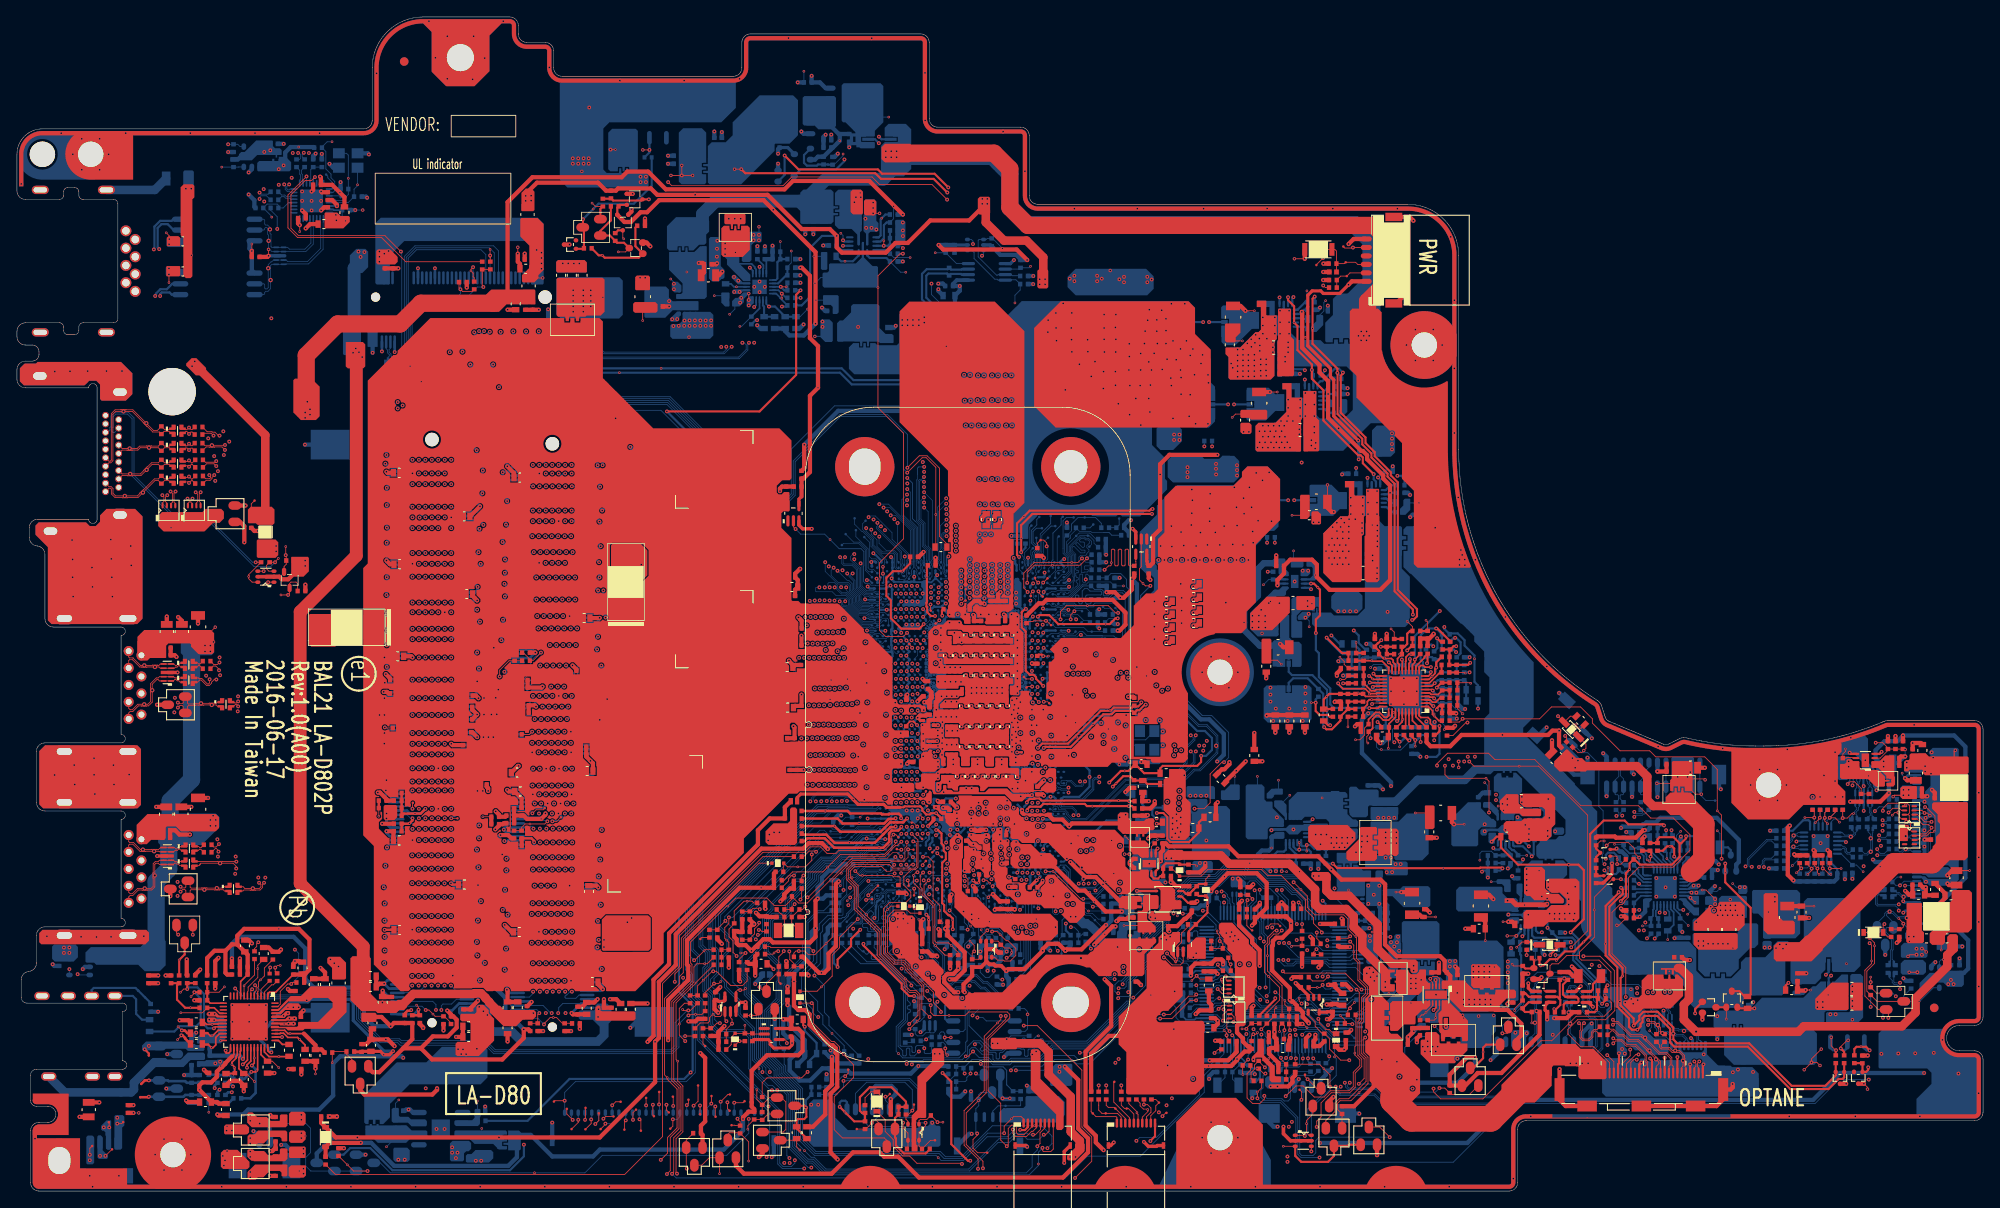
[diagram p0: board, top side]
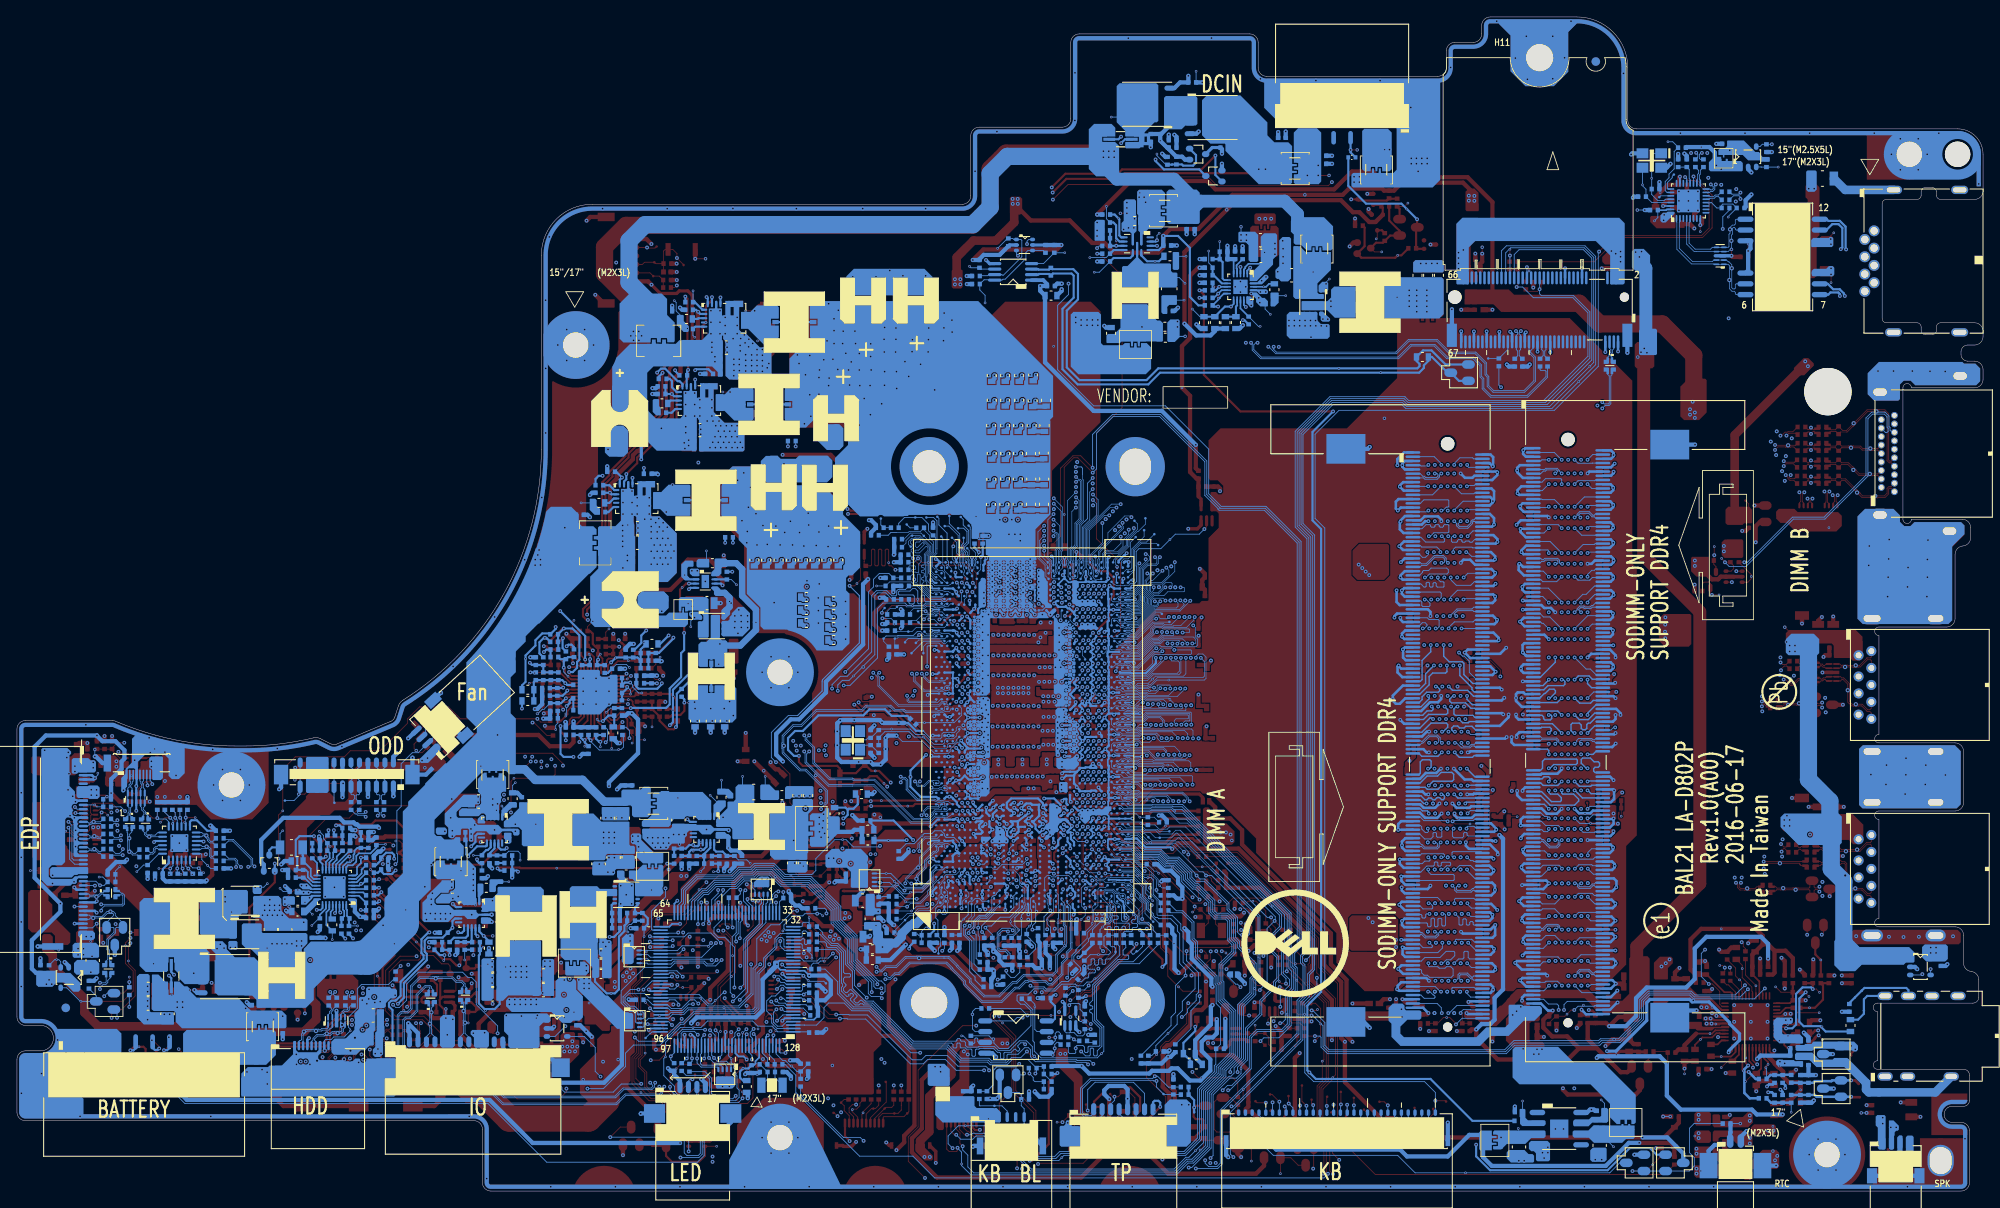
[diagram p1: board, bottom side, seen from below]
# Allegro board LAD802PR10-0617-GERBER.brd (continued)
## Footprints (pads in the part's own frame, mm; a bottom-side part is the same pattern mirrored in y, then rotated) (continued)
SN65LVPE502CPRGER_VQFN24_4X4-S
  oval 0.254x1.041 smd: 1(0,0) 2(0.5,0) 3(1,0) 4(1.5,0) 5(2,0) 6(2.5,0) 13(2.5,3.95) 14(2,3.95) 15(1.5,3.95) 16(1,3.95) 17(0.5,3.95) 18(0,3.95)
  oval 1.041x0.254 smd: 7(3.225,0.725) 8(3.225,1.225) 9(3.225,1.725) 10(3.225,2.225) 11(3.225,2.725) 12(3.225,3.225) 19(-0.725,3.225) 20(-0.725,2.725) 21(-0.725,2.225) 22(-0.725,1.725) 23(-0.725,1.225) 24(-0.725,0.725)
  rect 2.108x2.108 smd: 25(1.25,1.975)
SN74AHC1G08DCKR_SC70-5
  oval 0.381x1.295 smd: 1(0,0.15) 2(0.65,0.15) 3(1.3,0.15) 4(1.3,1.89) 5(0,1.89)
SN74LVC1G06DCKR_SC70-5
  oval 0.381x0.864 smd: 1(0,0) 2(0.65,0) 3(1.3,0) 4(1.3,1.74) 5(0,1.74)
SSM3K7002FU_SC70-3
  oval 0.508x0.991 smd: 1(0,0) 2(0.65,1.9) 3(-0.65,1.9)
STARC_132C30-100020-A2-R_30P
  oval 0.406x0.787 smd: 1(0,0) 2(0.8,0) 3(1.6,0) 4(2.4,0) 5(3.2,0) 6(4,0) 7(4.8,0) 8(5.6,0) 9(6.4,0) 10(7.2,0) 11(8,0) 12(8.8,0) 13(9.6,0) 14(10.4,0) 15(11.2,0) 16(12,0) 17(12.8,0) 18(13.6,0) 19(14.4,0) 20(15.2,0) 21(16,0) 22(16.8,0) 23(17.6,0) 24(18.4,0) 25(19.2,0) 26(20,0) 27(20.8,0) 28(21.6,0) 29(22.4,0) 30(23.2,0)
  rect 0.559x1.295 smd: 31(-1.475,-3.3) 32(24.675,-3.3)
SW_TST71-N-220-T170-S017_2P
  rect 0.61x1.499 smd: 1(0,0) 2(3.2,0)
SY6288C20AAC_SOT23-5
  oval 0.559x0.787 smd: 1(0,0) 2(0.95,0) 3(1.9,0) 4(1.9,2.4) 5(0,2.4)
SY6288D20AAC_SOT23-5
  oval 0.559x0.787 smd: 1(0,0) 2(0.95,0) 3(1.9,0) 4(1.9,2.4) 5(0,2.4)
SY8033BDBC_DFN10_3X3-S
  oval 0.305x0.559 smd: 1(0,0) 2(0.5,0) 3(1,0) 4(1.5,0) 5(2,0) 6(2,2.7) 7(1.5,2.7) 8(1,2.7) 9(0.5,2.7) 10(0,2.7)
  rect 2.591x1.753 smd: 11(1,1.35)
SY8286BRAC_QFN20_3X3-S
  oval 0.889x0.254 smd: 1(0,0) 2(0,-0.45) 3(0,-0.9) 4(0,-1.35) 5(0,-1.8) 11(3.1,-1.8) 12(3.1,-1.35) 13(3.1,-0.9) 14(3.1,-0.45) 15(3.1,0)
  oval 0.254x0.889 smd: 6(0.65,-2.45) 7(1.1,-2.45) 8(1.55,-2.45) 9(2,-2.45) 10(2.45,-2.45) 16(2.45,0.65) 17(2,0.65) 18(1.55,0.65) 19(1.1,0.65) 20(0.65,0.65)
  rect 0.991x0.991 smd: 21(1.55,-0.9)
SY8286CRAC_QFN20_3X3-S
  oval 0.889x0.254 smd: 1(0,0) 2(0,-0.45) 3(0,-0.9) 4(0,-1.35) 5(0,-1.8) 11(3.1,-1.8) 12(3.1,-1.35) 13(3.1,-0.9) 14(3.1,-0.45) 15(3.1,0)
  oval 0.254x0.889 smd: 6(0.65,-2.45) 7(1.1,-2.45) 8(1.55,-2.45) 9(2,-2.45) 10(2.45,-2.45) 16(2.45,0.65) 17(2,0.65) 18(1.55,0.65) 19(1.1,0.65) 20(0.65,0.65)
  rect 0.991x0.991 smd: 21(1.55,-0.9)
SY8286RAC_QFN20_3X3-S
  oval 0.889x0.254 smd: 1(0,0) 2(0,-0.45) 3(0,-0.9) 4(0,-1.35) 5(0,-1.8) 11(3.1,-1.8) 12(3.1,-1.35) 13(3.1,-0.9) 14(3.1,-0.45) 15(3.1,0)
  oval 0.254x0.889 smd: 6(0.65,-2.45) 7(1.1,-2.45) 8(1.55,-2.45) 9(2,-2.45) 10(2.45,-2.45) 16(2.45,0.65) 17(2,0.65) 18(1.55,0.65) 19(1.1,0.65) 20(0.65,0.65)
  rect 0.991x0.991 smd: 21(1.55,-0.9)
TAIYO_MCF12102G900-T_4P
  rect 0.508x0.305 smd: 1(0,0) 2(0,-0.55) 3(1.25,-0.55) 4(1.25,0)
TPC12
  round 0.305 smd: 1(0,0)
TPS22961DNYR_WSON8
  oval 0.305x0.508 smd: 1(0,0) 2(0.65,0) 3(1.3,0) 4(1.95,0) 5(1.95,2.7)
  oval 1.6x0.508 smd: 6(0.65,2.7)
  rect 2.388x1.6 smd: 7(0.975,1.35)
TPS22967DSGR_SON8_2X2-S
  oval 0.254x0.787 smd: 1(0,0) 2(0.5,0) 3(1,0) 4(1.5,0) 5(1.5,2.2) 6(1,2.2) 7(0.5,2.2) 8(0,2.2)
  rect 1.6x0.889 smd: 9(0.75,1.1)
TVNST52302AB0_SOT523-3
  oval 0.508x0.559 smd: 1(0,0) 2(-0.5,-1.4) 3(0.5,-1.4)
TVWDF1004AD0_DFN9
  oval 0.203x0.686 smd: 1(0,0) 2(0.5,0) 4(1.5,0) 5(2,0) 6(2,0.875) 7(1.5,0.875) 8(0.5,0.875) 9(0,0.875)
  oval 0.406x1.549 smd: 3(1,0.437)
W25Q128FVSIQ_SO8
  oval 0.635x1.676 smd: 1(0,0) 2(1.27,0) 3(2.54,0) 4(3.81,0) 5(3.81,7.25) 6(2.54,7.25) 7(1.27,7.25) 8(0,7.25)
Y_7V25000014_4P
  rect 1.397x1.194 smd: 1(0,0) 2(2.2,0) 3(2.2,1.7) 4(0,1.7)
Y_X1A000141000200_2P
  rect 0.991x1.803 smd: 1(0,0) 2(2.5,0)
Y_X3G024000DC1H_4P
  rect 1.397x1.194 smd: 1(0,0) 2(2.2,0) 3(2.2,1.7) 4(0,1.7)
YUQIU_PJ753-F07J1BE-B_7P-T
  oval 0.991x1.803 hole 0.61x1.397: 1(0,0) 2(9.5,-5.5) 3(9.5,-8.6) 4(0,-7.8) 5(9.5,0) 6(9.5,-2.75) 7(0,-2.65)

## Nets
0.6V_DDR_VTT_ON: CC90.1 PR202.1 RC9.2 UC2.4
1.2V_VTT_PWRGD: PR209.2 PU200.10 RC106.1
2.5V_VIN: PC802.1 PJP801.2 PU800.3
3V_FB: PC113.1 PR109.2 PR110.1 PU100.13
3V_SN: PC112.1 PR106.2
3V_VIN: PC100.1 PC103.1 PC104.1 PC105.1 PC130.1 PC131.1 PJP105.2 PL102.2 PU100.2 PU100.3 PU100.4 PU100.5
5V_FB: PC127.1 PR115.2 PR118.1 PU102.13
5V_SN: PC125.1 PR112.2
5V_VIN: PC115.1 PC116.1 PC117.1 PC118.1 PC132.1 PC133.1 PJP106.2 PL103.2 PU102.2 PU102.3 PU102.4 PU102.5
+0.6V_DDR_VTT: CD5.1 CD6.1 CD7.1 CD8.1 CD31.1 CD32.1 CD33.1 CD34.1 JDIMM1.258 JDIMM2.258 PJP203.1
+0.6VSP: PC205.1 PC211.1 PJP203.2 PU200.2 PU200.20
+1.0V_AMPHYPLL: CC74.1 CC75.1 RC169.1 UC1.K15 UC1.L15
+1.0V_APLL: CC82.1 CC83.1 L1.2 UC1.V15
+1.0V_APLLEBB: CC63.1 RC162.1 UC1.N18
+1.0V_CLK2: CC76.1 RC170.1 UC1.K19
+1.0V_CLK4: CC84.1 RC173.1 UC1.N20
+1.0V_CLK5: CC77.1 RC76.2 RC171.1 UC1.L19
+1.0V_MPHYGT: CC59.1 CC60.1 CC73.1 RC169.2 RC174.1 UC1.N15 UC1.N16 UC1.N17 UC1.P15 UC1.P16
+1.0V_PRIM: CC55.1 CC57.1 CC58.1 CC72.1 CC87.1 CE17.1 CZ4.1 CZ21.1 L1.1 PJP302.2 RC149.1 RC161.2 RC162.2 RC170.2 RC171.2 RC173.2 RC174.2 UC1.A10 UC1.A14 UC1.AB17 UC1.AB19 UC1.AB20 UC1.AF18 UC1.AF19 UC1.AK20 UC1.K17 UC1.L1 UC1.L21 UC1.P18 UC1.T1 UC1.V20 UC1.V21 UC1.Y18 UE1.95 UZ1.1 UZ1.2 UZ2.1 UZ2.2 UZ2.7
+1.0V_SRAM: CC62.1 RC161.1 UC1.AF20 UC1.AF21 UC1.T19 UC1.T20
+1.0V_VCCST: CC41.1 CC44.1 JP2.1 PC602.1 PR601.1 PR604.1 PR605.1 RC104.2 RC111.1 RC112.1 RC138.2 RC152.1 RC154.1 RZ4.2 UC1.A18 UC1.K20 UC1.K21
+1.0V_VCCST_C: CZ2.1 JP2.2 UZ1.7 UZ1.8
+1.0V_VCCSTG: CC42.1 JP3.1 RC113.1 RC140.2 RC141.2 RC142.2 RZ4.1 UC1.A22 UC1.G20
+1.0V_VCCSTG_C: CZ6.1 JP1.1 JP3.2 UZ2.6
+1.0V_XDP: RC143.1 RC149.2
+1.0VS_VCCIO: CC45.1 CC46.1 CC47.1 CC48.1 CC49.1 CC50.1 CC51.1 CC52.1 CC53.1 CC54.1 CZ8.1 JP1.2 RC4.1 UC1.AK28 UC1.AK30 UC1.AL30 UC1.AL42 UC1.AM28 UC1.AM30 UC1.AM42
+1.0VS_VCCOPC: CC17.1 CC18.1 CC19.1 CC20.1 CC21.1 CC22.1 CC23.1 CC24.1 CC25.1 PJP1202.2 UC1.AB62 UC1.AE62 UC1.AG62 UC1.P62 UC1.V62
+1.0VS_VCCOPCP: PC1206.1 PC1207.1 PC1208.1 PJP1202.1 PL1201.2 PU1200.12
+1.2V_DDR: CC1.1 CC26.1 CC27.1 CC28.1 CC29.1 CC30.1 CC31.1 CC32.1 CC33.1 CC34.1 CC35.1 CC36.1 CC37.1 CC38.1 CC39.1 CC40.1 CC43.1 CD11.1 CD12.1 CD13.1 CD14.1 CD15.1 CD16.1 CD17.1 CD18.1 CD19.1 CD20.1 CD21.1 CD22.1 CD23.1 CD24.1 CD25.1 CD26.1 CD27.1 CD41.1 CD42.1 CD43.1 CD44.1 CD45.1 CD46.1 CD47.1 CD48.1 CD49.1 CD50.1 CD51.1 CD52.1 CD53.1 CD54.1 CD55.1 CD56.1 CD57.1 JDIMM1.12 JDIMM1.33 JDIMM1.54 JDIMM1.75 JDIMM1.96 JDIMM1.111 JDIMM1.112 JDIMM1.117 JDIMM1.118 JDIMM1.123 JDIMM1.124 JDIMM1.129 JDIMM1.130 JDIMM1.135 JDIMM1.136 JDIMM1.141 JDIMM1.142 JDIMM1.147 JDIMM1.148 JDIMM1.153 JDIMM1.154 JDIMM1.159 JDIMM1.160 JDIMM1.163 JDIMM1.178 JDIMM1.199 JDIMM1.220 JDIMM1.241 JDIMM2.12 JDIMM2.33 JDIMM2.54 JDIMM2.75 JDIMM2.96 JDIMM2.111 JDIMM2.112 JDIMM2.117 JDIMM2.118 JDIMM2.123 JDIMM2.124 JDIMM2.129 JDIMM2.130 JDIMM2.135 JDIMM2.136 JDIMM2.141 JDIMM2.142 JDIMM2.147 JDIMM2.148 JDIMM2.153 JDIMM2.154 JDIMM2.159 JDIMM2.160 JDIMM2.163 JDIMM2.178 JDIMM2.199 JDIMM2.220 JDIMM2.241 PJP200.2 RD7.1 RD10.1 RD20.1 RD23.1 RD24.1 UC1.AL23 UC1.AM40 UC1.AU23 UC1.AU28 UC1.AU35 UC1.AU42 UC1.BB23 UC1.BB32 UC1.BB41 UC1.BB47 UC1.BB51 UC2.5
+1.2VP: PC213.1 PC214.2 PC215.1 PC216.1 PC217.1 PC218.1 PC219.1 PC220.1 PJP200.1 PL200.1 PR207.2 PU200.5 PU200.19
+1.8V_AVDD: CA12.1 RA5.1 UA1.40
+1.8V_CPVDD: CA13.1 CA14.1 RA6.2 UA1.36
+1.8V_PRIM: CC68.1 CC86.1 PJP502.2 QA1.1 RC137.1 UC1.AA1 UC1.AF16 UC1.G61 UC1.H63
+1.8VALWP: PC503.1 PC505.1 PC506.1 PC507.1 PJP502.1 PL501.2 PR503.2
+1VALWP: PC309.1 PC310.1 PC311.1 PC312.1 PC313.1 PJP302.1 PL301.2 PR308.2
+2.5V_MEM: CD1.1 CD2.1 CD3.1 CD4.1 CD35.1 CD36.1 CD37.1 CD38.1 JDIMM1.257 JDIMM1.259 JDIMM2.257 JDIMM2.259 PJP802.2
+2.5VP: PC803.1 PC804.1 PJP802.1 PR801.1 PU800.6
+3.3V_ALW_DSW: CC80.1 CC81.1 RC85.1 RC89.2 RC90.2 RC93.1 RC163.1 UC1.AD17 UC1.AD18 UC1.AJ17
+3.3V_HDA: CC61.1 L2.2 UC1.AJ19
+3.3V_OUT: CZ12.1 JP5.1 UZ3.8 UZ3.9
+3.3V_SPI: CC3.1 RC17.1 RC18.1 RC19.1 RC20.1 RC139.1 UC1.AJ16 UC3.8
+3.3V_WLAN: CW6.1 CW7.1 CW8.1 CW9.1 JWLAN1.2 JWLAN1.4 JWLAN1.64 JWLAN1.66 RW3.1 RW5.2
+3V_DVDD: CA5.1 CA6.1 CA15.1 CA16.1 CA17.1 RA2.1 RA3.2 RA8.1 UA1.1 UA1.9
+3VALW: CC11.1 CC12.1 CC13.1 CC85.1 CL9.1 CZ25.1 D2.2 JP9.1 JP11.2 JPWR1.1 PC1205.1 PJP102.2 PJP501.1 PJP801.1 PR3.2 PR16.2 PR28.1 PR209.1 PR303.1 PR304.1 PR756.2 PR791.1 PU1200.10 Q2.2 Q2.5 Q16.2 R35.1 R43.1 R53.1 RA11.2 RC88.2 RC92.2 RC163.2 RE2.2 RE15.2 RE17.2 RE18.2 RE21.2 RE25.1 RE40.2 RE46.1 RE49.1 RE55.1 RE56.1 RE57.1 RE58.1 RE59.1 RL7.1 RPE1.5 RPE1.6 RPE1.7 RPE1.8 RPE2.5 RPE2.6 RPE2.7 RPE2.8 RPE3.1 RPE3.2 RPE3.3 RPE3.4 RPE4.1 RPE4.2 RPE4.3 RPE4.4 RPE5.1 RPE5.2 RPE5.3 RPE5.4 RPE6.1 RPE6.2 RPE6.3 RPE6.4 RW5.1 TPS9.1(TP-1) UC5.5 UC6.5 UC7.5 UC9.5 UL3.5 UZ3.6 UZ3.7
+3VALW_EC: CE5.1 CE6.1 CE7.2 CE8.2 CE9.1 CE10.1 CE11.1 CE12.1 CE13.1 CE15.1 CE20.1 CE21.1 RE1.1 RE2.1 RE3.1 RE8.2 RE9.2 RE10.2 RE11.2 RE12.1 RE14.2 UE1.5 UE1.19 UE1.22 UE1.43 UE1.54 UE1.65 UE1.82 UE1.103 UE1.115
+3VALW_PCH: CC64.1 CC65.1 CC66.1 CC67.1 CC78.1 CC79.1 JP9.2 L2.1 RC5.1 RC17.2 RC29.2 RC30.2 RC31.2 RC32.2 RC33.2 RC34.2 RC35.2 RC37.2 RC38.2 RC39.2 RC44.1 RC45.2 RC46.2 RC47.2 RC84.1 RC128.1 RC129.1 RPC1.5 RPC1.6 RPC1.7 RPC1.8 RX2.1 RX13.1 TPS10.1(TP-1) UC1.AD15 UC1.AG15 UC1.AJ21 UC1.AK15 UC1.AK17 UC1.T16 UC1.V19 UC1.Y15 UC1.Y16
+3VALWP: PC106.1 PC107.1 PC108.1 PC109.1 PC110.1 PJP102.1 PL100.2 PR107.1 PR108.2 PR109.1 PR113.1 PU100.14
+3VLP: D1.2 PC111.1 PU100.16 PU100.17 R42.1 RE29.2
+3VS: C17.1 C20.1 C21.1 CD9.1 CD10.1 CD39.1 CD40.1 CE22.1 CW3.1 CW4.1 CW5.1 CX4.2 CX5.2 EC2225.1 EC2226.1 JDB1.9 JDB1.10 JDIMM1.255 JDIMM2.255 JIOB1.12 JP5.2 JSSD1.24 JSSD1.25 JSSD1.26 JSSD1.27 JSSD1.28 JSSD1.29 JSSD1.30 PR612.1 PR1206.1 Q6.2 Q10.2 Q10.5 Q11.2 Q11.5 QA1.2 QC1.2 QC1.5 QI2.2 QI2.5 QI3.2 R5.1 R11.1 R16.1 R23.1 R24.1 R28.1 R29.1 R33.1 R34.1 R36.1 R48.1 R49.1 R50.2 R57.1 RA2.2 RC1.2 RC2.2 RC3.2 RC9.1 RC13.1 RC14.1 RC27.1 RC28.1 RC36.2 RC42.1 RC43.2 RC51.1 RC53.1 RC55.1 RC57.1 RC59.1 RC61.1 RC63.1 RC64.1 RC69.2 RC70.2 RC72.1 RC73.1 RC86.1 RC105.1 RC114.1 RC115.1 RC181.1 RC187.1 RC188.1 RD1.1 RD2.1 RD3.1 RD13.1 RD14.1 RD15.1 RE13.2 RI15.1 RL3.1 RL16.1 RW3.2 RX1.1 RX10.1 RX11.1 RX14.1 RX16.1 RX18.1 RX20.1 RX22.1 RX24.1 RX26.1 RX28.1 RX30.1 U1.5 U2.1 UC4.5 UE2.5 UX2.1 UX2.13
+3VS_CAM: C14.1 C15.1 JEDP1.30 R16.2
+5V_AVDD: CA10.1 CA11.1 RA4.2 UA1.26
+5V_CAM: CX2.2 CX13.1 J3D1.9 J3D1.10 JP10.2 UX1.7 UX1.8
+5V_HDD: CS5.1 CS6.1 CS7.1 JHDD1.10 JHDD1.11 JHDD1.12 JP12.2
+5V_HDMI: CI9.1 FI1.1 JHDMI1.18 ZT62.1(TP-1)
+5V_KB_BL: C34.1 EC3002.1 F3.1 JKBBL1.1 ZT61.1(TP-1)
+5V_OUT: CZ9.1 JP4.2 UZ3.13 UZ3.14
+5V_PVDD: CA1.1 CA2.1 CA3.1 CA4.1 RA1.1 UA1.41 UA1.46
+5VALW: CU5.1 CU17.1 CX1.1 CX12.1 CZ5.1 CZ22.1 CZ23.1 CZ24.1 EC2229.1 EC2230.1 JP10.1 PC661.1 PC669.1 PC677.1 PC685.1 PC801.1 PD5.3 PD6.3 PJP103.2 PR8.1 PR206.1 PR210.2 PR602.2 PR615.1 PR634.1 PU603.2 PU604.2 PU605.2 PU606.6 PU800.4 Q3.3 Q4.3 Q15.3 UU1.5 UU3.5 UX1.1 UX1.2 UX1.4 UZ1.4 UZ2.3 UZ3.1 UZ3.2 UZ3.4
+5VALWP: PC120.1 PC121.1 PC122.1 PC123.1 PC124.1 PJP103.1 PL101.2 PR115.1 PR117.2 PU102.14
+5VS: C30.1 EC2215.1 EC2216.1 F3.2 FI1.2 JFAN1.1 JP4.1 JP12.1 JP13.1 Q7.3 QI1.2 R12.1 R30.2 RA1.2 RA4.1 RI13.2 RI14.2
+5VS_ODD: CS13.1 CS14.1 CS15.1 JODD1.17 JODD1.18 JODD1.19 JODD1.20 JODD1.21 JODD1.22 JP13.2
+17.4V_BATT+: PC7.1 PC761.1 PC766.1 PC775.1 PC776.1 PC777.1 PC778.1 PJP3.2 PL3.1 PQ710.3 PR745.2 PR765.4 PR780.2
+17.4V_BATT++: PBATT1.8 PBATT1.9 PBATT1.10 PC8.1 PJP3.1 PL3.2
+19V_ADPIN: PC1.1 PC2.1 PJP1.2 PJPDC1.5 PJPDC1.6 PL1.1
+19V_VIN: PC3.1 PC4.1 PC742.2 PD704.2 PJP1.1 PL1.2 PQ740.5 PR5.1 PR7.2 PR31.2 PR729.1
+19VB: EC2201.1 EC2202.1 EC2203.1 EC2204.1 EC2205.1 EC2206.1 EC2207.1 EC2208.1 EC2209.1 EC2210.1 EC2211.1 EC2212.1 EC2213.1 EC2214.1 F1.1 PJP105.1 PJP106.1 PJP206.2 PJP301.1 PJP601.2 PJP602.2 PJP701.1 PJP1201.1 PL102.1 PL103.1 PL201.1 PL302.1 PL602.2 PL606.2 PL704.1 PL1202.1 PQ717.5 PR102.2 PR703.4
+19VB_1.2V: PC201.1 PC206.1 PC208.1 PC212.1 PC230.1 PC231.1 PJP206.1 PL201.2 PQ201.2 PQ201.3 PQ201.4 PQ201.10 PR208.1
+19VB_+1VALW: PC301.1 PC302.1 PC303.1 PC320.1 PC321.1 PJP301.2 PL302.2 PU300.2 PU300.3 PU300.4 PU300.5
+VCC_CORE: PC1001.1 PC1002.1 PC1003.1 PC1004.1 PC1005.1 PC1006.1 PC1007.1 PC1008.1 PC1009.1 PC1010.1 PC1011.1 PC1012.1 PC1013.1 PC1030.1 PC1031.1 PC1032.1 PC1033.1 PC1034.1 PC1035.1 PC1036.1 PC1037.1 PC1038.1 PC1039.1 PC1050.1 PC1051.1 PC1052.1 PC1053.1 PC1054.1 PC1061.1 PC1062.1 PC1064.1 PC1065.1 PC1066.1 PC1067.1 PC1068.1 PC1069.1 PC1070.1 PC1071.1 PC1072.1 PC1073.1 PC1074.1 PC1075.1 PC1076.1 PC1077.1 PC1078.1 PC1079.1 PC1080.1 PC1081.1 PC1082.1 PC1083.1 PC1084.1 PC1085.1 PC1086.1 PC1087.1 PC1088.1 PC1089.1 PC1090.1 PC1091.1 PC1092.1 PC1093.1 PC1094.1 PC1095.1 PC1096.1 PC1097.1 PC1098.1 PC1099.1 PC1125.1 PC1126.1 PC1127.1 PC1164.1 PC1170.1 PC1171.1 PC1172.1 PC1173.1 PC1174.1 PL603.1 RC150.1 UC1.A30 UC1.A34 UC1.A39 UC1.A44 UC1.AK33 UC1.AK35 UC1.AK37 UC1.AK38 UC1.AK40 UC1.AL33 UC1.AL37 UC1.AL40 UC1.AM32 UC1.AM33 UC1.AM35 UC1.AM37 UC1.AM38 UC1.G30 UC1.G32 UC1.G33 UC1.G35 UC1.G37 UC1.G38 UC1.G40 UC1.G42 UC1.J30 UC1.J33 UC1.J37 UC1.J40 UC1.K33 UC1.K35 UC1.K37 UC1.K38 UC1.K40 UC1.K42 UC1.K43
+VCC_CORE_G0: TP32.1(TP-1) UC1.K32
+VCC_CORE_G1: TP33.1(TP-1) UC1.AK32
+VCC_GT: PC1014.1 PC1015.1 PC1016.1 PC1017.1 PC1018.1 PC1019.1 PC1020.1 PC1021.1 PC1022.1 PC1023.1 PC1024.1 PC1025.1 PC1026.1 PC1027.1 PC1028.1 PC1029.1 PC1040.1 PC1041.1 PC1042.1 PC1043.1 PC1044.1 PC1045.1 PC1046.1 PC1047.1 PC1048.1 PC1049.1 PC1055.1 PC1056.1 PC1063.1 PC1101.1 PC1128.1 PC1129.1 PC1130.1 PC1131.1 PC1132.1 PC1133.1 PC1134.1 PC1135.1 PC1136.1 PC1137.1 PC1138.1 PC1154.1 PC1155.1 PC1156.1 PC1158.1 PC1159.1 PC1161.1 PC1162.1 PC1163.1 PC1175.1 PC1176.1 PC1177.1 PC1178.1 PC1179.1 PC1180.1 PC1181.1 PC1182.1 PC1183.1 PC1184.1 PC1221.1 PC1222.1 PC1223.1 PC1224.1 PL604.1 PL605.1 RC155.1 RC157.1 UC1.A48 UC1.A53 UC1.A58 UC1.A62 UC1.A66 UC1.AA63 UC1.AA64 UC1.AA66 UC1.AA67 UC1.AA69 UC1.AA70 UC1.AA71 UC1.AC64 UC1.AC65 UC1.AC66 UC1.AC67 UC1.AC68 UC1.AC69 UC1.AC70 UC1.AC71 UC1.AK42 UC1.AK43 UC1.AK45 UC1.AK46 UC1.AK48 UC1.AK50 UC1.AK52 UC1.AK53 UC1.AK55 UC1.AK56 UC1.AK58 UC1.AK60 UC1.AK70 UC1.AL43 UC1.AL46 UC1.AL50 UC1.AL53 UC1.AL56 UC1.AL60 UC1.AM48 UC1.AM50 UC1.AM52 UC1.AM53 UC1.AM56 UC1.AM58 UC1.AU58 UC1.AU63 UC1.BB57 UC1.BB66 UC1.J43 UC1.J45 UC1.J46 UC1.J48 UC1.J50 UC1.J52 UC1.J53 UC1.J55 UC1.J56 UC1.J58 UC1.J60 UC1.K48 UC1.K50 UC1.K52 UC1.K53 UC1.K55 UC1.K56 UC1.K58 UC1.K60 UC1.L62 UC1.L63 UC1.L64 UC1.L65 UC1.L66 UC1.L67 UC1.L68 UC1.L69 UC1.L70 UC1.L71 UC1.M62 UC1.N63 UC1.N64 UC1.N66 UC1.N67 UC1.N69 UC1.N70 UC1.N71 UC1.R63 UC1.R64 UC1.R65 UC1.R66 UC1.R67 UC1.R68 UC1.R69 UC1.R70 UC1.R71 UC1.T62 UC1.U65 UC1.U68 UC1.U71 UC1.W63 UC1.W64 UC1.W65 UC1.W66 UC1.W67 UC1.W68 UC1.W69 UC1.W70 UC1.W71 UC1.Y62
+VCC_SA: EC2217.1 EC2218.1 PC1057.1 PC1058.1 PC1059.1 PC1060.1 PC1139.1 PC1140.1 PC1141.1 PC1142.1 PC1143.1 PC1144.1 PC1145.1 PC1146.1 PC1147.1 PC1148.1 PC1149.1 PC1150.1 PC1151.1 PC1152.1 PC1153.1 PL601.1 RC159.1 UC1.AK23 UC1.AK25 UC1.G23 UC1.G25 UC1.G27 UC1.G28 UC1.J22 UC1.J23 UC1.J27 UC1.K23 UC1.K25 UC1.K27 UC1.K28 UC1.K30
GND: C1.2 C2.2 C3.2 C4.2 C5.2 C13.2 C14.2 C15.2 C16.2 C17.2 C19.2 C20.2 C21.2 C24.2 C25.2 C26.2 C27.2 C30.2 C34.2 CA1.2 CA2.2 CA3.2 CA4.2 CA5.2 CA6.2 CA13.2 CA14.2 CA15.2 CA16.2 CA17.2 CA22.1 CA25.1 CA27.2 CA28.2 CA29.2 CA30.2 CC1.2 CC2.1 CC3.2 CC4.2 CC5.2 CC6.2 CC7.2 CC8.2 CC9.2 CC10.2 CC11.2 CC12.2 CC13.2 CC14.2 CC15.2 CC16.2 CC17.2 CC18.2 CC19.2 CC20.2 CC21.2 CC22.2 CC23.2 CC24.2 CC25.2 CC26.2 CC27.2 CC28.2 CC29.2 CC30.2 CC31.2 CC32.2 CC33.2 CC34.2 CC35.2 CC36.2 CC37.2 CC38.2 CC39.2 CC40.2 CC41.2 CC42.2 CC43.2 CC44.2 CC45.2 CC46.2 CC47.2 CC48.2 CC49.2 CC50.2 CC51.2 CC52.2 CC53.2 CC54.2 CC55.2 CC56.2 CC57.2 CC58.2 CC59.2 CC60.2 CC61.2 CC62.2 CC63.2 CC64.2 CC65.2 CC66.2 CC67.2 CC68.2 CC69.2 CC70.2 CC71.2 CC72.2 CC73.2 CC74.2 CC75.2 CC76.2 CC77.2 CC78.2 CC79.2 CC80.2 CC81.2 CC82.2 CC83.2 CC84.2 CC85.2 CC86.2 CC87.2 CC88.2 CC89.2 CC90.2 CD1.2 CD2.2 CD3.2 CD4.2 CD5.2 CD6.2 CD7.2 CD8.2 CD9.2 CD10.2 CD11.2 CD12.2 CD13.2 CD14.2 CD15.2 CD16.2 CD17.2 CD18.2 CD19.2 CD20.2 CD21.2 CD22.2 CD23.2 CD24.2 CD25.2 CD26.2 CD27.2 CD28.2 CD29.2 CD31.2 CD32.2 CD33.2 CD34.2 CD35.2 CD36.2 CD37.2 CD38.2 CD39.2 CD40.2 CD41.2 CD42.2 CD43.2 CD44.2 CD45.2 CD46.2 CD47.2 CD48.2 CD49.2 CD50.2 CD51.2 CD52.2 CD53.2 CD54.2 CD55.2 CD56.2 CD57.2 CD58.2 CE3.2 CE4.2 CE5.2 CE6.2 CE7.1 CE8.1 CE9.2 CE10.2 CE11.2 CE12.2 CE13.2 CE14.2 CE15.2 CE16.2 CE17.2 CE18.2 CE19.2 CE20.2 CE22.2 CE23.2 CE24.2 CE26.2 CE27.2 CE28.2 CE29.2 CE31.2 CE32.1 CE33.2 CI9.2 CL5.2 CL6.2 CL7.2 CL8.2 CL9.2 CL10.2 CL11.2 CL12.2 CL13.2 CL14.2 CS5.2 CS6.2 CS7.2 CS13.2 CS14.2 CS15.2 CU5.2 CU6.2 CU7.2 CU8.2 CU9.2 CU10.2 CU17.2 CU18.2 CU19.2 CU20.2 CU21.2 CU22.2 CW3.2 CW4.2 CW5.2 CW6.2 CW7.2 CW8.2 CW9.2 CX1.2 CX2.1 CX3.2 CX4.1 CX5.1 CX12.2 CX13.2 CZ1.2 CZ2.2 CZ3.2 CZ4.2 CZ5.2 CZ6.2 CZ7.2 CZ8.2 CZ9.2 CZ10.2 CZ11.2 CZ12.2 CZ21.2 CZ22.2 CZ23.2 CZ24.2 CZ25.2 DA1.1 DA2.1 DA4.1 DA5.1 DA6.1 DE1.2 DX1.3 DX1.8 EC2201.2 EC2202.2 EC2203.2 EC2204.2 EC2205.2 EC2206.2 EC2207.2 EC2208.2 EC2209.2 EC2210.2 EC2211.2 EC2212.2 EC2213.2 EC2214.2 EC2215.2 EC2216.2 EC2217.2 EC2218.2 EC2225.2 EC2226.2 EC2229.2 EC2230.2 EC2301.2 EC2302.2 EC2901.2 EC2902.2 EC3001.2 EC3002.2 EC3201.2 EC3202.2 ED2901.2 EU2601.3 EU2602.1 EU2603.3 EU2604.1 EU3101.3 EU3501.3 H1.1(TP-1) H2.1(TP-1) H3.1(TP-1) H4.1(TP-1) H5.1(TP-1) H11.1(TP-1) H12.1(TP-1) H21.1(TP-1) HCPU1.1(TP-1) HCPU2.1(TP-1) HCPU3.1(TP-1) HCPU4.1(TP-1) J3D1.1 J3D1.4 J3D1.11 J3D1.12 JCMOS1.2 JDB1.2 JDB1.11 JDB1.12 JDEG1.10 JDEG1.11 JDEG1.12 JDIMM1.1 JDIMM1.2 JDIMM1.5 JDIMM1.6 JDIMM1.9 JDIMM1.10 JDIMM1.14 JDIMM1.15 JDIMM1.18 JDIMM1.19 JDIMM1.22 JDIMM1.23 JDIMM1.26 JDIMM1.27 JDIMM1.30 JDIMM1.31 JDIMM1.35 JDIMM1.36 JDIMM1.39 JDIMM1.40 JDIMM1.43 JDIMM1.44 JDIMM1.47 JDIMM1.48 JDIMM1.51 JDIMM1.52 JDIMM1.56 JDIMM1.57 JDIMM1.60 JDIMM1.61 JDIMM1.64 JDIMM1.65 JDIMM1.68 JDIMM1.69 JDIMM1.72 JDIMM1.73 JDIMM1.77 JDIMM1.78 JDIMM1.81 JDIMM1.82 JDIMM1.85 JDIMM1.86 JDIMM1.89 JDIMM1.90 JDIMM1.93 JDIMM1.94 JDIMM1.98 JDIMM1.99 JDIMM1.102 JDIMM1.103 JDIMM1.106 JDIMM1.107 JDIMM1.167 JDIMM1.168 JDIMM1.171 JDIMM1.172 JDIMM1.175 JDIMM1.176 JDIMM1.180 JDIMM1.181 JDIMM1.184 JDIMM1.185 JDIMM1.188 JDIMM1.189 JDIMM1.192 JDIMM1.193 JDIMM1.196 JDIMM1.197 JDIMM1.201 JDIMM1.202 JDIMM1.205 JDIMM1.206 JDIMM1.209 JDIMM1.210 JDIMM1.213 JDIMM1.214 JDIMM1.217 JDIMM1.218 JDIMM1.222 JDIMM1.223 JDIMM1.226 JDIMM1.227 JDIMM1.230 JDIMM1.231 JDIMM1.234 JDIMM1.235 JDIMM1.238 JDIMM1.239 JDIMM1.243 JDIMM1.244 JDIMM1.247 JDIMM1.248 JDIMM1.251 JDIMM1.252 JDIMM1.261 JDIMM1.262 JDIMM2.1 JDIMM2.2 JDIMM2.5 JDIMM2.6 JDIMM2.9 JDIMM2.10 JDIMM2.14 JDIMM2.15 JDIMM2.18 JDIMM2.19 JDIMM2.22 JDIMM2.23 JDIMM2.26 JDIMM2.27 JDIMM2.30 JDIMM2.31 JDIMM2.35 JDIMM2.36 JDIMM2.39 JDIMM2.40 JDIMM2.43 JDIMM2.44 JDIMM2.47 JDIMM2.48 JDIMM2.51 JDIMM2.52 JDIMM2.56 JDIMM2.57 JDIMM2.60 JDIMM2.61 JDIMM2.64 JDIMM2.65 JDIMM2.68 JDIMM2.69 JDIMM2.72 JDIMM2.73 JDIMM2.77 JDIMM2.78 JDIMM2.81 JDIMM2.82 JDIMM2.85 JDIMM2.86 JDIMM2.89 JDIMM2.90 JDIMM2.93 JDIMM2.94 JDIMM2.98 JDIMM2.99 JDIMM2.102 JDIMM2.103 JDIMM2.106 JDIMM2.107 JDIMM2.167 JDIMM2.168 JDIMM2.171 JDIMM2.172 JDIMM2.175 JDIMM2.176 JDIMM2.180 JDIMM2.181 JDIMM2.184 JDIMM2.185 JDIMM2.188 JDIMM2.189 JDIMM2.192 JDIMM2.193 JDIMM2.196 JDIMM2.197 JDIMM2.201 JDIMM2.202 JDIMM2.205 JDIMM2.206 JDIMM2.209 JDIMM2.210 JDIMM2.213 JDIMM2.214 JDIMM2.217 JDIMM2.218 JDIMM2.222 JDIMM2.223 JDIMM2.226 JDIMM2.227 JDIMM2.230 JDIMM2.231 JDIMM2.234 JDIMM2.235 JDIMM2.238 JDIMM2.239 JDIMM2.243 JDIMM2.244 JDIMM2.247 JDIMM2.248 JDIMM2.251 JDIMM2.252 JDIMM2.261 JDIMM2.262 JEDP1.9 JEDP1.13 JEDP1.16 JEDP1.19 JEDP1.22 JEDP1.27 JEDP1.33 JEDP1.35 JEDP1.38 JEDP1.41 JEDP1.42 JFAN1.4 JFAN1.5 JFAN1.6 JHDD1.1 JHDD1.4 JHDD1.7 JHDD1.13 JHDD1.14 JHDMI1.2 JHDMI1.5 JHDMI1.8 JHDMI1.11 JHDMI1.17 JHDMI1.20 JHDMI1.21 JHDMI1.22 JHDMI1.23 JIOB1.1 JIOB1.2 JIOB1.5 JIOB1.6 JIOB1.9 JIOB1.10 JIOB1.17 JIOB1.18 JKB1.1 JKB1.31 JKB1.32 JKBBL1.5 JKBBL1.6 JLAN1.9 JLAN1.10 JLAN1.11 JLAN1.12 JLED1.1 JLED1.4 JLED1.5 JLED1.6 JODD1.1 JODD1.2 JODD1.7 JODD1.8 JODD1.13 JODD1.14 JODD1.25 JODD1.26 JPWR1.6 JPWR1.7 JPWR1.8 JRTC1.2 JRTC1.3 JRTC1.4 JSPK1.5 JSPK1.6 JSSD1.1 JSSD1.4 JSSD1.7 JSSD1.10 JSSD1.13 JSSD1.16 JSSD1.21 JSSD1.31 JSSD1.32 JSSD1.33 JSSD1.34 JSSD1.35 JTP1.5 JTP1.9 JTP1.10 JUSB1.4 JUSB1.7 JUSB1.10 JUSB1.11 JUSB1.12 JUSB1.13 JUSB2.4 JUSB2.7 JUSB2.10 JUSB2.11 JUSB2.12 JUSB2.13 JWLAN1.1 JWLAN1.7 JWLAN1.10 JWLAN1.18 JWLAN1.25 JWLAN1.31 JWLAN1.37 JWLAN1.43 JWLAN1.49 JWLAN1.55 JWLAN1.61 JWLAN1.67 JWLAN1.68 JWLAN1.69 PBATT1.1 PBATT1.2 PBATT1.3 PBATT1.4 PBATT1.11 PBATT1.12 PC1.2 PC2.2 PC3.2 PC4.2 PC7.2 PC8.2 PC100.2 PC103.2 PC104.2 PC105.2 PC106.2 PC107.2 PC108.2 PC109.2 PC110.2 PC111.2 PC112.2 PC115.2 PC116.2 PC117.2 PC118.2 PC119.2 PC120.2 PC121.2 PC122.2 PC123.2 PC124.2 PC125.2 PC126.2 PC128.2 PC130.2 PC131.2 PC132.2 PC133.2 PC201.2 PC202.2 PC203.2 PC204.1 PC205.2 PC206.2 PC208.2 PC209.2 PC210.2 PC211.2 PC212.2 PC213.2 PC215.2 PC216.2 PC217.2 PC218.2 PC219.2 PC220.2 PC230.2 PC231.2 PC301.2 PC302.2 PC303.2 PC304.2 PC305.2 PC306.2 PC308.2 PC310.2 PC311.2 PC312.2 PC313.2 PC320.2 PC321.2 PC501.2 PC502.2 PC504.2 PC505.2 PC506.2 PC507.2 PC601.2 PC602.2 PC603.2 PC604.2 PC605.1 PC606.2 PC608.2 PC612.2 PC613.1 PC614.1 PC616.1 PC618.1 PC619.1 PC621.1 PC622.2 PC625.1 PC628.2 PC629.1 PC631.2 PC636.1 PC641.2 PC643.2 PC644.2 PC645.2 PC647.1 PC649.2 PC651.1 PC652.2 PC654.1 PC656.2 PC657.2 PC658.2 PC659.2 PC660.2 PC661.2 PC662.2 PC664.2 PC665.2 PC666.2 PC667.2 PC668.2 PC669.2 PC670.2 PC672.2 PC673.2 PC674.2 PC677.2 PC678.2 PC679.2 PC680.2 PC681.2 PC685.2 PC686.2 PC687.2 PC688.2 PC690.2 PC691.2 PC692.2 PC693.2 PC694.2 PC695.1 PC705.2 PC711.1 PC748.2 PC749.1 PC751.1 PC752.1 PC753.1 PC757.1 PC760.2 PC761.2 PC762.2 PC763.2 PC764.2 PC765.2 PC766.2 PC767.2 PC768.1 PC769.1 PC775.2 PC776.2 PC777.2 PC778.2 PC780.2 PC781.2 PC790.2 PC801.2 PC802.2 PC804.2 PC805.2 PC1001.2 PC1002.2 PC1003.2 PC1004.2 PC1005.2 PC1006.2 PC1007.2 PC1008.2 PC1009.2 PC1010.2 PC1011.2 PC1012.2 PC1013.2 PC1014.2 PC1015.2 PC1016.2 PC1017.2 PC1018.2 PC1019.2 PC1020.2 PC1021.2 PC1022.2 PC1023.2 PC1024.2 PC1025.2 PC1026.2 PC1027.2 PC1028.2 PC1029.2 PC1030.2 PC1031.2 PC1032.2 PC1033.2 PC1034.2 PC1035.2 PC1036.2 PC1037.2 PC1038.2 PC1039.2 PC1040.2 PC1041.2 PC1042.2 PC1043.2 PC1044.2 PC1045.2 PC1046.2 PC1047.2 PC1048.2 PC1049.2 PC1050.2 PC1051.2 PC1052.2 PC1053.2 PC1054.2 PC1055.2 PC1056.2 PC1057.2 PC1058.2 PC1059.2 PC1060.2 PC1061.2 PC1062.2 PC1063.2 PC1064.2 PC1065.2 PC1066.2 PC1067.2 PC1068.2 PC1069.2 PC1070.2 PC1071.2 PC1072.2 PC1073.2 PC1074.2 PC1075.2 PC1076.2 PC1077.2 PC1078.2 PC1079.2 PC1080.2 PC1081.2 PC1082.2 PC1083.2 PC1084.2 PC1085.2 PC1086.2 PC1087.2 PC1088.2 PC1089.2 PC1090.2 PC1091.2 PC1092.2 PC1093.2 PC1094.2 PC1095.2 PC1096.2 PC1097.2 PC1098.2 PC1099.2 PC1101.2 PC1125.2 PC1126.2 PC1127.2 PC1128.2 PC1129.2 PC1130.2 PC1131.2 PC1132.2 PC1133.2 PC1134.2 PC1135.2 PC1136.2 PC1137.2 PC1138.2 PC1139.2 PC1140.2 PC1141.2 PC1142.2 PC1143.2 PC1144.2 PC1145.2 PC1146.2 PC1147.2 PC1148.2 PC1149.2 PC1150.2 PC1151.2 PC1152.2 PC1153.2 PC1154.2 PC1155.2 PC1156.2 PC1158.2 PC1159.2 PC1161.2 PC1162.2 PC1163.2 PC1164.2 PC1170.2 PC1171.2 PC1172.2 PC1173.2 PC1174.2 PC1175.2 PC1176.2 PC1177.2 PC1178.2 PC1179.2 PC1180.2 PC1181.2 PC1182.2 PC1183.2 PC1184.2 PC1202.2 PC1203.2 PC1204.2 PC1205.2 PC1206.2 PC1207.2 PC1208.2 PC1209.2 PC1210.2 PC1211.2 PC1212.2 PC1221.2 PC1222.2 PC1223.2 PC1224.2 PD2.1 PD3.1 PD4.1 PD5.2 PD6.2 PH601.1 PH603.1 PJP2.1 PJPDC1.7 PJPDC1.8 PL4.2 PQ1.1 PQ1.4 PQ2.1 PQ2.4 PQ3.3 PQ5.3 PQ201.5 PQ201.6 PQ201.7 PQ601.5 PQ601.6 PQ601.7 PQ708.1 PQ708.2 PQ708.3 PQ711.3 PQ712.3 PQ720.3 PQ721.3 PR2.2 PR9.1 PR10.1 PR29.2 PR32.2 PR33.1 PR103.2 PR110.2 PR118.2 PR122.2 PR203.2 PR204.2 PR302.2 PR305.2 PR310.2 PR502.1 PR505.2 PR608.2 PR611.2 PR613.1 PR629.1 PR631.1 PR637.2 PR647.1 PR651.2 PR653.2 PR654.2 PR662.2 PR680.2 PR681.2 PR727.2 PR731.2 PR732.2 PR738.2 PR751.1 PR752.1 PR753.1 PR755.1 PR779.1 PR802.2 PR1202.1 PR1205.2 PR1207.2 PU100.7 PU100.8 PU100.18 PU100.21 PU102.7 PU102.8 PU102.18 PU102.21 PU200.1 PU200.3 PU200.14 PU200.21 PU300.7 PU300.8 PU300.18 PU300.21 PU500.11 PU602.41 PU603.7 PU603.10 PU604.7 PU604.10 PU605.7 PU605.10 PU606.4 PU606.9 PU703.33 PU800.8 PU800.9 PU1200.2 PU1200.11 Q1.3 Q8.3 Q13.3 QC2.3 QI1.3 R2.2 R10.2 R27.2 R40.2 R45.2 R54.2 RA9.2 RA17.1 RA18.1 RA22.1 RA24.2 RC6.1 RC7.2 RC8.2 RC10.2 RC11.2 RC12.2 RC52.2 RC54.2 RC56.2 RC58.2 RC60.2 RC62.2 RC66.2 RC67.2 RC68.2 RC87.2 RC94.1 RC102.2 RC109.2 RC110.2 RC119.2 RC120.2 RC121.2 RC122.2 RC130.2 RC131.1 RC132.1 RC133.1 RC134.2 RC136.1 RC144.2 RC145.2 RC146.2 RC147.2 RC151.2 RC156.2 RC158.2 RC160.2 RC164.2 RC182.2 RC192.2 RD4.2 RD5.2 RD6.2 RD11.2 RD12.2 RD16.2 RD17.2 RD18.2 RD21.2 RD22.2 RE16.2 RE19.2 RE20.2 RE32.2 RE48.2 RE50.2 RE53.1 RI16.2 RL2.1 RL4.2 RL6.1 RP1.1 RP1.2 RP1.3 RW8.2 RX3.2 RX5.2 RX6.2 RX12.1 RX15.1 RX17.1 RX19.1 RX21.1 RX23.1 RX25.1 RX27.1 RX29.1 RX31.1 RZ9.2 SW1.2 U1.2 U2.5 UA1.49 UC1.A5 UC1.A67 UC1.A70 UC1.AA2 UC1.AA4 UC1.AA65 UC1.AA68 UC1.AB8 UC1.AB15 UC1.AB16 UC1.AB18 UC1.AB21 UC1.AD8 UC1.AD13 UC1.AD16 UC1.AD19 UC1.AD20 UC1.AD21 UC1.AD62 UC1.AE64 UC1.AE65 UC1.AE66 UC1.AE67 UC1.AE68 UC1.AE69 UC1.AF1 UC1.AF2 UC1.AF4 UC1.AF10 UC1.AF15 UC1.AF17 UC1.AF63 UC1.AG16 UC1.AG17 UC1.AG18 UC1.AG19 UC1.AG20 UC1.AG21 UC1.AG71 UC1.AH6 UC1.AH13 UC1.AH63 UC1.AH64 UC1.AH67 UC1.AJ4 UC1.AJ15 UC1.AJ18 UC1.AJ20 UC1.AK8 UC1.AK11 UC1.AK16 UC1.AK18 UC1.AK21 UC1.AK22 UC1.AK27 UC1.AK63 UC1.AK68 UC1.AK69 UC1.AL2 UC1.AL4 UC1.AL28 UC1.AL32 UC1.AL35 UC1.AL38 UC1.AL45 UC1.AL48 UC1.AL52 UC1.AL55 UC1.AL58 UC1.AL64 UC1.AL65 UC1.AL66 UC1.AM8 UC1.AM13 UC1.AM21 UC1.AM25 UC1.AM27 UC1.AM43 UC1.AM45 UC1.AM46 UC1.AM55 UC1.AM60 UC1.AM61 UC1.AM68 UC1.AM71 UC1.AN20 UC1.AN23 UC1.AN28 UC1.AN30 UC1.AN32 UC1.AN33 UC1.AN35 UC1.AN37 UC1.AN38 UC1.AN40 UC1.AN42 UC1.AN58 UC1.AN63 UC1.AP10 UC1.AP18 UC1.AP20 UC1.AP23 UC1.AP28 UC1.AP32 UC1.AP35 UC1.AP38 UC1.AP42 UC1.AP58 UC1.AP63 UC1.AP68 UC1.AP70 UC1.AR5 UC1.AR8 UC1.AR11 UC1.AR15 UC1.AR16 UC1.AR20 UC1.AR23 UC1.AR28 UC1.AR35 UC1.AR42 UC1.AR43 UC1.AR45 UC1.AR46 UC1.AR48 UC1.AR50 UC1.AR52 UC1.AR53 UC1.AR55 UC1.AR58 UC1.AR63 UC1.AT2 UC1.AT4 UC1.AT20 UC1.AT23 UC1.AT28 UC1.AT35 UC1.AT42 UC1.AT56 UC1.AT58 UC1.AT63 UC1.AT68 UC1.AT71 UC1.AU10 UC1.AU15 UC1.AU20 UC1.AU32 UC1.AU38 UC1.AV1 UC1.AV68 UC1.AV69 UC1.AV70 UC1.AV71 UC1.AW6 UC1.AW8 UC1.AW10 UC1.AW12 UC1.AW14 UC1.AW16 UC1.AW18 UC1.AW21 UC1.AW23 UC1.AW26 UC1.AW28 UC1.AW30 UC1.AW32 UC1.AW34 UC1.AW36 UC1.AW38 UC1.AW41 UC1.AW43 UC1.AW45 UC1.AW47 UC1.AW49 UC1.AW51 UC1.AW53 UC1.AW55 UC1.AW57 UC1.AW60 UC1.AW62 UC1.AW64 UC1.AW66 UC1.AY3 UC1.AY66 UC1.AY71 UC1.B10 UC1.B14 UC1.B18 UC1.B22 UC1.B30 UC1.B34 UC1.B39 UC1.B44 UC1.B48 UC1.B53 UC1.B58 UC1.B62 UC1.B66 UC1.B71 UC1.BA1 UC1.BA2 UC1.BA6 UC1.BA10 UC1.BA14 UC1.BA18 UC1.BA23 UC1.BA28 UC1.BA32 UC1.BA36 UC1.BA41 UC1.BA45 UC1.BA49 UC1.BA53 UC1.BA57 UC1.BA62 UC1.BA66 UC1.BA71 UC1.BB6 UC1.BB18 UC1.BB26 UC1.BB30 UC1.BB34 UC1.BB38 UC1.BB43 UC1.BB55 UC1.BB60 UC1.BB64 UC1.BB67 UC1.BB70 UC1.C1 UC1.C5 UC1.C25 UC1.D6 UC1.D10 UC1.D11 UC1.D14 UC1.D18 UC1.D22 UC1.D25 UC1.D26 UC1.D30 UC1.D34 UC1.D39 UC1.D44 UC1.D45 UC1.D47 UC1.D48 UC1.D53 UC1.D58 UC1.D62 UC1.D66 UC1.D69 UC1.E6 UC1.E11 UC1.E15 UC1.E18 UC1.E21 UC1.E46 UC1.E50 UC1.E53 UC1.E56 UC1.E65 UC1.E71 UC1.F1 UC1.F2 UC1.F4 UC1.F8 UC1.F13 UC1.F22 UC1.F23 UC1.F27 UC1.F28 UC1.F32 UC1.F33 UC1.F35 UC1.F37 UC1.F38 UC1.F40 UC1.F42 UC1.F68 UC1.G5 UC1.G6 UC1.G10 UC1.G22 UC1.G43 UC1.G45 UC1.G48 UC1.G52 UC1.G55 UC1.G58 UC1.G60 UC1.G63 UC1.G66 UC1.H15 UC1.H18 UC1.H71 UC1.J8 UC1.J11 UC1.J13 UC1.J25 UC1.J28 UC1.J32 UC1.J35 UC1.J38 UC1.J42 UC1.K16 UC1.K18 UC1.K22 UC1.K61 UC1.K63 UC1.K64 UC1.K65 UC1.K66 UC1.K67 UC1.K68 UC1.K70 UC1.K71 UC1.L2 UC1.L4 UC1.L8 UC1.L11 UC1.L16 UC1.L17 UC1.L18 UC1.L20 UC1.N6 UC1.N10 UC1.N13 UC1.N19 UC1.N21 UC1.N65 UC1.N68 UC1.P17 UC1.P19 UC1.P20 UC1.P21 UC1.R6 UC1.R13 UC1.T2 UC1.T4 UC1.T15 UC1.T17 UC1.T18 UC1.T21 UC1.U10 UC1.U63 UC1.U64 UC1.U66 UC1.U67 UC1.U69 UC1.U70 UC1.V16 UC1.V17 UC1.V18 UC1.W6 UC1.W9 UC1.W13 UC1.Y17 UC1.Y19 UC1.Y20 UC1.Y21 UC2.3 UC3.4 UC4.3 UC5.3 UC6.3 UC7.3 UC9.3 UE1.17 UE1.51 UE1.64 UE1.84 UE1.100 UE1.124 UE2.3 UL1.33 UL3.2 UU1.2 UU3.2 UX1.5 UX1.9 UX2.10 UX2.21 UX2.25 UZ1.5 UZ1.9 UZ2.5 UZ3.11 UZ3.15 YL1.2 YL1.4
V3D3_STB: RA11.1 RA12.1 UA1.20
VCC_EDRAM_SENSE: TP34.1(TP-1) UC1.AC63
VCC_GT_SENSE: PC617.1 PC618.2 PC620.1 PR622.1 RC155.2 UC1.J70
VCCEOPIO_SENSE: TP36.1(TP-1) UC1.AL63
VCCIO_SENSE: TP38.1(TP-1) UC1.AM23
VCCSA_B+: PC608.1 PC612.1 PJP603.1 PQ601.2 PQ601.3 PQ601.4 PQ601.10
VCCSENSE: PC639.1 PC651.2 PC653.1 PR648.1 RC150.2 UC1.E32
VCCSENSE_VCCGTUS: RC157.2 UC1.AK62
VCCST_PWRGD: RC96.2 UC1.B65
VCCSTG_EN: DZ2.1 RZ2.2 RZ3.1 UC9.4
VCCSTG_EN_R: CZ7.1 DZ2.2 RZ3.2 UZ2.4
VDD_1.2V: PC209.1 PR205.1 PR206.2 PU200.11
VDD_CHG: PC768.2 PR741.1 PR749.2 PR750.2 PR760.1 PR781.1 PU703.19
VDDP_CHG: PC769.2 PR760.2 PU703.20
VIN_+VCCEOPIO: PC1202.1 PC1203.1 PC1210.1 PC1211.1 PC1212.1 PJP1201.2 PL1202.2 PU1200.1
VSS_EDRAM_SENSE: TP35.1(TP-1) UC1.AE63
VSS_GT_SENSE: PC619.2 PC620.2 PU602.6 RC156.1 UC1.J69
VSSEOPIO_SENSE: TP37.1(TP-1) UC1.AJ62
VSSIO_SENSE: TP39.1(TP-1) UC1.AM22
VSSSENSE: PC653.2 PC654.2 PU602.18 RC151.1 UC1.E33
VSSSENSE_VCCGTUS: RC158.1 UC1.AL61
3D_CAM_EN: DX2.2 RX1.2 RX2.2 RX3.1 UE1.71 UX1.3
3D_CAM_EN_PCH: DX2.1 UC1.AN7
+DCBAT_CAM: JEDP1.3 JEDP1.4 R51.1
+DCBAT_LCD: C4.1 C5.1 F1.2 JEDP1.1 JEDP1.2 R51.2
+LAN_VDD10: CL5.1 CL6.1 UL1.8 UL1.30
+LAN_VDD33: CL7.1 CL8.1 JP11.1 RL1.1 RL5.1 UL1.32 UL3.1
+LAN_VDDREG: CL14.1 RL5.2 UL1.23
+LCDVDD: R3.2 U1.1
+LCDVDD_LCD: C2.1 C3.1 JEDP1.6 JEDP1.7 JEDP1.8 R3.1
+LINE1_VREFO_L: RA29.1 UA1.31
+LINE1_VREFO_R: RA33.1 UA1.30
+MIC2-VREFO: RA25.1 RA26.1 UA1.29
+RTC_CELL: C1.1 CC70.1 CC71.1 D1.1 D2.1 RA12.2 RC77.2 RC78.2 RC91.2 RE7.2 RE30.2 RE41.1 UC1.AK19 UC1.BB14
+RTC_CELL_VBAT: CE14.1 RE7.1 UE1.122
+RTC_VCC: JRTC1.1 R1.2
+TP_VDD: C19.1 JTP1.8 Q9.2 Q12.1 R31.1 R32.1 R36.2 R37.2 R39.1 R40.1 R41.1 R46.1 R47.1 ZT59.1(TP-1)
+TPAN_VDD: F2.2 JEDP1.40 R13.2
+TPAN_VDD_F: F2.1 R11.2 R12.2 R13.1
+V_DDR_REFA: CD28.1 JDIMM1.164 RD9.2 RD10.2 RD12.1
+V_DDR_REFA_R: CD30.1 RD9.1 UC1.AY67
+V_DDR_REFB: CD58.1 JDIMM2.164 RD19.2 RD20.2 RD21.1
+V_DDR_REFB_R: CD59.1 RD19.1 UC1.BA67
AC_DIS: PQ712.2 UE1.69
AC_PRESENT: DZ1.2 RC90.1 UC1.AY15
ACAV_IN: CE32.2 DZ1.1 PR12.1 PR731.1 PR741.2 PU703.2 UE1.128
ACIN_CHG: PC711.2 PQ712.1 PR729.2 PR732.1 PU703.1
ACLIM: PR749.1 PR751.2 PU703.16
ADJ_2.5V: PC803.2 PR801.2 PR802.1 PU800.7
ALERT#: R28.2 U2.6
ALL_SYS_PWRGD: RC105.2 RC106.2 RC107.1 RE42.2 UC6.4 UC7.2
ALWON: PR114.1 UE1.121
AMBER_LED_BAT: JLED1.2 Q3.1 ZT17.1(TP-1)
ASGATE: PR762.2 PU703.30
AUD_AGND: CA7.2 CA10.2 CA11.2 CA12.2 CA20.1 CA21.1 CA23.2 CA26.2 CA34.2 CA35.2 CA36.2 CA37.2 EC2301.1 EC2302.1 JHP1.7 RA17.2 RA18.2 RA22.2 RA30.2 RA34.2 RA40.2 RA41.1 UA1.25 UA1.38
AUD_HP1_JACK_L: RA27.1 UA1.32
AUD_HP1_JACK_L1: RA27.2 RA28.2 RA29.2 RA36.1
AUD_HP1_JACK_R: RA31.1 UA1.33
AUD_HP1_JACK_R1: RA31.2 RA32.2 RA33.2 RA37.1
AUD_PC_BEEP: CA31.2 UA1.16
AUD_PC_BEEP_C: DA3.1 RA23.1
AUD_SENSE: RA10.1 RA39.1
AUD_SENSE_A: CA7.1 RA3.1 RA10.2 UA1.13
AUD_SPK_L+: RA15.1 UA1.42
AUD_SPK_L+_C: CA28.1 DA1.3 JSPK1.3 RA15.2 ZT6.1(TP-1)
AUD_SPK_L-: RA16.1 UA1.43
AUD_SPK_L-_C: CA27.1 DA1.2 JSPK1.4 RA16.2 ZT7.1(TP-1)
AUD_SPK_R+: RA13.1 UA1.45
AUD_SPK_R+_C: CA30.1 DA2.3 JSPK1.1 RA13.2 ZT4.1(TP-1)
AUD_SPK_R-: RA14.1 UA1.44
AUD_SPK_R-_C: CA29.1 DA2.2 JSPK1.2 RA14.2 ZT5.1(TP-1)
AUD_VREF: CA23.1 UA1.28
BA: PD704.3 PQ710.1 PR780.1
BAT1_LED#: Q2.1 RE18.1 UE1.1
BAT2_LED#: Q2.4 RE21.1 UE1.106
BATT_WHITE_LED_R#: Q2.3 Q4.2 Q5.1
BEEP: DA3.2 UE1.45
BKLT_CTRL: D3.1 R9.1 RP1.8 RP2.7
BLON_OUT_C: JEDP1.24 RP1.7 RP2.1
BLUETOOTH_EN: JWLAN1.46 RC42.2 UC1.AB2
BOARD_ID: CE2.1 RE1.2 RE6.2 UE1.111
BOARD_ID2: RC55.2 RC56.1 UC1.AB3
BOARD_ID3: RC57.2 RC58.1 UC1.BA7
BREATH_LED#: Q16.3 R53.2 UE1.70
BST_1.2V: PR200.2 PU200.18
BST_1.2V_R: PC200.1 PR200.1
BST_3V: PR100.1 PU100.1
BST_5V: PR111.1 PU102.1
BST_+1VALW: PR306.1 PU300.1
BST_+1VALW_R: PC307.1 PR306.2
BST_+VCCEOPIO: PR1203.1 PU1200.9
BST_R_+VCCEOPIO: PC1201.1 PR1203.2
C0_1.0VS_VCCOPCP: PR1207.1 PU1200.4
C1_1.0VS_VCCOPCP: PR1206.2 PU1200.3
CAM_DETECT#: J3D1.7 RC63.2 UC1.P2
CAP_LED: JKB1.4 R25.2 ZT50.1(TP-1)
CAP_LED#: Q6.3 R24.2 UE1.93
CAP_LED_Q: Q7.1 R25.1
CAP_LED_R#: Q6.1 Q7.2
CBN: CA24.1 UA1.35
CBP: CA24.2 UA1.37
CCLIM: PR750.1 PR752.2 PU703.11
CFG0: RC131.2 TPC10.1(TP-1) UC1.E68
CFG1: RC132.2 TPC11.1(TP-1) UC1.B67
CFG2: TPC12.1(TP-1) UC1.D65
CFG3: RC133.2 RC175.1 TPC13.1(TP-1) UC1.D67
CFG4: RC136.2 TPC14.1(TP-1) UC1.E70
CFG5: TPC15.1(TP-1) UC1.C68
CFG6: TPC16.1(TP-1) UC1.D68
CFG7: TPC17.1(TP-1) UC1.C67
CFG8: TPC20.1(TP-1) UC1.F71
CFG9: TPC21.1(TP-1) UC1.G69
CFG10: TPC22.1(TP-1) UC1.F70
CFG11: TPC23.1(TP-1) UC1.G68
CFG12: TPC24.1(TP-1) UC1.H70
CFG13: TPC25.1(TP-1) UC1.G71
CFG14: TPC26.1(TP-1) UC1.H69
CFG15: TPC27.1(TP-1) UC1.G70
CFG16: TPC19.1(TP-1) UC1.E63
CFG17: TPC18.1(TP-1) UC1.F63
CFG18: TPC29.1(TP-1) UC1.E66
CFG19: TPC28.1(TP-1) UC1.F66
CFG_RCOMP: RC134.1 UC1.E60
CHG_AMBER_LED_R#: Q2.6 Q3.2
CLK_ITPXDP_N: TP8.1(TP-1) UC1.F43
CLK_ITPXDP_P: TP9.1(TP-1) UC1.E43
CLK_PCI_LPC_MEC: CC88.1 RC15.2 RE27.2 UE1.57
CLK_PCI_LPDEBUG: JDB1.1 RC16.2
CLK_PCIE_LAN_N2: UC1.D41 UL1.16
CLK_PCIE_LAN_P2: UC1.C41 UL1.15
CLK_PCIE_LAN_REQ#: RC73.2 RL13.1 UC1.AT8
CLK_PCIE_LAN_REQ#_R: RL13.2 RL16.2 UL1.12
CLK_PCIE_SSD_N3: JSSD1.3 UC1.D40
CLK_PCIE_SSD_P3: JSSD1.2 UC1.C40
CLK_PCIE_SSD_REQ#: JSSD1.20 RC188.2 UC1.AT10
CLK_PCIE_WLAN_N1: EC3201.1 JWLAN1.41 UC1.B42
CLK_PCIE_WLAN_P1: EC3202.1 JWLAN1.39 UC1.A42
CLK_PCIE_WLAN_REQ#: RC72.2 RW9.1 UC1.AT7
CLK_PCIE_WLAN_REQ#_R: JWLAN1.45 RW9.2 ZT63.1(TP-1)
CLK_SMB: PBATT1.7 PR18.1
CLK_TP_SIO: C27.1 JTP1.1 R32.2 UE1.78 ZT13.1(TP-1)
CLKRUN#: RC36.1 UC1.AW11 UE1.63
CMP_STRAP0: RE40.1 UE1.118
CMP_VIN0: RE37.2 RE52.1 UE1.20
CMP_VOUT0: PR116.1 RE49.2 RE52.2 UE1.85
CMSRC: PR763.2 PU703.29
COMP: PC751.2 PR754.2 PU703.10
COMP_IA: PC636.2 PR639.2 PU602.16
COMP_VSA: PC628.1 PR630.1 PU602.24
CORE_SNUB: PC662.1 PR663.2
CORE_SW: PL603.4 PR663.1 PU603.8
CPU_B+: PC606.1 PC656.1 PC657.1 PC658.1 PC659.1 PC660.1 PC680.1 PC686.1 PC691.1 PC694.1 PJP601.1 PJP603.2 PL602.1 PR603.2 PU603.6 PU603.11
CPU_DP3_AUXN: TP1.1(TP-1) UC1.G46
CPU_DP3_AUXP: TP2.1(TP-1) UC1.F46
CPU_POPIRCOMP: RC119.1 UC1.AT16
CPU_XDP_TCK0: RC146.1 TPC2.1(TP-1) UC1.A59 UC1.B61
CPVEE: CA25.2 UA1.34
CS_1.2V: PR205.2 PU200.13
CSI2_COMP: RC7.1 UC1.E13
DAT_SMB: PBATT1.6 PR20.1
DAT_TP_SIO: C26.1 JTP1.2 R31.2 UE1.79 ZT12.1(TP-1)
DBC_EN: R6.2 UC1.AM5
DBC_EN_R: JEDP1.10 R5.2 R6.1
DDC_CLK_HDMI: JHDMI1.15 QI2.6 RI13.1
DDC_DATA_HDMI: JHDMI1.16 QI2.3 RI14.1
DDR4_DRAMRST#: CD29.1 JDIMM1.108 JDIMM2.108 RD8.1
DDR_A_ACT#: JDIMM1.114 UC1.BA55
DDR_A_ALERT#: JDIMM1.116 UC1.AW50
DDR_A_BG0: JDIMM1.115 UC1.AY55
DDR_A_BG1: JDIMM1.113 UC1.AY54
DDR_A_BS0: JDIMM1.150 UC1.AU52
DDR_A_BS1: JDIMM1.145 UC1.AT48
DDR_A_CAS#: JDIMM1.156 UC1.AU48
DDR_A_CKE0: JDIMM1.109 UC1.BA56
DDR_A_CKE1: JDIMM1.110 UC1.BB56
DDR_A_CKE2: TP3.1(TP-1) UC1.AW56
DDR_A_CKE3: TP4.1(TP-1) UC1.AY56
DDR_A_CLK0: JDIMM1.137 UC1.AT53
DDR_A_CLK1: JDIMM1.138 UC1.AT55
DDR_A_CLK#0: JDIMM1.139 UC1.AU53
DDR_A_CLK#1: JDIMM1.140 UC1.AU55
DDR_A_CS#0: JDIMM1.149 UC1.AU45
DDR_A_CS#1: JDIMM1.157 UC1.AU43
DDR_A_D0: JDIMM1.4 UC1.AL71
DDR_A_D1: JDIMM1.3 UC1.AL68
DDR_A_D2: JDIMM1.20 UC1.AN68
DDR_A_D3: JDIMM1.21 UC1.AN69
DDR_A_D4: JDIMM1.8 UC1.AL70
DDR_A_D5: JDIMM1.7 UC1.AL69
DDR_A_D6: JDIMM1.16 UC1.AN70
DDR_A_D7: JDIMM1.17 UC1.AN71
DDR_A_D8: JDIMM1.29 UC1.AR70
DDR_A_D9: JDIMM1.25 UC1.AR68
DDR_A_D10: JDIMM1.37 UC1.AU71
DDR_A_D11: JDIMM1.41 UC1.AU68
DDR_A_D12: JDIMM1.24 UC1.AR71
DDR_A_D13: JDIMM1.28 UC1.AR69
DDR_A_D14: JDIMM1.42 UC1.AU70
DDR_A_D15: JDIMM1.38 UC1.AU69
DDR_A_D16: JDIMM1.45 UC1.BB65
DDR_A_D17: JDIMM1.49 UC1.AW65
DDR_A_D18: JDIMM1.63 UC1.AW63
DDR_A_D19: JDIMM1.58 UC1.AY63
DDR_A_D20: JDIMM1.50 UC1.BA65
DDR_A_D21: JDIMM1.46 UC1.AY65
DDR_A_D22: JDIMM1.59 UC1.BA63
DDR_A_D23: JDIMM1.62 UC1.BB63
DDR_A_D24: JDIMM1.67 UC1.BA61
DDR_A_D25: JDIMM1.70 UC1.AW61
DDR_A_D26: JDIMM1.79 UC1.BB59
DDR_A_D27: JDIMM1.84 UC1.AW59
DDR_A_D28: JDIMM1.66 UC1.BB61
DDR_A_D29: JDIMM1.71 UC1.AY61
DDR_A_D30: JDIMM1.83 UC1.BA59
DDR_A_D31: JDIMM1.80 UC1.AY59
DDR_A_D32: JDIMM1.174 UC1.AY39
DDR_A_D33: JDIMM1.170 UC1.AW39
DDR_A_D34: JDIMM1.187 UC1.AY37
DDR_A_D35: JDIMM1.186 UC1.AW37
DDR_A_D36: JDIMM1.169 UC1.BB39
DDR_A_D37: JDIMM1.173 UC1.BA39
DDR_A_D38: JDIMM1.182 UC1.BA37
DDR_A_D39: JDIMM1.183 UC1.BB37
DDR_A_D40: JDIMM1.195 UC1.AY35
DDR_A_D41: JDIMM1.191 UC1.AW35
DDR_A_D42: JDIMM1.207 UC1.AY33
DDR_A_D43: JDIMM1.203 UC1.AW33
DDR_A_D44: JDIMM1.194 UC1.BB35
DDR_A_D45: JDIMM1.190 UC1.BA35
DDR_A_D46: JDIMM1.208 UC1.BA33
DDR_A_D47: JDIMM1.204 UC1.BB33
DDR_A_D48: JDIMM1.211 UC1.AY31
DDR_A_D49: JDIMM1.216 UC1.AW31
DDR_A_D50: JDIMM1.229 UC1.AY29
DDR_A_D51: JDIMM1.228 UC1.AW29
DDR_A_D52: JDIMM1.215 UC1.BB31
DDR_A_D53: JDIMM1.212 UC1.BA31
DDR_A_D54: JDIMM1.224 UC1.BA29
DDR_A_D55: JDIMM1.225 UC1.BB29
DDR_A_D56: JDIMM1.237 UC1.AY27
DDR_A_D57: JDIMM1.233 UC1.AW27
DDR_A_D58: JDIMM1.236 UC1.AY25
DDR_A_D59: JDIMM1.232 UC1.AW25
DDR_A_D60: JDIMM1.245 UC1.BB27
DDR_A_D61: JDIMM1.249 UC1.BA27
DDR_A_D62: JDIMM1.246 UC1.BA25
DDR_A_D63: JDIMM1.250 UC1.BB25
DDR_A_DQS0: JDIMM1.13 UC1.AM69
DDR_A_DQS1: JDIMM1.34 UC1.AT70
DDR_A_DQS2: JDIMM1.55 UC1.AY64
DDR_A_DQS3: JDIMM1.76 UC1.BA60
DDR_A_DQS4: JDIMM1.179 UC1.AY38
DDR_A_DQS5: JDIMM1.200 UC1.BA34
DDR_A_DQS6: JDIMM1.221 UC1.AY30
DDR_A_DQS7: JDIMM1.242 UC1.BA26
DDR_A_DQS#0: JDIMM1.11 UC1.AM70
DDR_A_DQS#1: JDIMM1.32 UC1.AT69
DDR_A_DQS#2: JDIMM1.53 UC1.BA64
DDR_A_DQS#3: JDIMM1.74 UC1.AY60
DDR_A_DQS#4: JDIMM1.177 UC1.BA38
DDR_A_DQS#5: JDIMM1.198 UC1.AY34
DDR_A_DQS#6: JDIMM1.219 UC1.BA30
DDR_A_DQS#7: JDIMM1.240 UC1.AY26
DDR_A_MA0: JDIMM1.144 UC1.AY50
DDR_A_MA1: JDIMM1.133 UC1.BB50
DDR_A_MA2: JDIMM1.132 UC1.AY51
DDR_A_MA3: JDIMM1.131 UC1.BA50
DDR_A_MA4: JDIMM1.128 UC1.BB52
DDR_A_MA5: JDIMM1.126 UC1.BA51
DDR_A_MA6: JDIMM1.127 UC1.BA52
DDR_A_MA7: JDIMM1.122 UC1.AW52
DDR_A_MA8: JDIMM1.125 UC1.AY52
DDR_A_MA9: JDIMM1.121 UC1.BB54
DDR_A_MA10: JDIMM1.146 UC1.AT50
DDR_A_MA11: JDIMM1.120 UC1.BA54
DDR_A_MA12: JDIMM1.119 UC1.AW54
DDR_A_MA13: JDIMM1.158 UC1.AU46
DDR_A_ODT0: JDIMM1.155 UC1.AT45
DDR_A_ODT1: JDIMM1.161 UC1.AT43
DDR_A_PAR: JDIMM1.143 UC1.AT52
DDR_A_RAS#: JDIMM1.152 UC1.AU50
DDR_A_WE#: JDIMM1.151 UC1.AT46
DDR_B_ACT#: JDIMM2.114 UC1.AN53
DDR_B_ALERT#: JDIMM2.116 UC1.AN43
DDR_B_BG0: JDIMM2.115 UC1.AP52
DDR_B_BG1: JDIMM2.113 UC1.AN52
DDR_B_BS0: JDIMM2.150 UC1.BB44
DDR_B_BS1: JDIMM2.145 UC1.BA44
DDR_B_CAS#: JDIMM2.156 UC1.AY43
DDR_B_CKE0: JDIMM2.109 UC1.AN56
DDR_B_CKE1: JDIMM2.110 UC1.AP55
DDR_B_CKE2: TP5.1(TP-1) UC1.AN55
DDR_B_CKE3: TP6.1(TP-1) UC1.AP53
DDR_B_CLK0: JDIMM2.137 UC1.AP45
DDR_B_CLK1: JDIMM2.138 UC1.AP46
DDR_B_CLK#0: JDIMM2.139 UC1.AN45
DDR_B_CLK#1: JDIMM2.140 UC1.AN46
DDR_B_CS#0: JDIMM2.149 UC1.BB42
DDR_B_CS#1: JDIMM2.157 UC1.AY42
DDR_B_D0: JDIMM2.28 UC1.AF65
DDR_B_D1: JDIMM2.25 UC1.AF64
DDR_B_D2: JDIMM2.42 UC1.AK65
DDR_B_D3: JDIMM2.38 UC1.AK64
DDR_B_D4: JDIMM2.24 UC1.AF66
DDR_B_D5: JDIMM2.29 UC1.AF67
DDR_B_D6: JDIMM2.41 UC1.AK67
DDR_B_D7: JDIMM2.37 UC1.AK66
DDR_B_D8: JDIMM2.8 UC1.AF70
DDR_B_D9: JDIMM2.4 UC1.AF68
DDR_B_D10: JDIMM2.21 UC1.AH71
DDR_B_D11: JDIMM2.20 UC1.AH68
DDR_B_D12: JDIMM2.7 UC1.AF71
DDR_B_D13: JDIMM2.3 UC1.AF69
DDR_B_D14: JDIMM2.16 UC1.AH70
DDR_B_D15: JDIMM2.17 UC1.AH69
DDR_B_D16: JDIMM2.45 UC1.AT66
DDR_B_D17: JDIMM2.49 UC1.AU66
DDR_B_D18: JDIMM2.62 UC1.AP65
DDR_B_D19: JDIMM2.59 UC1.AN65
DDR_B_D20: JDIMM2.50 UC1.AN66
DDR_B_D21: JDIMM2.46 UC1.AP66
DDR_B_D22: JDIMM2.63 UC1.AT65
DDR_B_D23: JDIMM2.58 UC1.AU65
DDR_B_D24: JDIMM2.71 UC1.AT61
DDR_B_D25: JDIMM2.66 UC1.AU61
DDR_B_D26: JDIMM2.79 UC1.AP60
DDR_B_D27: JDIMM2.84 UC1.AN60
DDR_B_D28: JDIMM2.70 UC1.AN61
DDR_B_D29: JDIMM2.67 UC1.AP61
DDR_B_D30: JDIMM2.83 UC1.AT60
DDR_B_D31: JDIMM2.80 UC1.AU60
DDR_B_D32: JDIMM2.169 UC1.AU40
DDR_B_D33: JDIMM2.173 UC1.AT40
DDR_B_D34: JDIMM2.183 UC1.AT37
DDR_B_D35: JDIMM2.187 UC1.AU37
DDR_B_D36: JDIMM2.170 UC1.AR40
DDR_B_D37: JDIMM2.174 UC1.AP40
DDR_B_D38: JDIMM2.186 UC1.AP37
DDR_B_D39: JDIMM2.182 UC1.AR37
DDR_B_D40: JDIMM2.190 UC1.AT33
DDR_B_D41: JDIMM2.194 UC1.AU33
DDR_B_D42: JDIMM2.207 UC1.AU30
DDR_B_D43: JDIMM2.203 UC1.AT30
DDR_B_D44: JDIMM2.191 UC1.AR33
DDR_B_D45: JDIMM2.195 UC1.AP33
DDR_B_D46: JDIMM2.204 UC1.AR30
DDR_B_D47: JDIMM2.208 UC1.AP30
DDR_B_D48: JDIMM2.216 UC1.AU27
DDR_B_D49: JDIMM2.212 UC1.AT27
DDR_B_D50: JDIMM2.225 UC1.AT25
DDR_B_D51: JDIMM2.229 UC1.AU25
DDR_B_D52: JDIMM2.211 UC1.AP27
DDR_B_D53: JDIMM2.215 UC1.AN27
DDR_B_D54: JDIMM2.228 UC1.AN25
DDR_B_D55: JDIMM2.224 UC1.AP25
DDR_B_D56: JDIMM2.232 UC1.AT22
DDR_B_D57: JDIMM2.236 UC1.AU22
DDR_B_D58: JDIMM2.249 UC1.AU21
DDR_B_D59: JDIMM2.245 UC1.AT21
DDR_B_D60: JDIMM2.237 UC1.AN22
DDR_B_D61: JDIMM2.233 UC1.AP22
DDR_B_D62: JDIMM2.250 UC1.AP21
DDR_B_D63: JDIMM2.246 UC1.AN21
DDR_B_DQS0: JDIMM2.34 UC1.AH65
DDR_B_DQS1: JDIMM2.13 UC1.AG70
DDR_B_DQS2: JDIMM2.55 UC1.AR65
DDR_B_DQS3: JDIMM2.76 UC1.AR60
DDR_B_DQS4: JDIMM2.179 UC1.AR38
DDR_B_DQS5: JDIMM2.200 UC1.AR32
DDR_B_DQS6: JDIMM2.221 UC1.AR27
DDR_B_DQS7: JDIMM2.242 UC1.AR21
DDR_B_DQS#0: JDIMM2.32 UC1.AH66
DDR_B_DQS#1: JDIMM2.11 UC1.AG69
DDR_B_DQS#2: JDIMM2.53 UC1.AR66
DDR_B_DQS#3: JDIMM2.74 UC1.AR61
DDR_B_DQS#4: JDIMM2.177 UC1.AT38
DDR_B_DQS#5: JDIMM2.198 UC1.AT32
DDR_B_DQS#6: JDIMM2.219 UC1.AR25
DDR_B_DQS#7: JDIMM2.240 UC1.AR22
DDR_B_MA0: JDIMM2.144 UC1.BA46
DDR_B_MA1: JDIMM2.133 UC1.AY46
DDR_B_MA2: JDIMM2.132 UC1.AY47
DDR_B_MA3: JDIMM2.131 UC1.BB46
DDR_B_MA4: JDIMM2.128 UC1.BA47
DDR_B_MA5: JDIMM2.126 UC1.AY48
DDR_B_MA6: JDIMM2.127 UC1.BA48
DDR_B_MA7: JDIMM2.122 UC1.AP48
DDR_B_MA8: JDIMM2.125 UC1.BB48
DDR_B_MA9: JDIMM2.121 UC1.AP50
DDR_B_MA10: JDIMM2.146 UC1.AW46
DDR_B_MA11: JDIMM2.120 UC1.AN48
DDR_B_MA12: JDIMM2.119 UC1.AN50
DDR_B_MA13: JDIMM2.158 UC1.BA43
DDR_B_ODT0: JDIMM2.155 UC1.BA42
DDR_B_ODT1: JDIMM2.161 UC1.AW42
DDR_B_PAR: JDIMM2.143 UC1.AP43
DDR_B_RAS#: JDIMM2.152 UC1.AW44
DDR_B_WE#: JDIMM2.151 UC1.AY44
DDR_VTT_CNTL: UC1.AW67 UC2.2
DIMM_CHA_SA0: JDIMM1.256 RD1.2 RD4.1
DIMM_CHA_SA1: JDIMM1.260 RD2.2 RD5.1
DIMM_CHA_SA2: JDIMM1.166 RD3.2 RD6.1
DIMM_CHB_SA0: JDIMM2.256 RD13.2 RD16.1
DIMM_CHB_SA1: JDIMM2.260 RD14.2 RD17.1
DIMM_CHB_SA2: JDIMM2.166 RD15.2 RD18.1
DMIC_CLK: L5.2 UA1.3
DMIC_CLK_EDP: JEDP1.28 L5.1 R56.1
DMIC_DATA: RA42.2 UA1.2
DMIC_DATA_EDP: JEDP1.29 RA42.1
DRMOS_EN: PR655.2 PU603.12 PU604.12 PU605.12
E51_TX1: JWLAN1.36 RW6.2
EC_AGND: CE1.2 CE2.2 CE21.2 CE25.2 CE30.2 RE4.1 RE6.1 RE50.1 UE1.112
EC_MUTE#: RA8.2 RE24.1 RE28.1 UA1.47
EC_MUTE#_R: RE28.2 UE1.119
EC_SPI_CLK: RE33.2 UE1.32
EC_SPI_CS0#: RE38.1 UE1.27
EC_SPI_MISO: RE35.2 UE1.29
EC_SPI_MOSI: RE34.2 UE1.28
EC_WAKE#: RC100.1 UE1.35
EDP_AUX: C11.2 JEDP1.14
EDP_AUX#: C10.2 JEDP1.15
EDP_AUX_DN: C10.1 UC1.E45
EDP_AUX_DP: C11.1 UC1.F45
EDP_BKLT_CTRL: D3.2 R8.2 R9.2
EDP_COMP: RC4.2 UC1.E52
EDP_HPD: JEDP1.11 RP1.6 UC1.L10
EDP_TX0: C7.2 JEDP1.18
EDP_TX0#: C6.2 JEDP1.17
EDP_TX0_DN: C6.1 UC1.C47
EDP_TX0_DP: C7.1 UC1.C46
EDP_TX1: C9.2 JEDP1.21
EDP_TX1#: C8.2 JEDP1.20
EDP_TX1_DN: C8.1 UC1.D46
EDP_TX1_DP: C9.1 UC1.C45
EDP_VDD_EN: D4.2 UC1.U13
EDRAM_OPIO_RCOMP: RC121.1 UC1.H66
EMMC_RCOMP: RC8.1 UC1.AT1
EN_0.6VSP: PC203.1 PR202.2 PU200.7
EN_1.0V_VCCST_ON: CZ1.1 DZ5.2 RZ1.2 RZ9.1 UZ1.3
EN_1.2V: PC202.1 PR201.2 PU200.8
EN_1.8VALW: PC502.1 PR501.2 PR502.2 PU500.5
EN_2.5V: PC805.1 PR803.2 PU800.2
EN_3V: PR121.1 PU100.12
EN_5V: PR120.1 PU102.12
EN_+1VALW: PC304.1 PR301.2 PR302.1 PU300.11
EN_+VCCEOPIO: PC1204.1 PR1204.1 PR1205.1 PU1200.5
ENLDO_3V5V: PR102.1 PR103.1 PU100.11 PU102.11
EOPIO_RCOMP: RC122.1 UC1.H65
FAN1_PWM: JFAN1.2 R50.1 UE1.47 ZT14.1(TP-1)
FAN1_TACH: CE28.1 D8.2 R55.2 RE13.1 UE1.40 ZT15.1(TP-1)
FB_1.2V: PC214.1 PR204.1 PR207.1 PU200.6
FB_1.8VALW: PC503.2 PR504.1 PR505.1 PU500.6
FB_+1VALW: PC309.2 PR309.1 PR310.1 PU300.14
FB_IA: PR645.2 PR648.2 PR650.1 PU602.17
FB_VSA: PR646.1 PR649.1 PR652.1 PU602.25
FCCM_GT: PR664.2 PR671.2 PU602.11
FCCM_IA: PR659.2 PU602.21
FCCM_VSA: PR679.2 PU602.29
FW_UPDATE: DX3.2 J3D1.8 RX10.2 RX13.2 UE1.34
FW_UPDATE_PCH: DX3.1 UC1.AP5
GPP_B23: RC39.1 UC1.AM7
GPP_C5: RC38.1 UC1.W1
GPU_B+: PC664.1 PC665.1 PC666.1 PC667.1 PC668.1 PC672.1 PC673.1 PC674.1 PC679.1 PC681.1 PC687.1 PC688.1 PC690.1 PC692.1 PC693.1 PJP602.1 PL606.1 PU604.6 PU604.11 PU605.6 PU605.11
GT1N: PL605.2 PR670.1 PR673.1
GT1P: PL605.3 PR674.2 PR675.1
GT2N: PL604.2 PR666.1 PR677.2
GT2P: PL604.3 PR667.2 PR668.1
GT_SNUB1: PC678.1 PR676.2
GT_SNUB2: PC670.1 PR669.2
GT_SW1: PL605.4 PR676.1 PU605.8
GT_SW2: PL604.4 PR669.1 PU604.8
H_CATERR#: RC111.2 UC1.D63
H_CPU_SVIDALRT#: RC153.1 UC1.B63
H_CPUPWRGD: CC15.1 RC95.2 UC1.A68
H_CPUPWRGD_R: RC95.1 TP7.1(TP-1)
H_DRAMRST#: RD7.2 RD8.2 UC1.AT13
H_PROCHOT#: CE26.1 PC605.2 PQ2.6 PQ3.1 PQ721.1 PR678.1 PR777.1 RC113.2 RC117.1 UE2.4
H_PROCHOT#_R: RC117.2 UC1.C65
H_PROCHOT_EC: RE53.2 UE1.83 UE2.2
H_THERMTRIP#: RC112.2 TP14.1(TP-1) UC1.C63
H_VCCST_PWRGD: RC96.1 RC104.1 UC7.4
HDA_BIT_CLK: RC124.2 UC1.AY22
HDA_CODEC_BITCLK: CC16.1 RC124.1 UA1.6
HDA_CODEC_RST#: RC127.1 TP74.1(TP-1)
HDA_CODEC_SDIN0: RA7.2 UA1.8
HDA_CODEC_SDOUT: RC125.1 UA1.5
HDA_CODEC_SYNC: RC123.1 UA1.10
HDA_RST#: CC89.1 RC127.2 UC1.AW22
HDA_SDIN0: RA7.1 UC1.BA21
HDA_SDOUT: RC125.2 RC126.2 RC129.2 UC1.BB22
HDA_SYNC: RC123.2 UC1.BA22
HDD_DEVSLP: RS1.2 UC1.J1
HDD_DEVSLP_R: JHDD1.8 RS1.1
HDMI_CLK: CI1.1 UC1.G56
HDMI_CLK#: CI2.1 UC1.F56
HDMI_CLK#_R: CI2.2 LI1.2 RI1.1 RPI2.6
HDMI_CLK#_R_C: JHDMI1.12 LI1.1 RI1.2 RI3.2
HDMI_CLK_R: CI1.2 LI1.3 RI2.1 RPI2.5
HDMI_CLK_R_C: JHDMI1.10 LI1.4 RI2.2 RI3.1
HDMI_DATA0: CI3.1 UC1.G53
HDMI_DATA0#: CI4.1 UC1.F53
HDMI_DATA0#_R: CI4.2 LI2.2 RI5.1 RPI2.8
HDMI_DATA0#_R_C: JHDMI1.9 LI2.1 RI5.2 RI6.2
HDMI_DATA0_R: CI3.2 LI2.3 RI4.1 RPI2.7
HDMI_DATA0_R_C: JHDMI1.7 LI2.4 RI4.2 RI6.1
HDMI_DATA1: CI7.1 UC1.F58
HDMI_DATA1#: CI8.1 UC1.E58
HDMI_DATA1#_R: CI8.2 LI3.2 RI7.1 RPI1.8
HDMI_DATA1#_R_C: JHDMI1.6 LI3.1 RI7.2 RI9.2
HDMI_DATA1_R: CI7.2 LI3.3 RI8.1 RPI1.7
HDMI_DATA1_R_C: JHDMI1.4 LI3.4 RI8.2 RI9.1
HDMI_DATA2: CI5.1 UC1.F55
HDMI_DATA2#: CI6.1 UC1.E55
HDMI_DATA2#_R: CI6.2 LI4.2 RI10.1 RPI1.6
HDMI_DATA2#_R_C: JHDMI1.3 LI4.1 RI10.2 RI12.2
HDMI_DATA2_R: CI5.2 LI4.3 RI11.1 RPI1.5
HDMI_DATA2_R_C: JHDMI1.1 LI4.4 RI11.2 RI12.1
HDMI_HPD: QI3.3 RI15.2 UC1.L9
HDMI_HPD_B: JHDMI1.19 QI3.1 RI16.1
HDMI_PLL_GND: QI1.1 RPI1.1 RPI1.2 RPI1.3 RPI1.4 RPI2.1 RPI2.2 RPI2.3 RPI2.4
HOST_DEBUG_TX: JDEG1.8 JWLAN1.30 RE59.2 RW6.1 RW8.1 UE1.81 ZT57.1(TP-1)
HPOUT_L: CA35.1 DA4.2 JHP1.1 RA30.1 RA36.2 ZT19.1(TP-1)
HPOUT_R: CA34.1 DA4.3 JHP1.2 RA34.1 RA37.2 ZT22.1(TP-1)
I2C_SCL_TP: Q10.1 R34.2 UC1.U6
I2C_SCL_TP_Q: JTP1.6 Q10.6 R46.2 ZT9.1(TP-1)
I2C_SDA_TP: Q10.4 R33.2 UC1.U7
I2C_SDA_TP_Q: JTP1.7 Q10.3 R47.2 ZT8.1(TP-1)
I_ADP: PC748.1 PR774.1 RE51.2
I_ADP_R: CE25.1 RE51.1 UE1.110
I_BATT: PC749.2 PR775.1 RE54.2
I_BATT_R: CE30.1 RE54.1 UE1.114
I_SYS: PR620.1 PR727.1 PU703.8 RE44.1
ICSP_CLK: RE24.2 RE60.1 UE1.101
ICSP_CLK_R: JDEG1.2 RE60.2 ZT53.1(TP-1)
ICSP_CLR: RE61.1 UE1.87
ICSP_CLR_R: JDEG1.3 RE61.2 ZT54.1(TP-1)
ICSP_DAT: RE26.2 RE63.1 UE1.102
ICSP_DAT_R: JDEG1.5 RE63.2 ZT56.1(TP-1)
ILMT_+1VALW: PR304.2 PR305.1 PU300.13
IMON_IA: PC625.2 PR629.2 PU602.14
IMON_VSA: PC643.1 PR651.1 PU602.23
IMVP_VR_ON: PR616.1 PR655.1 RC107.2
INT_TP#: JTP1.4 Q9.3 R39.2 ZT10.1(TP-1)
INTRUDER#: RC91.1 UC1.AP16
IR_CAM_DETECT#: JEDP1.34 RC64.2 UC1.P4
IR_GND: JEDP1.25 JEDP1.26 R54.1
ISEN1_GT: PC635.2 PR615.2 PR675.2 PR677.1 PU602.9
ISEN2_GT: PC638.2 PR634.2 PR668.2 PR670.2 PU602.10
ISOLATE#: RL3.2 RL4.1 UL1.20
ISUMN_GT: PC624.2 PC626.2 PC635.1 PC638.1 PC641.1 PH602.2 PR632.1 PR633.2 PR638.1 PR666.2 PR673.2
ISUMN_IA: PC642.2 PC645.1 PC646.2 PH605.2 PL603.2 PR640.2 PR644.2 PR656.2
ISUMN_VSA: PC633.2 PC637.2 PC644.1 PH604.2 PL601.2 PR636.2 PR641.2 PR643.1
ISUMP_GT: PC624.1 PC626.1 PR628.1 PR633.1 PR637.1 PR667.1 PR674.1 PU602.7
ISUMP_IA: PC642.1 PC646.1 PR653.1 PR656.1 PR657.1 PR661.2 PU602.19
ISUMP_VSA: PC633.1 PC637.1 PR624.2 PR642.1 PR643.2 PR654.1 PU602.27
JACK_PLUG: JHP1.5 RA39.2 ZT20.1(TP-1)
JACK_PLUG_DET: JHP1.6 RA40.1 ZT21.1(TP-1)
KB_BL_CTRL#: EC3001.1 JKBBL1.4 Q8.1 ZT52.1(TP-1)
KB_DET#: JKB1.30 RC45.1 UC1.BB7 ZT24.1(TP-1)
KB_LED_BL_DET: R26.1 R27.1 UC1.W8
KB_LED_DET_C: JKBBL1.2 R26.2 ZT51.1(TP-1)
KB_LED_PWM: Q8.2 UE1.44
KSI0: JKB1.22 RPE1.4 UE1.98 ZT32.1(TP-1)
KSI1: JKB1.24 RPE1.3 UE1.99 ZT30.1(TP-1)
KSI2: JKB1.26 RPE1.2 UE1.6 ZT28.1(TP-1)
KSI3: JKB1.23 RPE1.1 UE1.7 ZT31.1(TP-1)
KSI4: JKB1.27 RPE2.4 UE1.104 ZT27.1(TP-1)
KSI5: JKB1.25 RPE2.3 UE1.105 ZT29.1(TP-1)
KSI6: JKB1.28 RPE2.2 UE1.107 ZT26.1(TP-1)
KSI7: JKB1.29 RPE2.1 UE1.108 ZT25.1(TP-1)
KSO0: JKB1.13 RPE3.8 UE1.2 ZT41.1(TP-1)
KSO1: JKB1.15 RPE3.7 UE1.14 ZT39.1(TP-1)
KSO2: JKB1.14 RPE3.6 UE1.15 ZT40.1(TP-1)
KSO3: JKB1.16 RPE3.5 UE1.16 ZT38.1(TP-1)
KSO4: JKB1.20 RPE4.8 UE1.37 ZT34.1(TP-1)
KSO5: JKB1.21 RPE4.7 UE1.38 ZT33.1(TP-1)
KSO6: JKB1.18 RPE4.6 UE1.39 ZT36.1(TP-1)
KSO7: JKB1.19 RPE4.5 UE1.50 ZT35.1(TP-1)
KSO8: JKB1.17 RPE6.8 UE1.46 ZT37.1(TP-1)
KSO9: JKB1.7 RE15.1 UE1.68 ZT47.1(TP-1)
KSO10: JKB1.5 RPE5.8 UE1.72 ZT49.1(TP-1)
KSO11: JKB1.6 RPE5.7 UE1.74 ZT48.1(TP-1)
KSO12: JKB1.12 RPE5.6 UE1.75 ZT42.1(TP-1)
KSO13: JKB1.9 RPE5.5 UE1.76 ZT45.1(TP-1)
KSO14: JKB1.8 RPE6.6 UE1.77 ZT46.1(TP-1)
KSO15: JKB1.10 RPE6.7 UE1.86 ZT44.1(TP-1)
KSO16: JKB1.11 RPE6.5 UE1.92 ZT43.1(TP-1)
L_BKLT_CTRL: R8.1 UC1.R11
L_BKLT_EN_EC: RC6.2 UC1.R12 UE1.91
LAN_EN: RL6.2 UE1.3 UL3.4
LAN_MDI0N: EU3501.2 EU3501.8 TL1.5 UL1.2
LAN_MDI0P: EU3501.1 EU3501.9 TL1.6 UL1.1
LAN_MDI1N: EU3501.5 EU3501.6 TL1.1 UL1.5
LAN_MDI1P: EU3501.4 EU3501.7 TL1.2 UL1.4
LAN_TXN_C_PCH_RXN6: CL2.2 UL1.18
LAN_TXP_C_PCH_RXP6: CL1.2 UL1.17
LAN_WAKE#: RC85.2 RC100.2 UC1.AM15
LANXIN: CL10.1 UL1.28 YL1.1
LANXOUT: CL11.1 UL1.29 YL1.3
LCD_BRIGHTNESS: JEDP1.23 RP2.2
LCD_TST: D3.3 RP2.6 UE1.26
LCD_TST_C: JEDP1.12 RP2.3
LCD_VCC_TEST_EN: RE44.2 RE64.2 UE1.113
LCD_VCC_TEST_EN_R: D4.3 RE64.1
LCDVDD_EN: D4.1 R10.1 U1.4
LDO1_CAP: CA20.2 RA41.2 UA1.27
LDO2_CAP: CA21.2 UA1.39
LDO3_CAP: CA22.2 UA1.7
LDO_+1VALW: PC306.1 PU300.16 PU300.17
LED1: RL1.2 UL1.26
LG_1.2V: PQ201.8 PU200.15
LGATE_CHG: PQ708.4 PU703.21
LID_CLOSE#: CE19.1 D5.1 R22.1 RE25.2 UE1.41
LID_CLOSE#_C: EC2902.1 JPWR1.2 R22.2 ZT3.1(TP-1)
LINE1-L_C: CA32.2 RA28.1
LINE1-L_R: CA33.2 RA32.1
LINE1_L: CA32.1 UA1.22
LINE1_R: CA33.1 UA1.21
LOM_TCT: CL12.1 TL1.3 TL1.4
LP#_+VCCEOPIO: PR1201.1 PU1200.6
LPC_LAD0: JDB1.8 UC1.AY13 UE1.59
LPC_LAD1: JDB1.7 UC1.BA13 UE1.60
LPC_LAD2: JDB1.6 UC1.BB13 UE1.61
LPC_LAD3: JDB1.5 UC1.AY12 UE1.62
LPC_LFRAME#: JDB1.4 UC1.BA12 UE1.58
LPSS_UART2_CTS#: RC43.1 UC1.AD4
LX_1.2V: PC200.2 PC207.1 PL200.2 PQ201.9 PU200.16
LX_1.8VALW: PL501.1 PR506.1 PU500.2 PU500.3
LX_3V: PC102.2 PL100.1 PR106.1 PU100.6 PU100.19 PU100.20
LX_5V: PC114.2 PL101.1 PR112.1 PU102.6 PU102.19 PU102.20
LX_+1VALW: PC307.2 PL301.1 PR307.1 PU300.6 PU300.19 PU300.20
M2_SLOT2_PEDET: JSSD1.18 UC1.G4
MCT: CL13.1 RL14.1 RL15.1
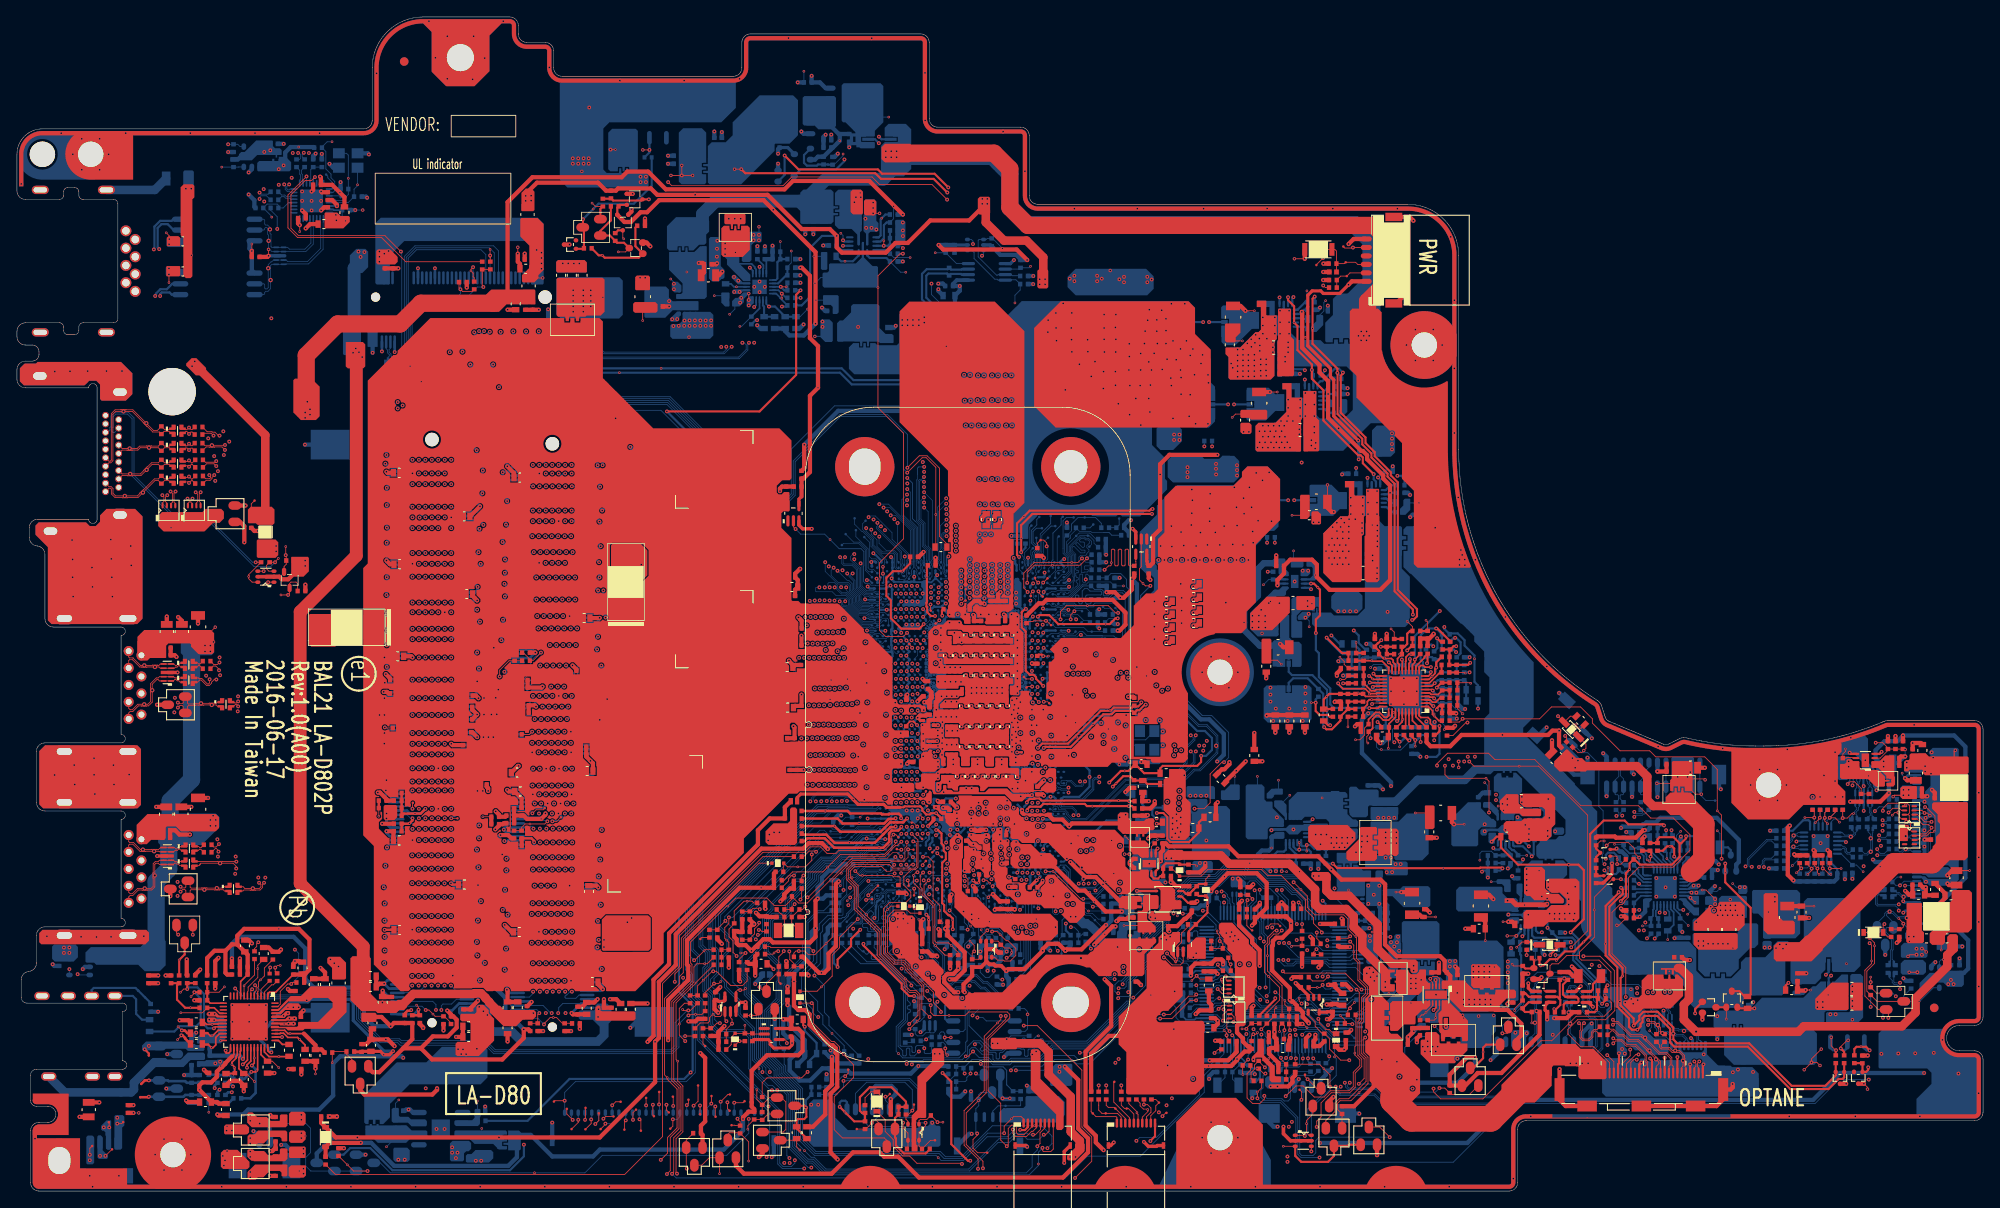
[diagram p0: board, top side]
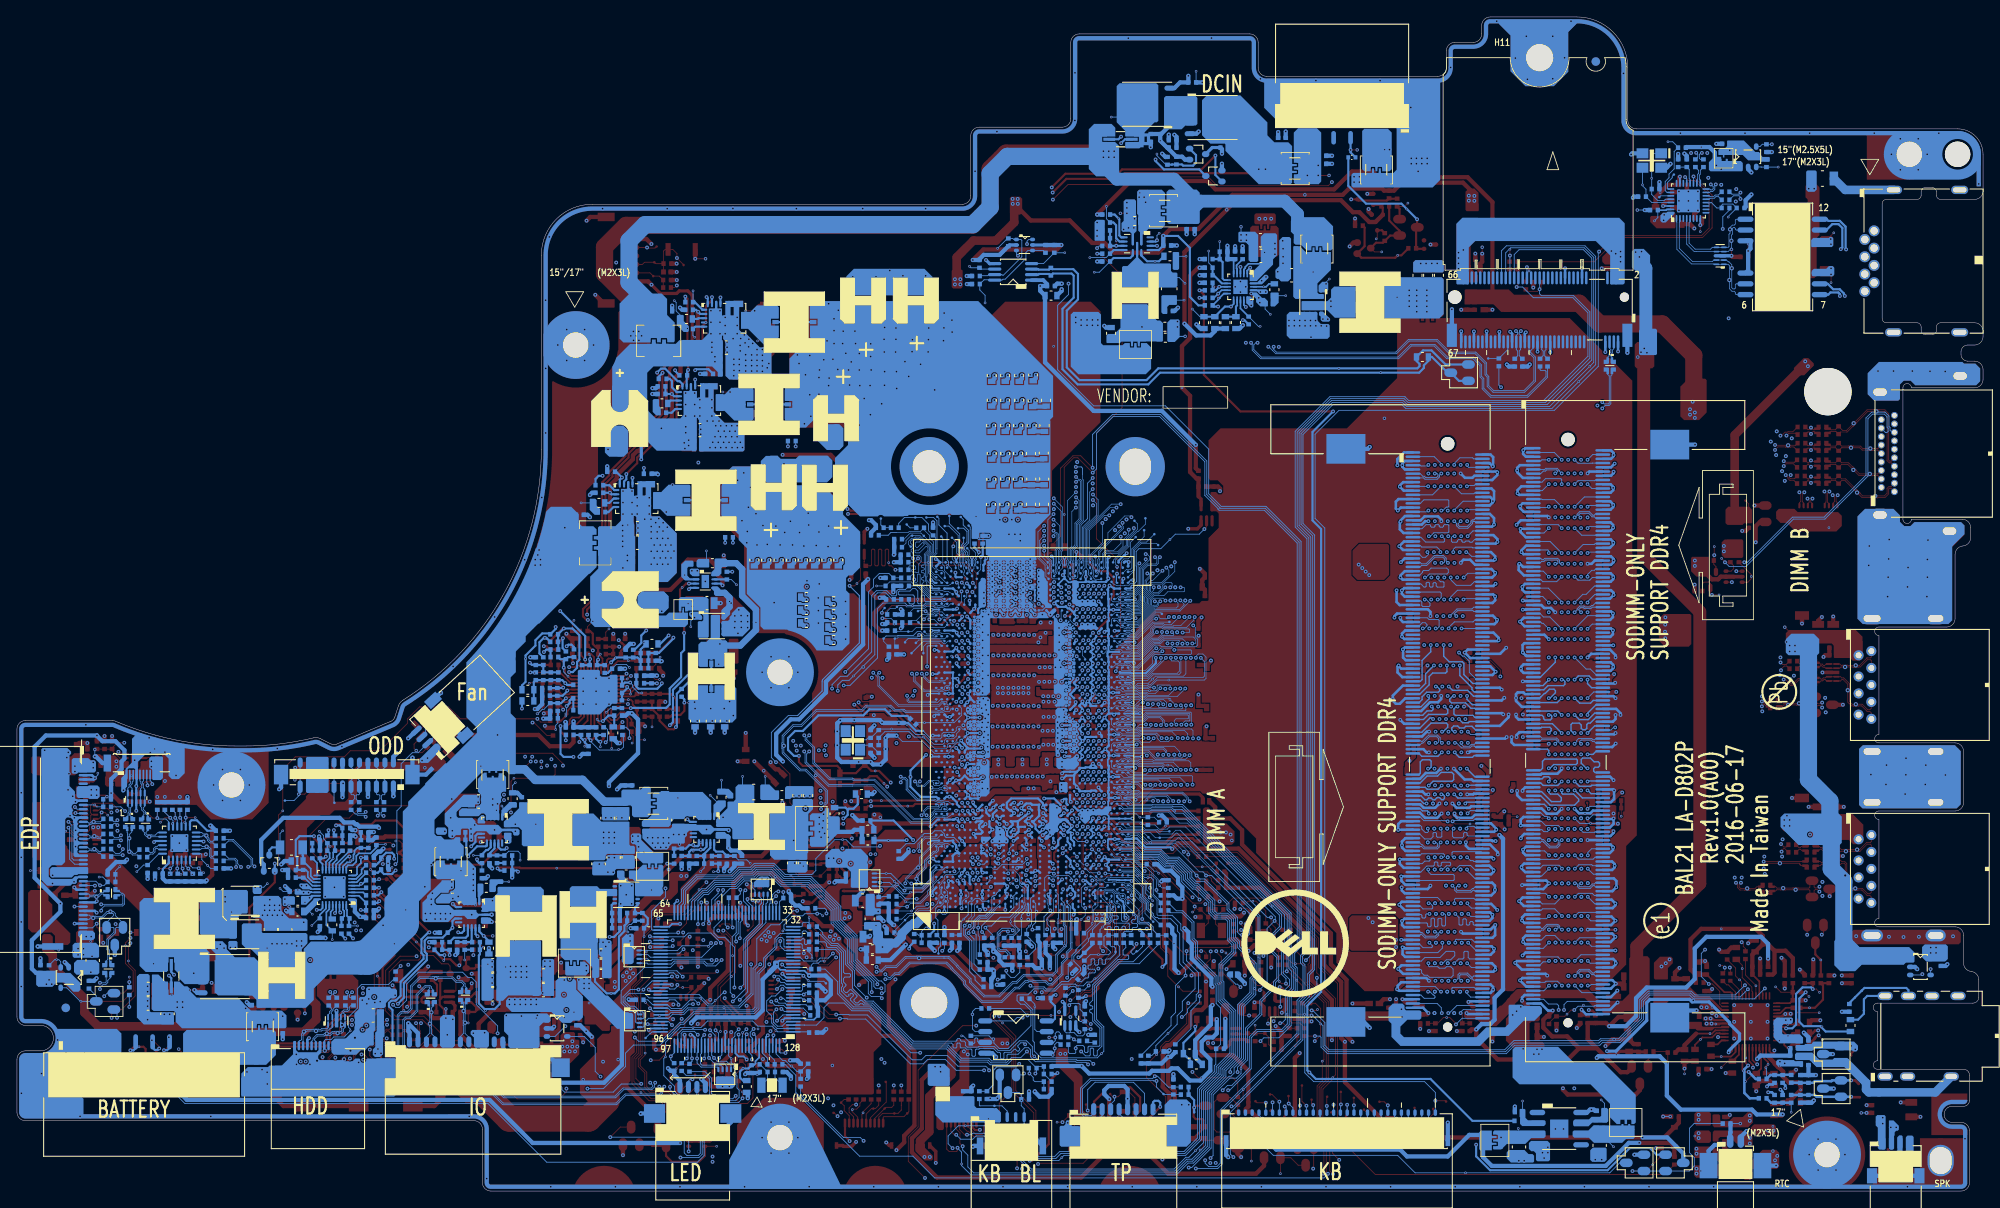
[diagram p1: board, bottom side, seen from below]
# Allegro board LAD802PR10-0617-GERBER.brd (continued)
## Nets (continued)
MCT0: RL15.2 TL1.9
MCT1: RL14.2 TL1.10
MDO0+: JLAN1.1 TL1.7
MDO0-: JLAN1.2 TL1.8
MDO1+: JLAN1.3 TL1.11
MDO1-: JLAN1.6 TL1.12
ME_FWP_EC: RC126.1 RE19.1 UE1.80
ME_SUS_PWR_ACK: RC84.2 UC1.AR13 UE1.42
MEC_XTAL1: CE3.1 RE47.2 YE1.1
MEC_XTAL1_R: RE47.1 UE1.123
MEC_XTAL2: CE4.1 RE45.1 UE1.125 YE1.2
MIC_CAP: CA26.1 UA1.19
MODEL_ID: CE1.1 RE3.2 RE4.2 UE1.109
MPHYP_PWR_EN: TP13.1(TP-1) UC1.AM10
NCT7718_DXN: C22.2 C23.2 Q14.3 U2.3
NCT7718_DXP: C22.1 C23.1 Q14.1 Q14.2 U2.2
NRB_BIT: RC44.2 UC1.AR7
NTC_IA: PR635.2 PU602.15
ONE_DIMM#: RC181.2 RC182.1 UC1.M2
PANEL_BKEN_EC: RP2.8 UE1.117
PBAT_CHG_SMBCLK: PD2.3 PR18.2 PR770.1 RE9.1 UE1.9
PBAT_CHG_SMBDAT: PD2.2 PR20.2 PR769.1 RE8.1 UE1.8
PBAT_PRES#: CE16.1 PC14.1 PC753.2 PD3.2 PR15.2 PR16.1 PR756.1 PR764.1 UE1.97
PCH_BATLOW#: RC89.1 UC1.AU13
PCH_DPWROK: RC87.1 RC97.2 UC1.BB20
PCH_HDMI_CLK: QI2.1 RC1.1 UC1.L13
PCH_HDMI_DATA: QI2.4 RC2.1 UC1.L12
PCH_JTAG_TCK1: RC147.1 TPC3.1(TP-1) UC1.B56
PCH_PCIE_WAKE#: RC99.2 UC1.BB15
PCH_PLTRST#: RC108.1 UC1.AN10 UC4.1 UC4.2
PCH_PLTRST#_EC: CE27.1 JDB1.3 JSSD1.23 RC108.2 RC109.1 RL12.1 RW4.2 UC4.4 UE1.56
PCH_POPIRCOMP: RC120.1 UC1.AU16
PCH_RSMRST#: RE20.1 UC5.1 UE1.88
PCH_RSMRST#_Q: RC94.2 RC97.1 RC148.1 UC1.AY17 UC5.4
PCH_RTCRST#: CC5.1 JCMOS1.1 QC2.1 RC78.1 TPS7.1(TP-1) UC1.AM16
PCH_RTCX1: CC8.1 RC82.2 UC1.AM18 YC2.1
PCH_RTCX2: RC82.1 RC83.2 UC1.AM20
PCH_RTCX2_R: CC9.1 RC83.1 YC2.2
PCH_SMB_ALERT#: RC37.1 UC1.R10
PCH_SMBCLK: JDIMM1.253 JDIMM2.253 QC1.1 RC28.2
PCH_SMBDATA: JDIMM1.254 JDIMM2.254 QC1.4 RC27.2
PCH_SPI_CLK_0_R: RC178.1 UC3.6
PCH_SPI_CLK_R: RC21.2 RC24.2 RC178.2 RE33.1
PCH_SPI_CLK_R1: RC24.1 UC1.AV2
PCH_SPI_CS#0_R1: RC18.2 RE38.2 UC1.AU3 UC3.1
PCH_SPI_D0_0_R: RC179.1 UC3.5
PCH_SPI_D0_R: RC23.2 RC179.2 RE34.1
PCH_SPI_D0_R1: RC23.1 RC40.2 UC1.AV3
PCH_SPI_D1_0_R: RC180.1 UC3.2
PCH_SPI_D1_R: RC22.2 RC180.2 RE35.1
PCH_SPI_D1_R1: RC22.1 UC1.AW3
PCH_SPI_D2_0_R: RC176.2 UC3.3
PCH_SPI_D2_R: RC26.2 RC176.1
PCH_SPI_D2_R1: RC19.2 RC26.1 RC41.2 UC1.AW2
PCH_SPI_D3_0_R: RC177.2 UC3.7
PCH_SPI_D3_R: RC25.2 RC177.1
PCH_SPI_D3_R1: RC20.2 RC25.1 UC1.AU4
PCI_CLK_LPC1: RC15.1 RC16.1 UC1.AY9
PCIE_CRX_LANTX_N6: CL2.1 UC1.G18
PCIE_CRX_LANTX_P6: CL1.1 UC1.F18
PCIE_CRX_SSDTX_N11: JSSD1.8 UC1.E28
PCIE_CRX_SSDTX_N12: JSSD1.14 UC1.E30
PCIE_CRX_SSDTX_P11: JSSD1.9 UC1.E27
PCIE_CRX_SSDTX_P12: JSSD1.15 UC1.F30
PCIE_CRX_WLANTX_N5: JWLAN1.35 UC1.F16
PCIE_CRX_WLANTX_P5: JWLAN1.33 UC1.E16
PCIE_CTX_C_SSDRX_N11: CS18.2 JSSD1.6
PCIE_CTX_C_SSDRX_N12: CS16.2 JSSD1.12
PCIE_CTX_C_SSDRX_P11: CS19.2 JSSD1.5
PCIE_CTX_C_SSDRX_P12: CS17.2 JSSD1.11
PCIE_CTX_LANRX_N6: CL4.1 UC1.D20
PCIE_CTX_LANRX_P6: CL3.1 UC1.C20
PCIE_CTX_SSDRX_N11: CS18.1 UC1.D24
PCIE_CTX_SSDRX_N12: CS16.1 UC1.A25
PCIE_CTX_SSDRX_P11: CS19.1 UC1.C24
PCIE_CTX_SSDRX_P12: CS17.1 UC1.B25
PCIE_CTX_WLANRX_N5: CW1.2 JWLAN1.29
PCIE_CTX_WLANRX_N5_C: CW1.1 UC1.C19
PCIE_CTX_WLANRX_P5: CW2.2 JWLAN1.27
PCIE_CTX_WLANRX_P5_C: CW2.1 UC1.D19
PCIE_PTX_LANRX_N6_C: CL4.2 UL1.14
PCIE_PTX_LANRX_P6_C: CL3.2 UL1.13
PCIE_RCOMPN: RC65.1 UC1.F5
PCIE_RCOMPP: RC65.2 UC1.E5
PCIE_WAKE#: JSSD1.19 RC99.1 RE12.2 UE1.4 UL1.21
PECI_EC: DE1.1 RE23.2 UC1.A54
PECI_MEC1404: RE23.1 UE1.94
PHASE_CHG: PC721.2 PL700.1 PQ704.1 PQ704.2 PQ704.3 PQ708.5 PR766.1 PU703.22
PIRQA#: RC187.2 UC1.BB11
PLT_RST#_LAN: RL12.2 UL1.19
PLT_RST_NGFF#: JWLAN1.44 RW4.1
PM_ZVM#: PR1201.2 UC1.AR56
PME#: TP12.1(TP-1) UC1.AU11
POK: CC10.1 PR13.1 PR107.2 PR113.2 PR301.1 PR501.1 PU100.9 PU102.9 RC102.1 UC5.2
POWER_SW#_MB: EC2901.1 ED2901.1 JPWR1.3 RE43.2 SW1.1 TPS8.1(TP-1) ZT2.1(TP-1)
POWER_SW_IN#: CE33.1 RE41.2 RE43.1 UE1.127
PROG: PR753.2 PU703.9
PROH: PQ720.2 PR777.2 PR781.2 PU703.5
PROJECT_ID1: RC51.2 RC52.1 UC1.AY8
PROJECT_ID2: RC53.2 RC54.1 UC1.BA8
PS_ID: PD5.1 PR3.1 PR4.2 UE1.36
PSID: PJPDC1.3 PL2.2
PSID-1: PQ5.2 PR6.1 PR9.2
PSID-2: PQ5.1 PQ6.2 PR8.2 PR11.1
PSID-3: PQ6.3 PR4.1
PTP_DIS#: D6.1 RE22.1 RE26.1
PTP_DIS#_R: RE22.2 UE1.90
PWM1_GT: PR680.1 PU602.12 PU605.13
PWM2_GT: PR681.1 PU602.13 PU604.13
PWM_IA: PR662.1 PU602.22 PU603.13
PWM_VSA: PU602.30 PU606.3
PWR_LED_R#: Q15.2 Q16.1
RESET_OUT#: CE31.1 RE16.1 UC1.BA20 UE1.73
RING2: RA25.2 RA35.1 UA1.17
RING2_R: CA36.1 DA5.2 JHP1.4 RA35.2 ZT23.1(TP-1)
RTC_DET#: Q1.1 RC46.1 UC1.P1
RTC_PWR: D1.3 Q1.2 R1.1 R2.1
RTCRST_ON: QC2.2 RC164.1 UE1.31
RUNPWROK: RE42.1 UE1.48
SA_SNUB: PC622.1 PR627.2
SA_SW: PL601.4 PQ601.9 PR619.2 PR627.1 PU606.8
SATA3_CRX_HDDTX_N0: CS3.1 UC1.F20
SATA3_CRX_HDDTX_P0: CS4.1 UC1.E20
SATA3_CTX_HDDRX_N0: CS2.1 UC1.B21
SATA3_CTX_HDDRX_P0: CS1.1 UC1.A21
SATA_CRX_ODDTX_N1: CS10.2 UC1.G21
SATA_CRX_ODDTX_P1: CS9.2 UC1.F21
SATA_CTX_ODDRX_N1: CS11.2 UC1.D21
SATA_CTX_ODDRX_P1: CS12.2 UC1.C21
SATA_LED#: Q5.3 RC69.1 UC1.H1
SATA_LED_EN: Q5.2 R23.2 UE1.30
SATA_ODD_DA#: JODD1.23 JODD1.24 TP46.1(TP-1)
SATA_ODD_PRSNT#: JODD1.15 JODD1.16 TP47.1(TP-1)
SATA_RXN0_R: CS3.2 EU3101.4 EU3101.7 JHDD1.5
SATA_RXN2_R: CS10.1 JODD1.9 JODD1.10
SATA_RXP0_R: CS4.2 EU3101.5 EU3101.6 JHDD1.6
SATA_RXP2_R: CS9.1 JODD1.11 JODD1.12
SATA_TXN0_R: CS2.2 EU3101.2 EU3101.8 JHDD1.3
SATA_TXN2_R: CS11.1 JODD1.5 JODD1.6
SATA_TXP0_R: CS1.2 EU3101.1 EU3101.9 JHDD1.2
SATA_TXP2_R: CS12.1 JODD1.3 JODD1.4
SD_RCOMP: RC130.1 UC1.AB7
SERIRQ: RC14.2 UC1.AY11 UE1.55
SIO_EXT_SCI#: RC70.1 UC1.J2 UE1.66
SIO_EXT_SMI#: RC5.2 UC1.L6 UE1.10
SIO_EXT_WAKE#: RC47.1 UC1.AD3 UE1.116
SIO_PWRBTN#: RC93.2 UC1.BA15 UE1.52
SIO_RCIN#: RC13.2 UC1.AW13 UE1.53
SIO_SLP_A#: TPS6.1(TP-1) UC1.AN16
SIO_SLP_LAN#: RC88.1 TP10.1(TP-1) UC1.AW15
SIO_SLP_S0#: TPS2.1(TP-1) UC1.AT11 UC9.2
SIO_SLP_S3#: CE29.1 DZ4.1 PR1204.2 RC103.1 RZ2.1 TPS3.1(TP-1) UC1.AP15 UC9.1 UE1.23 UZ3.3 UZ3.5
SIO_SLP_S4#: DZ5.1 PR201.1 PR803.1 RZ1.1 TPS4.1(TP-1) UC1.BA16 UE1.67
SIO_SLP_S5#: PQ711.2 TPS5.1(TP-1) UC1.AY16
SIO_SLP_SUS#: TP75.1(TP-1) UC1.AN15
SIO_SLP_WLAN#: TP11.1(TP-1) UC1.BB17
SLEEVE: RA26.2 RA38.1 UA1.18
SLEEVE_R: CA37.1 DA5.3 JHP1.3 RA38.2 ZT18.1(TP-1)
SM_RCOMP0: RC10.1 UC1.AR18
SM_RCOMP1: RC11.1 UC1.AT18
SM_RCOMP2: RC12.1 UC1.AU18
SMBCLK: QC1.6 RC29.1 UC1.R7
SMBDATA: QC1.3 RC30.1 UC1.R8
SML0_SMBCLK: RC33.1 UC1.R9
SML0_SMBDATA: RC34.1 UC1.W2
SML1CLK: Q11.3 RC31.1 RE11.1 UC1.W3 UE1.12
SML1DATA: Q11.6 RC32.1 RE10.1 UC1.V3 UE1.11
SNUB_+1VALW: PC308.1 PR307.2
SOC_XDP_TDI: RC141.1 TPC5.1(TP-1) UC1.D59 UC1.D60
SOC_XDP_TDO: RC142.1 TPC1.1(TP-1) UC1.A56 UC1.A61
SOC_XDP_TMS: RC140.1 TPC4.1(TP-1) UC1.C59 UC1.C60
SOC_XDP_TRST#: TPC6.1(TP-1) UC1.B59 UC1.C61
SPKR: DA3.3 RC128.2 UC1.AW5
SRTCRST#: CC4.1 RC77.1 UC1.AN18
SUS_STAT#/LPCPD#: RC35.1 UC1.BA11
SUSCLK: RC74.2 RC75.2 RC110.1 RC189.2 UC1.BA17
SUSCLK_EC: RC75.1 RE45.2
SUSCLK_SSD: JSSD1.22 RC189.1
SUSCLK_WLAN: JWLAN1.42 RC74.1
SW_VCCEOPIO: PC1201.2 PL1201.1 PR1208.1 PU1200.8
SYS_PWROK: UC1.B6 UE1.89
SYS_RESET#: RC86.2 TPS1.1(TP-1) UC1.B5
SYSPWR_PRES: RE29.1 RE32.1 UE1.120
T_CRIT#: R29.2 U2.4
THM_SML1_CLK: C24.1 Q11.4 R49.2 U2.8
THM_SML1_DATA: C25.1 Q11.1 R48.2 U2.7
TON_1.2V: PR208.2 PU200.9
TOUCH_SCREEN_PD#: D5.2 R19.2 RC115.2 RC118.1
TOUCH_SCREEN_PD#_R: RC118.2 UC1.A7
TOUCHPAD_INTR#: DZ3.1 Q9.1 RE14.1 UE1.33
TOUCHPAD_INTR#_D: DZ3.2 RC114.2 UC1.BA5
TP_EN: C16.1 JEDP1.39 R19.1
TP_LOCK#: D6.2 JTP1.3 R41.2 ZT11.1(TP-1)
TP_ON#_GATE: C18.2 Q12.2 Q13.2 R38.2
TP_PW_EN#: R38.1 UE1.49
UG_1.2V: PQ201.1 PU200.17
UGATE_CHG: PR761.1 PU703.23
USB2_ID: RC67.1 UC1.AG3
USB2_VBUSSENSE: RC68.1 UC1.AG4
USB3_CM_P0: RX16.2 RX17.2 UX2.14
USB3_CRX_C_RD_DTX_N3: CX6.2 UX2.11
USB3_CRX_C_RD_DTX_P3: CX7.2 UX2.12
USB3_CRX_DTX_N1: LU3.3 RU5.2 UC1.H8
USB3_CRX_DTX_N1_C: EU2601.1 EU2601.9 JUSB1.5 LU3.4 RU5.1
USB3_CRX_DTX_N2: LU6.3 RU11.2 UC1.J6
USB3_CRX_DTX_N2_C: EU2603.1 EU2603.9 JUSB2.5 LU6.4 RU11.1
USB3_CRX_DTX_N3: CX6.1 UC1.J10
USB3_CRX_DTX_P1: LU3.2 RU6.2 UC1.G8
USB3_CRX_DTX_P1_C: EU2601.2 EU2601.8 JUSB1.6 LU3.1 RU6.1
USB3_CRX_DTX_P2: LU6.2 RU12.2 UC1.H6
USB3_CRX_DTX_P2_C: EU2603.2 EU2603.8 JUSB2.6 LU6.1 RU12.1
USB3_CRX_DTX_P3: CX7.1 UC1.H10
USB3_CRX_L_DTX_N3: DX1.4 DX1.7 J3D1.5 LX2.2 RX9.2
USB3_CRX_L_DTX_P3: DX1.5 DX1.6 J3D1.6 LX2.1 RX8.2
USB3_CRX_RD_DTX_N3: LX2.3 RX9.1 UX2.20
USB3_CRX_RD_DTX_P3: LX2.4 RX8.1 UX2.19
USB3_CTX_C_DRX_N3: CX11.2 LX1.3 RX4.1
USB3_CTX_C_DRX_P3: CX9.2 LX1.4 RX7.1
USB3_CTX_C_RD_DRX_N3: CX8.2 UX2.8
USB3_CTX_C_RD_DRX_P3: CX10.2 UX2.9
USB3_CTX_DRX_N1: CU2.1 UC1.C13
USB3_CTX_DRX_N1_C: EU2601.4 EU2601.7 JUSB1.8 LU2.4 RU3.1
USB3_CTX_DRX_N1_R: CU2.2 LU2.3 RU3.2
USB3_CTX_DRX_N2: CU4.1 UC1.B13
USB3_CTX_DRX_N2_C: EU2603.4 EU2603.7 JUSB2.8 LU5.4 RU9.1
USB3_CTX_DRX_N2_R: CU4.2 LU5.3 RU9.2
USB3_CTX_DRX_N3: CX8.1 UC1.B15
USB3_CTX_DRX_P1: CU1.1 UC1.D13
USB3_CTX_DRX_P1_C: EU2601.5 EU2601.6 JUSB1.9 LU2.1 RU4.1
USB3_CTX_DRX_P1_R: CU1.2 LU2.2 RU4.2
USB3_CTX_DRX_P2: CU3.1 UC1.A13
USB3_CTX_DRX_P2_C: EU2603.5 EU2603.6 JUSB2.9 LU5.1 RU10.1
USB3_CTX_DRX_P2_R: CU3.2 LU5.2 RU10.2
USB3_CTX_DRX_P3: CX10.1 UC1.A15
USB3_CTX_L_DRX_N3: DX1.1 DX1.10 J3D1.2 LX1.2 RX4.2
USB3_CTX_L_DRX_P3: DX1.2 DX1.9 J3D1.3 LX1.1 RX7.2
USB3_CTX_RD_DRX_N3: CX11.1 UX2.23
USB3_CTX_RD_DRX_P3: CX9.1 UX2.22
USB3_DE1_P0: RX28.2 RX29.2 UX2.3
USB3_DE2_P0: RX22.2 RX23.2 UX2.16
USB3_EQ1_P0: RX30.2 RX31.2 UX2.2
USB3_EQ2_P0: RX24.2 RX25.2 UX2.17
USB3_ERD_P0: RX18.2 RX19.2 UX2.5
USB3_OS1_P0: RX26.2 RX27.2 UX2.4
USB3_OS2_P0: RX20.2 RX21.2 UX2.15
USB3_P0_PIN6: RX11.2 RX12.2 UX2.6
USB3_P0_PIN18: RX14.2 RX15.2 UX2.18
USB20_VCCA: JIOB1.13 JIOB1.14 JIOB1.15 JIOB1.16 UU3.1
USB30_VCCA: CU6.1 CU7.1 CU8.1 CU9.1 CU10.1 CU18.1 CU19.1 CU20.1 CU21.1 CU22.1 JUSB1.1 JUSB2.1 UU1.1
USB_CAMERA_EDP: JEDP1.32 L3.4 R18.1
USB_CAMERA_EDP#: JEDP1.31 L3.1 R17.1
USB_EN#: RE17.1 UE1.13 UU1.4 UU3.4
USB_OC#0_1: RPC1.3 UC1.A9 UU1.3
USB_OC#2_3: RPC1.2 UC1.C9 UU3.3
USB_OC#4_5: RPC1.1 UC1.D9
USB_OC#6_7: RPC1.4 UC1.B9
USB_PN1: LU1.2 RU1.2 UC1.AB9
USB_PN1_C: EU2602.3 JUSB1.2 LU1.1 RU1.1
USB_PN2: LU4.2 RU8.1 UC1.AD6
USB_PN2_C: EU2604.3 JUSB2.2 LU4.1 RU8.2
USB_PN3: LU7.3 RU14.1 UC1.AH3
USB_PN3_C: JIOB1.8 LU7.4 RU14.2
USB_PN5: L3.2 R17.2 UC1.AJ1
USB_PN6: LU8.2 RU15.1 UC1.AF6
USB_PN6_C: JIOB1.3 LU8.1 RU15.2
USB_PN7: L4.2 R20.2 UC1.AH1
USB_PN7_TPNL: DA6.2 JEDP1.36 L4.1 R20.1
USB_PN8: LW1.3 RW1.2 UC1.AF8
USB_PN8_R: JWLAN1.5 LW1.4 RW1.1
USB_PP1: LU1.3 RU2.2 UC1.AB10
USB_PP1_C: EU2602.2 JUSB1.3 LU1.4 RU2.1
USB_PP2: LU4.3 RU7.1 UC1.AD7
USB_PP2_C: EU2604.2 JUSB2.3 LU4.4 RU7.2
USB_PP3: LU7.2 RU13.1 UC1.AJ3
USB_PP3_C: JIOB1.7 LU7.1 RU13.2
USB_PP5: L3.3 R18.2 UC1.AJ2
USB_PP6: LU8.3 RU16.1 UC1.AF7
USB_PP6_C: JIOB1.4 LU8.4 RU16.2
USB_PP7: L4.3 R21.2 UC1.AH2
USB_PP7_TPNL: DA6.3 JEDP1.37 L4.4 R21.1
USB_PP8: LW1.2 RW2.2 UC1.AF9
USB_PP8_R: JWLAN1.3 LW1.1 RW2.1
USBCOMP: RC66.1 UC1.AB6
VCI_IN1: RE30.1 UE1.126
VCIN0_PH: C32.1 C33.1 R42.2 R43.2 R44.1 RE37.1
VCREF0: CE23.1 RE46.2 RE48.1 UE1.25
VD_IN1_C: C32.2 C33.2 R44.2 R45.1
VIDALERT_N: PR607.1 RC152.2 RC153.2
VIDSCLK: PR606.1 UC1.A63
VIDSOUT: PR609.1 RC154.2 UC1.D64
VL: PC126.1 PU102.15
VR_ALERT#: PR625.2 PU602.36
VR_CAP: CE24.1 TP44.1(TP-1) UE1.18
VR_SCLK: PR618.2 PU602.37
VR_SDA: PR626.2 PU602.35
VRALERT#: RC92.1 UC1.AM11
VRAM_ID1: RC59.2 RC60.1 UC1.AP8
VRAM_ID2: RC61.2 RC62.1 UC1.AW7
VSA_SEN+: PC640.2 PC650.1 PC652.1 PR649.2 RC159.2 UC1.H20
VSA_SEN-: PC649.1 PC650.2 PU602.26 RC160.1 UC1.H21
VTTREF_1.2V: PC210.1 PU200.4
WHITE_LED_BAT: JLED1.3 Q4.1 ZT16.1(TP-1)
WHITE_LED_PWR: JPWR1.5 Q15.1 ZT1.1(TP-1)
WLAN_RADIO_DIS#: JWLAN1.48 RC3.1 UC1.B7
XCLK_BIASREF: RC76.1 UC1.E42
XDP_HOOK0: RC148.2 TPC32.1(TP-1)
XDP_ITP_PMODE: RC143.2 TPC7.1(TP-1) UC1.E8
XDP_OBS0_R: TP15.1(TP-1) UC1.C55
XDP_OBS1_R: TP16.1(TP-1) UC1.D55
XDP_OBS2_R: TP17.1(TP-1) UC1.B54
XDP_OBS3_R: TP18.1(TP-1) UC1.C56
XDP_PRDY#: TPC31.1(TP-1) UC1.D56
XDP_PREQ#: TPC30.1(TP-1) UC1.D61
XDP_PRSENT_CPU: RC144.1 RC175.2 TPC33.1(TP-1)
XDP_SPI_IO2: RC41.1 RC145.1 TPC9.1(TP-1)
XDP_SPI_SI: RC40.1 RC139.2 TPC8.1(TP-1)
XTAL24_IN: CC6.1 RC80.2 UC1.E37 YC1.3
XTAL24_OUT: RC80.1 RC81.2 UC1.E35
XTAL24_OUT_R: CC7.1 RC81.1 YC1.1
N16875033: CC14.1 DZ4.2 RC103.2 RC192.1 UC6.2
N17003698: TP71.1(TP-1) UE1.96
N17003752: JDIMM1.134 RD23.2
N17004366: JDIMM2.134 RD24.2
N17230024: TP48.1(TP-1) UL1.27
N17230026: TP49.1(TP-1) UL1.25
N17231159: RL2.2 UL1.31
N17237617: PC705.1 PC760.1 PC762.1 PC763.1 PC764.1 PC765.1 PC780.1 PC781.1 PJP701.2 PL704.2 PQ704.5
N17268429: PQ720.1 PR790.1 PR791.2
N17273333: QA1.3 RA5.2 RA6.1
N17274212: RL7.2 UL3.3
N17415515: PJP2.2 PJPDC1.1 PJPDC1.2 PL4.1
N17421985: PC695.2 PR601.2 PR606.2 PR618.1
N17563414: RA9.1 UA1.4
N17751623: C13.1 R56.2
N17772976: PQ740.4 PR778.1
N17902584: JDEG1.1 RE58.2 ZT60.1(TP-1)
N17902623: JDEG1.9 RE56.2 ZT58.1(TP-1)
N17902681: JDEG1.4 ZT55.1(TP-1)
N17902688: JDEG1.7 RE57.2
N17902690: JDEG1.6 RE55.2
N18234461: D8.1 JFAN1.3 R30.1 R55.1
N18336277: Q13.1 R37.1
N18336387: C18.1 Q12.3 R35.2
N18359999: R57.2 U1.3
N18390627: PQ710.2 PQ711.1
N18517471: CZ10.1 UZ3.12
N18517492: CZ11.1 UZ3.10
N18941428: PC640.1 PR646.2
N18941436: PC601.1 PR652.2
N18941447: PC632.1 PR636.1 PU602.28
N18941448: PC632.2 PR641.1
N18941457: PH604.1 PR642.2
N18941471: PR604.2 PR607.2 PR625.1
N18941481: PR605.2 PR609.2 PR626.1
N18941485: PR616.2 PU602.40
N18941487: PR612.2 PU602.39
N18941496: PR678.2 PU602.38
N18941497: PC603.1 PR602.1 PU602.34
N18941498: PC604.1 PR603.1 PU602.33
N18941511: PR608.1 PU602.32
N18941513: PR611.1 PU602.31
N18941562: PC630.1 PR640.1 PU602.20
N18941580: PH605.1 PR657.2
N18941616: PC639.2 PR645.1
N18941625: PC647.2 PR650.2
N18941629: PC629.2 PR639.1
N18941656: PC627.1 PR632.2
N18941661: PH602.1 PR628.2
N18941667: PC627.2 PR638.2 PU602.8
N18941711: PC621.2 PR623.1
N18941712: PR621.2 PR622.2 PR623.2 PU602.5
N18941722: PC616.2 PR617.2 PU602.4
N18941723: PC614.2 PR617.1
N18941731: PR610.2 PU602.3
N18941735: PC613.2 PR613.2 PU602.2
N18941759: PC617.2 PR621.1
N18941760: PC631.1 PR630.2
N18941767: PC630.2 PR644.1
N18941770: PC611.2 PU606.2
N18941771: PC611.1 PR619.1
N18941791: PH601.2 PR610.1 PR631.2
N18941811: PH603.2 PR635.1 PR647.2
N18941826: PQ601.8 PU606.5
N18941830: PQ601.1 PU606.1
N18941848: PR679.1 PU606.7
N18941869: PL601.3 PR624.1
N18944084: PL603.3 PR661.1
N18944130: PC671.2 PU605.5
N18944131: PR672.2 PU605.3
N18944132: PC671.1 PR672.1
N18944141: PC655.2 PU603.5
N18944142: PR660.2 PU603.3
N18944143: PC655.1 PR660.1
N18944153: PR659.1 PU603.1
N18944154: PC663.2 PU604.5
N18944155: PR665.2 PU604.3
N18944156: PC663.1 PR665.1
N18944237: PR664.1 PU604.1
N18944256: PR671.1 PU605.1
N18987516: PC128.1 PD102.2 PR114.2 PR120.2 PR121.2 PR122.1
N19006308: CD30.2 RD11.1
N19034361: CZ3.1 UZ1.6
N19055432: RX6.1 UX2.24
N19055471: RX5.1 UX2.7
N19675639: CX3.1 UX1.6
N19910104: CE18.1 RE27.1
N23700319: PD4.2 PL2.1 PQ6.1 PR6.2
N27266810: PC742.1 PC744.1 PQ709.1 PQ718.4 PR762.1 PR778.2
N27286345: PD704.1 PR743.2
N28424999: TP30.1(TP-1) UC1.AW71
N28425002: TP31.1(TP-1) UC1.AW70
N28483977: PQ1.2 PR2.1 PR12.2 PR13.2
N28483985: PQ1.3 PR5.2
N28484391: PC16.1 PQ2.3 PR28.2
N28484395: PC16.2 PQ2.2 PR29.1
N28484412: PQ2.5 PR31.1 PR33.2
N28484439: PC14.2 PQ3.2 PR32.1
N28484451: PQ1.5 PQ1.6 PR7.1 PR10.2
N28714500: PR769.2 PU703.3
N28714504: PR770.2 PU703.4
N28714507: PC744.2 PQ709.3 PQ718.1 PQ718.2 PQ718.3 PQ740.1 PQ740.2 PQ740.3 PR737.1 PR763.1
N28714524: PC750.1 PU703.27
N28714534: PC752.2 PR754.1
N28714559: PR774.2 PU703.6
N28714562: PR775.2 PU703.7
N28714564: PC721.1 PR771.2
N28714572: PC757.2 PR743.1 PU703.18
N28714582: PR755.2 PU703.12
N28714583: PC708.1 PR776.1 PU703.14
N28714585: PC708.2 PR742.1 PU703.15
N28714598: PC747.1 PR740.2 PU703.31
N28714599: PC747.2 PR772.2 PU703.32
N28714601: PC750.2 PU703.28
N28714604: PR773.1 PU703.25
N28714606: PQ704.4 PR761.2
N28714608: PR745.1 PU703.26
N28714612: PR771.1 PU703.24
N28714614: PR757.2 PU703.17
N28714617: PQ718.5 PR703.1
N28714625: PR757.1 PR779.2
N28714693: PC779.1 PL700.2 PQ717.1 PQ717.2 PQ717.3 PR765.1
N28714721: PR742.2 PR765.2
N28714724: PR765.3 PR776.2
N28714743: PQ709.2 PR737.2 PR738.1
N28714752: PR703.2 PR772.1
N28714753: PR703.3 PR740.1
N28714782: PC767.1 PR766.2
N28714793: PC779.2 PQ717.4 PR773.2
N28842863: CC56.1 UC1.AL1
N28843886: CC69.1 UC1.BB10
N28856399: TP19.1(TP-1) UC1.BA70
N28856402: TP20.1(TP-1) UC1.BA68
N28857231: TP21.1(TP-1) UC1.BB68
N28857234: TP22.1(TP-1) UC1.BB69
N28857237: TP23.1(TP-1) UC1.AK13
N28857240: TP24.1(TP-1) UC1.AK12
N28861827: RC138.1 UC1.C64
N28938912: CC2.2 RC21.1
N29189918: PR764.2 PU703.13
N29708559: TP28.1(TP-1) UC1.AY4
N29708561: TP29.1(TP-1) UC1.BB3
N29708599: TP25.1(TP-1) UC1.AU5
N29708601: TP26.1(TP-1) UC1.AT5
N29708639: TP27.1(TP-1) UC1.BB5
N32842463: RC137.2 UC1.U11 UC1.U12
N33124395: PC204.2 PR210.1 PU200.12
N33124472: PC207.2 PR203.1
N33188643: CA31.1 RA23.2 RA24.1
N36085760: PD6.1 PR11.2
N39282118: PC501.1 PJP501.2 PU500.8 PU500.9 PU500.10
N39282176: PC504.1 PR506.2
N39282188: PR503.1 PR504.2
N39880170: PR1202.2 PU1200.7
N39880453: PC1209.1 PR1208.2
N40598435: PC102.1 PR100.2
N40598492: PC119.1 PU102.16 PU102.17
N40598500: PC114.1 PR111.2
N40598503: PC113.2 PR108.1
N40598539: PC127.2 PR117.1
N40598619: PD102.1 PR116.2
N40605947: PC305.1 PR303.2 PU300.15
N40606056: PR308.1 PR309.2
N40664383: JDIMM1.165 TP41.1(TP-1)
N40665360: JDIMM2.165 TP42.1(TP-1)
N40665398: JDIMM2.162 TP43.1(TP-1)
N41315323: PBATT1.5 PR15.1
N41321201: PC790.1 PQ721.2 PR790.2
N41527020: JDIMM1.162 TP40.1(TP-1)
N124753277: CD59.2 RD22.1
N200649300: PR620.2 PU602.1

Pads without a net: FD1 1; FD2 1; FD3 1; FD4 1; JDIMM1 87 88 91 92 95 97 100 101 104 105; JDIMM2 87 88 91 92 95 97 100 101 104 105; JEDP1 5; JHDD1 9; JHDMI1 13 14; JIOB1 11; JKB1 2 3; JKBBL1 3; JLAN1 4 5 7 8; JPWR1 4; JSSD1 17; JWLAN1 6 8 9 11 12 13 14 15 16 17 19 20 21 22 23 24 26 28 32 34 38 40 47 50 51 52 53 54 56 57 58 59 60 62 63 65; PD3 3; PD4 3; PJPDC1 4; PU100 10 15; PU102 10; PU300 9 10 12; PU500 1 4 7; PU603 4 9; PU604 4 9; PU605 4 9; PU800 1 5; PU1200 13; RP1 4 5; RP2 4 5; UA1 11 12 14 15 23 24 48; UC1 A3 A4 A6 A11 A17 A19 A23 A26 A27 A29 A31 A33 A36 A38 A40 A45 A47 A50 A52 A65 A69 AB1 AB4 AB11 AB12 AB13 AC1 AC2 AC3 AD1 AD2 AD9 AD10 AD11 AD12 AF11 AF12 AF13 AG1 AG2 AH7 AH8 AH9 AH10 AH11 AH12 AK6 AK7 AK9 AK10 AL25 AL27 AM1 AM2 AM3 AM4 AN1 AN2 AN3 AN5 AN8 AN11 AN13 AP1 AP2 AP3 AP4 AP7 AP11 AP13 AP56 AR10 AT15 AU1 AU2 AU7 AU8 AU56 AW1 AW9 AW17 AW20 AW48 AW68 AW69 AY1 AY2 AY5 AY7 AY20 AY21 AY68 B2 B3 B11 B17 B19 B23 B26 B27 B29 B31 B33 B36 B38 B40 B45 B47 B50 B52 B69 B70 BA3 BA4 BA9 BB2 BB4 BB9 C2 C4 C7 C8 C11 C12 C15 C16 C17 C23 C27 C28 C29 C31 C32 C33 C36 C37 C38 C42 C50 C51 C52 C54 C70 C71 D1 D3 D4 D5 D7 D8 D12 D15 D16 D17 D23 D27 D28 D29 D31 D32 D33 D36 D37 D38 D42 D50 D51 D52 D54 D71 E1 E2 E3 E10 E22 E23 E25 E38 E40 E48 E61 F6 F10 F11 F15 F25 F48 F50 F52 F60 F61 F65 G1 G2 G3 G11 G13 G15 G16 G50 G65 H2 H3 H5 H11 H13 H16 J3 J4 J5 J68 J71 K45 K46 L7 M1 M3 M4 N1 N2 N3 N7 N8 N9 N11 N12 P3 U1 U2 U3 U4 U8 U9 V1 V2 W4 W7 W10 W11 W12; UC2 1; UC6 1; UC7 1; UE1 21 24; UE2 1; UL1 3 6 7 9 10 11 22 24; YC1 2 4

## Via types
v1: diameter 0.305, hole 0.152, TOP to BOTTOM, 451 vias
v2: diameter 0.457, hole 0.203, TOP to BOTTOM, 4259 vias
v3: diameter 0.508, hole 0.254, TOP to BOTTOM, 57 vias
v4: diameter 0.406, hole 0.203, TOP to BOTTOM, 113 vias

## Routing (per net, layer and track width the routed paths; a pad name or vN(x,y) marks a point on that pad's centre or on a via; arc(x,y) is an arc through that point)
0.6V_DDR_VTT_ON: length 30.7
  TOP w0.381: UC2.4 92.24,81.63 92.54,81.93
  TOP w0.508: 92.54,81.93 CC90.1 RC9.2 92.76,84.04 93.53,84.82 93.53,93.81 v1(94.48,94.76) 94.48,99.67 93.53,100.63 93.53,107.97 92.58,108.92 v2(92.4,108.92)
  BOTTOM w0.508: PR202.1 v2(92.4,108.92)
1.2V_VTT_PWRGD: length 288.3
  IN1 w0.254: v2(30,102.95) 44.79,102.95 48.24,99.5 81.48,99.5 83.14,101.16 87.75,101.16 90.23,103.64 v2(90.23,104.34)
  IN2 w0.254: v2(126.67,28.59) 126.74,28.52 126.74,25.84 128.61,23.97 128.61,20.59 124.48,16.47 124.48,14.39 118.95,8.86 116.27,8.86 113.66,6.26 111.87,6.26 110.02,4.41 99.97,4.41 99.07,5.32 61.21,5.32 60.36,6.17 47.18,6.17 43.71,9.63 43.71,11.32 43.71,11.58 39.71,15.58 39.71,17.07 38.41,18.37 38.41,26.75 34.18,30.99 26.21,30.99 19.83,37.36 19.83,74.56 19.83,74.65 15.77,78.71 15.77,86.85 20.91,91.99 22.4,91.99 30,99.6 v2(30,102.95)
  BOTTOM w0.203: PU200.10 89.55,105.87 90,105.42 90,105.35 PR209.2
  BOTTOM w0.254: v2(126.67,28.59) 126.58,28.68 126.58,28.9 RC106.1 ; v2(90.23,104.34) 90.74,104.34 PR209.2
2.5V_VIN: length 0.5
  BOTTOM w0.102: 54.82,6.89 v1(54.82,7.38)
3V_FB: length 6.4
  BOTTOM w0.102: PR109.2 173.9,40.09 172.8,40.09 172.55,39.83 v1(172.55,39.03)
  BOTTOM w0.254: PR109.2 174.41,39.6 PC113.1 PR110.1 176.17,39.81 175.57,40.41 PU100.13
3V_SN: length 1.6
  TOP w0.102: PR106.2 v1(164.94,44.6)
3V_VIN:
  vias: v1(175.34,44.91) v2(175.22,45.67) v2(175.79,46.25) v2(175.79,45.55)
5V_FB: length 3.5
  BOTTOM w0.254: PU102.13 178.26,29.41 178.22,29.37 ; 178.22,29.37 PC127.1 PR118.1 ; 178.22,29.37 PR115.2
5V_SN: length 2.9
  TOP w0.102: PC125.1 v1(173.18,29.55)
  TOP w0.508: PC125.1 173.18,31.77 PR112.2
5V_VIN:
  vias: v1(179.53,37.8) v2(178.07,37.99) v2(178.07,37.36) v2(178.07,36.72) v2(178.07,36.09) v2(178.07,35.45) v2(179.85,34.75) v2(180.49,35.13) v2(180.49,34.5)
+0.6V_DDR_VTT: length 143.4
  TOP w1.016: 56.41,21.54 55.71,22.24 55.71,22.31 55.27,22.75 55.27,22.81 54.74,23.33 54.01,23.33 53.93,23.26 46.76,23.26 45.48,21.98
  TOP w1.524: 40.85,27.13 40.85,28.84 33.41,36.28 33.41,68.33 40.03,74.95 40.03,97.43
  IN2 w1.524: 40.98,112.07 42.22,113.31 74.57,113.31 76.13,114.88 82.76,114.88
  BOTTOM w0.305: v2(43.1,22.24) 43.15,22.24 44.02,21.38 JDIMM2.258 ; v2(60.91,20.99) 60.79,20.87 JDIMM1.258
  BOTTOM w1.524: 40.03,109.12 39.77,108.86 39.77,101.24
  vias: v2(39.64,98.89) v2(39.96,99.4) v2(40.28,110.83) v2(40.34,98.95) v2(40.53,110.19) v2(40.98,110.76) v2(83.97,114.7) v2(84.67,114.7) v2(85.36,114.7) v4(40.72,98.38)
+0.6VSP: length 2.9
  BOTTOM w0.203: PU200.2 87.19,108.71 87.03,108.87 87.03,109 86.65,109.38 85.12,109.38 85.11,109.37
  vias: v1(84.74,110.72) v2(83.52,111.78) v2(83.52,111.14) v2(83.52,110.51)
+1.0V_AMPHYPLL: length 10.3
  TOP w0.508: v2(130.32,32.97) 128.42,32.97 125.94,35.45 125.19,35.45 122.33,38.31 122.19,38.31
  vias: v1(120.8,39.58) v2(117.85,41.17)
+1.0V_APLL: length 29
  TOP w0.254: v2(129.26,47.71) v1(129.64,48.09) 130.49,48.94 131.29,48.94 CC82.1 131.81,48.42 CC83.1 132.92,48.42 133.32,48.02 L1.2
  IN1 w0.254: v2(114.36,41.3) 114.25,41.3 113.69,41.86 113.69,42.94 115.27,44.53 117.62,44.53 118.12,45.03 118.12,45.81 119.51,47.19 120.95,47.19 121.13,47.38 122.4,47.38 124.39,49.36 127.95,49.36 128.25,49.05 128.25,48.09 128.63,47.71 v2(129.26,47.71)
  BOTTOM w0.254: v2(114.36,41.3) 114.3,41.3 UC1.V15
+1.0V_APLLEBB: length 20
  IN1 w0.254: v2(115.99,43.28) 116.91,43.28 117.5,42.69 117.69,42.69 120.52,39.85 121.43,39.85 121.92,40.34 124.48,40.34 125.54,41.4 v2(126.19,41.4)
  BOTTOM w0.254: v2(115.99,43.28) 116.36,43.57 UC1.N18 ; v2(126.19,41.4) 128.5,43.71 CC63.1 131.24,43.44 130.83,43.03 RC162.1
+1.0V_CLK2: length 29.2
  TOP w0.254: CC76.1 139.4,43.48 RC170.1 139.4,42.31 138.26,41.17 136.06,41.17 135.68,41.54 135.68,44.13 135.21,44.6 v2(134.45,44.6)
  IN1 w0.254: v2(134.45,44.6) 134.3,44.6 133.48,43.77 129.43,43.77 127.93,42.27 125.07,42.27 124.67,41.86 120.73,41.86 119.07,43.53 v2(119.07,43.97)
  BOTTOM w0.254: v2(119.07,43.97) 118.33,43.97 UC1.K19
+1.0V_CLK4: length 27.7
  IN1 w0.254: v2(134.44,43.96) 134.21,43.96 133.64,43.39 129.59,43.39 128.09,41.88 125.23,41.88 124.83,41.48 122.74,41.48 122.1,40.83 120.11,40.83 119.73,41.21 119.73,42.2 118.05,43.88 v2(116.8,43.88)
  BOTTOM w0.254: v2(116.8,43.88) 116.8,44.47 UC1.N20 ; 133.91,44.98 133.79,45.1 133.23,45.1 132.72,45.61 132.72,46.55 CC84.1 ; 133.91,44.98 133.91,44.37 134.32,43.96 v2(134.44,43.96) ; 133.91,44.98 134.17,45.23 RC173.1
+1.0V_CLK5: length 48.9
  TOP w0.254: v2(128.84,48.19) 130.2,49.56 v1(130.66,49.56) 131.1,49.56 CC77.1 132.95,49.29 RC171.1 134.83,49.84 135.15,50.16 139.21,50.16 139.67,50.61 v2(139.67,51.33)
  IN1 w0.254: v2(117.57,45.23) 117.57,45.79 119.35,47.57 120.79,47.57 120.97,47.76 122.25,47.76 124.34,49.85 128.06,49.85 128.84,49.08 v2(128.84,48.19)
  BOTTOM w0.254: v2(139.67,51.33) 140.25,51.33 140.95,52.04 140.95,53.43 140.11,54.27 139.21,54.27 137.37,56.11 132.06,56.11 131.35,56.83 129.51,56.83 128.73,56.05 126.87,56.05 RC76.2 ; v2(117.57,45.23) 117.57,45.22 117.57,44.63 UC1.L19
+1.0V_MPHYGT: length 3.9
  BOTTOM w1.016: 129.39,29.23 128.27,29.23 127.55,29.95 127.55,30.35 126.58,31.32
  vias: v2(115.22,41.28) v2(115.92,42.03) v2(115.99,42.65) v2(116.02,41.28) v2(116.82,41.29) v2(124.29,32.36) v2(124.87,32.36) v4(122.26,34.75)
+1.0V_PRIM: length 89.5
  TOP w0.508: v2(157.37,19) 157.07,18.7 CE17.1 ; v2(117.68,33.22) 117.65,33.26 CC72.1 116.85,33.27 CC87.1 115.43,33.27 v2(115.33,33.17) ; v2(128.29,24.97) 129.06,24.2 129.06,19.47 126.04,16.45 126.04,7.73 127.25,6.52 127.25,5.74 v2(128.16,4.83)
  IN1 w0.508: v2(157.37,19) 157.37,18.9 159.41,16.87 159.41,12.3 158.36,11.26 157.35,11.26 154.89,8.79 152.8,8.79 150.72,6.71 147.96,6.71 143.83,10.85 140.02,10.85 134,4.83 v2(128.16,4.83)
  BOTTOM w0.203: v2(115.33,33.17) 115.32,33.19 UC1.T1 ; UE1.95 157.2,19.18 v2(157.37,19) ; v2(124.34,41) 124,41.34 UC1.A14 ; UC1.A10 123.49,38.86 v2(123.85,39.22)
  BOTTOM w0.254: UC1.AK20 108.05,44.91 v2(108.4,45.26) ; UC1.AF18 110.54,43.61 v2(110.88,43.95) ; UC1.AB19 112.46,43.97 112.55,43.97 v2(112.55,43.97) 112.65,43.97 UC1.Y18 v2(112.55,43.26) UC1.AB17 ; v2(114.28,45.22) UC1.V20 ; v2(117.68,33.22) 117.71,33.22 117.98,33.49 UC1.L1 ; v2(113.43,45.81) 113.55,45.81 113.8,45.56 UC1.V21 ; UC1.AF19 110.81,44.58 v2(110.86,44.58) ; UC1.AB20 112.49,45.23 v2(112.54,45.23) ; UC1.K17 117.99,42.96 v2(117.66,43.29) ; UC1.P18 115.45,43.61 v2(115.15,43.31) ; UC1.L21 117.2,45.64 v2(116.79,46.05)
  BOTTOM w0.508: v2(132.38,28.52) RC174.2 131.72,28.49 RC149.1 ; RC161.2 132.23,41.38 RC162.2 133.13,42.62 133.37,42.37 135.21,42.37
  vias: v2(133.7,32.32) v2(134.2,32.81) v2(134.27,32.18) v2(136.23,41.74) v2(136.32,44.01) v2(136.3,43.35) v2(136.3,42.69) v2(136.63,42.19) v2(136.76,44.46) v2(136.8,43.67) v2(136.89,42.84) v2(137.05,41.74) v2(137.24,42.37) v2(137.27,44.07) v2(137.27,43.3) v4(137.69,49.04)
+1.0V_SRAM: length 34.9
  TOP w0.508: CC62.1 110.8,45.27 v2(110.88,45.27)
  IN1 w0.254: v2(114.28,44.59) 114.28,44.08 113.3,43.1 113.3,41.65 114.15,40.8 114.96,40.8 115.49,40.26 115.49,39.25 115.65,39.08 115.65,38.36 115.86,38.15 116.51,38.15 118.45,40.09 119.72,40.09 120.61,39.2 121.43,39.2 122.19,39.96 124.64,39.96 125.6,40.92 126.47,40.92 v2(126.96,41.4)
  BOTTOM w0.254: UC1.AF20 110.82,45.24 110.85,45.24 v2(110.88,45.27) ; v2(110.88,45.27) 110.59,45.56 UC1.AF21 ; v2(110.88,45.27) 110.88,45.73 111.46,46.31 114.64,46.31 115.15,45.8 115.15,45.23 114.83,44.91 UC1.T20 114.65,44.91 114.32,44.59 v2(114.28,44.59) 114.6,44.26 UC1.T19 ; v2(126.96,41.4) 127,41.36 v1(129.12,41.36) RC161.1
+1.0V_VCCST: length 94.5
  TOP w0.508: RC104.2 131.78,72.45 v2(131.52,72.18) 131.52,70.96 130.55,70 v2(130.13,70) 129.48,70.64 v2(128.53,70.64) ; 121.66,44.39 122.23,43.82 123.32,43.82 v2(124.11,43.02) 124.45,43.37 130.35,43.37
  IN1 w0.508: v2(166.25,55.4) 163.83,55.4 163.14,54.72 158.58,54.72 155.63,51.77 144.61,51.77 144.6,51.78 142.67,51.78 v2(141.56,50.68) 139.54,48.66 136.95,48.66 134.9,46.6 133.24,46.6 131.05,44.4 v2(130.77,44.4) ; v2(128.53,70.64) 128.53,69.52 v2(127.64,68.64)
  BOTTOM w0.203: UC1.A18 123.32,43.82 v2(124.11,43.02)
  BOTTOM w0.254: UC1.K21 118.56,45.04 118.56,44.92 v2(118.56,44.91) UC1.K20
  BOTTOM w0.508: RC112.1 RC111.1 127.48,68.47 v2(127.64,68.64) ; v2(128.53,70.64) RC138.2 RC154.1 ; v2(131.52,72.18) 132.1,71.6 132.1,64.47 136.48,60.09 136.48,58.8 139.64,55.64 140.63,55.64 142.35,53.93 142.35,51.47 v2(141.56,50.68) ; v2(130.13,70) 129.58,70 RC152.1 ; v2(166.25,55.4) PC602.1 166.24,54.71 PR601.1 PR604.1 PR605.1
  vias: v4(130.07,44.09)
+1.0V_VCCST_C: length 1
  TOP w0.102: 131.4,41.17 v1(130.7,41.86)
+1.0V_VCCSTG: length 94.2
  TOP w0.254: RZ4.1 134.92,43.33 v2(134.44,43.33)
  TOP w0.508: v2(129.84,66.11) 130.06,66.11 130.75,66.81 130.75,68.23 129.24,69.74 121.43,69.74 121.02,69.33 120.53,69.33 119.1,67.9 RC141.2 ; v2(124.25,38.79) 126,37.04 127.24,37.04 v4(128.1,36.18) 130.25,34.03 ; CC42.1 120.97,46.79 v2(121.11,46.65)
  IN1 w0.254: v2(119.74,44.86) 119.74,45.07 120,45.32 120.62,45.32 120.91,45.61 120.91,46.45 v2(121.11,46.65) 121.45,46.99 122.56,46.99 124.42,48.85 v2(126.51,48.85) ; v2(134.44,43.33) 134.11,43.33 133.8,43.01 130.13,43.01 125.92,38.79 v2(124.25,38.79)
  IN1 w0.508: v2(124.67,51.45) 124.67,56.18 123.82,57.03 123.82,59.2 124.45,59.84 126.72,59.84 127.26,60.38 v2(127.26,63.3) 127.26,63.65 129.72,66.11 v2(129.84,66.11) 130.2,66.11 131.2,67.11 131.2,71.19 v2(130.06,72.33)
  IN2 w0.254: v2(126.51,48.85) 126.83,48.53 126.83,48.18 130.09,44.93 131.94,44.93 133,43.86 133.85,43.86 134.39,43.33 v2(134.44,43.33)
  BOTTOM w0.254: v2(119.74,44.86) 119.74,44.72 UC1.G20 ; UC1.A22 123.24,46.29 123.27,46.3 123.46,46.5 125.31,46.5 126.51,47.71 v2(126.51,48.85) 126.51,49.61 v2(124.67,51.45)
  BOTTOM w0.508: RC140.2 v2(129.84,66.11) ; RC113.1 v2(130.06,72.33) ; RC142.2 v2(127.26,63.3)
+1.0V_VCCSTG_C: length 1.8
  TOP w0.102: 132.42,31.32 v1(130.58,31.32)
+1.0V_XDP: length 8.2
  TOP w0.508: v2(129.57,31.22) 129.22,31.22 v1(128.3,30.3) v2(127.07,29.07)
  BOTTOM w0.508: RC149.2 128.89,27.25 v2(127.07,29.07) ; v2(129.57,31.22) 129.32,30.97 RC143.1
+1.0VS_VCCIO: length 25.7
  TOP w0.508: v2(119.72,62.26) 119.77,62.21 RC4.1 ; CC49.1 107.85,58.85 CC50.1
  IN1 w0.508: 109.24,49.74 109.37,49.61 117.35,49.61 117.61,49.88 118.28,49.88 118.57,50.17 118.57,51.89 118.96,52.28 118.96,61.5 v2(119.72,62.26)
  BOTTOM w0.254: UC1.AL42 107.67,56.77 UC1.AM42 107.03,57.41 v2(107.03,57.68) ; v2(106.88,51.28) 107.21,50.95 UC1.AM30
  vias: v2(103.91,32.71) v2(103.91,32.12) v2(104.54,32.7) v2(104.54,32.12) v2(105.52,32.19) v2(108.63,50.65) v2(108.64,50.04) v4(129.81,28.78)
+1.0VS_VCCOPC: length 8.4
  TOP w0.254: CC17.1 115.72,68.2 v2(115.53,68.01)
  TOP w0.457: v2(111.84,68.01) 111.96,67.9 CC24.1
  TOP w0.508: v2(111.84,68.01) 111.45,68.4 CC18.1 111.42,68.65 CC19.1 110.21,68.21 v2(110,68.01)
  BOTTOM w0.254: v2(114.64,68.03) 114.6,68.03 UC1.V62 114.13,68.45 v2(113.69,68.01) ; UC1.AE62 110.47,68.48 v2(110,68.01) ; v2(115.53,68.01) 115.96,68.44 UC1.P62 ; UC1.AB62 112.3,68.47 v2(111.84,68.01)
  BOTTOM w0.508: v2(110,68.01) 110,68.05 UC1.AG62
  vias: v1(109.62,99.65) v2(104.41,102.76) v2(104.41,102.13) v2(105.05,102.76) v2(105.05,102.13) v2(105.68,102.76) v2(105.68,102.13) v2(106.38,102.76) v2(106.38,102.13) v2(107.02,103.08) v2(107.02,102.44)
+1.0VS_VCCOPCP: length 15.7
  IN1 w0.254: v2(99.21,101.94) 96.79,101.94 95.91,102.82 95.91,111.08 96.98,112.16 v2(97.43,112.16)
  BOTTOM w0.102: v1(97.18,112.98) 97.43,112.73 v2(97.43,112.16)
  BOTTOM w0.254: PU1200.12 97.59,112 v2(97.43,112.16)
+1.2V_DDR: length 160.8
  TOP w0.254: v2(106.96,56.74) 106.96,56.78 106.51,57.23 105.13,57.23 CC33.1
  TOP w0.508: CD56.1 46.6,30.82 v2(46.62,30.84) ; CD49.1 54.31,36.16 v2(54.38,36.09) ; CD54.1 46.61,41.36 v2(46.65,41.4)
  IN1 w0.254: v2(104.24,54.02) 103.77,54.02 103.12,54.67 103.12,57.21 103.53,57.61 v2(103.6,57.61)
  BOTTOM w0.152: v2(99.95,46.16) 100.16,46.38 101.01,46.38 101.03,46.38 UC1.BB23 ; UC1.BB41 100.35,56.32
  BOTTOM w0.178: UC1.BB47 100.65,59.97 100.3,59.97 v2(100.23,59.93) ; v2(99.23,51.24) 100.15,51.24 100.27,51.35 101.04,51.35 101.06,51.36 UC1.BB32
  BOTTOM w0.203: UC1.BB51 100.3,62.43 v2(100.14,62.28)
  BOTTOM w0.254: v2(99.43,56.39) 99.5,56.32 100.35,56.32 ; UC1.AM40 107.21,56.49 v2(106.96,56.74) ; v2(103.6,57.61) 103.96,57.25 UC1.AU42 ; v2(107.59,45.91) 107.69,46 UC1.AL23 ; UC1.AU35 103.96,53.74 104.24,54.02 v2(104.24,54.02) ; UC1.AU23 104.03,47.17 v2(104.33,47.62) ; v2(104.28,50.39) 103.96,50.08 UC1.AU28
  BOTTOM w0.305: JDIMM2.112 43.48,59.87 v2(43.39,59.96) ; v2(43.33,52.79) 43.74,52.38 JDIMM2.142 ; v2(51.22,79.47) 51.38,79.62 JDIMM2.33 ; v2(51.4,25.42) 51.61,25.63 JDIMM2.241 ; JDIMM1.178 58.15,40.87 57.23,39.96 v2(57.23,39.71) ; v2(43.58,48.47) 43.99,48.87 JDIMM2.148 ; JDIMM1.118 56.78,57.88 v2(56.47,58.18) ; v2(49.7,49.87) 49.7,49.73 50.21,49.22 ; v2(46.65,73.99) 46.18,73.99 45.8,74.38 JDIMM2.54 ; v2(60.77,51.75) 60.6,51.75 60.47,51.87 JDIMM1.142 ; JDIMM2.153 54.01,47.62 54.31,47.32 v2(54.31,47.2) ; v2(49.7,45.09) 50.27,44.52 51.45,44.52 52.06,45.12 JDIMM2.163 ; JDIMM1.199 65.51,35.63 65.19,35.95 v2(65.19,36.03) ; v2(63.94,49.83) 64.02,49.75 64.06,49.75 64.49,49.32 65.72,49.32 66.42,48.62 JDIMM1.147 ; JDIMM2.124 43.27,56.87 42.76,56.37 v2(42.76,56.16) ; JDIMM2.135 54.69,54.12 55.02,53.79 v2(55.02,53.55) ; JDIMM1.75 65.48,68.62 65.18,68.32 v2(65.18,67.82) ; JDIMM2.117 54.02,58.62 54.21,58.82 54.88,58.82 55.09,58.62 v2(55.09,58.16) 55.09,57.81 54.4,57.13 JDIMM2.123 ; v2(65.35,24.81) 65.67,25.13 JDIMM1.241 ; JDIMM2.75 52.1,69.13 51.76,68.78 50.97,68.78 v2(50.46,68.28) ; v2(55.96,56.22) 55.96,55.9 56.99,54.87 JDIMM1.130 ; JDIMM2.178 44.88,41.4 v2(46.65,41.4) ; JDIMM2.118 43.58,58.38 v2(43.35,58.14) ; JDIMM1.136 56.37,53.38 v2(56.19,53.55) ; v2(61.57,30.58) 61.37,30.38 JDIMM1.220 ; JDIMM2.111 v2(54.28,60.13) ; JDIMM2.220 46.58,30.87 v2(46.62,30.84) ; JDIMM1.163 66.42,44.63 65.82,44.03 64.38,44.03 v2(63.86,44.54) ; v2(65.42,46.8) 65.78,46.8 66.11,47.13 JDIMM1.153 ; JDIMM1.112 57,59.38 v2(56.77,59.15) ; v2(55.08,56.21) 55.08,55.93 54.78,55.62 JDIMM2.129 ; JDIMM2.12 46.43,84.88 v2(46.65,84.66) ; v2(60.85,46.8) 60.13,46.8 60.05,46.87 JDIMM1.154 ; v2(56.25,64.09) 56.96,63.38 JDIMM1.96 ; JDIMM2.199 54.34,36.12 v2(54.38,36.09) ; JDIMM1.54 59.91,73.88 60.5,74.47 61.29,74.47 61.59,74.17 v2(61.59,74.1) ; JDIMM1.159 66.39,45.63 65.98,45.21 64.62,45.21 v2(64.12,45.72) ; JDIMM2.147 52.17,49.12 52.06,49.23 50.21,49.23 ; JDIMM2.136 43.5,53.87 v2(43.35,54.03) ; JDIMM1.117 68.15,58.13 68.79,57.49 69.26,57.49 69.62,57.84 v2(69.62,58.03) 69.62,58.44 68.43,59.62 JDIMM1.111 ; JDIMM2.160 43.89,45.87 43.52,46.24 v2(43.52,47.26) 43.63,47.38 JDIMM2.154 ; JDIMM1.148 60.14,48.38 60.32,48.55 61.14,48.55 v2(62.41,49.83) ; v2(56.6,56.24) 56.74,56.38 JDIMM1.124 ; v2(65.34,54.19) 65.61,54.19 66.17,53.62 JDIMM1.135 ; v2(43.35,62.94) 43.35,63.22 44,63.87 JDIMM2.96 ; JDIMM1.129 68.28,55.13 v2(68.74,55.58) ; v2(63.9,79.02) 63.9,79.2 64.28,79.58 65.87,79.58 66.33,79.13 JDIMM1.33 ; JDIMM1.141 66.01,52.13 65.63,51.75 v2(65.36,51.75) ; JDIMM1.12 60,84.37 60.24,84.13 61.1,84.13 v2(61.61,84.64) ; JDIMM1.160 60.38,45.38 60.55,45.21 62.08,45.21 v2(62.59,45.72) ; JDIMM1.123 66.27,56.62 65.24,57.66 64.29,57.66 63.91,58.04 v2(63.91,58.41) ; JDIMM2.159 54.38,46.12 54.95,46.69 v2(54.95,47.2) ; v2(43.35,56.16) 43.35,55.68 43.65,55.38 JDIMM2.130 ; JDIMM2.141 55.3,52.62 55.61,52.93 v2(55.61,53.55)
  vias: v4(70.61,91.15)
+1.2VP: length 49.8
  IN1 w0.762: 83.79,107.68 78.95,107.68 77.96,108.67 69.11,108.67 67.43,106.99
  IN2 w0.254: v2(89.12,111.51) 89.12,112.34 88.18,113.28 82.35,113.28 81.77,113.86 76.69,113.86 74.87,112.04 71.38,112.04 v2(65.6,106.27)
  BOTTOM w0.203: PU200.5 88.39,109.76 PC213.1
  BOTTOM w0.508: v2(89.12,111.51) PR207.2 89.12,109.93 PC214.2 88.23,109.93 PC213.1
  vias: v1(69.11,105.43) v2(65.6,105.63) v2(65.6,105) v2(65.6,104.36) v2(65.6,103.73) v2(66.8,106.27) v2(66.8,105.63) v2(66.8,105) v2(66.8,104.36) v2(66.8,103.73) v2(67.69,106.25) v2(67.69,105.63) v2(67.69,105) v2(67.69,104.36) v2(84.58,107.83) v2(85.08,107.38)
+1.8V_AVDD: length 7.2
  TOP w0.203: UA1.40 31.57,18.96 31.96,18.57 v1(32.21,18.57) 33.84,18.57
  TOP w0.508: 33.84,18.57 35.21,17.2 CA12.1 35.92,16.7 RA5.1
+1.8V_CPVDD: length 29.7
  TOP w0.203: UA1.36 29.59,16.56 29.79,16.36 v2(30.01,16.36)
  TOP w0.381: v2(44.35,16.5) 43.93,16.08 v1(43.26,16.08) 42.86,16.48 CA13.1 40.71,16.48 CA14.1 39.82,16.42 RA6.2
  BOTTOM w0.381: v2(44.35,16.5) 43.29,16.5 39.67,20.12 39.67,22.23 39.29,22.61 34.61,22.61 34.31,22.31 32.32,22.31 29.9,19.88 29.9,19.74 28.72,18.56 28.72,17.8 30.01,16.51 v2(30.01,16.36)
+1.8V_PRIM: length 186.5
  TOP w0.254: v2(119.01,68.67) 118.9,68.67 118.51,68.28 118.51,66.49 118.98,66.02 118.98,61.38 119.46,60.9 119.91,60.9 120.2,60.61 120.2,60.43 v2(121.05,59.58)
  TOP w0.508: QA1.1 40.48,11.89 40.99,11.38 48.99,11.38 49.55,11.94 v2(49.55,12.12)
  TOP w1.016: 154.45,37.1 154.45,35.44 155.05,34.84 157.09,34.84 160.48,31.45 160.48,28.56 162.23,26.82 163.79,26.82
  IN1 w0.254: v2(110.91,41.98) 110.94,41.98 111.4,42.44 111.4,46.05 111.87,46.53 116.23,46.53 116.37,46.67 117.91,46.67 119.11,47.87 119.11,51.39 119.52,51.8 120.71,51.8 120.72,51.78 121.44,51.78 122.89,53.23 122.89,59.07 122.38,59.58 v2(121.05,59.58)
  IN1 w0.508: v2(49.55,12.12) 49.55,14.71 50.06,15.22 100.06,15.22 v2(100.41,15.58)
  IN1 w1.016: v2(122.5,31.13) 123.36,30.27 124.89,30.27 125.57,30.94 125.7,30.94 129.01,34.25 129.01,36.52 129.75,37.26 129.77,37.26 129.78,37.26 134.01,37.26 134.55,37.8 136.29,37.8 138.48,39.98 140.55,39.98 141.27,39.26 150.12,39.26 151.98,37.41
  IN2 w0.508: v2(100.41,15.58) 100.41,15.76 104.88,20.23 104.88,24.58 103.18,26.28 103.18,28.55 103.6,28.97 107.33,28.97 108.35,29.99 110.38,29.99 112.42,32.02 v2(112.62,32.02)
  BOTTOM w0.203: v2(112.61,32.64) 112.61,33.79 UC1.AA1
  BOTTOM w0.254: UC1.G61 119.45,68.23 v2(119.01,68.67) 118.87,68.82 UC1.H63 ; v2(110.91,41.98) UC1.AF16
  BOTTOM w0.508: RC137.1 122.5,30.21 v2(122.5,31.13)
  vias: v2(152.93,37.17) v2(153.56,37.17) v2(164.74,26.58) v2(164.74,26) v4(111.65,32.97)
+1.8VALWP: length 13.9
  BOTTOM w0.254: PC503.1 PR503.2 159.92,31.63 160.25,31.31 160.25,30.66 160.9,30 160.9,23.79 161.37,23.32 v1(161.82,23.32) 162.35,23.32 163.72,24.7 PC507.1
+1VALWP: length 13.2
  IN2 w0.254: v2(149.18,37.74) 148.67,37.23 147.4,37.23 145.75,38.88 142.77,38.88 v2(140.29,41.36)
  BOTTOM w0.102: v1(149.75,37.67) 149.24,37.67 v2(149.18,37.74)
  BOTTOM w0.254: v2(149.18,37.74) 149.18,38.49 PR308.2 149.92,38.62 PC309.1
+2.5V_MEM:
  vias: v2(52.03,16.73) v2(52.39,16.16) v2(52.61,16.72) v2(52.98,16.15) v2(54.52,21.73) v2(55.02,21.21) v2(55.48,20.77) v2(68.54,20.54) v2(68.6,21.45) v4(54.25,16.78)
+2.5VP: length 2.1
  BOTTOM w0.102: PC804.1 44.6,6.24 v1(43.58,5.23)
+3.3V_ALW_DSW: length 106.2
  TOP w0.254: v2(92.92,19.39) 92.74,19.56 RC163.1 ; v2(108.42,42.59) 108.64,42.59 109.05,42.18 109.05,41.02 109.3,40.76 109.3,40.15 109.56,39.9 109.56,39.13 109.13,38.71 109.13,33.97 109.37,33.74 109.37,33.04 109.88,32.53 110,32.53 110.38,32.15 v2(110.38,30.88) ; v2(99.84,29.16) 99.84,28.98 104.35,24.47 104.35,23.89 105.24,23.01 v2(105.81,23.01)
  TOP w0.508: v2(76.8,17.8) 76.8,22.52 79.1,24.82 79.18,24.9 79.18,26.56 79.03,26.72 79.03,29.56 85.25,35.78 v1(87.78,35.78) RC93.1 RC89.2 89.29,37.48 RC90.2
  IN1 w0.254: v2(110.38,30.88) 109.56,30.05 100.33,30.05 99.84,29.56 v2(99.84,29.16) ; v2(76.8,17.8) 78.01,19 81.39,19 82.9,20.52 84.42,20.52 85.74,19.2 91.34,19.2 91.52,19.39 v2(92.92,19.39) 93.85,18.46 93.85,18.41 94.14,18.12 100.83,18.12 105.72,23.01 v2(105.81,23.01)
  IN2 w0.254: v2(110.89,43.28) 109.11,43.28 v2(108.42,42.59)
  BOTTOM w0.254: UC1.AD18 111.3,43.62 v2(110.89,43.28) 111.32,42.96 UC1.AD17 ; UC1.AJ17 108.82,42.9 108.51,42.59 v2(108.42,42.59) ; CC80.1 93.49,15.39 CC81.1 94.32,17.48 92.92,18.88 v2(92.92,19.39) ; v2(105.81,23.01) 105.91,22.91 106.02,22.91 106.13,22.8 RC85.1
+3.3V_HDA: length 19.7
  TOP w0.254: CC61.1 109.02,43.97 v2(108.41,44.57) 107.83,44.57 107.68,44.42 107.26,44.42 106.79,44.88 106.79,45.12 106.54,45.38 104.7,45.38 104.58,45.26 104.16,45.26
  TOP w0.381: L2.2 92.02,46.41 92.44,46.83 97.99,46.83 v1(98.64,46.18) 99.21,45.61 102.24,45.61 102.59,45.26 104.16,45.26
  BOTTOM w0.254: UC1.AJ19 108.72,44.26 108.41,44.57 v2(108.41,44.57)
+3.3V_OUT:
  vias: v1(164.42,22.18)
+3.3V_SPI: length 57.8
  TOP w0.254: RC17.1 88.61,26.8 v2(89.24,26.18) ; v2(96.79,26.43) 96.79,27.31 98.38,28.89 98.38,29.74 v2(99.46,30.82)
  IN1 w0.254: v2(89.24,26.18) 91.52,26.18 91.9,26.55 96.68,26.55 v2(96.79,26.43) 97,26.64 103.25,26.64 103.65,26.24 v2(104.35,26.24)
  IN2 w0.254: v2(99.46,30.82) 99.46,30.93 100.5,31.96 100.5,32.44 104.24,36.18 105.26,36.18 105.41,36.34 105.43,36.34 105.68,36.59 105.68,37.72 106.03,38.07 106.12,38.07 106.37,38.32 106.37,39.58 106.68,39.88 106.69,39.88 107.21,40.4 107.21,40.6 107.47,40.87 107.85,40.87 107.94,40.79 108.1,40.79 108.4,41.09 v2(108.4,41.97) ; v2(109.38,23.13) 108.95,23.55 108.95,25.01 106.7,27.26 v2(106.7,27.58) 106.45,27.58 106.07,27.2 105.82,27.2 104.87,26.24 v2(104.35,26.24)
  BOTTOM w0.254: v2(99.46,30.82) 99.14,30.5 RC139.1 ; RC20.1 96.35,26.88 v2(96.79,26.43) ; v2(109.38,23.13) 109.61,23.13 CC3.1 109.98,22.34 109.47,21.84 109.47,21.33 109.47,21.33 109.47,20.33 109.72,20.07 UC3.8 ; RC18.1 105.05,29.05 RC19.1 106.52,27.58 v2(106.7,27.58) ; v2(108.4,41.97) 108.48,41.97 UC1.AJ16
+3.3V_WLAN: length 0.8
  TOP w0.102: 61.23,107.71 v4(62.01,107.71)
  vias: v2(42.76,110.83) v2(42.76,110.21) v2(42.75,109.62) v2(43.33,110.57) v2(61.87,110.7) v2(61.87,110.06) v2(61.87,109.43) v2(61.87,108.79) v4(43.84,110.89) v4(61.3,111.02)
+3V_DVDD: length 38
  TOP w0.203: CA17.1 26.39,24.73 UA1.9 ; CA16.1 30.51,23.46 29.79,23.46 29.59,23.25 UA1.1
  TOP w0.508: CA15.1 33.88,25.41 RA8.1 ; CA15.1 33.99,25.61 34.5,26.12 34.5,29.67 33.25,30.93 v1(30.88,30.93) 26.8,30.93 25.99,30.12 25.99,29.1 ; CA15.1 33.6,25.54 CA16.1 ; 24.59,28.34 24.59,25.75 24.8,25.54 RA2.1 ; 24.59,28.34 23.29,28.34 22.43,27.49 RA3.2 ; 24.59,28.34 25.35,29.1 25.99,29.1 ; 25.99,29.1 CA5.1 27.21,27.88 CA6.1 CA17.1
+3VALW: length 706.1
  TOP w0.381: UC6.5 91.27,19.17 CC12.1 ; v2(157.06,106.91) 156.03,105.89 154.08,105.89 153.78,106.19 152.78,106.19 152.25,105.67 TPS9.1 152.25,99.7 154.93,97.03 154.93,96.08 155.32,95.7 155.32,91.42 v2(158.2,88.54) ; UC7.5 133.26,74.31 133.31,74.26 133.31,73.94 CC13.1 ; CC11.1 82.59,22.54 82.76,22.37 83.3,22.37 83.51,22.58 UC5.5
  TOP w0.432: Q2.5 152.3,5.93 152.3,5.93 151.46,5.93 151.46,5.93 Q2.2 150.22,5.93 149.38,6.76 v2(149.38,7.6)
  TOP w0.508: v2(141.59,86.85) 135.93,86.85 134.83,85.74 v4(134.83,84.54) 134.83,78.06 134.01,77.23 134.01,74.12 133.64,73.75 CC13.1 ; 144.18,19.74 143.91,19.47 143.91,18.7 144.61,18 144.61,17.63 145.19,17.05 145.34,17.05 RE40.2 145.31,16.46 144.81,16.46 v2(143.92,15.57) 143.92,15.45 143.21,14.75 139.83,14.75 ; v2(147.87,12.34) v2(148.67,12.34) 149.94,12.34 150.45,12.85 150.45,13.34 150.77,13.66 RE21.2 ; v2(85.64,8.5) 85.64,8.7 86.3,9.37 R35.1 86.95,9.67 86.66,9.97 86.66,10.47 86.66,10.47 86.66,14.2 88.48,16.02 92.16,16.02 92.67,16.53 92.67,18.64 92.16,19.15 CC12.1 91.34,19.2 RC163.2 90.4,20.25 v2(90.38,20.27) ; v2(144.04,36.85) 144.29,36.6 RE25.1 ; v2(157.22,28.78) 155.97,28.78 RE15.2 ; CC11.1 82.28,22.44 82.28,21.46 v2(82.71,21.03) ; v2(110.01,24.97) 110.7,24.97 111.78,26.04 111.78,28.16 CC85.1 109.76,30.68 v2(109.49,30.94) 109.76,31.21 RC92.2 ; v2(191.99,42.56) 191.81,42.56 190.94,41.69 188.6,41.69 188.46,41.83 186.4,41.83 PR791.1 ; RC88.2 D2.2 36.87,5.69 v2(40.56,5.69) ; JPWR1.1 157.45,107.31 v2(157.06,106.91) ; RE58.1 126.7,16.21 128.8,18.31 130.39,18.31 ; RA11.2 20.02,25.5 v2(20.02,27.32) ; PR16.2 v2(218.3,15.99) ; PR28.1 179.59,18.42 175.09,13.92 172.29,13.92 172.29,13.9 170.83,12.44 Q16.2 169.03,12.44 R53.1 168.99,13.73 171.04,15.78 v2(171.96,15.78) ; 60.43,118.05 61.34,118.95 68.54,118.95 69.48,118.01 PR3.2 70.64,118.01 70.9,118.27 74.77,118.27 75.52,117.52 v4(79.99,117.52) 88.54,117.52 92.58,113.48 95.88,113.48 v2(96.69,112.67) 96.69,111.31 97.3,110.7 102.47,110.7 103.61,111.84 105.07,111.84 107.73,114.5 112.31,114.5 113.44,115.63
  TOP w1.016: 114.27,115.58 114.27,114.27 116.42,112.12 119.08,112.12 121.06,110.15 121.06,108.48 121.06,108.48
  IN1 w0.508: v2(143.92,15.57) 143.92,15.39 144.42,14.88 145.22,14.88 145.68,14.42 146.27,14.42 146.65,14.05 146.65,12.94 147.25,12.34 v2(147.87,12.34) ; v2(191.99,42.56) 192.31,42.88 192.31,47.01 190.96,48.35 189.31,48.35 185.92,51.75 183.56,51.75 181.16,54.15 181.16,55.33 179.5,56.99 177.26,56.99 176.14,58.11 176.14,64.59 174.95,65.78 174.95,66.4 168.47,72.89 168.47,88.93 162.76,94.64 162.76,104.44 161.22,105.98 v2(161.22,109.53) ; v2(148.67,12.34) 149.56,12.34 150.3,11.6 150.3,10.83 149.38,9.91 v2(149.38,7.6) ; v2(109.49,30.94) 110.07,31.51 112.27,31.51 112.39,31.39 115.42,31.39 116.92,29.88 118.28,29.88 120.43,27.73 126.66,27.73 128.91,29.97 129.19,29.97 130.74,31.52 131.21,31.52 131.57,31.88 131.57,32.57 133.45,34.45 136.42,34.45 138.73,36.75 143.31,36.75 v2(143.4,36.85) ; v2(40.56,5.69) 43.38,8.51 43.38,19.76 43.38,20.37 38.34,25.42 38.25,25.42 37.99,25.67 31.83,25.67 31.71,25.55 28.91,25.55 27.64,26.82 20.52,26.82 v2(20.02,27.32) ; v2(90.38,20.27) 89.81,19.71 85.95,19.71 84.62,21.04 82.71,21.04 v2(82.71,21.03) ; v2(171.96,15.78) 173.16,16.98 185.28,16.98 187.11,18.82 188.65,18.82 189.19,18.28 193.65,18.28 194.2,17.72 194.2,17.71 194.94,16.97 205.15,16.97 206.17,17.99 215.59,17.99 217.59,15.99 v2(218.3,15.99)
  IN1 w1.016: 113.9,118.1 113.1,118.1 103.69,127.51 103.69,131.2 102.43,132.45 91.08,132.45 84.56,125.94 74.44,125.94 66.25,117.75 61.49,117.75 ; 29.29,121.62 29.29,120.8 29.97,120.12 29.97,118.22 32.02,116.16 32.02,113.62 33.04,112.6 40.72,112.6 45.87,117.75 59.15,117.75
  IN2 w0.508: v2(106.32,14.75) 107.14,15.58 109.5,15.58 110.15,16.23 110.15,24.82 v2(110.01,24.97) ; v2(158.26,86.31) 157.88,85.93 v2(151.53,85.93) ; v2(161.22,109.53) 158.6,106.91 v2(157.06,106.91)
  BOTTOM w0.254: PC1205.1 97.23,111 PU1200.10 ; v2(96.69,112.67) 94.95,112.67 93.56,111.27 93.56,105.48 92.55,104.48 PR209.1
  BOTTOM w0.381: v2(158.26,86.31) 158.26,88.48 v2(158.2,88.54)
  BOTTOM w0.508: v2(148.5,37.74) 148.5,38.04 148.16,38.37 PR303.1 ; v2(136.46,19.11) 136.87,18.69 RE18.2 ; PR756.2 192.37,42.59 192.02,42.59 v2(191.99,42.56) ; PC1205.1 96.69,111.55 v2(96.69,112.67) ; 58.97,5.25 58.97,4 57.94,2.96 44.5,2.96 41.78,5.69 v2(40.56,5.69) ; 160.55,19.51 160.55,14.88 162.64,12.78 169.95,12.78 171.96,14.8 v2(171.96,15.78) ; v2(136.55,23.55) 136.55,23.58 136.88,23.91 136.89,23.91 137.26,24.28 RE17.2 ; v2(90.38,20.27) 90.38,18.6 90.87,18.12 91.65,18.12 92.16,17.61 92.16,16.53 91.14,15.51 91.14,14.2 92.31,13.04 93.56,13.04 94.99,14.47 95.71,14.47 96.01,14.18 98.02,14.18 98.34,13.86 105.43,13.86 v2(106.32,14.75) 109.8,14.75 R43.1 ; v2(85.64,8.5) 85.64,7.16 83.37,4.89 68.76,4.89 67.95,4.08 63.14,4.08 60.6,6.62 59.2,6.62 ; PR304.1 v2(153.5,38)
  vias: v2(29.17,122.57) v2(29.88,122.77) v2(60,117.39) v2(60,116.81) v2(60.65,117.42) v2(60.65,116.83) v2(113.86,117.04) v2(113.85,116.45) v2(114.45,116.45) v2(114.46,117.04) v2(120.63,107.56) v2(120.63,106.95) v2(121.27,107.56) v2(121.27,106.95) v2(134.95,29.76) v2(135.38,30.19) v2(135.57,29.64) v2(136.02,30.01) v2(142.64,30.43) v2(143.09,29.99) v2(143.26,30.55) v2(143.47,29.49) v2(143.66,30.12) v2(144.07,29.67) v2(157.94,39.97) v2(158.64,41.87) v2(158.64,41.24) v2(158.58,40.6) v2(158.58,39.97) v2(159.28,41.87) v2(159.28,41.24) v2(159.58,30.08) v2(159.58,29.5) v2(164.42,25.07) v2(164.42,24.48) v2(164.42,23.9) v2(165,25.07) v2(165,24.48) v2(165,23.9) v2(165.63,24.91) v4(135.72,14.81)
+3VALW_EC: length 118.3
  TOP w0.508: CE5.1 156.23,23.32 155.52,24.04 155.52,24.28 CE10.1 155.35,24.32 154.75,24.32 154.75,24.32 154.65,24.32 v2(154.65,24.32) ; 146.67,32.69 146.29,32.31 CE7.2 146.02,31.67 v2(145.67,31.32) ; 146.67,32.69 147.4,33.42 147.4,36.34 146.26,37.48 142.82,37.48 v1(142.43,37.09) 140.86,35.53 v2(140.86,35.38) ; 146.67,32.69 146.97,32.4 CE15.1 CE8.2 150.28,31.81 v2(150.28,31.58) 150.28,30.9 149.27,29.89 148.54,29.89 148.14,29.49 148.14,28.99 148.05,28.91 148.05,26.01 150.14,23.92 v2(150.14,22.56) 150.32,22.37 150.46,22.37 150.97,21.87 RE3.1 151.27,21.49 151.66,21.1 151.66,20.56 152.36,19.86 v2(152.36,19.8) ; v2(142.26,26.75) 142.26,27.14 142.07,27.33 141.38,27.33 140.87,26.83 CE6.1 140.86,26.83 CE20.1 138.98,26.83 138.48,26.33 138.48,25.45 v2(138.45,25.42) ; v2(152.46,18.43) 152.03,18 CE11.1 ; RE2.1 141.63,19.71 v2(141.63,20.08) 141.31,20.39 CE12.1 ; CE9.1 v2(153.69,31.51)
  IN1 w0.508: v2(152.36,19.8) 152.46,19.7 v2(152.46,18.43) 152.46,17.79 153.56,16.68 153.56,15.21 152.66,14.31 148.61,14.31 147.39,15.52 v2(145.83,15.52) ; v2(150.28,31.58) 150.28,31.67 150.71,32.1 151.84,32.1 152.42,31.51 v2(153.69,31.51) ; v2(154.65,24.32) 154.65,24.1 154.26,23.71 151.29,23.71 v2(150.14,22.56)
  BOTTOM w0.203: v2(152.46,18.43) 152.27,18.43 151.96,18.12 UE1.103 ; v2(145.83,15.52) 146.18,15.88 146.79,15.88 147.16,16.25 UE1.115 ; UE1.54 150.36,31.94 150.28,31.86 v2(150.28,31.58) ; v2(138.45,25.42) 138.45,25.43 139,25.98 UE1.19 141.19,25.98 141.31,26.1 141.86,26.1 142.26,26.5 v2(142.26,26.75) 142.26,26.88 141.96,27.18 UE1.22 ; v2(145.67,31.32) 145.96,31.61 UE1.43 ; v2(154.65,24.32) 154.72,24.38 UE1.82 ; UE1.65 154.95,31.18 154.62,31.51 v2(153.69,31.51) ; RE8.2 137.42,20.7 137.9,20.22 138.9,20.22 139.06,20.38 UE1.5 141.33,20.38 v2(141.63,20.08)
  BOTTOM w0.508: v2(138.45,25.42) 138.42,25.42 138.42,25.43 138.42,25.42 136.54,25.42 135.91,24.8 135.91,23.19 136.6,22.5 RE10.2 ; v2(140.86,35.38) 140.86,35.26 140.59,34.99 RE14.2 140.59,34.19 140.09,33.68 139.63,33.68 139.3,33.36 RE12.1 ; v2(152.36,19.8) 152.36,19.81 152.36,19.86 151.73,20.49 144.77,20.49 143.95,21.32 143.95,24.95 142.88,26.01 ; RE10.2 137.55,21.74 RE9.2 RE8.2 ; RE10.2 RE11.2
+3VALW_PCH: length 386.3
  TOP w0.508: RC5.1 117.03,35.88 v2(117.02,35.88) ; v2(112.54,42.62) 112.99,42.62 113.11,42.5 CC78.1 113.62,42.62 v2(114.32,42.62) ; RC17.2 87.08,27.71 RC45.2 ; RC17.2 v2(87.08,25.42) ; RC17.2 86.32,26.8 RC129.1 ; RC39.2 v2(110.07,26.24) ; CC66.1 113.43,40.51 113.04,40.89 v2(112.81,40.89) 112.59,40.89 112.15,41.33 CC64.1 ; RX2.1 v2(221.57,53.67) ; RX13.1 v2(216.24,45.93) ; v2(96.92,36.53) 96.6,36.21 96.6,28.89 95.73,28.02 95.73,26.24 95.22,25.74 v2(94.89,25.74) 94.61,25.74 92.71,27.63 RC84.1 ; L2.1 90.57,45.28 CC65.1 88.79,43.96 87.4,42.56 87.4,40.88 76.92,30.4 76.92,26.76 75.08,24.92 75.08,18.32 74.63,17.87 74.63,17.86 v2(74.38,17.61)
  TOP w1.016: 117.5,17.42 120.67,17.42 121.69,16.4 121.69,13.73 124.29,11.13 124.29,7 125.37,5.92 125.37,4.91 ; 161.05,26.18 158.69,28.54 158.69,30.15 157.67,31.18 157.67,32.41 156.81,33.27 153.65,33.27 153.12,33.8 153.12,35.57 150.09,38.6 142.98,38.6 142.01,39.58 137.18,39.58 137.12,39.52
  IN1 w0.508: v2(221.57,53.67) 221.57,48.63 219.51,46.58 216.88,46.58 v2(216.24,45.93) ; v2(113.62,28.26) 113.56,28.2 113.56,27.9 113.3,27.65 113.3,27.45 112.8,26.94 110.76,26.94 v2(110.07,26.24) 108.04,26.24 v2(107.43,25.64) 106.23,25.64 106.09,25.77 104.91,25.77 104.74,25.61 103.43,25.61 102.9,26.14 97.84,26.14 97.44,25.74 v2(94.89,25.74) 94.58,26.04 92.11,26.04 91.48,25.42 v2(87.08,25.42) 85,25.42 84.06,24.47 84.06,23.97 83.07,22.98 82.37,22.98 81.95,22.56 79.13,22.56 79.12,22.55 78.67,22.55 77.94,21.82 77.94,20.74 75.45,18.24 75,18.24 74.38,17.62 v2(74.38,17.61)
  IN1 w1.016: 126,3.96 126.4,3.56 134.52,3.56 140.54,9.58 143.3,9.58 147.44,5.44 152.17,5.44 152.39,5.67 ; 154.44,6.18 154.64,6.18 157.47,9 157.47,9.48 157.97,9.99 158.88,9.99 160.74,11.84 160.74,17.86 161.96,19.08 161.96,22.97
  IN2 w0.254: v2(112.54,42.62) 112.67,42.62 113.05,43.01 113.05,44.15 v2(113.43,44.53)
  IN2 w0.508: v2(224.95,13.92) 224.95,18.76 230.38,24.19 230.38,50.27 229.95,50.69 225.32,50.69 224.05,51.96 222.71,51.96 221.57,53.11 v2(221.57,53.67) ; v2(116.73,28.26) 116.94,28.47 116.94,31.75 117.41,32.21 118.57,32.21 119.29,32.92 119.29,33.64 118.87,34.05 117.85,34.05 117.34,34.56 117.34,34.89 117.02,35.21 v2(117.02,35.88)
  BOTTOM w0.254: v2(107.66,40.41) 107.66,40.89 107.98,41.21 UC1.AK15 ; v2(113.43,44.53) 113.7,44.26 UC1.V19 ; v2(112.54,42.62) 112.97,42.31 UC1.Y16 ; v2(108.42,43.24) 108.14,42.96 UC1.AK17 ; v2(111.02,41.29) 111.02,41.35 UC1.AD15 ; v2(109.59,41.12) 109.66,41.18 UC1.AG15 ; UC1.AJ21 109.56,46.31 110.63,46.31 110.63,46.3 v2(110.75,46.3) ; v2(112.81,40.89) 112.83,40.92 112.83,41.49 UC1.Y15 ; UC1.T16 114.68,42.37 114.43,42.62 v2(114.32,42.62)
  BOTTOM w0.508: RC128.1 107.43,25.69 v2(107.43,25.64) ; v2(153.69,5.67) 171.07,5.67 176.15,10.75 211.86,10.75 215.03,13.92 v2(224.95,13.92) ; RC47.2 110.57,28.09 110.07,27.58 v2(110.07,26.24) ; RC35.2 96.78,36.67 v2(96.92,36.53) ; RC37.2 113.62,27.58 v2(113.62,28.26) 113.71,28.35 RC33.2 RC34.2 115.46,28.95 RC38.2 ; RC44.1 95.97,31.39 95.64,31.06 95.64,30.41 95.36,30.13 95.36,26.21 v2(94.89,25.74) ; RC46.2 117.42,28.14 117.81,28.53 RC32.2 116.87,28.95 RC31.2 116.73,28.83 v2(116.73,28.26) 116.53,28.26 116.02,27.75 116.02,27.18 115.5,26.66 RC30.2 RC29.2 114.51,26.01 v2(114.49,25.99)
  vias: v2(115.08,17.42) v2(115.67,17.42) v2(124.23,4.02) v2(124.86,4.02) v2(135.57,39.26) v2(136.15,39.26) v2(161.39,24.68) v2(161.39,24.05) v4(116.73,17.93)
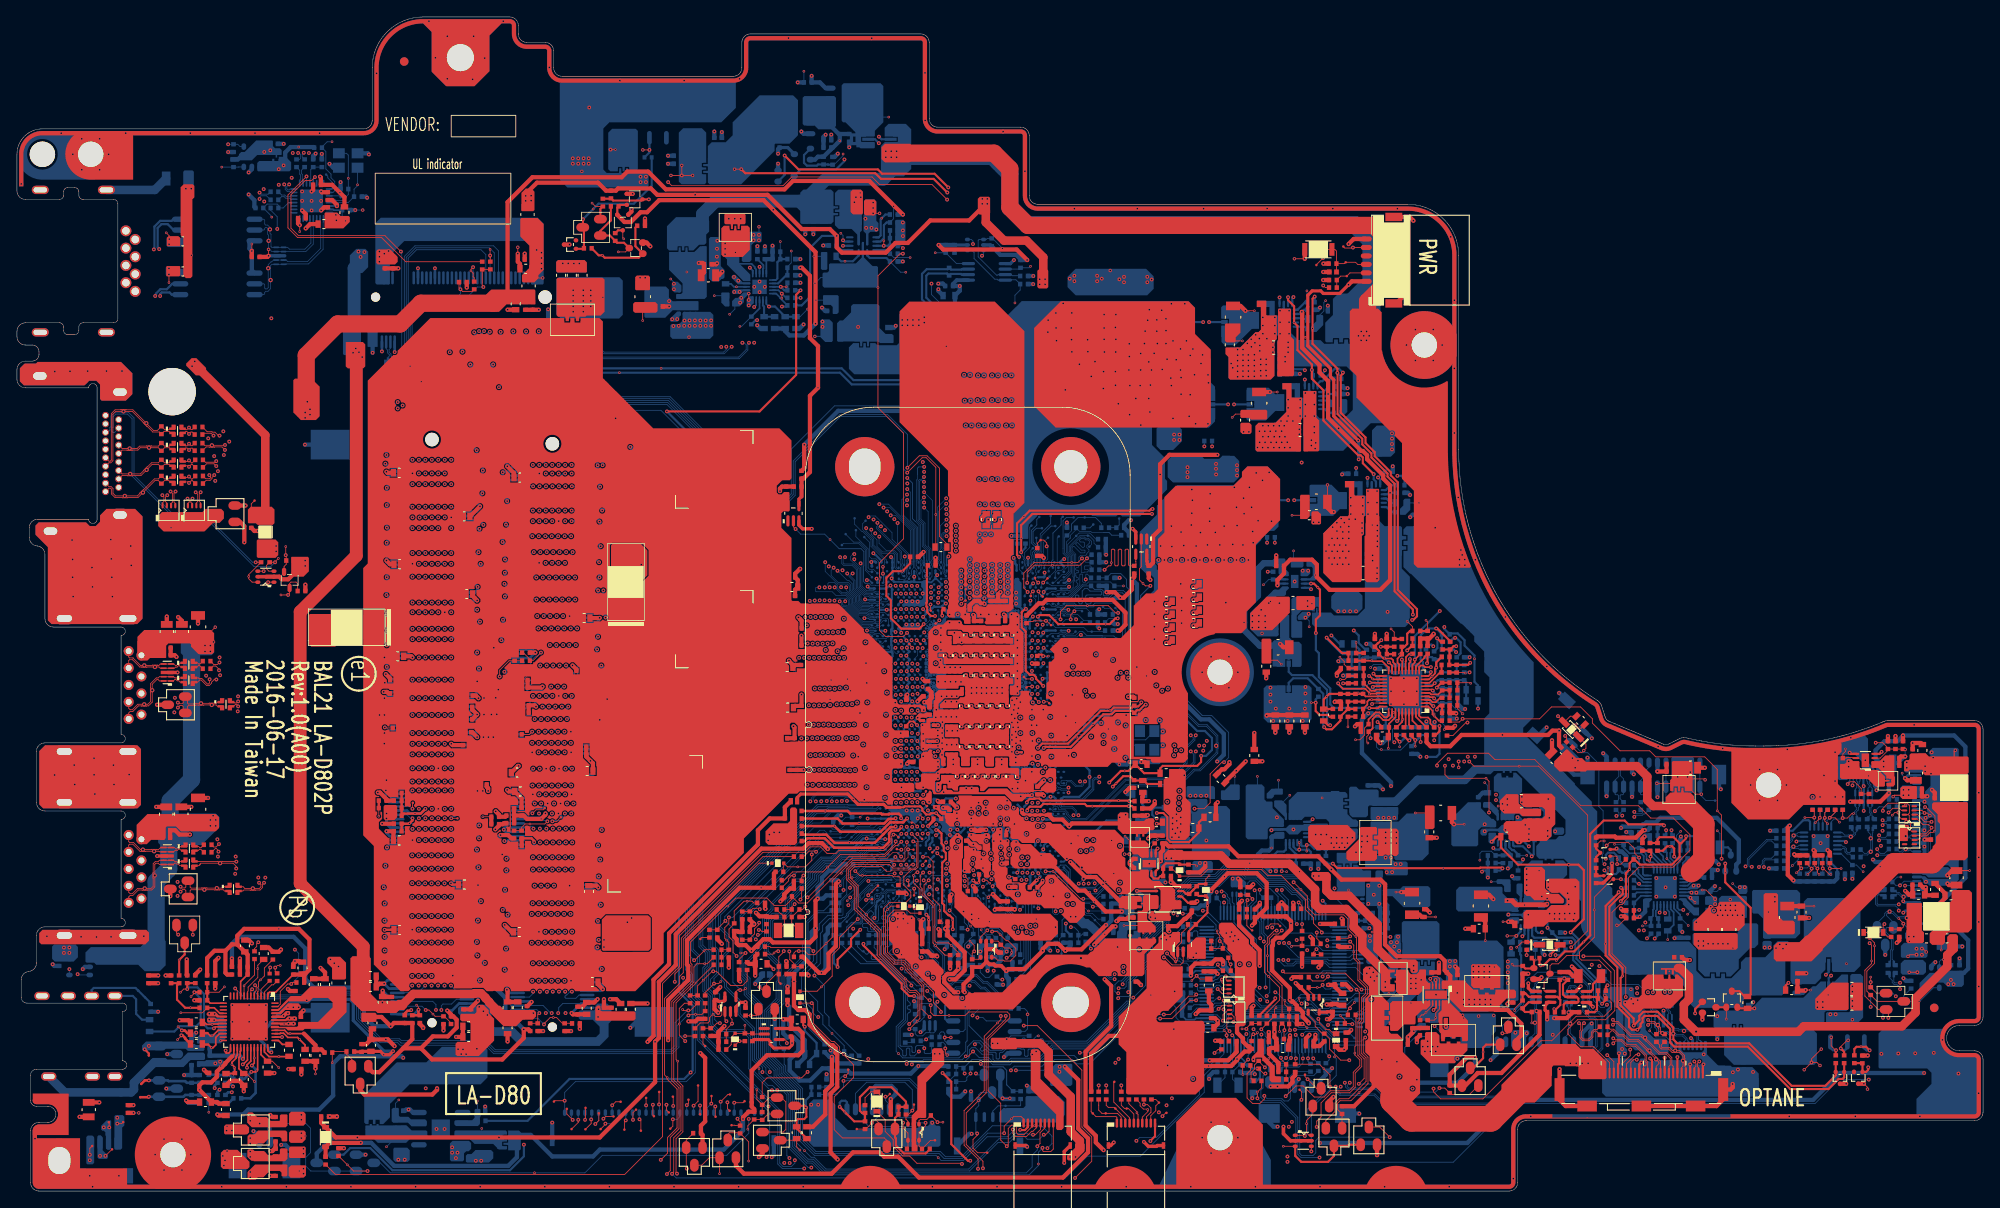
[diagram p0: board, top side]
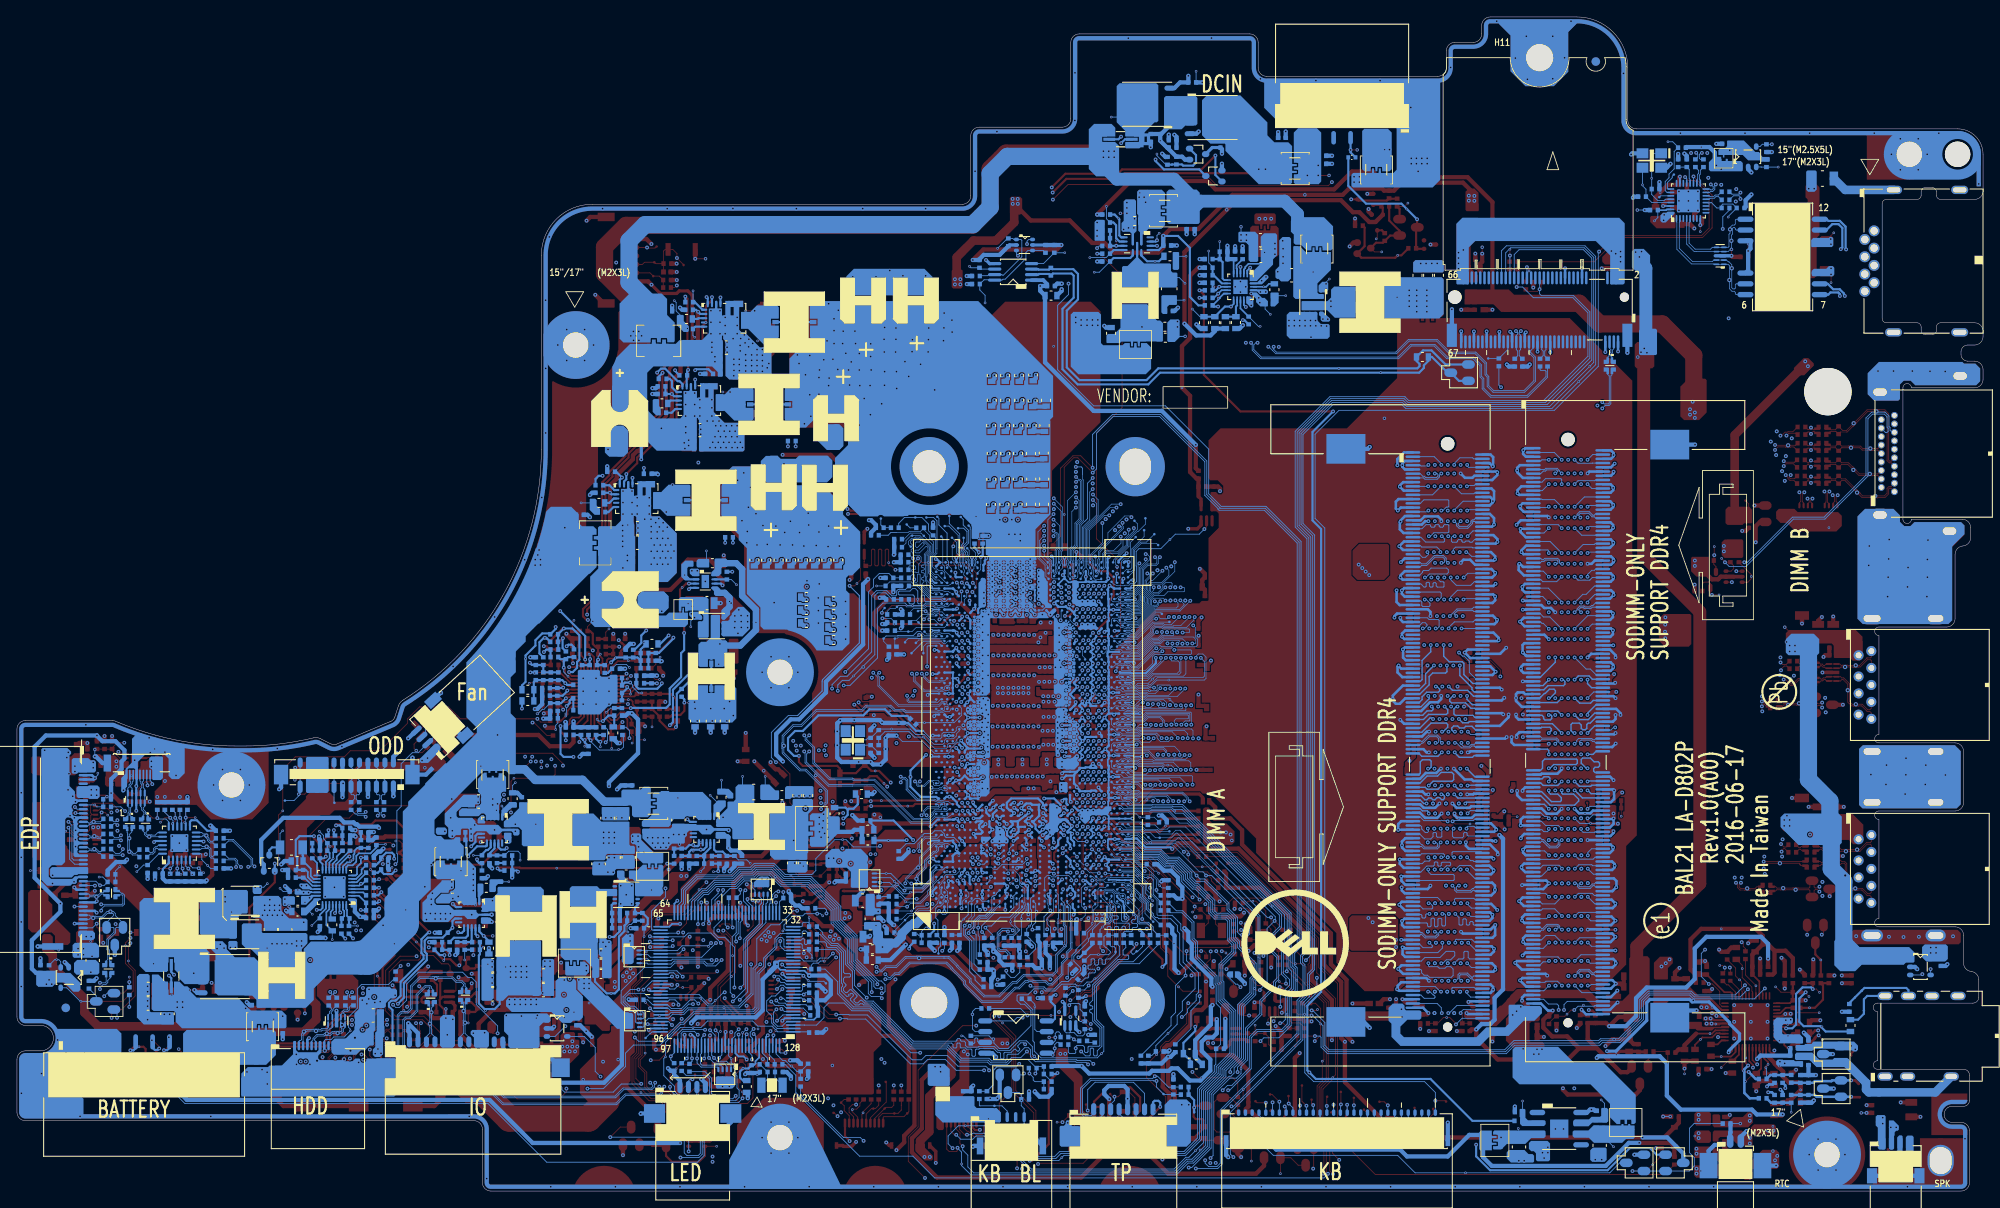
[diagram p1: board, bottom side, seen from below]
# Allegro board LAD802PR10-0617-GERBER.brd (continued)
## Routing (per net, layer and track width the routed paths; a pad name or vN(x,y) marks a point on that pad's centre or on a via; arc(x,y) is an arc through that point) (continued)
+3VALWP: length 46.3
  IN1 w0.254: v2(174.14,40.47) 173.95,40.28 173.89,40.28 172.17,38.56 164.46,38.56 164.19,38.83 164.19,38.92 162.71,40.41 v2(162.71,41.04) ; v2(172.8,37.67) 172.42,38.05 164.29,38.05 163.7,38.65 163.7,38.77 162.07,40.39 v2(162.07,41.04)
  IN1 w0.508: v2(182.62,30.49) 182.54,30.41 181.23,30.41 180.74,29.91 179.61,29.91 179.25,30.27 179.25,30.27 179.09,30.43 179.09,33.53 175.64,36.99 v2(173.49,36.99)
  BOTTOM w0.254: v2(172.8,37.67) 172.94,37.81 PR107.1 PR108.2 PR109.1 ; PU100.14 175.12,40.57 174.83,40.28 174.32,40.28 v2(174.14,40.47) ; PC107.1 163.66,39.45
  BOTTOM w0.508: PR113.1 v2(182.62,30.49) ; v2(173.49,36.99) PR107.1
  vias: v2(161.44,42.31) v2(161.44,41.68) v2(161.44,41.04) v2(162.07,42.31) v2(162.07,41.68) v2(162.71,42.31) v2(162.71,41.68)
+3VLP: length 240.8
  TOP w0.254: v2(173.95,41.22) 174.54,41.81 PC111.1 175.02,40.53 177.06,38.5 v4(183.03,38.5) 184.17,38.5 184.81,37.86 184.81,32.06 v2(183.25,30.51) ; v2(109.18,13.92) 110.2,12.9 110.2,5.53 112.16,3.57 v2(112.44,3.57) ; v2(148.42,22.75) 148.42,22.61 146.53,20.72 RE29.2
  IN1 w0.254: v2(159.02,18.81) 159.91,17.93 159.91,12.09 158.57,10.75 157.66,10.75 155.17,8.26 152.99,8.26 150.93,6.2 147.75,6.2 143.62,10.34 140.23,10.34 134.21,4.32 126.72,4.32 126.32,4.72 124.23,4.72 122.43,2.92 115.15,2.92 114.4,3.68 112.51,3.68 112.41,3.57 ; v2(59.79,5.47) 62.45,2.81 78.13,2.81 78.79,2.16 91.68,2.16 93.34,3.83 94.53,3.83 95.95,2.41 112.03,2.41 112.35,2.73 112.35,3.52 112.41,3.57 ; 112.41,3.57 v2(112.44,3.57)
  IN2 w0.254: v2(148.42,22.75) 149.26,22.75 150.44,21.57 153.05,21.57 153.22,21.4 155.61,21.4 156.66,20.35 157.87,20.35 158.26,19.96 158.26,19.42 158.87,18.81 v2(159.02,18.81) 159.99,18.81 162.18,16.62 163.89,16.62 164.92,15.59 169.01,15.59 170.87,17.45 180.36,17.45 180.6,17.21 187.58,17.21 v2(187.61,17.23)
  BOTTOM w0.254: v2(59.79,5.47) 59.79,4.1 58.15,2.46 44.28,2.46 41.67,5.07 39.3,5.07 38.52,4.29 D1.2 ; R42.1 109.3,13.8 v2(109.18,13.92) ; v2(183.25,30.51) 183.37,30.51 184.19,29.7 184.19,28.07 183.94,27.83 183.94,27.39 186.65,24.69 186.65,23.04 187.15,22.54 187.2,22.54 187.28,22.46 187.74,22.46 188.02,22.18 188.02,21.78 187.61,21.36 v2(187.61,17.23)
+3VS: length 682.3
  TOP w0.381: UE2.5 154.5,21.1 154.55,21.15 CE22.1
  TOP w0.432: QI2.5 29.42,72.47
  TOP w0.457: RC27.1 113.74,26.42 114.32,27 ; 114.32,27 QC1.5 QC1.2 ; 114.32,27 114.45,27 114.7,26.75 115.22,26.75 115.4,26.57 116.08,26.57 v2(116.69,25.96)
  TOP w0.508: RC53.1 RC57.1 85.11,30.56 85.01,30.67 RC59.1 84.6,29.99 84.89,29.7 84.89,29.24 85.12,29.01 85.94,29.01 v2(86.63,28.33) 87.13,28.84 RC73.1 87.32,28.99 88.04,29.71 RC61.1 88.78,29.71 89.17,29.33 93.53,29.33 94.19,29.99 v2(94.19,31.01) 94.19,34.24 v2(94.44,34.5) ; CD10.1 66.13,20.85 CD9.1 65.58,20.84 v2(65.42,20.99) ; v2(96.12,15.83) 96.12,12.55 95.33,11.77 95.33,9.04 93.88,7.58 R36.1 ; EC2225.1 v2(90.89,24.11) ; 29.42,72.47 QI2.2 30.94,72.47 31.24,72.17 31.99,72.17 32.81,72.98 QI3.2 ; 57.87,105.88 57.87,116.66 60.8,119.59 71.32,119.59 71.99,120.26 74.44,120.26 76.54,118.17 90.53,118.17 91.52,119.16 100.53,119.16 v2(104.49,115.19) ; R16.1 227.41,35.12 R11.1 227.41,34.55 v2(226.78,33.91) ; RC28.1 115.73,28.14 115.34,28.53 114.32,28.53 ; v2(116.69,25.96) 116.91,26.18 118.83,26.18 v2(120.99,28.34) 120.99,28.53 121.62,29.16 122.84,29.16 v2(123.65,28.35) 123.81,28.51 125.57,28.51 v2(128.45,31.39) ; v2(119.15,109.83) 117.91,111.07 109.25,111.07 v2(108.72,111.6) ; v2(146.58,26.58) 146.58,28.4 145.69,29.29 145.69,29.8 144.15,31.34 RE13.2 ; v2(209.1,43.1) 208.87,42.87 208.87,37.31 v2(209.53,36.65) ; v2(154.52,20.27) 154.81,20.27 155.18,20.64 CE22.1 ; RC9.1 92.86,85.27 v2(92.86,88.03) ; v2(50.76,21.29) 51.2,20.85 RD13.1 51.46,20.61 51.86,20.21 51.86,19.28 50.82,18.24 49.05,18.24 47.65,16.84 ; v2(220.8,46.94) 219.79,45.93 RX10.1 ; 45.55,16.84 42.73,14.02 41.95,14.02 41.45,14.53 QA1.2 ; 45.55,16.84 47.65,16.84 ; 45.55,16.84 46.63,17.92 RD14.1 CD39.1 45.73,19.83 44.47,19.83 v2(44.09,19.45) 43,20.53 CD40.1 ; v2(111.78,23.45) 111.65,23.58 111.65,24.37 112.67,25.39 RC27.1 ; RC43.2 111.02,26.29 v2(111.01,26.28) 111.01,26.18 110.45,25.61 109.82,25.61 109.81,25.6 109.75,25.6 109.37,25.23 109.37,24.63 110.55,23.45 v2(111.02,23.45) ; RD15.1 v2(43.07,43.33) ; RD2.1 v2(66.39,19.13) ; Q6.2 80.87,6.63 R24.1 80.68,7.71 81.17,8.21 81.17,15.7 v2(80.6,16.27) ; 47.65,16.84 48.97,15.52 57.25,15.52 59.77,18.05 v2(59.77,19.07) 60.34,19.07 RD1.1 ; v2(57.04,41.99) 57.93,41.99 58.32,41.6 RD3.1 ; RA2.2 v2(25.36,27.43) ; v2(90.05,34.17) 90.49,34.61 RC188.1 90.49,34.99 91.2,35.69 RC14.1 RC13.1 ; 160.04,12.91 160.04,12.34 157.71,10.01 R23.1 ; RX1.1 v2(222.46,53.74) ; R50.2 181.89,52.58 v2(181.89,54.31) 181.11,54.31 180.6,53.8 v4(175.22,53.8) 170.39,53.8 169.06,52.47 166.74,52.47 166.26,52.94 PR612.1
  TOP w2.032: 56.34,104.73 47.65,104.73 45.2,102.29 37.83,102.29 34.12,98.57 34.12,95.65
  TOP w3.048: 177.25,11.96 173.82,8.53 164.49,8.53 162.33,10.69 162.33,11.13
  IN1 w0.508: v2(154.52,20.27) 156.93,20.27 158.52,21.86 158.52,22.43 160.1,24.02 v2(160.1,24.79) ; v2(211.79,46.49) 211.79,45.79 v2(209.1,43.1) 207.95,43.1 206.58,44.47 199.16,44.47 194.11,49.52 194.11,49.76 193.37,50.5 189.5,50.5 187.55,52.46 185,52.46 183.14,54.31 v2(181.89,54.31) ; v2(57.04,41.99) 55.65,41.99 55.27,42.37 52.41,42.37 52.05,42.01 46.29,42.01 44.97,43.33 v2(43.07,43.33) ; v2(94.44,34.5) 93.68,35.26 91.14,35.26 v2(90.05,34.17) ; v2(111.21,106.76) 111.21,109.11 v2(108.72,111.6) 108.08,111.6 v2(104.49,115.19) ; v2(34.25,93.11) 34.25,97.87 31.52,100.6 29.87,100.6 29.1,101.36 29.1,104.16 30.56,105.62 30.56,111.21 29.87,111.91 29.87,114.95 28.53,116.29 28.15,116.29 27.33,117.11 v2(27.33,117.56) 27.33,118.89 26.56,119.65 26.56,122.76 27.45,123.65 30.25,123.65 31.03,122.87 31.75,122.87 32.53,123.65 34.72,123.65 35.23,123.14 v2(35.23,122.38)
  IN1 w2.413: 190.16,10.79 218.32,10.79
  IN2 w0.508: v2(173.82,15.45) 172.6,14.23 164.35,14.23 163.33,15.26 v2(162.77,15.26) ; v2(220.8,46.94) 220.53,46.68 216.02,46.68 215.6,47.1 212.43,47.1 211.82,46.49 v2(211.79,46.49)
  BOTTOM w0.076: RC105.1 124.28,29.15
  BOTTOM w0.254: UX2.13 211.49,43.56 211.31,43.74 210.69,43.74 209.45,42.5 208.44,42.5 CX4.2 ; 214.7,37.55 214.7,37.98 213.99,38.69 UX2.1
  BOTTOM w0.305: v2(65.42,20.99) 66.06,21.63 JDIMM1.255 ; v2(50.76,21.29) 51.32,21.29 52.16,22.12 JDIMM2.255
  BOTTOM w0.356: v2(108.57,22.33) 108.31,22.08 UC4.5
  BOTTOM w0.381: Q11.5 R49.1
  BOTTOM w0.406: R48.1 114.83,111.6 Q11.2
  BOTTOM w0.457: C21.1 110.4,107 110.85,107.46 U2.1
  BOTTOM w0.508: v2(123.65,28.35) 124.28,28.97 124.28,29.15 ; RC86.1 123.41,29.29 RC105.1 ; RC115.1 130.12,33.92 129.13,33.92 RC3.2 RC1.2 RC2.2 129.06,31.9 128.56,31.39 v2(128.45,31.39) ; RX14.1 RX24.1 RX22.1 RX20.1 RX16.1 v2(211.79,46.49) ; RC181.1 120.73,28.59 v2(120.99,28.34) ; v2(57.04,41.99) 56.62,41.57 56.62,23.78 57.61,22.79 57.61,20.21 58.12,19.7 59.14,19.7 v2(59.77,19.07) ; R49.1 R29.1 v2(108.72,111.6) ; RC55.1 112.14,26.66 111.76,26.28 v2(111.01,26.28) 111.01,27.32 111.27,27.58 111.27,29.29 111.46,29.48 RC42.1 ; v2(209.53,36.65) 209.65,36.52 RX11.1 RX18.1 RX26.1 RX28.1 RX30.1 214.34,36.52 214.7,36.88 CX5.2 214.7,37.55 ; C21.1 v2(111.21,106.76) 111.21,106.2 C20.1 110.64,97.76 104.91,92.03 96.86,92.03 v2(92.86,88.03) ; RC114.1 95.83,15.83 v2(96.12,15.83) 96.89,15.05 RC51.1 RC72.1 ; v2(25.36,27.43) 25.36,29.16 26.18,29.99 32.63,29.99 34.01,28.62 34.01,25.01 35.01,24.01 39.67,24.01 40.93,22.75 40.93,20.64 42.12,19.45 v2(44.09,19.45) ; v2(27.33,117.56) 28,116.88 28,116.1 RL16.1 ; RC63.1 RC64.1 116.82,26.12 116.67,25.96 v2(116.69,25.96) 116.69,25.34 116.83,25.2 116.83,25.11 RC70.2 RC69.2 ; v2(94.19,31.01) 93.73,30.55 93.73,29.53 93.33,29.13 93.33,27.42 91.02,25.1 91.02,24.24 v2(90.89,24.11) ; C17.1 229.64,25.72 230.14,26.23 230.14,29.58 226.78,32.95 v2(226.78,33.91) 229.81,36.95 229.81,52.42 228.49,53.74 v2(222.46,53.74) 222.46,53.7 221.82,53.06 220.29,53.06 219.22,52 219.22,51.01 219.56,50.67 219.56,49.8 220.8,48.57 v2(220.8,46.94) 220.81,46.93 R5.1 ; RC187.1 97.38,38.56 96.62,37.8 95.77,37.8 94.95,36.97 94.95,36.32 94.44,35.82 v2(94.44,34.5) 95.08,34.5 95.46,34.88 RC36.2 ; v2(35.23,122.38) 34.94,122.1 RL3.1 ; R48.1 115.99,110.43 117.86,110.43 118.37,109.93 R28.1 v2(119.15,109.83) ; CX4.2 209.03,43.1 v2(209.1,43.1) ; v2(173.82,15.45) 174.54,16.17 174.54,17.54 JIOB1.12 ; PR1206.1 v2(104.49,115.19)
  vias: v2(33.99,91.84) v2(33.99,91.2) v2(33.99,74.38) v2(33.99,73.74) v2(34.56,92.22) v2(34.56,91.59) v2(108.25,16.19) v2(108.84,16.19) v2(119.75,16.11) v2(120.21,16.47) v2(159.22,25.67) v2(159.53,26.24) v2(159.66,25.23) v2(159.98,25.8) v2(160.42,25.36) v2(183.23,15.05) v2(183.92,15.07) v2(184.61,15.07) v2(185.31,15.07) v2(227.79,24.4) v2(228.11,24.91) v2(228.43,24.4) v4(160.99,15.51) v4(165.12,13.14)
+3VS_CAM: length 4.2
  TOP w0.508: C14.1 224.81,35.82 v2(225.14,35.82) 225.14,35.08 C15.1 225.05,34.89 R16.2
  BOTTOM w0.305: v2(225.14,35.82) 224.87,35.55 JEDP1.30
+5V_AVDD: length 11.1
  TOP w0.203: UA1.26 25.59,16.1 25.37,15.88
  TOP w0.508: 25.37,15.88 24.57,15.08 24.57,15 24.17,14.61 24.1,14.61 23.59,14.1 CA10.1 23.59,13.49 22.92,12.82 21.87,12.82 21.51,12.46 v1(21.51,11.94) 21.51,11.93 CA11.1 23.6,10.5 23.79,10.31 RA4.2
+5V_CAM:
  vias: v1(218.4,48.98) v2(216.05,50.69) v2(216.05,50.06)
+5V_HDD:
  vias: v2(189.69,22.24) v2(190.41,22.66) v2(190.63,22.09) v2(191.17,22.52) v4(187.29,23.09) v4(189.06,22.34) v4(190.37,23.79)
+5V_HDMI: length 33.7
  TOP w0.102: CI9.1 27.64,81.07 ZT62.1
  TOP w1.016: 21.67,96.79 29.29,89.17 29.29,80.41
  IN2 w1.016: 20.02,98.06 16.02,98.06 14.63,96.67 14.63,93.49 12.85,91.71
  vias: v2(20.66,97.3) v2(20.98,97.87)
+5V_OUT:
  vias: v1(170.64,20.4)
+5V_PVDD:
  vias: v4(34.18,22.5)
+5VALW: length 314.9
  TOP w0.203: v2(167.34,24.89) 167.38,24.89 UZ3.4
  TOP w0.254: CZ5.1 138.12,34 137.37,34.75 UZ2.3 ; UX1.4 219.7,51.57 v2(219.93,51.81) ; 134.91,38.9 134.64,38.63 134.64,38.05 134.31,37.72 UZ1.4 ; PD5.3 71.14,116.34 PR8.1 70.81,116 PD6.3
  TOP w0.508: 169.06,24.38 169.06,25.38 CZ23.1 168.4,26.04 168.4,27.17 167.86,27.7 162.73,27.7 161.37,29.07 161.37,36.19 160.83,36.74 156.23,36.74 v2(155.03,37.94) 153.48,39.49 144.06,39.49 142.9,40.66 135.85,40.66 135.49,41.01 CZ22.1 135.17,40.96 135.17,40.18 134.91,39.92 v2(134.91,38.92) 134.91,38.9 ; Q15.3 176.88,17.81 177.44,18.37 177.44,19.74 175.81,21.37 174.38,21.37 174.37,21.39 ; v2(94.19,102.32) 94.19,110.76 v4(89.21,115.75) 88.07,116.88 75.74,116.88 74.32,115.46 73.55,115.46 72.41,114.32 71.65,114.32 70.81,115.16 PD6.3 ; v2(148.67,71.46) 148.67,72.09 149.45,72.87 PC685.1 150.18,74.48 152.75,74.48 153.32,73.91 153.32,72.43 154.83,70.92 160.81,70.92 161.96,72.06 161.96,82.37 v2(161.96,82.37) 161.96,83.24 161.15,84.05 161.15,84.43 159.25,86.33 159.25,86.79 158.74,87.3 158.56,87.3 v4(155.89,89.97) 154.66,91.21 v2(154.66,94.02) 154.66,95.55 153.64,96.56 153.64,97.43 151.59,99.47 151.59,103.64 151.56,103.68 v2(151.56,103.71) ; v2(155.28,11.11) 155.28,11.1 154.78,10.61 Q3.3 ; v2(139.21,34.18) 139.15,34.18 138.97,34 CZ5.1 ; Q4.3 v2(160.42,4.23)
  IN1 w0.508: v2(169.75,63.58) 168.49,62.32 168.49,58.73 168.1,58.34 168.1,56.55 167.59,56.04 162.89,56.04 162.73,56.2 160,56.2 159.84,56.36 v2(159.37,56.36) ; v2(94.19,102.32) 94.19,101.3 95,100.49 108.88,100.49 117.34,108.95 121.65,108.95 123.1,110.39 147.19,110.39 151.56,106.02 v2(151.56,103.71) ; v2(155.28,11.11) 153.32,11.11 v2(150.38,8.16)
  IN2 w0.508: v2(159.37,56.36) 159.07,56.36 157.69,57.74 156.29,57.74 153.51,60.52 153.51,64.04 151.94,65.61 150.13,65.61 148.29,67.46 148.29,71.07 v2(148.67,71.46) ; v2(134.91,38.92) 134.91,38.9 136.22,37.59 136.22,37.11 136.3,37.03 136.35,37.03 136.71,36.67 136.71,36.62 137.41,35.92 137.48,35.92 v2(139.21,34.18) ; v2(155.03,37.94) 158.91,37.94 159.94,38.97 159.94,45.04 162.07,47.17 v2(162.07,47.77)
  BOTTOM w0.254: PC661.1 v2(161.96,82.37) 161.78,82.19 PU603.2 ; PU606.6 148.88,71.66 v2(148.67,71.46) ; PC669.1 151.8,103.95 v2(151.56,103.71) 151.31,103.46 PU604.2 ; PC677.1 155.42,94.92 EC2230.1 v2(154.66,94.02) 154.39,93.75 PU605.2 ; PR615.1 PR634.1 169.45,63.87 v2(169.75,63.58)
  BOTTOM w0.508: v2(94.19,102.32) 92.81,100.93 91.12,100.93 90.61,101.44 PR206.1 PR210.2 ; v2(162.07,47.77) 162.07,48.22 158.64,51.65 158.64,55.63 v2(159.37,56.36) 159.84,56.36 160.1,56.09 PR602.2
  vias: v2(5.54,28.73) v2(5.54,28.09) v2(6.18,28.73) v2(6.18,28.09) v2(51.33,5.16) v2(51.33,4.53) v2(51.77,3.89) v2(51.96,4.53) v2(170.64,22.59) v2(170.64,22.01) v2(171.28,22.59) v2(171.28,22.01) v2(171.91,22.59) v2(171.91,22.01) v2(172.55,22.59) v2(172.55,22.01) v2(173.18,22.59) v2(173.18,22.01) v2(173.82,22.59) v2(173.82,22.01) v2(220.17,50.69) v2(220.17,50.06) v4(169.9,23.37)
+5VALWP: length 22.6
  IN2 w0.254: v2(173.69,25.23) 175.15,23.77 176.49,23.77 176.87,24.15 176.87,25.25 177.57,25.95 v2(177.57,30.05)
  BOTTOM w0.254: PC120.1 174.96,23.18 174.96,22.06 175.55,21.47 176.76,21.47 177.42,22.12 177.42,27.8 177.3,27.92 PR117.2 PR115.1 ; PU102.14 177.81,30.3 v2(177.57,30.05)
  vias: v1(174.26,26.43) v2(171.78,26.5) v2(171.78,25.86) v2(171.78,25.23) v2(172.42,26.5) v2(172.42,25.86) v2(172.42,25.23) v2(173.05,26.5) v2(173.05,25.86) v2(173.05,25.23) v2(173.69,26.5) v2(173.69,25.86)
+5VS: length 181.9
  TOP w0.508: RA4.1 23.76,8.91 v2(23.64,9.04) ; v2(26.82,76.54) 26.82,78.43 26.31,78.94 QI1.2 ; Q7.3 84.8,2.99 85.75,2.05 96.09,2.05 98.61,4.56 101.76,4.56 102.27,4.06 103.93,4.06 106.4,1.59 123.36,1.59 126.33,4.56 126.33,6.22 125.18,7.37 125.18,13.1 v2(123.6,14.67)
  TOP w1.016: 184.93,50.12 191.08,50.12 192.3,48.9 192.3,46.12 193,45.42 194.71,45.42 ; 228.37,28.53 227.68,27.84 227.68,26.47 223.94,22.74 223.94,21.06 222.32,19.44 210.76,19.44 210.12,18.79 198.04,18.79 196.6,20.22 196.6,22 197.2,22.6 197.2,25.27 196.17,26.31 195.92,26.31
  TOP w2.54: 197.02,45.26 198.97,43.31 198.97,39.14 197.51,37.68
  IN1 w1.016: 190.2,23.77 189.63,23.77 188.26,25.14 186.68,25.14 184.61,23.07 180.78,23.07 178.09,20.38 170.85,20.38 168.35,17.87
  BOTTOM w0.508: v2(45.56,15.71) 45.37,15.89 38.13,15.89 37.29,15.06 37.29,11.26 35.64,9.61 27.26,9.61 26.69,9.04 v2(23.64,9.04)
  vias: v2(30.57,76.09) v2(30.57,75.46) v2(36.98,27.32) v2(37.42,26.88) v2(37.93,26.49) v2(122.98,14.66) v2(122.96,14.06) v2(165.82,17.04) v2(166.07,16.46) v2(166.39,17.67) v2(166.4,17.04) v2(166.71,16.46) v2(166.99,17.04) v2(167.34,16.46) v2(167.57,17.04) v2(183.47,51.07) v2(184.12,50.78) v2(191.09,23.96) v2(191.09,23.32) v4(183.79,49.93)
+5VS_ODD: length 4.8
  TOP w0.102: 197.48,48.62 199,48.62 v4(199.12,48.51) ; 197.43,47.35 197.96,46.82 v4(198.67,46.82) ; 195.12,48.09 v4(193.43,48.09)
  vias: v2(195.88,48.85) v2(197.05,48.85) v2(197.38,49.42)
+17.4V_BATT+: length 14.5
  TOP w0.254: PQ710.3 203.05,21.55 PR780.2 v2(204.93,21.55)
  IN1 w0.508: v2(200.55,20.63) 197.66,23.53 197.66,25.6 196.7,26.55 196.7,30.28 v2(196.43,30.56)
  BOTTOM w0.508: v2(196.43,30.56) 196.17,30.82 PR745.2
  vias: v1(213.63,23.13) v2(212.36,22.31) v2(212.36,21.67) v2(213,22.31) v2(213,21.67)
+17.4V_BATT++: length 4.4
  TOP w0.102: v2(211.67,15.17) 212.31,15.17 v4(212.67,14.81) ; v2(211.67,15.17) v4(210.81,14.31) ; v2(211.67,15.17) 211.67,15.59 v4(212.82,16.74)
+19V_ADPIN: length 3.7
  TOP w0.102: v2(78.42,119.8) v4(79.7,119.8) ; v2(78.42,119.8) v4(78.42,120.99) ; v2(78.42,119.8) v4(77.14,119.8)
+19V_VIN: length 242.8
  TOP w0.102: v4(170.05,49.97) v2(170.05,50.67) ; v4(84.64,120.54) v2(85.43,120.54) ; PR729.1 188.95,31.35 v4(188.72,31.35)
  TOP w0.254: v2(109.74,117.79) 108.13,119.4 101.91,119.4 101.24,120.07 85.9,120.07 v2(85.43,120.54)
  TOP w0.508: v2(189.2,32.4) 189.62,32.4 PR729.1 ; v2(183.4,26.49) 184.17,25.72 PR5.1 183.56,25.35 183.08,25.83 PR7.2 PR31.2
  IN1 w0.508: v2(170.05,50.67) 170.05,49.19 175.82,43.43 177.2,43.43 177.9,44.13 179.73,44.13 180.43,43.43 181.33,43.43 183.54,41.22 183.54,39.54 183.85,39.22 183.85,33.47 185.49,31.83 185.49,27.46 184.4,26.37 183.52,26.37 v2(183.4,26.49)
  IN2 w0.508: v2(189.2,32.4) 191.93,35.13 191.93,36.9 190.01,38.82 190.01,40.82 189.2,41.64 v2(189.2,42.84) 188.38,42.84 186.39,40.85 186.39,38.29 186.38,38.27 186.38,37.44 186.39,37.43 186.39,30.59 183.4,27.6 v2(183.4,26.49) ; v2(109.74,117.79) 111.16,116.37 111.16,115.31 113.61,112.86 160.11,112.86 162.45,110.51 162.45,96.76 168.03,91.19 168.03,73.57 168.68,72.92 168.68,72.92 173.88,67.71 173.88,55.67 169.88,51.66 169.88,50.84 v2(170.05,50.67)
  BOTTOM w0.508: PD704.2 202.79,38.51 203.09,38.82 203.09,41.42 200.49,44.02 193.85,44.02 193.31,43.48 192.19,43.48 191.97,43.26 191.79,43.26 191.52,42.99 189.35,42.99 v2(189.2,42.84)
+19VB: length 211.8
  TOP w2.032: 159.3,102.96 159.3,102.97 159.3,104.93 162.6,108.23 162.6,111.37 160.05,113.91 119.24,113.91 117.11,116.04 117.11,120.57 115.25,122.43 105.18,122.43
  TOP w2.413: 227.03,39.81 225.9,38.68 221.41,38.68 211.48,28.75 211.46,28.75
  BOTTOM w1.016: 173.57,49.74 172,49.74 170.77,48.5 165.2,48.5 162.63,45.93 160.04,45.93
  BOTTOM w1.524: 103.33,120.53 102.17,119.36 95.42,119.36 93.75,117.68 ; 80.86,114 80.86,115.25 82.38,116.77 92.31,116.77 92.79,116.29
  BOTTOM w2.032: 157.56,105.05 159.71,107.19 159.71,112.1 157.8,114 119.15,114 117.11,116.04 117.11,120.02 115.08,122.05 105.21,122.05
  BOTTOM w4.064: 191.16,27.54 190.53,27.54 186.52,31.55 186.52,33.67
  vias: v2(102.48,122.66) v2(102.48,121.95) v2(103.12,122.66) v2(103.12,121.95) v2(103.75,122.66) v2(103.75,121.95) v2(158.22,100.88) v2(158.54,100.35) v2(158.55,101.4) v2(158.86,100.88) v2(159.19,101.4) v2(159.18,100.35) v2(159.49,100.88) v2(170.15,74.49) v2(170.15,73.86) v2(170.31,75.62) v2(170.47,75.04) v2(170.77,74.49) v2(170.78,73.83) v2(207.47,28.66) v2(207.92,29.1) v2(208.3,28.59) v2(208.68,29.1) v4(167.28,78.25)
+19VB_1.2V: length 20.2
  TOP w0.508: PC206.1 81.03,108.36 PC230.1 80.88,109.48 v2(80.42,109.48)
  IN1 w0.254: v2(92.43,105.36) 93.11,106.05 93.11,109.07 92.77,109.42 91.51,109.42 91.31,109.62 83.5,109.62 82.75,108.87 81.58,108.87 80.97,109.48 v2(80.42,109.48)
  BOTTOM w0.254: PR208.1 v2(92.43,105.36)
  vias: v1(79.01,108.41)
+19VB_+1VALW:
  vias: v1(153.94,46.37)
+VCC_CORE: length 43.1
  TOP w0.508: v2(130.83,56.14) 131.48,55.49 RC150.1
  BOTTOM w0.102: UC1.K43 118.26,57.87 ; UC1.K43 118.22,58.14 ; UC1.K43 118.52,57.84 ; UC1.J37 119.29,54.94 ; UC1.J37 118.99,54.64 ; UC1.J37 118.68,54.94 ; UC1.J37 118.99,55.25 ; UC1.G30 119.45,51.13 ; UC1.G30 119.72,51.09 ; UC1.G30 119.15,50.83 ; 107.52,55.4 UC1.AM38 ; UC1.AM38 107.21,55.09 ; UC1.AM38 106.95,55.13 ; UC1.AM38 106.91,55.4 ; UC1.AL37 107.99,54.03 ; UC1.AL37 107.38,54.03 ; UC1.AL37 107.69,53.72 ; UC1.AL37 107.69,54.33 ; 119.76,54.48 UC1.G37 ; UC1.G37 119.45,54.79 ; UC1.G37 119.15,54.48 ; UC1.G37 119.72,54.75 ; UC1.J33 118.99,53.42 ; UC1.J33 118.99,52.81 ; UC1.J33 119.29,53.11 ; UC1.J33 118.68,53.11 ; 106.91,54.48 UC1.AM37 ; UC1.AM37 107.21,54.79 ; UC1.AM37 107.21,54.18 ; UC1.AM37 107.52,54.48 ; UC1.G38 119.72,55.13 ; UC1.G38 119.45,55.09 ; UC1.G38 119.76,55.4 ; UC1.G38 119.15,55.4 ; UC1.G42 119.72,56.96 ; UC1.G42 119.45,56.92 ; UC1.G42 119.15,57.23 ; UC1.K42 118.52,57.53 ; UC1.K42 118.52,56.92 ; UC1.K42 118.83,57.23 ; UC1.K42 118.22,57.23 ; 107.21,52.35 UC1.AM33 ; UC1.AM33 107.52,52.65 ; UC1.AM33 107.21,52.96 ; UC1.AM33 106.91,52.65 ; 119.76,53.57 UC1.G35 ; UC1.G35 119.15,53.57 ; UC1.G35 119.72,53.3 ; UC1.G35 119.45,53.26 ; 107.69,55.55 UC1.AL40 107.99,55.86 ; UC1.AK40 108.42,56.58 ; UC1.AK40 108.15,56.62 ; UC1.AK40 108.46,56.31 ; UC1.AK40 108.15,56.01 ; UC1.J40 118.99,57.07 ; UC1.J40 119.29,56.77 ; UC1.J40 118.99,56.46 ; UC1.J40 118.68,56.77 ; 118.52,53.26 UC1.K35 ; UC1.K35 118.22,53.57 ; UC1.K35 118.83,53.57 ; UC1.K35 118.26,53.3 ; UC1.G32 119.72,51.47 ; UC1.G32 119.15,51.74 ; UC1.G32 119.45,51.43 ; 118.83,55.4 UC1.K38 ; UC1.K38 118.26,55.13 ; UC1.K38 118.22,55.4 ; UC1.K38 118.52,55.09 ; 118.22,54.48 UC1.K37 ; UC1.K37 118.83,54.48 ; UC1.K37 118.26,54.75 ; UC1.K37 118.52,54.79 ; 118.83,52.65 UC1.K33 ; UC1.K33 118.52,52.96 ; UC1.K33 118.26,52.92 ; UC1.J30 118.99,51.59 ; UC1.J30 119.29,51.28 ; UC1.J30 118.99,50.98 ; UC1.J30 118.68,51.28 ; UC1.AK38 108.15,55.7 ; UC1.AK38 108.46,55.4 ; UC1.AK38 108.42,55.66 ; UC1.AK38 107.85,55.4 ; UC1.K40 118.26,56.58 ; UC1.K40 118.22,56.31 ; UC1.K40 118.83,56.31 ; UC1.K40 118.52,56.62 ; UC1.AK33 108.42,52.39 ; UC1.AK33 108.46,52.65 ; UC1.AK33 108.15,52.35 ; UC1.AK33 107.85,52.65 ; 107.38,52.2 UC1.AL33 ; UC1.AL33 107.69,52.5 ; UC1.AL33 107.99,52.2 ; UC1.AL33 107.69,51.89 ; 119.76,52.65 UC1.G33 ; UC1.G33 119.15,52.65 ; UC1.G33 119.72,52.92 ; UC1.G33 119.45,52.96 ; 107.21,53.26 UC1.AM35 ; UC1.AM35 107.52,53.57 ; UC1.AM35 106.91,53.57 ; UC1.AM35 107.21,53.87 ; 108.15,54.18 UC1.AK37 ; UC1.AK37 107.85,54.48 ; UC1.AK37 108.42,54.22 ; UC1.AK37 108.46,54.48 ; 119.76,56.31 UC1.G40 ; UC1.G40 119.15,56.31 ; UC1.G40 119.45,56.62 ; UC1.G40 119.72,56.58 ; UC1.AM32 106.95,52.01 ; UC1.AM32 107.52,51.74 ; UC1.AM32 107.21,52.05 ; UC1.AK35 108.42,53.84 ; UC1.AK35 108.46,53.57 ; UC1.AK35 107.85,53.57 ; UC1.AK35 108.15,53.87
  BOTTOM w0.152: v2(124.48,58.52) 124.32,58.68 UC1.A44
  BOTTOM w0.203: v2(124.05,51.34) 123.96,51.25 UC1.A30 ; v2(123.72,56.03) 123.54,56.21 UC1.A39 ; UC1.A34 v2(123.87,53.73)
  vias: v2(106.82,54.97) v2(106.89,53.93) v2(106.91,53.09) v2(106.88,52.19) v2(108.44,56.77) v2(108.38,55.88) v2(108.62,54.33) v2(108.62,53.72) v2(108.63,52.5) v2(109.05,58.36) v2(108.99,55.93) v2(109.13,54.03) v2(109.11,52.84) v2(109.11,51.45) v2(109.16,55.31) v2(109.15,54.63) v2(109.16,53.45) v2(109.15,52.16) v2(109.6,55.93) v2(109.66,58.36) v2(109.67,52.65) v2(110.21,55.93) v2(110.27,58.36) v2(110.26,52.65) v2(110.81,55.93) v2(110.84,52.66) v2(110.85,58.37) v2(111.39,57.19) v2(111.41,54.81) v2(111.36,52.38) v2(112.59,57.22) v2(112.61,54.8) v2(112.61,52.41) v2(113.79,57.24) v2(113.81,54.8) v2(113.81,52.41) v2(114.99,57.24) v2(115.02,54.8) v2(115.02,52.41) v2(116.2,57.24) v2(116.23,54.8) v2(116.23,52.41) v2(117.33,56.22) v2(117.37,57.89) v2(117.36,55.28) v2(117.36,53.8) v2(117.36,53.22) v2(117.41,52.42) v2(117.36,51.81) v2(117.5,54.7) v2(117.57,56.75) v2(117.66,57.36) v2(117.69,55.76) v2(117.79,54.2) v2(117.83,52.82) v2(117.81,51.16) v2(117.81,50.55) v2(117.92,58.08) v2(117.87,53.52) v2(118.03,56.35) v2(118.04,55.28) v2(118.12,56.96) v2(118.09,54.7) v2(118.35,57.68) v2(118.35,53.1) v2(119.72,56.79) v2(119.68,54.96) v2(119.72,51.32) v2(119.77,53.09) v2(120.28,54.95) v2(121.05,56.79) v2(134.17,69.55) v2(134.16,68.05) v2(134.16,66.58) v2(134.16,65.11) v2(134.89,76.09) v2(135.34,74.44) v2(135.55,69.93) v2(135.56,68.41) v2(135.56,66.88) v2(135.56,65.36) v2(136.16,78.44) v2(136.23,76.03) v2(136.74,74.44) v2(137.31,77.74) v2(137.27,71.62) v2(137.38,69.97) v2(137.37,68.47) v2(137.37,67) v2(137.62,76.15) v2(138.13,74.44) v2(138.51,78.57) v2(138.58,82.76) v2(138.64,81.49) v2(138.58,79.96) v2(138.72,71.99) v2(138.77,70.45) v2(138.77,68.93) v2(138.77,67.4) v2(139.09,76.09) v2(139.53,74.44) v2(139.59,77.68) v2(140.42,76.22) v2(140.74,82.25) v2(140.67,80.54) v2(140.67,79.01) v2(140.93,74.44) v2(141.35,77.69) v2(141.88,76.22) v2(142.39,78.44) v2(142.39,74.44) v2(143.4,76.28) v2(143.59,83.01) v2(143.85,80.66) v2(143.85,74.44) v2(143.91,78.5) v2(144.61,76.22) v2(144.67,81.74) v2(144.74,79.9) v2(145.24,74.44) v2(145.37,83.01) v2(145.63,80.66) v2(145.75,77.81) v2(145.82,76.47) v2(146.17,84.71) v2(146.39,79.08) v2(146.91,83.84) v2(147.7,84.78) v2(147.98,79.01) v4(132.09,61.82) v4(142.59,69.41)
+VCC_CORE_G0: length 1.1
  TOP w0.254: TP32.1 118.03,51.76 118.01,51.74 v2(117.96,51.74)
  BOTTOM w0.254: UC1.K32 v2(117.96,51.74)
+VCC_CORE_G1: length 1.1
  TOP w0.076: TP33.1 108.5,51.76 v2(108.63,51.89)
  BOTTOM w0.076: v2(108.63,51.89) 108.48,51.74 UC1.AK32
+VCC_GT: length 128.9
  TOP w0.254: v2(108.92,62.63) 108.69,62.63 108.31,63 PC1042.1 ; v2(118,61.34) 117.81,61.53 PC1176.1
  TOP w0.508: PC1182.1 115.97,78.89 v2(115.97,79.19) ; RC157.1 108.35,74.7 v2(108.35,74.71) ; PC1180.1 114.56,78.75 v2(114.56,79.2)
  IN1 w0.508: 104.29,67.01 104.29,67.01 104.29,66.58 104.3,66.57 v2(104.3,65.85)
  BOTTOM w0.076: UC1.AK45 108.79,59.06 108.84,59.11
  BOTTOM w0.102: UC1.AK48 108.42,61.15 ; UC1.AK48 107.85,60.88 ; UC1.AK48 108.46,60.88 ; UC1.AK48 108.15,61.19 ; UC1.AA63 112.76,69.27 ; UC1.AA63 113.06,68.96 ; UC1.AA63 112.45,68.96 ; UC1.AA63 112.76,68.66 ; UC1.AA64 112.49,69.35 ; UC1.AA64 113.06,69.61 ; UC1.AA64 112.76,69.92 ; UC1.AA64 112.76,69.31 ; 108.46,64.54 UC1.AK55 ; UC1.AK55 108.42,64.81 ; UC1.AK55 107.85,64.54 ; UC1.AK55 108.15,64.85 ; UC1.L65 117.33,70.57 ; UC1.L65 117.33,69.96 ; UC1.L65 117.06,70 ; UC1.L65 117.02,70.26 ; 117.33,73.21 UC1.L70 ; UC1.L70 117.02,73.51 ; UC1.L70 117.06,73.25 ; UC1.L70 117.33,73.82 ; 118.99,62.86 UC1.J52 ; UC1.J52 118.99,63.48 ; UC1.J52 118.68,63.17 ; UC1.R67 115.23,71.3 ; UC1.R67 115.5,71.87 ; UC1.R67 115.19,71.56 ; UC1.R67 115.5,71.26 ; 107.69,57.99 UC1.AL43 ; UC1.AL43 107.69,57.38 ; UC1.AL43 107.99,57.68 ; 107.85,57.23 UC1.AK42 ; UC1.AK42 108.46,57.23 ; UC1.AK42 108.42,57.49 ; UC1.AK42 108.15,57.53 ; 116.11,68.96 UC1.N63 ; UC1.N63 116.72,68.96 ; UC1.N63 116.41,68.66 ; UC1.N63 116.41,69.27 ; 111.84,73.86 UC1.AC71 ; UC1.AC71 112.15,74.16 ; UC1.AC71 111.84,74.47 ; UC1.AC71 112.11,74.43 ; 113.67,72.56 UC1.W69 ; UC1.W69 113.4,72.6 ; UC1.W69 113.67,73.17 ; UC1.W69 113.37,72.86 ; 115.19,70.26 UC1.R65 ; UC1.R65 115.5,70.57 ; UC1.R65 115.81,70.26 ; UC1.R65 115.5,69.96 ; UC1.R64 115.5,69.92 ; UC1.R64 115.5,69.31 ; UC1.R64 115.19,69.61 ; UC1.R64 115.81,69.61 ; 115.5,73.21 UC1.R70 ; UC1.R70 115.19,73.51 ; UC1.R70 115.5,73.82 ; UC1.R70 115.81,73.51 ; 118.99,62.56 UC1.J50 ; UC1.J50 118.99,61.95 ; UC1.J50 118.68,62.26 ; 118.22,62.71 UC1.K52 ; UC1.K52 118.83,62.71 ; UC1.K52 118.52,62.41 ; UC1.K52 118.52,63.02 ; 114.89,72.21 UC1.U68 ; UC1.U68 114.59,71.91 ; UC1.U68 114.59,72.52 ; UC1.U68 114.32,71.95 ; 118.83,61.8 UC1.K50 ; UC1.K50 118.52,61.49 ; UC1.K50 118.26,61.53 ; UC1.K50 118.52,62.1 ; 118.22,65.46 UC1.K56 ; UC1.K56 118.52,65.76 ; UC1.K56 118.52,65.15 ; UC1.K56 118.83,65.46 ; UC1.J53 118.68,64.08 ; UC1.J53 118.99,63.78 ; UC1.J53 118.99,64.39 ; 108.15,58.75 UC1.AK45 ; UC1.AK45 108.42,59.32 ; UC1.AK45 108.15,59.36 ; UC1.AK45 107.85,59.06 ; 114.59,73.86 UC1.U71 ; UC1.U71 114.59,74.47 ; UC1.U71 114.28,74.16 ; UC1.U71 114.89,74.16 ; UC1.L62 117.52,68.23 ; UC1.L62 117.48,68.49 ; UC1.L62 117.79,68.19 ; UC1.L62 118.09,68.49 ; UC1.K60 118.52,67.59 ; UC1.K60 118.22,67.29 ; UC1.K60 118.52,66.98 ; UC1.K60 118.83,67.29 ; UC1.AC70 112.11,73.78 ; UC1.AC70 111.84,73.82 ; UC1.AC70 111.84,73.21 ; UC1.AC70 112.15,73.51 ; UC1.AA66 112.76,71.22 ; UC1.AA66 113.02,71.18 ; UC1.AA66 113.06,70.91 ; UC1.AA66 112.49,71.18 ; 116.41,71.26 UC1.N67 ; UC1.N67 116.15,71.3 ; UC1.N67 116.41,71.87 ; UC1.N67 116.72,71.56 ; UC1.AA71 113.06,74.16 ; UC1.AA71 112.76,74.47 ; UC1.AA71 112.76,73.86 ; UC1.AA71 112.45,74.16 ; 107.85,63.63 UC1.AK53 ; UC1.AK53 108.42,63.36 ; UC1.AK53 108.15,63.32 ; UC1.AK53 108.46,63.63 ; UC1.W71 113.67,74.47 ; UC1.W71 113.67,73.86 ; UC1.W71 113.37,74.16 ; UC1.W71 113.98,74.16 ; 108.15,65.15 UC1.AK56 ; UC1.AK56 107.85,65.46 ; UC1.AK56 108.42,65.19 ; UC1.AK56 108.46,65.46 ; 108.46,66.37 UC1.AK58 ; UC1.AK58 108.42,66.64 ; UC1.AK58 108.15,66.68 ; UC1.AK58 107.85,66.37 ; UC1.W63 113.67,69.27 ; UC1.W63 113.67,68.66 ; UC1.W63 113.37,68.96 ; UC1.W63 113.4,69.23 ; UC1.L69 117.33,73.17 ; UC1.L69 117.02,72.86 ; UC1.L69 117.06,72.6 ; UC1.L69 117.33,72.56 ; 118.99,67.44 UC1.J60 118.68,67.74 ; 113.67,73.21 UC1.W70 ; UC1.W70 113.37,73.51 ; UC1.W70 113.67,73.82 ; UC1.W70 113.4,73.25 ; UC1.N64 116.72,69.61 ; UC1.N64 116.41,69.31 ; UC1.N64 116.11,69.61 ; UC1.N64 116.41,69.92 ; 113.06,71.56 UC1.AA67 ; UC1.AA67 112.76,71.26 ; UC1.AA67 112.76,71.87 ; UC1.AA67 112.49,71.3 ; UC1.N66 116.41,71.22 ; UC1.N66 116.15,71.18 ; UC1.N66 116.68,71.18 ; UC1.N66 116.72,70.91 ; UC1.W64 113.4,69.35 ; UC1.W64 113.37,69.61 ; UC1.W64 113.67,69.92 ; UC1.W64 113.67,69.31 ; 118.22,64.54 UC1.K55 ; UC1.K55 118.52,64.24 ; UC1.K55 118.83,64.54 ; UC1.K55 118.52,64.85 ; UC1.K53 118.83,63.63 ; UC1.K53 118.52,63.32 ; UC1.K53 118.52,63.93 ; UC1.K53 118.22,63.63 ; UC1.N70 116.41,73.82 ; UC1.N70 116.41,73.21 ; UC1.N70 116.72,73.51 ; UC1.N70 116.11,73.51 ; UC1.K58 118.52,66.68 ; UC1.K58 118.26,66.1 ; UC1.K58 118.83,66.37 ; UC1.K58 118.52,66.07 ; UC1.AM58 107.52,66.37 ; 118.99,66.52 UC1.J58 ; UC1.J58 118.68,66.83 ; UC1.J58 118.99,67.13 ; 107.69,62.86 UC1.AL53 ; UC1.AL53 107.99,63.17 ; UC1.AL53 107.38,63.17 ; UC1.AL53 107.69,63.48 ; 114.74,68.49 UC1.T62 ; UC1.T62 115.04,68.8 ; UC1.T62 115.35,68.49 ; UC1.T62 115.04,68.19 ; UC1.L63 117.06,69.23 ; UC1.L63 117.02,68.96 ; UC1.L63 117.33,68.66 ; UC1.L63 117.33,69.27 ; 117.33,73.86 UC1.L71 ; UC1.L71 117.02,74.16 ; UC1.L71 117.06,74.43 ; UC1.L71 117.06,73.9 ; 118.99,64.69 UC1.J55 ; UC1.J55 118.68,65 ; UC1.J55 118.99,65.3 ; UC1.AK43 108.15,58.45 ; UC1.AK43 107.85,58.14 ; UC1.AK43 108.15,57.84 ; UC1.AK43 108.46,58.14 ; 115.19,74.16 UC1.R71 ; UC1.R71 115.5,73.86 ; UC1.R71 115.5,74.47 ; UC1.R71 115.81,74.16 ; 118.99,65.61 UC1.J56 ; UC1.J56 118.99,66.22 ; UC1.J56 118.68,65.91 ; 108.15,66.98 UC1.AK60 108.42,67.02 ; 107.21,63.32 UC1.AM53 107.52,63.63 ; 115.19,72.86 UC1.R69 ; UC1.R69 115.81,72.86 ; UC1.R69 115.5,73.17 ; UC1.R69 115.5,72.56 ; 107.85,59.97 UC1.AK46 ; UC1.AK46 108.15,59.66 ; UC1.AK46 108.42,59.7 ; 115.5,71.91 UC1.R68 ; UC1.R68 115.23,71.95 ; UC1.R68 115.5,72.52 ; UC1.R68 115.19,72.21 ; 107.38,61.34 UC1.AL50 ; UC1.AL50 107.69,61.04 ; UC1.AL50 107.69,61.65 ; UC1.AL50 107.99,61.34 ; 118.99,59.82 UC1.J45 118.99,59.21 ; UC1.W65 113.4,70 ; UC1.W65 113.67,69.96 ; UC1.W65 113.67,70.57 ; UC1.W65 113.37,70.26 ; 107.85,61.8 UC1.AK50 ; UC1.AK50 108.15,61.49 ; UC1.AK50 108.46,61.8 ; UC1.AK50 108.42,61.53 ; 117.33,71.91 UC1.L68 ; UC1.L68 117.02,72.21 ; UC1.L68 117.06,71.95 ; UC1.L68 117.33,72.52 ; 107.21,62.41 UC1.AM52 107.52,62.71 ; 107.21,61.19 UC1.AM48 ; UC1.AM48 107.21,60.58 ; UC1.AM48 107.52,60.88 ; 114.89,70.26 UC1.U65 ; UC1.U65 114.32,70 ; UC1.U65 114.59,69.96 ; UC1.U65 114.59,70.57 ; 112.15,71.56 UC1.AC67 ; UC1.AC67 112.11,71.3 ; UC1.AC67 111.84,71.26 ; UC1.N69 116.41,73.17 ; UC1.N69 116.41,72.56 ; UC1.N69 116.72,72.86 ; UC1.N69 116.11,72.86 ; UC1.K48 118.52,61.19 ; UC1.K48 118.52,60.58 ; UC1.K48 118.22,60.88 ; UC1.K48 118.83,60.88 ; 117.33,70.61 UC1.L66 ; UC1.L66 117.33,71.22 ; UC1.L66 117.02,70.91 ; UC1.L66 117.06,70.65 ; UC1.AC69 112.11,73.13 ; UC1.AC69 111.84,72.56 ; UC1.AC69 112.15,72.86 ; UC1.AC69 111.84,73.17 ; 107.69,66.52 UC1.AL60 107.99,66.83 ; 118.68,58.6 UC1.J43 118.99,58.9 ; UC1.Y62 113.21,68.8 ; UC1.Y62 113.21,68.19 ; UC1.Y62 113.52,68.49 ; UC1.Y62 112.91,68.49 ; UC1.W66 113.67,71.22 ; UC1.W66 113.37,70.91 ; UC1.W66 113.67,70.61 ; UC1.W66 113.4,70.65 ; UC1.R63 115.5,69.27 ; UC1.R63 115.81,68.96 ; UC1.R63 115.5,68.66 ; UC1.R63 115.19,68.96 ; UC1.L64 117.33,69.92 ; UC1.L64 117.02,69.61 ; UC1.L64 117.06,69.35 ; UC1.L64 117.33,69.31 ; 107.85,62.71 UC1.AK52 ; UC1.AK52 108.42,62.98 ; UC1.AK52 108.46,62.71 ; UC1.AK52 108.15,63.02 ; 112.76,73.21 UC1.AA70 ; UC1.AA70 112.76,73.82 ; UC1.AA70 112.45,73.51 ; UC1.AA70 113.06,73.51 ; 118.99,60.12 UC1.J46 ; UC1.J46 118.99,60.73 ; UC1.J46 118.68,60.43 ; UC1.N71 116.72,74.16 ; UC1.N71 116.11,74.16 ; UC1.N71 116.41,73.86 ; UC1.N71 116.41,74.47 ; 111.84,72.52 UC1.AC68 112.11,72.48 ; 113.37,72.21 UC1.W68 ; UC1.W68 113.4,71.95 ; UC1.W68 113.67,71.91 ; UC1.W68 113.67,72.52 ; 107.69,59.21 UC1.AL46 ; UC1.AL46 107.69,59.82 ; UC1.AL46 107.99,59.51 ; 116.57,68.49 UC1.M62 ; UC1.M62 116.87,68.19 ; UC1.M62 117.18,68.49 ; UC1.M62 116.87,68.8 ; 107.69,64.69 UC1.AL56 ; UC1.AL56 107.99,65 ; UC1.AL56 107.69,65.3 ; 118.99,61.04 UC1.J48 ; UC1.J48 118.68,61.34 ; UC1.J48 118.99,61.65 ; UC1.R66 115.5,71.22 ; UC1.R66 115.19,70.91 ; UC1.R66 115.23,70.65 ; UC1.R66 115.5,70.61 ; UC1.W67 113.67,71.87 ; UC1.W67 113.4,71.3 ; UC1.W67 113.67,71.26 ; UC1.W67 113.37,71.56 ; 117.02,71.56 UC1.L67 ; UC1.L67 117.33,71.87 ; UC1.L67 117.06,71.3 ; UC1.L67 117.33,71.26 ; UC1.AC66 111.84,71.22 ; UC1.AC66 112.11,71.18 ; UC1.AC66 112.15,70.91 ; UC1.AA69 112.76,73.17 ; UC1.AA69 112.76,72.56 ; UC1.AA69 112.45,72.86 ; UC1.AA69 113.06,72.86 ; UC1.AM50 107.52,61.8 ; UC1.AM50 107.21,61.49 ; UC1.AM50 107.21,62.1 ; UC1.AM56 107.52,65.46
  BOTTOM w0.127: UC1.BB57 100.29,66.09 v2(100.26,66.12) ; UC1.AK70 108.33,74.69 v2(108.35,74.71)
  BOTTOM w0.203: UC1.A62 123.98,68.6 v2(124.02,68.56) ; UC1.A53 123.34,63.83 v2(123.67,63.83) ; UC1.AC64 UC1.AC65 UC1.AC66 ; v2(124.1,71.28) 123.9,71.08 UC1.A66 ; UC1.A48 123.33,60.99 v2(123.9,60.99) ; v2(124.05,66.09) 124.05,66.1 124.03,66.12 UC1.A58
  BOTTOM w0.254: UC1.AU63 103.96,69.22 104.3,69.56 v2(104.31,69.56) ; v2(118,65.91) 118.46,66.37 UC1.K58 ; v2(118,59.5) 118.01,59.51 UC1.J45 ; UC1.AU58 103.96,66.33 104.3,66 v2(104.3,65.85) ; UC1.K50 118.46,61.8 v2(118,61.34) ; UC1.BB66 101.09,71.07 101.08,71.08 100.57,71.08 v2(100.34,71.31)
  vias: v2(108.78,61.79) v2(108.99,66.42) v2(108.97,65.56) v2(108.96,64.75) v2(108.99,63.83) v2(109.42,61.78) v2(110,67.06) v2(110.12,63.18) v2(110.07,61.79) v2(110.65,61.78) v2(110.95,68.01) v2(111.15,67.06) v2(111.32,63.18) v2(111.27,61.78) v2(112.42,96.28) v2(112.39,74.54) v2(112.39,73.83) v2(112.4,73.19) v2(112.38,72.52) v2(112.39,71.23) v2(112.48,93.24) v2(112.53,65.6) v2(112.53,63.18) v2(112.53,60.83) v2(112.61,90.32) v2(113.23,73.84) v2(113.21,73.19) v2(113.23,72.51) v2(113.23,71.87) v2(113.23,71.24) v2(113.23,70.6) v2(113.56,77.47) v2(113.56,76.71) v2(113.74,65.6) v2(113.74,63.18) v2(113.74,60.83) v2(114,93.3) v2(114.07,96.22) v2(114.13,90.32) v2(114.13,87.01) v2(114.07,73.84) v2(114.07,71.92) v2(114.1,69.93) v2(114.19,83.98) v2(114.19,81.01) v2(114.19,77.47) v2(114.89,77.47) v2(114.94,65.6) v2(114.94,63.18) v2(114.94,60.83) v2(115.02,73.87) v2(115.02,73.23) v2(115.02,72.6) v2(115.02,71.9) v2(115.02,71.27) v2(115.02,70.63) v2(115.72,96.22) v2(115.72,93.3) v2(115.72,90.32) v2(115.65,86.98) v2(115.65,83.99) v2(115.72,81.01) v2(115.97,73.84) v2(115.98,73.15) v2(115.98,72.51) v2(116,71.27) v2(116.15,65.6) v2(116.15,63.18) v2(116.15,60.83) v2(116.86,73.87) v2(116.86,73.23) v2(116.86,72.54) v2(116.86,71.9) v2(116.86,71.27) v2(116.86,70.57) v2(117.3,96.22) v2(117.3,93.3) v2(117.3,87.01) v2(117.3,83.97) v2(117.3,68.01) v2(117.37,90.32) v2(117.37,80.99) v2(117.36,65.6) v2(117.36,63.18) v2(117.36,60.83) v2(118,67.76) v2(118,66.8) v2(118,64.96) v2(118,64.07) v2(118,63.18) v2(118,62.23) v2(118,60.45) v2(118,58.74) v2(121.62,102.74) v2(121.6,101.33) v2(122.54,103.57) v2(122.56,101.82) v2(122.61,100.31) v2(123.4,104.72) v2(124.42,103.59) v2(124.35,101.81) v2(124.39,100.44) v2(124.43,98.99) v2(125.32,97.53) v2(126.28,100.42) v2(126.32,99.01) v2(126.72,96.09) v2(127.16,97.85) v2(128.14,94.67) v2(128.23,103.4) v2(128.23,101.81) v2(128.23,100.48) v2(128.16,96.67) v2(128.26,98.98) v2(129.62,103.4) v2(129.56,101.87) v2(129.62,100.48) v2(129.6,98.98) v2(129.56,96.67) v2(129.57,95.05) v2(129.9,92.87) v2(131.15,96.86) v2(131.2,99.94) v2(131.21,98.44) v2(131.24,91.59) v2(131.27,95.02) v2(131.97,93.49) v2(132.54,98.8) v2(132.54,96.86) v2(132.48,95.01) v2(132.56,90.35) v2(132.99,99.97) v2(133.07,101.44) v2(133.37,102.72) v2(133.5,97.81) v2(133.5,93.49) v2(133.56,103.97) v2(133.62,91.9) v2(133.69,95.08) v2(133.81,96.86) v2(134.13,98.82) v2(134.45,102.77) v2(134.45,101.43) v2(134.51,99.97) v2(135.02,103.9) v2(135.08,96.92) v2(135.53,102.89) v2(135.53,101.5) v2(135.53,99.97) v2(135.66,98.13) v2(136.1,95.9) v2(136.16,104.67) v2(136.16,95.01) v2(136.35,100.29) v2(136.35,91.15) v2(136.74,98.06) v2(137.24,99.34) v2(137.24,96.86) v2(137.31,95.97) v2(137.31,94) v2(137.75,104.67) v2(137.94,100.29) v2(138.26,91.39) v2(138.39,98.57) v2(138.39,93.93) v2(138.7,99.33) v2(138.89,96.29) v2(139.02,90.51) v2(139.66,97.62) v2(139.85,98.63) v2(140.48,96.28) v2(140.54,95.34) v2(140.48,90.51) v4(123.65,94.51)
+VCC_SA: length 24.1
  TOP w0.508: v2(147.4,56.09) 147.47,56.15 PC1060.1 PC1059.1 PC1058.1 ; EC2218.1 142.11,49.75 142.41,49.75 143.01,50.35 v2(143.01,50.59) ; v2(134.2,45.98) 134.2,45.64 133.69,45.13 RC159.1 ; EC2217.1 v2(145.94,54.04)
  BOTTOM w0.102: 118.22,50.83 UC1.K30 ; UC1.K30 118.52,50.52 ; UC1.K30 118.26,50.56 ; UC1.K23 118.52,47.47 ; UC1.K23 118.83,47.17 ; UC1.K23 118.22,47.17 ; UC1.K23 118.52,46.86 ; 118.68,46.71 UC1.J22 ; UC1.J22 119.29,46.71 ; UC1.J22 118.99,47.02 ; 118.52,49.61 UC1.K28 ; UC1.K28 118.83,49.91 ; UC1.K28 118.22,49.91 ; UC1.K28 118.52,50.22 ; 119.45,49.3 UC1.G27 119.15,49 ; 118.68,49.45 UC1.J27 ; UC1.J27 118.99,49.76 ; UC1.J27 119.29,49.45 ; UC1.J27 118.99,49.15 ; 119.15,48.08 UC1.G25 ; UC1.G25 119.72,47.82 ; UC1.G25 119.45,47.78 ; UC1.J23 118.99,47.93 ; UC1.J23 118.99,47.32 ; UC1.J23 118.68,47.63 ; UC1.J23 119.29,47.63 ; UC1.K25 118.26,47.82 ; UC1.K25 118.83,48.08 ; UC1.K25 118.52,47.78 ; UC1.K25 118.22,48.08 ; UC1.G23 119.72,47.44 ; UC1.G23 119.15,47.17 ; UC1.G23 119.45,47.47 ; 119.15,49.91 UC1.G28 119.45,49.61 ; 118.83,49 UC1.K27 ; UC1.K27 118.26,49.26 ; UC1.K27 118.52,49.3
  BOTTOM w0.203: UC1.G28 v2(119.71,49.45) UC1.G27
  vias: v2(108.69,47.93) v2(108.69,47.35) v2(110,48.33) v2(111.51,48.9) v2(112.72,48.9) v2(113.93,48.9) v2(115.13,48.9) v2(116.34,48.9) v2(116.92,48.85) v2(117.41,47.47) v2(118.03,47.49) v2(118.06,48.22) v2(147.85,59.39) v2(147.85,58.57) v2(147.85,57.74) v2(148.17,55.45) v2(148.48,56.91) v2(149.88,55.45) v2(150.07,56.91) v2(151.66,55.45) v2(151.91,56.91) v2(151.98,59.45) v2(151.98,58.69) v2(151.98,57.68) v4(118.96,48.41)
GND: length 2276.2
  TOP w0.102: v2(115.12,35.03) 114.95,35.03 v4(114.57,34.65) ; v4(218.27,12.02) 218.27,12.24 v2(217.85,12.66) ; v2(59.07,110.58) v4(59.07,111.33) ; v2(100.99,115.33) v4(101.75,115.33) ; v2(116.25,10.94) v4(117.11,10.94) ; v2(29.67,110.32) v4(29.67,111.08) ; v2(151.9,109.97) v4(150.68,109.97)
  TOP w0.203: v2(167.09,21.36) 167.09,21.36 167.09,21.35 167.38,21.64 UZ3.11 ; v2(106.17,54.97) 105.75,55.39 105.74,55.39 105.73,55.4 105.35,55.4 104.9,54.95 CC32.2
  TOP w0.254: JSSD1.1 198.85,14.86 v2(198.93,14.94) ; JDB1.2 119.24,7.54 118.89,7.19 118.32,7.19 v2(118.32,7.22) ; v2(133.69,5.9) 133.69,5.92 134.24,6.47 JDEG1.10 ; v2(216.17,51.71) 216.31,51.57 UX1.5 ; v2(188.68,40.4) 188.58,40.3 PQ720.3 ; JSSD1.13 192.85,15.42 v2(192.63,15.64) ; CC19.2 109.1,68.45 109.1,67.91 v2(109.14,67.87) ; JSSD1.4 v2(197.35,14.94) ; JSSD1.10 v2(194.35,15.74) ; v2(134.54,40.41) 134.31,40.18 UZ1.5 ; JSSD1.16 191.35,14.92 v2(191.6,15.17) ; JSSD1.21 188.85,14.96 188.96,15.07 v2(188.96,16.25) ; JSSD1.7 v2(195.85,15.8)
  TOP w0.305: v2(46.5,21.35) 46.41,21.27 46.06,21.27 45.74,20.95 CD39.2 ; v2(61,41.15) 61,41.3 60.7,41.6 RD6.2 ; v2(43.37,30.82) CD56.2 ; CD49.2 51.33,36.16 v2(51.19,36.3) ; v2(132.1,35.4) UZ2.5
  TOP w0.356: UC6.3 88.62,17.87 88.83,17.66 88.83,17.3 89.26,16.87 91.06,16.87 91.42,17.23 v2(91.42,17.46) ; PC1164.2 106.57,55.51 v2(106.24,55.83) ; CC61.2 108.11,43.7 v2(107.46,43.06) ; PC1085.2 107.47,53.05 PC1030.2 108.1,53.05
  TOP w0.381: RE53.1 151.44,23.95 152.3,23.08 UE2.3 ; v2(188.13,38.65) 188.13,37.42 187.75,37.04 187.75,36.99 PQ721.3 187.09,36.33 PC790.2 ; v2(185.88,21.74) 185.38,22.24 PQ1.1 ; v2(85.93,22.26) 85.33,22.26 84.81,21.74 UC5.3 ; v2(184.46,24.17) 183.83,23.54 PQ1.4 ; 108.1,53.05 108.5,53.05 v2(108.53,53.08) ; v2(116.83,42.65) 116.69,42.51 CC55.2 ; PQ2.1 178.65,23.57 178.26,23.95 v2(178.26,24.5) ; PQ2.4 180.62,22.27 180.24,21.89 180.24,21.35 PR33.1 ; CC14.2 86.94,17.87 UC6.3
  TOP w0.406: EU2601.3 v2(18.94,61.17) ; v2(131.59,78.12) 131.96,77.75 UC7.3 ; JDB1.11 119,5.37 v2(119.15,5.23) ; v2(129.37,5.73) 129.01,5.37 JDEG1.11 ; EU2603.3 v2(16.53,39.52) ; JDB1.12 123.53,4.66 v2(123.53,3.32) ; UC2.3 92.24,78.55 92.67,78.12 v2(93.75,78.12) ; v2(132.93,5.8) 133.45,5.28 134.41,5.28 134.51,5.37 JDEG1.12
  TOP w0.457: CC21.2 113.72,69.33 114.06,69.33 v2(114.12,69.27)
  TOP w0.508: CE31.2 RE16.2 153.82,26.69 153.53,26.4 v2(153.53,26.39) ; CC75.2 116.67,38.63 v2(116.14,38.63) ; v2(225.32,46.57) C3.2 C2.2 ; CC46.2 107.32,56.19 107.22,56.09 106.5,56.09 v2(106.24,55.83) ; CU21.2 v2(16.43,45.32) ; 86.95,31.5 86.88,31.43 86.73,31.43 86.44,31.14 RC58.2 ; 86.95,31.5 86.91,31.54 86.44,32 RC54.2 ; 86.95,31.5 v2(86.95,31.5) ; v2(214.45,48.37) CX2.1 CX13.2 ; CD50.2 53.43,79.59 v2(54.61,80.77) ; v2(157.82,54.82) 158.08,55.08 PR611.2 PR608.2 ; v2(90.72,27.12) 90.77,27.07 CC5.2 ; EC2902.2 v2(154.07,107.47) ; CC76.2 141.41,45.65 v2(141.63,45.87) ; v2(47.91,19.23) 47.91,19.31 47.52,19.7 RD17.2 ; v2(227.71,36.28) 227.88,36.1 R54.2 ; v2(136.1,36.42) 136.11,36.42 ; 136.11,36.42 CZ1.2 ; 136.11,36.42 136.26,36.42 136.72,35.96 CZ7.2 ; CC12.2 91.42,18.1 v2(91.42,17.46) ; v2(104.99,50.41) 105.2,50.62 CC45.2 ; v2(29.86,1.79) 29.87,1.79 CA29.2 ; v2(74.71,111.44) 74.26,111.88 PQ5.3 ; CD8.2 CD7.2 57.87,23.66 v2(57.79,23.74) ; CD51.2 46.51,63.08 v2(46.65,62.94) ; CC31.2 91.7,53.41 CC26.2 91.71,54.7 v2(91.59,54.82) ; v2(175.79,22.08) 175.95,22.24 EC2229.2 ; PR752.1 191.73,41.58 v2(191.97,41.82) ; v2(160.8,52.84) 160.36,53.29 PC604.2 ; v2(28.4,77.87) 28.01,77.87 CI9.2 ; CA27.2 CA30.2 30.39,4.99 30.12,4.72 v2(29.86,4.72) ; v2(92.77,49.69) 92.75,49.68 CC29.2 CC30.2 ; JPWR1.7 162.67,104.71 v2(163.68,105.72) ; v2(152.55,30) 152.85,29.7 CE29.2 ; CE5.2 155.85,21.93 155.71,22.07 CE22.2 155.12,22.01 v2(154.48,22.01) ; PR681.2 165.51,65.17 PR647.1 166.38,65.17 PC647.1 ; PC711.1 189.41,33.1 v2(189.2,33.32) ; PR29.2 177.59,25.62 PR32.2 v2(178.25,25.64) ; RW8.2 v2(53.05,106.58) ; v2(112.8,67.96) 112.87,67.89 CC24.2 CC22.2 ; 26.88,29.61 27.33,29.61 v2(27.71,29.23) ; v2(92.54,58.56) CC27.2 91.79,57.23 CC36.2 ; v2(43.31,24.46) 42.75,24.46 CD32.2 CD33.2 ; v2(147.66,18.75) 147.66,18.75 CE13.2 ; v2(225.88,47.33) 226.21,47 EC2212.2 ; CC17.2 115.72,70.37 v2(116,70.65) ; CC17.2 CC20.2 ; CC17.2 CC25.2 ; v2(133.37,44.34) 133.24,44.34 133.17,44.28 CC44.2 CC41.2 ; EC2216.2 196.72,27.25 v2(197.31,27.25) ; PC1072.2 139.15,66.71 v2(138.77,66.71) ; v2(166.64,32.85) 166.25,33.25 PC504.2 ; EC2226.2 164.05,18.14 v2(164.1,18.19) 164.61,18.69 CZ12.2 165.49,19.23 CZ11.2 CZ10.2 ; JSSD1.32 182.67,10.03 181.95,10.75 JSSD1.31 v2(181.95,14.37) ; CC10.2 82.75,18.77 v2(83.44,19.46) ; CC10.2 82.53,18.29 CC89.2 ; CC10.2 RC102.2 82.75,17.62 RC192.2 ; CC28.2 92.55,67.28 92.38,67.45 92.38,67.47 v2(92.18,67.67) ; v2(60.7,22.31) 60.21,21.82 CD5.2 ; PC1069.2 139.1,71.29 v2(138.74,71.29) ; PC125.2 v2(170.83,30.95) ; v2(92.38,73.39) 92.35,73.39 91.79,72.83 CC39.2 92.09,72.09 CC38.2 91.78,70.94 CC35.2 ; v2(88.29,33.29) 88.23,33.34 RC60.2 ; PC601.2 156.15,61.53 155.68,61.06 v2(155.68,60.79) ; CL8.2 36.23,116.05 v2(35.87,115.68) ; v2(33.64,115.68) 34.07,115.25 CL5.2 ; CD53.2 43.7,84.73 v2(43.58,84.85) ; EU2602.1 v2(16.53,57.36) ; PC1180.2 113.85,79.43 v2(113.85,79.2) ; v2(55.58,47.2) 55.58,47.52 55.4,47.69 CD43.2 ; v2(43.52,60.98) 44.01,60.48 CD42.2 ; CS14.2 CS13.2 193.52,49.49 v2(193.5,49.51) ; CZ8.2 132.18,24.71 v2(132.58,24.31) ; 156.53,16.67 156.74,16.87 CE17.2 ; 156.53,16.67 v2(156.53,16.68) ; 156.53,16.67 155.98,16.67 DE1.2 ; RD5.2 v2(65.35,18.87) ; v2(106.89,32.07) 106.62,31.8 CC56.2 106.77,30.79 CC51.2 CC52.2 ; CC83.2 132.8,46.56 132.73,46.5 RC160.2 v2(133.5,45.99) ; PD2.1 v2(215.75,12.65) ; v2(83.97,26.37) 83.97,26.37 RC110.2 ; v2(34.06,113.56) 34.56,114.06 CL7.2 ; v2(43.59,42.44) RD18.2 44.41,42.39 CD54.2 ; CA22.1 29.68,28.73 RA9.2 30.89,28.22 31.14,28.47 v2(31.14,28.48) ; v2(108.6,46.03) 108.72,45.92 CC62.2 ; v2(61.14,63.52) 61.14,63.52 CD29.2 ; v2(65.53,62) 65.98,61.54 CD13.2 ; CZ5.2 138.58,32.85 137.84,32.11 137.71,32.11 136.85,31.25 CZ4.2 135.79,30.76 v2(135.91,30.64) ; PC1060.2 v2(148.43,54.08) ; v2(155.43,57.7) 155.46,57.73 PR654.2 156.17,57.66 156.17,56.94 PC644.2 ; CE27.2 150.56,33.96 v2(150.52,34.01) ; RD12.2 57.6,44.16 RD11.2 56.86,44.39 v2(56.47,44.79) ; v2(150.16,18.36) 150.16,17.88 150.08,17.81 150.08,17.49 149.98,17.39 RE50.2 ; v2(135.56,67.71) 135.91,67.71 PC1004.2 ; v2(213.57,40.22) 213.82,39.97 RX31.1 ; CW4.2 CW3.2 v2(61.55,103.96) ; v2(43.58,74.38) 44.02,73.94 CD52.2 ; CC53.2 107.41,28.26 CC54.2 108.45,27.77 v2(108.54,27.68) ; v2(106.82,60.43) 107.09,60.15 CC50.2 ; v2(138.77,69.75) 139.16,69.75 PC1078.2 ; C4.2 224.56,52.85 v2(223.6,52.85) C5.2 ; CD35.2 CD36.2 53.55,21.62 v2(54.38,22.44) ; v2(112.74,36) 113.06,35.68 RC130.2 ; CD6.2 v2(57.87,17.64) ; CZ24.2 169.91,26.22 v2(169.64,26.49) ; v2(181.31,20.4) 182.8,20.4 183.34,20.94 PR10.1 PR2.2 ; v2(157.07,111.71) 157.66,112.31 JPWR1.6 ; v2(212.68,46.49) RX21.1 RX17.1 ; RA22.1 v2(7.39,8.76) ; v2(135.56,64.66) 135.91,64.66 PC1012.2 ; CD40.2 41.75,18.96 CA13.2 ; RD16.2 v2(50.31,18.94) ; RZ9.2 139.52,37.6 140.16,38.25 v2(140.16,38.69) ; RE19.2 150.52,25.23 v2(150.32,25.04) ; v2(33.8,21.3) 33.48,20.98 CA4.2 ; CA14.2 41.2,17.33 CA13.2 ; PR33.1 v2(180.49,20.25) ; CU8.2 v2(17.67,67.77) ; v2(222.71,51.26) 222.21,51.26 CX12.2 CX1.2 ; v2(214.46,46.49) RX25.1 RX23.1 ; CZ9.2 168.54,19.4 v2(168.55,19.39) ; CL12.2 29.55,110.2 v2(29.67,110.32) ; v2(165.12,17.55) 165.12,18.01 EC2215.2 ; v2(202.37,12.63) 202.37,12.22 202.12,11.98 JSSD1.35 201.25,10.81 200.46,10.03 JSSD1.34 JSSD1.33 ; v2(93.36,25.44) 93.21,25.59 CC4.2 ; v2(108.69,30.9) 108.85,30.75 CC85.2 ; EU2604.1 v2(18.09,34.78) ; PC647.1 PR680.2 ; PC647.1 166.57,65.16 167.09,65.68 v2(167.09,65.74) ; CC16.2 80.32,20.31 80.03,20.02 v2(79.2,20.02) ; CC11.2 82.38,23.49 v2(82.95,24.06) ; v2(221.72,29.28) 222.01,29.57 C16.2 ; CE18.2 v2(151.58,26.46) ; CD37.2 CD38.2 v2(51.8,18.18) ; CW6.2 59.33,109.37 59.07,109.62 v2(59.07,110.58) ; v2(169.76,56.34) 169.7,56.4 PR631.1 168.98,56.42 PC621.1 ; v2(106.94,75.39) 106.37,74.82 RC158.2 ; v2(179.81,25.21) 179.6,25 PQ3.3 ; RD4.2 v2(62.06,18.87) ; v2(129.69,31.84) 129.78,31.84 130.03,32.1 130.92,32.1 131.09,32.27 CZ6.2 ; RA18.1 v2(32.02,14.39) ; CL14.2 34.93,118.1 v2(34.75,117.92) ; v2(156.24,32.15) 156.37,32.02 CE9.2 ; CD2.2 70.7,22.63 v2(69.96,22.63) ; v2(141.61,25.62) 141.33,25.91 CE6.2 140.86,25.92 CE20.2 ; CE7.1 146.59,33.8 v2(146.59,34.01) ; RC136.1 120.88,74.92 v2(121.11,74.7) ; v2(135.56,66.19) 135.91,66.19 PC1071.2 ; v2(57.83,85.49) 58.63,84.69 CD23.2 ; CC43.2 92.53,64.37 v2(92.53,65.51) ; v2(133.69,72.09) 133.5,72.28 CC13.2 ; EC2217.2 v2(146.9,50.69) ; PC1059.2 v2(150.08,54.08) ; CC90.2 CC1.2 90.23,83.1 90,82.87 v2(90,82.57) ; v2(35.87,117.92) 35.97,117.82 CL6.2 ; EC2901.2 v2(154.1,109.4) ; PC651.1 v2(161.56,65.73) ; v2(87.17,32.83) 87.6,32.41 RC62.2 88.49,32.33 CC9.2 ; CD41.2 43.83,58.7 43.64,58.88 v2(43.26,58.88) ; CA25.1 v2(30.36,13.92) ; CC77.2 133.03,50.61 v2(132.62,50.61) ; v2(82.57,109.44) 82.46,109.33 PC230.2 ; v2(54.28,69.67) 54.02,69.93 54,69.93 53.74,70.19 CD55.2 ; PD5.2 v2(72.63,117.64) ; CE10.2 156.76,24.38 v2(157.37,23.77) ; v2(209.63,39.72) 209.75,39.6 RX12.1 RX19.1 ; v2(51.22,52.76) 51.38,52.6 CD44.2 ; RX15.1 v2(215.35,46.49) ; v2(110.23,34.98) 110.05,34.8 CC86.2 ; v2(211.92,40.22) 212.05,40.09 RX27.1 RX29.1 ; v2(91.07,62.57) 91.07,62.51 91.52,62.06 CC37.2 91.79,62.06 CC34.2 ; CZ2.2 131.66,39.18 v2(131.26,38.79) 131.26,38.59 CZ21.2 ; CD11.2 59.53,41.59 RD6.2 ; v2(72.47,115.84) 72.47,115.55 PD6.2 ; CD17.2 CD18.2 61.87,59.39 v2(61.98,59.51) ; CD15.2 CD16.2 61.08,57.3 v2(61.22,57.15) ; CE32.1 141.96,17.73 v2(141.33,17.73) ; v2(87.51,4.01) 87.94,4.44 Q13.3 ; CC82.2 131.23,47.56 v2(130.75,47.08) ; v2(83.19,108.45) 82.77,108.03 PC206.2 ; v2(115.32,79.2) 115.32,79.63 PC1182.2 ; CD21.2 58.36,30.56 v2(57.54,31.39) ; v2(138.77,68.23) 139.16,68.23 PC1081.2 ; RC151.2 131.65,58.31 v2(131.07,58.31) ; PR9.1 v2(74.07,114.72) ; v2(68.48,22.63) 68.1,22.25 CD10.2 66.71,21.75 CD9.2 ; EC2218.2 142.5,48.26 v4(143.82,49.58) v2(144.93,50.69) ; v2(29.86,8.97) 30.1,8.74 CA28.2 ; R40.2 C19.2 v2(103.07,10.85) ; CC42.2 120.4,47.71 v2(121.13,48.44) ; PD3.1 v2(217.85,12.66) ; CZ22.2 134.2,41.93 CZ3.2 133.76,41.93 v2(133.43,41.59) ; CE24.2 140.58,22.27 140.86,21.99 CE12.2 139.47,21.31 139.05,20.89 v2(139.04,20.89) ; v2(26.29,27.43) CA6.2 CA17.2 ; CC49.2 106.82,58.36 v2(106.22,57.77) ; CZ25.2 CZ23.2 v2(167.72,26.94) ; PC1174.2 135.91,69.23 v2(135.56,69.23) ; EC2225.2 v2(90.89,21.94) ; CC18.2 112.36,69.06 112.92,69.61 CC21.2 ; v2(54.28,53.55) 53.7,54.13 CD45.2 ; CS15.2 v2(199.09,49.93) ; CD48.2 54.14,58.44 v2(54.44,58.14) ; CA15.2 33.35,27.01 33.23,27.13 v2(32.79,27.13) 32.79,27.01 32.59,26.81 CA16.2 ; C30.2 181.06,51.77 v2(181.06,53.17) ; CA2.2 32.2,23.6 v2(31.96,23.83) ; CA13.2 v4(43.52,17.88) 43.75,17.88 v2(44.53,17.1) ; PD4.1 v2(65.17,111.65) ; CE28.2 144.15,33.91 v2(144.49,34.24) ; RA17.1 23.39,27.13 v2(23.77,27.51) ; EC2211.2 v2(225,41.46) ; CU18.2 CU19.2 18.66,42.56 19.17,42.06 v2(20.4,42.06) ; RI16.2 v2(34.02,71.53) ; v2(68.73,67.62) 68.7,67.59 CD22.2 ; CE26.2 153.64,17.1 CE11.2 152.94,17.68 153.15,17.89 v2(153.15,18.43) ; CE19.2 145.49,35.85 v2(145.82,36.18) ; v2(150.83,24.53) 151.35,24.01 RE53.1 ; PC622.2 v2(147.35,60.48) ; SW1.2 v2(151.9,109.97) ; CD47.2 53.69,56.8 v2(54.27,56.22) 53.71,55.65 CD46.2 ; CC72.2 116.85,34.18 CC87.2 115.94,34.18 115.12,35 v2(115.12,35.03) ; CU7.2 18.13,64.09 CU6.2 18.62,63.21 v2(18.82,63.01) ; CE15.2 148.8,33.68 v2(149.16,34.04) 149.69,33.51 CE8.1 ; QI1.3 v2(26.96,80.87) ; PC605.1 169.39,54.65 v2(169.63,54.88) ; v2(214.45,51.77) CX3.2 ; v2(116.42,68.01) 116.56,67.87 CC23.2 ; v2(164.71,114.47) 164.27,114.91 JPWR1.8 ; v2(74.38,22.12) CD1.2 ; CC33.2 104.92,58.46 v2(105.01,58.55) ; CU20.2 v2(20.57,45.32) ; v2(145.84,21.86) 145.64,21.66 RE32.2 ; PC685.2 v2(148.53,74.99) ; EC2302.2 v2(16.66,25.43) ; CD26.2 59.09,50.14 v2(59.17,50.14) ; v2(109.24,45.21) 109.77,45.21 CC57.2 ; CD24.2 68.54,24.38 v2(69.11,23.81) ; PC767.2 v2(211.38,32.22) ; PC112.2 v2(167.47,41.68) ; QC2.3 v2(89.38,20.31) ; RC164.2 v2(85.93,22.26) ; v2(69.23,22.63) CD4.2 CD3.2 ; CD28.2 59.52,46.32 CD19.2 57.99,47.14 v2(57.82,47.31) ; CC69.2 104.77,35.18 v2(104.93,35.02) ; CU10.2 v2(21.36,66.95) ; CW7.2 v2(59.89,110.58) ; EC2301.2 v2(13.73,9.22) ; CU9.2 19.45,67.26 v2(19.01,67.71) ; v2(43.14,23.64) CD34.2 43.19,22.9 CD31.2 ; ED2901.2 v2(154.08,108.42) ; v2(222.71,35.41) 223.18,34.94 C15.2 223.58,34.97 C14.2 ; R2.2 v2(38.56,5.05) ; v2(22.54,46.37) CU22.2 ; PQ711.3 v2(198.8,20.22) ; PC1058.2 v2(151.92,54.08) ; v2(68.57,35.82) 68.36,36.03 CD25.2 ; CA1.2 CA3.2 36.34,25.79 v2(35.81,26.32) ; RX3.2 v2(220.68,53.67) ; v2(44.98,108.84) CW9.2 43.39,108.84 CW8.2 ; v2(83.14,29.16) 82.61,29.7 RC94.1 ; CD14.2 67.15,51.52 CD12.2 67.15,51.24 v2(67.65,50.75) 67.94,50.46 CD20.2 ; CW5.2 v2(57.87,103.97) ; RA24.2 v2(17.53,25.43) ; CC8.2 v2(92.91,32.33) ; v2(37.73,8.79) 37.74,8.79 37.74,8.79 C1.2 ; PC654.1 v2(160.17,65.73)
  VCC w0.203: JLAN1.11 11.73,101.3 ; JLAN1.11 11.73,101.97 ; JLAN1.11 10.55,100.63 ; JLAN1.11 9.37,101.97 ; JLAN1.11 11.73,100.63 ; JLAN1.11 9.37,101.3 ; JLAN1.11 9.37,100.63 ; JLAN1.11 10.55,101.97 ; JUSB1.4 15.28,55.6 ; JUSB1.4 13.9,56.2 ; JUSB1.4 15.28,56.8 ; JUSB1.4 15.46,56.2 ; JUSB1.4 14.08,56.8 ; JUSB1.4 14.08,55.6 ; JUSB1.4 14.68,56.98 ; JUSB1.4 14.68,55.43 ; JHDMI1.5 10.91,84.96 ; JHDMI1.5 9.99,84.96 ; JHDMI1.5 9.99,84.04 ; JHDMI1.5 11.03,84.5 ; JHDMI1.5 10.91,84.04 ; JHDMI1.5 9.87,84.5 ; JUSB2.13 14.56,45.85 ; JUSB2.13 11.62,45.85 ; JUSB2.13 11.62,46.73 ; JUSB2.13 14.56,44.97 ; JUSB2.13 13.09,46.73 ; JUSB2.13 14.56,46.73 ; JUSB2.13 13.09,44.97 ; 11.54,83.46 JHDMI1.2 ; JHDMI1.2 12,82.42 ; JHDMI1.2 12.46,82.54 ; JHDMI1.2 11.42,83 ; JHDMI1.2 12.46,83.46 ; JHDMI1.2 12.58,83 ; JHDMI1.2 11.54,82.54 ; JHDMI1.11 10.91,87.96 ; JHDMI1.11 10.91,87.04 ; JHDMI1.11 9.87,87.5 ; JHDMI1.11 9.99,87.04 ; JHDMI1.11 9.99,87.96 ; JHDMI1.11 11.03,87.5 ; 50.27,133.7 H11.1 ; H11.1 52.3,135.73 ; H11.1 53.79,135.19 ; H11.1 50.81,132.21 ; H11.1 53.79,132.21 ; H11.1 52.3,131.67 ; H11.1 54.33,133.7 ; H11.1 50.81,135.19 ; JUSB1.7 13.18,60.48 ; JUSB1.7 13.78,59.1 ; JUSB1.7 13.96,59.7 ; JUSB1.7 13.78,60.3 ; JUSB1.7 13.18,58.92 ; H4.1 208.02,49.32 ; H4.1 205.18,49.32 ; H4.1 206.6,45.97 ; H4.1 208.53,47.9 ; H4.1 208.02,46.48 ; H4.1 205.18,46.48 ; H4.1 206.6,49.83 ; H4.1 204.67,47.9 ; 1.42,95.22 JHDMI1.23 ; JHDMI1.23 3.98,97.08 ; JHDMI1.23 3.98,96.15 ; JHDMI1.23 2.7,97.08 ; JHDMI1.23 1.42,97.08 ; JHDMI1.23 3.98,95.22 ; JHDMI1.23 1.42,96.15 ; JHDMI1.23 2.7,95.22 ; 11.54,86.46 JHDMI1.8 ; JHDMI1.8 12.58,86 ; JHDMI1.8 12.46,86.46 ; JHDMI1.8 12.46,85.54 ; JHDMI1.8 11.42,86 ; JHDMI1.8 11.54,85.54 ; 164.58,101.22 H21.1 ; H21.1 167.42,98.38 ; H21.1 166,101.73 ; H21.1 164.07,99.8 ; H21.1 166,97.87 ; H21.1 167.93,99.8 ; H21.1 164.58,98.38 ; H21.1 167.42,101.22 ; JLAN1.10 11.73,117.43 ; JLAN1.10 9.37,118.1 ; JLAN1.10 10.55,118.77 ; JLAN1.10 9.37,118.77 ; JLAN1.10 10.55,117.43 ; JLAN1.10 9.37,117.43 ; JLAN1.10 11.73,118.1 ; JLAN1.10 11.73,118.77 ; JHDMI1.21 5.23,76.92 ; JHDMI1.21 2.67,78.78 ; JHDMI1.21 2.67,76.92 ; JHDMI1.21 3.95,78.78 ; JHDMI1.21 2.67,77.85 ; JHDMI1.21 3.95,76.92 ; JHDMI1.21 5.23,78.78 ; JHDMI1.21 5.23,77.85 ; JUSB1.10 14.56,52.73 ; JUSB1.10 14.56,50.97 ; JUSB1.10 11.62,50.97 ; JUSB1.10 13.09,52.73 ; JUSB1.10 11.62,51.85 ; JUSB1.10 14.56,51.85 ; JUSB1.10 13.09,50.97 ; 12.15,93.32 JHDMI1.22 ; JHDMI1.22 13.43,95.18 ; JHDMI1.22 13.43,94.25 ; JHDMI1.22 10.87,95.18 ; JHDMI1.22 10.87,93.32 ; JHDMI1.22 13.43,93.32 ; JHDMI1.22 10.87,94.25 ; JHDMI1.22 12.15,95.18 ; 6.77,122.3 H2.1 ; H2.1 7.28,123.72 ; H2.1 10.63,122.3 ; H2.1 8.7,124.23 ; H2.1 8.7,120.37 ; H2.1 7.28,120.88 ; H2.1 10.12,123.72 ; H2.1 10.12,120.88 ; 9.87,90.5 JHDMI1.17 ; JHDMI1.17 10.91,90.04 ; JHDMI1.17 9.99,90.96 ; JHDMI1.17 11.03,90.5 ; JHDMI1.17 9.99,90.04 ; JHDMI1.17 10.91,90.96 ; JUSB1.13 14.56,66.67 ; JUSB1.13 14.56,68.43 ; JUSB1.13 11.62,67.55 ; JUSB1.13 13.09,66.67 ; JUSB1.13 11.62,68.43 ; JUSB1.13 13.09,68.43 ; JUSB1.13 14.56,67.55 ; 4.22,51.85 JUSB1.11 ; JUSB1.11 4.22,50.97 ; JUSB1.11 6.96,50.97 ; JUSB1.11 5.59,50.97 ; JUSB1.11 6.96,51.85 ; 4.22,46.73 JUSB2.12 ; JUSB2.12 6.96,45.85 ; JUSB2.12 5.59,46.73 ; JUSB2.12 4.22,45.85 ; JUSB2.12 6.96,46.73 ; 10.87,80.68 JHDMI1.20 ; JHDMI1.20 13.43,78.82 ; JHDMI1.20 13.43,79.75 ; JHDMI1.20 12.15,78.82 ; JHDMI1.20 10.87,78.82 ; JHDMI1.20 12.15,80.68 ; JHDMI1.20 13.43,80.68 ; JHDMI1.20 10.87,79.75 ; JUSB2.4 14.68,35.28 ; JUSB2.4 13.9,34.5 ; JUSB2.4 14.08,33.9 ; JUSB2.4 15.28,33.9 ; JUSB2.4 14.68,33.73 ; JUSB2.4 15.46,34.5 ; JUSB2.4 15.28,35.1 ; JUSB2.4 14.08,35.1 ; JLAN1.12 3.93,101.97 ; JLAN1.12 1.57,101.3 ; JLAN1.12 3.93,100.63 ; JLAN1.12 1.57,101.97 ; JLAN1.12 1.57,100.63 ; JLAN1.12 2.75,100.63 ; JLAN1.12 3.93,101.3 ; JLAN1.12 2.75,101.97 ; 97.71,82.87 HCPU1.1 ; HCPU1.1 97.71,88.03 ; HCPU1.1 97.71,85.45 ; HCPU1.1 100,82.87 ; HCPU1.1 102.29,88.03 ; HCPU1.1 102.29,85.45 ; HCPU1.1 100,88.03 ; HCPU1.1 102.29,82.87 ; JLAN1.9 3.93,118.77 ; JLAN1.9 3.93,118.1 ; JLAN1.9 1.57,118.1 ; JLAN1.9 2.75,117.43 ; JLAN1.9 3.93,117.43 ; JLAN1.9 1.57,117.43 ; JLAN1.9 1.57,118.77 ; JLAN1.9 2.75,118.77 ; JUSB2.7 13.18,38.78 ; JUSB2.7 13.78,37.4 ; JUSB2.7 13.96,38 ; JUSB2.7 13.18,37.22 ; JUSB2.7 13.78,38.6 ; 4.22,67.55 JUSB1.12 ; JUSB1.12 5.59,68.43 ; JUSB1.12 6.96,67.55 ; JUSB1.12 4.22,68.43 ; JUSB1.12 6.96,68.43
  VCC w0.254: 5,1.57 H12.1 ; H12.1 5,5.63 ; H12.1 3.27,5.63 ; H12.1 6.73,1.57 ; H12.1 3.27,1.57 ; H12.1 6.73,5.63 ; H12.1 6.73,3.6 ; H12.1 3.27,3.6 ; 16.98,5.72 H1.1 ; H1.1 18.4,2.37 ; H1.1 20.33,4.3 ; H1.1 18.4,6.23 ; H1.1 19.82,2.88 ; H1.1 16.47,4.3 ; H1.1 16.98,2.88 ; H1.1 19.82,5.72
  IN1 w0.508: v2(17.72,16.15) 17.62,16.05 v2(17.62,12.09) 17.62,11.96 14.87,9.22 v2(13.73,9.22)
  IN1 w1.016: JLAN1.10 9.8,118.1 8.88,119.02 8.38,119.02 7.74,119.15 7.15,119.4 4.05,119.4 JLAN1.9
  IN2 w0.127: v2(91.14,3.31) 91.51,2.94 92.05,2.94 92.56,3.45 95.56,3.45 96.15,2.86 110.49,2.86 111.65,4.02 121.69,4.02 124.16,6.5 124.16,10.27 129.03,15.13 v2(129.56,15.13) ; v2(129.94,15.58) 129.98,15.54 129.98,14.88 129.53,14.43 128.69,14.43 124.42,10.16 124.42,8.76 124.42,6.39 121.79,3.76 113.39,3.76 112.23,2.6 96.04,2.6 95.45,3.19 92.67,3.19 92.16,2.69 91.14,2.69 v2(90.51,3.32)
  GND w0.203: JLAN1.10 11.73,118.1 ; JLAN1.10 9.37,118.1 ; JLAN1.10 9.37,118.77 ; JLAN1.10 9.37,117.43 ; JLAN1.10 10.55,117.43 ; JLAN1.10 11.73,117.43 ; JLAN1.10 11.73,118.77 ; JLAN1.10 10.55,118.77 ; HCPU2.1 126.04,87.19 ; HCPU2.1 122.56,87.19 ; HCPU2.1 124.3,83.06 ; HCPU2.1 126.04,83.71 ; HCPU2.1 122.56,83.71 ; HCPU2.1 126.69,85.45 ; HCPU2.1 124.3,87.84 ; HCPU2.1 121.91,85.45 ; 10.87,78.82 JHDMI1.20 ; JHDMI1.20 13.43,78.82 ; JHDMI1.20 10.87,79.75 ; JHDMI1.20 13.43,80.68 ; JHDMI1.20 12.15,80.68 ; JHDMI1.20 10.87,80.68 ; JHDMI1.20 13.43,79.75 ; JHDMI1.20 12.15,78.82 ; 141.9,59.27 H5.1 ; H5.1 139.97,61.2 ; H5.1 141.9,63.13 ; H5.1 143.83,61.2 ; H5.1 143.32,62.62 ; H5.1 140.48,62.62 ; H5.1 140.48,59.78 ; H5.1 143.32,59.78 ; H11.1 53.79,132.21 ; H11.1 52.3,131.67 ; H11.1 52.3,135.73 ; H11.1 50.81,132.21 ; H11.1 54.33,133.7 ; H11.1 53.79,135.19 ; H11.1 50.27,133.7 ; H11.1 50.81,135.19 ; 3.95,76.92 JHDMI1.21 ; JHDMI1.21 3.95,78.78 ; JHDMI1.21 2.67,78.78 ; JHDMI1.21 5.23,77.85 ; JHDMI1.21 2.67,76.92 ; JHDMI1.21 2.67,77.85 ; JHDMI1.21 5.23,76.92 ; JHDMI1.21 5.23,78.78 ; 13.9,56.2 JUSB1.4 ; JUSB1.4 14.68,56.98 ; JUSB1.4 15.28,55.6 ; JUSB1.4 15.28,56.8 ; JUSB1.4 15.46,56.2 ; JUSB1.4 14.08,56.8 ; JUSB1.4 14.08,55.6 ; JUSB1.4 14.68,55.43 ; 1.57,101.97 JLAN1.12 ; JLAN1.12 3.93,100.63 ; JLAN1.12 2.75,101.97 ; JLAN1.12 1.57,100.63 ; JLAN1.12 3.93,101.97 ; JLAN1.12 1.57,101.3 ; JLAN1.12 3.93,101.3 ; JLAN1.12 2.75,100.63 ; JUSB1.11 6.96,50.97 ; JUSB1.11 5.59,50.97 ; JUSB1.11 6.96,51.85 ; JUSB1.11 4.22,51.85 ; JUSB1.11 4.22,50.97 ; 13.18,58.92 JUSB1.7 ; JUSB1.7 13.78,60.3 ; JUSB1.7 13.78,59.1 ; JUSB1.7 13.18,60.48 ; JUSB1.7 13.96,59.7 ; 11.62,51.85 JUSB1.10 ; JUSB1.10 13.09,50.97 ; JUSB1.10 14.56,51.85 ; JUSB1.10 13.09,52.73 ; JUSB1.10 14.56,50.97 ; JUSB1.10 14.56,52.73 ; JUSB1.10 11.62,50.97 ; H12.1 6.73,1.57 ; H12.1 6.73,3.6 ; H12.1 3.27,3.6 ; H12.1 3.27,5.63 ; H12.1 5,5.63 ; H12.1 3.27,1.57 ; H12.1 5,1.57 ; H12.1 6.73,5.63 ; 10.87,93.32 JHDMI1.22 ; JHDMI1.22 13.43,94.25 ; JHDMI1.22 12.15,95.18 ; JHDMI1.22 10.87,94.25 ; JHDMI1.22 13.43,95.18 ; JHDMI1.22 12.15,93.32 ; JHDMI1.22 10.87,95.18 ; JHDMI1.22 13.43,93.32 ; HCPU4.1 124.3,24.54 ; HCPU4.1 121.72,22.25 ; HCPU4.1 126.88,24.54 ; HCPU4.1 126.88,19.96 ; HCPU4.1 126.88,22.25 ; HCPU4.1 121.72,24.54 ; HCPU4.1 124.3,19.96 ; HCPU4.1 121.72,19.96 ; H3.1 143.32,4.88 ; H3.1 139.97,6.3 ; H3.1 140.48,4.88 ; H3.1 141.9,4.37 ; H3.1 143.83,6.3 ; H3.1 140.48,7.72 ; H3.1 143.32,7.72 ; H3.1 141.9,8.23 ; 7.28,120.88 H2.1 ; H2.1 10.63,122.3 ; H2.1 10.12,123.72 ; H2.1 10.12,120.88 ; H2.1 6.77,122.3 ; H2.1 7.28,123.72 ; H2.1 8.7,120.37 ; H2.1 8.7,124.23 ; H1.1 20.33,4.3 ; H1.1 16.47,4.3 ; H1.1 16.98,2.88 ; H1.1 18.4,2.37 ; H1.1 19.82,5.72 ; H1.1 16.98,5.72 ; H1.1 18.4,6.23 ; H1.1 19.82,2.88 ; JHDMI1.23 3.98,97.08 ; JHDMI1.23 3.98,95.22 ; JHDMI1.23 2.7,97.08 ; JHDMI1.23 2.7,95.22 ; JHDMI1.23 1.42,96.15 ; JHDMI1.23 3.98,96.15 ; JHDMI1.23 1.42,97.08 ; JHDMI1.23 1.42,95.22 ; 9.87,87.5 JHDMI1.11 ; JHDMI1.11 9.99,87.04 ; JHDMI1.11 10.91,87.96 ; JHDMI1.11 10.91,87.04 ; JHDMI1.11 11.03,87.5 ; JHDMI1.11 9.99,87.96 ; 97.71,85.45 HCPU1.1 ; HCPU1.1 102.29,82.87 ; HCPU1.1 100,82.87 ; HCPU1.1 97.71,82.87 ; HCPU1.1 102.29,85.45 ; HCPU1.1 97.71,88.03 ; HCPU1.1 100,88.03 ; HCPU1.1 102.29,88.03 ; JHDMI1.5 10.91,84.96 ; JHDMI1.5 9.87,84.5 ; JHDMI1.5 9.99,84.04 ; JHDMI1.5 9.99,84.96 ; JHDMI1.5 10.91,84.04 ; JHDMI1.5 11.03,84.5 ; JHDMI1.2 12.46,82.54 ; JHDMI1.2 11.42,83 ; JHDMI1.2 12.58,83 ; JHDMI1.2 12.46,83.46 ; JHDMI1.2 12,82.42 ; JHDMI1.2 11.54,82.54 ; JHDMI1.2 11.54,83.46 ; 205.18,46.48 H4.1 ; H4.1 205.18,49.32 ; H4.1 204.67,47.9 ; H4.1 206.6,49.83 ; H4.1 206.6,45.97 ; H4.1 208.02,46.48 ; H4.1 208.53,47.9 ; H4.1 208.02,49.32 ; 5.59,29.27 JUSB2.11 ; JUSB2.11 6.96,29.27 ; JUSB2.11 4.22,29.27 ; JUSB2.11 4.22,30.15 ; JUSB2.11 6.96,30.15 ; 9.99,90.04 JHDMI1.17 ; JHDMI1.17 10.91,90.96 ; JHDMI1.17 11.03,90.5 ; JHDMI1.17 9.99,90.96 ; JHDMI1.17 9.87,90.5 ; JHDMI1.17 10.91,90.04 ; JUSB2.10 14.56,30.15 ; JUSB2.10 11.62,29.27 ; JUSB2.10 14.56,29.27 ; JUSB2.10 11.62,30.15 ; JUSB2.10 13.09,29.27 ; JUSB2.10 13.09,31.03 ; JUSB2.10 14.56,31.03 ; 164.58,98.38 H21.1 ; H21.1 167.42,101.22 ; H21.1 166,97.87 ; H21.1 166,101.73 ; H21.1 167.93,99.8 ; H21.1 164.58,101.22 ; H21.1 164.07,99.8 ; H21.1 167.42,98.38 ; 11.54,85.54 JHDMI1.8 ; JHDMI1.8 12.58,86 ; JHDMI1.8 11.42,86 ; JHDMI1.8 12.46,86.46 ; JHDMI1.8 11.54,86.46 ; JHDMI1.8 12.46,85.54 ; JUSB1.13 13.09,68.43 ; JUSB1.13 11.62,68.43 ; JUSB1.13 14.56,68.43 ; JUSB1.13 11.62,67.55 ; JUSB1.13 13.09,66.67 ; JUSB1.13 14.56,66.67 ; JUSB1.13 14.56,67.55 ; 14.68,33.73 JUSB2.4 ; JUSB2.4 14.08,35.1 ; JUSB2.4 13.9,34.5 ; JUSB2.4 14.08,33.9 ; JUSB2.4 15.46,34.5 ; JUSB2.4 14.68,35.28 ; JUSB2.4 15.28,35.1 ; JUSB2.4 15.28,33.9 ; 11.62,45.85 JUSB2.13 ; JUSB2.13 14.56,44.97 ; JUSB2.13 13.09,44.97 ; JUSB2.13 14.56,45.85 ; JUSB2.13 14.56,46.73 ; JUSB2.13 13.09,46.73 ; JUSB2.13 11.62,46.73 ; JUSB1.12 6.96,68.43 ; JUSB1.12 4.22,67.55 ; JUSB1.12 5.59,68.43 ; JUSB1.12 6.96,67.55 ; JUSB1.12 4.22,68.43 ; JLAN1.9 2.75,118.77 ; JLAN1.9 2.75,117.43 ; JLAN1.9 1.57,118.77 ; JLAN1.9 3.93,117.43 ; JLAN1.9 3.93,118.77 ; JLAN1.9 1.57,117.43 ; JLAN1.9 3.93,118.1 ; JLAN1.9 1.57,118.1 ; 9.37,100.63 JLAN1.11 ; JLAN1.11 10.55,100.63 ; JLAN1.11 9.37,101.97 ; JLAN1.11 11.73,101.3 ; JLAN1.11 10.55,101.97 ; JLAN1.11 11.73,101.97 ; JLAN1.11 9.37,101.3 ; JLAN1.11 11.73,100.63 ; JUSB2.7 13.18,38.78 ; JUSB2.7 13.78,37.4 ; JUSB2.7 13.96,38 ; JUSB2.7 13.18,37.22 ; JUSB2.7 13.78,38.6 ; 100,19.96 HCPU3.1 ; HCPU3.1 97.71,22.25 ; HCPU3.1 101.67,23.92 ; HCPU3.1 102.29,22.25 ; HCPU3.1 100,24.54 ; HCPU3.1 98.33,23.92 ; HCPU3.1 101.67,20.58 ; HCPU3.1 98.33,20.58 ; JUSB2.12 6.96,45.85 ; JUSB2.12 5.59,46.73 ; JUSB2.12 6.96,46.73 ; JUSB2.12 4.22,45.85 ; JUSB2.12 4.22,46.73
  BOTTOM w0.076: 120.96,54.77 120.63,54.77 120.35,54.48 UC1.F37 ; v2(104.71,74.86) 104.65,74.79 UC1.AT71
  BOTTOM w0.089: v2(128.16,53.73) 127.45,53.02 125.05,53.02 123.67,51.63 122.04,51.63 121.83,51.85 121.83,52.11 120.98,52.95 120.72,52.95 v2(120.52,53.14) 120.52,53.14 120.52,53.15 UC1.F35 ; v2(119.77,54.03) 119.77,54.15 UC1.F37 ; 120.96,54.77 121.11,54.62 121.11,54.3 121.31,54.11 122.61,54.11 122.8,53.92 122.8,53.54 123.01,53.33 124.06,53.33 125.02,54.29
  BOTTOM w0.102: v2(181.31,20.4) v4(181.31,21.48) ; v2(222.71,51.26) v4(222.71,52.09) ; v2(13.73,9.22) v4(14.36,9.22) ; v2(87.52,112.79) v4(87.52,113.75) ; v2(37.73,8.79) v4(36.9,8.79) ; v2(39.9,115.72) v4(40.78,115.72)
  BOTTOM w0.127: v2(99.96,67.58) 100.42,67.58 100.56,67.43 101.13,67.43 UC1.BB60 ; 110.38,68.9 110.56,68.9 110.92,68.53 111.34,68.53 UC1.AD62 ; 95.09,100.82 v4(94.11,100.82)
  BOTTOM w0.152: v2(100.25,72.07) 100.52,72.07 UC1.BB67 ; v2(109.86,74.86) 109.66,74.66 UC1.AG71
  BOTTOM w0.178: UC1.AM71 106.99,73.85 106.99,74.12 106.99,74.72 106.95,74.76 106.95,74.93 106.95,74.94 106.95,75.38 v2(106.94,75.39) ; v2(99.82,52.68) 99.86,52.64 101.14,52.64 UC1.BB34 ; v2(100.3,57.64) 100.33,57.62 UC1.BB43 ; v2(100.21,47.63) 100.37,47.63 100.41,47.67 101.16,47.67 UC1.BB26
  BOTTOM w0.203: v2(141.61,25.62) 141.17,25.18 UE1.17 ; UC1.AW43 103.12,57.14 103.15,57.11 103.15,56.81 103.12,56.78 UC1.AW41 103.17,56.32 v2(103.63,55.86) 103.12,55.35 UC1.AW38 103.12,54.63 103.14,54.62 103.14,54.3 103.12,54.28 UC1.AW36 103.12,53.41 103.15,53.38 103.15,53.08 103.12,53.05 UC1.AW34 ; UC1.A67 123.66,71.75 123.99,72.08 v2(124.1,72.08) ; UC1.AW16 103.12,43 103.14,43.01 103.14,43.55 103.12,43.57 UC1.AW18 103.12,44.22 103.42,44.52 ; UC1.BB38 100.19,55.02 v2(100.15,54.98) ; v2(122.51,33) UC1.C1 ; v2(119.14,38.56) 119.14,38.62 UC1.G10 ; v2(157.37,23.77) 157.19,23.58 UE1.84 ; v2(100.03,69.8) 100.09,69.74 UC1.BB64 ; v2(100.42,36.58) 100.52,36.68 UC1.BB6 UC1.BA6 102.13,36.68 102.17,36.72 UC1.AW6 ; v2(108.66,60.08) 108.31,60.43 UC1.AL48 ; v2(101.13,32.21) 101.27,32.35 101.27,33.26 101.31,33.3 UC1.BA1 101.31,33.66 101.39,33.74 101.39,34.07 UC1.BA2 101.6,34.29 101.75,34.29 102.13,34.68 UC1.AY3 ; UC1.AW62 103.12,68.27 103.18,68.21 103.18,67.65 103.12,67.59 UC1.AW60 ; UC1.AW14 103.22,41.42 103.22,40.51 103.12,40.41 UC1.AW12 ; UC1.AW26 103.14,47.6 103.14,48.44 103.12,48.46 UC1.AW28 ; UC1.BB30 100.14,50.04 v2(100,49.91) ; PU200.14 87.19,104.52 v2(86.95,104.29) ; UC1.AT68 104.61,71.85 103.48,71.85 UC1.AV68 ; UC1.D48 UC1.D47 121.52,60.48 121.52,60.14 121.49,60.12 121.49,59.78 121.52,59.75 121.52,59.37 UC1.D45 UC1.D44 ; v2(153.15,18.43) 153.15,17.16 UE1.100 ; UC1.AW49 103.12,61.53 103.22,61.62 103.22,61.9 103.12,62 UC1.AW51 ; v2(86.44,108.92) 86.79,108.58 PU200.1 ; v2(149.16,34.04) UE1.51 ; UE1.64 154.36,33.9 v2(154.01,34.24) ; UC1.F38 v2(119.71,55.86) UC1.F40 ; v2(100.33,43.95) 100.33,43.95 100.33,43.95 100.36,43.95 100.36,43.94 UC1.BB18 UC1.BA18 ; UC1.AW21 103.19,45.19 103.19,45.94 103.12,46.01 UC1.AW23 ; UC1.AV1 103.33,32.1 v2(103.32,32.08) ; UC1.B14 122.43,41.27 122.09,41.27 121.62,41.34 UC1.D14 ; v2(119.26,74.71) UC1.H71 ; UC1.AP68 105.89,71.83 107.05,71.83 UC1.AM68 107.49,71.89 107.58,71.8 107.85,71.8 108.26,72.21 UC1.AK68 108.45,72.21 UC1.AH67 ; v2(106.26,66.84) UC1.AN58 ; UC1.AW32 103.12,51 103.23,50.89 103.23,50.24 UC1.AW30 ; UC1.AL58 v2(108.38,65.91) ; UE1.124 143.56,18.15 v2(143.34,18.37) ; UC1.F35 119.77,53.9 v2(119.77,54.03) ; UC1.AL55 v2(108.38,64.08) ; v2(105.6,66.82) UC1.AP58 ; UC1.AL52 v2(108.38,62.26) ; v2(100.08,64.73) 100.14,64.79 101.17,64.79 UC1.BB55 ; PU200.3 v2(87.59,109.02)
  BOTTOM w0.254: UC1.AF10 109.98,38.87 v2(109.72,38.61) ; UC1.V17 113.76,42.88 113.76,42.4 UC1.V16 113.88,42.31 114.16,42.03 114.29,42.03 v2(114.33,41.99) 114.35,41.99 114.67,41.66 UC1.T15 115.11,41.98 115.11,42.39 115.15,42.43 v2(115.15,42.63) ; UC1.V17 UC1.Y17 ; UC1.V17 UC1.V18 ; UC1.AT2 104.72,34.8 v2(104.93,35.02) 104.93,35.27 UC1.AT4 ; UC1.G55 119.45,64.65 v2(119.76,64.96) ; UC1.AT35 UC1.AR35 UC1.AP35 105.91,53.37 v2(106.2,53.08) ; UC1.BA71 101.2,74.27 100.84,74.27 v2(100.77,74.2) 100.82,74.15 100.82,73.73 UC1.BB70 ; v2(106.2,53.08) 106.56,52.72 UC1.AN33 ; v2(106.2,53.08) 106.56,53.44 UC1.AN35 ; UC1.AU10 103.96,39.05 v2(103.61,39.41) 103.29,39.1 UC1.AW10 ; UC1.AK68 108.33,72.45 v2(108.54,72.66) 108.33,72.87 UC1.AK69 ; UC1.AB16 v2(112.55,42.01) 112.18,41.73 UC1.AB15 ; UC1.AW10 UC1.BA10 ; UC1.AW10 103.12,38.83 v2(103.47,38.48) 103.12,38.13 UC1.AW8 ; UC1.N13 116.32,40.82 v2(116.03,40.53) 115.75,40.82 UC1.R13 ; UC1.AW53 103.17,63.65 103.17,64.38 103.12,64.42 UC1.AW55 103.12,65.2 103.2,65.28 103.2,65.62 103.12,65.7 UC1.AW57 ; UC1.AW53 UC1.BA53 ; UC1.AW53 103.27,63.46 103.27,63.09 103.17,62.99 103.17,62.44 UC1.AW51 ; v2(119.83,67.77) 119.45,67.39 UC1.G60 UC1.G58 ; UC1.F23 120.06,47.17 119.71,46.76 v2(119.71,46.71) ; 114.13,73.19 v2(114.12,73.19) ; 114.13,73.19 UC1.U69 v2(114.12,72.51) ; 114.13,73.19 114.31,73.37 114.31,73.37 114.46,73.51 UC1.U70 ; UC1.K22 118.58,46.31 119.4,46.31 UC1.G22 v2(119.71,46.71) ; UC1.E46 v2(120.98,60.43) 121.04,60.49 UC1.D47 ; UC1.G43 119.45,58.2 119.7,58.65 119.71,58.65 ; UC1.G43 118.99,57.68 UC1.J42 ; UC1.G43 119.45,58.01 v2(119.82,57.65) 120.1,57.36 UC1.F42 ; UC1.H15 v2(119.07,42.14) 118.21,42.14 UC1.K16 118.04,42.44 118.41,42.81 118.41,43.19 118.04,43.56 UC1.K18 118.2,43.61 118.2,43.61 118.7,43.61 UC1.H18 ; 119.71,58.65 v2(119.73,58.65) ; 119.71,58.65 119.45,58.92 UC1.G45 ; UC1.AN40 106.24,56.63 v2(106.24,56.67) 106.24,56.91 UC1.AN42 106.56,57.31 106.22,57.66 ; v2(116,70.65) UC1.N65 ; UC1.AP38 105.91,55.5 v2(106.24,55.83) 106.56,55.51 UC1.AN38 ; v2(108.63,54.94) UC1.AL38 ; v2(108.71,71.22) 109.09,71.51 UC1.AH67 ; UC1.B18 UC1.D18 121.32,43.82 121.22,43.92 v2(121.01,43.92) 120.88,43.78 120.88,43.63 UC1.E18 ; UC1.J13 118.15,40.48 117.99,40.32 v2(117.99,40.31) 118.15,40.15 UC1.J11 118.15,39.85 117.8,39.85 117.79,39.86 117.5,39.57 UC1.L11 ; UC1.AR28 105.26,50.14 v2(104.99,50.41) 104.61,50.03 UC1.AT28 UC1.AR28 ; UC1.AR28 105.34,49.99 105.84,49.99 UC1.AP28 UC1.AN28 106.56,49.77 106.88,49.45 ; v2(115.15,42.63) 115.48,42.96 UC1.P17 ; v2(115.15,42.63) 115.08,42.63 114.74,42.96 UC1.T17 114.46,43.19 114.46,43.38 UC1.T18 UC1.V18 ; v2(148.92,105.42) PU604.10 ; v2(103.53,52.14) 103.92,51.74 UC1.AU32 ; v2(103.53,52.14) 103.12,51.74 UC1.AW32 102.57,51.36 ; v2(103.53,52.14) 103.12,52.54 UC1.AW34 ; UC1.J28 119.73,50.37 v2(119.78,50.42) 119.97,50.23 119.97,50.04 UC1.F28 ; UC1.AL2 107.08,34.8 107.08,35.2 UC1.AL4 107.37,35.61 v2(107.65,35.9) 108.03,35.52 UC1.AJ4 ; UC1.F1 UC1.F2 120.55,34.59 v2(120.55,35) 120.55,35.41 UC1.F4 ; UC1.D44 v2(121.99,58.68) UC1.B44 ; UC1.A5 123.91,35.37 v2(123.91,34.88) ; v2(215.73,41.17) 215.6,41.29 UX2.21 ; UC1.AW30 103.12,49.72 103.17,49.68 103.17,49.27 103.12,49.23 UC1.AW28 v2(102.63,48.86) UC1.BA28 ; UC1.AP70 v2(105.83,72.46) UC1.AP68 105.45,71.89 105.39,71.82 105.1,71.82 105.04,71.89 UC1.AT68 ; v2(116.14,38.63) 116.33,38.63 UC1.N10 ; 102.57,51.36 v2(102.55,51.39) 102.53,51.36 ; 102.57,51.36 102.53,51.36 ; v2(159.3,84.13) PU603.10 ; UC1.W6 113.13,36.26 112.87,36 v2(112.74,36) 112.67,35.93 UC1.AA4 UC1.AA2 ; UC1.AH64 109.26,69.61 v2(109.57,69.31) 109.44,69.31 UC1.AH63 109.05,68.92 108.23,68.92 UC1.AK63 107.95,68.73 107.74,68.73 UC1.AM61 ; UC1.AW41 102.63,56.32 v2(102.5,56.19) 102.36,56.32 UC1.BA41 ; UC1.AD13 111.12,40.82 v2(110.76,40.53) ; UC1.T2 115.12,34.71 v2(115.12,35.03) 115.32,35.23 UC1.T4 115.08,35.73 v2(115.08,35.96) 115.39,36.26 UC1.R6 UC1.N6 ; v2(102.43,66.09) UC1.BA57 ; UC1.F22 120.08,46.25 119.71,46.68 v2(119.71,46.71) ; v2(108.63,48.68) 108.47,48.68 UC1.AK27 UC1.AM27 ; v2(118.35,54.02) 118.35,54.03 UC1.J35 119.77,54.03 v2(119.77,54.03) ; 106.22,57.66 v2(106.22,57.77) ; 106.22,57.66 106.22,57.53 UC1.AP42 105.91,57.23 105.78,57.36 105.78,57.6 v2(105.6,57.78) ; UC1.AT23 104.69,47.24 105.19,47.24 UC1.AR23 UC1.AP23 UC1.AN23 106.56,47.31 v2(106.88,47.63) 106.88,47.75 UC1.AM25 UC1.AM27 ; UC1.AR8 105.26,38.14 v2(104.9,38.5) ; PU102.18 175.93,32.6 v2(175.91,32.61) ; UC1.E56 120.8,65.46 121.05,65.71 121.05,65.86 ; UC1.AR15 104.9,42.05 v2(104.9,42.14) 104.9,42.23 UC1.AR16 104.95,42.91 v2(104.95,42.97) ; UC1.V18 113.84,43.61 113.01,44.26 UC1.Y19 112.94,44.26 v2(112.57,44.64) ; UC1.AW14 v2(102.41,41.52) UC1.BA14 ; UC1.AM55 107.21,64.61 107.08,64.75 107.08,64.85 v2(106.95,64.98) ; v2(121.11,74.7) 121.11,74.21 UC1.E71 ; v2(118.14,52.33) 118.27,52.2 UC1.J32 119.69,52.2 119.77,52.28 ; v2(112.37,71.92) UC1.AA68 ; 127.24,55.22 126.79,55.22 125.86,54.29 125.02,54.29 ; UC1.D34 v2(121.99,53.73) UC1.B34 ; UC1.AW45 v2(102.61,58.8) UC1.BA45 ; UC1.AW45 103.12,59.22 103.17,59.26 103.17,59.56 103.12,59.61 UC1.AW47 103.12,60.38 103.17,60.42 103.17,60.73 103.12,60.77 UC1.AW49 ; UC1.AW45 103.12,58.36 103.17,58.31 103.17,57.94 103.12,57.9 UC1.AW43 ; UC1.AK11 107.63,38.99 v2(107.63,38.36) 107.55,38.36 UC1.AM8 ; UC1.D30 122.01,51.25 v2(122.02,51.25) 122.02,51.25 UC1.B30 ; v2(119.72,61.36) 119.72,61.15 UC1.G48 ; UC1.N21 116.4,45.56 v2(116.72,45.24) 117.05,44.91 UC1.L20 ; 102.39,46.38 UC1.BA23 ; 102.39,46.38 v2(102.39,46.39) ; 102.39,46.38 UC1.AW23 103.12,46.84 103.2,46.92 103.2,47.19 103.12,47.27 UC1.AW26 ; UC1.AM27 107.21,49.12 106.88,49.45 ; v2(108.6,46.03) 108.38,46.25 UC1.AK22 108.12,46.22 108.12,45.7 UC1.AK21 ; UC1.T21 114.44,45.81 v2(114.27,45.81) ; UC1.AM13 107.21,41.16 107.59,41.54 107.59,42 v2(107.44,42.15) 107.61,42.31 UC1.AK16 107.98,42.44 107.61,42.81 107.61,42.82 107.46,42.97 v2(107.46,43.06) 107.98,43.58 UC1.AK18 ; 121.1,64.08 120.91,63.68 UC1.E53 ; 121.1,64.08 121.1,64.08 121.1,64.08 121.48,63.7 UC1.D53 UC1.B53 ; 121.1,64.08 v2(121.09,64.08) ; v2(106.25,43.97) 105.91,43.63 UC1.AP18 ; UC1.AF15 110.37,41.66 v2(110.04,42) 109.97,42 UC1.AG16 ; v2(103.1,74.79) 103.26,74.63 UC1.AV71 UC1.AV70 UC1.AV69 103.26,72.36 v2(103.17,72.27) 103.17,72.16 UC1.AV68 ; UC1.AY71 101.96,74.35 101.28,75.03 101.22,75.03 v2(101.01,75.24) ; v2(108.62,36.76) 109.09,36.29 UC1.AH6 ; UC1.U10 114.04,38.87 v2(113.75,39.16) ; UC1.D14 121.48,41.14 121.12,40.78 121.12,40.61 121.11,40.61 121.11,40.39 121.05,40.32 v2(121.05,40.31) 121.05,40.15 UC1.E11 121.21,39.85 UC1.D11 121.52,38.9 UC1.D10 UC1.B10 ; UC1.AB8 112.01,37.56 v2(111.78,37.79) 111.45,37.79 UC1.AD8 ; v2(112.39,70.57) UC1.AA65 ; UC1.W13 113.36,40.79 v2(112.84,40.27) ; v2(119.86,71.68) 119.52,71.34 UC1.G66 ; UC1.U63 v2(114.12,69.27) UC1.U64 ; UC1.AT42 UC1.AR42 105.26,57.44 v2(105.6,57.78) ; UC1.BA36 v2(102.48,53.84) UC1.AW36 ; v2(121.21,72.95) 121.21,72.49 UC1.D69 UC1.F68 ; v2(119.8,37.49) 119.82,37.49 119.82,37.47 119.81,37.47 119.81,37.47 UC1.G6 119.54,37.03 119.54,36.28 UC1.G5 ; UC1.AK8 v2(107.64,37.56) ; UC1.D25 v2(121.13,48.44) 121.1,48.47 120.63,48.47 UC1.F27 119.64,48.54 UC1.J25 118.93,48.6 118.38,48.6 118.15,48.83 v2(117.97,48.83) ; UC1.AM43 107.23,58.14 UC1.AL45 107.67,58.6 UC1.AM45 107.21,59.09 v2(106.81,59.49) 107.21,59.89 UC1.AM46 v2(106.82,60.43) ; v2(103.63,55.86) UC1.AU38 ; 102.53,51.36 UC1.BA32 ; UC1.D6 121.65,36.57 v2(122.01,36.57) 122.01,35.96 UC1.C5 ; UC1.L8 v2(117.99,37.56) 118.15,37.73 UC1.J8 ; v2(113.94,38.1) 113.83,38.21 UC1.W9 ; UC1.E6 120.48,37.38 120.48,37.49 v2(120.46,37.49) 120.1,37.85 UC1.F8 ; UC1.E15 120.42,41.35 v2(120.42,41.29) 120.1,40.98 UC1.F13 ; UC1.B39 122.22,55.93 v2(121.88,55.93) 121.76,55.93 UC1.D39 ; UC1.A70 UC1.B71 123.01,74.16 123.41,74.56 v2(123.53,74.56) ; v2(117.85,69.3) 118.16,68.98 UC1.K63 118.52,68.67 UC1.K61 ; UC1.AT58 v2(104.9,66.83) UC1.AR58 ; 121.05,65.86 121.31,66.12 UC1.D58 UC1.B58 ; 121.05,65.86 v2(121.05,65.87) ; v2(118.35,55.86) UC1.J38 v2(119.71,55.86) ; v2(106.17,54.97) 106.56,54.51 UC1.AN37 v2(106.25,53.94) ; v2(97.57,62.9) 97.57,62.26 98.75,61.08 100.49,61.08 100.56,61.15 101.76,61.15 UC1.BA49 ; v2(120.52,53.14) 120.52,53.07 UC1.F33 120.1,52.61 119.77,52.28 ; 119.77,52.28 120.1,51.95 UC1.F32 ; UC1.P20 115.59,44.91 v2(115.95,45.26) 115.65,45.56 UC1.P21 ; PU300.18 148.12,42.65 148.04,42.57 v2(147.97,42.57) ; UC1.BA66 UC1.AY66 v2(103.03,71.43) UC1.AW66 103.19,70.88 103.19,69.91 UC1.AW64 103.17,69.8 103.17,69.03 103.12,68.98 UC1.AW62 v2(102.59,68.57) UC1.BA62 ; UC1.E21 121.03,45.61 121.03,45.84 UC1.D22 121.7,46.51 v2(121.92,46.51) 122.28,46.51 UC1.B22 ; UC1.N19 116.31,44.26 v2(115.99,43.95) 115.68,44.26 UC1.P19 ; v2(121.02,68.72) 121.14,68.6 UC1.D62 UC1.B62 ; UC1.AM60 107.21,67.4 v2(106.88,67.74) 107.21,68.07 UC1.AM61 ; UC1.AF1 110.08,33.92 110.08,34.45 UC1.AF2 110.23,34.72 v2(110.23,34.98) 110.02,35.19 UC1.AF4 ; v2(217.83,44.85) DX1.3 DX1.8 v2(217.83,47.77) 217.79,47.81 J3D1.4 ; UC1.AM21 106.76,44.88 v2(106.25,44.88) ; UC1.BA18 UC1.AW18 ; UC1.K70 UC1.K71 117.75,74 117.75,74.37 117.56,74.55 v2(117.56,74.68) ; UC1.AL35 108.5,53.11 v2(108.53,53.08) ; v2(106.88,68.65) 107.21,68.31 UC1.AM61 ; UC1.AW57 103.12,66.25 103.26,66.38 103.26,67.15 UC1.AW60 ; UC1.AW57 103.49,66.09 v2(103.63,65.95) ; PU606.4 152.48,71.16 v2(152.64,71) ; v2(119.72,63.13) 119.72,62.98 UC1.G52 ; UC1.D48 UC1.B48 ; PU100.18 173.28,42.6 v2(173.12,42.44) ; UC1.C25 v2(121.88,48.48) UC1.D26 ; v2(105.6,57.78) 105.52,57.78 105.26,58.03 UC1.AR43 105.26,58.18 105.01,58.43 v2(105.01,58.55) 105.01,58.71 105.27,58.99 UC1.AR45 104.98,59.37 v2(104.98,59.45) 104.98,59.69 UC1.AR46 104.93,60.3 v2(104.93,60.42) 104.93,60.55 105.26,60.88 UC1.AR48 105.26,60.88 104.95,61.19 v2(104.95,61.32) 104.95,61.49 UC1.AR50 105,62.06 v2(105,62.22) 105,62.36 105.26,62.62 UC1.AR52 104.9,63.08 v2(104.9,63.16) 104.9,63.27 UC1.AR53 104.96,63.93 v2(104.96,64.1) 104.96,64.24 UC1.AR55 105.27,64.57 104.91,64.92 v2(104.91,64.95) 104.9,64.95 104.6,65.4 UC1.AT56 ; v2(111.39,73.19) 111.06,72.86 UC1.AE69 UC1.AE68 UC1.AE67 UC1.AE66 UC1.AE65 ; UC1.AP32 v2(105.54,52.2) ; UC1.AR11 105.26,39.81 v2(105.68,39.4) 105.91,39.16 UC1.AP10 ; v2(108.63,49.28) 108.45,49.45 UC1.AL28 106.88,49.45 ; PU605.10 v2(151.91,95.73) ; UC1.L4 118.05,35.41 v2(118.05,35) 118.05,34.59 UC1.L2 ; UC1.AU15 103.96,41.79 v2(104.31,42.14) ; v2(109.78,40.46) 109.45,40.46 UC1.AH13 109.09,41.38 UC1.AJ15 ; UC1.AR5 105.38,36.2 105.81,36.62 v2(106.14,36.62) ; UC1.G63 119.52,69.62 v2(119.54,69.65) ; v2(114.12,70.6) UC1.U66 ; v2(209.89,41.23) 209.95,41.29 UX2.10 ; v2(116,71.89) UC1.N68 ; UC1.Y20 113.18,44.91 v2(113.43,45.17) 113.4,45.17 UC1.Y21 112.85,45.72 112.32,45.72 UC1.AB21 UC1.AD21 111.37,45.52 111.37,44.95 UC1.AD20 UC1.AD19 111.98,43.61 UC1.AB18 111.76,43.2 111.76,42.74 UC1.AD16 111.24,42.31 v2(110.91,42.64) 110.81,42.64 UC1.AF17 110.17,43.29 109.98,43.29 UC1.AG18 ; UC1.L16 117.17,42.31 v2(116.83,42.65) 117.14,42.96 UC1.L17 UC1.L18 ; v2(114.12,71.24) UC1.U67 ; PU1200.11 v2(97.43,111.5) ; UC1.B66 UC1.D66 121.1,70.7 v2(121.1,70.67) 121.1,70.47 UC1.E65 ; UC1.AN30 106.56,50.85 106.24,51.17 v2(106.24,51.27) 106.24,51.42 UC1.AN32 106.23,52.07 v2(106.23,52.29) ; v2(121.07,62.27) 121.07,62.12 UC1.E50 ; UC1.AL32 v2(108.33,51.28) ; UC1.AE64 110.97,69.6 v2(111.39,69.87)
  BOTTOM w0.305: v2(68.48,22.63) 68.12,22.63 68.12,22.63 JDIMM1.251 ; JDIMM2.61 54.15,72.62 54.77,73.25 54.77,73.91 v2(54.7,73.99) 54.62,73.99 54.26,73.62 JDIMM2.57 ; JDIMM1.9 68.19,85.13 68.49,85.43 v2(68.49,85.62) 68.49,85.82 68.19,86.13 JDIMM1.5 ; JDIMM1.93 68.2,64.13 v2(68.43,63.9) 68.43,63.86 68.41,63.84 68.41,62.93 68.1,62.62 JDIMM1.99 ; JDIMM2.44 43.91,76.87 43.61,76.57 v2(43.61,76.47) 43.61,76.28 44.02,75.87 JDIMM2.48 ; 68.79,83.08 68.33,82.62 JDIMM1.19 ; 68.79,83.08 v2(68.78,83.08) ; 68.79,83.08 68.79,83.23 68.39,83.62 JDIMM1.15 ; JDIMM1.189 68.32,38.13 68.8,38.6 v2(68.8,39.11) 68.78,39.13 JDIMM1.185 ; 68.98,42.63 68.98,43.29 68.64,43.63 JDIMM1.167 ; 68.98,42.63 67.25,42.63 JDIMM1.171 ; 68.98,42.63 v2(68.98,42.6) ; JDIMM1.10 57.38,84.88 v2(57.3,84.79) 57.3,84.47 57.89,83.88 JDIMM1.14 ; JDIMM2.47 53.9,76.13 54.44,75.58 v2(54.44,75.37) 54.2,75.13 JDIMM2.51 ; JDIMM2.5 53.92,86.62 54.24,86.94 54.24,87.38 v2(54.23,87.39) 54,87.62 JDIMM2.1 ; JDIMM2.180 43.92,40.87 43.64,40.59 v2(43.64,40.53) 43.64,40.25 44.02,39.87 JDIMM2.184 ; JDIMM1.26 58.18,80.88 57.82,81.24 v2(57.82,81.39) ; JDIMM1.239 68.41,25.63 v2(68.98,26.2) 68.98,26.24 68.6,26.63 JDIMM1.235 ; JDIMM2.30 43.94,80.37 43.62,80.69 v2(43.62,80.92) 43.62,81.02 43.98,81.37 JDIMM2.26 ; JDIMM1.90 57.24,64.88 v2(57.13,64.98) 57.14,64.98 57.14,65.26 57.75,65.88 JDIMM1.86 ; JDIMM1.52 57.7,74.38 v2(57.57,74.51) 57.55,74.53 57.55,74.88 58.04,75.38 JDIMM1.48 ; JDIMM1.18 57.98,82.88 57.68,82.57 57.68,81.53 v2(57.82,81.39) ; JDIMM1.243 68.63,24.63 69.04,24.21 69.04,23.87 v2(69.11,23.81) 69,23.7 68.92,23.7 68.84,23.63 JDIMM1.247 ; JDIMM2.2 43.89,87.37 43.58,87.07 v2(43.58,86.82) 43.58,86.68 43.89,86.37 JDIMM2.6 ; JDIMM1.209 68.21,33.13 v2(68.86,33.77) 68.86,33.77 68.86,33.82 68.55,34.13 JDIMM1.205 ; JDIMM2.27 54.31,81.13 54.61,80.82 v2(54.61,80.77) 54.61,80.55 54.18,80.13 JDIMM2.31 ; JDIMM2.94 v2(43.62,64.38) ; JDIMM2.19 54.46,83.13 54.9,82.68 v2(54.9,82.31) 54.72,82.13 JDIMM2.23 ; JDIMM1.107 68.5,60.62 69.06,61.18 69.06,61.87 v2(68.93,62) 68.93,61.93 68.63,61.62 JDIMM1.103 ; v2(54.51,41.61) 54.51,41.73 54.12,42.12 JDIMM2.175 ; JWLAN1.31 v2(52.55,99.01) ; JWLAN1.25 v2(51.05,98.95) ; JDIMM2.40 43.94,77.87 43.63,78.18 v2(43.63,78.26) 43.63,78.57 43.94,78.87 JDIMM2.36 ; JDIMM2.223 53.95,30.12 54.25,29.82 v2(54.25,29.39) 53.99,29.12 JDIMM2.227 ; JDIMM1.238 57.77,25.87 v2(57.53,26.11) 57.53,26.47 57.93,26.87 JDIMM1.234 ; JEDP1.38 v2(225.1,31.55) ; JDIMM2.244 43.71,24.87 43.31,24.48 v2(43.31,24.46) 43.89,23.87 JDIMM2.248 ; 57.55,31.37 58.05,30.87 JDIMM1.218 ; 57.55,31.37 v2(57.54,31.39) ; 57.55,31.37 57.55,30.18 57.86,29.87 JDIMM1.222 ; JWLAN1.1 v2(43.05,99.04) ; v2(55.01,78.58) 55.01,78.63 54.52,79.13 JDIMM2.35 ; JDIMM1.65 68.28,71.13 v2(68.55,70.86) 68.55,70.45 68.22,70.13 JDIMM1.69 ; JDIMM1.81 68.42,67.13 68.73,67.43 v2(68.73,67.62) ; JDIMM1.43 68.3,76.62 v2(68.86,76.07) 68.42,75.62 JDIMM1.47 ; JDIMM2.218 43.87,31.38 v2(43.35,31.9) 43.83,32.38 JDIMM2.214 ; JWLAN1.55 v2(58.55,101.41) ; v2(65.42,79.02) 65.8,79.02 66.19,78.62 JDIMM1.35 ; JDIMM1.227 68.18,28.63 68.3,28.75 v2(68.47,28.75) 68.47,27.93 68.16,27.63 JDIMM1.231 ; JDIMM2.247 53.88,24.12 v2(54.61,24.85) 54.34,25.12 JDIMM2.243 ; JDIMM2.197 51.52,36.63 v2(51.19,36.3) 51.86,35.63 JDIMM2.201 ; v2(60.7,22.31) 60.63,22.38 JDIMM1.252 ; JDIMM2.73 54.23,69.62 v2(54.28,69.67) ; v2(222.49,34.19) 222.63,34.05 JEDP1.33 ; JDIMM2.89 51.75,65.62 v2(51.22,65.1) ; JDIMM2.213 54.03,32.63 54.37,32.28 v2(54.37,31.91) 54.09,31.63 JDIMM2.217 ; JDIMM2.206 43.81,34.38 v2(43.37,33.93) 43.37,33.71 43.7,33.38 JDIMM2.210 ; JDIMM2.103 54.2,62.13 54.5,61.82 v2(54.5,61.63) 54.5,61.43 54.2,61.13 JDIMM2.107 ; JHDD1.4 197.65,17.84 v2(197.45,18.04) ; v2(54.38,22.44) 54.38,22.82 54.07,23.12 JDIMM2.251 ; v2(43.14,23.64) 43.15,23.62 43.16,23.62 43.9,22.87 JDIMM2.252 ; JDIMM1.72 57.86,69.38 57.55,69.68 v2(57.55,70.15) 57.78,70.38 JDIMM1.68 ; JDIMM2.22 43.93,82.37 43.62,82.68 v2(43.62,82.95) 43.62,83.07 43.93,83.37 JDIMM2.18 ; JDIMM1.56 57.98,73.38 v2(57.54,72.93) 57.54,72.73 57.9,72.38 JDIMM1.60 ; JDIMM2.65 54.03,71.62 54.33,71.32 v2(54.33,71.27) 54.33,70.93 54.03,70.62 JDIMM2.69 ; JDIMM2.86 43.89,66.38 v2(43.66,66.15) 43.66,65.68 43.96,65.38 JDIMM2.90 ; JWLAN1.37 54.05,101.18 v2(53.93,101.3) ; v2(43.59,42.44) 43.59,42.23 43.95,41.87 JDIMM2.176 ; JDIMM1.202 58,34.87 57.57,35.3 v2(57.57,35.53) 57.57,36.04 57.9,36.38 JDIMM1.196 ; JDIMM2.81 54.16,67.62 v2(54.62,67.17) 54.08,66.62 JDIMM2.85 ; JDIMM1.197 68.13,36.13 68.6,36.59 68.6,37.09 v2(68.62,37.11) 68.61,37.13 JDIMM1.193 ; JDIMM1.44 57.48,76.38 v2(57.28,76.57) 57.28,76.9 57.76,77.38 JDIMM1.40 ; JDIMM1.106 57.87,60.88 v2(57.49,61.25) 58.11,61.88 JDIMM1.102 ; JDIMM2.226 43.93,29.38 43.37,29.94 v2(43.37,29.99) 43.75,30.38 JDIMM2.222 ; JDIMM2.188 43.76,38.87 43.45,38.57 v2(43.45,38.37) 43.45,38.18 43.76,37.87 JDIMM2.192 ; JDIMM1.64 57.76,71.38 v2(57.5,71.63) ; JDIMM1.39 68.36,77.62 68.79,78.06 68.79,78.88 v2(68.7,78.97) 68.7,79.1 68.18,79.62 JDIMM1.31 ; v2(43.45,85.81) 43.89,85.37 JDIMM2.10 ; JDIMM1.192 58.03,37.38 57.72,37.68 v2(57.72,37.83) 57.72,37.88 58.22,38.38 JDIMM1.188 ; JWLAN1.49 v2(57.05,101.36) ; JDIMM2.106 43.92,61.38 43.62,61.68 v2(43.62,61.83) 43.62,62.07 43.92,62.38 JDIMM2.102 ; JDIMM1.230 58.08,27.87 57.69,28.27 v2(57.69,28.6) 57.97,28.87 JDIMM1.226 ; JWLAN1.61 v2(60.05,101.4) ; JDIMM2.230 v2(43.37,28.38) ; JDIMM1.30 58.17,79.88 57.68,79.38 v2(57.68,78.61) 57.92,78.38 JDIMM1.36 ; v2(57.49,41.29) 57.86,41.29 57.94,41.38 JDIMM1.176 ; JDIMM2.93 54.1,64.62 54.31,64.41 54.31,63.56 v2(54.28,63.53) 54.21,63.45 54.21,63.45 53.95,63.19 53.95,63.19 53.88,63.13 JDIMM2.99 ; JDIMM2.14 43.89,84.37 43.58,84.68 v2(43.58,84.85) ; JDIMM1.78 57.81,67.88 v2(57.33,67.39) 57.33,67.18 57.63,66.88 JDIMM1.82 ; v2(222.5,32.83) 222.71,33.05 JEDP1.35 ; JDIMM1.210 58.15,32.87 v2(57.87,32.59) 57.87,32.21 58.21,31.87 JDIMM1.214 ; JDIMM1.168 58.05,43.38 57.42,42.75 v2(57.42,42.62) 57.67,42.38 JDIMM1.172 ; JDIMM1.206 58.02,33.87 v2(57.3,33.16) ; JDIMM2.168 43.66,43.87 v2(43.58,43.95) 43.58,43.31 44.02,42.87 JDIMM2.172 ; JDIMM2.181 53.91,40.63 v2(54.26,40.28) 54.26,39.93 53.95,39.63 JDIMM2.185 ; JDIMM2.205 54.3,34.63 v2(54.73,34.2) 54.73,34.19 54.16,33.63 JDIMM2.209 ; JWLAN1.67 v2(61.55,101.43) ; v2(54.31,27.79) 53.98,28.12 JDIMM2.231 ; JDIMM2.39 54.55,78.13 v2(54.55,78.12) 54.55,77.74 53.93,77.13 JDIMM2.43 ; v2(54.28,68.58) 53.95,68.58 53.9,68.62 JDIMM2.77 ; JDIMM2.56 43.89,73.87 43.58,74.18 v2(43.58,74.38) 43.58,74.57 43.89,74.87 JDIMM2.52 ; JDIMM1.184 57.92,39.38 v2(57.74,39.2) ; v2(61,41.15) 61,41.15 61,40.73 60.65,40.38 JDIMM1.180 ; JDIMM1.213 68.24,32.13 68.51,31.86 v2(68.53,31.86) 68.53,31.38 68.27,31.13 JDIMM1.217 ; v2(68.57,35.82) 68.56,35.8 68.56,35.47 68.21,35.13 JDIMM1.201 ; v2(46.65,62.94) 46.22,63.38 JDIMM2.98 ; JDIMM1.61 68.46,72.13 v2(68.71,72.38) 68.71,72.61 68.2,73.13 JDIMM1.57 ; v2(55.77,101.36) 55.55,101.14 JWLAN1.43 ; v2(47.3,108.86) JWLAN1.10 ; JDIMM2.196 43.54,36.87 43.24,36.57 43.24,35.86 v2(43.26,35.83) 43.72,35.38 JDIMM2.202 ; JDIMM1.98 60.49,62.88 61.13,63.52 v2(61.14,63.52) 60.78,63.88 JDIMM1.94 ; JDIMM1.23 68.95,81.62 69.26,81.32 69.26,80.5 v2(69.03,80.27) 68.68,80.62 JDIMM1.27 ; JDIMM1.77 69.12,68.13 69.43,67.82 v2(69.43,67.65) ; JDIMM1.6 58.22,85.88 v2(57.83,85.49) 57.78,85.44 57.78,86.57 58.09,86.88 JDIMM1.2 ; JHDD1.1 199.15,16.32 v2(198.95,16.12) ; JDIMM2.82 43.99,67.38 43.66,67.71 v2(43.66,68.15) 43.88,68.38 JDIMM2.78 ; v2(49.3,108.86) JWLAN1.18 ; JDIMM2.9 54.63,85.62 54.95,85.3 v2(54.95,85) 54.95,84.79 54.28,84.13 JDIMM2.15 ; JDIMM1.223 68.6,29.63 68.6,29.63 v2(68.63,29.63) ; JDIMM2.234 43.63,27.38 43.32,27.07 v2(43.32,26.89) 43.32,26.74 43.69,26.38 JDIMM2.238 ; JDIMM2.235 54.98,27.12 v2(55.19,26.91) 54.4,26.12 JDIMM2.239 ; JDIMM1.175 68.14,41.63 68.54,41.23 v2(68.54,40.79) 68.54,40.53 68.13,40.13 JDIMM1.181 ; JDIMM2.171 54.53,43.12 v2(54.53,43.13) 54.53,43.8 54.21,44.12 JDIMM2.167 ; JDIMM1.248 58.1,23.38 57.79,23.68 v2(57.79,23.74) 57.79,24.07 58.1,24.38 JDIMM1.244 ; v2(69.17,70.86) 69.17,69.49 68.81,69.13 JDIMM1.73 ; JDIMM2.72 44.02,69.87 43.58,70.31 v2(43.58,70.31) 43.58,70.57 43.88,70.87 JDIMM2.68 ; JDIMM2.64 43.92,71.87 43.62,72.18 v2(43.62,72.41) 43.62,72.57 43.92,72.87 JDIMM2.60 ; JDIMM2.193 54.01,37.63 54.44,38.05 v2(54.44,38.18) 54.44,38.32 54.13,38.63 JDIMM2.189 ; JDIMM1.89 68.27,65.13 v2(68.54,65.39) 68.54,65.75 68.17,66.13 JDIMM1.85 ; JDIMM1.22 58.13,81.88 57.82,81.57 v2(57.82,81.39) ; JDIMM1.51 68.22,74.62 v2(68.66,74.19) ; v2(69.08,85.62) 69.08,86.34 68.3,87.13 JDIMM1.1 ; JWLAN1.7 v2(44.55,98.97)
  BOTTOM w0.381: U2.5 117.18,109.41 v2(117.6,109.83) ; v2(106.57,18.74) 106.63,18.74 107.01,19.13 UC4.3
  BOTTOM w0.406: EU3501.3 v2(29.67,110.32) ; v2(194.21,21.28) 194.21,21.13 194.2,21.12 EU3101.3
  BOTTOM w0.457: RC146.2 127.48,66.55 v2(127.66,66.38) ; JIOB1.6 180.6,17.88 v2(181.14,18.43) 181.6,17.97 JIOB1.5
  BOTTOM w0.508: v2(113.3,93.3) 113.3,92.98 PC1024.2 ; v2(161.12,47.39) 160.66,47.85 EC2206.2 159.35,47.85 EC2214.2 ; JKB1.31 89.28,4.26 89.28,4.25 v2(89.03,4) ; v2(160.69,33.88) 160.69,33.52 160.79,33.42 PC502.2 PR502.1 ; PC1027.2 115.02,92.92 v2(115.02,93.3) ; PC669.2 153.44,103.95 v2(153.69,104.21) ; RC7.2 127.54,39.19 126.74,39.98 v2(126.74,40.3) ; JRTC1.4 32.38,4.73 31.67,5.44 v2(31.16,5.44) ; PC1132.2 110.75,83.31 PC1130.2 112.26,83.3 PC1022.2 113.49,83.66 v2(113.49,83.98) ; v2(200.97,47.4) 200.75,47.62 JODD1.25 ; PC209.2 92.3,101.75 v2(92.78,102.23) ; CL11.2 41.17,117.3 v2(41.3,117.18) ; v2(130.77,54.92) 131.21,54.48 CC6.2 ; PC1023.2 116.61,92.92 v2(116.61,93.3) ; PH603.1 156.38,84.62 v2(156.3,84.54) ; EC2202.2 204.44,21.93 v2(204.79,22.28) ; JFAN1.4 v2(185.76,53.41) ; v2(112.61,6.75) 112.32,6.75 JKBBL1.6 ; JODD1.13 v2(193.5,46.46) ; PC1060.2 v2(148.43,54.08) ; v2(159.75,22.62) 159.69,22.56 RE20.2 ; v2(152.61,38) PR305.2 PR310.2 ; PC4.2 v2(82.25,124.99) ; v2(87.31,102.13) 87.69,101.75 PC204.1 ; JTP1.10 93.68,7.92 v2(93.68,10.18) ; PC201.2 v2(82.56,110.22) ; R27.2 116.33,10.86 v2(116.25,10.94) 115.98,11.21 Q8.3 ; PC629.1 v2(160.17,61.62) ; v2(92.41,107.14) PC202.2 ; v2(113.43,87.01) 113.43,86.72 PC1223.2 PC1016.2 110.85,86.32 PC1018.2 ; v2(155.11,14.5) 154.79,14.17 CE16.2 154.39,13.72 153.7,13.03 JLED1.1 ; v2(138.77,66.71) 139.15,66.71 PC1013.2 ; PJPDC1.8 83.7,127.86 ; RC8.2 106.97,31.99 v2(106.89,32.07) ; UU1.2 8.03,26.44 v2(7.77,26.18) ; JKBBL1.5 119.05,5.33 v2(119.15,5.23) ; JODD1.8 190.5,49.38 v2(190.71,49.17) ; CC80.2 92.92,15.77 CC81.2 92.92,17.8 91.08,19.64 91.08,21.75 v2(90.89,21.94) ; v2(136.04,74.44) 136.04,74.12 PC1070.2 ; CC59.2 131.39,30 v2(131.27,30.12) ; PC1058.2 v2(151.92,54.08) ; v2(180.18,27.85) 180.18,27.85 179.98,28.06 PR118.2 ; PC126.2 v2(176.23,28.66) ; v2(53.47,97.5) 53.72,97.26 EC3202.2 ; JDIMM2.262 36.1,21.3 v2(33.8,21.3) ; v2(146.01,13.79) 145.88,13.92 CE14.2 144.4,13.92 CE3.2 ; PR738.2 96.44,121.99 v2(96.82,122.37) ; v2(119.11,12.43) 119.33,12.22 EC3002.2 C34.2 ; PC203.2 v2(92.4,108.03) ; PC1134.2 PC1224.2 111.91,89.93 v2(111.91,90.32) ; v2(130.75,51.11) 131.21,51.57 CC7.2 ; v2(171.34,62.97) PC641.2 ; PC1135.2 110.57,92.54 PC1222.2 111.78,92.86 v2(111.78,93.24) ; v2(222.71,51.26) 222.59,51.26 221.81,50.49 J3D1.12 ; JIOB1.18 168.86,15.64 169.88,15.64 169.88,15.63 v2(169.89,15.63) ; JRTC1.2 28.58,6.39 v2(27.89,7.07) ; PR751.1 196.16,40.18 PR779.1 196.16,41.42 196.26,41.52 v2(196.26,41.82) ; PC748.2 188.13,38.03 188.13,38.64 v2(188.13,38.65) 188.13,39.23 PC749.1 ; RC6.1 115.64,24.33 v2(116.31,24.33) ; v2(156.94,94.71) 156.54,94.71 PC677.2 ; v2(160.8,52.84) 161.06,52.84 PC603.2 ; JIOB1.2 184.6,18.63 185.73,19.76 ; PR802.2 45.77,9.47 45.9,9.61 v2(46.19,9.61) 46.36,9.61 46.71,9.27 PU800.8 ; v2(138.77,69.75) 139.16,69.75 PC1080.2 ; v2(155.86,62.5) 156.03,62.5 156.08,62.56 PC645.2 ; PBATT1.11 v2(229,13.86) ; v2(56.17,97.5) 55.93,97.26 EC3201.2 ; PR755.1 192.6,41.07 PC753.1 192.08,41.93 v2(191.97,41.82) ; PR204.2 v2(92.4,109.94) ; CL10.2 v2(38.17,119.02) ; v2(94.51,10.18) 94.81,10.48 C27.2 ; v2(176.35,37.14) 176.59,36.9 PR122.2 ; PC1002.2 135.9,69.23 v2(135.56,69.23) ; v2(115.02,83.99) 115.02,83.67 PC1021.2 ; v2(175.85,38.06) 176.17,38.38 PR110.2 ; J3D1.11 v2(213.14,49.03) ; v2(165.53,51.23) 165.2,51.57 PC695.1 ; C13.2 221.2,37.37 221.2,37.82 220.2,38.82 219.2,38.82 v2(218.92,39.1) ; v2(107.96,8.04) 107.96,6.76 JTP1.9 ; EC2213.2 v2(93.94,112.87) ; CC73.2 130.08,32.24 v2(129.69,31.84) ; v2(140.23,74.44) 140.23,74.12 PC1074.2 ; v2(103.07,10.85) 103.65,11.44 103.65,11.89 103.14,12.4 101.3,12.4 100.9,12 v2(100.9,10.9) JTP1.5 ; v2(158.33,9.12) 158.3,9.15 JLED1.5 ; PC7.2 v2(200.55,17.91) ; PC649.2 157.07,60.79 PC652.2 v2(156.42,60.81) ; v2(113.37,96.22) 113.37,95.84 PC1179.2 ; v2(130.75,47.08) 131,46.83 CC84.2 ; v2(190.5,46.5) 190.5,46.51 JODD1.7 ; v2(109.43,28.53) 109.68,28.78 RC67.2 RC68.2 ; U1.2 225.79,26.53 v2(226.27,27.01) ; v2(229.45,28.85) 229.45,28.85 JEDP1.41 ; PC1014.2 115.02,89.93 v2(115.02,90.32) ; v2(128.47,74.18) RC122.2 RC121.2 ; CX5.1 v2(215.61,36.79) ; v2(187.09,51.64) 187.5,51.23 JODD1.2 ; v2(138.73,13.23) 138.58,13.38 CE33.2 ; DA4.1 v2(17.62,12.09) ; CC63.2 132.73,43.71 v2(133.37,44.34) ; Q1.3 v2(41.12,4.29) ; v2(137.43,74.44) 137.43,74.12 PC1079.2 ; PC661.2 164.06,82.37 v2(164.32,82.11) ; CC79.2 134.13,36.56 CC67.2 135.32,36.55 v2(135.47,36.4) ; v2(135.56,67.71) 135.9,67.71 PC1068.2 ; v2(222.51,25.1) 222.81,24.8 R10.2 ; v2(4.21,26.75) 4.41,26.55 CU5.2 ; RX6.2 v2(216.49,36.83) ; v2(108.68,106.38) 108.68,106.19 C20.2 ; v2(159.16,64.55) 159.59,64.55 160.1,64.04 PR653.2 ; JIOB1.10 176.6,18.55 176.74,18.69 v2(176.74,18.68) ; PC1076.2 135.9,66.19 v2(135.56,66.19) ; CC15.2 131.16,77.68 RC144.2 130.59,78.58 131.15,79.14 v2(131.4,79.14) ; JLED1.6 147.7,8.11 148.21,7.6 v2(148.69,7.6) ; v2(119.86,106.99) C24.2 ; v2(94.95,104.21) 95.34,103.82 PC1209.2 ; PR732.2 PR731.2 189.41,33.11 v2(189.2,33.32) ; v2(185.25,51.12) 185.25,51.12 JODD1.26 183.65,49.12 EC2203.2 ; v2(111.84,11.76) 111.84,11.7 111.27,11.13 110.26,11.13 109.86,11.52 R45.2 ; v2(112.2,28.85) 112.76,29.41 RC56.2 ; v2(134.64,74.44) 134.64,74.12 PC1082.2 ; PC1073.2 139.15,68.23 v2(138.77,68.23) ; v2(181.88,58.76) 181.94,58.76 JFAN1.6 ; C21.2 109.2,107.04 v2(108.67,107.04) ; v2(116.61,96.22) 116.61,95.84 PC1025.2 ; C17.2 v2(229.13,27.45) ; PC2.2 v2(76.79,122.13) ; v2(36.86,121.18) 37.33,120.71 YL1.4 ; DA5.1 v2(17.72,16.15) ; CC3.2 v2(111.5,22.77) ; v2(164.32,79.49) 164.6,79.77 EC2205.2 ; PC757.1 200.34,38.93 v2(200.73,38.54) ; v2(97.22,44.3) 96.83,44.3 96.27,43.75 RC87.2 ; PC1017.2 116.61,83.64 v2(116.61,83.97) ; PC1015.2 113.43,90 v2(113.43,90.32) ; RX5.2 v2(206.64,38.06) ; PC805.2 v2(55.22,9.97) ; v2(89.38,20.31) 89.38,16.95 CC88.2 ; YL1.2 41.38,122.41 v2(41.51,122.29) ; PC1075.2 138.83,74.12 v2(138.83,74.44) ; PC1019.2 114.96,86.68 v2(114.96,86.98) ; v2(116.67,90.32) 116.67,89.93 PC1184.2 ; PR727.2 189.81,39.54 189.3,40.05 189.04,40.05 v2(188.68,40.4) ; v2(27.33,120.16) 27.7,120.54 UL3.2 ; RC147.2 129.05,62.88 v2(129.28,62.65) ; PC1006.2 144.55,74.12 v2(144.55,74.44) ; RC182.2 121.62,28.62 v2(121.88,28.36) ; v2(169.82,55.73) 169.05,55.73 PC614.1 169.02,56.63 PC616.1 ; PC210.2 v2(87.33,111.46) ; RC133.1 v2(123.84,78.86) ; PC1221.2 115.08,80.68 v2(115.08,81.01) ; v2(147.84,37.73) 147.28,38.29 PC305.2 PC306.2 ; v2(168.55,19.39) 168.75,19.19 UU3.2 ; 185.73,19.76 185.73,18.86 185.6,18.73 JIOB1.1 ; 185.73,19.76 v2(185.73,19.77) ; RC52.2 96.1,16.46 v2(95.97,16.59) ; v2(129.84,66.89) 129.43,66.89 RC134.2 ; PC213.2 v2(88.22,111.45) ; JWLAN1.68 v2(41.95,98.89) ; JFAN1.5 179.48,53.75 v2(180.42,54.69) ; v2(151.18,13.21) 150.7,12.73 JLED1.4 ; v2(132.1,35.4) 133.01,34.49 CC74.2 ; PR753.1 189.64,41.72 189.97,41.39 PC751.1 190.44,42.3 PC752.1 190.39,42.35 v2(189.81,42.35) ; v2(200.62,37.87) PC768.1 PC769.1 ; EC2201.2 v2(154.62,104.44) ; JRTC1.3 24.4,3 24.4,3.01 v2(24.41,3.01) ; JWLAN1.69 v2(62.65,104.01) ; RL6.1 v2(24.91,122.57) ; PC1.2 v2(76.79,121.18) ; v2(128.47,75.06) 128.43,75.1 RC131.1 RC132.1 ; v2(115.02,96.22) 115.02,95.84 PC1156.2 ; v2(105.81,22.4) 105.95,22.26 RC109.2 ; PQ712.3 v2(89.77,121.19) ; UC3.4 116.87,16.26 v2(116.42,15.81) ; v2(113.56,81.01) 113.56,80.65 PC1154.2 PC1155.2 PC1136.2 ; CE4.2 141.12,14.04 140.61,13.54 v2(140.61,13.23) ; PC608.2 v2(148.9,69.35) ; JIOB1.9 177.6,18.15 v2(178.07,18.62) ; PJPDC1.7 v2(67.5,127.82) ; JSPK1.5 v2(12.03,1.8) ; C25.2 v2(119.87,107.94) ; v2(111.72,96.28) 111.72,95.9 PC1026.2 ; v2(164.1,18.19) v4(164.77,18.85) 165.47,19.56 CU17.2 ; v2(106,26.5) 106,25.74 RC145.2 ; C26.2 v2(95.5,13.79) ; PC1020.2 116.61,86.66 v2(116.61,87.01) ; EC3001.2 v2(112.53,11.76) ; v2(135.56,64.66) 135.9,64.66 PC1077.2 ; 127.24,55.22 v2(127.89,55.22) 129.8,55.22 v2(129.86,55.29) 130.13,55.55 v2(133.14,55.55) 134.77,55.55 v2(134.79,55.53) 135.15,55.17 v2(135.15,54.22) v2(135.15,52.58) 135.15,51.12 134.64,50.61 v2(132.62,50.61) v2(131.21,50.61) 130.92,50.32 v4(130.03,50.32) 129.43,50.92 v2(129.43,52.14) v2(129.43,53.45) 129.15,53.73 v2(128.16,53.73) ; PR1202.1 v2(104.49,109.66) ; EC2204.2 EC2210.2 195.55,29.88 v2(195.51,29.84) ; v2(72.35,19.26) 73.04,19.95 JDIMM1.262 ; v2(87.08,24.42) 87.08,24.53 87.87,25.32 JCMOS1.2 ; PC1003.2 143.15,74.12 v2(143.15,74.44) ; RL2.1 v2(39.9,115.72) ; v2(72.35,87.78) 72.57,87.55 JDIMM1.261 ; JSPK1.6 v2(8.59,1.8) ; JKB1.32 63.13,5.98 63.13,5.99 v2(63.13,8.07) ; JDIMM2.261 v2(33.97,88.05) ; PC1059.2 v2(150.08,54.08) ; v2(141.69,74.44) 141.69,74.12 PC1173.2 ; v2(151.33,96.4) PH601.1 ; v2(105.53,18.43) CC2.1 ; PC1205.2 v2(95.1,111.54) ; DA6.1 v2(220.36,27.86) ; v2(170.81,56.86) 170.53,56.86 169.96,57.44 PC619.1 PC618.1 ; RC156.2 v2(117.31,77.29) ; PC3.2 v2(83.14,124.92) ; v2(187.5,46.58) 187.5,46.58 JODD1.1 ; v2(116.73,81.01) 116.73,80.6 PC1178.2 ; EC2230.2 v2(156.95,94.02) ; v2(193.5,49.51) 193.5,49.51 JODD1.14 ; v2(167.21,55.33) 167.16,55.28 PC602.2 ; PR662.2 v2(162.28,85.49) ; PR505.2 v2(159.51,31.01) ; PC128.2 v2(183.27,29.36) ; RL4.2 v2(35.96,122.34) ; v2(103.65,102.06) 103.45,101.86 PC1206.2 ; CL9.2 v2(31.46,123.53) ; EC2207.2 v2(92.98,112.87) ; CX4.1 v2(206.78,42.51)
  BOTTOM w1.016: JLAN1.10 16.26,118.1 CL13.2
  vias: v1(24.79,7.64) v2(0.51,118.8) v2(2.13,6.18) v2(3.54,30.05) v2(4.44,49.08) v2(4.47,96.68) v2(5.22,124.79) v2(6.26,96.7) v2(6.5,76.79) v2(6.59,122.3) v2(6.56,74.5) v2(6.56,72.41) v2(6.62,70.12) v2(6.75,50.25) v2(6.81,47.96) v2(7.65,124.13) v2(7.65,120.47) v2(7.56,29.99) v2(8.34,96.73) v2(8.85,73.55) v2(8.91,71.27) v2(8.92,0.51) v2(9.09,51.06) v2(9.1,49.1) v2(9.19,46.83) v2(9.38,29.96) v2(9.75,124.13) v2(9.75,120.47) v2(10.56,96.73) v2(10.81,122.3) v2(11.07,76.85) v2(11.13,74.57) v2(11.09,29.99) v2(11.2,72.41) v2(11.26,70.12) v2(11.39,50.25) v2(11.45,47.96) v2(12.39,96.73) v2(12.83,124.79) v2(13.23,49.13) v2(13.42,76.09) v2(13.48,73.81) v2(14.97,30.07) v2(16.29,4.3) v2(17.35,6.13) v2(17.35,2.47) v2(18.63,58.18) v2(18.56,56.47) v2(18.94,36.47) v2(18.94,34.82) v2(19.45,6.13) v2(19.45,2.47) v2(20.45,124.79) v2(20.51,4.3) v2(22.31,60.79) v2(22.56,88.79) v2(23.26,86.7) v2(23.39,83.77) v2(23.64,41.49) v2(23.71,84.92) v2(23.7,39.46) v2(23.9,62.95) v2(23.96,60.85) v2(24.16,0.51) v2(24.34,89.62) v2(24.28,4.15) v2(24.4,86.82) v2(24.54,3.62) v2(24.72,7.13) v2(25.04,88.41) v2(25.42,21.93) v2(25.42,19.96) v2(25.42,17.99) v2(25.36,7.13) v2(25.74,37.42) v2(25.8,39.46) v2(26.04,56.59) v2(26.08,58.35) v2(27.39,21.93) v2(27.39,19.96) v2(27.39,17.99) v2(28.08,124.79) v2(28.47,36.98) v2(29.1,118.19) v2(29.17,116.73) v2(29.29,36.98) v2(29.36,21.93) v2(29.36,19.96) v2(29.36,17.99) v2(30.88,118.7) v2(31.78,0.51) v2(32.41,119.53) v2(32.53,122.45) v2(33.64,117.92) v2(33.64,116.8) v2(34.44,122.45) v2(34.75,116.8) v2(34.75,115.68) v2(35.7,124.79) v2(35.87,116.8) v2(37.47,67.67) v2(37.49,66.82) v2(37.51,65.98) v2(37.49,65.21) v2(39.4,0.51) v2(42.41,131.84) v2(43.59,44.54) v2(44.98,3.7) v2(45.49,92.66) v2(45.74,3.7) v2(46.65,79.47) v2(46.65,68.28) v2(46.65,65.1) v2(46.65,52.76) v2(46.65,42.72) v2(46.62,36.32) v2(46.62,25.38) v2(47.02,0.51) v2(47.41,86.26) v2(47.41,84.66) v2(47.41,83.39) v2(47.41,80.72) v2(47.41,78.2) v2(47.41,75.26) v2(47.41,73.99) v2(47.41,72.47) v2(47.41,69.42) v2(47.41,66.32) v2(47.41,65.1) v2(47.41,62.94) v2(47.41,60.33) v2(47.41,58.14) v2(47.41,56.16) v2(47.41,54.03) v2(47.41,51.51) v2(47.41,49.87) v2(47.41,48.31) v2(47.41,47.26) v2(47.41,45.09) v2(47.41,43.97) v2(47.41,41.4) v2(47.38,39.6) v2(47.38,38.03) v2(47.38,34.71) v2(47.38,32.44) v2(47.38,30.84) v2(47.38,29.31) v2(47.38,27.15) v2(47.38,24.23) v2(48.14,30.84) v2(48.17,84.66) v2(48.17,73.99) v2(48.17,65.1) v2(48.17,51.51) v2(48.17,49.87) v2(48.17,42.72) v2(48.17,41.4) v2(48.6,138) v2(48.94,86.26) v2(48.94,84.66) v2(48.94,83.39) v2(48.94,80.72) v2(48.94,79.47) v2(48.94,78.2) v2(48.94,75.26) v2(48.94,73.99) v2(48.94,72.47) v2(48.94,69.42) v2(48.94,68.28) v2(48.94,66.32) v2(48.94,65.1) v2(48.94,62.94) v2(48.94,60.33) v2(48.94,58.14) v2(48.94,56.16) v2(48.94,54.03) v2(48.94,52.76) v2(48.94,51.51) v2(48.94,49.87) v2(48.94,48.31) v2(48.94,47.26) v2(48.94,45.09) v2(48.94,43.97) v2(48.94,42.72) v2(48.94,41.4) v2(48.9,39.6) v2(48.9,38.03) v2(48.9,36.3) v2(48.9,34.71) v2(48.9,32.44) v2(48.9,30.84) v2(48.9,29.31) v2(48.9,27.15) v2(48.9,25.38) v2(48.9,24.23) v2(49.36,133.69) v2(49.49,7.32) v2(49.7,79.47) v2(49.7,68.28) v2(49.7,65.1) v2(49.7,62.94) v2(49.7,51.51) v2(49.7,43.97) v2(49.67,36.3) v2(50.43,39.6) v2(50.43,38.03) v2(50.43,36.3) v2(50.43,34.71) v2(50.43,32.44) v2(50.43,29.31) v2(50.43,27.15) v2(50.43,24.23) v2(50.44,7.32) v2(50.46,86.26) v2(50.46,83.39) v2(50.46,80.72) v2(50.46,79.47) v2(50.46,75.26) v2(50.46,72.47) v2(50.46,69.42) v2(50.46,66.32) v2(50.46,65.1) v2(50.46,60.33) v2(50.46,58.14) v2(50.46,56.16) v2(50.46,54.03) v2(50.46,51.51) v2(50.46,49.87) v2(50.46,48.31) v2(50.46,47.26) v2(50.46,45.09) v2(50.46,43.97) v2(50.46,42.72) v2(50.76,136.23) v2(50.76,131.21) v2(51.22,73.99) v2(51.22,68.28) v2(51.22,62.94) v2(51.22,41.4) v2(51.19,30.84) v2(53.74,131.15) v2(53.87,136.23) v2(54.12,3.57) v2(54.64,0.51) v2(54.76,3.57) v2(55.16,133.65) v2(57.36,138) v2(60.85,79.02) v2(60.76,52.87) v2(60.78,24.81) v2(61.06,55.68) v2(61.06,36.03) v2(61.37,67.82) v2(61.53,54.19) v2(61.53,51.75) v2(61.49,32.7) v2(61.49,29.29) v2(61.61,85.66) v2(61.64,83.13) v2(61.61,80.27) v2(61.55,77.25) v2(61.63,58.41) v2(61.57,47.84) v2(61.61,46.8) v2(61.58,44.54) v2(61.62,39.37) v2(61.63,37.93) v2(61.58,33.95) v2(61.61,26.87) v2(61.72,75.37) v2(61.65,49.83) v2(61.68,42.75) v2(61.69,41.13) v2(61.68,23.51) v2(61.83,45.72) v2(62.02,72.38) v2(62.04,69.78) v2(62.27,66.37) v2(62.33,30.58) v2(62.26,0.51) v2(62.37,84.64) v2(62.35,74.1) v2(62.45,41.13) v2(62.38,20.99) v2(62.48,62) v2(62.58,55.68) v2(62.74,57.15) v2(62.8,132.54) v2(62.86,64.41) v2(63.01,32.7) v2(63.01,29.29) v2(63.14,85.66) v2(63.14,84.64) v2(63.14,80.27) v2(63.14,79.02) v2(63.08,77.25) v2(63.05,54.19) v2(63.05,52.87) v2(63.07,51.75) v2(63.09,47.84) v2(63.14,46.8) v2(63.1,44.54) v2(63.14,39.37) v2(63.11,33.95) v2(63.1,30.58) v2(63.14,26.87) v2(63.06,24.81) v2(63.16,83.13) v2(63.25,75.37) v2(63.15,58.41) v2(63.18,49.83) v2(63.2,42.75) v2(63.21,41.13) v2(63.15,37.93) v2(63.2,23.52) v2(63.35,55.68) v2(63.34,36.03) v2(63.35,45.72) v2(63.55,72.38) v2(63.57,69.78) v2(63.65,67.82) v2(63.79,66.37) v2(63.78,59.51) v2(63.83,24.81) v2(64,62) v2(64.11,55.68) v2(64.27,57.15) v2(64.38,109.43) v2(64.41,67.82) v2(64.42,64.41) v2(64.53,32.7) v2(64.54,29.29) v2(64.6,77.25) v2(64.64,74.1) v2(64.58,54.19) v2(64.6,51.75) v2(64.64,47.86) v2(64.62,44.54) v2(64.63,33.95) v2(64.59,24.81) v2(64.66,85.66) v2(64.69,83.13) v2(64.66,80.27) v2(64.66,79.02) v2(64.67,58.41) v2(64.7,49.83) v2(64.66,46.8) v2(64.73,42.75) v2(64.67,39.37) v2(64.68,37.93) v2(64.66,26.87) v2(64.66,23.52) v2(64.7,20.99) v2(64.77,75.37) v2(64.88,45.72) v2(65.02,109.43) v2(65.07,72.38) v2(65.09,69.78) v2(65.32,66.37) v2(65.34,52.87) v2(65.42,84.64) v2(65.5,41.13) v2(65.49,30.61) v2(65.56,121.82) v2(65.56,121.19) v2(65.69,109.42) v2(65.92,64.41) v2(66.2,121.82) v2(66.2,121.19) v2(66.33,109.42) v2(66.83,121.82) v2(66.83,121.19) v2(67.44,121.82) v2(67.44,121.19) v2(69.25,29.63) v2(69.24,28.78) v2(69.88,0.51) v2(71.12,130.99) v2(72,31.71) v2(72.4,72.66) v2(72.5,32.21) v2(72.82,73.07) v2(73.23,73.49) v2(73.5,107.74) v2(73.55,119.65) v2(73.55,119.02) v2(73.64,73.9) v2(74.1,107.74) v2(74.19,119.65) v2(74.19,119.02) v2(77.43,102.04) v2(77.5,0.51) v2(78.06,102.06) v2(78.69,130.99) v2(78.73,102.68) v2(78.7,102.06) v2(79.33,102.7) v2(79.33,102.06) v2(79.97,102.7) v2(79.97,102.06) v2(80.6,102.7) v2(80.6,102.06) v2(81.24,102.7) v2(81.24,102.06) v2(81.87,102.7) v2(81.87,102.06) v2(82.61,112.1) v2(82.56,111.16) v2(83.07,99.57) v2(85.12,0.51) v2(85.24,131.2) v2(86.89,112.79) v2(86.89,112.16) v2(86.97,106.67) v2(86.95,100.07) v2(87.52,112.16) v2(87.59,107.29) v2(87.59,106.04) v2(88.21,106.67) v2(88.75,42.06) v2(89.3,42.31) v2(89.94,42.31) v2(91,136.01) v2(92.53,53.4) v2(92.74,0.51) v2(93.44,62.9) v2(93.4,57.3) v2(93.97,55.01) v2(94.04,49.68) v2(94.09,69.66) v2(94.19,67.71) v2(94.43,64.57) v2(94.39,53.42) v2(94.6,47.92) v2(94.69,59.29) v2(94.86,45.98) v2(95.02,102.57) v2(95.02,101.94) v2(95.05,65.91) v2(95.22,62.9) v2(95.28,71.21) v2(95.42,67.72) v2(95.4,51.47) v2(95.73,55.02) v2(95.75,73.69) v2(95.85,69.66) v2(95.83,49.68) v2(95.91,57.33) v2(96.25,65.91) v2(96.2,64.61) v2(96.3,53.41) v2(96.45,59.25) v2(96.45,47.92) v2(96.71,45.98) v2(97.21,71.24) v2(97.34,51.48) v2(97.38,73.23) v2(97.57,54.97) v2(97.66,49.65) v2(98.21,47.92) v2(98.44,53.43) v2(98.5,57.44) v2(100.08,114.7) v2(100.16,113.62) v2(100.36,0.51) v2(100.82,136) v2(100.79,113.62) v2(100.99,116.6) v2(100.99,115.97) v2(101.03,79.22) v2(101.24,77.59) v2(101.37,113.43) v2(102.38,77.96) v2(102.64,80.18) v2(103.49,79.26) v2(104.49,114.25) v2(104.5,113.32) v2(104.5,112.65) v2(104.92,69.56) v2(104.94,44.9) v2(105.02,83.47) v2(104.98,80.89) v2(105.61,69.56) v2(105.6,44.9) v2(106.24,69.51) v2(106.84,85.99) v2(106.84,70.49) v2(107,84.84) v2(106.98,83.05) v2(106.99,81.23) v2(107.11,131.91) v2(107.12,126.29) v2(107.98,0.51) v2(109.3,47.06) v2(109.51,63.18) v2(109.48,60.09) v2(109.52,57.72) v2(109.61,80.44) v2(109.63,78.54) v2(109.71,54.29) v2(110.12,60.08) v2(110.1,42.61) v2(110.21,57.72) v2(110.32,54.29) v2(110.43,50.92) v2(110.43,50.33) v2(110.57,65.85) v2(110.74,77.89) v2(110.74,76.13) v2(110.71,63.18) v2(110.73,60.08) v2(110.83,57.73) v2(110.93,54.29) v2(110.9,48.9) v2(111.18,65.31) v2(111.35,60.06) v2(111.39,72.53) v2(111.39,71.88) v2(111.39,71.23) v2(111.39,70.55) v2(111.42,64.73) v2(111.92,65.6) v2(111.92,63.18) v2(111.92,60.83) v2(111.97,57.24) v2(112,54.8) v2(112,52.41) v2(111.97,47.5) v2(112.11,48.9) v2(112.59,59.36) v2(112.59,58.73) v2(112.61,47.5) v2(113.13,65.6) v2(113.13,63.18) v2(113.13,60.83) v2(113.19,59.39) v2(113.19,58.75) v2(113.18,57.24) v2(113.2,54.8) v2(113.2,52.41) v2(113.3,50.92) v2(113.3,50.33) v2(113.32,48.9) v2(113.77,59.36) v2(113.77,58.73) v2(114.33,65.6) v2(114.33,63.18) v2(114.33,60.83) v2(114.36,59.36) v2(114.36,58.73) v2(114.38,57.24) v2(114.41,54.8) v2(114.41,52.41) v2(114.52,48.9) v2(114.97,59.36) v2(114.97,58.73) v2(115.54,65.6) v2(115.54,63.18) v2(115.54,60.83) v2(115.6,59.36) v2(115.6,58.73) v2(115.59,57.24) v2(115.62,54.8) v2(115.62,52.41) v2(115.6,0.51) v2(115.73,48.9) v2(116.15,50.9) v2(116.15,50.32) v2(116.2,59.37) v2(116.2,58.74) v2(116.31,124.97) v2(116.75,65.6) v2(116.75,63.18) v2(116.75,60.83) v2(116.8,57.24) v2(116.82,54.8) v2(116.82,52.41) v2(117.85,70.6) v2(117.85,69.95) v2(118.89,120.3) v2(123.22,0.51) v2(124.18,107.63) v2(124.73,115.89) v2(124.72,107.97) v2(124.72,107.33) v2(126,59.01) v2(126.7,53.61) v2(127.4,107.97) v2(127.4,107.33) v2(127.96,107.63) v2(128.16,52.85) v2(129.81,60.55) v2(130.03,107.55) v2(130.58,107.84) v2(130.58,107.21) v2(130.84,0.51) v2(131.07,60.56) v2(132.15,115.89) v2(133.32,107.84) v2(133.32,107.21) v2(133.56,38.62) v2(133.84,107.52) v2(136.48,89.24) v2(136.48,88.6) v2(136.52,52.57) v2(136.48,51.4) v2(137.12,89.24) v2(137.12,88.6) v2(138.06,85.39) v2(138.06,84.8) v2(138.06,84.22) v2(138.39,46.63) v2(138.46,0.51) v2(138.76,27.57) v2(139.02,46.63) v2(139.09,28.05) v2(139.53,38.69) v2(139.66,46.63) v2(139.79,61.2) v2(139.79,6.3) v2(139.92,51.95) v2(139.97,115.89) v2(140.34,53.1) v2(140.29,46.63) v2(140.85,63.03) v2(140.85,59.37) v2(140.85,8.13) v2(140.85,4.47) v2(141.43,85.78) v2(141.43,85.2) v2(141.43,84.54) v2(142.95,63.03) v2(142.95,59.37) v2(142.95,8.13) v2(142.95,4.47) v2(143.91,85.63) v2(143.91,85.04) v2(143.91,84.41) v2(143.97,99.27) v2(143.97,98.6) v2(143.97,97.96) v2(143.97,97.33) v2(143.97,96.69) v2(143.97,96.06) v2(144.01,61.2) v2(144.01,6.3) v2(144.61,99.27) v2(144.61,98.63) v2(144.61,98) v2(144.61,97.36) v2(144.61,96.73) v2(144.61,96.09) v2(144.67,89.55) v2(145.12,99.99) v2(145.24,98.63) v2(145.24,98) v2(145.24,97.36) v2(145.24,96.73) v2(145.24,96.09) v2(145.31,89.55) v2(145.57,100.49) v2(145.6,99.59) v2(145.73,67.86) v2(145.71,67.16) v2(145.71,66.46) v2(145.94,98) v2(145.94,97.36) v2(145.94,96.73) v2(145.94,96.09) v2(146.02,100.06) v2(145.96,98.66) v2(146.11,101) v2(146.08,0.51) v2(146.54,100.56) v2(146.49,67.89) v2(146.48,67.18) v2(146.46,66.49) v2(146.6,99.75) v2(146.59,99.1) v2(146.55,89.63) v2(146.58,88.32) v2(146.71,98.13) v2(146.71,97.49) v2(146.69,96.78) v2(146.72,96.16) v2(146.76,68.56) v2(146.92,87.7) v2(146.95,103.06) v2(146.95,102.1) v2(146.95,101.14) v2(146.96,90.28) v2(146.96,88.98) v2(147.19,89.63) v2(147.21,88.32) v2(147.23,67.85) v2(147.21,67.18) v2(147.34,98.13) v2(147.34,97.49) v2(147.33,96.8) v2(147.25,66.46) v2(147.43,100.55) v2(147.35,96.17) v2(147.45,115.91) v2(147.59,90.28) v2(147.59,88.98) v2(147.56,87.7) v2(147.82,89.63) v2(147.91,88.32) v2(148.14,100.16) v2(148.14,99.54) v2(148.14,98.95) v2(148.23,90.28) v2(148.29,88.98) v2(148.25,87.7) v2(148.37,103.06) v2(148.37,102.1) v2(148.37,101.14) v2(148.48,89.64) v2(148.55,88.32) v2(148.89,90.26) v2(148.93,88.98) v2(148.89,87.7) v2(149.09,90.84) v2(149.17,89.64) v2(149.18,88.32) v2(149.47,90.28) v2(149.52,87.7) v2(149.56,88.98) v2(149.8,90.82) v2(149.83,88.33) v2(149.94,93.35) v2(149.94,92.39) v2(149.94,91.43) v2(150.16,87.7) v2(150.49,90.84) v2(150.57,42.65) v2(150.71,71.91) v2(151.25,90.47) v2(151.25,89.86) v2(151.25,89.27) v2(151.35,93.35) v2(151.35,92.39) v2(151.35,91.43) v2(152.93,78.89) v2(153.18,42.06) v2(153.56,78.89) v2(153.7,0.51) v2(153.82,42.06) v2(154.45,42.06) v2(154.76,76.21) v2(154.76,74.68) v2(155.02,41.68) v2(155.02,41.04) v2(155.11,76.99) v2(155.11,75.47) v2(155.11,73.94) v2(155.21,115.89) v2(155.19,78.31) v2(155.34,40.54) v2(155.39,76.21) v2(155.39,74.68) v2(155.68,78.83) v2(155.7,77.86) v2(155.75,76.99) v2(155.75,75.47) v2(155.75,73.94) v2(155.66,41.68) v2(155.66,41.04) v2(155.85,68.39) v2(156.03,76.21) v2(156.03,74.68) v2(155.97,40.54) v2(156.13,78.34) v2(156.19,79.33) v2(156.29,41.68) v2(156.29,41.04) v2(156.38,77.75) v2(156.38,76.99) v2(156.38,75.47) v2(156.38,73.94) v2(156.55,68.39) v2(156.56,78.85) v2(156.61,40.54) v2(156.74,76.21) v2(156.74,74.68) v2(156.93,41.68) v2(156.93,41.04) v2(157.12,79.25) v2(157.09,78.39) v2(157.09,77.75) v2(157.09,76.99) v2(157.09,75.47) v2(157.09,73.94) v2(157.25,68.39) v2(157.33,81.79) v2(157.33,80.83) v2(157.33,79.86) v2(157.51,41.68) v2(157.86,79.25) v2(157.94,68.39) v2(158.74,81.79) v2(158.74,80.83) v2(158.74,79.86) v2(158.66,78.81) v2(158.66,78.21) v2(158.66,77.63) v2(159.39,36.02) v2(159.39,33.88) v2(160.04,34.95) v2(160.55,44.03) v2(160.69,36.02) v2(161.18,44.03) v2(161.32,0.51) v2(161.44,39.33) v2(161.56,37.61) v2(161.82,44.03) v2(162.07,60.48) v2(162.07,58.96) v2(162.07,57.43) v2(162.07,39.33) v2(162.07,29.36) v2(162.19,89.39) v2(162.19,88.75) v2(162.19,88.12) v2(162.19,87.48) v2(162.2,37.62) v2(162.45,44.03) v2(162.45,28.85) v2(162.6,38.57) v2(162.83,115.89) v2(162.77,29.36) v2(162.9,29.99) v2(163.02,28.34) v2(163.21,38.57) v2(163.59,60.48) v2(163.59,58.96) v2(163.59,57.43) v2(163.89,99.8) v2(164.95,101.63) v2(164.95,97.97) v2(165.12,60.48) v2(165.12,58.96) v2(165.12,57.43) v2(167.05,101.63) v2(167.05,97.97) v2(167.38,23.16) v2(168.11,99.8) v2(168.94,0.51) v2(169.02,27.12) v2(169.02,26.49) v2(169.11,112.55) v2(169.54,105.08) v2(169.54,97.04) v2(169.54,89.42) v2(169.64,27.13) v2(170,81.82) v2(172.02,74.47) v2(175.56,67.72) v2(175.57,42.6) v2(175.85,27.07) v2(175.85,26.44) v2(175.85,25.8) v2(175.85,25.17) v2(175.85,24.53) v2(176.49,1.47) v2(177.19,41.17) v2(177.5,46.5) v2(177.5,45.87) v2(177.91,43.19) v2(178.33,42.12) v2(178.33,41.48) v2(178.26,32.6) v2(178.35,42.72) v2(178.56,8.81) v2(180.46,61.89) v2(180.55,42.5) v2(180.55,41.86) v2(180.61,36.47) v2(180.61,35.83) v2(180.78,32.73) v2(181.35,32.09) v2(181.43,42.44) v2(181.36,32.73) v2(181.95,32.73) v2(181.93,32.09) v2(182.56,32.74) v2(182.58,32.09) v2(182.9,35.13) v2(183.03,34.44) v2(183.03,33.8) v2(183.14,32.74) v2(183.72,32.74) v2(189.33,16.76) v2(189.64,16.21) v2(193.36,36.92) v2(193.36,34.73) v2(193.58,52.43) v2(194.46,35.83) v2(195.55,36.92) v2(195.55,34.73) v2(198.08,31.71) v2(200.6,32.54) v2(200.93,33.7) v2(200.93,33.12) v2(201.19,52.2) v2(201.19,32.54) v2(201.52,33.7) v2(201.52,33.12) v2(201.77,32.54) v2(202.1,33.7) v2(202.1,33.12) v2(202.35,32.54) v2(202.39,14.01) v2(202.69,33.7) v2(202.69,33.12) v2(202.94,32.54) v2(202.99,14.33) v2(203.52,32.54) v2(204.49,47.9) v2(204.77,14.05) v2(205.55,49.73) v2(205.55,46.07) v2(207.65,49.73) v2(207.65,46.07) v2(208.71,47.9) v2(208.81,52.1) v2(209.04,8.81) v2(211.92,41.87) v2(212.74,41.04) v2(213.57,41.87) v2(213.89,20.85) v2(214.52,20.85) v2(216.31,53.47) v2(216.49,24.15) v2(216.49,23.52) v2(216.49,22.44) v2(216.49,21.8) v2(216.83,8.81) v2(218.01,50.82) v2(219.34,47.29) v2(219.86,40.72) v2(219.91,16.19) v2(220.05,42.5) v2(221.9,16.22) v2(222.32,42.91) v2(222.91,42.91) v2(223.77,54.99) v2(223.9,16.25) v2(224.45,8.81) v2(225,45.93) v2(224.98,42.55) v2(224.99,40.63) v2(225.13,44.02) v2(225.17,36.48) v2(225.84,51.75) v2(226.09,16.3) v2(227.11,17.83) v2(231.39,46.98) v2(231.39,39.36) v2(231.39,31.74) v2(231.39,24.12) v2(231.38,11.54) v4(24.79,4.72) v4(66.63,120.29) v4(79.27,100.73) v4(88.6,41.36) v4(118.4,46.56) v4(128.95,108.59) v4(143.21,97.62) v4(143.4,97.11) v4(146.32,87.71) v4(146.86,65.79) v4(147.66,69.36) v4(153.75,40.91) v4(154.4,75.49) v4(180.61,46.25) v4(180.74,44.02) v4(183.6,32.02) v4(183.79,35.9) v4(199.79,33.55) v4(202.08,34.37) v4(216.49,20.21)
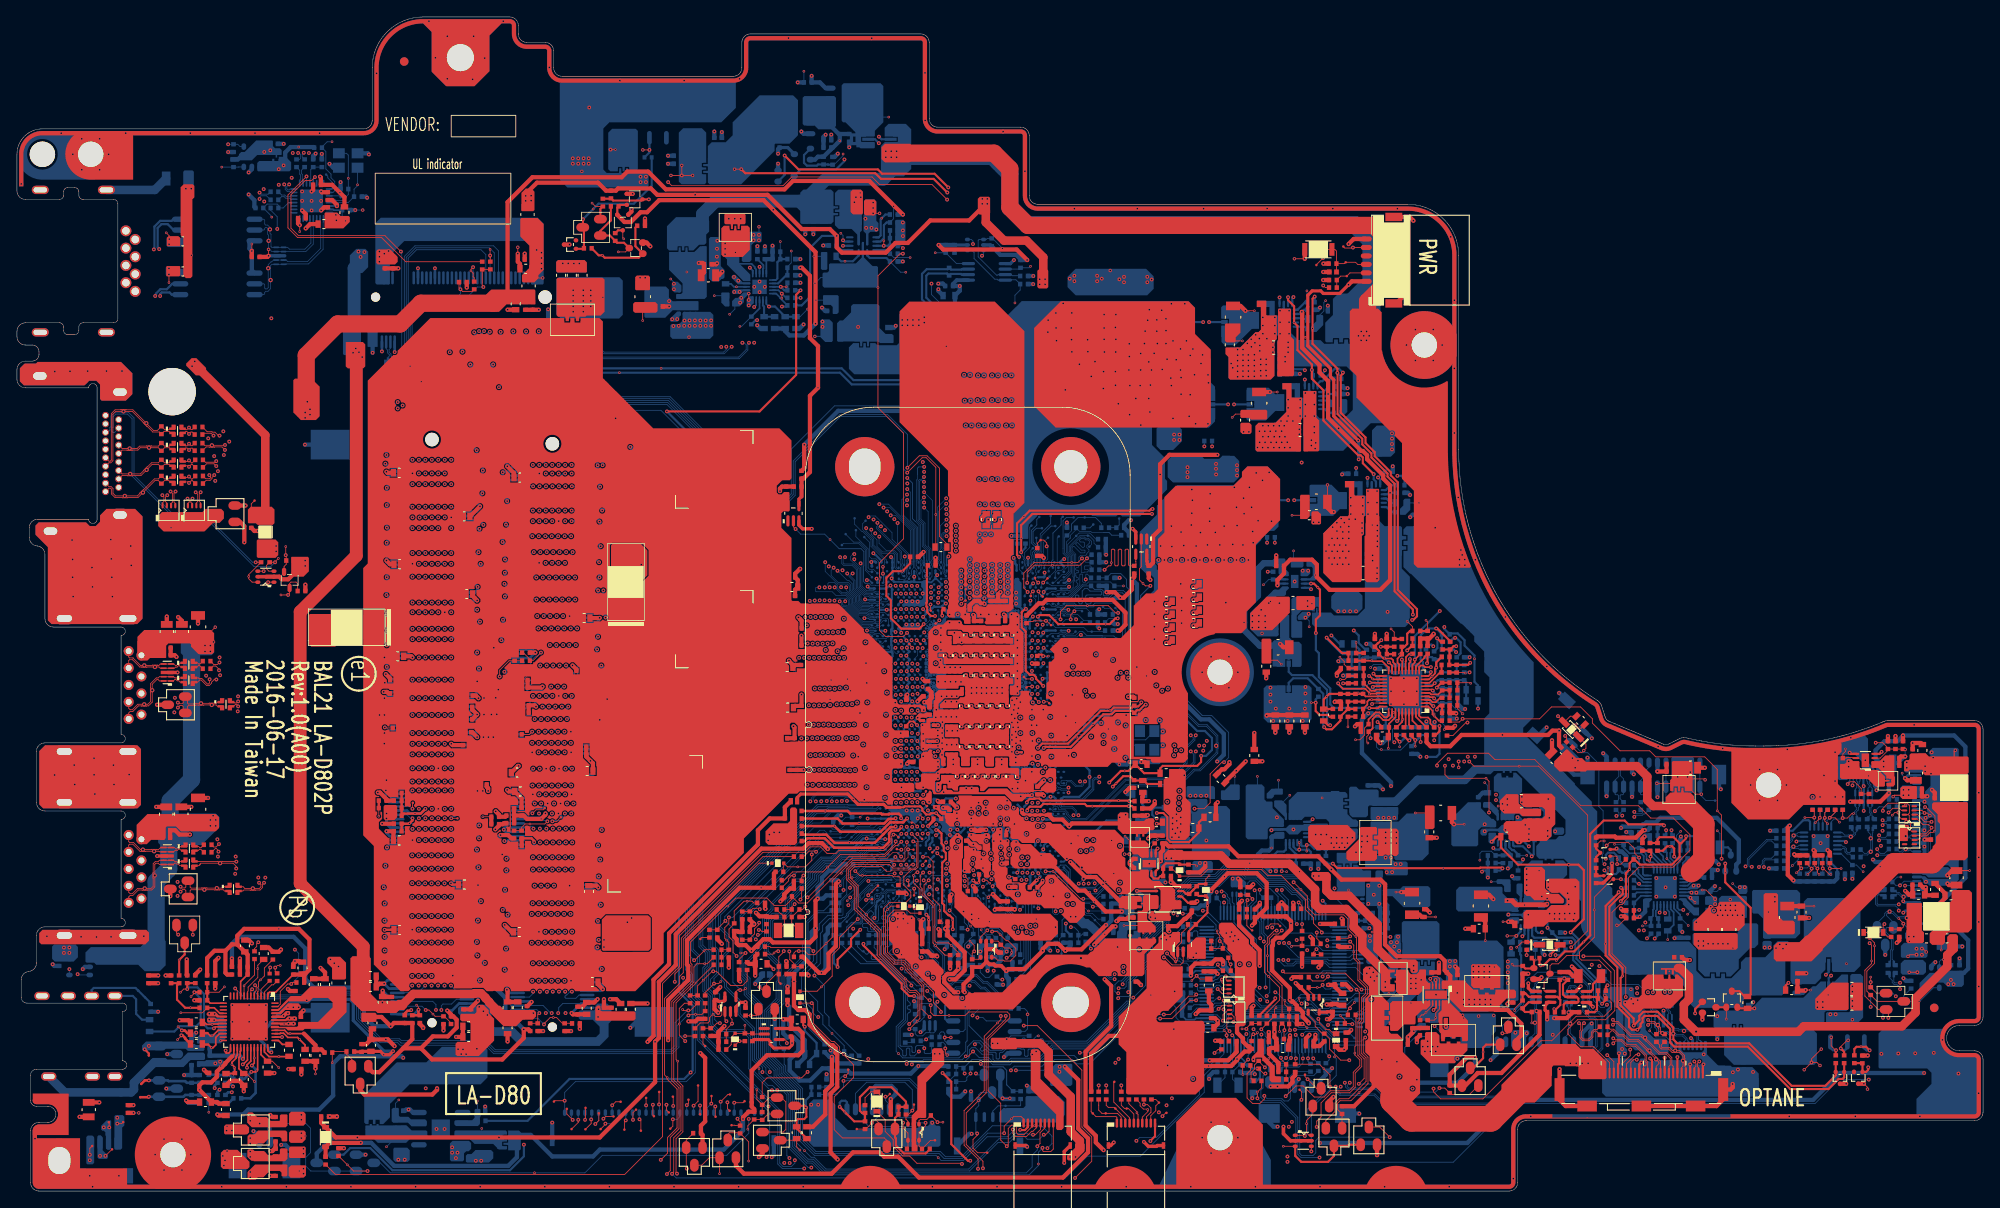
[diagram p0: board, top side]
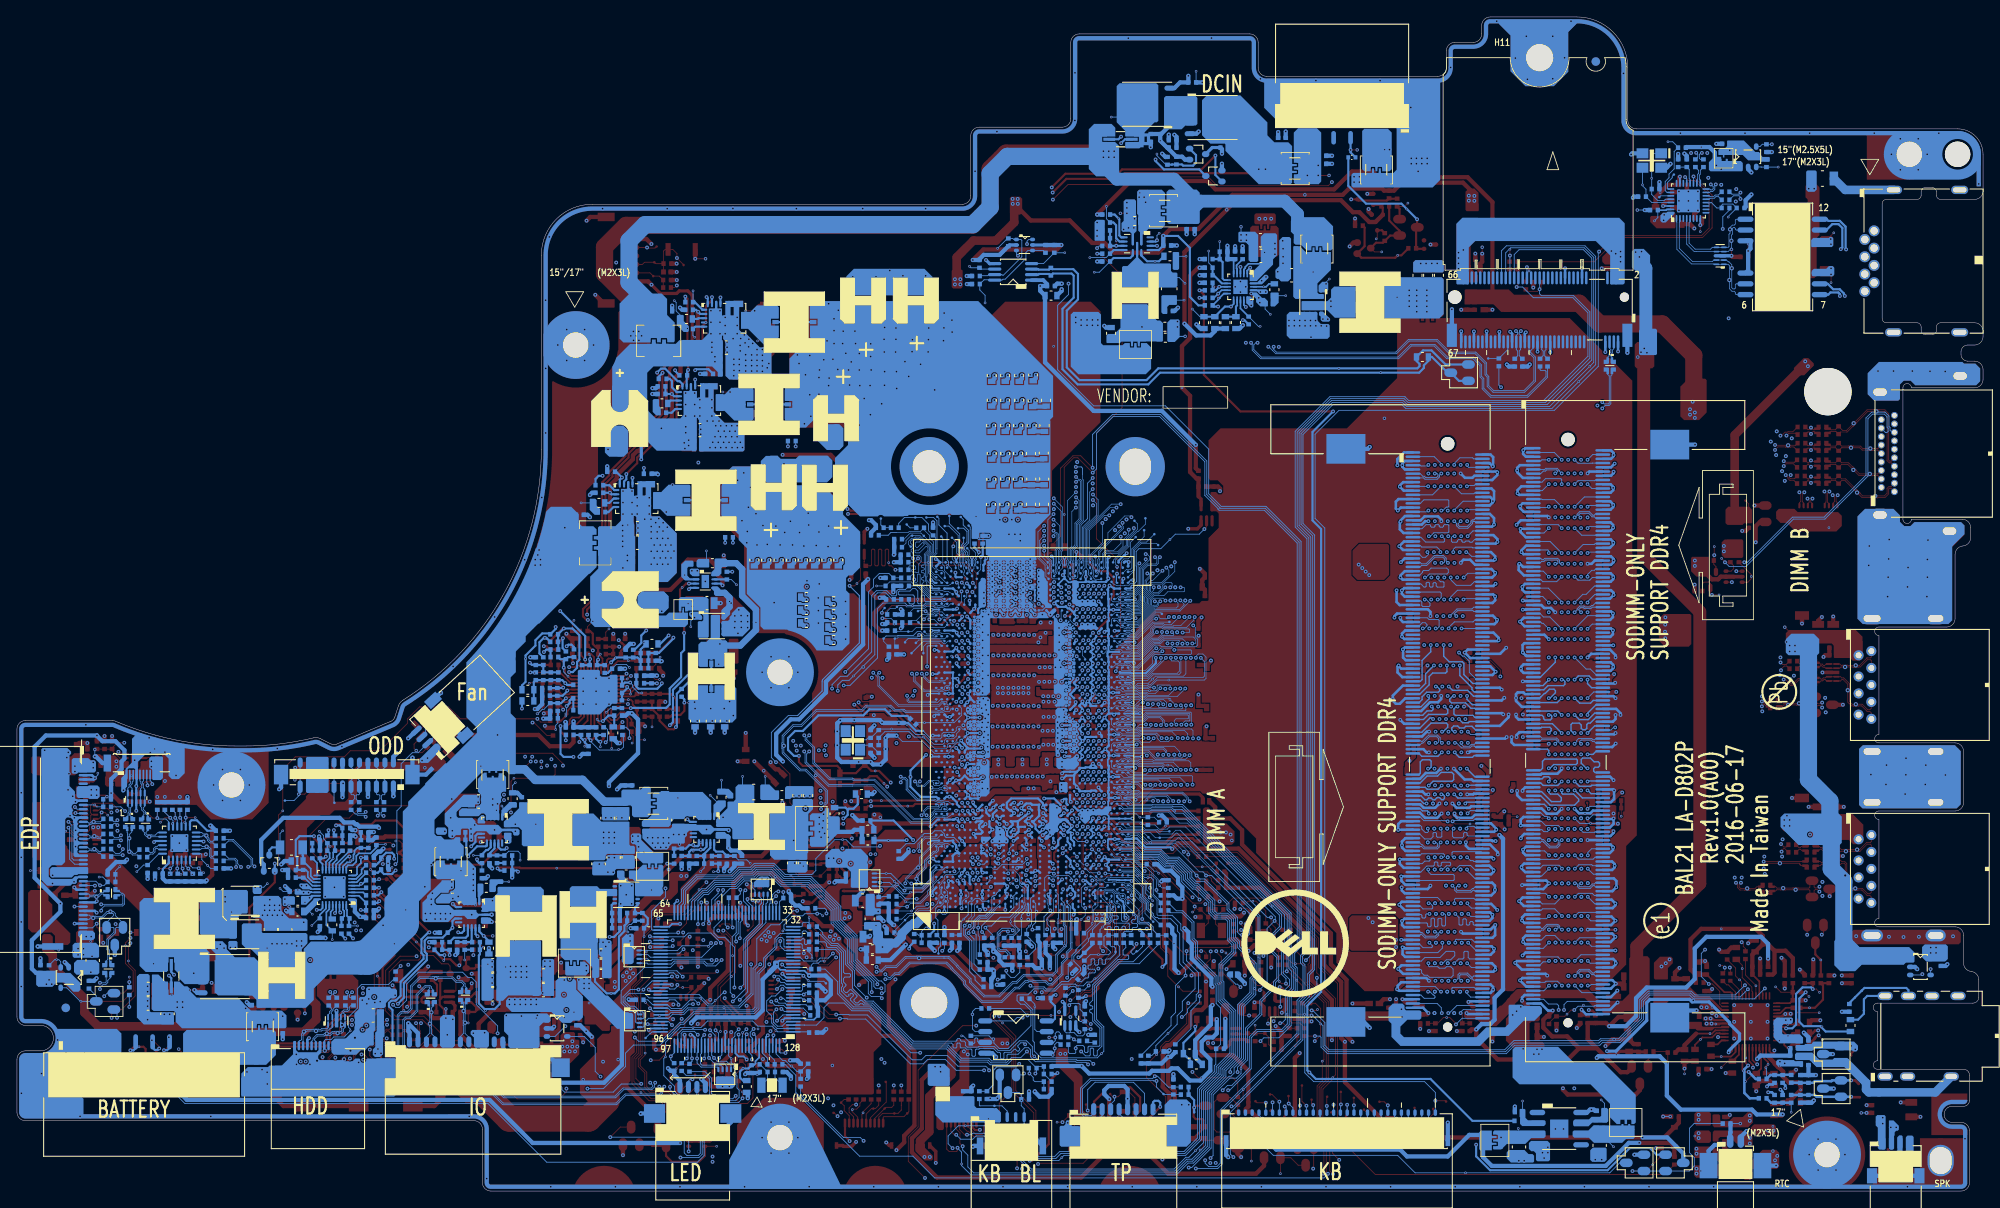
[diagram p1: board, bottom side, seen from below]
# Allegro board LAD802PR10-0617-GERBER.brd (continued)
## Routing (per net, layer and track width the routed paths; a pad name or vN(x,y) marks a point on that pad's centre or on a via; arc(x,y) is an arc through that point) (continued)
V3D3_STB: length 11.1
  TOP w0.102: v1(19.29,23.45) 19.67,23.83 v2(20.08,23.83)
  TOP w0.203: UA1.20 23.4,19.36 v2(23.23,19.2)
  TOP w0.254: RA12.1 RA11.1 v2(20.08,23.83)
  BOTTOM w0.254: v2(23.23,19.2) 22.5,19.2 22.05,19.64 22.05,23.26 21.29,24.02 20.28,24.02 v2(20.08,23.83)
VCC_EDRAM_SENSE: length 2.5
  TOP w0.102: TP34.1 111.91,70.44 112.36,69.98 v2(112.36,69.95)
  BOTTOM w0.076: UC1.AC63 111.84,69.21 112.36,69.73 v2(112.36,69.95)
VCC_GT_SENSE: length 95.6
  TOP w0.254: v2(118.45,75.37) v1(118.45,76.98) 118.45,78.55 119.77,79.88 v2(133.88,79.88) ; PC617.1 168.1,59.97 PR622.1 168.02,59.96 167.47,59.41 v2(167.47,59.38)
  IN1 w0.254: v2(133.88,79.88) 133.88,77.37 132.61,76.1 132.61,64.18 135.36,61.44 137.05,61.44 140.28,58.21 143.73,58.21 147,54.95 152,54.95 153.79,56.74 153.79,62.89 155.83,64.93 157.99,64.93 159.88,66.82 164.1,66.82 165.74,65.18 165.74,61.69 166.1,61.33 166.1,60.65 166.35,60.39 167.42,60.39 167.72,60.09 167.72,59.64 167.47,59.39 v2(167.47,59.38)
  BOTTOM w0.076: v2(118.45,75.37) 118.45,75.14 118.57,75.01 118.57,74.94 118.69,74.82 118.69,74.52 118.72,74.49 118.72,74.49 118.86,74.35 118.86,74.06 118.81,73.92 118.81,73.75 UC1.J70
  BOTTOM w0.254: v2(118.45,75.37) 118.96,75.88 RC155.2 ; PC618.2 168.18,59.33 PC620.1 167.51,59.35 167.48,59.38 v2(167.47,59.38)
VCCEOPIO_SENSE: length 1.3
  TOP w0.102: v2(107.75,69.2) 107.75,68.5 TP36.1
  BOTTOM w0.076: v2(107.75,69.2) 107.52,68.96 UC1.AL63
VCCIO_SENSE: length 1.1
  TOP w0.102: v2(106.89,46.75) 107.21,47.08 TP38.1
  BOTTOM w0.076: v2(106.89,46.75) 107.21,47.08 TP38.1
VCCSA_B+:
  vias: v1(152.74,69.3) v2(152.23,69.61) v2(152.23,68.98)
VCCSENSE: length 56
  TOP w0.254: v2(133.14,57.38) 133.04,57.38 132.38,56.72 132.09,56.72 RC150.2 131.54,56.65 129.53,56.65 129.12,56.24 128.13,56.24 v1(126.92,55.04) 124.28,52.4 121.24,52.4 v2(121.12,52.28) ; PR648.1 PC653.1 161.56,63.35 PC651.2 ; PC639.1 PC651.2 ; PC651.2 v2(160.87,64.21)
  IN1 w0.254: v2(133.14,57.38) 136.12,57.38 138.72,54.78 143.9,54.78 145.55,53.13 152.22,53.13 153.19,54.1 153.19,54.53 154.93,56.27 154.93,60.76 155.53,61.36 159,61.36 159,61.36 159.21,61.36 160.55,62.69 160.55,63.89 v2(160.87,64.21)
  BOTTOM w0.254: UC1.E32 120.75,51.91 v2(121.12,52.28)
VCCSENSE_VCCGTUS: length 7.3
  TOP w0.254: RC157.2 107.33,73.69 v1(107.33,72.41) 107.33,69.45 107.27,69.4 107.27,68.94 107.36,68.85 107.36,68.28 107.8,67.84 v2(108.29,67.84)
  BOTTOM w0.076: v2(108.29,67.84) 108.29,67.96 108.02,68.23 UC1.AK62
VCCST_PWRGD: length 24.4
  BOTTOM w0.076: UC1.B65 122.85,70.4 123.11,70.66 123.64,70.66 123.83,70.47 123.94,70.47 124.02,70.54 124.02,70.58 124.09,70.66 124.26,70.66 124.92,71.32 124.96,71.32 125.13,71.49 125.13,71.66 124.92,71.86 124.92,72 125,72.08 125.12,72.08 125.19,72.15 125.19,72.31 125.12,72.38 125,72.38 124.92,72.46 124.92,72.57 124.88,72.61 124.88,72.85 124.96,72.93 125.13,72.93 125.2,73.01 125.2,73.16 125.13,73.24 124.96,73.24 124.88,73.31 124.88,73.46 124.96,73.54 125.13,73.54 125.2,73.62 125.2,73.77 125.13,73.85 124.96,73.85 124.88,73.92 124.88,75.12 124.44,75.56 124.44,75.91 124.57,76.04 124.68,76.04 125.44,75.28 125.89,75.28 125.98,75.36 125.98,75.55 125.92,75.6 125.55,75.6 124.9,76.26 124.9,76.36 125.01,76.47 125.13,76.47 125.68,75.92 125.79,75.92 125.92,76.04 125.92,76.46 125.82,76.56 125.46,76.56 125.33,76.69 125.33,76.8 125.51,76.98 125.86,76.98 126.03,76.81 126.34,76.81 126.48,76.67 126.48,76.43 126.19,76.14 126.19,75.89 126.44,75.65 126.44,75.46 126.19,75.22 126.19,75.13 126.06,75 125.47,75 125.25,74.78 125.25,74.25 125.53,73.97 125.53,73.02 125.61,72.94 125.82,72.94 125.9,73.02 126.25,73.02 126.36,73.13 126.36,73.26 126.28,73.34 125.95,73.34 125.9,73.39 125.9,73.67 125.98,73.75 126.61,73.75 126.75,73.6 RC96.2
VCCSTG_EN: length 7
  TOP w0.254: UC9.4 138.21,30.63 RZ2.2 140.42,32.83 v1(140.42,33.67) 140.42,34.62 DZ2.1 139.38,34.81 RZ3.1
VCCSTG_EN_R: length 4.9
  TOP w0.102: v1(140.61,37.19) 140.23,36.81 DZ2.2
  TOP w0.254: DZ2.2 139.4,36.21 RZ3.2 139.15,35.94 138.77,35.55 138.76,35.55 138.61,35.41 138.61,35.4 CZ7.1 137.9,35.05 137.55,35.4 UZ2.4
VDD_1.2V: length 9.4
  IN1 w0.254: v2(88.7,104.34) 88.7,104.15 v2(87.3,102.74)
  BOTTOM w0.102: v1(93.26,104.04) 92.36,103.14 PC209.1
  BOTTOM w0.203: PU200.11 88.39,104.65 v2(88.7,104.34)
  BOTTOM w0.254: v2(88.7,104.34) 89.42,104.34 PR206.2 PC209.1 ; v2(87.3,102.74) 87.12,102.74 PR205.1
VDD_CHG: length 29
  TOP w0.254: 196.11,41.03 196.11,39.41 195.21,38.51 191.41,38.51 190.8,39.12 PR781.1 190.2,38.65 v1(190.2,37.93) 189.78,37.51 189.78,34.81 v2(189.17,34.2) ; 196.11,41.03 195.39,41.74 193.76,41.74 193.5,41.49 PR749.2 PR750.2 ; 196.11,41.03 196.29,41.03 196.87,41.61 v2(196.87,41.86)
  BOTTOM w0.203: PU703.19 196.99,36.43 197.59,37.03 197.59,37.64 197.83,37.88 PR760.1
  BOTTOM w0.254: v2(196.87,41.86) 198.57,41.86 199.01,41.42 199.01,39.52 198.84,39.34 198.84,38.05 PC768.2 198.88,37.88 PR760.1 ; PR741.1 189.37,34 v2(189.17,34.2)
VDDP_CHG: length 2.9
  BOTTOM w0.203: PU703.20 197.06,36.03 198,36.97 PR760.2
  BOTTOM w0.254: PC769.2 198.88,36.97 PR760.2
VIN_+VCCEOPIO:
  vias: v1(99.46,117.75) v2(98.78,116.64) v2(98.95,117.24) v2(99.54,117.24)
VSS_EDRAM_SENSE: length 1.3
  TOP w0.102: TP35.1 111.78,69.66 v2(111.39,69.27)
  BOTTOM w0.076: UC1.AE63 111.08,68.96 v2(111.39,69.27)
VSS_GT_SENSE: length 97.9
  TOP w0.203: PU602.6 166.88,59.16 v2(166.99,59.04)
  TOP w0.254: v2(133.94,80.46) 133.78,80.46 133.58,80.26 119.46,80.26 v1(118.77,79.58) 117.95,78.75 117.95,75.05 v2(118.2,74.8)
  IN1 w0.254: v2(133.94,80.46) 133.78,80.46 133.4,80.08 133.4,77.43 132.23,76.26 132.23,64.03 135.2,61.05 136.9,61.05 140.12,57.83 143.57,57.83 146.84,54.56 152.15,54.56 154.17,56.58 154.17,62.73 155.99,64.55 158.15,64.55 160.04,66.44 163.95,66.44 165.36,65.02 165.36,61.53 165.69,61.2 165.69,60.34 v2(166.99,59.04)
  BOTTOM w0.076: v2(118.2,74.8) 118.2,73.96 118.26,73.91 118.26,73.29 118.59,72.95 UC1.J69
  BOTTOM w0.254: PC619.2 169.03,58.43 PC620.2 167.53,58.43 166.99,58.97 v2(166.99,59.04) ; RC156.1 117.99,76.37 117.99,75.01 v2(118.2,74.8)
VSSEOPIO_SENSE: length 1.8
  TOP w0.102: v2(108.8,67.33) 108.41,66.95 TP37.1
  BOTTOM w0.076: UC1.AJ62 108.74,68.39 108.74,67.38 v2(108.8,67.33)
VSSIO_SENSE: length 1.2
  TOP w0.102: TP39.1 107.28,45.42 v2(106.89,45.81)
  BOTTOM w0.076: v2(106.89,45.81) 106.89,45.93 UC1.AM22
VSSSENSE: length 59.2
  TOP w0.203: PU602.18 162.59,62.11 162.33,62.38 162.33,62.62 162.12,62.82 161.17,62.82 PC653.2
  TOP w0.254: v2(120.43,52.29) 120.92,52.78 123.97,52.78 127.83,56.65 v1(128.93,56.65) 128.99,56.65 129.37,57.03 131.54,57.03 RC151.1 131.89,57.17 132.25,57.17 132.62,57.54 v2(132.62,57.65) ; v2(160.92,64.99) 160.56,64.62 160.51,64.62 160.17,64.28 PC654.2 160.66,63.71 PC653.2
  IN1 w0.254: v2(132.62,57.65) 132.92,57.94 136.61,57.94 139.26,55.29 143.93,55.29 145.7,53.51 152.06,53.51 152.81,54.26 152.81,54.69 154.55,56.43 154.55,60.92 155.37,61.74 159.01,61.74 160.1,62.83 160.1,64.17 v2(160.92,64.99)
  BOTTOM w0.254: v2(120.43,52.29) 120.43,52.33 UC1.E33
VSSSENSE_VCCGTUS: length 15.2
  TOP w0.254: RC158.1 105.35,74.05 v1(104.43,73.12) 103.33,73.12 102.54,72.33 102.54,70.21 103.07,69.69 103.07,67.58 104.32,66.33 106.44,66.33 106.95,66.85 v2(106.95,66.88)
  BOTTOM w0.076: v2(106.95,66.88) 107.23,66.88 107.69,67.34 UC1.AL61
3D_CAM_EN: length 211.2
  TOP w0.102: RX3.1 220.68,52.27 220.07,52.89 219.25,52.89 v2(219.24,52.88) ; RX3.1 220.68,51.98 219.77,51.07 UX1.3 ; RX3.1 RX2.2 RX1.2 ; DX2.2 105.37,32.78 105,33.15 103.45,33.15 102.68,32.38 102.68,28.19 103.63,27.23 104.63,27.23 105.22,26.64 105.22,26.32 108.1,23.45 108.1,22.22 108.99,21.33 v2(108.99,21.13) ; v2(183.32,28.75) 185.26,30.69 185.26,44.33 179.48,50.12 v1(177.19,50.12) 171.85,50.12 v2(171.3,50.67)
  IN1 w0.127: v2(183.32,28.75) 177.98,28.75 176.3,27.07 176.3,24.02 176.17,23.89 170.07,23.89 166.07,27.89 159.08,27.89 158.07,26.89 155.29,26.89 154.55,27.64 v2(154.55,28.9) 155,29.35 155,31.88 154.41,32.47 154.2,32.47 152.81,32.47 152.23,33.05 150.22,33.05 149.99,32.82 144.49,32.82 144.31,33 141.49,33 139.26,30.78 137.74,30.78 135.92,28.96 134.86,28.96 131.02,25.13 130.2,25.13 129.22,24.15 129.22,20.99 126.49,18.26 118.14,18.26 117.32,19.07 111.04,19.07 v2(108.99,21.13)
  IN2 w0.127: v2(219.24,52.88) 218.36,52.88 216.59,51.11 213.24,51.11 210.67,48.55 210.67,46.58 209.03,44.94 202.74,44.94 199.25,48.43 195.71,48.43 192.95,51.19 189.92,51.19 188.06,53.04 186.5,53.04 186.05,52.6 172.61,52.6 171.55,51.53 171.55,50.92 v2(171.3,50.67)
  BOTTOM w0.102: UE1.71 154.67,28.78 v2(154.55,28.9)
3D_CAM_EN_PCH: length 4.7
  TOP w0.102: v2(106.22,37.61) 106.07,37.61 105.73,37.28 v1(105.73,37.23) 105.73,36.38 106.51,35.6 DX2.1
  BOTTOM w0.076: UC1.AN7 106.56,37.27 v2(106.22,37.61)
+DCBAT_CAM: length 5.1
  TOP w0.508: v2(222.7,48.7) 222.95,48.45 R51.1
  BOTTOM w0.102: v1(222.36,49.29) 222.36,49.08 222.7,48.74 v2(222.7,48.7)
  BOTTOM w0.305: JEDP1.3 223.05,49.05 v2(222.7,48.7) 222.85,48.55 JEDP1.4
+DCBAT_LCD: length 1.9
  TOP w0.127: v4(228.63,52) 228.49,51.86 F1.2
  vias: v2(222.91,50.56) v2(222.91,49.93) v2(225.06,50.12) v2(225.06,49.48) v4(225.76,49.23) v4(226.02,51.14)
+LAN_VDD10: length 12.9
  TOP w0.102: v2(33.35,113.95) v1(33.35,113.18)
  TOP w0.508: CL6.1 37.17,116.91 37.74,116.34 v2(37.74,116.19) ; v2(33.35,113.95) 33.15,114.14 CL5.1
  IN1 w0.508: v2(33.35,113.95) 33.6,114.19 35.9,114.19 36.34,113.75 37.9,113.75 38.56,114.41 38.56,115.66 38.03,116.19 v2(37.74,116.19)
  BOTTOM w0.203: UL1.8 v2(33.35,113.95) ; v2(37.74,116.19) 37.74,116.2 UL1.30
+LAN_VDD33: length 13.1
  IN1 w1.016: 36.79,116.1 36.79,118.22 36.6,118.41 36.6,119.28 36.62,119.3 36.62,120.02 36.11,120.52 36.11,120.52 36.02,120.6 32.28,120.6
  BOTTOM w0.508: RL1.1 34.99,123.15 v1(33.23,123.15) 32.28,123.15 31.64,122.52 31.64,121.75
  vias: v2(30.88,120.55) v2(31.45,120.99) v2(37.61,115.15) v2(37.68,114.51)
+LAN_VDDREG: length 6.3
  TOP w0.508: v2(35.75,119.66) 35.85,119.56 CL14.1 37.17,118.7 v1(38.09,117.78) 38.63,117.24 RL5.2
  BOTTOM w0.203: UL1.23 v2(35.75,119.66)
+LCDVDD: length 1
  TOP w0.102: v2(224.15,25.81) v4(223.18,25.81)
+LCDVDD_LCD: length 3
  TOP w0.102: v2(224.69,28.6) 224.8,28.6 v4(225.2,28.2) ; v2(224.05,27.88) 223.24,27.88 v4(223.04,27.68)
  TOP w0.127: v4(221.29,46.53) 221.46,46.69 v2(222.5,46.69)
  vias: v2(222.51,47.33) v2(223.13,47.34) v2(223.13,46.7) v2(224.05,28.59) v2(224.69,27.86)
+LINE1_VREFO_L: length 7.6
  TOP w0.203: UA1.31 27.59,15.33 27.13,14.88 v2(27.13,14.56)
  IN2 w0.305: v2(23.9,11.96) 25.24,13.3 25.61,13.3 26.74,14.44 27.01,14.44 v2(27.13,14.56)
  BOTTOM w0.305: v2(23.9,11.96) 23.64,11.7 RA29.1
+LINE1_VREFO_R: length 7.5
  TOP w0.203: v2(26.64,14.95) 26.69,14.95 27.19,15.44 UA1.30
  IN2 w0.305: v2(23.32,12.15) 23.39,12.15 23.39,12.17 23.69,12.46 23.79,12.46 25.06,13.73 25.43,13.73 v2(26.64,14.95)
  BOTTOM w0.305: v2(23.32,12.15) 23.32,12.46 23.63,12.77 RA33.1
+MIC2-VREFO: length 6.3
  TOP w0.203: v2(26.65,15.58) 26.79,15.72 UA1.29
  BOTTOM w0.508: RA26.1 RA25.1 26.25,15.98 v2(26.65,15.58)
+RTC_CELL: length 261.3
  TOP w0.508: v2(85.3,24.72) 85.17,24.85 RC91.2 ; C1.1 35.88,8.04 D2.1 37.6,6.32 v2(40.15,6.32) v4(56.85,6.32) 68.74,6.32 75.27,12.85 v2(75.27,17.61) 75.71,18.05 75.71,24.66 77.71,26.65 77.71,30.29 87.81,40.39 CC71.1 CC70.1 92.74,40.39 93.39,41.04 94.95,41.04 v2(95.64,40.35) ; v2(21.61,26.12) 21.04,25.55 RA12.2 ; RE30.2 143.86,16.41 142.87,15.43 v2(140.69,15.43) ; RC78.2 91.64,25.6 RC77.2 91.65,24.72 v2(91.65,24.72) 91.65,24.72 91.65,21.86 92.16,21.35 92.98,21.35 93.49,20.85 93.49,19.61 95.91,17.2 96.22,17.2 96.58,16.84 96.58,16.34 96.54,16.3 96.75,16.09 96.75,12.29 95.97,11.5 95.97,4.55 v2(96.79,3.73)
  IN1 w0.432: v2(140.69,15.43) 140.97,15.43 142.13,14.27 144.98,14.27 145.44,13.81 145.44,11.22 v2(145.7,10.95)
  IN1 w0.508: v2(75.27,17.61) 75.71,17.61 78.58,20.47 78.58,21.56 78.94,21.92 79.39,21.92 79.39,21.93 82.22,21.93 82.63,22.34 83.33,22.34 84.69,23.7 84.69,24.21 85.2,24.72 v2(85.3,24.72) 85.68,24.72 87.08,23.32 88.09,23.32 89.49,24.72 v2(91.65,24.72) ; v2(21.61,26.12) 27.19,26.12 28.4,24.91 31.97,24.91 32.1,25.04 37.73,25.04 42.75,20.02 42.75,8.93 40.15,6.34 v2(40.15,6.32) ; v2(140.69,15.43) 139.34,14.07 139.34,12.15 134.4,7.21 127.15,7.21 126.17,6.22 123.94,6.22 121.9,4.19 115.68,4.19 114.92,4.95 109.2,4.95 107.98,3.73 v2(96.79,3.73)
  IN2 w0.254: v2(100.22,41.59) 100.63,42.01 100.91,42.01 103.35,44.44 104.88,44.44 104.89,44.44 105.85,44.44 105.86,44.43 106.5,44.43 106.99,44.91 v2(107.45,44.91)
  BOTTOM w0.254: UC1.BB14 101.15,41.54 101.06,41.54 101.03,41.55 100.27,41.55 100.22,41.6 v2(100.22,41.59) 99.81,41.59 98.76,40.54 95.83,40.54 v2(95.64,40.35) ; UC1.AK19 107.98,44.32 107.45,44.84 v2(107.45,44.91)
  BOTTOM w0.508: v2(140.69,15.43) 139.86,15.43 139.74,15.31 RE41.1 ; v2(40.15,6.32) 37.25,6.32 35.36,4.44 D1.1 ; v2(145.7,10.95) 145.7,11.52 RE7.2
+RTC_CELL_VBAT: length 6.2
  BOTTOM w0.203: UE1.122 144.36,15.75 144.79,15.32 144.79,15.04 144.99,14.84 CE14.1
  BOTTOM w0.254: RE7.1 146.26,13.04 146.62,13.39 146.62,14.1 v1(146.26,14.46) 145.64,14.46 CE14.1
+RTC_VCC: length 3.2
  BOTTOM w0.102: R1.2 v4(28.63,7.96)
  BOTTOM w0.508: R1.2 29.79,6.93 29.83,6.89 JRTC1.1
+TP_VDD: length 40.8
  TOP w0.254: Q12.1 92.85,10.06 v2(93.05,9.86) 93.11,9.8 93.11,8.74 92.86,8.49 92.1,8.49 91.97,8.36 R37.2 91.97,7.39 R36.2 ; R46.1 107.67,4.91 107.19,4.44 104.62,4.44 103.66,5.39 103.66,6.23 103.56,6.33 Q9.2 103.56,8.62 R40.1 C19.1 104.85,9.93 R47.1 104.86,10.54 103.16,12.24 100.59,12.24 99.42,11.08 99.42,9.47 99.68,9.21 R41.1 R39.1 98.75,8.22 v1(97.65,9.32) v2(97.05,9.93)
  IN1 w0.254: v2(97.05,9.93) 96.82,9.7 93.21,9.7 v2(93.05,9.86)
  BOTTOM w0.254: v2(97.05,9.93) 97.05,10.43 97.26,10.65 97.72,10.65 97.9,10.47 JTP1.8 ; R31.1 R32.1 93.05,10.72 v2(93.05,9.86) ZT59.1
+TPAN_VDD:
  vias: v1(223.21,29.46) v2(223.15,30.02) v2(223.73,30.02)
+TPAN_VDD_F: length 1.4
  TOP w0.102: R12.2 v1(226.97,28.43)
+V_DDR_REFA: length 9.7
  TOP w0.508: RD10.2 58.63,44.3 RD12.1 ; RD9.2 RD12.1 ; RD12.1 58.65,44.3 CD28.1 59.76,44.3 60.15,43.9 v1(61.83,43.9) 62.34,44.4 v2(62.34,44.54)
  BOTTOM w0.305: JDIMM1.164 59.94,44.38 60.28,44.03 62.03,44.03 62.34,44.34 v2(62.34,44.54)
+V_DDR_REFA_R: length 154.7
  TOP w0.102: v4(102.15,73.64) v2(102.15,72.82)
  TOP w0.508: RD9.1 57.43,43.39 57.3,43.27 CD30.1 56.86,43.11 v2(56.43,42.67)
  IN1 w0.381: v2(102.15,72.82) 103.09,73.77 108.34,73.77 109.14,74.57 109.14,75.31 110.18,76.35 110.18,77.22 110.19,77.22 110.19,79.51 110.54,79.87
  IN1 w0.508: 110.54,79.87 110.54,86.51 103.5,93.56 91.6,93.56 90.9,92.86 48.41,92.86 40.98,85.43 40.98,52.22 42.44,50.75 52.34,50.75 53.61,49.48 53.61,45.48 v2(56.43,42.67)
  BOTTOM w0.152: v2(102.15,72.82) 102.22,72.75 102.22,71.83 UC1.AY67
+V_DDR_REFB: length 9.5
  TOP w0.305: RD20.2 RD19.2 RD21.1 CD58.1 45.62,44.53 v1(46.95,44.53) 47.62,44.53 v2(48.17,45.09)
  BOTTOM w0.305: JDIMM2.164 46.01,44.87 46.32,44.57 47.65,44.57 v2(48.17,45.09)
+V_DDR_REFB_R: length 143.7
  TOP w0.508: RD19.1 CD59.1 43.59,46.23 42.82,47.01 v2(42.57,47.01)
  IN1 w0.381: v2(101.39,72.24) 102.36,72.24 103.38,73.26 109.23,73.26 111.4,75.42 111.4,81.36
  IN1 w0.508: 111.4,81.36 111.4,86.56 103.76,94.2 91.34,94.2 90.63,93.49 47.83,93.49 40.12,85.78 40.12,48.43 41.49,47.07 42.5,47.07 v2(42.57,47.01)
  BOTTOM w0.254: UC1.BA67 101.5,72.13 v2(101.39,72.24)
AC_DIS: length 219.8
  TOP w0.254: v2(109.85,118.39) 108.23,120.01 102.05,120.01 101.54,120.52 92.18,120.52 v2(90.55,122.15)
  IN1 w0.127: v2(170.7,50.67) 170.7,49.28 174.28,45.7 174.63,45.7 176.01,47.09 177.65,47.09 180.64,44.09 181.3,44.09 183.98,41.41 183.98,39.72 184.36,39.34 184.36,33.59 185.95,32.01 185.95,26.89 v2(185.75,26.69)
  IN2 w0.127: v2(154.55,29.58) 155.21,28.91 155.21,28.55 156.7,27.07 165.76,27.07 169.5,23.32 174.01,23.32 174.84,22.5 179.69,22.5 182.17,24.97 184.03,24.97 v2(185.75,26.69)
  IN2 w0.254: v2(109.85,118.39) 111.67,116.58 111.67,115.54 113.75,113.45 160.23,113.45 162.96,110.72 162.96,96.97 168.54,91.4 168.54,73.78 169.18,73.13 169.18,73.13 174.29,68.02 174.39,67.87 174.39,55.45 174.29,55.36 174.29,55.35 170.58,51.63 170.58,50.79 v2(170.7,50.67)
  BOTTOM w0.102: UE1.69 v2(154.55,29.58)
  BOTTOM w0.254: v2(90.55,122.15) 90.55,119.86 PQ712.2
AC_PRESENT: length 15.3
  TOP w0.102: v2(93.75,39.71) 93.75,39.01 92.98,38.25 v1(92.1,38.25) 90.88,38.25 DZ1.2 90.39,38.63 RC90.1
  BOTTOM w0.076: v2(93.75,39.71) 93.75,40.04 94.89,41.18 98.39,41.18 99.55,42.34 101.65,42.34 101.84,42.14 UC1.AY15
ACAV_IN: length 201.8
  TOP w0.102: v2(141.25,16.29) 141.68,16.71 CE32.2 ; v2(75.94,3.68) 76.73,4.46 76.73,6.31 77.86,7.44 77.86,12.03 76.7,13.19 v1(76.7,13.38) 76.37,13.71 76.37,22.7 78.17,24.5 78.17,25.32 78.59,25.75 78.59,29.74 87.53,38.68 DZ1.1
  TOP w0.254: v2(187.6,24.28) 187.41,24.08 PR12.1
  IN1 w0.127: v2(149.85,4.07) 152.73,4.07 153.28,4.63 154.51,4.63 161.58,11.7 161.58,13.48 163.42,15.32 166.98,15.32 171.35,19.69 178.38,19.69 181.07,22.37 184.93,22.37 186.84,24.28 v2(187.6,24.28) ; 134.7,9.29 133.07,7.65 126.97,7.65 125.98,6.67 123.75,6.67 121.72,4.64 115.86,4.64 115.11,5.39 107.28,5.39 106.55,4.65 91.05,4.65 89.38,2.98 87.12,2.98 86.43,3.68 v2(75.94,3.68) ; 134.7,9.29 135.17,9.76 135.17,10.29 135.42,10.53 135.85,10.53 135.86,10.52 136.62,10.52 138.06,11.96 138.06,13.78 140.43,16.15 141.11,16.15 v2(141.25,16.29) ; 134.7,9.29 v2(134.69,9.29)
  IN2 w0.127: v2(134.69,9.29) 134.7,9.29 134.26,8.84 134.26,4.44 135.82,2.88 148.65,2.88 149.85,4.07 v2(149.85,4.07)
  IN2 w0.254: v2(187.6,24.28) 188.17,24.85 188.17,29.95 191.35,33.12 v2(191.35,33.17)
  BOTTOM w0.102: UE1.128 141.96,16.39 141.86,16.29 v2(141.25,16.29)
  BOTTOM w0.203: PU703.2 191.55,34.83 PR741.2 PR731.1 191.29,33.11 v2(191.35,33.17)
ACIN_CHG: length 170.7
  TOP w0.254: v2(191.41,32.35) 191.27,32.21 PR729.2 PC711.2
  IN1 w0.508: v2(191.41,32.35) 191.23,32.35 190.33,33.25 190.33,34.5 190.06,34.77 190.06,38.84 189.29,39.61 189.29,40.67 187.94,42.02 187.94,43 182.93,48.01 182.27,48.01 173.29,57 173.29,63.68 172.29,64.68 172.29,65.3 165.73,71.86 165.73,87.84 159.63,93.93 159.63,96.5 156.79,99.34 156.79,104.79 158.34,106.35 158.34,111.76 157.77,112.34 110.36,112.34 103.53,119.17 100.12,119.17 v2(97.6,121.69)
  BOTTOM w0.254: PQ712.1 92.45,120.52 96.62,120.52 97.6,121.5 v2(97.6,121.69)
  BOTTOM w0.508: PR732.1 190.85,32.35 v2(191.41,32.35) 191.44,32.35 192.04,32.95 192.04,33.81
ACLIM: length 5.5
  TOP w0.254: v2(195.47,39.46) 195.47,40.41 195.22,40.66 v1(194.97,40.66) 194.65,40.66 194.13,40.14 PR749.1
  BOTTOM w0.203: v2(195.47,39.46) 195.67,39.25 PR751.2 196.17,38.88 195.86,38.57 PU703.16
ADJ_2.5V: length 1.4
  BOTTOM w0.102: v1(45.04,10.75) 44.64,10.35 PR802.1
ALERT#: length 3.1
  BOTTOM w0.102: v1(119.55,109.09) 119.38,108.91 R28.2 118.21,108.76 U2.6
ALL_SYS_PWRGD: length 131.6
  TOP w0.102: v2(133.69,71.39) 133.1,71.39 v1(132.82,71.67) 132.4,72.09 132.4,73.43 132.61,73.64 UC7.2 ; v2(142.37,50.59) 142.13,50.59 140.74,49.19 140.74,45.8 140.04,45.1 v2(138.89,45.1) ; UC6.4 90.58,17.87 90.81,17.65 v2(90.81,17.46)
  IN1 w0.127: v2(138.89,45.1) 138.89,41.39 136,38.5 134.26,38.5 133.72,37.96 129.49,37.96 129.48,37.96 129.46,37.96 128.3,36.8 128.3,34.67 127.59,33.97 126.67,33.97 125.69,32.98 125.69,32.05 125.67,32.04 125.67,32.03 125.21,31.56 125.2,31.56 124.77,31.13 v2(124.31,31.13) 123.49,31.13 122.79,31.83 122.2,31.83 122,32.03 122,33.1 121.31,33.8 119.53,33.8 118.44,32.72 116.87,32.72 115.99,33.59 112.21,33.59 110.64,32.02 108.16,32.02 107.19,31.05 100.22,31.05 100.01,31.26 98.89,31.26 98.64,31.01 v2(98.64,30.94)
  IN2 w0.127: v2(98.64,30.94) 98.64,30.81 95.46,27.63 95.46,25.04 93.25,22.83 93.25,21.68 90.81,19.24 v2(90.81,17.46) ; v2(146.58,35.54) 146.58,36.51 145.29,37.8 142.03,37.8 138.89,40.93 v2(138.89,45.1)
  BOTTOM w0.102: RC107.1 125.19,30.64 124.7,31.13 v2(124.31,31.13) ; RC107.1 RC105.2 ; RC107.1 125.55,30.18 125.69,30.32 RC106.2 ; v2(146.58,35.54) 146.58,35.05 RE42.2 ; 139.82,56.09 140.93,56.09 142.92,54.1 142.92,51.13 v2(142.37,50.59)
  BOTTOM w0.127: 139.82,56.09 136.93,58.99 136.93,60.15 136.89,60.31 132.54,64.65 132.54,70.25 v2(133.69,71.39)
ALWON: length 49.6
  IN1 w0.127: v2(145.01,18.53) 145.44,18.96 145.44,19.27 147.3,21.13 152.43,21.13 152.98,21.68 152.98,22.02 153.71,22.76 154.66,22.76 159.29,27.39 165.86,27.39 169.86,23.39 176.38,23.39 176.8,23.81 176.8,25.93 179.35,28.47 181.14,28.47 181.48,28.13 v2(181.48,27.84)
  BOTTOM w0.102: v1(181.57,27.2) 181.48,27.28 v2(181.48,27.84) ; v2(145.01,18.53) 144.76,18.28 UE1.121
  BOTTOM w0.254: PR114.1 182.02,27.84 v2(181.48,27.84)
AMBER_LED_BAT: length 4
  TOP w0.102: ZT17.1 151.92,13.49 v2(152.23,13.19) 153.3,12.11 Q3.1
  BOTTOM w0.102: JLED1.2 152.7,12.98 152.49,13.19 v2(152.23,13.19)
ASGATE: length 164
  IN1 w0.508: v2(193.76,32.85) 193.41,32.85 190.7,35.57 190.7,39.1 189.92,39.87 189.92,40.93 188.58,42.28 188.58,43.35 183.2,48.72 182.66,48.72 173.92,57.46 173.92,63.94 172.92,64.94 172.92,65.56 166.42,72.06 166.42,88.06 160.73,93.76 160.73,103.6 158.98,105.35 158.98,112.02 158.03,112.97 110.66,112.97 103.83,119.8 100.58,119.8 96.04,124.34 v2(96.04,124.62)
  BOTTOM w0.203: PU703.30 193.86,32.95 v2(193.76,32.85)
  BOTTOM w0.508: PR762.2 v2(96.04,124.62)
AUD_AGND: length 34.3
  TOP w0.102: v2(35.21,14.45) v1(35.21,13.82)
  TOP w0.203: UA1.38 v2(31.26,18.16) ; UA1.25 25.19,16.48 24.98,16.28 24.7,16.28 24.61,16.36 v2(24.61,16.58)
  TOP w0.508: CA21.1 35.2,15.31 CA12.2 v2(35.21,14.45) ; RA17.2 v2(23.39,23.89) ; CA20.1 25.18,12.99 RA41.1 26.23,12.99 CA23.2 v2(26.75,11.77) ; CA10.2 22.43,13.93 v2(22.05,14.31) ; v2(19.2,20.15) 20.21,20.15 CA26.2 ; RA22.2 v2(9.71,10.46) ; RA18.2 v2(33.55,13.75) ; EC2302.1 v2(16.64,24.52) ; v2(19.96,10.69) 20.14,10.5 CA11.2 ; EC2301.1 v2(13.73,10.13) ; CA7.2 v2(20.92,22.5)
  VCC w0.254: 7.82,12.84 JHP1.7 ; JHP1.7 7.82,13.52 ; JHP1.7 9.98,13.52 ; JHP1.7 8.9,12.84 ; JHP1.7 9.98,12.84
  GND w0.254: 8.9,12.84 JHP1.7 ; JHP1.7 7.82,13.52 ; JHP1.7 9.98,12.84 ; JHP1.7 7.82,12.84 ; JHP1.7 9.98,13.52
  BOTTOM w0.508: v2(21.14,18.69) 20.59,18.14 CA37.2 ; RA34.2 CA34.2 ; CA34.2 20.59,13.68 20.59,14.86 CA36.2 ; CA34.2 v2(19.72,13.68) ; RA40.2 v2(16.64,21.15) ; RA30.2 CA35.2 20.23,10.42 v2(19.96,10.69)
AUD_HP1_JACK_L: length 7.6
  TOP w0.203: UA1.32 v1(27.99,15.7) 27.99,15.08 v2(27.71,14.81)
  BOTTOM w0.305: RA27.1 27.52,10.94 28.15,11.58 28.15,14.37 v2(27.71,14.81)
AUD_HP1_JACK_L1: length 4.3
  BOTTOM w0.102: RA36.1 v1(22.63,9.29)
  BOTTOM w0.305: RA27.2 25.01,10.42 RA28.2 RA29.2 RA36.1
AUD_HP1_JACK_R: length 5
  TOP w0.203: v2(27.64,14.05) 28.15,14.05 v1(28.28,14.18) 28.39,14.29 UA1.33
  BOTTOM w0.305: RA31.1 26.82,13.23 v2(27.64,14.05)
AUD_HP1_JACK_R1: length 4.5
  BOTTOM w0.102: RA31.2 25.53,14.48 v1(25.61,14.56)
  BOTTOM w0.305: RA37.1 22.66,13.73 23.6,13.73 RA33.2 RA32.2 25.08,13.68 RA31.2
AUD_PC_BEEP: length 5.5
  TOP w0.102: CA31.2 21.87,21.03 v1(19.33,21.03)
  TOP w0.203: CA31.2 23.28,21.61 23.93,20.96 UA1.16
AUD_PC_BEEP_C: length 4.1
  TOP w0.254: DA3.1 19.78,27.91 v1(19.13,27.26) RA23.1
AUD_SENSE: length 11.6
  TOP w0.102: v2(20.92,23.46) 20.92,23.33 v1(20.53,22.94)
  TOP w0.254: RA10.1 v2(20.92,23.46)
  BOTTOM w0.254: v2(20.92,23.46) 21.67,22.71 21.67,19.96 21.16,19.45 19.19,19.45 18.56,18.82 RA39.1
AUD_SENSE_A: length 6.3
  TOP w0.102: v1(24.47,24.08) 23.84,23.46 RA10.2
  TOP w0.203: UA1.13 22.79,22.16 CA7.1
  TOP w0.254: RA3.1 22.43,23.94 22.45,23.93 RA10.2 CA7.1
AUD_SPK_L+: length 11.9
  IN1 w1.016: 34.73,9.31 35.02,9.31 37.41,11.7 37.41,17.81 36.16,19.07 35.83,19.07
  vias: v1(31.52,19.7) v2(32.02,19.75) v2(32.61,19.75) v2(33.55,8.99) v2(33.55,8.41)
AUD_SPK_L+_C: length 17.2
  TOP w0.102: ZT6.1 11.21,4.92 v2(10.43,4.15)
  IN1 w1.016: 11.92,4.55 16.35,8.98 21.49,8.98 22.32,8.15 25.8,8.15
  vias: v2(9.8,4.15) v2(27.51,8.91) v2(27.51,8.28)
AUD_SPK_L-: length 17.1
  IN1 w1.016: 34.85,20.82 36.38,20.82 38.81,18.39 38.81,11.12 35.58,7.89 35.33,7.89
  vias: v1(33.99,6.5) v2(32.14,20.36) v2(32.72,20.36) v2(33.55,6.83) v2(33.55,6.25)
AUD_SPK_L-_C: length 20.7
  TOP w0.102: v2(8.59,4.27) 8.59,5.05 ZT7.1
  IN1 w1.016: 9.42,3.03 11.34,3.03 12.5,3.03 17.05,7.58 20.91,7.58 22.24,6.25 26.5,6.25
  vias: v2(8.59,3.64) v2(27.51,6.25) v2(27.51,5.61)
AUD_SPK_R+: length 23.2
  IN1 w1.016: 35.03,5.61 35.58,5.61 36.79,6.81 36.98,6.81 40.21,10.04 40.21,18.97 36.89,22.29 34.3,22.29
  vias: v1(31.96,21.67) v2(32.59,21.68) v2(33.23,21.68) v2(33.8,4.99) v2(33.8,4.41)
AUD_SPK_R+_C: length 16.8
  TOP w0.102: ZT4.1 12.35,7.96 v2(11.83,7.96)
  IN2 w1.016: 26.63,4.4 25.29,4.4 20.72,8.97 16.27,8.97 15.65,8.36 12.72,8.36
  vias: v2(11.83,8.65) v2(27.51,4.66) v2(27.51,4.02)
AUD_SPK_R-: length 30.9
  IN1 w1.016: 34.82,2.62 41.6,9.41 41.6,19.55 37.38,23.77 33.34,23.77 32.55,22.99
  vias: v1(33.29,2.37) v2(31.45,20.66) v2(31.96,20.98) v2(33.8,2.64) v2(33.8,2.06)
AUD_SPK_R-_C: length 19.4
  TOP w0.102: ZT5.1 10.88,8.08 v2(10.88,7.51)
  IN2 w1.016: 26.63,1.92 23.71,1.92 21.99,3.64 21.99,5.54 19.96,7.58 16.85,7.58 15.9,6.62 11.7,6.62
  vias: v2(10.24,7.51) v2(27.51,2.25) v2(27.51,1.61)
AUD_VREF: length 5
  TOP w0.102: v1(28.02,12.91) 27.07,13.87 CA23.1
  TOP w0.203: CA23.1 26.18,14.43 26.18,15.76 26.33,15.91 26.33,16.47 26.39,16.53 UA1.28
BA: length 20.2
  TOP w0.254: v2(201.49,38.63) v1(201.49,37.55) 201.49,36.42 204.49,33.42 204.49,23.2 204.24,22.95 PR780.1 203.79,22.95 203.15,23.58 PQ710.1
  BOTTOM w0.254: PD704.3 v2(201.49,38.63)
BAT1_LED#: length 32.4
  TOP w0.102: v2(151.91,6.5) 151.83,6.58 Q2.1
  BOTTOM w0.102: v2(151.91,6.5) 152.25,6.84 152.25,9.68 154.35,11.78 154.35,12.36 155.61,13.62 155.61,15.63 v1(155.4,15.83) 155.4,17.55 153.65,19.3 151.21,19.3 150.45,20.06 145.12,20.06 144.51,19.45 142.83,19.45 142.17,18.78 UE1.1 138.55,18.78 RE18.1
BAT2_LED#: length 17.4
  TOP w0.102: v2(154.87,12.29) 154.87,13.7 v1(154.15,14.42) 153.62,14.96 RE21.1 150.77,15.56 v2(150.85,15.64) ; Q2.4 v2(152.67,4.68)
  BOTTOM w0.102: v2(150.85,15.64) 150.76,15.74 UE1.106 ; v2(152.67,4.68) 152.67,9.76 154.87,11.97 v2(154.87,12.29)
BATT_WHITE_LED_R#: length 12.1
  TOP w0.102: v1(149.37,5.28) Q2.3
  TOP w0.254: Q4.2 157.1,5.47 156.97,5.33 Q5.1 155.34,4.14 154.64,3.45 151.47,3.45 150.77,4.14 Q2.3
BEEP: length 156.6
  TOP w0.102: v2(20.75,30.23) DA3.2
  IN1 w0.127: v2(147.07,29.44) 146.44,28.8 140.97,28.8 139.32,27.15 138.39,27.15 137.76,27.15 134.77,24.16 134.77,22.35 133.37,20.95 133.37,20.02 128.82,15.46 126.55,15.46 125.96,14.88 124.67,14.88 124.09,15.46 122.23,15.46 121.44,14.68 121.19,14.42 119.05,14.42 118.56,14.92 116.96,14.92 116.86,14.81 114.81,14.81 113.44,13.45 109.82,13.45 109.76,13.51 98.94,13.51 98,12.57 95.26,12.57 94.47,13.36 52.04,13.36 50.18,11.5 49.48,11.5 48.66,12.32 48.66,15.64 47.2,17.1 47.2,19.87 44.28,22.79 44.28,24.51 38.73,30.05 27.3,30.05 26.64,29.39 20.06,29.39 19.83,29.62 19.83,30.02 20.05,30.23 v2(20.75,30.23)
  BOTTOM w0.102: UE1.45 146.76,31.85 146.83,31.78 146.83,30.37 147.12,30.08 147.12,29.49 v2(147.07,29.44)
BKLT_CTRL: length 35.6
  TOP w0.102: RP2.7 223.01,44.4 ; 223.01,44.4 223.09,44.4 223.2,44.29 223.2,43.5 223.35,43.35 223.35,42.58 223.51,42.41 RP1.8 ; 223.01,44.4 223.22,44.61 223.22,45.48 222.96,45.75 220.7,45.75 220.09,45.14 v2(220.09,44.85) ; D3.1 219.4,22.38 R9.1 218.19,23.58 218.19,25.94 219.1,26.85 v1(219.1,28.94) 219.1,29.28 v2(218.51,29.86)
  IN1 w0.127: v2(218.51,29.86) 218.99,30.35 218.99,37.51 220.5,39.02 220.5,44 220.09,44.42 v2(220.09,44.85)
BLON_OUT_C: length 10.6
  TOP w0.102: RP1.7 224.37,41.91 224.59,42.13 225.16,42.13 225.83,42.8 v2(225.83,42.87) 225.47,43.22 224.81,43.22 224.14,43.9 RP2.1
  BOTTOM w0.102: v2(225.83,42.87) 225.69,42.73 225.69,39.15 225.09,38.55 JEDP1.24
BLUETOOTH_EN: length 200.2
  IN2 w0.127: v2(112.13,30.84) 111.88,30.84 110.83,29.78 110.83,28 112.03,26.79 112.03,25.3 113.35,23.98 113.35,20.99 113.7,20.65 113.7,15.65 113.27,15.22 113.27,14.83 113.81,14.28 113.81,13.6 113.09,12.88 110.92,12.88 110,11.96 99.97,11.96 96.98,8.97 90.21,8.97 89.19,9.99 v2(88.65,9.99)
  BOTTOM w0.102: JWLAN1.46 56.3,110.68 55.7,111.28 47.04,111.28 45.92,110.15 45.92,97.75 v1(46.37,97.3) 51.12,92.55 68.01,92.55 68.48,93.02 76.76,93.02 80.44,89.34 80.44,78.66 79.07,77.29 79.07,26.2 79.66,25.61 79.66,23.1 80.46,22.31 80.46,17.92 88.4,9.99 v2(88.65,9.99) ; RC42.2 111.64,30.84 v2(112.13,30.84) 112.13,31.29 111.74,31.68 111.74,33.92 UC1.AB2
BOARD_ID: length 4.4
  TOP w0.102: RE1.2 RE6.2 CE2.1 149.09,15.57 149.09,15.73 149.09,15.73 v2(149.09,15.72)
  BOTTOM w0.102: UE1.111 148.76,16.05 149.09,15.73 149.09,15.73 v2(149.09,15.72)
BOARD_ID2: length 8.5
  BOTTOM w0.102: UC1.AB3 112.35,34.49 112.35,33.28 112.22,33.15 112.22,31.51 v1(112.48,31.26) 112.8,30.94 RC56.1 112.8,30.14 112.38,29.72 112.38,29.7 111.77,29.09 111.77,28.54 RC55.2
BOARD_ID3: length 21.1
  TOP w0.102: v2(87.54,31.65) 87.46,31.57 87.46,31.39 87,30.93 87,30.34 86.44,29.78 RC58.1 RC57.2
  IN2 w0.142: v2(98.29,34.63) 98.25,34.63 98.1,34.48 97.19,34.48 95.49,32.78 90.53,32.78 90.3,32.55 88.4,32.55 87.54,31.7 v2(87.54,31.65)
  BOTTOM w0.076: UC1.BA7 101.5,37.43 101.39,37.53 100.24,37.53 98.81,36.11 98.81,35.16 v2(98.29,34.63) 98.29,34.59 v1(97.94,34.24)
BREATH_LED#: length 35.1
  TOP w0.102: v2(157.25,29.43) 157.68,29.01 v1(157.68,28.21) 157.68,27.44 158.16,26.96 158.16,24.88 159.05,23.99 159.05,23.29 158.6,22.85 158.6,20.1 158.39,19.89 158.39,16.11 158.9,15.61 158.9,13.27 v2(158.27,12.65) ; v2(167.79,12.15) 168.41,12.15 R53.2 169.18,11.38 171.31,11.38 Q16.3
  BOTTOM w0.102: UE1.70 157.01,29.18 v2(157.25,29.43) ; v2(158.27,12.65) 158.29,12.63 160.61,12.63 161.56,11.67 167.31,11.67 v2(167.79,12.15)
BST_1.2V: length 2.6
  BOTTOM w0.203: PR200.2 84.22,107.02 84.57,106.67 v1(84.86,106.67) PU200.18
BST_1.2V_R: length 1.3
  BOTTOM w0.102: PR200.1 v1(82.25,105.62)
BST_3V: length 0.4
  BOTTOM w0.102: v1(174.71,45.42) 174.58,45.29 174.58,45.04
BST_+1VALW: length 1.7
  BOTTOM w0.102: v1(150.13,46.69) 149.19,45.74 PR306.1
BST_+1VALW_R: length 1.3
  BOTTOM w0.102: PR306.2 v1(148.8,48.47)
BST_+VCCEOPIO: length 3.5
  BOTTOM w0.254: PR1203.1 97.2,109.68 v1(97.67,109.68) 98.6,109.68 99.28,110.37 PU1200.9
BST_R_+VCCEOPIO: length 1.2
  BOTTOM w0.102: PR1203.2 v1(94,110.27)
C0_1.0VS_VCCOPCP: length 5.5
  BOTTOM w0.102: v1(103.4,116.16) 103.4,114.7 102.97,114.27 PR1207.1
  BOTTOM w0.254: PU1200.4 101.85,112 102.26,112.41 102.26,113.94 102.57,114.25 PR1207.1
C1_1.0VS_VCCOPCP: length 3.9
  BOTTOM w0.254: PU1200.3 101.65,112.5 101.87,112.73 101.87,114.64 v1(102,114.76) 102.43,115.19 PR1206.2
CAM_DETECT#: length 135.7
  IN1 w0.127: v2(119.08,30.56) 119.08,30.31 120.61,28.78 125.47,28.78 126.17,29.48 126.89,29.48 126.9,29.48 127.14,29.48 128.87,31.21 128.87,31.84 129.59,32.56 130.54,32.56 131.95,33.97 132.34,33.97 133.27,34.89 136.24,34.89 138.54,37.19 142.99,37.19 143.09,37.29 146.24,37.29 147.29,36.24 149.28,36.24 150.02,35.5 154.66,35.5 155.21,34.94 156.91,34.94 157.63,35.66 157.63,37.44 159.95,39.76 159.95,42.15 159.05,43.05 159.05,47.14 159.05,47.35 161.25,49.55 166.27,49.55 167.33,50.6 167.92,50.6 168.96,51.65 171.55,51.65 v2(171.97,51.24)
  IN2 w0.127: v2(216.5,47.86) 216.5,48.03 214.84,49.7 212.19,49.7 210.93,48.44 210.93,46.47 209.14,44.68 202.64,44.68 199.14,48.18 195.6,48.18 192.84,50.93 189.81,50.93 187.96,52.79 186.6,52.79 186.16,52.34 172.99,52.34 171.97,51.32 v2(171.97,51.24)
  BOTTOM w0.076: 116.73,33.22 115.99,33.96 UC1.P2
  BOTTOM w0.102: 116.73,33.22 116.73,33.2 117.59,32.34 118.31,32.34 118.9,31.74 118.9,31.1 119.08,30.93 v2(119.08,30.56) 118.77,30.24 118.77,27.44 RC63.2 ; v2(216.5,47.86) 216.5,47.92 216.5,47.93 216.5,48.1 216.59,48.2 J3D1.7
CAP_LED: length 2.9
  TOP w0.102: v2(84.98,8.53) 84.98,8.48 85.3,8.16 R25.2 84.71,7.72 84.67,7.77 ZT50.1
  BOTTOM w0.102: JKB1.4 85.4,8.94 v2(84.98,8.53)
CAP_LED#: length 105.7
  TOP w0.102: R24.2 78.94,5.99 Q6.3 78.95,5.12 78.95,2.71 v2(79.01,2.64)
  IN1 w0.127: v2(79.01,2.64) 79.6,2.64 79.77,2.48 91.54,2.48 93.21,4.15 94.67,4.15 96.08,2.73 111.78,2.73 111.97,2.92 111.97,3.87 112.1,3.99 114.53,3.99 115.28,3.24 122.3,3.24 124.33,5.27 133.81,5.27 139.83,11.29 144.01,11.29 148.15,7.16 150.54,7.16 152.62,9.24 154.71,9.24 157.17,11.7 158.17,11.7 158.96,12.49 158.96,16.69 156.58,19.07 155.15,19.07 v2(154.64,19.58)
  BOTTOM w0.102: v2(154.64,19.58) 155.03,19.98 UE1.93
CAP_LED_Q: length 5.9
  TOP w0.102: v1(86.3,3.54) 86.3,5.8 R25.1 85.23,6.88 84.03,6.88 83.84,6.68 Q7.1
CAP_LED_R#: length 5.2
  TOP w0.102: v1(82.87,2.05) Q7.2 81.66,3.94 80.77,3.05 Q6.1
CBN: length 3.6
  TOP w0.203: UA1.35 29.19,16.41 29.73,15.86 v1(30.88,15.86) 32.05,15.86 CA24.1
CBP: length 1.8
  TOP w0.203: UA1.37 30.84,17.76 31.31,17.3 CA24.2
CCLIM: length 4.4
  TOP w0.102: v1(192.54,38.94) 192.68,39.08 v2(192.68,39.46)
  TOP w0.254: PR752.2 PR750.1 192.75,40 192.75,39.53 v2(192.68,39.46)
  BOTTOM w0.203: PU703.11 193.86,38.47 192.86,39.46 v2(192.68,39.46)
CFG0: length 12.3
  BOTTOM w0.076: RC131.2 127.03,76.43 127.03,76.74 126.46,77.31 TPC10.1 125.38,77.31 124.11,76.05 124.11,75.43 124.55,74.98 124.55,72.47 124.59,72.43 124.59,72.05 124.25,71.71 123.95,71.71 123.64,71.4 122.08,71.4 121.8,71.57 UC1.E68
CFG1: length 10
  BOTTOM w0.076: RC132.2 127.26,76.9 126.55,77.62 125.27,77.62 TPC11.1 123.95,76.29 123.95,75.36 124.39,74.92 124.39,72.91 123.55,72.08 123.15,72.08 UC1.B67
CFG2: length 12.2
  BOTTOM w0.076: TPC12.1 126.73,76.26 126.73,76.66 126.39,77.01 126.07,77.01 125.93,77.15 125.44,77.15 124.28,75.98 124.28,75.5 124.72,75.05 124.72,72.54 124.76,72.5 124.76,71.98 124.58,71.81 124.58,71.21 124.19,70.82 122.72,70.82 122.41,70.72 122.04,70.72 UC1.D65
CFG3: length 13.2
  BOTTOM w0.076: UC1.D67 122.31,71.75 123.27,72.71 123.65,72.71 124.06,73.12 124.06,74.78 123.56,75.27 123.56,77.12 123.78,77.34 RC133.2 124.38,77.87 124.38,78.01
  BOTTOM w0.102: RC175.1 127.9,78.77 127.21,79.46 TPC13.1 125.16,79.46 124.38,78.67 124.38,78.01
CFG4: length 5.1
  TOP w0.102: RC136.2 120.35,76.41 TPC14.1 121.11,76.79 121.46,76.45 v2(121.46,76.05)
  BOTTOM w0.076: v2(121.46,76.05) 121.58,75.93 121.58,74.56 121.37,74.35 121.37,73.99 121.17,73.79 UC1.E70
CFG5: length 5.2
  BOTTOM w0.076: TPC15.1 122.7,77.04 122.7,73.91 122.51,73.72 122.51,73.2 UC1.C68
CFG6: length 7.1
  BOTTOM w0.076: UC1.D68 121.7,73.45 122.02,73.77 122.02,74.04
  BOTTOM w0.102: TPC16.1 123.16,79.35 123.16,78.58 122.19,77.62 122.19,74.45 122.02,74.27 122.02,74.04
CFG7: length 9.4
  BOTTOM w0.076: UC1.C67 122.46,72.91 122.77,73.22 123.21,73.22 123.37,73.38 123.65,73.38 123.89,73.63 123.89,74.71 123.39,75.22 123.39,75.77
  BOTTOM w0.102: TPC17.1 123.78,79.46 123.39,79.06 123.39,75.77
CFG8: length 5.9
  BOTTOM w0.076: 121.58,78.04 120.89,77.35 120.89,75.4 120.56,75.08 120.56,74.1 120.61,74.05 120.61,73.78 UC1.F71
  BOTTOM w0.102: 121.58,78.04 121.98,78.44 TPC20.1
CFG9: length 7.6
  BOTTOM w0.076: 119.78,75.34 119.78,75.09 ; 119.85,74.86 119.85,74.52 119.65,74.32 119.65,74.06 119.71,73.94 119.71,73.8 119.64,73.57 119.64,73.44 119.72,73.22 119.72,72.96 UC1.G69
  BOTTOM w0.089: 119.78,75.09 119.85,75.01 119.85,74.86
  BOTTOM w0.102: 119.78,75.34 120.12,75.68 120.12,75.98 119.64,76.46 119.64,77.92 120.29,78.57 120.29,79.23 TPC21.1
CFG10: length 4.5
  BOTTOM w0.076: UC1.F70 120.81,73.39 120.81,73.87 120.8,73.88 120.8,74.1 120.73,74.16 120.73,74.93 121.06,75.26 121.06,76.52 TPC22.1
CFG11: length 8.4
  BOTTOM w0.076: 120.7,77.5 120.7,75.46 120.4,75.17 120.4,73.99 120.28,73.87 120.28,73.4 120.11,73.23 120.11,73.04 120.22,72.93 120.22,72.69 119.82,72.29 UC1.G68
  BOTTOM w0.102: 120.7,77.5 121.93,78.73 TPC23.1
CFG12: length 5.8
  BOTTOM w0.076: UC1.H70 119.03,73.42 119.03,73.65 118.97,73.78 118.97,73.89 119.03,74.03 119.03,74.42 118.89,74.56 118.89,74.56 118.86,74.59 118.86,75.32 119.46,75.92 119.46,78.04
  BOTTOM w0.102: TPC24.1 119.46,78.31 119.46,78.04
CFG13: length 5.3
  BOTTOM w0.076: 120.01,75.3 120.01,75.16 120.07,75.1 120.07,74.38 119.92,74.23 UC1.G71
  BOTTOM w0.102: 120.01,75.3 120.31,75.61 120.31,76.08 119.84,76.55 119.84,77.79 120.24,78.19 TPC25.1
CFG14: length 3.6
  BOTTOM w0.076: TPC26.1 119.59,75.6 119.59,75.04 119.65,74.97 119.65,74.55 119.49,74.39 119.49,74.02 119.5,73.99 119.53,73.91 119.53,73.79 119.47,73.57 119.47,73.43 119.53,73.27 119.53,73.01 119.26,72.74 UC1.H69
CFG15: length 3.9
  BOTTOM w0.076: UC1.G70 120.11,73.71 120.11,73.94 120.23,74.05 120.23,75.25
  BOTTOM w0.102: TPC27.1 120.24,76.46 120.52,76.18 120.52,75.54 120.23,75.25
CFG16: length 2.5
  TOP w0.102: TPC19.1 120.49,70.62 v2(120.49,70.74)
  BOTTOM w0.076: UC1.E63 120.49,69.49 v2(120.49,70.74)
CFG17: length 2.4
  TOP w0.102: TPC18.1 119.59,70.5 v2(119.83,70.74)
  BOTTOM w0.076: UC1.F63 120.17,69.76 119.87,70.06 119.87,70.7 v2(119.83,70.74)
CFG18: length 1.4
  TOP w0.102: v2(121.04,71.78) 121.05,71.78 TPC29.1
  BOTTOM w0.076: UC1.E66 120.82,71.55 v2(121.04,71.78)
CFG19: length 1.4
  TOP w0.102: TPC28.1 120.1,72.13 v2(120.45,71.78)
  BOTTOM w0.076: UC1.F66 120.17,71.49 v2(120.45,71.78)
CFG_RCOMP: length 12.5
  TOP w0.254: v2(129.83,67.56) 129.56,67.56 128.89,66.89 v1(128.42,66.89) 122.81,66.89 121.76,67.94 120.59,67.94 v2(120.41,67.76)
  BOTTOM w0.076: v2(129.83,67.56) 128.81,67.56 128.34,67.09 RC134.1
  BOTTOM w0.254: UC1.E60 120.41,67.62 v2(120.41,67.76)
CHG_AMBER_LED_R#: length 4.2
  TOP w0.102: Q3.2 152.85,9.07 152.1,8.32 v1(152.1,7.96) 152.1,6.88 152.4,6.58 Q2.6
CLK_ITPXDP_N: length 1.3
  TOP w0.097: v2(120.53,57.69) 120.56,57.69 120.56,57.69 120.52,57.69 TP8.1
  BOTTOM w0.097: v2(120.53,57.69) 120.1,58.11 UC1.F43
CLK_ITPXDP_P: length 1.3
  TOP w0.097: TP9.1 121.58,57.72 v2(121.11,57.72)
  BOTTOM w0.097: UC1.E43 120.75,58.08 v2(121.11,57.72)
CLK_PCI_LPC_MEC: length 121.8
  TOP w0.102: RE27.2 v2(151.58,31.49)
  IN2 w0.127: v2(121.54,5.06) 121.54,5.05 122.07,5.58 122.07,8.53 128.51,14.97 128.51,16.36 131.97,19.83 131.97,22.51 v2(131.67,22.81)
  BOTTOM w0.102: v2(131.67,22.81) 133.12,24.26 133.12,26.02 133.96,26.86 133.96,29.66 135.87,31.58 135.87,33.12 138.71,35.96 141.84,35.96 143.17,37.28 144.37,37.28 144.83,36.82 146.2,36.82 147.09,35.92 149.43,35.92 150.37,34.97 150.86,34.97 151.58,34.26 151.58,33.73 151.56,33.71 UE1.57 151.56,31.51 v2(151.58,31.49) ; RC15.2 95.81,32.83 94.49,32.83 93.3,31.64 93.3,29.71 92.9,29.31 92.9,27.6 90.58,25.28 90.58,24.42 90.46,24.29 90.46,22.13 89.94,21.61 89.94,17.3 CC88.1 90.49,16.74 90.49,14.95 90.67,14.78 90.67,14.06 92.64,12.09 92.64,6.27 94.24,4.67 108.91,4.67 109.52,4.06 111.41,4.06 115.05,7.7 v1(120.04,7.7) 120.86,7.7 122.07,6.5 122.07,5.58 121.54,5.05 v2(121.54,5.06)
CLK_PCI_LPDEBUG: length 63.2
  TOP w0.102: JDB1.1 118.74,8.49 118.45,8.78 117.56,8.78 v1(117.31,8.52) 116.44,7.66 v2(116.44,6.83)
  BOTTOM w0.102: v2(116.44,6.83) 114.5,6.83 111.5,3.83 109.37,3.83 108.76,4.44 94.15,4.44 92.41,6.17 92.41,12 90.44,13.97 90.44,14.68 88.83,16.29 88.83,21.01 90.23,22.41 90.23,24.38 90.36,24.51 90.36,25.37 92.67,27.69 92.67,29.4 93.07,29.81 93.07,31.74 94.4,33.06 95.15,33.06 RC16.2
CLK_PCIE_LAN_N2: length 178.3
  IN2 w0.122: v2(130.19,61.14) 130.31,61.14 130.65,61.48 130.65,63.85 132.09,65.3 132.09,87.19 113.6,105.69 113.6,107.31 110.58,110.33 110.58,112.62 106.79,116.4 106.79,123.94 105.15,125.58 105.15,131.64 103.02,133.78 90.39,133.78 85.73,129.12 53.54,129.12 42.44,118.02 36.87,118.02 36.2,118.69 34.02,118.69 32.75,119.96 32.19,119.96 31.85,119.62 31.85,119 v2(32.11,118.75)
  BOTTOM w0.076: v2(130.19,61.14) 130.34,61.14 130.42,61.06 130.42,60.91 130.19,60.67 130.19,59.66 127.89,57.36 123.19,57.36 122.79,57.76 122.3,57.76 122.22,57.68 122.22,57.45 122.12,57.34 121.95,57.34 UC1.D41
  BOTTOM w0.097: UL1.16 32.21,118.2 32.11,118.1 31.97,118.1 31.83,118.23 31.83,118.48 32.09,118.75 v2(32.11,118.75)
CLK_PCIE_LAN_P2: length 178.4
  IN2 w0.122: v2(31.52,118.75) 31.6,118.83 31.6,119.73 32.09,120.21 32.85,120.21 34.12,118.94 36.3,118.94 36.98,118.27 42.34,118.27 53.43,129.36 85.63,129.36 90.29,134.03 103.12,134.03 105.4,131.74 105.4,125.68 107.04,124.04 107.04,116.5 110.83,112.72 110.83,110.43 113.85,107.41 113.85,105.79 132.34,87.3 132.34,65.19 130.9,63.75 v2(130.9,61.14)
  BOTTOM w0.076: UC1.C41 122.5,57.51 122.58,57.59 122.72,57.59 123.12,57.19 127.96,57.19 130.35,59.59 130.35,60.6 130.89,61.14 v2(130.9,61.14)
  BOTTOM w0.097: v2(31.52,118.75) 31.64,118.63 31.64,118.15 31.89,117.91 32.14,117.91 32.25,117.8 UL1.15
CLK_PCIE_LAN_REQ#: length 205.5
  TOP w0.102: RC73.2 88.81,28.84 88.92,28.72 93.53,28.72 v2(93.94,28.31)
  IN2 w0.089: v2(104.27,38.48) 104.27,38.19 104.06,37.98 103.26,37.98 102.69,37.41 102.69,36.75 101.97,36.04
  IN2 w0.127: v2(30.7,113.49) 30.7,97.01 25.17,91.48 21.1,91.48 19.24,89.62 19.24,87.22 19.73,86.72 20.4,86.72 22.26,84.86 22.26,84.29 24.24,82.31 30.63,82.31 32.66,80.28 32.66,68.93 40.79,60.8 40.79,40.44 44.72,36.51 44.72,20.73 47.68,17.77 48.78,17.77 52.15,14.4 76.39,14.4 76.54,14.56 76.91,14.93 80.91,14.93 82.21,16.22 93.5,16.22 94.57,17.3 94.57,20.47 v2(94.51,20.53) ; 101.97,36.04 100.92,34.99 100.92,34.46 98.68,32.21 97.85,32.21 v2(93.94,28.31)
  BOTTOM w0.097: UC1.AT8 104.61,38.13 v2(104.27,38.48)
  BOTTOM w0.102: RL13.1 29.92,115.72 30.7,114.93 v2(30.7,113.49) ; v2(94.51,20.53) 94.38,20.53 93.83,21.07 93.83,21.46 92.8,22.49 92.8,23.16 92.57,23.4 92.54,23.4 92.54,25.76 93.94,27.16 v2(93.94,28.31)
CLK_PCIE_LAN_REQ#_R: length 5.9
  BOTTOM w0.102: v1(30.06,114.89) 30.06,114.97 RL16.2 29.51,116.43 30.69,116.43 30.83,116.29 RL13.2 31.4,115.97 32.03,116.6 UL1.12
CLK_PCIE_SSD_N3: length 123.3
  TOP w0.097: v2(197.84,15.28) 198.03,15.1 198.03,14.71 197.85,14.54 JSSD1.3
  IN2 w0.122: v2(137.05,45.05) 137.05,45.24 137.17,45.36 137.39,45.36 137.95,44.8 137.95,40.92 138.86,40.01 138.86,38.41 140.28,37 142.31,37 143.51,35.8 143.51,34.07 146.09,31.5 146.09,30.71 145.97,30.59 145.97,29.55 147.15,28.38 151.19,28.38 151.99,27.58 154.87,27.58 157.55,24.9 159.04,24.9 161.47,22.47 167.63,22.47 167.98,22.13 169.58,22.13 170.37,21.34 180.26,21.34 181.42,22.5 185.91,22.5 186.3,22.11 186.3,21.91 186.3,21.91 186.3,21.77 186.84,21.23 188.49,21.23 188.82,21.56 188.82,23.06 190.84,25.08 195.01,25.08 195.82,24.26 195.82,18.12 197.95,16 197.95,15.39 v2(197.84,15.28)
  BOTTOM w0.076: UC1.D40 121.76,56.88 121.81,56.83 121.81,56.68 121.91,56.58 122.36,56.58 122.74,56.45 122.93,56.45 123.13,56.51 123.21,56.51 123.33,56.45 124.11,56.45 124.12,56.44 124.14,56.44
  BOTTOM w0.097: 124.14,56.44 127.12,56.44 127.31,56.63 128.41,56.63 128.9,57.12 131.68,57.12 132.2,56.6 137.56,56.6 139.34,54.82 140.29,54.82 141.45,53.66 v3(141.45,52.52) 141.45,51.72 139.49,49.76 138.82,49.76 136.29,47.24 136.29,45.78 136.53,45.55 136.7,45.55 137.05,45.19 v2(137.05,45.05)
CLK_PCIE_SSD_P3: length 123.3
  TOP w0.097: v2(198.43,15.28) 198.22,15.07 198.22,14.67 198.35,14.54 JSSD1.2
  IN2 w0.122: v2(137.05,45.77) 137.21,45.61 137.49,45.61 138.2,44.9 138.2,41.03 139.11,40.11 139.11,38.52 140.39,37.24 142.42,37.24 143.76,35.9 143.76,34.18 146.34,31.6 146.34,30.61 146.22,30.49 146.22,29.66 147.25,28.63 151.29,28.63 152.09,27.83 154.98,27.83 157.65,25.15 159.14,25.15 161.57,22.72 167.74,22.72 168.08,22.38 169.68,22.38 170.47,21.59 180.15,21.59 181.31,22.75 186.01,22.75 186.16,22.61 186.55,22.22 186.55,22.18 186.55,22.18 186.55,21.88 186.95,21.48 188.39,21.48 188.57,21.66 188.57,23.16 190.73,25.32 195.11,25.32 196.07,24.36 196.07,18.23 198.2,16.1 198.2,15.51 v2(198.43,15.28)
  BOTTOM w0.076: UC1.C40 122.14,56.88 122.06,56.96 122.06,57.1 122.14,57.18 122.41,57.18 122.5,57.09 122.5,56.76 122.57,56.69 122.63,56.66 122.77,56.62 122.91,56.62 123.1,56.67 123.25,56.67 123.37,56.62 124.11,56.62 124.12,56.63 124.12,56.63 124.14,56.63
  BOTTOM w0.097: 124.14,56.63 127.04,56.63 127.23,56.82 128.34,56.82 128.82,57.31 131.75,57.31 132.28,56.78 137.64,56.78 139.42,55.01 140.37,55.01 141.64,53.74 141.64,52.89 141.68,52.84 141.68,52.23 141.64,52.19 141.64,51.64 139.57,49.58 138.9,49.58 136.48,47.16 136.48,45.86 136.58,45.77 v2(137.05,45.77)
CLK_PCIE_SSD_REQ#: length 185.9
  TOP w0.076: v2(104.29,39.45) 103.78,39.96 103.33,39.96 102.63,39.26 101.12,39.26
  TOP w0.102: JSSD1.20 189.35,15.03 190.28,15.96 v2(190.28,16.69) ; RC188.2 91.41,34.74 ; 91.41,34.74 91.41,34.45 90.66,33.7 89.31,33.7 88.45,34.56 84.79,34.56 v1(83.84,33.61) 83.69,33.61 79.46,29.38 79.46,26.9 79.61,26.74 79.61,24.72 77.24,22.34 77.24,13.02 78.09,12.17 78.09,7.35 77.06,6.32 77.06,2.4 v2(76.66,2.01) ; 91.41,34.74 92.17,33.98 93.22,33.98 98.5,39.26 101.12,39.26
  IN1 w0.127: v2(76.66,2.01) 77.34,1.33 124,1.33 124.62,1.96 125.11,1.96 125.49,1.59 154.35,1.59 162.94,10.18 164.12,10.18 166.96,13.02 170.19,13.02 173.45,16.28 185.71,16.28 186.49,15.5 189.96,15.5 190.28,15.82 v2(190.28,16.69)
  BOTTOM w0.076: UC1.AT10 104.61,39.19 104.35,39.45 v2(104.29,39.45)
CLK_PCIE_WLAN_N1: length 118.9
  IN2 w0.122: v2(55.09,101.45) 55.01,101.36 55.01,100.2 56.28,98.92 57.05,98.92 57.46,98.5 83.52,98.5 83.92,98.09 117.72,98.09 128.59,87.23 128.59,79.48 127.02,77.91 127.02,71.43 126.34,70.75 126.34,62.91 127.12,62.13 127.12,59.33 126.91,59.12 v2(126.91,58.43)
  BOTTOM w0.076: v2(126.91,58.43) 126.91,57.81 126.71,57.61 123.34,57.61 122.94,58.01 UC1.B42
  BOTTOM w0.097: v2(55.09,101.45) 54.91,101.26 54.91,101.08 55.05,100.94 JWLAN1.41 55.05,99.25 54.89,99.1 54.89,98.52 EC3201.1
CLK_PCIE_WLAN_P1: length 118.8
  IN2 w0.122: v2(126.19,58.44) 126.33,58.44 126.66,58.77 126.66,59.22 126.87,59.43 126.87,62.03 126.09,62.81 126.09,70.86 126.77,71.53 126.77,78.02 128.34,79.58 128.34,87.12 117.62,97.85 83.82,97.85 83.41,98.25 57.36,98.25 56.94,98.67 56.18,98.67 54.76,100.09 54.76,101.2 54.51,101.45 v2(54.51,101.45)
  BOTTOM w0.076: v2(126.19,58.44) 126.38,58.44 126.74,58.07 126.74,57.88 126.64,57.78 123.51,57.78 123.43,57.86 123.43,57.97 UC1.A42
  BOTTOM w0.097: EC3202.1 54.71,98.54 54.71,99.1 54.55,99.25 JWLAN1.39 54.55,100.97 54.72,101.14 54.72,101.29 54.56,101.45 v2(54.51,101.45)
CLK_PCIE_WLAN_REQ#: length 175.7
  IN2 w0.127: v2(94.06,25.42) 92.82,24.17 92.82,21.86 89.26,18.31 80.73,18.31 79.42,17 73.58,17 72.24,15.66 55.48,15.66 50.23,20.91 46.33,20.91 45.98,21.25 45.98,38.83 42.05,42.76 42.05,87.96 47.37,93.27 55.3,93.27 v2(56.85,94.82)
  BOTTOM w0.076: UC1.AT7 104.29,36.78 103.59,36.78 103.33,37.04 102.95,37.04 102.9,36.99 100.31,36.99 99.15,35.83
  BOTTOM w0.102: RW9.1 57.11,95.08 v2(56.85,94.82) ; RC72.2 95.78,19.53 95.78,20.49 95.75,20.56 95.24,21.07 95.24,24.24 v2(94.06,25.42) 94.06,26.12 94.25,26.31 94.25,26.33 94.75,26.83 94.75,30.38 95.03,30.66 95.03,31.33 95.82,32.12 97.22,32.12 97.37,32.28 97.62,32.28 97.87,32.53 97.87,32.72 98.48,33.32 98.48,34.05 99.15,34.73 99.15,35.83
CLK_PCIE_WLAN_REQ#_R: length 3.7
  BOTTOM w0.102: ZT63.1 RW9.2 56.05,99.27 JWLAN1.45
CLK_SMB: length 3.9
  TOP w0.102: v2(214.56,16.61) 214.5,16.61 213.99,17.12 v4(213.99,18.14)
  TOP w0.254: v2(214.56,16.61) 214.52,16.57 PR18.1
  BOTTOM w0.254: v2(214.56,16.61) 214.18,16.61 213.9,16.9 PBATT1.7
CLK_TP_SIO: length 90.7
  IN1 w0.127: v2(153.37,25.29) 152.6,26.06 152.6,28.6 151.15,30.05 147.09,30.05 146.89,30.25 146.47,30.25 146.34,30.12 144.29,30.12 143.44,30.97 142.33,30.97 140.11,28.75 138.64,28.75 134.26,24.37 134.26,22.56 132.86,21.16 132.86,20.23 128.61,15.97 126.34,15.97 125.75,15.39 124.88,15.39 124.3,15.97 122.02,15.97 120.98,14.93 119.26,14.93 118.77,15.42 116.75,15.42 116.65,15.32 114.6,15.32 113.86,14.58 107.51,14.58 106.68,13.76 98.6,13.76 97.83,12.99 v2(97.49,12.99)
  BOTTOM w0.102: UE1.78 154.06,25.98 v2(153.37,25.29) ; JTP1.1 104.9,9.18 105.2,8.88 105.84,8.88 106.22,9.26 106.22,12.05 105.21,13.06 97.9,13.06 97.83,12.99 v2(97.49,12.99) 97.49,12.27 ZT13.1 96.61,11.39 C27.1 94.63,11.39 R32.2
CLKRUN#: length 78.8
  IN1 w0.127: v2(130.1,40.72) 129.37,40.72 126.36,37.71 124.9,37.71 124.72,37.53 124.34,37.53 122.45,35.65 117.74,35.65 116.45,34.36 111.74,34.36 111.63,34.24 109.66,34.24 106.98,31.56 100.43,31.56 98.46,33.53 98.48,33.55 98.48,33.89 98.24,34.14 97.89,34.14 97.87,34.12 97.37,34.62 97.37,35.39 v2(97.49,35.51)
  BOTTOM w0.076: UC1.AW11 102.49,39.39 101.8,39.39 101.61,39.2 101.61,39.13 101.32,38.84 100.51,38.84 98.96,37.29 98.06,37.29 97.49,36.72 v2(97.49,35.51) 97.49,35.28 97.35,35.13 97.25,35.13 97.05,34.93
  BOTTOM w0.102: v2(130.1,40.72) 130.23,40.59 133.24,40.59 134.1,41.45 v1(134.51,41.45) 135.44,41.45 137.68,39.21 137.68,37.8 138.14,37.33 141.28,37.33 142.6,38.65 144.93,38.65 145.4,38.19 146.77,38.19 147.66,37.29 151.8,37.29 153.51,35.58 153.51,34.17 153.96,33.72 UE1.63 ; RC36.1 97.05,34.93
CMP_STRAP0: length 2.9
  TOP w0.102: RE40.1 145.62,18.29 v2(145.83,18.5) 146.13,18.5 v1(146.32,18.69)
  BOTTOM w0.102: v2(145.83,18.5) 145.96,18.37 UE1.118
CMP_VIN0: length 6.9
  TOP w0.102: v2(141.64,26.72) 141.64,26.58 142.23,25.99 RE52.1
  BOTTOM w0.102: v2(141.64,26.72) 141.3,26.38 UE1.20 138.84,26.38 138.64,26.18 RE37.2 138.21,26.64 137.96,26.88 137.38,26.88 137.13,27.13 v1(136.67,27.13)
CMP_VOUT0: length 55.6
  TOP w0.102: PR116.1 178.07,27.84 v2(178.07,27.83) ; RE52.2 v2(143.16,26.75) 142.88,27.03 RE49.2
  IN1 w0.127: v2(178.07,27.83) 176.55,26.31 176.55,23.92 176.27,23.64 169.97,23.64 165.97,27.64 159.18,27.64 154.55,23.01 153.61,23.01 152.72,22.13 152.72,21.79 152.32,21.39 150.48,21.39 v2(148.42,23.45)
  IN2 w0.127: v2(148.42,23.45) 148.31,23.56 146.4,23.56 143.22,26.75 v2(143.16,26.75)
  BOTTOM w0.102: UE1.85 151.43,23.18 150.32,22.07 149.93,22.07 148.55,23.45 v2(148.42,23.45)
CMSRC: length 163.6
  IN1 w0.508: v2(194.39,32.79) 194.39,33.48 193.86,34.02 193.19,34.02 192.69,34.51 192.69,35.65 191.96,36.39 191.96,39.87 190.43,41.39 190.43,43.52 189.96,43.99 189.96,45.23 189.32,45.87 186.95,45.87 183.47,49.36 182.92,49.36 174.56,57.72 174.56,64.21 173.56,65.2 173.56,65.83 167.06,72.33 167.06,88.33 161.36,94.02 161.36,103.86 159.61,105.61 159.61,112.29 158.22,113.68 110.87,113.68 104.1,120.45 100.85,120.45 v2(98.17,123.13)
  BOTTOM w0.203: PU703.29 194.26,32.93 v2(194.39,32.79)
  BOTTOM w0.508: PR763.2 v2(98.17,123.13)
COMP: length 4.8
  BOTTOM w0.203: PU703.10 193.46,38.29 192.96,38.78 192.59,38.78 v1(192.3,39.07) 192.21,39.16 192.21,39.67 192.09,39.78 192.09,40.14 191.76,40.47 PR754.2 PC751.2
COMP_IA: length 3.6
  TOP w0.203: v2(163.35,62.68) 163.39,62.64 PU602.16
  BOTTOM w0.102: v1(163.09,63.33) 163.35,63.06 v2(163.35,62.68)
  BOTTOM w0.254: PR639.2 PC636.2 163.46,62.57 v2(163.35,62.68)
COMP_VSA: length 4.1
  TOP w0.203: v2(159.93,59.47) 160.02,59.56 PU602.24
  BOTTOM w0.102: v2(159.93,59.47) 159.53,59.07 v1(159.53,58.63)
  BOTTOM w0.254: v2(159.93,59.47) 159.93,59.31 160.48,58.76 PC628.1 160.54,57.9 PR630.1
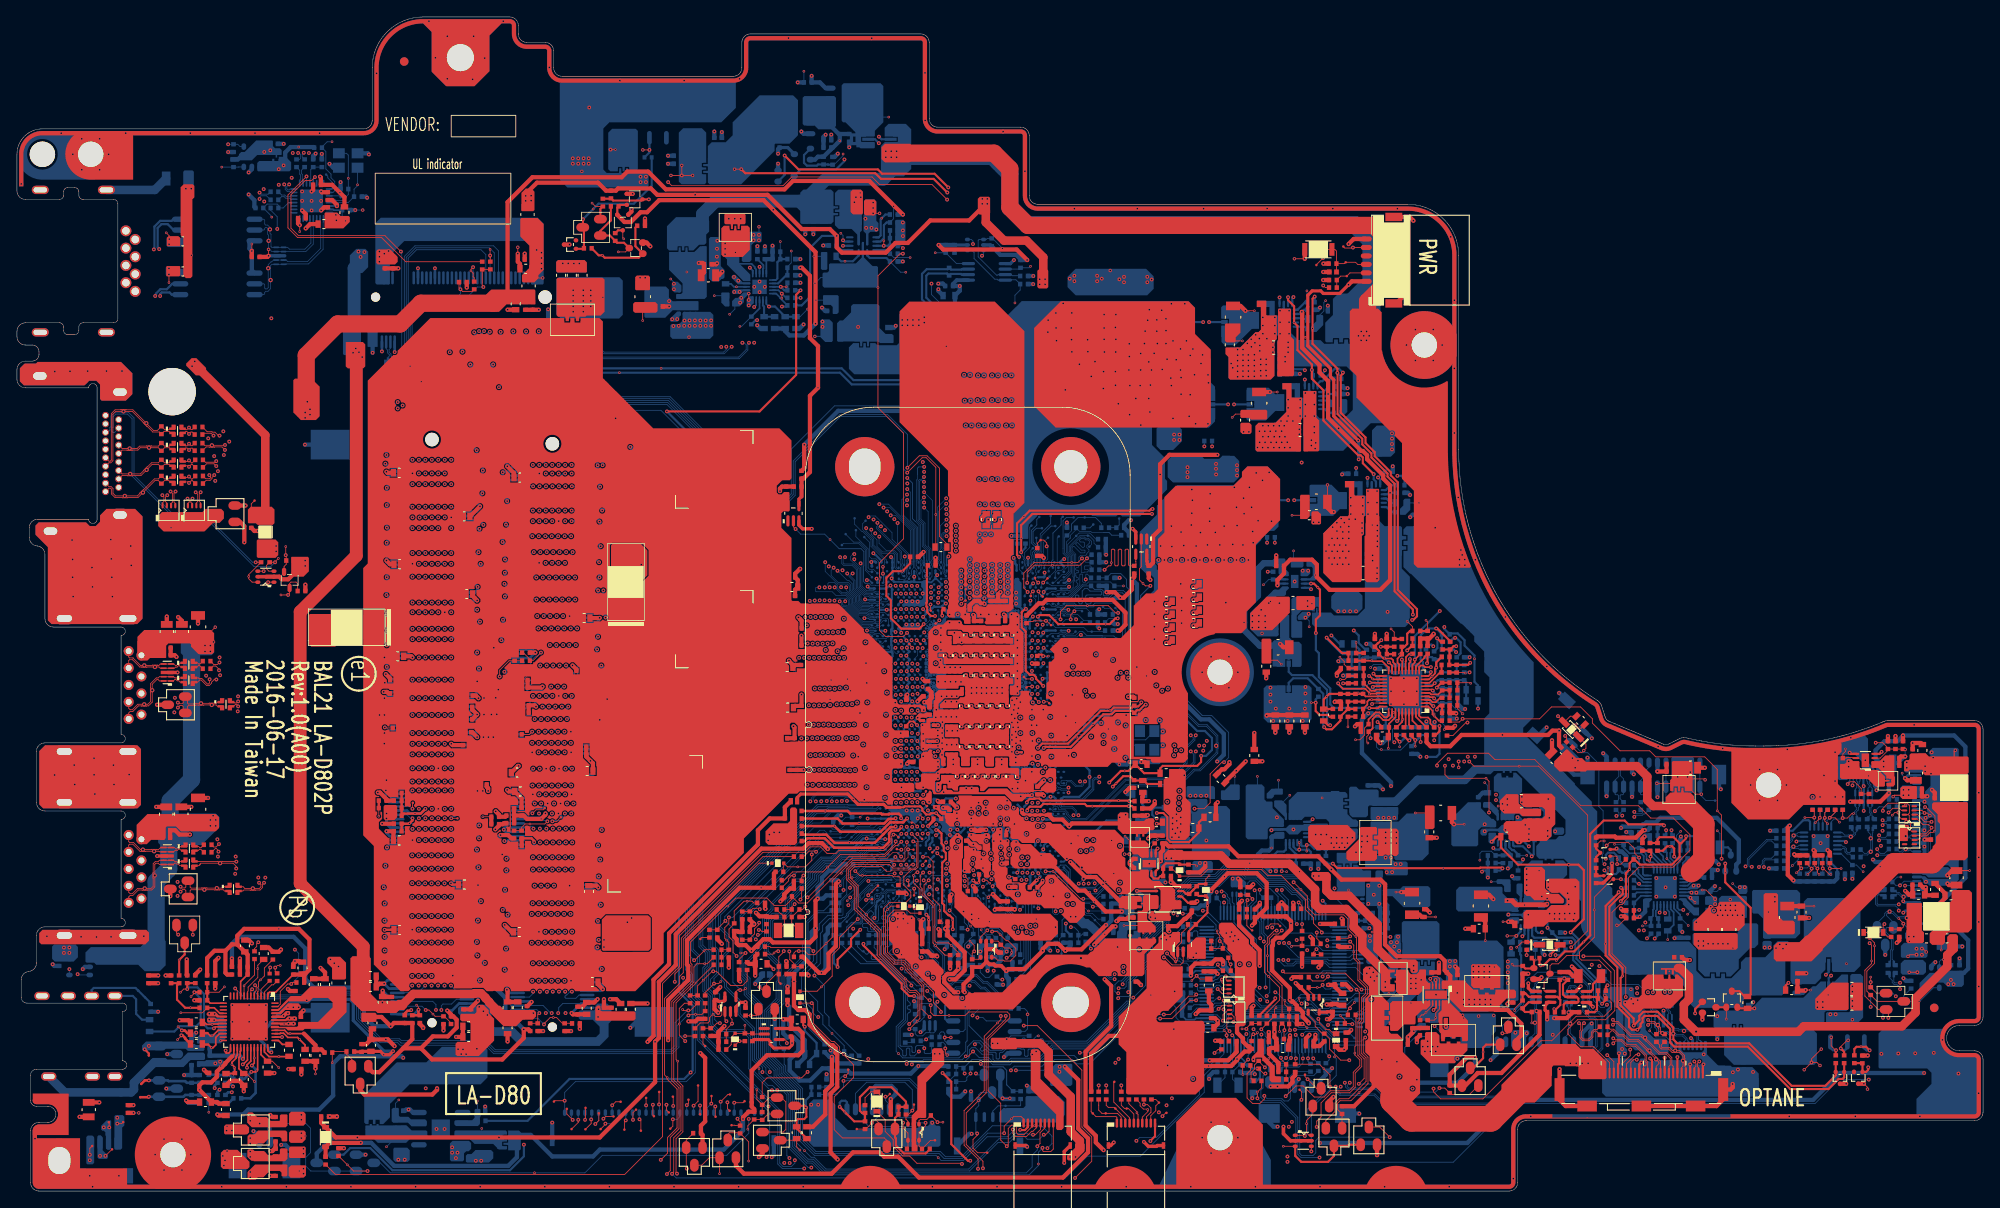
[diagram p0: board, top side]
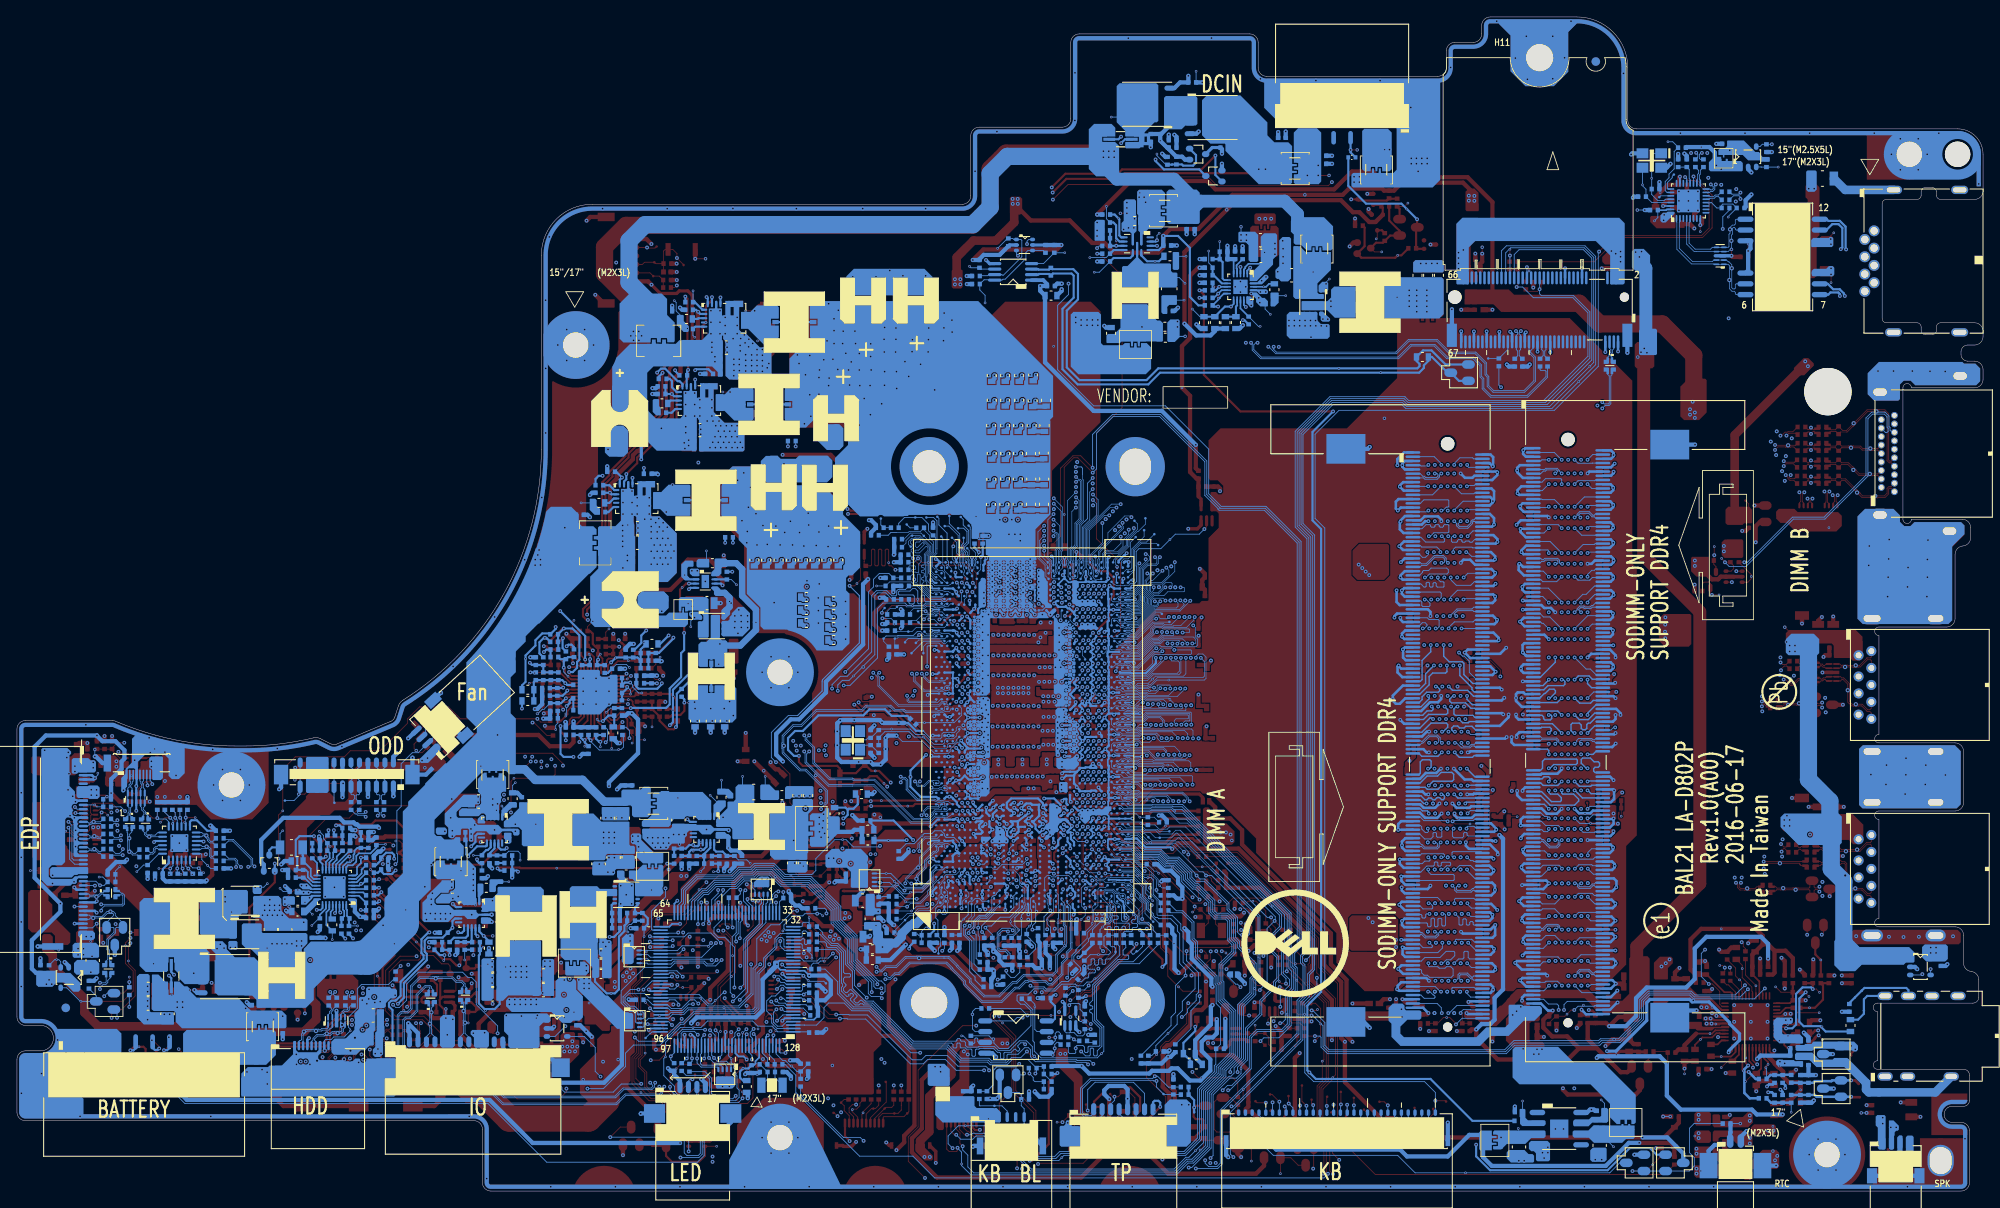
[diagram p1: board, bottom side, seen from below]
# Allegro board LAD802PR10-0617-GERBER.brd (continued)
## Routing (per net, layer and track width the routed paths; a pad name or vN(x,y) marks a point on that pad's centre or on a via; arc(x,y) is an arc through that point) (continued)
CORE_SNUB: length 1.3
  TOP w0.102: PC662.1 v1(150.39,79.72)
CORE_SW: length 3.6
  TOP w0.102: v4(154.58,83.29) PR663.1
  TOP w0.508: v2(155.32,80.1) 155.09,80.1 154.58,80.61 PR663.1
CPU_B+: length 17.1
  TOP w0.203: PR603.2 160.91,54.9 v2(160.48,55.33)
  IN2 w0.254: v2(160.48,55.33) 160.44,55.37 160.44,57.91 159.91,58.44 159.34,58.44 158.83,58.95 158.83,61.99 160.41,63.57 161.43,63.57 162.33,64.47 162.33,67.66 v2(161.67,68.32)
  vias: v1(159.86,78.57) v2(159.35,82.57) v2(159.35,81.21) v2(159.35,79.86) v2(159.9,74.99) v2(159.9,74.36) v2(160.42,82.57) v2(160.42,81.21) v2(160.42,79.86) v2(160.43,73.5) v2(160.42,72.88) v2(160.42,72.24) v2(160.46,78.52) v2(160.46,77.91) v2(160.46,77.27) v2(160.46,76.65) v2(160.46,76.04)
CPU_DP3_AUXN: length 1.3
  TOP w0.102: TP1.1 119.2,59.51 v2(119.74,59.51)
  BOTTOM w0.076: v2(119.74,59.51) 119.74,59.68 UC1.G46
CPU_DP3_AUXP: length 1.7
  TOP w0.102: v2(119.72,60.41) 119.02,60.41 TP2.1
  BOTTOM w0.076: UC1.F46 119.72,60.35 v2(119.72,60.41)
CPU_POPIRCOMP: length 14.5
  TOP w0.305: v2(104.31,42.97) 104.31,42.88 103.95,42.53 103.19,42.53 102.89,42.23 102.89,41.21 102.18,40.5 v1(101.68,40.5) 96.39,40.5 95.29,41.61 93.24,41.61 92.91,41.28 RC119.1
  BOTTOM w0.254: v2(104.31,42.97) 104.31,42.97 104.31,42.9 UC1.AT16
CPU_XDP_TCK0: length 6.8
  BOTTOM w0.076: UC1.B61 122.86,67.92 122.88,67.95 123.37,68.19 123.63,68.19 123.8,68.02 125.11,68.02 125.81,67.32 ; 125.81,67.32 125.57,67.07 TPC2.1 125.28,66.79 UC1.A59 ; 125.81,67.32 126.31,67.32 RC146.1
CPVEE: length 3.6
  TOP w0.102: v1(30.88,14.56) 30.13,15.31 CA25.2
  TOP w0.203: CA25.2 28.79,16.09 UA1.34
CS_1.2V: length 4.2
  BOTTOM w0.102: PR205.2 85.47,102 v1(85.26,102)
  BOTTOM w0.203: PR205.2 87.59,104.12 PU200.13
CSI2_COMP: length 9.2
  BOTTOM w0.102: RC7.1 127.02,40.98 126.08,40.98 v1(125.15,41.9) 124.88,42.18 123.97,42.18 123.65,42.5 122.89,42.5 122.51,42.12 122.51,41.93 122.32,41.74 122.31,41.74 122.3,41.72 121.39,41.72 120.75,41.09 UC1.E13
DAT_SMB: length 4
  TOP w0.102: v2(215.12,16.82) 215.12,17.04 215.87,17.79 v4(215.98,17.79)
  TOP w0.254: PR20.1 215.52,16.42 v2(215.12,16.82)
  BOTTOM w0.254: v2(215.12,16.82) 215.29,16.65 215.65,16.65 215.9,16.91 PBATT1.6
DAT_TP_SIO: length 93.2
  TOP w0.102: ZT12.1 98.04,13.9 v2(97.68,13.54)
  IN1 w0.127: v2(154.01,25.31) 154.01,26.82 152.86,27.97 152.86,28.71 151.26,30.31 147.19,30.31 147,30.5 146.36,30.5 146.23,30.37 144.4,30.37 143.54,31.22 142.22,31.22 140,29 138.53,29 134.01,24.48 134.01,22.66 132.61,21.27 132.61,20.33 128.5,16.23 126.23,16.23 125.65,15.64 124.99,15.64 124.4,16.22 121.91,16.22 120.87,15.19 119.37,15.19 118.33,16.23 114.21,16.23 112.89,14.91 107.48,14.91 106.58,14.01 98.22,14.01 97.75,13.54 v2(97.68,13.54)
  BOTTOM w0.102: v2(154.01,25.31) 154.45,25.75 154.9,25.75 155.07,25.58 UE1.79 ; R31.2 95.48,12.27 C26.1 96.08,12.25 97.37,13.54 v2(97.68,13.54) 97.94,13.29 105.3,13.29 106.45,12.15 106.45,9.16 105.94,8.65 104.16,8.65 103.9,8.91 JTP1.2
DBC_EN: length 151.8
  IN1 w0.127: v2(106.95,36.65) 106.95,35.83 107.34,35.45 107.97,35.45 108.92,34.5 111.53,34.5 111.64,34.61 116.34,34.61 117.63,35.9 122.35,35.9 124.23,37.79 124.61,37.79 124.79,37.97 126.26,37.97 130.47,42.18 134.71,42.18 135.38,42.85 135.38,44.38 136.13,45.13 136.13,46.84 137.18,47.9 155.21,47.9 159.41,52.09 159.49,52.17 161.08,52.17 161.13,52.22 167.37,52.22 168.33,53.18 171.8,53.18 172.99,53.18 181.07,45.1 181.72,45.1 185.03,41.79 185.03,40.11 185.44,39.7 185.44,33.95 186.96,32.43 186.96,31.2 189.3,28.86 193.91,28.86 194.52,29.47 194.52,30.19 197.21,32.89 197.21,33.44 196.24,34.42 196.24,37.36 199.03,40.15 208.19,40.15 210.92,42.88 215.26,42.88 216.62,44.24 218.57,44.24 v2(219.15,44.82)
  BOTTOM w0.076: UC1.AM5 107.21,36.39 v2(106.95,36.65)
  BOTTOM w0.102: R6.2 219.65,45.32 v2(219.15,44.82)
DBC_EN_R: length 3.3
  BOTTOM w0.102: JEDP1.10 v1(222.73,45.55) 222.5,45.32 R6.1 R5.2
DDC_CLK_HDMI: length 35.3
  TOP w0.102: QI2.6 27.74,71.82 27.34,72.23 v1(27.34,72.5) 27.34,72.72 RI13.1 v2(28.16,74.17)
  BOTTOM w0.102: JHDMI1.15 10.72,89.5 10.97,89.74 10.97,90.07 11.09,90.2 11.09,91.43 11.55,91.88 13.13,91.88 13.81,91.2 13.81,84.44 18.75,79.49 22.47,79.49 27.79,74.17 v2(28.16,74.17)
DDC_DATA_HDMI: length 36.9
  TOP w0.102: QI2.3 29.71,73.12 29.42,73.42 29.42,73.79 RI14.1 v2(30.44,74.17) 30.44,74.24 v1(30.84,74.63)
  BOTTOM w0.102: v2(30.44,74.17) 29.95,73.68 27.96,73.68 22.37,79.27 18.65,79.27 13.58,84.34 13.58,91.11 13.04,91.65 11.64,91.65 11.32,91.33 11.32,90.1 11.2,89.97 11.2,89.62 11.32,89.49 11.51,89.49 12,89.98 JHDMI1.16
DDR4_DRAMRST#: length 26.9
  TOP w0.102: CD29.1 59.71,63.52 60.5,62.73 RD8.1 60.85,62.57 v2(61.81,63.52)
  IN1 w0.127: v2(48.17,62.94) 49.79,64.56 60.76,64.56 v2(61.81,63.52)
  BOTTOM w0.102: JDIMM1.108 59.78,60.38 60.59,61.19 60.59,62.51 61.19,63.11 61.4,63.11 v2(61.81,63.52) ; JDIMM2.108 45.62,60.87 46.32,61.58 46.81,61.58 v2(48.17,62.94)
DDR_A_ACT#: length 51
  IN1 w0.076: v2(94.83,67.72) 94.02,68.53 91.79,68.53 91.19,69.13
  IN1 w0.211: 91.19,69.13 90.22,70.11 78.05,70.11 71.39,63.44 68.24,63.44 67.73,63.95 63.78,63.95 61.83,62 v2(61.72,62)
  BOTTOM w0.076: UC1.BA55 101.6,65.01 101.38,65.01 101.37,65.02 101.36,65.02 101.36,65.02 101.27,65.06 101.07,65.06 100.98,65.02 100.98,65.02 100.62,65.02 100.55,65.09 99.73,65.09 97.88,66.95 96.68,66.95 96.53,66.8 95.75,66.8 v2(94.83,67.72)
  BOTTOM w0.163: JDIMM1.114 60.01,58.88 60.28,59.14 60.28,59.38 61.72,60.82 v2(61.72,62)
DDR_A_ALERT#: length 53.2
  IN1 w0.076: v2(93.16,66.72) 90.86,66.72 89.57,68.01 89.54,68.01
  IN1 w0.211: 89.54,68.01 89.4,68.14 78.87,68.14 71.77,61.05 64.01,61.05 63.52,60.55 63.52,60.01 v2(63.02,59.51)
  BOTTOM w0.076: v2(93.16,66.72) 92.9,66.46 92.9,65.36 92.63,65.09 92.63,64.41 92.84,64.2 95.1,64.2 95.11,64.21 95.54,64.21 95.7,64.05 96.97,64.05 97.36,63.66 97.79,63.66 99.71,61.74 100.41,61.74 100.6,61.93 100.7,62.03 100.86,62.03 100.87,62.04 100.95,62.04 101.03,62.01 101.04,62 101.07,61.98 101.21,61.98 101.37,62.03 101.37,62.03 101.61,62.03 101.65,62 101.94,62 102.1,62.05 102.13,62.08 102.32,62.08 102.57,61.83 UC1.AW50
  BOTTOM w0.163: v2(63.02,59.51) 62.58,59.07 60.8,59.07 60.1,58.38 JDIMM1.116
DDR_A_BG0: length 52.3
  IN1 w0.076: 90.84,68.79 91.35,68.28 93.05,68.28 v2(93.6,67.72)
  IN1 w0.211: 90.84,68.79 90.01,69.62 78.26,69.62 71.59,62.95 68.03,62.95 67.53,63.46 64.2,63.46 63.7,62.96 63.7,62.46 v2(63.24,62)
  BOTTOM w0.076: UC1.AY55 102.37,64.89 102.08,64.6 101.92,64.52 101.74,64.52 101.58,64.57 101.44,64.57 101.22,64.51 101.1,64.51 101.02,64.54 100.99,64.56 100.64,64.56 100.44,64.36 99.8,64.36 98.16,66 98.16,66.36 97.73,66.78 96.75,66.78 96.6,66.64 95.52,66.64 95.45,66.71 94.62,66.71 v2(93.6,67.72)
  BOTTOM w0.163: v2(63.24,62) 63.23,61.99 63.23,61.27 63.4,61.11 64.92,61.11 65.33,60.69 65.33,59.72 66.43,58.62 JDIMM1.115
DDR_A_BG1: length 51.6
  IN1 w0.076: v2(92.98,67.71) 92.65,68.04 90.9,68.04 90.49,68.44
  IN1 w0.211: v2(64.77,62) 64.66,62.1 64.55,62.1 64.19,62.46 64.19,62.76 64.41,62.97 65.72,62.97 65.93,62.76 65.93,62.24 66.14,62.03 66.56,62.03 66.77,62.24 66.77,62.76 66.99,62.97 67.31,62.97 67.52,62.76 67.52,62.24 67.73,62.03 68.19,62.03 68.35,62.18 68.35,62.31 68.49,62.46 70.17,62.46 70.57,62.06 71.39,62.06 78.46,69.13 89.81,69.13 90.49,68.44
  BOTTOM w0.076: UC1.AY54 102.05,64.33 101.79,64.33 101.58,64.4 101.44,64.4 101.21,64.34 101.07,64.34 100.95,64.39 100.71,64.39 100.49,64.18 99.75,64.18 97.99,65.94 97.99,66.29 97.66,66.62 96.82,66.62 96.67,66.47 93.97,66.47 93.08,67.36 93.08,67.61 v2(92.98,67.71)
  BOTTOM w0.163: JDIMM1.113 66.52,59.13 65.75,59.89 65.75,61.01 v2(64.77,62)
DDR_A_BS0: length 52.1
  IN1 w0.076: v2(103.61,62.22) 103.11,61.72 103.11,61.15 102.05,60.09 100.91,60.09 98.66,57.84 95.14,57.84
  IN1 w0.211: 95.14,57.84 92.61,57.84 91.85,58.6 82.61,58.6 74.5,50.5 73.48,50.5 72.59,49.6 68.6,49.6 68.3,49.31 62.28,49.31 v2(60.81,47.84)
  BOTTOM w0.076: v2(103.61,62.22) 103.61,62.36 UC1.AU52
  BOTTOM w0.163: JDIMM1.150 60.77,47.87 v2(60.81,47.84)
DDR_A_BS1: length 52.3
  IN1 w0.076: v2(104.29,61.32) 104.29,61.78 104,62.07 104,62.46 103.8,62.66 103.31,62.66 102.94,62.29 102.94,61.21 102.07,60.34 100.12,60.34 98.11,58.33 95.14,58.33
  IN1 w0.211: v2(65.46,49.83) 65.49,49.8 68.09,49.8 68.39,50.09 72.39,50.09 73.28,50.99 74.3,50.99 82.4,59.09 92.93,59.09 93.69,58.33 95.14,58.33
  BOTTOM w0.076: UC1.AT48 104.54,60.81 104.43,60.81 104.12,61.12 104.12,61.23 104.21,61.32 v2(104.29,61.32)
  BOTTOM w0.163: v2(65.46,49.83) 65.28,49.83 65.1,50 65.1,50.71 65.26,50.87 66.13,50.87 66.38,50.63 66.38,49.29 66.54,49.13 JDIMM1.145
DDR_A_CAS#: length 53.5
  IN1 w0.076: 89.61,56.64 90.23,56.64 90.49,56.89 91.7,56.89 92.25,56.34 98.96,56.34 99.28,56.02 100.13,56.02 102.25,58.14 102.25,58.95 102.46,59.17 102.77,59.17 102.88,59.05 103.78,59.05 103.99,59.27 103.99,59.75 103.67,60.07 v2(103.67,60.41)
  IN1 w0.211: v2(62.37,46.8) 62.84,47.26 69.02,47.26 69.41,47.64 74.43,47.64 83.42,56.64 89.61,56.64
  BOTTOM w0.076: v2(103.67,60.41) 103.96,60.71 UC1.AU48
  BOTTOM w0.163: JDIMM1.156 59.85,46.38 59.87,46.36 61.94,46.36 v2(62.37,46.8)
DDR_A_CKE0: length 51.4
  IN1 w0.076: 91.53,69.48 91.53,69.41 92.1,68.85 95.92,68.85 96.79,67.99 96.79,67.72 96.71,67.65 96.09,67.65 v2(96.02,67.72)
  IN1 w0.211: 91.53,69.48 90.42,70.6 77.85,70.6 71.18,63.93 70.81,63.93 70.6,64.14 70.6,64.66 70.39,64.87 69.97,64.87 69.76,64.66 69.76,64.14 69.55,63.93 69.03,63.93 68.82,64.14 68.82,64.23 68.61,64.44 68.14,64.44 67.71,64.87 65.35,64.87 65.14,64.66 v2(65.14,64.41)
  BOTTOM w0.076: UC1.BA56 101.34,65.61 101.14,65.61 100.99,65.71 100.7,65.71 100.64,65.65 100.64,65.65 100.58,65.59 99.98,65.59 97.62,67.95 97.29,67.95 97.2,67.86 97.2,67.68 97.04,67.51 96.23,67.51 v2(96.02,67.72)
  BOTTOM w0.163: JDIMM1.109 66.37,60.13 66.17,60.33 66.17,62.59 65.14,63.61 v2(65.14,64.41)
DDR_A_CKE1: length 50.7
  IN1 w0.076: 91.88,69.83 91.88,69.83 92.54,69.17 95.84,69.17 97.49,67.52 v2(97.53,67.52)
  IN1 w0.211: 91.88,69.83 90.62,71.09 77.65,71.09 71.92,65.36 69.49,65.36 69.06,64.93 68.35,64.93 67.91,65.36 64.57,65.36 63.62,64.41 v2(63.62,64.41)
  BOTTOM w0.076: UC1.BB56 100.82,65.43 99.91,65.43 97.86,67.48 97.57,67.48 v2(97.53,67.52)
  BOTTOM w0.163: v2(63.62,64.41) 63.62,63.09 62.96,62.43 61.42,62.43 61.23,62.25 61.23,60.92 60.19,59.88 JDIMM1.110
DDR_A_CKE2: length 7.8
  BOTTOM w0.076: TP3.1 95.99,67.11 97.95,67.11 99.8,65.26 100.62,65.26 100.69,65.19 100.94,65.19 101.04,65.22 101.3,65.22 101.39,65.19 102.53,65.19 UC1.AW56
DDR_A_CKE3: length 6.6
  BOTTOM w0.076: TP4.1 96.98,68.22 97.59,68.22 100.05,65.76 100.51,65.76 100.63,65.88 101.05,65.88 101.17,65.79 101.7,65.79 UC1.AY56
DDR_A_CLK0: length 52.2
  IN1 w0.076: 93.26,61.13 93.28,61.16 93.92,61.16 94.19,61.42 100.48,61.42 102.48,63.42 103.91,63.42 104.1,63.62 104.1,63.81 v2(104.38,64.08)
  IN1 w0.122: v2(63.83,52.87) 63.91,52.87 64.09,52.69 64.09,52.47 64.39,52.17 65.57,52.17 65.67,52.27 65.86,52.27 66.12,52.54 66.12,52.6 66.25,52.72 66.61,52.72 66.73,52.6 66.73,52.54 67,52.27 67.57,52.27 67.84,52.54 67.84,52.6 67.96,52.72 68.33,52.72 68.45,52.6 68.45,52.54 68.72,52.27 69.35,52.27 69.71,52.63 70.08,52.63 70.44,52.27 71.68,52.27 72.43,53.03 73.45,53.03 81.56,61.13 93.26,61.13
  BOTTOM w0.076: UC1.AT53 104.55,63.63 104.38,63.8 v2(104.38,64.08)
  BOTTOM w0.097: v2(63.83,52.87) 64.03,53.08 64.03,53.47 64.34,53.78 65.39,53.78 66.14,53.04 66.27,53.04 66.35,53.13 JDIMM1.137
DDR_A_CLK1: length 52.1
  IN1 w0.076: 93.24,62.28 93.26,62.26 97.45,62.26 98.28,63.09 100.46,63.09 102.95,65.58 103.81,65.58 104.07,65.32 104.07,65.11 v2(104.26,64.92)
  IN1 w0.122: v2(61.53,52.87) 61.77,53.12 61.77,53.24 62.28,53.75 71.68,53.75 71.99,54.06 73.03,54.06 81.13,62.16 90.15,62.16 90.3,62.31 90.74,62.31 90.89,62.16 91.24,62.16 91.37,62.28 93.24,62.28
  BOTTOM w0.076: v2(104.26,64.92) 104.25,64.92 104.25,64.9 104.52,64.56 UC1.AT55
  BOTTOM w0.097: JDIMM1.138 59.83,52.87 60.01,52.69 60.37,52.69 60.6,52.47 61.3,52.47 61.54,52.72 61.54,52.85 v2(61.53,52.87)
DDR_A_CLK#0: length 52.2
  IN1 w0.076: v2(103.62,64.08) 103.9,63.81 103.9,63.7 103.82,63.62 102.39,63.62 100.39,61.63 94.11,61.63 93.84,61.36 93.26,61.36 93.24,61.38
  IN1 w0.122: v2(64.57,52.87) 64.49,52.87 64.35,52.73 64.35,52.56 64.49,52.42 65.46,52.42 65.57,52.52 65.75,52.52 65.88,52.64 65.88,52.71 66.14,52.97 66.71,52.97 66.98,52.71 66.98,52.64 67.1,52.52 67.47,52.52 67.59,52.64 67.59,52.71 67.86,52.97 68.43,52.97 68.7,52.71 68.7,52.64 68.82,52.52 69.25,52.52 69.61,52.88 70.18,52.88 70.54,52.52 71.57,52.52 72.33,53.28 73.35,53.28 81.45,61.38 93.24,61.38
  BOTTOM w0.076: v2(103.62,64.08) 103.5,64.08 103.42,64.01 103.42,63.67 103.72,63.38 103.82,63.38 103.96,63.52 103.96,63.63 UC1.AU53
  BOTTOM w0.097: JDIMM1.139 66.41,52.62 66.19,52.85 66.06,52.85 65.31,53.6 64.42,53.6 64.22,53.4 64.22,52.96 64.37,52.81 64.51,52.81 v2(64.57,52.87)
DDR_A_CLK#1: length 52.3
  IN1 w0.076: 93.24,62.03 93.25,62.03 93.27,62.06 97.54,62.06 98.36,62.88 100.54,62.88 103.03,65.37 103.72,65.37 103.87,65.23 103.87,65.13 103.63,64.89 103.58,64.89 v2(103.61,64.89)
  IN1 w0.122: 93.24,62.03 91.47,62.03 91.34,61.91 90.79,61.91 90.64,62.06 90.4,62.06 90.25,61.91 81.23,61.91 73.13,53.81 72.09,53.81 71.79,53.5 62.39,53.5 62.02,53.14 62.02,53.01 62.17,52.87 v2(62.29,52.87)
  BOTTOM w0.076: v2(103.61,64.89) 103.58,64.89 103.73,64.87 103.96,64.55 UC1.AU55
  BOTTOM w0.097: v2(62.29,52.87) 62.1,52.87 61.51,52.28 60.52,52.28 60.29,52.5 60.02,52.5 59.99,52.47 59.96,52.47 59.87,52.38 JDIMM1.140
DDR_A_CS#0: length 55.2
  IN1 w0.076: 89.98,57.13 90.53,57.13 90.69,57.28 91.54,57.28 92.26,56.57 99.09,56.57 99.28,56.76 100.58,56.76 102,58.18 102,59.14 102.72,59.85 103.19,59.85 v2(103.62,59.42)
  IN1 w0.211: v2(65.38,47.84) 68.91,47.84 69.21,48.13 73.79,48.13 74,48.34 74,48.81 74.21,49.03 75.11,49.03 83.22,57.13 89.98,57.13
  BOTTOM w0.076: UC1.AU45 103.79,58.88 103.59,58.88 103.42,59.05 103.42,59.21 v2(103.62,59.42)
  BOTTOM w0.163: JDIMM1.149 66.4,48.13 65.57,48.96 64.34,48.96 63.91,49.39 62.66,49.39 62.44,49.17 62.44,48.53 62.63,48.34 64.87,48.34 v2(65.38,47.84)
DDR_A_CS#1: length 56
  IN1 w0.076: v2(103.65,58.52) 103.22,58.52 100.4,55.69 99.1,55.69 98.83,55.96 92.16,55.96 91.56,56.56 90.96,56.56 90.23,55.84 90.05,55.66 89.61,55.66
  IN1 w0.211: v2(65.64,45.72) 65.87,45.49 67.88,45.49 68.09,45.7 68.09,46.07 68.3,46.28 68.72,46.28 68.94,46.07 68.94,45.7 69.15,45.49 69.57,45.49 69.78,45.7 69.78,46.45 69.99,46.66 70.41,46.66 70.62,46.45 70.62,45.7 70.83,45.49 71.25,45.49 71.46,45.7 71.46,46.45 71.68,46.66 72.1,46.66 72.31,46.45 72.31,45.7 72.52,45.49 72.94,45.49 73.15,45.7 73.15,46.45 73.36,46.66 73.78,46.66 73.99,46.45 73.99,45.7 74.21,45.49 74.8,45.49 75.13,45.82 75.13,46.12 74.86,46.39 74.86,46.69 75.07,46.9 75.37,46.9 75.64,46.63 75.94,46.63 76.18,46.87 76.18,47.17 75.91,47.44 75.91,47.74 83.83,55.66 89.61,55.66
  BOTTOM w0.076: v2(103.65,58.52) 103.62,58.55 103.5,58.55 103.42,58.47 103.42,58.06 103.5,57.98 103.89,57.98 103.96,58.06 UC1.AU43
  BOTTOM w0.163: v2(65.64,45.72) 65.98,45.72 66.38,46.13 JDIMM1.157
DDR_A_D0: length 68.7
  IN1 w0.076: 107.84,82.7 v2(106.98,81.83)
  IN1 w0.127: 107.84,82.7 108.22,83.08 108.22,87.18 103.01,92.39 93.49,92.39 90.87,89.78 67.54,89.78 63.83,86.08 62.79,86.08 v2(62.37,85.66)
  BOTTOM w0.076: v2(106.98,81.83) 106.62,81.48 106.62,79.27 107.11,78.79 107.11,76.21 107.65,75.67 107.65,74.19 UC1.AL71
  BOTTOM w0.102: JDIMM1.4 60.09,86.37 60.21,86.5 61.7,86.5 62.37,85.83 v2(62.37,85.66)
DDR_A_D1: length 69.9
  IN1 w0.076: v2(106.99,82.44) 107.84,83.29
  IN1 w0.127: v2(63.9,85.66) 67.68,89.44 87.4,89.44 87.53,89.31 87.53,89.11 87.65,88.98 87.91,88.98 88.04,89.11 88.04,89.31 88.16,89.44 88.43,89.44 88.56,89.31 88.56,89.17 88.69,89.05 88.94,89.05 89.07,89.17 89.07,89.31 89.19,89.44 89.45,89.44 89.57,89.31 89.57,89.17 89.7,89.05 89.96,89.05 90.08,89.17 90.08,89.31 90.21,89.44 91.02,89.44 93.63,92.05 102.87,92.05 107.88,87.04 107.88,83.33 107.84,83.29
  BOTTOM w0.076: v2(106.99,82.44) 107.98,81.45 107.98,74.51 108.09,74.4 108.09,74.01 108.08,73.97 108.05,73.82 108.01,73.69 108.01,73.69 107.92,73.47 107.92,72.49 107.67,72.23 UC1.AL68
  BOTTOM w0.102: JDIMM1.3 64.72,86.62 63.9,85.8 v2(63.9,85.66)
DDR_A_D2: length 70.4
  IN1 w0.127: v2(62.4,83.13) 62.22,83.13 61.98,82.89 61.98,82.53 62.84,81.67 67.48,81.67 67.67,81.86 67.67,82.04 67.5,82.21 67.5,82.39 67.68,82.57 67.86,82.57 68.03,82.4 68.21,82.4 68.39,82.58 68.39,82.76 68.22,82.93 68.22,83.11 68.74,83.64 68.92,83.64 69.09,83.47 69.27,83.47 69.45,83.64 69.45,83.82 69.28,84 69.28,84.17 69.46,84.35 69.64,84.35 69.81,84.18 69.99,84.18 70.17,84.36 70.17,84.54 70,84.71 70,84.89 70.6,85.49 92.72,85.49 96.62,89.39 101.55,89.39 103.53,87.4 103.53,83.49 103.83,83.19 104.4,83.19 104.58,83.01 104.58,82.57 v2(104.99,82.16)
  BOTTOM w0.076: UC1.AN68 106.16,72.73 106.12,72.94 106.15,73.04 106.17,73.15 106.12,73.32 105.91,73.52 105.91,74.31 105.91,74.31 105.91,78.15 104.37,79.69 104.37,81.55 v2(104.99,82.16)
  BOTTOM w0.102: v2(62.4,83.13) 61.52,82.25 60.05,82.25 59.93,82.37 JDIMM1.20
DDR_A_D3: length 69.6
  IN1 w0.127: v2(63.93,83.13) 63.76,83.13 63.34,82.71 62.97,82.71 62.85,82.59 62.85,82.15 62.99,82.01 63.8,82.01 63.93,82.14 63.93,82.31 64.05,82.44 64.31,82.44 64.43,82.31 64.43,82.14 64.56,82.01 64.81,82.01 64.94,82.14 64.94,82.59 65.07,82.71 65.32,82.71 65.45,82.59 65.45,82.14 65.58,82.01 65.83,82.01 65.96,82.14 65.96,82.59 66.08,82.71 66.34,82.71 66.47,82.59 66.47,82.14 66.59,82.01 66.85,82.01 66.97,82.14 66.97,82.59 67.1,82.71 67.34,82.71 70.49,85.87 92.62,85.87 96.48,89.73 101.69,89.73 103.87,87.54 103.87,85.25 v2(105.01,84.12)
  BOTTOM w0.076: 105.98,78.97 105.99,78.97 106.4,78.56 106.4,74.53 106.61,74.32 106.61,74.08 106.55,73.96 106.55,73.8 106.62,73.57 106.62,73.44 106.54,73.22 106.54,72.96 UC1.AN69
  BOTTOM w0.102: v2(63.93,83.13) 64.93,82.13 JDIMM1.21 ; v2(105.01,84.12) 105.64,83.49 105.64,79.31 105.98,78.97
DDR_A_D4: length 69.8
  IN1 w0.076: 107.84,81.48 v2(107,80.63)
  IN1 w0.127: 107.84,81.48 108.57,82.2 108.57,87.32 103.15,92.74 93.34,92.74 90.73,90.12 67.39,90.12 63.69,86.42 61.61,86.42 v2(60.85,85.66)
  BOTTOM w0.076: v2(107,80.63) 107.48,80.15 107.48,76.07 107.81,75.74 107.81,74.43 107.92,74.32 107.92,74.04 107.9,73.96 107.84,73.84 107.67,73.66 UC1.AL70
  BOTTOM w0.102: v2(60.85,85.66) 60.85,85.53 60.69,85.37 JDIMM1.8
DDR_A_D5: length 70.7
  IN1 w0.127: v2(65.42,85.66) 68.05,88.28 78.64,88.28 78.77,88.41 78.77,88.73 78.89,88.85 79.15,88.85 79.28,88.73 79.28,88.41 79.4,88.28 79.66,88.28 79.78,88.41 79.78,88.73 79.91,88.85 80.16,88.85 80.29,88.73 80.29,88.41 80.42,88.28 80.67,88.28 80.8,88.41 80.8,88.73 80.93,88.85 81.18,88.85 81.31,88.73 81.31,88.41 81.43,88.28 81.69,88.28 81.82,88.41 81.82,88.73 81.94,88.85 82.2,88.85 82.32,88.73 82.32,88.41 82.45,88.28 82.7,88.28 82.83,88.41 82.83,88.73 82.96,88.85 83.21,88.85 83.34,88.73 83.34,88.41 83.47,88.28 83.72,88.28 83.85,88.41 83.85,88.73 83.97,88.85 84.23,88.85 84.36,88.73 84.36,88.41 84.48,88.28 90.35,88.28 93.77,91.71 102.73,91.71 107.54,86.9 107.54,85.94 107.02,85.42 v2(107,85.42)
  BOTTOM w0.076: 106.22,84.52 106.22,83.99 106.13,83.89 106.13,79.07 106.57,78.62 106.57,74.59 106.78,74.39 106.78,74.02 106.76,73.99 106.73,73.91 106.73,73.79 106.79,73.57 106.79,73.43 106.74,73.27 106.74,73.09 106.78,73.01 106.78,72.53 106.79,72.41 106.94,72.26 107.31,72.26 107.67,72.62 UC1.AL69
  BOTTOM w0.102: v2(107,85.42) 106.37,85.42 106.22,85.28 106.22,84.52 ; JDIMM1.7 66.39,85.62 66.3,85.53 65.55,85.53 v2(65.42,85.66)
DDR_A_D6: length 68.9
  IN1 w0.127: v2(105,81.52) 104.96,81.52 103.19,83.29 103.19,87.26 101.4,89.05 96.76,89.05 92.86,85.15 71.44,85.15 67.62,81.33 62.29,81.33 62.16,81.45 62.16,81.87 62.03,82 61.78,82 61.65,81.87 61.65,81.45 61.53,81.33 61.27,81.33 61.14,81.45 61.14,81.87 61.02,82 60.76,82 60.64,81.87 60.64,81.45 60.51,81.33 60.23,81.33 60.1,81.45 60.1,82.98 60.26,83.13 v2(60.88,83.13)
  BOTTOM w0.076: UC1.AN70 106.08,73.78 106.08,74.34 106.07,74.34 106.07,78.22 104.54,79.75 104.54,81.06 v2(105,81.52)
  BOTTOM w0.102: v2(60.88,83.13) 60.79,83.22 60.03,83.22 59.88,83.37 JDIMM1.16
DDR_A_D7: length 67.9
  IN1 w0.127: v2(65.45,83.13) 67.27,83.13 67.45,83.31 67.45,83.49 67.15,83.79 67.15,83.97 67.33,84.15 67.51,84.15 67.81,83.85 67.99,83.85 68.17,84.03 68.17,84.21 67.87,84.51 67.87,84.69 68.05,84.87 68.23,84.87 68.53,84.57 68.71,84.57 70.58,86.44 91.75,86.44 91.9,86.6 91.9,86.69 92.08,86.87 92.26,86.87 92.61,86.53 92.79,86.53 92.97,86.71 92.97,86.89 92.62,87.23 92.62,87.41 92.8,87.59 92.98,87.59 93.33,87.24 93.51,87.24 93.69,87.42 93.69,87.6 93.34,87.95 93.34,88.13 93.52,88.31 93.7,88.31 94.05,87.96 94.23,87.96 94.41,88.14 94.41,88.32 93.8,88.92 93.8,89.1 93.98,89.28 94.16,89.28 94.77,88.68 94.95,88.68 95.13,88.86 95.13,89.04 94.59,89.58 94.59,89.76 94.77,89.94 94.95,89.94 95.48,89.4 95.66,89.4 96.34,90.07 102.21,90.07 105.5,86.79 105.5,83.3 105.01,82.81 v2(105.01,82.81)
  BOTTOM w0.076: UC1.AN71 106.34,74.27 106.24,74.37 106.24,78.29 105.37,79.16 105.37,82.45 v2(105.01,82.81)
  BOTTOM w0.102: JDIMM1.17 65.67,83.13 65.66,83.13 v2(65.45,83.13)
DDR_A_D8: length 56.8
  IN1 w0.127: v2(65.42,80.27) 67.95,80.27 70.41,82.73 70.59,82.73 70.8,82.52 70.98,82.52 71.16,82.7 71.16,82.88 70.95,83.09 70.95,83.27 71.13,83.45 71.31,83.45 71.52,83.24 71.7,83.24 71.88,83.42 71.88,83.6 71.67,83.81 71.67,83.99 71.85,84.17 90.88,84.17 91.03,84.01 91.03,83.59 91.16,83.46 91.54,83.46 91.67,83.59 91.67,84.04 91.8,84.17 92.18,84.17 92.3,84.04 92.3,83.59 92.43,83.46 92.81,83.46 92.94,83.59 92.94,84.04 93.07,84.17 93.45,84.17 93.57,84.04 93.57,83.59 93.7,83.46 94.08,83.46 94.21,83.59 94.21,84.09 94.34,84.22 94.72,84.22 94.84,84.09 94.84,83.59 94.97,83.46 95.35,83.46 95.48,83.59 95.48,83.67 95.61,83.8 96.36,83.8 98.54,81.63 101.81,81.63 102.21,81.22 v2(102.21,80.63)
  BOTTOM w0.076: UC1.AR70 105.31,73.66 105.58,73.93 105.58,74.25 105.58,74.25 105.58,78.01 102.97,80.63 v2(102.21,80.63)
  BOTTOM w0.102: JDIMM1.29 65.57,80.13 v2(65.42,80.27)
DDR_A_D9: length 58.7
  IN1 w0.127: v2(63.9,80.27) 63.8,80.18 63.8,79.98 63.93,79.85 68.02,79.85 68.95,80.79 69.74,80.79 72.77,83.83 89.82,83.83 90.53,83.12 96.56,83.12 98.4,81.28 101.46,81.28 v2(101.71,81.03)
  BOTTOM w0.076: v2(101.71,81.03) 102.8,81.03 105.74,78.08 105.74,74.28 105.75,74.28 105.75,73.52 105.51,73.24 105.48,73.09 105.49,73.03 105.54,72.92 105.55,72.86 105.54,72.77 105.54,72.74 105.22,72.41 UC1.AR68
  BOTTOM w0.102: JDIMM1.25 66.36,81.13 65.94,81.54 63.11,81.54 63.01,81.44 63.01,80.78 63.11,80.68 63.3,80.68 63.71,80.27 v2(63.9,80.27)
DDR_A_D10: length 55.2
  IN1 w0.127: v2(101.71,77.2) 101.8,77.11 102,77.11 102.15,77.25 102.15,77.43 100.61,78.97 97.59,78.97 95.65,80.91 84.57,80.91 84.3,81.18 84.04,81.18 83.91,81.06 83.91,80.98 83.79,80.85 83.53,80.85 83.41,80.98 83.41,81.06 83.28,81.18 83.03,81.18 82.9,81.06 82.9,80.98 82.77,80.85 82.52,80.85 82.39,80.98 82.39,81.06 82.26,81.18 82.01,81.18 81.88,81.06 81.88,80.98 81.76,80.85 81.5,80.85 81.37,80.98 81.37,81.06 81.25,81.18 80.99,81.18 80.87,81.06 80.87,80.98 80.74,80.85 80.49,80.85 80.36,80.98 80.36,81.06 80.23,81.18 73.25,81.18 69.31,77.25 v2(65.36,77.25)
  BOTTOM w0.076: v2(101.71,77.2) 101.68,77.17 101.68,76.41 102.53,75.56 103.49,75.56 103.87,75.18 103.87,74.25 103.96,74.16 UC1.AU71
  BOTTOM w0.102: v2(65.36,77.25) 65.18,77.25 64.77,77.65 63.11,77.65 63.01,77.75 63.01,78.51 63.11,78.62 63.53,78.62 63.63,78.51 63.63,78.42 63.73,78.31 64.04,78.31 64.14,78.42 64.14,78.51 64.24,78.62 64.55,78.62 64.65,78.51 64.65,78.42 64.75,78.31 65.06,78.31 65.16,78.42 65.16,78.51 65.26,78.62 65.69,78.62 66.19,78.13 JDIMM1.37
DDR_A_D11: length 57.6
  IN1 w0.127: v2(100.45,79.49) 100.26,79.31 97.74,79.31 95.79,81.25 89.12,81.25 88.98,81.39 88.98,81.56 88.85,81.68 88.59,81.68 88.46,81.56 88.46,81.38 88.34,81.25 84.71,81.25 84.28,81.68 82.28,81.68 82.12,81.53 81.36,81.53 81.2,81.68 80.8,81.68 80.65,81.53 80.16,81.53 80,81.68 79.5,81.68 79.34,81.53 78.97,81.53 78.81,81.68 78.39,81.68 78.23,81.53 77.89,81.53 77.73,81.68 77.38,81.68 77.22,81.53 76.87,81.53 76.71,81.68 76.36,81.68 76.2,81.53 75.85,81.53 75.69,81.68 75.35,81.68 75.19,81.53 74.84,81.53 74.68,81.68 74.33,81.68 74.17,81.53 73.82,81.53 73.66,81.68 73.26,81.68 69.19,77.61 67.16,77.61 67.03,77.75 66.71,77.75 66.58,77.61 65.87,77.61 65.76,77.72 63.72,77.72 63.56,77.56 63.56,77.38 63.69,77.25 63.84,77.25 v2(63.84,77.25)
  BOTTOM w0.076: v2(100.45,79.49) 100.59,79.63 101.24,79.63 103.22,77.66 103.22,76.89 105.08,75.03 105.08,74.59 104.88,74.39 104.88,74.02 104.9,73.99 104.93,73.91 104.93,73.79 104.87,73.57 104.87,73.43 104.94,73.21 104.92,72.75 104.99,72.56 104.99,72.49 104.87,72.29 104.76,72.17 104.33,72.15 104.07,72.16 UC1.AU68
  BOTTOM w0.102: v2(63.84,77.25) 63.51,76.91 63.51,76.66 63.61,76.56 65.74,76.56 66.31,77.13 JDIMM1.41
DDR_A_D12: length 56.1
  IN1 w0.127: v2(62.37,80.27) 62.79,80.69 67.88,80.69 71.7,84.51 93.13,84.51 93.32,84.7 95.95,84.7 98.68,81.97 102.1,81.97 103.06,81.01 v2(103.06,79.71)
  BOTTOM w0.076: UC1.AR71 105.41,74.26 105.41,77.95 103.65,79.71 v2(103.06,79.71)
  BOTTOM w0.102: JDIMM1.24 61.32,81.37 62.37,80.32 v2(62.37,80.27)
DDR_A_D13: length 56.9
  IN1 w0.127: v2(103.87,78.8) 103.35,78.8 101.32,80.83 98.37,80.83 96.42,82.77 90.39,82.77 89.96,83.2 72.63,83.2 68.94,79.51 60.28,79.51 60.15,79.64 60.15,80.15 60.28,80.27 v2(60.85,80.27)
  BOTTOM w0.076: UC1.AR69 105.11,72.96 105.11,73.22 105.04,73.44 105.04,73.57 105.1,73.8 105.1,73.9 105.11,73.91 105.05,74.06 105.05,74.32 105.25,74.52 105.25,75.1 103.87,76.47 v2(103.87,78.8)
  BOTTOM w0.102: JDIMM1.28 60.75,80.37 v2(60.85,80.27)
DDR_A_D14: length 56.1
  IN1 w0.127: v2(62.32,77.25) 62.15,77.25 61.73,76.83 61.68,76.83 61.55,76.7 61.55,76.48 61.68,76.35 62.25,76.35 62.67,76.77 65.47,76.77 65.61,76.9 66.09,76.9 66.32,76.67 66.82,76.67 67.04,76.9 67.36,76.9 67.59,76.67 68.09,76.67 68.31,76.9 69.6,76.9 73.54,80.84 80.02,80.84 80.02,80.84 80.34,80.51 84.31,80.51 84.37,80.57 95.51,80.57 97.45,78.62 100.47,78.62 100.77,78.33 v2(100.77,78.02)
  BOTTOM w0.076: v2(100.77,78.02) 100.77,77.49 101.44,76.81 101.44,76.03 102.08,75.4 103.42,75.4 103.71,75.11 103.71,73.58 103.83,73.46 103.94,73.46 UC1.AU70
  BOTTOM w0.102: JDIMM1.42 59.94,76.88 60.28,76.54 60.51,76.54 60.65,76.68 61,76.68 61.14,76.54 61.37,76.54 61.47,76.64 61.47,76.74 61.57,76.84 61.87,76.84 61.98,76.74 61.98,76.64 62.08,76.54 62.59,76.54 62.69,76.64 62.69,77.11 62.56,77.25 v2(62.32,77.25)
DDR_A_D15: length 56.4
  IN1 w0.127: v2(60.79,77.25) 60.79,77.49 60.67,77.62 59.46,77.62 59.33,77.49 59.33,76.13 59.46,76.01 62.39,76.01 62.81,76.43 65.95,76.43 66.04,76.33 68.33,76.33 68.49,76.48 69.67,76.48 73.35,80.17 84.45,80.17 84.51,80.23 95.36,80.23 97.31,78.28 100.09,78.28 v2(100.16,78.2)
  BOTTOM w0.076: UC1.AU69 103.99,73.07 103.54,73.52 103.54,73.7 103.53,73.71 103.53,75.05 103.35,75.23 102.01,75.23 101.06,76.18 101.06,76.96 100.15,77.87 100.15,78.19 v2(100.16,78.2)
  BOTTOM w0.102: v2(60.79,77.25) 60.16,77.88 JDIMM1.38
DDR_A_D16: length 49.5
  IN1 w0.127: v2(98.76,75.14) 98.76,75.14 97.09,76.81 96.91,76.81 94.82,78.91 91.34,78.91 91.13,78.69 90.79,78.69 90.58,78.91 90.33,78.91 90.15,78.73 80.77,78.73 80.69,78.65 73.7,78.65 70.01,74.95 68.01,74.95 67.89,74.83 67.89,74.79 67.76,74.66 67.51,74.66 67.38,74.79 67.38,74.83 67.25,74.96 67,74.96 66.87,74.83 66.87,74.79 66.74,74.66 66.49,74.66 66.36,74.79 66.36,74.83 66.24,74.96 65.98,74.96 65.86,74.83 65.86,74.79 65.73,74.66 65.47,74.66 65.35,74.79 65.35,74.8 65.22,74.93 64.18,74.93 63.96,75.14 63.96,75.32 v2(64.01,75.37)
  BOTTOM w0.076: v2(98.76,75.14) 98.6,75.14 98.33,74.86 98.33,74.44 99.33,73.44 99.33,71.25 100.09,70.5 100.76,70.5 UC1.BB65
  BOTTOM w0.102: v2(64.01,75.37) 64.01,75.55 64.43,75.97 66.21,75.97 66.37,76.13 JDIMM1.45
DDR_A_D17: length 51.1
  IN1 w0.127: v2(98.57,72.85) 98.27,73.15 98.27,73.44 99.18,74.35 99.18,75.31 97.34,77.15 97.05,77.15 94.96,79.25 90.18,79.25 90.01,79.08 89.59,79.08 89.42,79.25 89.17,79.25 89,79.08 88.58,79.08 88.41,79.25 88.15,79.25 87.98,79.08 87.56,79.08 87.39,79.25 87.14,79.25 86.96,79.08 86.55,79.08 86.37,79.25 86.12,79.25 85.95,79.08 85.53,79.08 85.36,79.25 85.1,79.25 84.93,79.08 73.64,79.08 69.87,75.3 65.6,75.3 v2(65.53,75.37)
  BOTTOM w0.076: v2(98.57,72.85) 98.39,72.85 98.32,72.78 98.32,72.55 98.84,72.03 98.84,71.05 99.55,70.34 99.55,69.76 99.88,69.43 100.45,69.43 100.52,69.5 101.02,69.5 101.1,69.47 101.22,69.47 101.44,69.53 101.58,69.53 101.74,69.48 101.97,69.48 102.01,69.51 102.61,69.51 102.8,69.7 UC1.AW65
  BOTTOM w0.102: v2(65.53,75.37) 65.51,75.37 65.4,75.26 65.4,75.12 65.76,74.76 66.12,74.76 66.49,75.13 JDIMM1.49
DDR_A_D18: length 52.9
  IN1 w0.127: v2(64.31,72.38) 64.2,72.27 64.2,72.09 64.32,71.96 68.05,71.96 68.4,71.62 70.27,71.62 74.75,76.09 93.71,76.09 95.33,74.46 v2(95.33,74.19)
  BOTTOM w0.076: UC1.AW63 102.72,69.25 102.62,69.25 102.23,68.86 102.12,68.86 101.99,68.88 101.86,68.88 101.72,68.87 101.52,68.66 100.63,68.66 100.52,68.77 99.61,68.77 98.89,69.49 98.89,70.06 98.18,70.77 98.18,71.37 97.94,71.6 96.82,71.6 95.33,73.09 v2(95.33,74.19)
  BOTTOM w0.102: v2(64.31,72.38) 64.31,72.18 64,71.87 63.69,71.87 63.58,71.77 63.58,71.32 63.66,71.25 64.37,71.25 64.5,71.38 64.5,71.67 64.6,71.77 64.77,71.77 64.87,71.67 64.87,71.35 64.98,71.25 65.18,71.25 65.28,71.35 65.28,71.71 65.38,71.81 65.59,71.81 65.69,71.71 65.69,71.35 65.79,71.25 65.93,71.25 66.31,71.62 JDIMM1.63
DDR_A_D19: length 51.5
  IN1 w0.127: v2(97.93,72.85) 97.93,73.27 96.25,74.95 96.14,74.95 94.31,76.77 74.46,76.77 70.49,72.8 62.88,72.8 61.99,73.68 61.04,73.68 60.92,73.55 60.92,72.72 v2(61.26,72.38)
  BOTTOM w0.076: UC1.AY63 102.05,69.28 101.79,69.28 101.58,69.36 101.44,69.36 101.21,69.29 101.07,69.29 100.98,69.34 100.59,69.34 100.52,69.26 99.81,69.26 99.38,69.7 99.38,70.27 98.67,70.98 98.67,71.96 98.15,72.48 98.15,72.62 v2(97.93,72.85)
  BOTTOM w0.102: v2(61.26,72.38) 60.77,72.88 JDIMM1.58
DDR_A_D20: length 50.5
  IN1 w0.127: v2(98.76,74.53) 98.32,74.97 98.32,75.03 96.89,76.47 96.77,76.47 94.67,78.56 91.48,78.56 91.23,78.31 90.7,78.31 90.62,78.39 80.91,78.39 80.83,78.31 73.85,78.31 70.14,74.61 68.49,74.61 68.2,74.32 65.02,74.32 64.81,74.52 64.12,74.52 64.01,74.63 60.89,74.63 60.73,74.79 60.73,75.24 60.85,75.37 v2(60.96,75.37)
  BOTTOM w0.076: v2(98.76,74.53) 98.76,74.28 99.5,73.54 99.5,71.32 100.16,70.66 100.98,70.66 101.2,70.56 101.2,70.55 101.21,70.55 101.35,70.41 UC1.BA65
  BOTTOM w0.102: JDIMM1.50 60.33,74.88 60.82,75.37 v2(60.96,75.37)
DDR_A_D21: length 51.5
  IN1 w0.127: v2(62.49,75.37) 62.66,75.37 63.07,75.79 65.71,75.79 65.85,75.65 69.73,75.65 73.62,79.53 84.72,79.53 84.78,79.59 95.1,79.59 97.2,77.5 97.48,77.5 99.52,75.45 99.52,74.06 v2(99.51,74.05)
  BOTTOM w0.076: UC1.AY65 101.94,70.41 101.68,70.67 101.4,70.67 101.26,70.73 101.23,70.73 101.02,70.83 100.23,70.83 99.66,71.39 99.66,73.89 v2(99.51,74.05)
  BOTTOM w0.102: v2(62.49,75.37) 62.49,75.69 62.22,75.96 60.28,75.96 60.2,75.88 JDIMM1.46
DDR_A_D22: length 51.6
  IN1 w0.127: v2(96.33,73.53) 96.33,73.95 93.85,76.43 74.6,76.43 70.13,71.96 69.86,71.96 69.73,72.09 69.73,72.33 69.61,72.46 69.35,72.46 69.23,72.33 69.23,72.09 69.1,71.96 68.54,71.96 68.12,72.38 v2(65.83,72.38)
  BOTTOM w0.076: UC1.BA63 101.29,69.08 101.03,68.83 100.7,68.83 100.59,68.93 99.68,68.93 99.05,69.56 99.05,70.13 98.34,70.84 98.34,71.49 98.07,71.77 96.88,71.77 96.03,72.62 96.03,73.24 v2(96.33,73.53)
  BOTTOM w0.102: JDIMM1.59 66.48,72.62 66.12,72.98 66.12,73.08 65.99,73.21 65.39,73.21 65.11,73.49 63.26,73.49 63.08,73.3 63.08,72.95 63.24,72.79 65.3,72.79 65.71,72.38 v2(65.83,72.38)
DDR_A_D23: length 50
  IN1 w0.127: v2(96.79,73.17) 96.58,72.97 95.88,72.97 94.32,74.53 94.32,74.99 93.57,75.75 74.89,75.75 70.42,71.27 68.25,71.27 67.91,71.62 63.53,71.62 63.32,71.83 63.02,71.83 62.81,71.62 62.49,71.62 62.37,71.74 62.37,72.14 62.61,72.38 v2(62.79,72.38)
  BOTTOM w0.076: v2(96.79,73.17) 97.93,72.03 98.13,72.03 98.51,71.65 98.51,70.91 99.22,70.2 99.22,69.63 99.74,69.1 100.83,69.1 UC1.BB63
  BOTTOM w0.102: JDIMM1.62 60.01,71.88 60.42,71.46 62.13,71.46 62.79,72.12 v2(62.79,72.38)
DDR_A_D24: length 49
  IN1 w0.127: v2(95.86,71.21) 95.43,71.65 95.33,71.65 92.55,74.42 75.73,74.42 72.86,71.55 72.57,71.55 70.76,69.75 67.91,69.75 67.36,70.3 64.16,70.3 63.99,70.13 63.99,69.95 64.16,69.78 v2(64.33,69.78)
  BOTTOM w0.076: v2(95.86,71.21) 95.83,71.21 95.65,71.39 95.65,71.67 95.75,71.77 96.41,71.77 96.82,71.37 96.82,71.08 97.26,70.63 97.85,70.63 98.56,69.93 98.56,69.35 99.47,68.44 100.38,68.44 100.49,68.33 101,68.33 101.28,68.05 UC1.BA61
  BOTTOM w0.102: JDIMM1.67 66.38,70.62 66.35,70.66 64.05,70.66 63.91,70.52 63.91,70 64.13,69.78 v2(64.33,69.78)
DDR_A_D25: length 49.9
  IN1 w0.127: v2(97.81,71.21) 97.4,71.63 96.93,71.63 96.23,72.33 95.62,72.33 92.84,75.11 75.45,75.11 72.58,72.24 72.28,72.24 70.48,70.44 68.19,70.44 67.65,70.98 62.48,70.98 v2(61.28,69.78)
  BOTTOM w0.076: UC1.AW61 102.67,67.95 102.35,68.27 102.12,68.27 101.99,68.25 101.77,68.25 101.77,68.25 101.76,68.25 101.51,68.5 100.56,68.5 100.45,68.6 99.54,68.6 98.72,69.42 98.72,69.99 97.81,70.91 v2(97.81,71.21)
  BOTTOM w0.102: v2(61.28,69.78) 61.18,69.88 JDIMM1.70
DDR_A_D26: length 49.3
  IN1 w0.076: v2(95.26,69.68) 95.36,69.68 95.53,69.85 95.53,70.11 95.39,70.25 93.07,70.25 92.68,70.63
  IN1 w0.127: 92.68,70.63 91.09,72.22 77.18,72.22 73.99,69.03 73.42,69.03 73.24,68.85 73.24,68.67 73.34,68.57 73.34,68.39 73.16,68.21 72.98,68.21 72.88,68.31 72.7,68.31 72.52,68.13 72.52,67.95 72.62,67.85 72.62,67.67 72.44,67.49 72.26,67.49 72.16,67.59 71.98,67.59 71.65,67.27 70.12,67.27 69.71,66.86 68.41,66.86 68,67.27 65.7,67.27 65.33,66.9 64.31,66.9 64.18,66.76 64.18,66.54 64.36,66.36 64.55,66.36 v2(64.56,66.37)
  BOTTOM w0.076: UC1.BB59 100.74,66.83 99.68,66.83 97.73,68.78 95.15,68.78 94.95,68.98 94.95,69.37 v2(95.26,69.68)
  BOTTOM w0.102: JDIMM1.79 65.55,67.62 65.35,67.42 64.26,67.42 64.15,67.32 64.15,66.56 64.34,66.37 v2(64.56,66.37)
DDR_A_D27: length 51
  IN1 w0.076: v2(96.43,69.65) 95.64,70.44 93.36,70.44 92.93,70.87
  IN1 w0.127: v2(61.51,66.37) 61.36,66.37 61.23,66.49 61.23,67.12 61.36,67.24 65.19,67.24 65.55,67.61 68.14,67.61 68.55,67.2 69.57,67.2 69.98,67.61 71.25,67.61 73.34,69.69 74.16,69.69 77.03,72.56 91.24,72.56 92.76,71.04 92.76,71.04 92.93,70.87
  BOTTOM w0.076: v2(96.43,69.65) 96.71,69.94 97.85,69.94 98.06,69.72 98.06,69.15 99.26,67.94 100.18,67.94 100.29,67.84 100.43,67.84 100.64,67.62 100.98,67.62 100.98,67.62 101.08,67.66 101.27,67.66 101.36,67.62 101.36,67.62 101.37,67.62 101.38,67.61 101.6,67.61 101.69,67.64 101.95,67.64 102.05,67.57 102.66,67.57 102.8,67.43 UC1.AW59
  BOTTOM w0.102: v2(61.51,66.37) 59.06,66.37 JDIMM1.84
DDR_A_D28: length 48.3
  IN1 w0.127: v2(62.8,69.78) 63.67,70.64 67.51,70.64 68.05,70.09 70.62,70.09 72.42,71.9 72.72,71.9 75.59,74.77 92.7,74.77 95.48,71.99 96.08,71.99 96.44,71.62 96.44,71.22 v2(96.45,71.21)
  BOTTOM w0.076: UC1.BB61 100.73,68.17 100.42,68.17 100.32,68.27 99.4,68.27 98.39,69.28 98.39,69.86 97.81,70.44 97.22,70.44 v2(96.45,71.21)
  BOTTOM w0.102: JDIMM1.66 61.99,70.88 62.8,70.06 v2(62.8,69.78)
DDR_A_D29: length 49.8
  IN1 w0.127: v2(65.85,69.78) 65.68,69.78 65.34,69.44 65.34,69.25 65.47,69.13 66.71,69.13 66.84,69.25 66.84,69.83 66.97,69.95 67.22,69.95 67.35,69.83 67.35,69.25 67.48,69.13 68,69.13 68.12,69.25 68.12,69.28 68.25,69.41 68.5,69.41 68.63,69.28 68.63,69.25 68.76,69.13 69.01,69.13 69.14,69.25 69.14,69.28 69.27,69.41 69.52,69.41 69.65,69.28 69.65,69.25 69.77,69.13 70.03,69.13 70.16,69.25 70.16,69.28 70.28,69.41 70.9,69.41 72.71,71.21 73.08,71.21 75.95,74.08 92.41,74.08 94.65,71.84 v2(94.65,71.21)
  BOTTOM w0.076: v2(94.65,71.21) 94.27,71.21 94.19,71.14 94.19,70.77 94.27,70.69 96.16,70.69 96.6,70.25 97.77,70.25 98.23,69.79 98.23,69.22 99.33,68.11 100.25,68.11 100.35,68 100.49,68 100.71,67.79 100.95,67.79 101.06,67.82 101.3,67.82 101.39,67.79 101.6,67.79 101.7,67.82 102.02,67.82 UC1.AY61
  BOTTOM w0.102: v2(65.85,69.78) 65.66,69.78 65.23,69.35 65.23,69.06 65.34,68.96 66.09,68.96 66.2,69.06 66.2,69.5 66.33,69.62 JDIMM1.71
DDR_A_D30: length 49.5
  IN1 w0.076: v2(94.68,69.68) 94.68,69.98 94.6,70.06 92.77,70.06 92.44,70.39
  IN1 w0.127: v2(66.08,66.37) 66.07,66.36 65.88,66.36 65.7,66.54 65.7,66.79 65.84,66.92 66.62,66.92 66.75,66.8 66.75,66.28 66.88,66.15 67.13,66.15 67.26,66.28 67.26,66.8 67.39,66.92 67.64,66.92 67.77,66.8 67.77,66.28 67.89,66.15 68.28,66.15 68.4,66.28 68.4,66.39 68.53,66.51 68.78,66.51 68.91,66.39 68.91,66.28 69.04,66.15 69.29,66.15 69.42,66.28 69.42,66.39 69.55,66.51 69.8,66.51 69.93,66.39 69.93,66.28 70.05,66.15 70.31,66.15 70.43,66.28 70.43,66.8 70.56,66.92 70.82,66.92 70.94,66.8 70.94,66.28 71.07,66.15 71.59,66.15 71.77,66.33 71.77,66.51 71.66,66.63 71.66,66.81 71.82,66.97 72.04,66.97 72.13,66.87 72.31,66.87 77.32,71.88 90.95,71.88 92.44,70.39
  BOTTOM w0.076: v2(94.68,69.68) 94.24,69.24 94.24,69.13 94.78,68.59 97.69,68.59 99.61,66.67 100.5,66.67 100.7,66.47 100.98,66.47 101.48,66.68 101.48,66.68 UC1.BA59
  BOTTOM w0.102: v2(66.08,66.37) 65.89,66.37 65.59,66.67 65.59,66.84 65.79,67.04 66.14,67.04 66.56,66.62 JDIMM1.83
DDR_A_D31: length 50.7
  IN1 w0.076: 92.2,70.15 92.72,69.63 v2(93.51,69.63)
  IN1 w0.127: 92.2,70.15 90.81,71.53 77.46,71.53 71.73,65.81 64.38,65.81 63.62,65.04 62.57,65.04 62.44,65.17 62.44,65.95 62.86,66.37 v2(63.03,66.37)
  BOTTOM w0.076: v2(93.51,69.63) 94.72,68.42 97.62,68.42 99.54,66.5 100.44,66.5 100.63,66.31 101.01,66.31 101.05,66.33 101.48,66.46 101.68,66.46 101.94,66.73 UC1.AY59
  BOTTOM w0.102: v2(63.03,66.37) 63.03,66.46 62.36,67.14 60.16,67.14 59.92,67.38 JDIMM1.80
DDR_A_D32: length 53
  IN1 w0.076: 89.61,53.88 89.91,53.88 91.32,55.29 93.14,55.29 93.39,55.04 v2(93.39,55.01)
  IN1 w0.127: 89.61,53.88 85.7,53.88 77.05,45.23 77.05,45.12 75.63,43.71 63.84,43.71 63.32,43.19 62.25,43.19 62.12,43.07 62.12,42.89 62.25,42.75 v2(62.44,42.75)
  BOTTOM w0.076: UC1.AY39 101.94,55.68 101.68,55.95 101.4,55.95 100.99,56.11 100.59,56.11 100.48,56.01 99.22,56.01 98.73,56.5 93.47,56.5 93.39,56.42 v2(93.39,55.01)
  BOTTOM w0.102: JDIMM1.174 60.73,41.87 60.85,42 60.85,42.21 60.95,42.31 61.16,42.31 61.26,42.21 61.26,41.84 61.42,41.67 62.4,41.67 62.57,41.84 62.57,42.63 v2(62.44,42.75)
DDR_A_D33: length 50.5
  IN1 w0.076: 89.61,54.23 89.92,54.23 91.14,55.45 98.32,55.45 v2(98.73,55.04)
  IN1 w0.127: v2(60.92,42.75) 62.22,44.05 75.49,44.05 76.68,45.24 76.68,45.34 85.56,54.23 89.61,54.23
  BOTTOM w0.076: v2(98.73,55.04) 99.45,55.04 99.88,54.61 100.44,54.61 100.6,54.78 100.94,54.78 101.06,54.75 101.27,54.76 101.34,54.78 101.66,54.78 101.72,54.76 102.01,54.74 102.51,54.74 102.8,55.03 UC1.AW39
  BOTTOM w0.102: JDIMM1.170 59.89,42.87 60.05,43.03 60.79,43.03 60.92,42.9 v2(60.92,42.75)
DDR_A_D34: length 52
  IN1 w0.076: 89.34,50.65 89.96,50.65 92.17,52.86 93.7,52.86 93.81,52.98 95.03,52.98 95.35,53.29 95.35,53.79 95.42,53.87 98.83,53.87 99.38,54.41 99.38,54.58 99.29,54.67 98.48,54.67 v2(98.15,55.01)
  IN1 w0.127: 89.34,50.65 87.17,50.65 81.43,44.91 81.43,44.61 77.16,40.33 72.91,40.33 72.11,39.53 71.6,39.53 71.46,39.38 71.46,38.74 71.28,38.56 70.45,38.56 70.33,38.69 70.33,39.17 70.13,39.36 69.14,39.36 68.97,39.53 68.62,39.53 68.42,39.33 67.39,39.33 67.24,39.18 67.24,38.69 67.12,38.56 66.86,38.56 66.73,38.69 66.73,39.2 66.61,39.33 65.47,39.33 v2(65.43,39.37)
  BOTTOM w0.076: v2(98.15,55.01) 98.15,54.8 98.27,54.67 99.58,54.67 99.81,54.45 100.51,54.45 100.67,54.61 100.92,54.61 101.12,54.57 101.24,54.57 101.4,54.61 101.64,54.61 101.79,54.56 102.05,54.56 UC1.AY37
  BOTTOM w0.102: JDIMM1.187 66.15,38.63 65.85,38.92 65.33,38.92 65.23,39.02 65.23,39.17 v2(65.43,39.37)
DDR_A_D35: length 53.3
  IN1 w0.076: v2(94.98,53.44) 95.08,53.55 95.08,53.86 95,53.93 92.22,53.93 89.97,51.68 89.73,51.68
  IN1 w0.127: 89.73,51.68 86.74,51.68 80.41,45.34 80.41,45.03 76.73,41.36 72.41,41.36 71.71,40.66 69.55,40.66 68.91,41.3 68.29,41.3 67.55,40.56 60.55,40.56 60.42,40.43 60.42,39.57 60.62,39.37 v2(60.86,39.37)
  BOTTOM w0.076: v2(94.98,53.44) 94.98,53.51 95.64,54.18 99.38,54.18 99.64,53.91 101.56,53.91 101.78,54.13 102.26,54.13 102.58,54.46 UC1.AW37
  BOTTOM w0.102: JDIMM1.186 60.05,38.87 60.15,38.98 60.46,38.98 v2(60.86,39.37)
DDR_A_D36: length 50.8
  IN1 w0.076: 90.83,53.55 91.5,54.22 91.74,54.22 92,54.48 95.32,54.48 95.4,54.55 95.4,54.77 v2(95.14,55.02)
  IN1 w0.127: 90.83,53.55 90.63,53.55 90.32,53.23 90.32,53.04 90.19,52.91 89.94,52.91 89.65,53.2 85.99,53.2 78.68,45.9 78.68,45.72 78.72,45.68 78.72,45.5 78.54,45.32 78.36,45.32 78.32,45.36 78.14,45.36 77.96,45.18 77.96,45 78,44.96 78,44.77 77.83,44.61 77.5,44.61 77.3,44.4 77.3,44.09 77.1,43.89 76.78,43.89 76.58,43.69 76.58,43.37 76.09,42.88 75.52,42.88 75.38,43.02 74.96,43.02 74.82,42.88 74.44,42.88 74.3,43.02 73.95,43.02 73.81,42.88 73.43,42.88 73.29,43.02 72.8,43.02 72.66,42.88 72.09,42.88 71.95,43.02 71.69,43.02 71.41,42.74 71.04,42.74 70.76,43.02 70.39,43.02 70.12,42.75 69.73,42.75 69.46,43.02 68.37,43.02 68.17,42.82 67.6,42.82 67.39,43.02 67.11,43.02 66.89,42.79 66.58,42.79 66.35,43.02 65.62,43.02 65.49,42.89 v2(65.49,42.75)
  BOTTOM w0.076: v2(95.14,55.02) 95.4,55.28 95.4,55.5 95.19,55.71 93.8,55.71 93.72,55.78 93.72,56.09 93.8,56.17 98.59,56.17 99.08,55.68 100.84,55.68 UC1.BB39
  BOTTOM w0.102: v2(65.49,42.75) 65.43,42.69 65.43,42.41 65.54,42.29 65.78,42.29 66.21,42.71 66.21,42.96 66.37,43.13 JDIMM1.169
DDR_A_D37: length 52.1
  IN1 w0.076: 89.61,53.54 90.25,53.54 91.16,54.45 91.74,54.45 91.93,54.64 94.19,54.64 v2(94.56,55.01)
  IN1 w0.127: 89.61,53.54 85.84,53.54 77.62,45.32 77.62,45.21 75.77,43.36 63.98,43.36 63.85,43.24 63.85,42.87 v2(63.97,42.75)
  BOTTOM w0.076: v2(94.56,55.01) 94.12,55.45 93.63,55.45 93.56,55.53 93.56,56.26 93.63,56.33 98.66,56.33 99.15,55.84 100.55,55.84 100.66,55.95 100.95,55.95 101.2,55.83 101.2,55.83 101.21,55.82 101.35,55.68 UC1.BA39
  BOTTOM w0.102: JDIMM1.173 66.45,42.13 65.86,41.53 65.14,41.53 64.88,41.8 64.88,42.21 64.77,42.31 64.57,42.31 64.47,42.21 64.47,41.84 64.37,41.74 63.94,41.74 63.84,41.84 63.84,42.62 v2(63.97,42.75)
DDR_A_D38: length 52
  IN1 w0.076: v2(93.81,53.42) 93.81,53.68 93.72,53.77 92.37,53.77 89.94,51.34 89.73,51.34
  IN1 w0.127: 89.73,51.34 86.89,51.34 80.75,45.2 80.75,44.89 76.87,41.02 72.55,41.02 71.75,40.22 62.11,40.22 61.98,40.09 61.98,39.59 62.2,39.37 v2(62.38,39.37)
  BOTTOM w0.076: UC1.BA37 101.29,54.36 101.01,54.08 99.71,54.08 99.44,54.34 94.21,54.34 93.81,53.94 v2(93.81,53.42)
  BOTTOM w0.102: v2(62.38,39.37) 62.53,39.37 62.63,39.47 62.63,39.93 62.53,40.03 59.2,40.03 JDIMM1.182
DDR_A_D39: length 51.4
  IN1 w0.076: v2(93.19,53.4) 93.37,53.4 93.46,53.31 93.46,53.11 93.38,53.03 92.02,53.03 89.98,50.99 89.69,50.99
  IN1 w0.127: 89.69,50.99 87.03,50.99 81.09,45.06 81.09,44.75 77.02,40.67 72.69,40.67 71.89,39.87 71.23,39.87 71.04,39.68 71.04,39.45 70.91,39.32 70.73,39.32 70.61,39.45 70.61,39.67 70.4,39.87 69.79,39.87 69.62,39.71 69.28,39.71 69.11,39.87 68.18,39.87 68.01,39.71 67.67,39.71 67.5,39.87 67.25,39.87 67.04,39.67 66.74,39.67 66.54,39.87 66.23,39.87 66.03,39.67 65.72,39.67 65.52,39.87 63.64,39.87 63.52,39.75 63.52,39.57 63.71,39.37 v2(63.91,39.37)
  BOTTOM w0.076: v2(93.19,53.4) 93.19,54.32 93.37,54.51 99.51,54.51 99.74,54.28 100.58,54.28 100.65,54.36 UC1.BB37
  BOTTOM w0.102: v2(63.91,39.37) 63.64,39.37 63.54,39.47 63.54,39.68 63.64,39.79 66.23,39.79 66.39,39.63 JDIMM1.183
DDR_A_D40: length 54.2
  IN1 w0.076: 89.22,49.32 89.52,49.32 92.57,52.37 97.52,52.37 97.83,52.68 v2(97.83,53.41)
  IN1 w0.127: v2(65.44,37.93) 65.62,37.93 65.88,37.67 66.32,37.24 67.66,37.24 68.1,37.67 68.1,37.67 68.31,37.88 69.27,37.88 69.9,37.24 71.94,37.24 73.71,39.01 77.71,39.01 82.76,44.06 82.76,44.37 87.71,49.32 89.22,49.32
  BOTTOM w0.076: UC1.AY35 102.05,53.13 101.78,53.13 101.6,53.06 101.39,53.06 101.3,53.1 101.06,53.1 101.04,53.1 100.95,53.06 100.38,53.06 100.2,53.24 99.63,53.24 99.33,52.94 98.3,52.94 v2(97.83,53.41)
  BOTTOM w0.102: v2(65.44,37.93) 65.44,37.68 65.11,37.35 62.48,37.35 62.38,37.25 62.38,36.73 62.48,36.63 JDIMM1.195
DDR_A_D41: length 55.5
  IN1 w0.076: 89.22,49.67 89.61,49.67 92.48,52.53 96.67,52.53 96.88,52.75 v2(96.88,53.43)
  IN1 w0.127: 89.22,49.67 89.22,49.66 87.56,49.66 82.41,44.51 82.41,44.2 77.56,39.35 73.46,39.35 71.69,37.58 70.05,37.58 69.28,38.35 68.3,38.35 67.96,38.02 67.96,38.02 67.52,37.58 66.46,37.58 65.69,38.35 63.93,38.35 63.8,38.22 63.8,38.04 v2(63.91,37.93)
  BOTTOM w0.076: v2(96.88,53.43) 97.46,54.01 99.31,54.01 99.57,53.75 101.54,53.75 101.74,53.55 102.24,53.55 102.56,53.23 UC1.AW35
  BOTTOM w0.102: JDIMM1.191 66.32,37.63 65.61,38.34 64.83,38.34 64.73,38.44 64.73,38.72 64.62,38.82 64.41,38.82 64.31,38.72 64.31,38.43 64.21,38.33 64,38.33 63.9,38.43 63.9,38.68 63.8,38.79 62.9,38.79 62.79,38.68 62.79,38.47 62.9,38.37 63.29,38.37 63.73,37.93 v2(63.91,37.93)
DDR_A_D42: length 53.8
  IN1 w0.076: 89.22,46.43 89.54,46.43 89.87,46.75 89.87,47.13 91.65,48.91 91.65,49.56 92.65,50.56 98.56,50.56 98.63,50.64 v2(98.63,51.38)
  IN1 w0.127: v2(65.39,33.95) 65.39,34.22 65.52,34.35 65.91,34.35 66.03,34.22 66.03,33.93 66.16,33.81 66.41,33.81 66.54,33.93 66.54,34.22 66.67,34.35 66.92,34.35 67.05,34.22 67.05,33.93 67.18,33.81 67.43,33.81 67.56,33.93 67.56,34.22 67.68,34.35 69.12,34.35 69.24,34.22 69.24,33.94 69.37,33.82 69.62,33.82 69.75,33.95 69.75,34.22 69.88,34.35 70.13,34.35 70.26,34.22 70.26,33.93 70.39,33.8 70.64,33.8 70.77,33.93 70.77,34.22 70.89,34.35 71.15,34.35 71.27,34.22 71.27,34.01 71.4,33.88 71.65,33.88 71.78,34.01 71.78,34.22 71.91,34.35 72.16,34.35 72.29,34.22 72.29,34.12 72.42,33.99 72.67,33.99 72.8,34.12 72.8,34.22 72.93,34.35 73.22,34.35 74.96,36.09 78.87,36.09 85.65,42.86 85.65,43.17 86.6,44.12 88.9,46.43 89.22,46.43
  BOTTOM w0.076: v2(98.63,51.38) 98.86,51.61 100.59,51.61 100.62,51.57 100.99,51.57 101.14,51.64 102.29,51.64 102.41,51.76 102.41,51.93 102.33,52 UC1.AY33
  BOTTOM w0.102: v2(65.39,33.95) 65.21,33.95 64.92,33.66 64.92,33.38 65.02,33.28 66.05,33.28 66.39,33.63 JDIMM1.207
DDR_A_D43: length 53.1
  IN1 w0.076: 89.22,46.77 89.49,46.77 89.68,46.96 89.68,47.18 91.21,48.7 91.21,49.35 92.61,50.75 94.06,50.75 v2(94.76,51.45)
  IN1 w0.127: v2(63.87,33.95) 63.65,34.17 63.65,34.56 63.78,34.69 73.08,34.69 74.84,36.46 78.76,36.46 85.3,43 85.3,43.31 86.48,44.49 88.76,46.77 89.21,46.77 89.21,46.77 89.22,46.77
  BOTTOM w0.076: UC1.AW33 102.8,52.65 102.59,52.86 102.08,52.86 101.98,52.93 101.73,52.93 101.6,52.89 101.38,52.89 101.37,52.89 101.36,52.9 101.36,52.9 101.27,52.93 101.07,52.93 100.98,52.9 100.98,52.9 100.31,52.9 100.13,53.08 99.69,53.08 99.09,52.47 95.38,52.47 94.76,51.85 v2(94.76,51.45)
  BOTTOM w0.102: JDIMM1.203 64.34,34.63 63.87,34.16 v2(63.87,33.95)
DDR_A_D44: length 52.3
  IN1 w0.076: 89.22,48.97 89.49,48.97 92.72,52.2 97.78,52.2 v2(99.02,53.45)
  IN1 w0.127: 89.22,48.97 87.85,48.97 83.1,44.22 83.1,43.92 77.85,38.67 73.85,38.67 72.08,36.9 69.76,36.9 69.13,37.53 68.45,37.53 68.25,37.33 68.24,37.33 67.81,36.9 66.17,36.9 65.64,37.43 62,37.43 61.35,36.78 60.56,36.78 60.43,36.91 60.43,37.8 60.56,37.93 v2(60.87,37.93)
  BOTTOM w0.076: UC1.BB35 100.77,53.41 99.07,53.41 v2(99.02,53.45)
  BOTTOM w0.102: JDIMM1.194 59.93,36.87 60.87,37.81 v2(60.87,37.93)
DDR_A_D45: length 53.3
  IN1 w0.076: 89.22,50.01 89.64,50.01 92.33,52.7 95.9,52.7 95.97,52.78 95.97,53.15 v2(95.71,53.41)
  IN1 w0.127: 89.22,50.01 87.43,50.01 82.07,44.65 82.07,44.34 77.42,39.7 73.31,39.7 71.54,37.93 70.19,37.93 69.42,38.69 68.15,38.69 67.38,37.92 66.6,37.92 66.27,38.26 66.27,38.26 65.83,38.69 62.13,38.69 62,38.57 62,38.12 62.19,37.93 v2(62.39,37.93)
  BOTTOM w0.076: v2(95.71,53.41) 96.11,53.02 96.99,53.02 97.43,53.45 97.43,53.68 97.6,53.85 99.24,53.85 99.5,53.58 101.02,53.58 101.28,53.33 UC1.BA35
  BOTTOM w0.102: v2(62.39,37.93) 62.2,37.93 61.74,38.39 60.43,38.39 59.91,37.87 JDIMM1.190
DDR_A_D46: length 53.3
  IN1 w0.076: v2(93.59,51.41) 92.8,51.41 90.38,48.99 90.38,48.41 89.43,47.46 89.22,47.46
  IN1 w0.127: 89.22,47.46 88.48,47.46 85.39,44.37 84.62,43.6 84.62,43.29 78.48,37.15 74.57,37.15 72.79,35.38 60.2,35.38 60.07,35.25 60.07,34.08 60.2,33.95 v2(60.82,33.95)
  BOTTOM w0.076: v2(93.59,51.41) 94.08,50.92 95.39,50.92 97.64,50.92 98.49,51.77 100.65,51.77 100.69,51.74 100.95,51.74 101.21,51.86 101.35,52 UC1.BA33
  BOTTOM w0.102: v2(60.82,33.95) 60.82,33.85 60.34,33.38 JDIMM1.208
DDR_A_D47: length 52.7
  IN1 w0.076: 89.22,47.11 89.39,47.11 90.76,48.49 90.76,49.14 92.66,51.04 93.78,51.04 v2(94.18,51.44)
  IN1 w0.127: v2(62.35,33.95) 62.35,34.24 62.22,34.37 61.66,34.37 61.53,34.5 61.53,34.91 61.66,35.03 72.93,35.03 74.7,36.8 78.62,36.8 84.96,43.15 84.96,43.45 85.73,44.23 88.62,47.11 89.22,47.11
  BOTTOM w0.076: v2(94.18,51.44) 94.53,51.08 95.32,51.08 97.54,51.08 98.39,51.94 100.78,51.94 UC1.BB33
  BOTTOM w0.102: v2(62.35,33.95) 62.35,34.4 62.22,34.53 60.06,34.53 59.9,34.38 JDIMM1.204
DDR_A_D48: length 56.2
  IN1 w0.076: 89.22,44.88 90.44,46.1 90.44,47 92.67,49.23 93.62,49.23 93.69,49.31 93.69,49.55 93.54,49.7 v2(93.44,49.7)
  IN1 w0.127: 89.22,44.88 87.95,43.6 86.97,42.62 86.97,42.31 79.42,34.77 75.65,34.77 73.55,32.67 72.34,32.67 72.15,32.48 71.66,32.48 71.52,32.34 71.52,31.7 71.39,31.58 71.14,31.58 71.01,31.7 71.01,32.34 70.88,32.47 70.63,32.47 70.5,32.34 70.5,31.7 70.37,31.58 70.12,31.58 69.99,31.7 69.99,32.34 69.85,32.48 69.6,32.48 69.47,32.35 69.47,31.7 69.35,31.58 69.11,31.58 68.97,31.72 68.97,32.35 68.84,32.48 68.14,32.48 68,32.34 68,31.7 67.88,31.58 67.62,31.58 67.49,31.7 67.49,32.35 67.37,32.48 67.08,32.48 66.95,32.35 66.95,31.98 66.82,31.85 66.57,31.85 66.44,31.98 66.44,32.35 66.32,32.48 65.94,32.48 65.93,32.49 65.42,32.49 65.3,32.61 v2(65.3,32.7)
  BOTTOM w0.076: v2(93.44,49.7) 93.44,50.51 93.68,50.75 95.46,50.75 95.46,50.75 97.82,50.75 97.94,50.87 99.48,50.87 99.57,50.96 100.47,50.96 100.64,51.13 100.98,51.13 101.4,50.97 101.68,50.97 101.94,50.7 UC1.AY31
  BOTTOM w0.102: v2(65.3,32.7) 65.64,32.7 65.74,32.59 65.74,32.31 65.84,32.21 66.09,32.21 66.19,32.31 66.19,32.52 66.29,32.63 JDIMM1.211
DDR_A_D49: length 56.7
  IN1 w0.076: v2(98.85,49.67) 98.25,50.26 92.58,50.26 91.9,49.58 91.9,48.93 90.06,47.09 90.06,46.56 89.29,45.79 89.22,45.79
  IN1 w0.127: v2(62.25,32.7) 62.25,33.08 62.7,33.53 65.54,33.53 65.9,33.17 66.54,33.17 66.54,33.17 71.86,33.17 72.05,33.36 73.12,33.36 75.22,35.45 79.14,35.45 86.28,42.6 86.28,42.9 87.21,43.83 87.21,43.83 89.17,45.79 89.22,45.79
  BOTTOM w0.076: UC1.AW31 102.8,50.01 102.58,49.79 102.02,49.79 102,49.77 101.73,49.77 101.58,49.83 101.44,49.83 101.22,49.76 101.1,49.76 101.02,49.79 100.99,49.81 100.61,49.81 100.41,49.6 100.28,49.6 100,49.32 99.19,49.32 v2(98.85,49.67)
  BOTTOM w0.102: v2(62.25,32.7) 61.81,32.26 61.81,31.48 61.71,31.38 61.46,31.38 61.36,31.48 61.36,32.01 61.26,32.11 61.05,32.11 60.95,32.01 60.95,31.48 60.85,31.38 60.65,31.38 60.54,31.48 60.54,31.69 60.44,31.79 60.24,31.79 60.14,31.69 60.14,31.48 60.04,31.38 JDIMM1.216
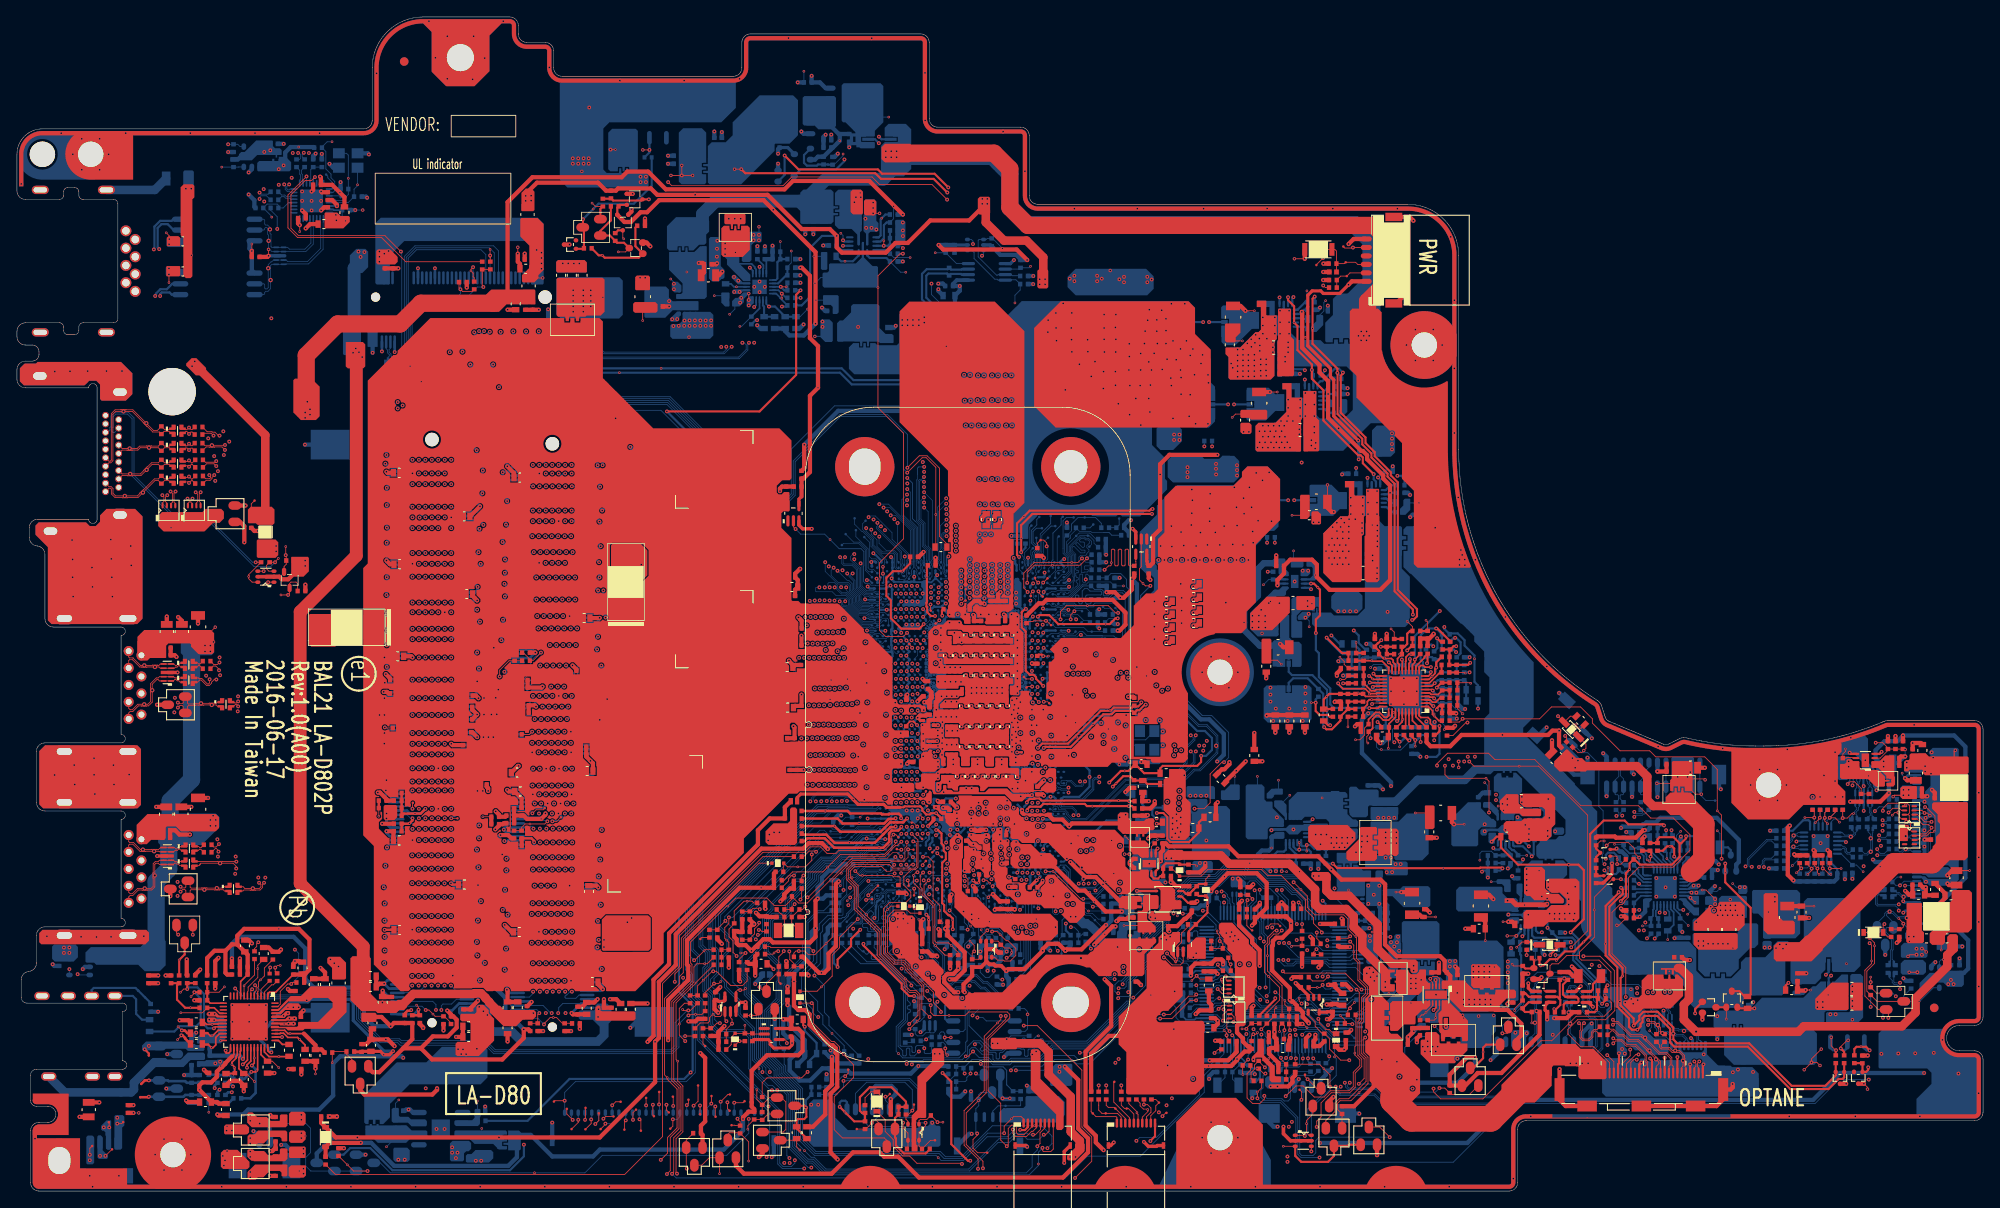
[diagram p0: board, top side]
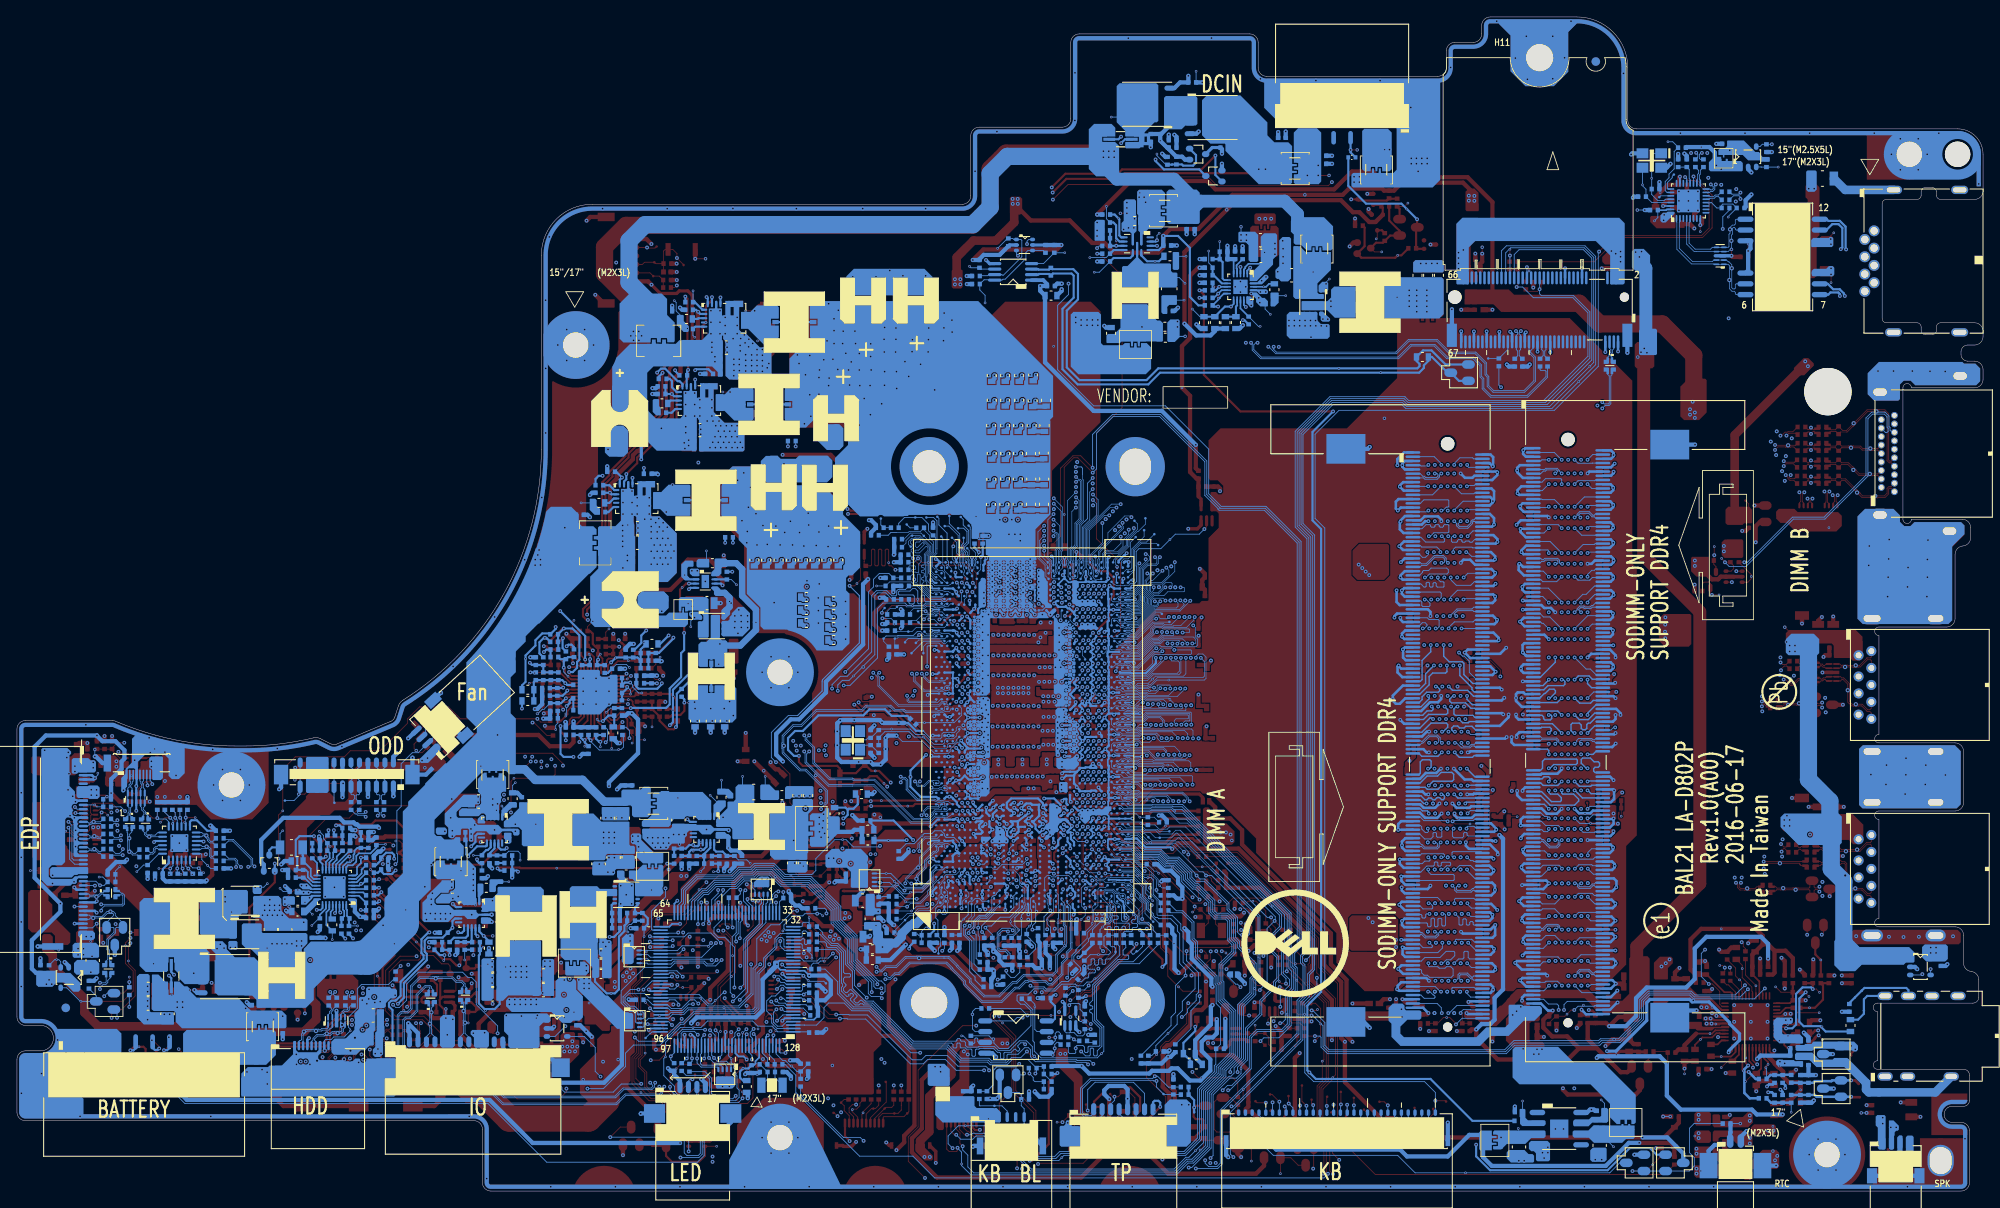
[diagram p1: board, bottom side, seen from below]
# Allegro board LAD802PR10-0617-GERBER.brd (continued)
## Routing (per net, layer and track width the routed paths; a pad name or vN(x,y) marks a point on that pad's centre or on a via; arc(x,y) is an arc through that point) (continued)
DDR_A_D50: length 55.3
  IN1 w0.076: 90.61,43.67 90.61,44.07 91.27,44.72 91.27,46.8 92.78,48.31 96.93,48.31 v2(98.26,49.63)
  IN1 w0.127: v2(63.77,29.29) 63.61,29.46 63.61,29.81 63.73,29.93 65.57,29.93 65.91,29.59 65.91,29.27 66.22,28.97 67.71,28.97 67.95,29.2 69.41,29.2 69.63,29.42 72.93,29.42 76.42,32.91 80.19,32.91 89.18,41.89 90.11,41.89 90.53,42.31 90.53,43.59 90.61,43.67
  BOTTOM w0.076: UC1.AY29 102.05,49.58 101.79,49.58 101.58,49.65 101.44,49.65 101.21,49.59 101.07,49.59 100.95,49.64 100.68,49.64 100.48,49.44 100.35,49.44 100.07,49.16 98.73,49.16 v2(98.26,49.63)
  BOTTOM w0.102: v2(63.77,29.29) 63.77,28.66 64.31,28.13 JDIMM1.229
DDR_A_D51: length 56.5
  IN1 w0.076: v2(95.26,47.92) 94.74,47.4 92.68,47.4 91.84,46.56 91.84,44.09 91.64,43.89 91.64,43.68
  IN1 w0.127: 91.64,43.68 91.64,41.97 90.54,40.86 89.6,40.86 80.62,31.88 77.22,31.88 72.98,27.64 68.01,27.64 67.71,27.94 62.08,27.94 v2(60.73,29.29)
  BOTTOM w0.076: UC1.AW29 102.8,49.47 102.56,49.23 102.42,49.23 102.3,49.12 102.02,49.12 101.99,49.14 101.7,49.14 101.33,48.77 100.38,48.77 100.27,48.66 96,48.66 v2(95.26,47.92)
  BOTTOM w0.102: JDIMM1.228 59.81,28.38 v2(60.73,29.29)
DDR_A_D52: length 55.6
  IN1 w0.076: v2(95.22,49.69) 94.81,50.1 92.65,50.1 92.29,49.73 92.29,49.08 90.25,47.05 90.25,46.39 89.22,45.36
  IN1 w0.127: v2(63.77,32.7) 63.77,33.06 63.9,33.19 65.39,33.19 65.75,32.83 66.39,32.83 66.4,32.82 72,32.82 72.19,33.01 73.27,33.01 75.37,35.11 79.28,35.11 86.62,42.46 86.62,42.76 87.48,43.62 89.22,45.36
  BOTTOM w0.076: v2(95.22,49.69) 95.78,50.25 v1(96.16,50.25) 96.54,50.25 96.72,50.42 99.5,50.42 99.7,50.63 100.78,50.63 UC1.BB31
  BOTTOM w0.102: v2(63.77,32.7) 63.51,32.7 63.4,32.59 63.4,31.38 63.51,31.27 63.72,31.27 63.84,31.39 63.84,32.07 63.94,32.17 64.19,32.17 64.29,32.07 64.29,31.28 64.4,31.18 64.6,31.18 64.7,31.28 64.7,32.09 64.8,32.19 65.01,32.19 65.11,32.09 65.11,31.28 65.21,31.18 65.41,31.18 65.51,31.28 65.51,31.52 65.62,31.63 JDIMM1.215
DDR_A_D53: length 55.2
  IN1 w0.076: 89.22,44.39 90.63,45.8 90.63,46.96 92.72,49.04 93.98,49.04 v2(94.63,49.69)
  IN1 w0.127: 89.22,44.39 88.73,43.9 87.36,42.53 87.36,42.22 79.56,34.42 75.79,34.42 72.6,31.23 66.7,31.23 65.79,32.14 63.43,32.14 63.3,32.02 63.3,31.39 63.17,31.26 62.92,31.26 62.79,31.39 62.79,32.02 62.66,32.14 62.41,32.14 62.28,32.02 62.28,31.39 62.16,31.26 61.9,31.26 61.78,31.39 61.78,32.02 61.65,32.14 61.27,32.14 v2(60.72,32.7)
  BOTTOM w0.076: v2(94.63,49.69) 95.53,50.59 97.89,50.59 97.94,50.64 99.48,50.64 99.64,50.8 100.54,50.8 100.71,50.97 100.95,50.97 101.21,50.84 101.35,50.7 UC1.BA31
  BOTTOM w0.102: JDIMM1.212 60.4,32.38 v2(60.72,32.7)
DDR_A_D54: length 54.8
  IN1 w0.076: v2(93.85,47.92) 93.5,47.57 92.59,47.57 91.65,46.63 91.65,44.28 91.3,43.93 91.3,43.67
  IN1 w0.127: 91.3,43.67 91.3,42.11 90.39,41.2 89.46,41.2 80.48,32.22 77.07,32.22 72.84,27.98 68.15,27.98 67.85,28.28 63.26,28.28 v2(62.25,29.29)
  BOTTOM w0.076: UC1.BA29 101.27,49.38 100.82,48.93 100.31,48.93 100.21,48.83 94.76,48.83 v2(93.85,47.92)
  BOTTOM w0.102: JDIMM1.224 59.98,29.38 60.31,29.7 62.15,29.7 62.25,29.6 v2(62.25,29.29)
DDR_A_D55: length 54.3
  IN1 w0.076: v2(93.24,47.94) 92.64,47.94 91.46,46.75 91.46,44.47 90.96,43.96 90.96,43.67
  IN1 w0.127: v2(65.3,29.29) 65.13,29.29 64.77,28.93 64.77,28.75 64.89,28.62 68,28.62 68.29,28.33 69.53,28.33 69.65,28.45 69.65,28.95 69.78,29.07 70.04,29.07 70.16,28.95 70.16,28.45 70.29,28.33 70.54,28.33 70.67,28.45 70.67,28.95 70.8,29.07 71.05,29.07 71.18,28.95 71.18,28.45 71.31,28.33 72.33,28.33 76.56,32.56 80.33,32.56 89.32,41.55 90.25,41.55 90.96,42.25 90.96,43.67
  BOTTOM w0.076: v2(93.24,47.94) 93.24,48.92 93.32,48.99 100.14,48.99 100.24,49.1 100.57,49.1 UC1.BB29
  BOTTOM w0.102: v2(65.3,29.29) 64.96,28.95 64.96,28.81 65.05,28.71 66.05,28.71 66.46,29.13 JDIMM1.225
DDR_A_D56: length 59.3
  IN1 w0.076: 92.64,46.6 93.05,47.01 96.64,47.01 97.04,47.41 v2(97.04,47.92)
  IN1 w0.127: 92.64,46.6 92.47,46.43 92.47,45.21 92.62,45.06 92.62,41.56 90.94,39.88 90.01,39.88 81.02,30.9 77.62,30.9 73.68,26.96 73.38,26.66 67.6,26.66 67.39,26.88 65.43,26.88 v2(65.42,26.87)
  BOTTOM w0.076: v2(97.04,47.92) 97.04,48.27 97.27,48.5 100.34,48.5 100.45,48.6 101.73,48.6 102.08,48.25 UC1.AY27
  BOTTOM w0.102: JDIMM1.237 66.32,26.13 66.22,26.02 66.22,25.74 65.93,25.46 65.53,25.46 65.29,25.21 62.72,25.21 62.5,25.43 62.5,26.19 62.78,26.46 63.29,26.46 63.47,26.29 64.14,26.29 64.31,26.46 65.32,26.46 65.42,26.57 v2(65.42,26.87)
DDR_A_D57: length 59.7
  IN1 w0.076: v2(95.84,47.92) 95.84,47.48 95.56,47.2 92.97,47.2 92.13,46.35 92.13,46.33
  IN1 w0.127: v2(63.9,26.87) 63.9,27.18 64.03,27.3 67.45,27.3 67.75,27.01 73.24,27.01 77.48,31.24 80.88,31.24 89.87,40.23 90.8,40.23 92.28,41.7 92.28,44.91 92.13,45.06 92.13,46.33
  BOTTOM w0.076: UC1.AW27 102.52,47.97 101.11,47.97 101.07,47.93 101.06,47.93 101.06,47.93 100.43,47.93 100.36,48 99.74,48 99.1,47.36 96.4,47.36 v2(95.84,47.92)
  BOTTOM w0.102: v2(63.9,26.87) 63.71,26.87 63.3,27.28 62.79,27.28 62.31,27.76 62.31,28.17 62.42,28.28 63.33,28.28 64.06,27.54 65.84,27.54 66.26,27.13 JDIMM1.233
DDR_A_D58: length 58.1
  IN1 w0.127: v2(60.85,26.87) 60.24,26.87 60.11,26.74 60.11,26.28 60.29,26.11 67.19,26.11 67.32,25.98 68.13,25.98 68.67,25.44 69.3,25.44 69.38,25.52 69.84,25.98 73.67,25.98 77.91,30.21 81.31,30.21 90.29,39.2 91.23,39.2 93.31,41.28 93.31,45.34 93.16,45.49 93.16,46.14 93.61,46.6 96.8,46.6 97.3,46.1 v2(97.3,46.01)
  BOTTOM w0.076: UC1.AY25 101.9,47.02 101.65,46.77 101.36,46.77 100.97,46.58 99.84,46.58 99.65,46.39 97.67,46.39 v2(97.3,46.01)
  BOTTOM w0.102: v2(60.85,26.87) 60.35,26.38 JDIMM1.236
DDR_A_D59: length 59.2
  IN1 w0.127: v2(97.9,46.02) 97.9,46.1 97.18,46.82 93.35,46.82 92.81,46.28 92.81,45.35 92.96,45.2 92.96,41.42 91.08,39.54 90.15,39.54 81.17,30.56 77.76,30.56 73.83,26.62 73.53,26.32 69.7,26.32 69.24,25.86 69.15,25.78 68.81,25.78 68.27,26.32 67.46,26.32 67.33,26.45 62.39,26.45 62.26,26.58 62.26,26.76 v2(62.37,26.87)
  BOTTOM w0.076: UC1.AW25 102.62,47.02 102.36,46.77 101.88,46.77 101.61,46.49 101.61,46.23 101.5,46.12 101.1,46.12 101.06,46.16 100.61,46.16 100.24,45.79 99.54,45.79 99.31,46.02 v2(97.9,46.02)
  BOTTOM w0.102: v2(62.37,26.87) 61.87,27.38 61.37,27.38 61.23,27.51 61.23,28.18 61.13,28.28 60.8,28.28 60.73,28.21 60.73,27.55 60.55,27.38 JDIMM1.232
DDR_A_D60: length 57.1
  IN1 w0.076: v2(98.8,47.92) 98.8,44.82 98.71,44.73
  IN1 w0.127: 98.71,44.73 98.71,44.73 96.44,42.46 96.44,40.01 93.63,37.2 93.63,36.9 92.82,36.08 90.78,36.08 88.82,34.12 88.82,33.84 89.05,33.61 89.05,32.98 88.54,32.47 87.94,32.47 87.55,32.07 86.77,32.07 86.31,31.61 86.31,31.32 84.25,29.26 84.25,28.71 83.6,28.06 82.85,28.06 82.46,27.67 78.96,27.67 74.73,23.43 71.86,23.43 70.33,21.9 70.31,21.9 70.27,21.87 68.11,21.87 67.38,22.6 67.06,22.6 66.56,23.1 64.35,23.1 v2(63.93,23.52)
  BOTTOM w0.076: UC1.BB27 100.43,48.35 100.41,48.33 99.27,48.33 98.86,47.92 v2(98.8,47.92)
  BOTTOM w0.102: v2(63.93,23.52) 64.01,23.52 64.61,24.13 JDIMM1.245
DDR_A_D61: length 57.8
  IN1 w0.076: v2(97.62,47.92) 97.62,46.94 98.27,46.3 98.27,45.75 98,45.48 97.96,45.48
  IN1 w0.127: v2(65.46,23.52) 66.63,23.52 67.2,22.94 67.52,22.94 68.25,22.21 70.13,22.21 70.16,22.24 70.19,22.24 71.72,23.77 74.58,23.77 78.82,28.01 82.32,28.01 82.71,28.4 83.46,28.4 83.9,28.85 83.9,29.4 85.96,31.46 85.96,31.75 86.63,32.41 87.41,32.41 87.87,32.87 88.11,32.87 88.11,32.87 88.46,32.87 88.71,33.12 88.71,33.47 88.48,33.7 88.48,34.26 90.64,36.43 92.68,36.43 93.29,37.04 93.29,37.34 96.1,40.15 96.1,43.77 97.81,45.48 97.96,45.48
  BOTTOM w0.076: v2(97.62,47.92) 98.02,47.53 98.99,47.53 99.63,48.17 100.43,48.17 100.51,48.09 101,48.09 101.04,48.13 101.18,48.13 101.39,48.35 UC1.BA27
  BOTTOM w0.102: JDIMM1.249 66.31,23.12 65.92,22.73 64.75,22.73 64.64,22.84 64.64,22.99 64.79,23.13 64.85,23.13 65.24,23.52 v2(65.46,23.52)
DDR_A_D62: length 57.6
  IN1 w0.127: v2(96.12,45.98) 95.17,45.03 95.17,41.32 95.17,39.86 94.6,39.29 94.6,39.29 94.1,38.79 94.07,38.79 94.06,38.78 93.45,38.78 92.29,37.62 92.29,37.26 91.8,36.77 90.5,36.77 85.62,31.89 85.62,31.6 83.56,29.54 83.56,28.99 83.32,28.75 82.57,28.75 82.18,28.35 78.68,28.35 74.44,24.11 71.05,24.11 70.23,23.3 69.68,23.3 69.42,23.05 68.79,23.05 68.54,23.3 67.37,23.3 66.8,23.87 66.73,23.94 62.9,23.94 62.5,23.54 v2(62.5,23.49)
  BOTTOM w0.076: UC1.BA25 101.35,47.02 101.2,46.87 100.93,46.74 100.58,46.74 99.77,46.74 99.58,46.55 96.34,46.55 96.12,46.33 v2(96.12,45.98)
  BOTTOM w0.102: v2(62.5,23.49) 62.65,23.64 62.65,23.93 62.55,24.03 60.03,24.03 59.88,23.87 JDIMM1.246
DDR_A_D63: length 56.9
  IN1 w0.127: v2(60.88,23.51) 60.66,23.51 60.53,23.64 60.53,24.04 60.66,24.17 62.57,24.17 62.67,24.28 66.87,24.28 67.14,24.01 67.51,23.64 68.69,23.64 68.69,23.64 68.93,23.39 69.28,23.39 69.53,23.64 70.09,23.64 70.9,24.46 74.3,24.46 78.54,28.69 81.94,28.69 83.13,29.89 83.42,29.89 85.28,31.74 85.28,32.03 90.92,37.68 91.86,37.68 93.3,39.13 93.92,39.13 93.93,39.13 93.96,39.13 94.25,39.43 94.83,40 94.83,40.65 94.83,40.65 94.83,41.17 94.83,41.17 94.83,45.31 v2(95.52,46.01)
  BOTTOM w0.076: v2(95.52,46.01) 96.23,46.72 99.51,46.72 99.71,46.91 100.51,46.91 100.62,47.02 UC1.BB25
  BOTTOM w0.102: JDIMM1.250 60.43,22.87 60.88,23.32 v2(60.88,23.51)
DDR_A_DQS0: length 70.1
  IN1 w0.076: 106.57,83.76 106.6,83.79 106.85,83.79 v2(106.98,83.66)
  IN1 w0.127: 106.57,83.76 106.47,83.76 106.13,84.1 106.13,87.05 102.36,90.82 94.14,90.82 90.42,87.11 70.15,87.11 69.74,86.7 68.95,86.7 68.54,87.11 68.22,87.11 67.51,86.4 67.51,86.22 67.82,85.92 67.82,85.53 67.49,85.21 67.11,85.21 66.83,85.48 66.65,85.48 66.38,85.21 66.38,85.03 66.66,84.76 66.66,84.37 66.05,83.77 64.24,83.77 63.96,84.04 63.96,84.47 63.96,84.47 63.96,84.58 v2(63.9,84.64)
  BOTTOM w0.076: UC1.AM69 107.11,72.73 107.15,72.77 107.28,72.77 107.34,72.84 107.44,73.04 107.44,73.33 107.4,73.41 107.4,73.62 107.46,73.73 107.46,73.95 107.4,74.06 107.4,74.32 107.48,74.4 107.48,75.6 106.94,76.14 106.94,78.72 106.46,79.2 106.46,83.72 106.53,83.79 106.85,83.79 v2(106.98,83.66)
  BOTTOM w0.102: v2(63.9,84.64) 63.93,84.64 64.1,84.46 64.1,84.25 64.38,83.97 65.83,83.97 65.99,84.13 JDIMM1.13
DDR_A_DQS1: length 56.8
  IN1 w0.127: v2(101.91,78.41) 101.91,78.73 101.98,78.8 101.98,79.27 101.06,80.19 98.1,80.19 96.16,82.14 89.84,82.14 89.41,82.57 88.09,82.57 87.81,82.3 87.81,82.27 87.69,82.14 87.31,82.14 87.18,82.27 87.18,82.3 86.91,82.57 86.32,82.57 86.05,82.3 86.05,82.27 85.92,82.14 85.54,82.14 85.41,82.27 85.41,82.3 85.14,82.57 72.9,82.57 68.88,78.55 67.44,78.55 67.23,78.76 66.57,78.76 66.42,78.6 63.35,78.6 63.11,78.36 62.68,78.36 62.37,78.67 v2(62.37,79.02)
  BOTTOM w0.076: v2(101.91,78.41) 101.66,78.41 101.57,78.32 101.57,78.21 104.34,75.44 104.34,74.6 104.42,74.52 104.42,74.06 104.42,74.06 104.42,74.03 104.37,73.89 104.37,73.78 104.42,73.65 104.42,73.38 104.39,73.3 104.39,73.08 104.48,72.89 104.59,72.89 104.65,72.95 104.65,72.98 UC1.AT70
  BOTTOM w0.102: JDIMM1.34 59.83,78.88 59.93,78.97 60.16,78.97 60.2,78.93 60.2,78.75 60.77,78.19 61.81,78.19 62.11,78.49 62.11,78.72 62.12,78.73 62.12,78.77 v2(62.37,79.02)
DDR_A_DQS2: length 51.2
  IN1 w0.127: v2(63.88,74.1) 63.77,73.99 63.77,73.81 63.9,73.68 70.12,73.68 74.11,77.67 94.67,77.67 96.51,75.83 96.62,75.83 97.56,74.9 97.56,74.89 v2(97.67,74.78)
  BOTTOM w0.076: v2(97.67,74.78) 97.53,74.78 97.45,74.7 97.45,74.09 97.57,73.97 98.57,73.97 99.17,73.37 99.17,71.18 100.02,70.33 100.52,70.33 100.71,70.14 100.95,70.14 101.07,70.19 101.28,70.19 101.39,70.14 101.6,70.14 101.68,70.18 101.93,70.18 102.26,69.84 UC1.AY64
  BOTTOM w0.102: JDIMM1.55 66.4,73.62 66.23,73.79 65.63,73.79 64.65,74.77 63.72,74.77 63.52,74.57 63.52,74.2 63.62,74.1 v2(63.88,74.1)
DDR_A_DQS3: length 49.8
  IN1 w0.076: 93.61,71.44 93.63,71.42 93.63,71.38 93.7,71.31 93.7,71.25 94.14,70.82 96.65,70.82 97.45,70.02 97.45,69.81 v2(97.69,69.57)
  IN1 w0.127: 93.61,71.44 91.6,73.45 76.21,73.45 73.34,70.58 72.97,70.58 70.89,68.49 62.78,68.49 62.51,68.22 62.51,68.08 62.38,67.96 62.26,67.96 v2(62.13,67.82)
  BOTTOM w0.076: v2(97.69,69.57) 97.66,69.57 97.66,69.57 97.55,69.57 97.39,69.42 97.39,69.2 97.49,69.11 97.86,69.11 99.8,67.17 100.98,67.17 101.13,67.11 101.24,67.11 101.25,67.11 101.26,67.12 101.29,67.15 101.8,67.15 101.87,67.22 101.87,67.34 UC1.BA60
  BOTTOM w0.102: JDIMM1.76 60.07,68.38 60.17,68.47 61.97,68.47 62.37,68.07 v2(62.13,67.82)
DDR_A_DQS4: length 52
  IN1 w0.076: 89.73,52.56 89.74,52.56 89.77,52.54 89.82,52.54 89.85,52.51 90.14,52.51 91.63,54 91.76,54 92.07,54.31 96.26,54.31 96.47,54.52 96.47,54.81 v2(96.32,54.96)
  IN1 w0.127: v2(63.97,41.13) 64.19,41.35 64.19,41.91 64.46,42.18 66.4,42.18 66.67,41.91 66.67,41.57 66.8,41.44 67.18,41.44 67.31,41.57 67.31,41.91 67.58,42.18 69.45,42.18 69.79,41.85 69.79,41.67 69.91,41.55 70.53,41.55 70.66,41.67 70.66,41.83 70.93,42.1 71.9,42.1 72.05,42.24 76.37,42.24 79.52,45.4 79.52,45.84 86.25,52.56 89.73,52.56
  BOTTOM w0.076: UC1.AY38 102.21,55.32 102.07,55.41 101.96,55.45 101.68,55.45 101.6,55.42 101.39,55.42 101.28,55.47 101.07,55.47 100.95,55.42 100.54,55.42 100.45,55.51 99.01,55.51 98.53,56 97.05,56 96.59,55.54 96.59,55.23 v2(96.32,54.96)
  BOTTOM w0.102: v2(63.97,41.13) 64.15,40.95 64.15,40.59 64.36,40.37 65.94,40.37 66.23,40.65 66.43,40.65 66.46,40.63 JDIMM1.179
DDR_A_DQS5: length 53.9
  IN1 w0.076: v2(96.05,51.45) 96.26,51.45 96.34,51.53 96.34,51.69 96.19,51.83 92.95,51.83 90.06,48.95 90.06,48.62 89.56,48.12 89.27,48.12 89.24,48.09 89.22,48.09
  IN1 w0.127: 89.22,48.09 88.21,48.09 83.98,43.86 83.98,43.55 78.21,37.78 74.3,37.78 72.53,36.01 69.08,36.01 68.86,36.24 68.4,36.24 68.17,36.01 65.81,36.01 65.28,36.54 62.36,36.54 62.23,36.42 62.23,36.14 62.36,36.01 62.57,36.01 v2(62.58,36.03)
  BOTTOM w0.076: v2(96.05,51.45) 96.28,51.68 96.28,51.95 96.64,52.3 100.51,52.3 100.63,52.42 101.02,52.42 101.1,52.38 101.23,52.38 101.36,52.43 101.63,52.43 101.71,52.4 101.93,52.4 101.99,52.43 102.08,52.48 102.09,52.52 102.09,52.6 102.03,52.67 UC1.BA34
  BOTTOM w0.102: v2(62.58,36.03) 62.31,35.76 62.31,35.48 62.1,35.26 60.38,35.26 60.15,35.49 60.03,35.49 59.92,35.38 JDIMM1.200
DDR_A_DQS6: length 55.7
  IN1 w0.076: v2(96.41,49.69) 96.53,49.57 96.53,49.19 96.13,48.79 92.7,48.79 90.82,46.9 90.82,44.91 89.77,43.86 89.73,43.86 89.73,43.85
  IN1 w0.127: v2(63.9,30.59) 64.06,30.75 64.06,31.24 64.33,31.51 65.53,31.51 66.73,30.31 66.73,29.98 66.86,29.85 67.24,29.85 67.37,29.98 67.37,30.31 67.64,30.58 68.18,30.58 68.46,30.3 68.71,30.3 69.01,30.6 69.7,30.6 70,30.3 70.48,30.3 70.78,30.6 71.46,30.6 71.76,30.3 72.57,30.3 76.06,33.79 79.83,33.79 87.99,41.96 87.99,42.26 89.56,43.83 89.71,43.83 89.73,43.85
  BOTTOM w0.076: UC1.AY30 102.27,50.34 101.99,50.47 101.68,50.47 101.6,50.44 101.39,50.44 101.28,50.49 101.07,50.49 100.95,50.44 100.34,50.44 100.31,50.47 99.77,50.47 99.56,50.26 96.8,50.26 96.63,50.08 96.63,49.9 v2(96.41,49.69)
  BOTTOM w0.102: v2(63.9,30.59) 64.05,30.59 64.2,30.44 64.2,30.2 64.53,29.86 65.81,29.86 66.23,30.28 66.33,30.28 66.49,30.13 JDIMM1.221
DDR_A_DQS7: length 58.7
  IN1 w0.127: v2(93.58,45.97) 93.94,45.6 93.94,41.01 91.49,38.56 90.56,38.56 84.39,32.4 84.39,32.11 83.06,30.77 82.77,30.77 81.57,29.58 78.17,29.58 73.93,25.34 70.54,25.34 69.72,24.52 67.88,24.52 67.24,25.16 65.94,25.16 65.63,25.47 62.2,25.47 61.93,25.21 61.93,25.03 61.71,24.81 v2(61.54,24.81)
  BOTTOM w0.076: UC1.BA26 102.03,47.68 102.09,47.62 102.09,47.54 102.08,47.49 101.99,47.44 101.93,47.42 101.71,47.42 101.63,47.45 101.36,47.45 101.23,47.4 101.12,47.4 100.98,47.45 100.59,47.45 100.38,47.24 99.57,47.24 99.38,47.05 94.39,47.05 93.73,46.39 93.73,46.12 v2(93.58,45.97)
  BOTTOM w0.102: JDIMM1.242 60.08,24.87 60.23,25.03 60.4,25.03 60.89,25.51 61.63,25.51 61.73,25.42 61.73,24.99 v2(61.54,24.81)
DDR_A_DQS#0: length 70.1
  IN1 w0.076: 106.76,84.01 106.57,84.01
  IN1 w0.127: v2(64.66,84.64) 64.49,84.64 64.21,84.36 64.21,84.15 64.34,84.02 65.95,84.02 66.41,84.47 66.41,84.65 66.14,84.93 66.14,85.31 66.55,85.73 66.94,85.73 67.21,85.46 67.39,85.46 67.57,85.64 67.57,85.82 67.27,86.12 67.27,86.5 68.12,87.36 68.64,87.36 69.05,86.94 69.64,86.94 70.05,87.36 90.32,87.36 94.03,91.07 102.46,91.07 106.38,87.15 106.38,84.2 106.57,84.01 ; v2(106.98,84.24) 106.76,84.01
  BOTTOM w0.076: v2(106.98,84.24) 106.71,83.96 106.47,83.96 106.29,83.79 106.29,79.13 106.78,78.65 106.78,76.07 107.32,75.53 107.32,74.47 107.23,74.39 107.23,74.06 107.24,74.06 107.24,74.03 107.29,73.89 107.29,73.78 107.24,73.65 107.24,73.38 107.27,73.3 107.27,73.08 107.21,72.94 107.09,72.94 107,73.02 UC1.AM70
  BOTTOM w0.102: JDIMM1.11 66.38,84.62 66.08,84.32 65.91,84.32 65.75,84.16 64.46,84.16 64.3,84.33 64.3,84.54 64.4,84.64 v2(64.66,84.64)
DDR_A_DQS#1: length 56.9
  IN1 w0.127: v2(101.49,78.82) 101.65,78.82 101.73,78.9 101.73,79.17 100.96,79.94 98,79.94 96.05,81.89 89.73,81.89 89.3,82.32 88.19,82.32 88.06,82.19 88.06,82.16 87.79,81.89 87.2,81.89 86.93,82.16 86.93,82.19 86.8,82.32 86.42,82.32 86.29,82.19 86.29,82.16 86.02,81.89 85.43,81.89 85.16,82.16 85.16,82.19 85.03,82.32 73,82.32 68.98,78.3 67.34,78.3 67.13,78.51 66.68,78.51 66.52,78.35 63.45,78.35 63.21,78.11 62.58,78.11 62.13,78.57 62.06,78.57 v2(61.61,79.02)
  BOTTOM w0.076: UC1.AT69 104.47,72.54 104.44,72.57 104.22,73.04 104.22,73.33 104.26,73.41 104.26,73.62 104.2,73.73 104.2,73.95 104.26,74.06 104.26,74.45 104.17,74.53 104.17,75.37 101.4,78.14 101.4,78.39 101.49,78.48 v2(101.49,78.82)
  BOTTOM w0.102: JDIMM1.32 59.86,79.38 60.06,79.17 60.24,79.17 60.4,79.01 60.4,78.83 60.85,78.38 61.73,78.38 61.92,78.57 61.92,78.72 v2(61.61,79.02)
DDR_A_DQS#2: length 51.1
  IN1 w0.127: v2(97.09,74.78) 97.09,75.02 96.52,75.58 96.4,75.58 94.56,77.42 74.21,77.42 70.22,73.43 63.78,73.43 v2(63.11,74.1)
  BOTTOM w0.076: UC1.BA64 101.92,69.74 102,69.82 102,69.88 101.86,70.01 101.71,70.01 101.63,69.98 101.36,69.98 101.23,70.03 101.12,70.03 101.1,70.03 100.99,69.98 100.64,69.98 100.45,70.17 99.95,70.17 99,71.11 99,73.3 98.5,73.81 97.5,73.81 97.29,74.02 97.29,74.58 v2(97.09,74.78)
  BOTTOM w0.102: v2(63.11,74.1) 63.33,74.31 63.33,74.65 63.64,74.96 64.73,74.96 65.71,73.99 66.23,73.99 66.37,74.13 JDIMM1.53
DDR_A_DQS#3: length 49.8
  IN1 w0.076: 93.38,71.32 93.51,71.19 93.51,71.17 94.06,70.62 96.56,70.62 97.25,69.94 97.25,69.78 v2(97.04,69.57)
  IN1 w0.127: 93.38,71.32 91.5,73.2 76.32,73.2 73.45,70.33 73.07,70.33 70.99,68.24 62.89,68.24 62.76,68.12 62.76,67.96 v2(62.89,67.82)
  BOTTOM w0.076: UC1.AY60 102.18,67.29 101.87,66.98 101.36,66.98 101.34,66.97 101.31,66.94 101.26,66.94 101.09,66.94 100.95,67.01 99.73,67.01 97.8,68.95 97.42,68.95 97.23,69.14 97.23,69.38 v2(97.04,69.57)
  BOTTOM w0.102: JDIMM1.74 60.08,68.88 60.29,68.66 62.05,68.66 v2(62.89,67.82)
DDR_A_DQS#4: length 51.9
  IN1 w0.076: v2(96.97,54.96) 96.88,54.96 96.67,54.76 96.67,54.44 96.34,54.11 92.15,54.11 91.84,53.8 91.71,53.8 90.23,52.31 89.73,52.31
  IN1 w0.127: 89.73,52.31 86.35,52.31 79.77,45.73 79.77,45.3 76.47,42 72.15,42 72.01,41.85 71.04,41.85 70.91,41.73 70.91,41.57 70.64,41.3 69.81,41.3 69.54,41.57 69.54,41.74 69.35,41.93 67.68,41.93 67.56,41.81 67.56,41.47 67.28,41.19 66.7,41.19 66.42,41.47 66.42,41.81 66.3,41.93 64.57,41.93 64.44,41.81 64.44,41.42 v2(64.73,41.13)
  BOTTOM w0.076: UC1.BA38 102,54.94 102.11,54.94 102.18,54.98 102.18,55.05 102.18,55.06 102.18,55.13 102.15,55.15 102.08,55.21 101.99,55.26 101.93,55.29 101.71,55.29 101.63,55.25 101.36,55.25 101.23,55.3 101.12,55.3 100.98,55.25 100.47,55.25 100.38,55.35 98.94,55.35 98.46,55.84 97.11,55.84 96.75,55.47 96.75,55.19 v2(96.97,54.96)
  BOTTOM w0.102: v2(64.73,41.13) 64.51,41.13 64.34,40.95 64.34,40.67 64.44,40.56 65.86,40.56 66.15,40.85 66.22,40.85 66.49,41.13 JDIMM1.177
DDR_A_DQS#5: length 53.9
  IN1 w0.076: 89.22,48.34 89.24,48.34 89.27,48.31 89.48,48.31 89.86,48.7 89.86,49.03 92.86,52.03 96.27,52.03 96.54,51.77 96.54,51.62 v2(96.7,51.45)
  IN1 w0.127: 89.22,48.34 88.11,48.34 83.73,43.96 83.73,43.65 78.11,38.03 74.2,38.03 72.43,36.26 69.18,36.26 68.96,36.49 68.29,36.49 68.07,36.26 65.91,36.26 65.38,36.79 62.26,36.79 61.99,36.52 61.99,36.15 61.86,36.03 v2(61.82,36.03)
  BOTTOM w0.076: v2(96.7,51.45) 96.45,51.7 96.45,51.88 96.71,52.14 100.58,52.14 100.7,52.26 100.98,52.26 101.07,52.22 101.28,52.22 101.39,52.27 101.6,52.27 101.68,52.23 101.96,52.23 102.07,52.28 102.21,52.36 102.26,52.49 102.34,52.57 UC1.AY34
  BOTTOM w0.102: JDIMM1.198 59.92,35.87 60.12,35.68 60.23,35.68 60.46,35.46 62.02,35.46 62.12,35.56 62.12,35.87 61.96,36.03 v2(61.82,36.03)
DDR_A_DQS#6: length 55.6
  IN1 w0.076: 89.9,43.67 89.9,43.71 91.02,44.82 91.02,46.82 92.79,48.59 96.21,48.59 96.73,49.1 96.73,49.5 96.92,49.69 v2(97.06,49.69)
  IN1 w0.127: v2(64.66,30.59) 64.64,30.57 64.44,30.57 64.31,30.7 64.31,31.13 64.44,31.26 65.43,31.26 66.48,30.21 66.48,29.87 66.75,29.6 67.34,29.6 67.61,29.87 67.61,30.21 67.74,30.33 68.07,30.33 68.35,30.05 68.81,30.05 69.11,30.35 69.59,30.35 69.89,30.05 70.58,30.05 70.88,30.35 71.36,30.35 71.66,30.05 72.67,30.05 76.16,33.54 79.93,33.54 88.24,41.85 88.24,42.16 89.67,43.58 89.81,43.58 89.9,43.67
  BOTTOM w0.076: UC1.BA30 102,49.99 102.07,50 102.15,50.08 102.15,50.16 102.11,50.21 101.99,50.28 101.93,50.31 101.71,50.31 101.63,50.27 101.36,50.27 101.23,50.32 101.1,50.32 100.99,50.27 100.27,50.27 100.24,50.3 99.84,50.3 99.63,50.09 96.87,50.09 96.79,50.02 96.79,49.83 96.93,49.69 v2(97.06,49.69)
  BOTTOM w0.102: v2(64.66,30.59) 64.53,30.59 64.39,30.45 64.39,30.28 64.61,30.06 65.73,30.06 66.15,30.47 66.27,30.47 66.28,30.47 66.32,30.47 66.47,30.63 JDIMM1.219
DDR_A_DQS#7: length 58.9
  IN1 w0.127: v2(62.3,24.81) 62.18,24.93 62.18,25.11 62.3,25.23 65.52,25.23 65.83,24.92 67.14,24.92 67.78,24.28 69.82,24.28 70.64,25.09 74.04,25.09 78.27,29.33 81.67,29.33 82.87,30.52 83.16,30.52 84.64,32.01 84.64,32.3 90.66,38.31 91.59,38.31 94.19,40.91 94.19,45.93 v2(94.23,45.97)
  BOTTOM w0.076: v2(94.23,45.97) 94.13,45.97 93.9,46.2 93.9,46.32 94.46,46.88 99.44,46.88 99.64,47.07 100.44,47.07 100.66,47.29 100.95,47.29 101.07,47.23 101.28,47.23 101.39,47.29 101.6,47.29 101.68,47.25 101.96,47.25 102.07,47.3 102.21,47.38 102.26,47.51 102.26,47.57 102.28,47.59 UC1.AY26
  BOTTOM w0.102: v2(62.3,24.81) 62.16,24.81 61.92,25.05 61.92,25.55 61.76,25.71 60.81,25.71 60.32,25.22 60.23,25.22 60.07,25.38 JDIMM1.240
DDR_A_MA0: length 48.9
  IN1 w0.076: v2(102.29,61.32) 101.16,61.32 100.68,60.84 95.13,60.84 94.72,60.43
  IN1 w0.211: v2(62.31,51.75) 63.26,50.8 65.76,50.8 66.16,51.21 72.12,51.21 72.87,51.97 73.89,51.97 82,60.07 94.35,60.07 94.72,60.43
  BOTTOM w0.076: v2(102.29,61.32) 102.29,61.37 102.15,61.51 UC1.AY50
  BOTTOM w0.163: JDIMM1.144 60.02,51.38 60.23,51.16 61.77,51.16 62.31,51.71 v2(62.31,51.75)
DDR_A_MA1: length 50.5
  IN1 w0.076: v2(96.8,63.68) 96.99,63.87 97.15,63.87 97.43,63.59 97.43,63.41 97.29,63.27 91.66,63.27 91.57,63.18
  IN1 w0.211: 91.57,63.18 91.42,63.03 90.21,63.03 89.91,62.73 80.89,62.73 72.79,54.63 71.75,54.63 71.45,54.32 70.91,54.32 70.6,54.63 70.06,54.63 69.76,54.32 69.22,54.32 68.92,54.63 68.29,54.63 67.99,54.32 67.39,54.32 67.07,54.64 66.65,54.64 66.33,54.32 65.85,54.32 65.53,54.65 64.02,54.65 63.81,54.44 v2(63.81,54.19)
  BOTTOM w0.076: UC1.BB50 100.85,61.76 100.85,61.66 100.78,61.58 99.64,61.58 97.72,63.49 96.98,63.49 v2(96.8,63.68)
  BOTTOM w0.163: JDIMM1.133 66.18,54.13 65.11,55.2 63.31,55.2 63.14,55.04 63.14,54.71 63.67,54.19 v2(63.81,54.19)
DDR_A_MA2: length 51.7
  IN1 w0.076: v2(97.51,64.03) 97.32,64.22 96.81,64.22 96.06,63.46 94.83,63.46 94.52,63.77 94.13,63.77 93.86,63.51 89.99,63.51
  IN1 w0.211: v2(62.29,54.19) 62.29,54.32 62.07,54.55 62.07,55.01 62.28,55.22 62.68,55.22 63.01,54.88 63.57,54.88 63.9,55.22 67.1,55.22 67.2,55.12 72.59,55.12 80.69,63.22 89.68,63.22 89.75,63.29 89.77,63.29 89.99,63.51
  BOTTOM w0.076: UC1.AY51 102.33,62.25 102.06,62.25 102.01,62.2 101.92,62.17 101.7,62.17 101.66,62.19 101.3,62.19 101.28,62.17 101.26,62.17 101.07,62.17 100.99,62.2 100.64,62.2 100.34,61.91 99.78,61.91 97.66,64.03 v2(97.51,64.03)
  BOTTOM w0.163: JDIMM1.132 59.84,54.38 60.29,54.83 61.02,54.83 61.22,54.63 61.74,54.63 61.97,54.85 62.44,54.85 62.67,54.63 62.67,54.4 62.46,54.19 v2(62.29,54.19)
DDR_A_MA3: length 50.4
  IN1 w0.076: 89.65,63.85 93.64,63.85 93.78,64 95.23,64 v2(95.4,63.83)
  IN1 w0.211: 89.65,63.85 89.5,63.71 80.49,63.71 72.82,56.04 72.17,56.04 71.96,55.83 71.96,55.82 71.75,55.61 71.33,55.61 71.12,55.82 71.12,55.83 70.91,56.04 70.49,56.04 70.28,55.83 70.28,55.82 70.07,55.61 69.64,55.61 69.43,55.82 69.43,55.83 69.22,56.04 68.08,56.04 67.75,55.71 67.24,55.71 66.91,56.04 66.46,56.04 66.13,55.71 64.9,55.71 v2(64.87,55.68)
  BOTTOM w0.076: v2(95.4,63.83) 93.44,63.83 93.37,63.76 93.37,63.39 93.44,63.31 97.67,63.31 97.94,63.05 97.94,62.25 98.78,61.4 101.56,61.4 101.64,61.48 101.64,61.69 101.56,61.77 UC1.BA50
  BOTTOM w0.163: JDIMM1.131 66.41,54.62 65.23,55.81 65,55.81 v2(64.87,55.68)
DDR_A_MA4: length 50.5
  IN1 w0.076: v2(93.85,64.57) 93.47,64.2 89.3,64.2
  IN1 w0.211: v2(61.82,55.68) 61.82,55.46 61.58,55.22 60.81,55.22 60.6,55.43 60.6,56.26 60.81,56.47 62.06,56.47 62.33,56.2 65.93,56.2 66.26,56.53 72.61,56.53 80.28,64.2 89.3,64.2
  BOTTOM w0.076: v2(93.85,64.57) 94.41,65.14 96.68,65.14 97.09,64.73 97.8,64.73 99.48,63.05 100.8,63.05 UC1.BB52
  BOTTOM w0.163: JDIMM1.128 60.59,55.38 60.72,55.24 61.39,55.24 v2(61.82,55.68)
DDR_A_MA5: length 51.5
  IN1 w0.076: v2(95.61,64.58) 95.07,65.12 92.39,65.12 91.84,65.67 90.51,65.67 90,66.18 89.17,66.18
  IN1 w0.211: v2(61.98,57.15) 61.84,57.15 61.63,57.36 61.63,57.75 61.83,57.95 65.63,57.95 66.17,58.49 71.98,58.49 79.68,66.18 84.3,66.18 84.81,65.67 86.04,65.67 86.54,66.17 86.54,66.18 86.55,66.18 89.17,66.18
  BOTTOM w0.076: v2(95.61,64.58) 95.61,64.37 95.77,64.21 96.92,64.21 97.1,64.4 97.66,64.4 99.4,62.66 100.97,62.66 100.98,62.67 101.07,62.7 101.27,62.7 101.36,62.67 101.36,62.67 101.37,62.66 101.38,62.66 101.75,62.66 101.82,62.58 UC1.BA51
  BOTTOM w0.163: v2(61.98,57.15) 62.13,57.15 62.41,56.87 62.41,56.28 62.25,56.12 60.17,56.12 59.93,55.88 JDIMM1.126
DDR_A_MA6: length 50.5
  IN1 w0.076: 89.17,64.69 90.22,64.69 90.76,65.23 91.59,65.23 92.45,64.37 93.19,64.37 93.26,64.44 v2(93.26,64.59)
  IN1 w0.211: 89.17,64.69 80.08,64.69 72.41,57.02 67.69,57.02 67.31,57.4 66.84,57.4 66.47,57.02 66.06,57.02 65.73,56.69 63.72,56.69 63.51,56.9 v2(63.51,57.15)
  BOTTOM w0.076: UC1.BA52 101.5,63.2 101.34,63.35 100.69,63.35 100.55,63.22 99.55,63.22 97.87,64.89 97.16,64.89 96.69,65.36 93.13,65.36 92.86,65.08 92.86,64.67 92.93,64.59 v2(93.26,64.59)
  BOTTOM w0.163: JDIMM1.127 66,55.62 65.4,56.22 63.3,56.22 63.14,56.39 63.14,56.78 v2(63.51,57.15)
DDR_A_MA7: length 52.9
  IN1 w0.076: 89.17,67.16 89.23,67.22 89.7,67.22 90.73,66.19 94.07,66.19 94.16,66.28 95.55,66.28 95.66,66.17 v2(95.66,65.93)
  IN1 w0.211: v2(62.39,58.41) 62.25,58.55 62.25,58.9 62.4,59.05 65.02,59.05 66.04,60.07 70.43,60.07 71.03,59.47 71.58,59.47 79.27,67.16 89.17,67.16
  BOTTOM w0.076: v2(95.66,65.93) 95.47,65.73 95.46,65.73 95.46,65.6 95.54,65.52 96.76,65.52 97.23,65.06 97.94,65.06 99.61,63.38 100.48,63.38 100.62,63.52 101.6,63.52 101.79,63.33 102.72,63.33 102.8,63.26 UC1.AW52
  BOTTOM w0.163: JDIMM1.122 59.88,56.88 59.96,56.95 60.4,56.95 61.04,57.59 62.69,57.59 62.91,57.8 62.91,58.03 62.53,58.41 v2(62.39,58.41)
DDR_A_MA8: length 51.4
  IN1 w0.076: v2(95.03,64.57) 95.03,64.77 94.85,64.96 92.18,64.96 91.71,65.42 90.53,65.42 90.29,65.18 89.56,65.18
  IN1 w0.211: 89.56,65.18 89.32,65.18 89.11,65.39 89.11,65.48 88.9,65.69 88.48,65.69 88.26,65.48 88.26,65.39 88.05,65.18 87.6,65.18 87.39,65.39 87.39,65.48 87.18,65.69 86.76,65.69 86.55,65.48 86.55,65.39 86.34,65.18 84.51,65.18 84.3,65.39 84.3,65.48 84.09,65.69 83.67,65.69 83.46,65.48 83.46,65.39 83.25,65.18 82.83,65.18 82.62,65.39 82.62,65.48 82.41,65.69 81.98,65.69 81.77,65.48 81.77,65.39 81.56,65.18 81.14,65.18 80.93,65.39 80.93,65.48 80.72,65.69 80.3,65.69 80.09,65.48 80.09,65.39 79.3,64.61 78.8,64.61 78.45,64.26 78.45,63.76 78.11,63.41 77.6,63.41 77.26,63.07 77.26,62.56 76.92,62.22 76.41,62.22 76.07,61.88 76.07,61.37 75.72,61.03 75.22,61.03 74.87,60.68 74.87,60.18 74.53,59.84 74.03,59.84 73.68,59.49 73.68,58.99 73.34,58.64 72.83,58.64 72.49,58.3 72.49,57.79 72.21,57.51 71.34,57.51 71.13,57.72 71.13,57.79 70.92,58 70.5,58 70.29,57.79 70.29,57.72 70.08,57.51 68.8,57.51 68.59,57.72 68.59,57.79 68.38,58 66.37,58 65.83,57.46 65.24,57.46 65.03,57.25 v2(65.03,57.15)
  BOTTOM w0.076: UC1.AY52 102.19,62.95 102.19,62.83 102.12,62.76 101.94,62.76 101.87,62.83 101.4,62.83 101.3,62.87 101.06,62.87 101.04,62.87 100.94,62.83 99.47,62.83 97.73,64.56 97.02,64.56 96.61,64.97 94.89,64.97 94.81,64.9 94.81,64.79 v2(95.03,64.57)
  BOTTOM w0.163: v2(65.03,57.15) 64.87,56.99 64.87,56.8 65.03,56.64 65.58,56.64 66.09,56.13 JDIMM1.125
DDR_A_MA9: length 49.8
  IN1 w0.076: v2(94.41,65.88) 94.57,65.88 94.94,65.51 94.94,65.4 94.83,65.3 93.26,65.3 93.05,65.51 93.05,65.85 92.97,65.93 90.76,65.93 89.9,66.79 89.29,66.79 89.17,66.67
  IN1 w0.211: 89.17,66.67 86.26,66.67 86.05,66.46 86.05,66.37 85.84,66.16 85.42,66.16 85.21,66.37 85.21,66.46 85,66.67 79.48,66.67 71.78,58.98 70.68,58.98 70.46,59.19 70.46,59.34 70.25,59.55 69.83,59.55 69.62,59.34 69.62,59.19 69.41,58.98 68.99,58.98 68.78,59.19 68.78,59.34 68.57,59.55 68.15,59.55 67.93,59.34 67.93,59.19 67.72,58.98 67.3,58.98 67.09,59.19 67.09,59.34 66.88,59.55 66.46,59.55 66.25,59.34 66.25,59.19 66.04,58.98 65.65,58.98 65.44,58.77 v2(65.44,58.41)
  BOTTOM w0.076: UC1.BB54 100.85,64.09 100.77,64.01 99.68,64.01 97.83,65.87 97.83,66.22 97.59,66.45 96.88,66.45 96.74,66.31 93.68,66.31 93.58,66.21 93.58,65.96 93.66,65.88 v2(94.41,65.88)
  BOTTOM w0.163: JDIMM1.121 66.28,57.13 65.33,58.08 65.33,58.31 v2(65.44,58.41)
DDR_A_MA10: length 53.2
  IN1 w0.076: 95.14,58.82 97.92,58.82 99.63,60.53 102.03,60.53 102.78,61.28 102.78,62.36 103.24,62.82 103.87,62.82 104.37,62.33 v2(104.37,62.22)
  IN1 w0.211: v2(60.89,49.83) 61.35,50.29 67.89,50.29 68.19,50.58 72.19,50.58 73.08,51.48 74.1,51.48 82.2,59.58 93.15,59.58 93.91,58.82 95.14,58.82
  BOTTOM w0.076: UC1.AT50 104.61,62.02 104.41,62.22 v2(104.37,62.22)
  BOTTOM w0.163: JDIMM1.146 59.94,48.87 v2(60.89,49.83)
DDR_A_MA11: length 50.7
  IN1 w0.076: v2(97.44,65.93) 97.44,66.71 96.88,67.28 90.96,67.28 90.15,68.09
  IN1 w0.211: 90.15,68.09 89.61,68.63 78.66,68.63 71.57,61.54 62.87,61.54 60.86,59.53 v2(60.86,58.41)
  BOTTOM w0.076: v2(97.44,65.93) 97.53,65.93 99.75,63.71 100.35,63.71 100.48,63.85 101.01,63.85 101.29,64.13 UC1.BA54
  BOTTOM w0.163: JDIMM1.120 60.24,57.38 60.86,58 v2(60.86,58.41)
DDR_A_MA12: length 51.4
  IN1 w0.076: v2(96.84,65.96) 97.24,66.35 97.24,66.68 97.16,66.76 94.4,66.76 94,66.36 90.8,66.36 89.5,67.65 89.17,67.65
  IN1 w0.211: 89.17,67.65 79.07,67.65 71.97,60.56 64.22,60.56 64.01,60.34 64.01,60.04 v2(64.54,59.51)
  BOTTOM w0.076: v2(96.84,65.96) 96.84,65.67 97.3,65.22 98.01,65.22 99.68,63.55 100.41,63.55 100.55,63.68 101.49,63.68 101.7,63.89 102.84,63.89 102.91,63.97 102.91,64.15 102.84,64.22 UC1.AW54
  BOTTOM w0.163: JDIMM1.119 66.52,57.62 66.17,57.98 66.17,58.3 65.62,58.84 64.25,58.84 64.09,59.01 64.09,59.2 64.4,59.51 v2(64.54,59.51)
DDR_A_MA13: length 54.2
  IN1 w0.076: 89.61,55.17 90.16,55.17 90.79,55.8 98.73,55.8 99,55.53 100.55,55.53 103.17,58.15 104.38,58.15 104.65,58.42 104.65,59.19 v2(104.36,59.48)
  IN1 w0.211: 89.61,55.17 84.03,55.17 76.67,47.81 76.67,46.67 75.01,45 61.79,45 v2(61.07,45.72)
  BOTTOM w0.076: v2(104.36,59.48) 104.36,59.57 UC1.AU46
  BOTTOM w0.163: v2(61.07,45.72) 60.91,45.87 JDIMM1.158
DDR_A_ODT0: length 55.4
  IN1 w0.076: 89.61,56.15 90.12,56.15 90.7,56.73 91.63,56.73 92.21,56.15 98.89,56.15 99.18,55.86 100.31,55.86 103.34,58.88 103.84,58.88 104.07,59.11 104.34,59.11 104.45,59 104.45,58.76 v2(104.25,58.55)
  IN1 w0.211: 89.61,56.15 83.62,56.15 74.63,47.15 69.61,47.15 69.23,46.77 67.83,46.77 67.62,46.56 67.62,46.19 67.41,45.98 66.97,45.98 66.76,46.19 66.76,46.56 66.55,46.77 66.12,46.77 65.92,46.57 65.92,46.35 65.76,46.19 65.37,46.19 65.23,46.34 64.63,46.34 64.49,46.2 64.04,46.2 63.83,46.41 63.83,46.72 v2(63.9,46.8)
  BOTTOM w0.076: UC1.AT45 104.72,59.06 104.8,58.97 104.8,58.87 104.65,58.71 104.65,58.59 104.52,58.46 104.32,58.46 104.25,58.53 v2(104.25,58.55)
  BOTTOM w0.163: JDIMM1.155 66.29,46.63 65.82,46.15 65.62,46.15 65.41,46.36 65.09,46.36 64.89,46.15 64.65,46.15 64.4,46.41 64.1,46.41 63.86,46.17 63.68,46.17 63.53,46.32 63.53,46.6 63.72,46.8 v2(63.9,46.8)
DDR_A_ODT1: length 56.6
  IN1 w0.076: v2(104.29,57.75) 104.06,57.98 103.26,57.98 100.62,55.35 98.94,55.35 98.65,55.63 90.94,55.63 89.98,54.68 89.61,54.68
  IN1 w0.211: 89.61,54.68 85.37,54.68 85.08,54.38 84.78,54.38 84.48,54.68 84.23,54.68 83.86,54.31 83.86,54.1 84.23,53.73 84.23,53.53 83.83,53.13 83.63,53.13 83.3,53.47 83.03,53.47 82.7,53.14 82.7,52.87 83.04,52.54 83.04,52.34 82.64,51.94 82.44,51.94 82.11,52.28 81.83,52.28 81.51,51.95 81.51,51.68 81.81,51.38 81.81,51.12 81.45,50.75 81.19,50.75 80.85,51.08 80.64,51.08 80.28,50.73 80.28,50.52 80.62,50.18 80.62,49.92 80.31,49.61 80.05,49.61 79.74,49.92 79.47,49.92 79.15,49.59 79.15,49.32 79.48,48.99 79.48,48.79 79.15,48.45 78.89,48.45 78.59,48.76 78.32,48.76 77.99,48.43 77.99,48.16 78.25,47.9 78.25,47.6 77.98,47.33 77.38,47.33 77.16,47.11 77.16,46.47 76.23,45.53 76.23,45.42 75.3,44.5 65.42,44.5 v2(65.38,44.53)
  BOTTOM w0.076: v2(104.29,57.75) 104.27,57.74 104.27,57.58 104.35,57.51 104.98,57.51 105.06,57.59 105.06,57.88 104.76,58.18 104.65,58.18 UC1.AT43
  BOTTOM w0.163: JDIMM1.161 66.4,45.13 66.13,44.85 65.54,44.85 65.38,44.69 v2(65.38,44.53)
DDR_A_PAR: length 49.9
  IN1 w0.076: 94.36,60.77 94.6,61.01 100.61,61.01 102.59,62.99 104.08,62.99 v2(104.27,63.17)
  IN1 w0.211: v2(63.84,51.75) 64.3,51.29 65.55,51.29 65.96,51.7 71.91,51.7 72.67,52.46 73.69,52.46 81.79,60.56 94.15,60.56 94.36,60.77
  BOTTOM w0.076: UC1.AT52 v2(104.27,63.17)
  BOTTOM w0.163: v2(63.84,51.75) 64.3,51.29 66.21,51.29 66.54,51.62 JDIMM1.143
DDR_A_RAS#: length 52.4
  IN1 w0.076: 92.24,57.52 92.84,56.91 98.89,56.91 99.14,57.17 99.27,57.17 99.52,57.42 99.52,58.25 101.11,59.84 102.03,59.84 103.52,61.32 v2(103.59,61.32)
  IN1 w0.211: 92.24,57.52 91.65,58.11 82.81,58.11 74.71,50.01 73.69,50.01 72.8,49.11 68.8,49.11 68.5,48.82 63.31,48.82 v2(62.33,47.84)
  BOTTOM w0.076: v2(103.59,61.32) 103.59,61.43 UC1.AU50
  BOTTOM w0.163: v2(62.33,47.84) 61.87,47.38 JDIMM1.152
DDR_A_WE#: length 51.4
  IN1 w0.076: v2(104.28,60.41) 104.28,60.64 104.13,60.78 103.21,60.78 102.01,59.58 101.24,59.58 99.72,58.06 99.72,57.36 99.33,56.98 99.21,56.98 98.98,56.75 92.32,56.75 91.55,57.52
  IN1 w0.211: v2(63.85,47.84) 64.34,48.33 68.7,48.33 69,48.62 73,48.62 73.89,49.52 74.91,49.52 83.01,57.62 91.45,57.62 91.55,57.52
  BOTTOM w0.076: UC1.AT46 v2(104.28,60.41)
  BOTTOM w0.163: v2(63.85,47.84) 64.29,47.4 65.56,47.4 65.79,47.62 JDIMM1.151
DDR_B_ACT#: length 73.5
  IN2 w0.076: v2(106.83,64.04) 106.51,64.36 106.51,65.12 106.15,65.48 100.83,65.48 100.66,65.65 100.12,65.65 98.39,67.38 98.39,67.57 97.17,68.79 93.17,68.79 92.98,68.98
  IN2 w0.211: v2(46.65,60.33) 48.8,62.48 51.45,62.48 53.46,64.48 55.29,64.48 57.25,66.44 57.72,66.44 58.28,67 58.28,67.47 61.05,70.24 69.67,70.24 71.63,72.2 72.87,72.2 74.34,73.66 88.31,73.66 92.98,68.99 92.98,68.98
  BOTTOM w0.076: v2(106.83,64.04) 106.83,63.89 UC1.AN53
  BOTTOM w0.163: v2(46.65,60.33) 46.65,59.86 46.17,59.38 JDIMM2.114
DDR_B_ALERT#: length 78.7
  IN2 w0.076: 106.77,61.21 106.77,62.41 106.48,62.7 105.9,62.7 105.07,63.54 103.96,63.54 103.38,62.96 101.25,62.96 98.41,65.81 98.41,66.11 97.82,66.69 96.48,66.69 96.29,66.88 94,66.88 93.58,67.3 91.9,67.3 91.46,67.75 91.12,67.75 90.57,68.3
  IN2 w0.089: 106.77,61.21 107.26,60.73 107.26,59.28 106.65,58.67 v2(106.22,58.67)
  IN2 w0.211: v2(46.65,58.14) 46.65,58.97 47.22,59.54 49.19,59.54 49.29,59.64 51.39,59.64 53.84,62.09 56.28,62.09 60.24,66.05 60.24,66.45 61.16,67.36 66.53,67.36 67,66.89 69.87,66.89 73.22,70.24 73.68,70.24 75.15,71.7 79.76,71.7 80.62,70.84 88.03,70.84 90.57,68.3
  BOTTOM w0.102: v2(46.65,58.14) 45.92,58.87 JDIMM2.116 ; v2(106.22,58.67) UC1.AN43
DDR_B_BG0: length 72.9
  IN2 w0.076: v2(106.24,64.05) 106.24,64.36 106.13,64.47 101.38,64.47 100.52,65.32 99.68,65.32 97.93,67.07 96.98,67.07 96.75,67.31 96.75,67.94 96.32,68.37 92.07,68.37 91.62,68.82
  IN2 w0.211: 91.62,68.82 87.76,72.68 74.74,72.68 73.28,71.22 72.49,71.22 70.05,68.78 60.97,68.78 59.26,67.06 59.26,66.45 55.88,63.07 53.43,63.07 51.86,61.49 50.07,61.49 49.7,61.13 v2(49.7,60.33)
  BOTTOM w0.076: UC1.AP52 105.91,62.85 106.24,63.18 v2(106.24,64.05)
  BOTTOM w0.163: v2(49.7,60.33) 49.53,60.33 49.32,60.12 49.32,59.78 49.48,59.62 51.32,59.62 51.81,59.13 JDIMM2.115
DDR_B_BG1: length 73
  IN2 w0.076: v2(106.91,63.09) 105.75,63.09 105.14,63.7 101.91,63.7 100.45,65.16 99.59,65.16 97.87,66.88 96.67,66.88 96.39,67.16 96.39,67.87 96.17,68.09 91.65,68.09 91.62,68.12
  IN2 w0.211: v2(51.22,60.33) 51.38,60.33 53.64,62.58 56.08,62.58 59.75,66.25 59.75,66.86 61.18,68.29 70.25,68.29 72.69,70.73 73.48,70.73 74.95,72.19 80.44,72.19 80.65,71.98 80.65,71.54 80.86,71.33 81.41,71.33 81.62,71.54 81.62,71.98 81.83,72.19 82.13,72.19 82.34,71.98 82.34,71.54 82.55,71.33 83.08,71.33 83.29,71.54 83.29,71.98 83.5,72.19 83.81,72.19 84.03,71.98 84.03,71.54 84.24,71.33 84.66,71.33 84.87,71.54 84.87,71.98 85.08,72.19 85.5,72.19 85.71,71.98 85.71,71.54 85.92,71.33 86.26,71.33 86.47,71.54 86.47,71.98 86.68,72.19 87.1,72.19 87.32,71.98 87.32,71.54 87.53,71.33 88.42,71.33 91.62,68.12
  BOTTOM w0.076: v2(106.91,63.09) 106.56,62.74 UC1.AN52
  BOTTOM w0.163: JDIMM2.113 51.9,59.62 51.22,60.3 v2(51.22,60.33)
DDR_B_BS0: length 72.2
  IN2 w0.076: v2(94.1,59.28) 94.02,59.2 93.65,59.2
  IN2 w0.211: 93.65,59.2 92.56,59.2 91.76,58.4 82.62,58.4 82.4,58.19 82.4,57.8 82.19,57.59 75.36,57.59 73.6,55.83 73,55.83 68.41,51.24 68.41,50.94 68.41,50.94 68.41,50.64 67.74,49.96 66.25,49.96 65.65,49.36 55.99,49.36 55.95,49.41 45.13,49.41 44.91,49.2 44.91,45.12 45.13,44.91 45.66,44.91 45.93,45.19 45.93,48.1 46.14,48.31 v2(46.65,48.31)
  BOTTOM w0.076: UC1.BB44 100.79,58.34 99.6,58.34 99.43,58.51 98.76,58.51 98.56,58.31 95.07,58.31 v2(94.1,59.28)
  BOTTOM w0.163: v2(46.65,48.31) 46.59,48.38 JDIMM2.150
DDR_B_BS1: length 73.6
  IN2 w0.211: v2(51.22,49.87) 51.4,50.05 57.17,50.05 57.36,49.85 58.36,49.85 58.57,50.07 58.57,50.31 58.88,50.62 59.43,50.62 59.6,50.45 66.7,50.45 67.46,51.21 67.69,51.21 72.8,56.32 73.1,56.32 73.1,56.32 73.4,56.32 73.7,56.62 73.7,56.92 73.69,56.92 73.69,57.22 73.96,57.49 74.56,57.49 75.01,57.94 75.01,58.56 75.55,59.09 75.88,59.09 76.1,58.88 76.1,58.29 76.31,58.08 76.73,58.08 76.94,58.29 76.94,58.88 77.15,59.09 77.57,59.09 77.78,58.88 77.78,58.29 77.99,58.08 78.41,58.08 78.63,58.29 78.63,58.88 78.84,59.09 79.26,59.09 79.47,58.88 79.47,58.29 79.68,58.08 80.1,58.08 80.31,58.29 80.31,58.88 80.52,59.09 80.86,59.09 81.07,58.88 81.07,58.29 81.28,58.08 81.7,58.08 81.91,58.29 81.91,58.68 82.13,58.89 91.56,58.89 92.38,59.71 92.43,59.71 93.3,59.71 93.68,60.09 95.33,60.09 95.54,59.88 95.54,59.56 95.27,59.3 v2(95.27,59.27)
  BOTTOM w0.076: UC1.BA44 101.27,58.28 101,58.55 99.63,58.55 99.5,58.68 98.69,58.68 98.49,58.48 96.05,58.48 95.46,59.07 95.46,59.08 v2(95.27,59.27)
  BOTTOM w0.163: JDIMM2.145 52.2,49.62 51.96,49.87 51.96,50.69 51.7,50.95 47.97,50.95 47.86,50.84 47.86,50.47 48.02,50.31 50.64,50.31 51.08,49.87 v2(51.22,49.87)
DDR_B_CAS#: length 72.3
  IN2 w0.076: 87.52,54.38 88.63,54.38 89.95,55.71 96.86,55.71 97.27,56.12 v2(97.27,57.43)
  IN2 w0.211: v2(46.65,47.26) 48.36,45.55 51.45,45.55 51.63,45.37 51.67,45.33 51.74,45.27 58.74,45.27 59.58,44.43 59.58,42.73 60.51,41.8 65.88,41.8 66.44,42.36 66.44,42.84 73.09,49.49 73.09,50.16 76.45,53.52 77.77,53.52 78.36,54.11 84.31,54.11 84.58,54.38 87.52,54.38
  BOTTOM w0.076: UC1.AY43 102.18,57.81 102.08,57.81 101.92,57.89 101.74,57.89 101.58,57.83 101.44,57.83 101.22,57.9 101.1,57.9 100.99,57.85 100.62,57.85 100.45,58.01 99.46,58.01 99.29,58.18 98.9,58.18 98.7,57.98 96.65,57.98 96.32,57.65 96.32,57.12 96.4,57.04 97.19,57.04 97.27,57.13 v2(97.27,57.43)
  BOTTOM w0.163: JDIMM2.156 46.23,46.87 46.61,47.26 v2(46.65,47.26)
DDR_B_CKE0: length 69.6
  IN2 w0.175: 93.07,69.6 93.07,69.48 93.4,69.15 97.19,69.15 99.8,66.54 102.76,66.54 102.94,66.36 106.55,66.36 v2(107.01,65.9)
  IN2 w0.211: v2(50.46,62.94) 52.49,64.97 55.09,64.97 57.05,66.93 57.52,66.93 57.79,67.2 57.79,67.67 60.84,70.73 67.77,70.73 68.36,71.32 69.73,71.32 72.77,74.36 88.31,74.36 93.07,69.6
  BOTTOM w0.076: UC1.AN56 v2(107.01,65.9)
  BOTTOM w0.163: v2(50.46,62.94) 50.46,62.37 52.21,60.62 JDIMM2.109
DDR_B_CKE1: length 70.7
  IN2 w0.076: 92.02,69.11 92.6,68.53 97.04,68.53 98.15,67.43 98.15,67.31 99.97,65.49 100.59,65.49 100.76,65.32 105.17,65.32 v2(105.51,64.98)
  IN2 w0.211: v2(48.17,60.33) 49.83,61.99 51.65,61.99 53.66,63.99 55.49,63.99 57.45,65.95 57.93,65.95 58.77,66.79 58.77,67.27 60.77,69.27 69.59,69.27 72.03,71.71 73.07,71.71 74.54,73.17 87.96,73.17 92.02,69.11
  BOTTOM w0.076: v2(105.51,64.98) 105.51,64.97 105.51,64.94 UC1.AP55
  BOTTOM w0.163: JDIMM2.110 46.08,60.38 46.47,60.76 47.74,60.76 v2(48.17,60.33)
DDR_B_CKE2: length 1.3
  TOP w0.102: TP5.1 v2(106.13,64.98)
  BOTTOM w0.076: v2(106.13,64.98) 106.15,64.98 106.23,64.9 106.23,64.88 UC1.AN55
DDR_B_CKE3: length 1.2
  TOP w0.102: v2(105.58,64.08) 105.28,64.53 TP6.1
  BOTTOM w0.076: UC1.AP53 105.92,63.67 v2(105.58,64.08)
DDR_B_CLK0: length 73.3
  IN2 w0.076: v2(105.64,59.46) 105.71,59.46 105.78,59.53 105.78,59.75 105.67,59.86 101.6,59.86 101.3,60.15
  IN2 w0.122: 101.3,60.15 101.07,60.39 99.25,60.39 97.76,61.89 92.59,61.89 92.55,61.85 85.95,61.85 85.9,61.8 79.07,61.8 78.81,61.55 78.81,61.41 78.55,61.14 76.25,61.14 75.98,61.41 75.98,61.81 75.86,61.93 75.49,61.93 70.93,57.36 70.18,57.36 70.06,57.24 70.06,56.88 69.79,56.61 69.22,56.61 68.95,56.88 68.95,57.24 68.82,57.37 67.44,57.37 67.32,57.24 67.32,57.02 67.72,56.61 67.72,56.23 67.32,55.82 66.94,55.82 66.44,56.32 66.27,56.32 66.01,56.07 66.01,55.89 66.51,55.39 66.51,55.01 66.1,54.61 65.73,54.61 65.32,55.01 65.15,55.01 64.74,54.6 64.32,54.6 64.06,54.87 64.06,54.9 63.93,55.02 63.57,55.02 63.45,54.9 63.45,54.87 63.18,54.6 62.61,54.6 62.34,54.87 62.34,54.89 62.22,55.01 61.85,55.01 61.73,54.89 61.73,54.87 61.46,54.6 60.94,54.6 60.67,54.87 60.67,55.13 60.55,55.25 60.18,55.25 60.06,55.13 60.06,54.57 59.79,54.3 59,54.3 56.79,52.09 50.05,52.09 49.85,52.3 49.85,52.64 49.73,52.76 v2(49.7,52.76)
  BOTTOM w0.076: v2(105.64,59.46) 105.91,59.18 UC1.AP45
  BOTTOM w0.097: v2(49.7,52.76) 49.86,52.76 50.05,52.95 50.05,53.2 50.28,53.43 52.02,53.43 52.22,53.62 JDIMM2.137
DDR_B_CLK1: length 72.2
  IN2 w0.076: v2(105.59,60.44) 105.71,60.44 105.82,60.55 105.82,60.68 105.69,60.81 105.19,60.81 105.17,60.79 102.41,60.79 102.41,60.79 101.49,60.79 101.01,61.27 100.74,61.27 100.29,60.83 99.72,60.83 99.34,61.2 99.34,61.82 98.8,62.36 91.98,62.36 91.33,63.01
  IN2 w0.122: 91.33,63.01 90.76,63.01 90.53,62.78 77.92,62.78 77.8,62.66 77.8,62.18 77.53,61.92 76.96,61.92 76.69,62.18 76.69,62.66 76.57,62.78 75.02,62.78 70.42,58.18 70.15,58.18 69.68,58.66 69.07,58.66 68.55,58.14 68.04,58.14 67.6,58.59 67.43,58.59 64.94,56.1 64.4,56.1 64.01,56.48 63.65,56.48 63.26,56.1 62.68,56.1 62.29,56.48 61.93,56.48 61.54,56.1 59.69,56.1 57.1,53.5 57.1,53.5 56.46,52.87 51.8,52.87 51.39,53.28 50.94,53.28 50.91,53.31 48,53.31 47.88,53.19 47.88,52.88 48,52.76 48.17,52.76 v2(48.17,52.76)
  BOTTOM w0.076: v2(105.59,60.44) 105.91,60.11 UC1.AP46
  BOTTOM w0.097: v2(48.17,52.76) 47.92,53.01 47.92,53.17 47.7,53.39 46.16,53.39 46,53.24 45.8,53.24 45.66,53.38 JDIMM2.138
DDR_B_CLK#0: length 73.1
  IN2 w0.076: 101.64,60.17 101.77,60.04 105.83,60.04 105.98,59.89 105.98,59.59 106.11,59.47 v2(106.23,59.47)
  IN2 w0.122: 101.64,60.17 101.17,60.64 99.36,60.64 97.86,62.13 92.48,62.13 92.45,62.1 85.84,62.1 85.8,62.05 78.96,62.05 78.57,61.66 78.57,61.51 78.44,61.39 76.35,61.39 76.23,61.51 76.23,61.91 75.96,62.18 75.39,62.18 70.82,57.61 70.07,57.61 69.81,57.34 69.81,56.98 69.68,56.86 69.32,56.86 69.2,56.98 69.2,57.34 68.93,57.62 67.33,57.62 67.07,57.35 67.07,56.91 67.48,56.5 67.48,56.33 67.22,56.07 67.04,56.07 66.54,56.57 66.16,56.57 65.76,56.17 65.76,55.79 66.26,55.29 66.26,55.12 66,54.86 65.83,54.86 65.42,55.26 65.04,55.26 64.63,54.85 64.43,54.85 64.3,54.98 64.3,55 64.04,55.27 63.46,55.27 63.2,55 63.2,54.98 63.08,54.85 62.71,54.85 62.59,54.98 62.59,54.99 62.32,55.26 61.75,55.26 61.48,54.99 61.48,54.98 61.36,54.85 61.04,54.85 60.92,54.98 60.92,55.23 60.65,55.5 60.08,55.5 59.81,55.23 59.81,54.67 59.69,54.55 58.89,54.55 56.68,52.34 50.16,52.34 50.1,52.4 50.1,52.64 50.25,52.79 50.43,52.79 v2(50.46,52.76)
  BOTTOM w0.076: v2(106.23,59.47) 106.24,59.47 106.56,59.15 UC1.AN45
  BOTTOM w0.097: JDIMM2.139 52.21,53.12 52.1,53.24 50.36,53.24 50.24,53.12 50.24,52.98 v2(50.46,52.76)
DDR_B_CLK#1: length 72.2
  IN2 w0.076: 91.36,63.26 92.09,62.53 98.87,62.53 99.51,61.89 99.51,61.27 99.79,60.99 100.23,60.99 100.67,61.44 101.08,61.44 101.17,61.35 101.56,60.95 102.34,60.95 102.34,60.95 105.1,60.95 105.12,60.97 105.76,60.97 105.99,60.75 105.99,60.62 106.17,60.44 v2(106.17,60.43)
  IN2 w0.122: 91.36,63.26 90.66,63.26 90.43,63.03 77.81,63.03 77.55,62.76 77.55,62.29 77.42,62.17 77.06,62.17 76.94,62.29 76.94,62.76 76.67,63.03 74.91,63.03 70.37,58.49 70.2,58.49 69.78,58.91 68.97,58.91 68.45,58.39 68.15,58.39 67.7,58.83 67.33,58.83 64.84,56.34 64.5,56.34 64.11,56.73 63.54,56.73 63.15,56.34 62.79,56.34 62.4,56.73 61.82,56.73 61.44,56.34 59.59,56.34 56.99,53.75 56.99,53.75 56.36,53.12 51.9,53.12 51.5,53.53 51.05,53.53 51.01,53.56 47.9,53.56 47.63,53.29 47.63,52.9 47.49,52.76 v2(47.41,52.76)
  BOTTOM w0.076: UC1.AN46 106.56,60.03 v2(106.17,60.43)
  BOTTOM w0.097: v2(47.41,52.76) 47.59,52.94 47.59,53 47.39,53.2 46.23,53.2 46.08,53.05 45.88,53.05 45.7,52.87 JDIMM2.140
DDR_B_CS#0: length 70.3
  IN2 w0.076: v2(97.92,57.45) 97.92,57.85 98.09,58.02 99.22,58.02 99.52,57.72 99.52,57.1 99.65,56.98 101.11,56.98 101.24,57.1 101.24,58.5 101.03,58.71 93.6,58.71 92.27,57.39 91.97,57.39
  IN2 w0.211: v2(51.22,48.31) 51.35,48.31 51.42,48.38 65.48,48.38 66,47.86 66.74,47.86 66.95,48.08 66.95,48.79 67.15,48.98 68.14,48.98 70.5,51.34 70.5,51.87 70.83,52.2 71.36,52.2 71.69,52.53 71.69,53.06 72.03,53.39 72.55,53.39 72.89,53.73 72.89,54.25 73.22,54.59 73.75,54.59 75.74,56.58 83.31,56.58 83.52,56.79 83.52,57.21 83.73,57.42 84.23,57.42 84.44,57.21 84.44,57.04 84.65,56.83 85.07,56.83 85.28,57.04 85.28,57.21 85.49,57.42 85.92,57.42 86.13,57.21 86.13,57.04 86.34,56.83 86.8,56.83 87.02,57.04 87.02,57.15 87.26,57.39 87.63,57.39 87.84,57.18 87.84,57.06 88.05,56.85 88.47,56.85 88.68,57.06 88.68,57.18 88.89,57.39 91.97,57.39
  BOTTOM w0.076: UC1.BB42 100.79,56.9 99.91,56.9 99.7,57.12 98.81,57.12 98.74,57.04 98.18,57.04 97.92,57.3 v2(97.92,57.45)
  BOTTOM w0.163: v2(51.22,48.31) 51.08,48.45 51.08,48.71 51.25,48.87 51.77,48.87 52.02,48.62 JDIMM2.149
DDR_B_CS#1: length 72.7
  IN2 w0.076: 89.07,55.49 89.8,56.22 95.46,56.22 95.59,56.34 95.59,56.7 95.44,56.84 94.46,56.84 v2(94.02,57.28)
  IN2 w0.211: v2(49.7,47.26) 49.48,47.04 49.48,46.74 49.69,46.53 51.86,46.53 52.08,46.31 52.14,46.25 59.71,46.25 60.7,45.26 65.81,45.26 66.22,44.85 66.65,44.85 67.06,45.26 67.47,45.26 72.11,49.9 72.11,50.2 72.07,50.23 72.07,50.53 76.05,54.51 77.37,54.51 77.95,55.09 83.91,55.09 84.18,55.36 88.95,55.36 89.07,55.49
  BOTTOM w0.076: v2(94.02,57.28) 94.02,56.74 94.1,56.66 99.18,56.66 99.28,56.76 99.59,56.76 99.77,56.57 100.45,56.57 100.5,56.53 100.99,56.53 101.02,56.54 101.4,56.69 101.88,56.69 UC1.AY42
  BOTTOM w0.163: v2(49.7,47.26) 49.7,46.95 49.57,46.82 48.29,46.82 47.7,46.23 47.7,46 48.18,45.52 51.07,45.52 52.17,46.63 JDIMM2.157
DDR_B_D0: length 85.1
  IN2 w0.076: 109.3,74.86 109.58,74.58 109.58,72.62 110.1,72.1 110.1,71.16 v2(109.6,70.66)
  IN2 w0.127: 109.3,74.86 107.91,76.25 107.91,77.4 106.81,78.5 106.81,79.33 105.79,80.35 105.79,85.95 101.78,89.96 82.78,89.96 82.46,89.64 64.69,89.64 63.99,90.34 60.63,90.34 55.37,85.08 55.37,84.83 52.1,81.56 48.53,81.56 48.11,81.14 47.07,81.14 v2(46.65,80.72)
  BOTTOM w0.076: UC1.AF65 109.86,70.29 v2(109.6,70.66)
  BOTTOM w0.102: v2(46.65,80.72) 46.5,80.87 JDIMM2.28
DDR_B_D1: length 83.9
  IN2 w0.076: v2(109.59,70.02) 109.09,70.53 109.09,72.64 107.98,73.75 107.98,74.91
  IN2 w0.127: 107.98,74.91 106.34,76.55 106.34,76.83 105.78,77.39 105.78,78.9 103.19,81.5 103.19,87.06 101.32,88.93 98.64,88.93 98.52,88.8 98.52,88.62 98.39,88.49 84.73,88.49 84.6,88.62 84.6,88.8 84.47,88.93 84.22,88.93 84.09,88.8 84.09,88.62 83.97,88.49 83.71,88.49 83.59,88.62 83.59,88.8 83.46,88.93 83.2,88.93 82.89,88.61 64.27,88.61 63.61,89.27 61.02,89.27 56.4,84.65 56.4,84.4 52.3,80.3 50.12,80.3 v2(49.7,80.72)
  BOTTOM w0.076: v2(109.59,70.02) 109.84,69.65 UC1.AF64
  BOTTOM w0.102: v2(49.7,80.72) 50.54,81.56 51.98,81.56 52.05,81.62 JDIMM2.25
DDR_B_D2: length 84.1
  IN2 w0.076: v2(107.81,69.96) 107.44,70.32 107.44,70.87 107.27,71.04 107.27,71.84 104.95,74.16 104.65,74.16 103.94,74.88
  IN2 w0.089: 103.94,74.88 103.94,74.88 103.94,74.92
  IN2 w0.127: v2(48.17,78.2) 48.94,77.44 52.79,77.44 54.95,79.59 55.22,79.59 57.06,81.43 57.06,81.72 59.56,84.22 65.6,84.22 65.91,84.54 72.22,84.54 72.98,85.3 79.14,85.3 79.27,85.17 79.27,84.54 79.4,84.41 79.65,84.41 79.78,84.54 79.78,85.17 79.91,85.3 80.16,85.3 80.29,85.17 80.29,84.54 80.41,84.41 80.67,84.41 80.8,84.54 80.8,85.17 80.92,85.3 81.18,85.3 81.3,85.17 81.3,84.54 81.43,84.41 81.68,84.41 81.81,84.54 81.81,85.17 81.94,85.3 82.19,85.3 82.32,85.17 82.32,84.54 82.45,84.41 82.7,84.41 82.83,84.54 82.83,85.17 82.95,85.3 83.21,85.3 83.34,85.17 83.34,84.54 83.46,84.41 83.72,84.41 83.84,84.54 83.84,85.17 83.97,85.3 84.22,85.3 84.35,85.17 84.35,84.49 84.48,84.36 84.73,84.36 84.86,84.49 84.86,84.57 84.99,84.7 93.49,84.7 97.8,80.4 100.55,80.4 103.27,77.68 103.27,76.79 103.82,76.23 103.82,75.37 103.94,75.25 103.94,74.92
  BOTTOM w0.076: UC1.AK65 108.11,70.26 v2(107.81,69.96)
  BOTTOM w0.102: v2(48.17,78.2) 47.34,77.36 45.76,77.36 45.74,77.38 JDIMM2.42
DDR_B_D3: length 84.6
  IN2 w0.076: 103.68,74.68 103.87,74.68 104.71,73.83 105.01,73.83 107.11,71.73 107.11,70.97 107.28,70.8 107.28,69.84 107.55,69.57 108.49,69.57 v2(108.65,69.4)
  IN2 w0.127: v2(46.65,78.2) 47.75,77.09 52.93,77.09 55.09,79.25 55.36,79.25 57.4,81.29 57.4,81.56 59.72,83.88 65.74,83.88 65.95,84.09 73.09,84.09 73.21,84.22 73.21,84.79 73.34,84.92 73.59,84.92 73.72,84.79 73.72,84.15 73.85,84.02 74.1,84.02 74.23,84.15 74.23,84.79 74.36,84.92 74.61,84.92 74.74,84.79 74.74,84.15 74.86,84.02 75.12,84.02 75.25,84.15 75.25,84.79 75.37,84.92 75.63,84.92 75.75,84.79 75.75,84.15 75.88,84.02 76.13,84.02 76.26,84.15 76.26,84.79 76.39,84.92 76.64,84.92 76.77,84.79 76.77,84.15 76.9,84.02 77.15,84.02 77.28,84.15 77.28,84.79 77.4,84.92 77.66,84.92 77.79,84.79 77.79,84.15 77.91,84.02 78.17,84.02 78.29,84.15 78.29,84.79 78.42,84.92 78.67,84.92 78.8,84.79 78.8,84.15 78.93,84.02 93.69,84.02 98.67,79.04 100.16,79.04 100.18,79.02 100.55,79.02 103.48,76.09 103.48,74.88 103.68,74.68
  BOTTOM w0.076: UC1.AK64 108.44,69.61 v2(108.65,69.4)
  BOTTOM w0.102: v2(46.65,78.2) 46.63,78.2 46.46,78.38 JDIMM2.38
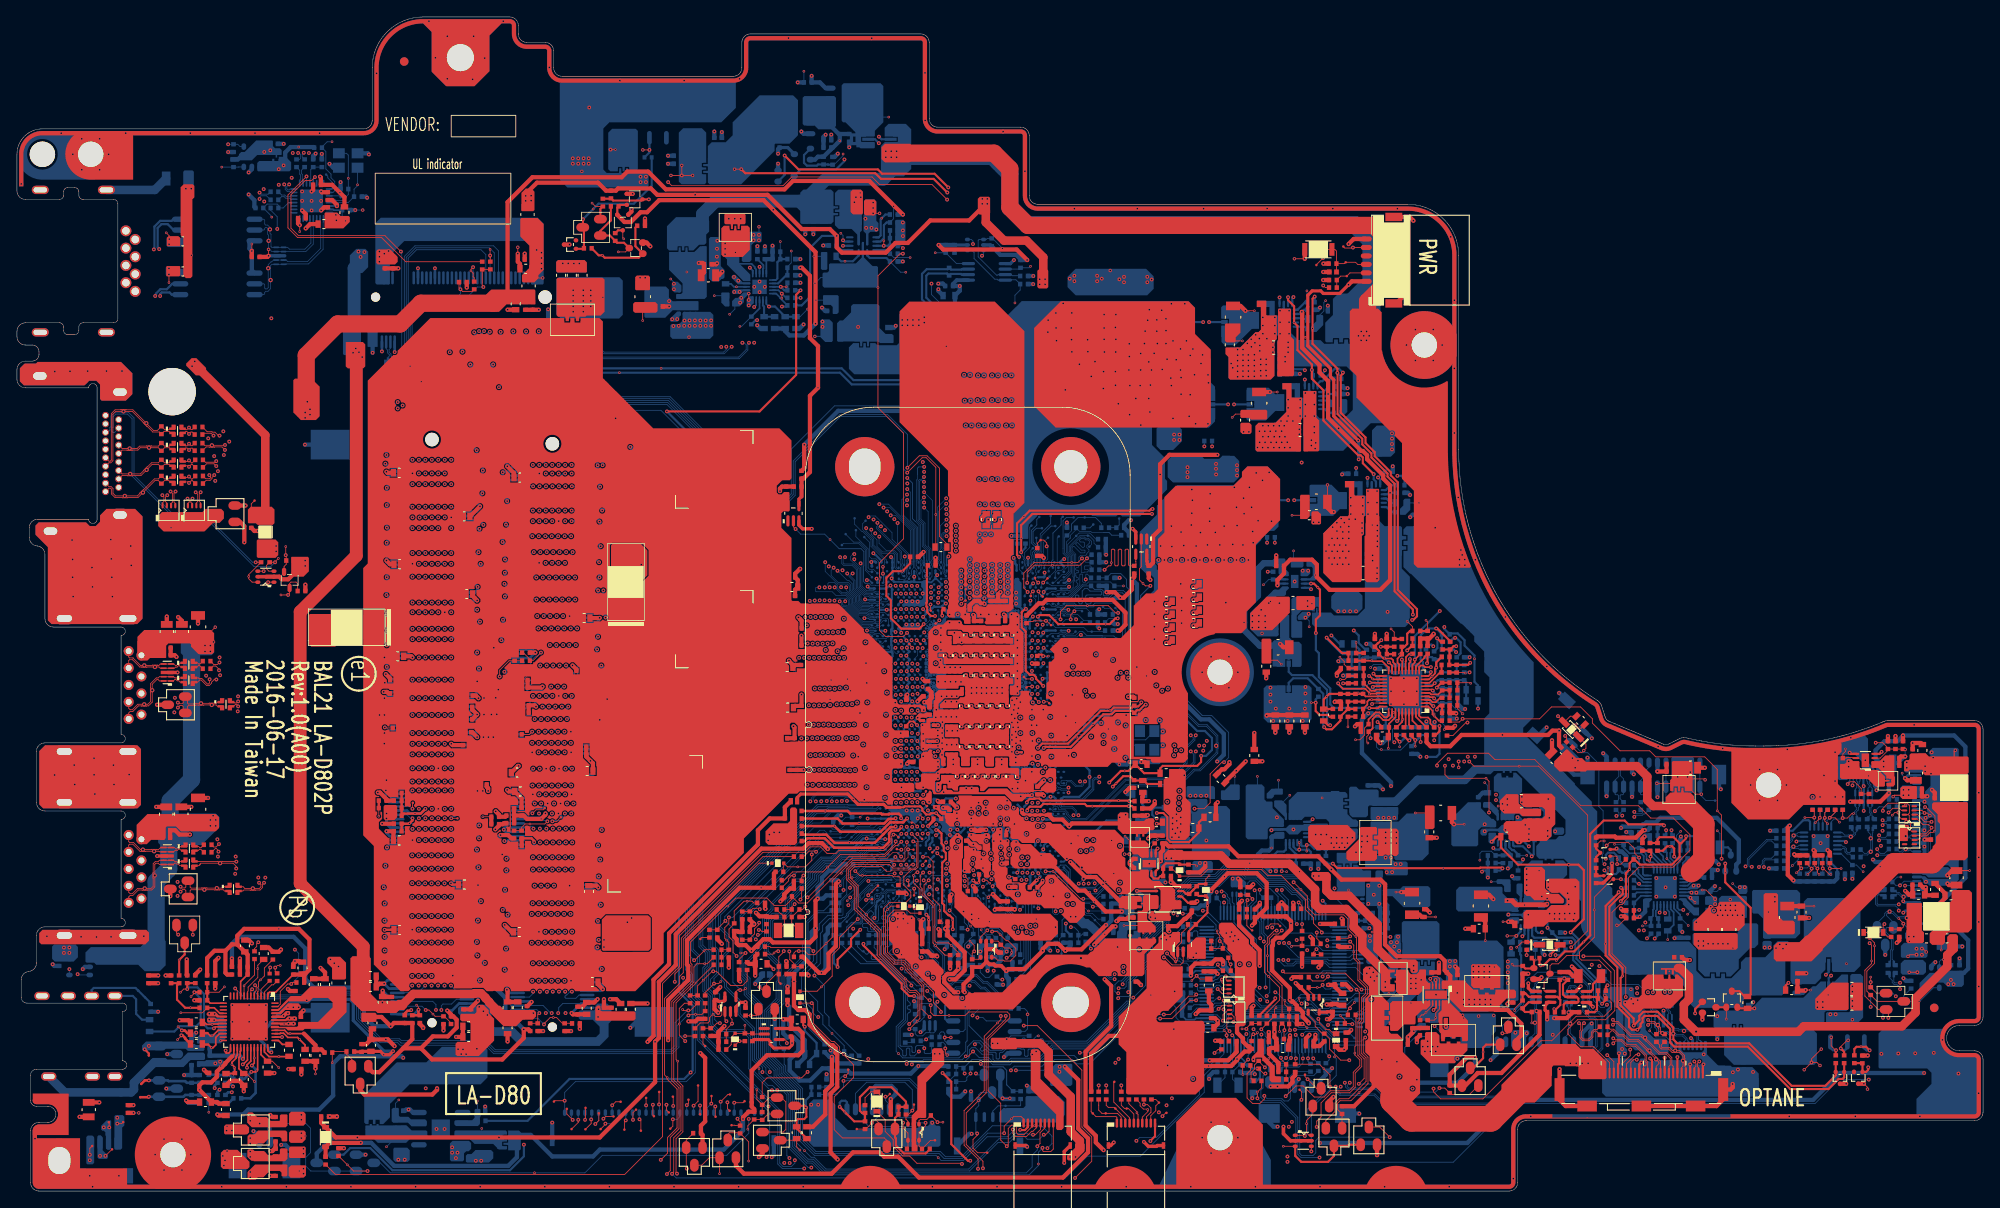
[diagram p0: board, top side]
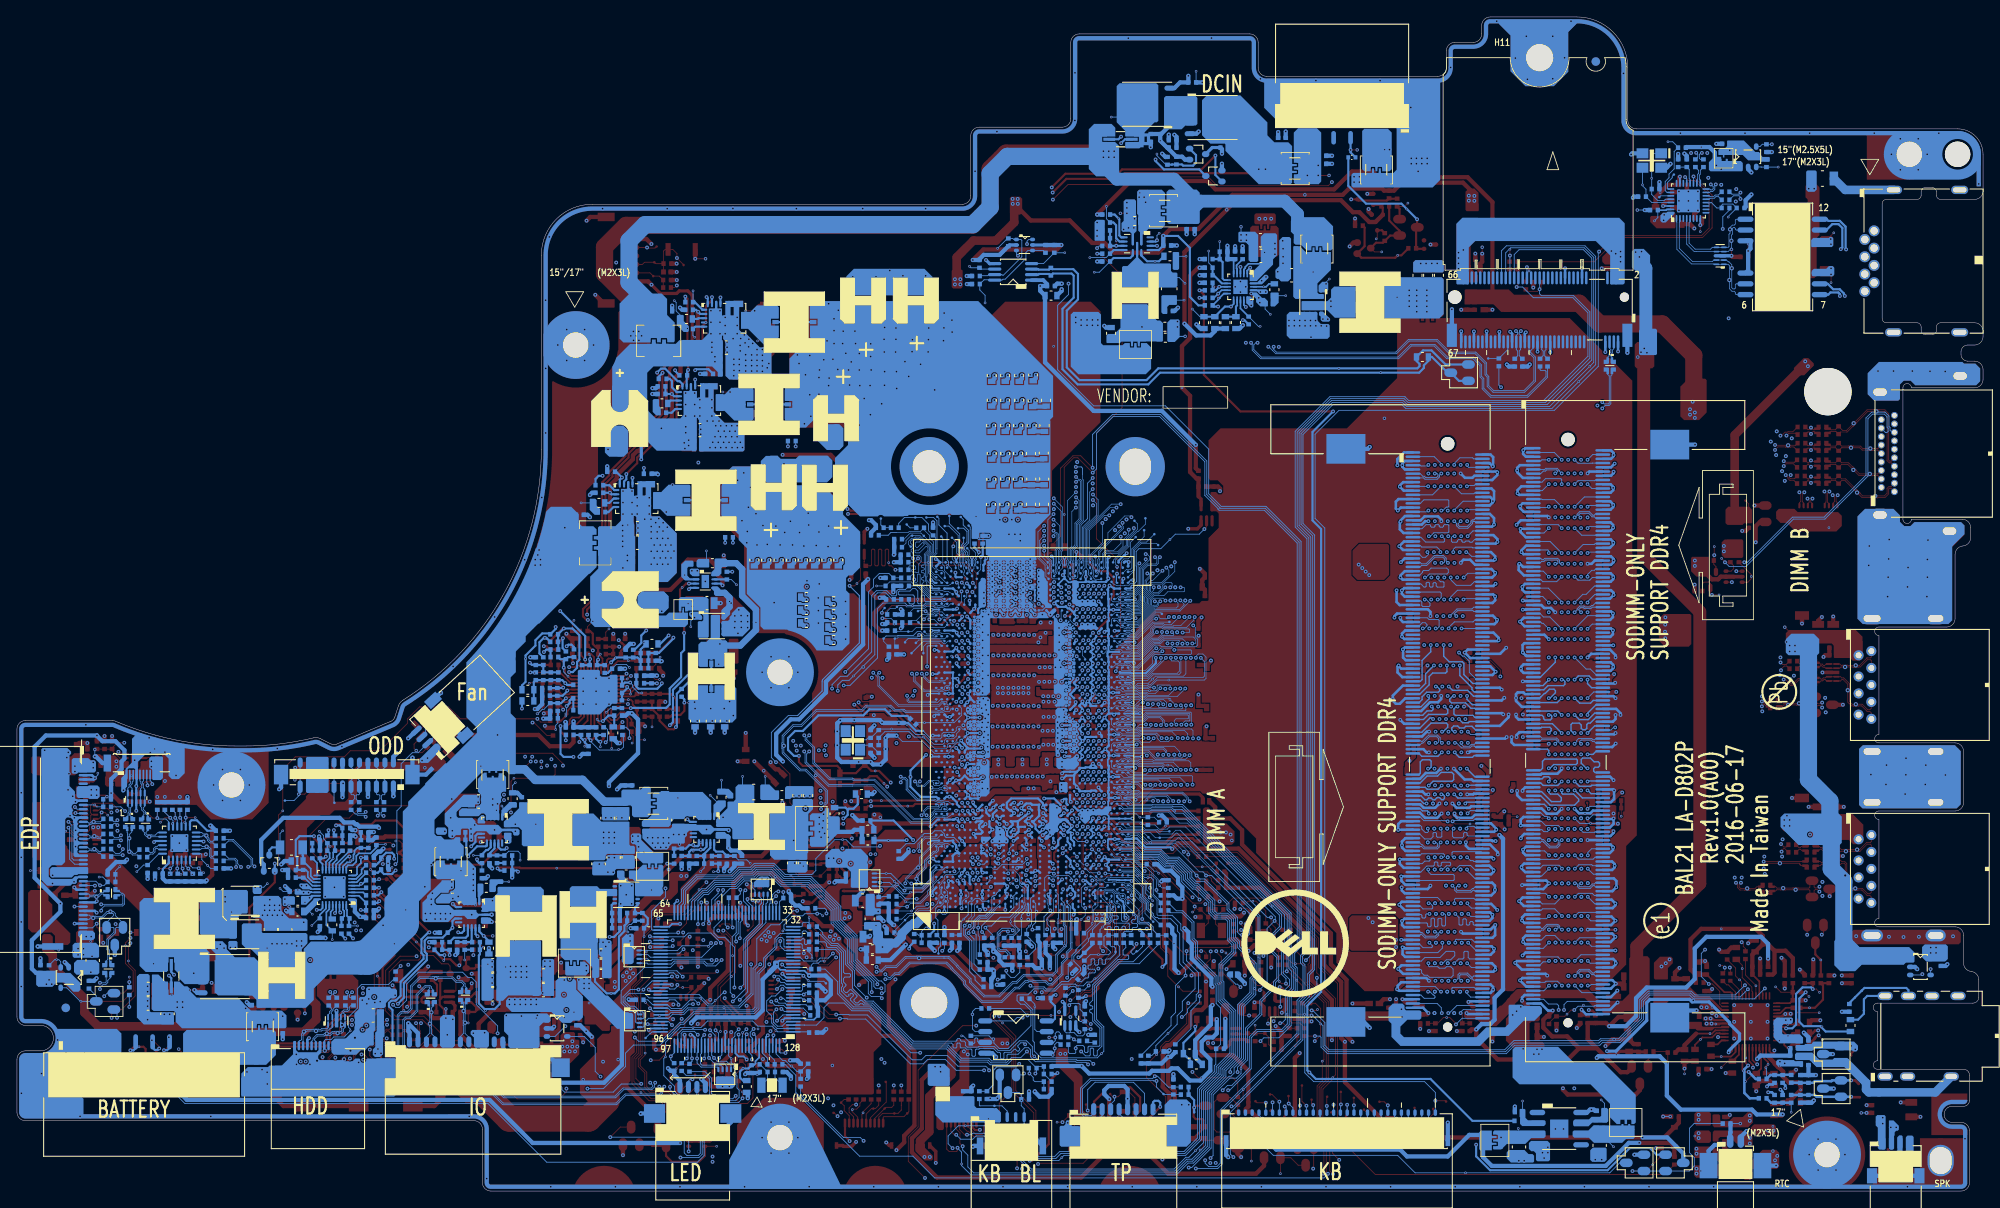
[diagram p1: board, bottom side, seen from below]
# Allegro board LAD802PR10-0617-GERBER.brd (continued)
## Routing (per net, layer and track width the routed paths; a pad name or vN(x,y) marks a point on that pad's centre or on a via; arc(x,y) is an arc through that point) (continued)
DDR_B_D4: length 84.2
  IN2 w0.076: v2(109.59,71.26) 109.93,71.6 109.93,72.04 109.42,72.55 109.42,74.39 108.45,75.36 108.45,75.41
  IN2 w0.127: v2(48.17,80.72) 48.65,81.2 52.23,81.2 55.71,84.68 55.71,84.94 60.76,89.98 63.87,89.98 64.55,89.3 82.6,89.3 82.92,89.62 101.63,89.62 105.44,85.81 105.44,80.21 106.47,79.19 106.47,77.68 107.03,77.11 107.03,76.83 108.45,75.41
  BOTTOM w0.076: UC1.AF66 110.01,70.94 109.69,71.26 v2(109.59,71.26)
  BOTTOM w0.102: v2(48.17,80.72) 47.02,81.87 JDIMM2.24
DDR_B_D5: length 83.5
  IN2 w0.076: 108.28,75.27 108.3,75.27 109.25,74.32 109.25,72.15 v2(109.56,71.84)
  IN2 w0.127: v2(51.22,80.72) 51.34,80.84 52.36,80.84 56.06,84.54 56.06,84.79 60.89,89.63 63.74,89.63 64.41,88.96 82.75,88.96 83.06,89.27 84.95,89.27 85.08,89.15 85.08,88.96 85.21,88.84 85.46,88.84 85.59,88.96 85.59,89.15 85.71,89.27 85.97,89.27 86.09,89.15 86.09,88.96 86.22,88.84 86.48,88.84 86.6,88.96 86.6,89.15 86.73,89.27 86.98,89.27 87.11,89.15 87.11,88.96 87.24,88.84 87.49,88.84 87.62,88.96 87.62,89.15 87.75,89.27 88,89.27 88.13,89.15 88.13,88.96 88.25,88.84 88.51,88.84 88.63,88.96 88.63,89.15 88.76,89.27 89.02,89.27 89.14,89.15 89.14,88.96 89.27,88.84 89.52,88.84 89.65,88.96 89.65,89.15 89.78,89.27 90.03,89.27 90.16,89.15 90.16,88.96 90.29,88.84 90.54,88.84 90.67,88.96 90.67,89.15 90.79,89.27 91.05,89.27 91.17,89.15 91.17,88.96 91.3,88.84 91.56,88.84 91.68,88.96 91.68,89.15 91.81,89.27 92.06,89.27 92.19,89.15 92.19,88.96 92.32,88.84 92.57,88.84 92.7,88.96 92.7,89.15 92.83,89.27 93.08,89.27 93.21,89.15 93.21,88.96 93.33,88.84 93.59,88.84 93.71,88.96 93.71,89.15 93.84,89.27 94.1,89.27 94.22,89.15 94.22,88.96 94.35,88.84 94.6,88.84 94.73,88.96 94.73,89.15 94.86,89.27 101.46,89.27 104.1,86.64 104.1,81.07 106.12,79.05 106.12,77.54 106.69,76.97 106.69,76.87 108.28,75.27
  BOTTOM w0.076: v2(109.56,71.84) 109.73,71.84 UC1.AF67
  BOTTOM w0.102: v2(51.22,80.72) 51.32,80.62 JDIMM2.29
DDR_B_D6: length 82
  IN2 w0.076: v2(107.81,71.26) 107.81,71.77 107.26,72.32 107.26,73.4 105.8,74.86 105.34,74.86 105.28,74.92
  IN2 w0.127: 105.28,74.92 104.55,75.65 104.55,76.47 103.95,77.07 103.95,77.96 100.83,81.09 98.28,81.09 93.38,85.98 86.23,85.98 86.1,86.11 86.1,86.85 85.98,86.97 85.72,86.97 85.6,86.85 85.6,86.11 85.47,85.98 85.21,85.98 85.09,86.11 85.09,86.85 84.96,86.97 84.71,86.97 84.58,86.85 84.58,86.11 84.45,85.98 84.2,85.98 84.07,86.11 84.07,86.85 83.94,86.97 83.69,86.97 83.56,86.85 83.56,86.11 83.44,85.98 83.18,85.98 83.06,86.11 83.06,86.85 82.93,86.97 82.67,86.97 82.55,86.85 82.55,86.11 82.42,85.98 82.17,85.98 82.04,86.11 82.04,86.85 81.91,86.97 81.66,86.97 81.53,86.85 81.53,86.11 81.4,85.98 81.15,85.98 81.02,86.11 81.02,86.85 80.9,86.97 80.64,86.97 80.52,86.85 80.52,86.11 80.39,85.98 80.13,85.98 80.01,86.11 80.01,86.85 79.88,86.97 73.68,86.97 72.79,86.09 72.79,86.08 60.43,86.08 59.53,85.18 59.53,85.17 56.32,81.96 56.32,81.67 54.93,80.28 54.66,80.28 52.51,78.13 51.29,78.13 v2(51.22,78.2)
  BOTTOM w0.076: v2(107.81,71.26) 108.11,71.56 UC1.AK67
  BOTTOM w0.102: JDIMM2.41 51.79,77.62 v2(51.22,78.2)
DDR_B_D7: length 83.1
  IN2 w0.076: v2(107.81,70.6) 107.81,70.74 107.44,71.11 107.44,71.9 104.86,74.49 104.56,74.49 104.3,74.75 104.3,74.9
  IN2 w0.127: 104.3,74.9 104.3,74.96 104.3,75.4 104.21,75.49 104.21,76.33 103.61,76.93 103.61,77.82 100.69,80.74 97.94,80.74 93.04,85.64 79.66,85.64 79.54,85.77 79.54,86.06 79.41,86.19 79.15,86.19 79.03,86.06 79.03,85.77 78.9,85.64 78.65,85.64 78.52,85.77 78.52,86.51 78.39,86.63 78.14,86.63 78.01,86.51 78.01,85.77 77.88,85.64 77.63,85.64 77.5,85.77 77.5,86.51 77.38,86.63 77.12,86.63 77,86.51 77,85.77 76.87,85.64 76.61,85.64 76.49,85.77 76.49,86.51 76.36,86.63 76.11,86.63 75.98,86.51 75.98,85.77 75.85,85.64 75.6,85.64 75.47,85.77 75.47,86.51 75.34,86.63 75.09,86.63 74.96,86.51 74.96,85.77 74.84,85.64 74.58,85.64 74.46,85.77 74.46,86.51 74.33,86.63 74.07,86.63 73.95,86.51 73.95,85.77 73.82,85.64 72.84,85.64 72.28,85.08 59.93,85.08 56.71,81.86 56.71,81.58 55.07,79.94 54.8,79.94 52.65,77.78 50.12,77.78 v2(49.7,78.2)
  BOTTOM w0.076: v2(107.81,70.6) 108.18,70.86 UC1.AK66
  BOTTOM w0.102: JDIMM2.37 52.14,78.62 52.12,78.6 50.1,78.6 v2(49.7,78.2)
DDR_B_D8: length 87.8
  IN2 w0.076: v2(110.74,77.31) 111.95,78.52 111.95,79.93
  IN2 w0.127: v2(48.17,86.26) 48.59,85.84 51.4,85.84 51.64,86.09 51.64,87.17 58.38,93.91 79.46,93.91 79.86,93.52 103.59,93.52 111.75,85.35 111.75,84.03 111.94,83.85 111.94,79.94 111.95,79.93
  BOTTOM w0.076: v2(110.74,77.31) 111.31,76.73 111.31,74.72 110.32,73.73 UC1.AF70
  BOTTOM w0.102: JDIMM2.8 46.07,85.88 46.09,85.85 47.77,85.85 v2(48.17,86.26)
DDR_B_D9: length 88.8
  IN2 w0.076: v2(110.74,78.49) 111.59,79.34 111.59,80.25
  IN2 w0.127: 111.59,80.25 111.59,83.71 111.41,83.89 111.41,85.17 103.4,93.18 79.71,93.18 79.32,93.57 58.53,93.57 51.98,87.03 51.98,85.94 51.54,85.5 47.41,85.5 v2(46.65,86.26)
  BOTTOM w0.076: UC1.AF68 110.54,72.53 110.54,73.27 110.64,73.36 110.64,73.81 111.47,74.65 111.47,77.76 v2(110.74,78.49)
  BOTTOM w0.102: v2(46.65,86.26) 46.03,86.88 JDIMM2.4
DDR_B_D10: length 86.6
  IN2 w0.127: v2(51.22,83.39) 51.25,83.36 51.55,83.36 53.5,85.31 53.5,85.6 53.74,85.84 53.74,86.02 53.52,86.24 53.52,86.42 53.7,86.6 53.88,86.6 54.1,86.38 54.28,86.38 57.55,89.65 57.55,89.83 57.33,90.04 57.33,90.22 57.51,90.4 57.69,90.4 57.91,90.18 58.09,90.18 58.27,90.36 58.27,90.54 58.05,90.76 58.05,90.94 58.23,91.12 58.41,91.12 58.62,90.9 58.8,90.9 58.98,91.08 58.98,91.26 58.77,91.48 58.77,91.66 58.95,91.84 59.12,91.84 59.34,91.62 59.52,91.62 59.95,92.05 64.64,92.05 65.03,91.66 71.97,91.66 72.1,91.78 72.1,91.92 72.22,92.05 72.48,92.05 72.61,91.92 72.61,91.78 72.73,91.66 72.99,91.66 73.11,91.78 73.11,91.92 73.24,92.05 73.49,92.05 73.62,91.92 73.62,91.78 73.75,91.66 76.13,91.66 76.48,91.31 77.14,91.31 77.27,91.43 77.27,91.92 77.4,92.05 77.65,92.05 77.78,91.92 77.78,91.43 77.91,91.31 78.16,91.31 78.29,91.43 78.29,91.92 78.41,92.05 78.67,92.05 78.8,91.92 78.8,91.43 78.92,91.31 79.18,91.31 79.3,91.43 79.3,91.53 79.43,91.66 79.68,91.66 79.81,91.53 79.81,91.43 79.94,91.31 80.19,91.31 80.32,91.43 80.32,91.53 80.45,91.66 80.7,91.66 80.83,91.53 80.83,91.43 80.95,91.31 81.21,91.31 81.34,91.43 81.34,91.53 81.46,91.66 102.77,91.66 109.85,84.58 109.85,83.23 110.07,83.01 110.07,79.64 v2(109.64,79.2)
  BOTTOM w0.076: v2(109.64,79.2) 108.9,78.46 108.9,75.7 109.05,75.55 109.05,74.21 UC1.AH71
  BOTTOM w0.102: v2(51.22,83.39) 51.99,82.62 JDIMM2.21
DDR_B_D11: length 89.4
  IN2 w0.127: v2(109.64,79.85) 107.18,79.85 106.42,80.62 106.42,86.21 102.04,90.59 82.51,90.59 82.2,90.28 64.96,90.28 64.26,90.98 60.33,90.98 54.53,85.17 54.53,84.89 51.84,82.2 48.26,82.2 47.84,81.78 45.84,81.78 45.71,81.9 45.71,83.26 45.84,83.39 v2(46.65,83.39)
  BOTTOM w0.076: UC1.AH68 109.68,72.21 109.88,72.41 109.88,72.66 109.89,72.67 109.89,72.93 109.9,72.95 109.9,73 109.92,73.02 109.92,73.28 109.88,73.41 109.88,73.63 109.89,73.65 109.89,73.65 109.89,73.65 109.92,73.74 109.92,73.94 109.89,74.03 109.89,74.03 109.89,74.37 110.31,74.79 110.31,79.19 v2(109.64,79.85)
  BOTTOM w0.102: v2(46.65,83.39) 46.14,82.87 JDIMM2.20
DDR_B_D12: length 86.3
  IN2 w0.127: v2(110.73,76.72) 111.17,76.28 111.17,76.06 111.34,75.9 111.83,75.9 112.41,76.48 112.41,83.86 112.1,84.17 112.1,85.49 103.73,93.86 82.17,93.86 81.78,94.26 81.52,94.26 81.4,94.13 81.4,93.99 81.27,93.86 81.02,93.86 80.89,93.99 80.89,94.13 80.76,94.26 80.51,94.26 80.38,94.13 80.38,93.99 80.25,93.86 80,93.86 79.87,93.99 79.87,94.13 79.75,94.26 58.24,94.26 50.78,86.79 50.78,86.53 51.05,86.26 v2(51.22,86.26)
  BOTTOM w0.076: UC1.AF71 111.14,74.99 111.14,76.31 v2(110.73,76.72)
  BOTTOM w0.102: JDIMM2.7 52.17,86.13 52.03,86.26 v2(51.22,86.26)
DDR_B_D13: length 88.4
  IN2 w0.127: v2(110.74,75.54) 111.96,75.54 112.75,76.33 112.75,84 112.44,84.32 112.44,85.66 111.54,86.56 111.51,86.56 103.87,94.21 82.31,94.21 81.92,94.6 58.1,94.6 49.76,86.26 v2(49.7,86.26)
  BOTTOM w0.076: v2(110.74,75.54) 110.74,74.99 110.05,74.3 110.05,74.06 110.09,73.97 110.09,73.96 110.09,73.71 110.05,73.62 110.05,73.41 110.08,73.33 110.09,73.33 110.12,73.23 110.12,72.96 UC1.AF69
  BOTTOM w0.102: v2(49.7,86.26) 50.56,87.13 JDIMM2.3
DDR_B_D14: length 87.6
  IN2 w0.127: v2(48.17,83.39) 48,83.39 47.59,82.97 46.82,82.97 46.69,82.84 46.69,82.25 46.82,82.12 47.71,82.12 48.12,82.54 51.7,82.54 54.19,85.03 54.19,85.32 60.21,91.34 64.38,91.34 65.1,90.62 82.06,90.62 82.37,90.94 102.5,90.94 108.89,84.55 108.89,81.05 109.07,80.87 109.4,80.87 v2(109.61,81.08)
  BOTTOM w0.076: v2(109.61,81.08) 108.73,80.2 108.73,75.63 108.88,75.48 108.88,74.45 108.73,74.3 108.73,74.06 108.85,73.81 108.85,73.81 108.85,73.8 109,73.66 UC1.AH70
  BOTTOM w0.102: JDIMM2.16 45.71,83.87 45.79,83.8 47.77,83.8 v2(48.17,83.39)
DDR_B_D15: length 88.6
  IN2 w0.127: v2(109.61,81.71) 109.36,81.71 109.23,81.84 109.23,84.71 102.67,91.28 82.23,91.28 81.91,90.96 75.4,90.96 75.28,91.09 75.28,91.19 75.15,91.32 74.89,91.32 74.77,91.19 74.77,91.09 74.64,90.96 74.39,90.96 74.26,91.09 74.26,91.19 74.13,91.32 73.88,91.32 73.75,91.19 73.75,91.09 73.62,90.96 73.37,90.96 73.24,91.09 73.24,91.19 73.12,91.32 72.86,91.32 72.74,91.19 72.74,91.09 72.61,90.96 72.35,90.96 72.23,91.09 72.23,91.19 72.1,91.32 71.85,91.32 71.72,91.19 71.72,91.09 71.59,90.96 71.34,90.96 71.21,91.09 71.21,91.19 71.08,91.32 70.83,91.32 70.7,91.19 70.7,91.09 70.58,90.96 70.32,90.96 70.2,91.09 70.2,91.19 70.07,91.32 69.81,91.32 69.69,91.19 69.69,91.09 69.56,90.96 69.31,90.96 69.18,91.09 69.18,91.19 69.05,91.32 68.8,91.32 68.67,91.19 68.67,91.09 68.54,90.96 68.29,90.96 68.16,91.09 68.16,91.19 68.04,91.32 67.78,91.32 67.66,91.19 67.66,91.09 67.53,90.96 67.27,90.96 67.15,91.09 67.15,91.19 67.02,91.32 66.77,91.32 66.64,91.19 66.64,91.09 66.51,90.96 66.26,90.96 66.13,91.09 66.13,91.19 66,91.32 65.75,91.32 65.62,91.19 65.62,91.09 65.5,90.96 65.24,90.96 64.51,91.69 60.08,91.69 53.85,85.46 53.85,85.17 51.56,82.88 49.47,82.88 49.34,83.01 49.34,83.26 49.47,83.39 v2(49.7,83.39)
  BOTTOM w0.076: UC1.AH69 109,73.07 108.6,73.46 108.6,73.95 108.56,74.02 108.56,74.37 108.72,74.52 108.72,75.39 108.57,75.54 108.57,80.67 v2(109.61,81.71)
  BOTTOM w0.102: JDIMM2.17 52.02,83.62 51.61,84.03 49.8,84.03 49.7,83.93 v2(49.7,83.39)
DDR_B_D16: length 69.1
  IN2 w0.076: v2(104.27,71.4) 104.27,72.08 101.96,74.39
  IN2 w0.127: 101.96,74.39 101.96,75.34 101.06,76.23 100.25,76.23 98.5,77.98 97.7,77.98 92.69,82.99 76.06,82.99 75.93,82.87 75.93,82.44 75.81,82.31 75.55,82.31 75.43,82.44 75.43,82.87 75.3,82.99 69.95,82.99 68.88,81.92 59.91,81.92 53.67,75.68 50.12,75.68 v2(49.7,75.26)
  BOTTOM w0.076: UC1.AT66 104.61,71.05 v2(104.27,71.4)
  BOTTOM w0.102: v2(49.7,75.26) 51.06,76.62 JDIMM2.45
DDR_B_D17: length 68.4
  IN2 w0.076: v2(103.64,71.4) 103.64,72.43 101.6,74.48
  IN2 w0.127: 101.6,74.48 101.6,75.21 100.93,75.87 100.12,75.87 98.38,77.62 97.55,77.62 93.2,81.97 75.08,81.97 74.96,82.1 74.96,82.44 74.83,82.57 74.58,82.57 74.45,82.44 74.45,82.06 74.32,81.93 74.07,81.93 73.94,82.06 73.94,82.47 73.81,82.6 73.56,82.6 73.43,82.47 73.43,82.06 73.31,81.93 73.05,81.93 72.92,82.06 72.92,82.47 72.8,82.6 72.54,82.6 72.42,82.47 72.42,82.06 72.29,81.93 72.04,81.93 71.91,82.06 71.91,82.47 71.78,82.6 71.53,82.6 71.4,82.47 71.4,82.06 71.27,81.93 71.02,81.93 70.89,82.06 70.89,82.47 70.77,82.6 70.51,82.6 70.38,82.47 70.38,82.06 70.26,81.93 69.38,81.93 69.02,81.58 60.05,81.58 53.78,75.3 51.26,75.3 v2(51.22,75.26)
  BOTTOM w0.076: UC1.AU66 103.96,71.08 v2(103.64,71.4)
  BOTTOM w0.102: JDIMM2.49 51.33,75.62 51.22,75.52 v2(51.22,75.26)
DDR_B_D18: length 71.8
  IN2 w0.076: 96.67,73.85 96.93,73.6 98.35,73.6 99.88,72.07 99.88,71.92 100.1,71.7 100.47,71.7 102.39,69.79 104,69.79 104.14,69.93 106.05,69.93 106.45,70.33 106.45,70.63 106.23,70.85 105.93,70.85 105.57,70.5 105.45,70.5 v2(105.44,70.49)
  IN2 w0.127: 96.67,73.85 93.61,76.92 92.41,76.92 90.45,78.88 82.44,78.88 81.94,79.39 70.79,79.39 69.07,77.67 60.42,77.67 57.88,75.12 57.6,75.12 56.17,73.7 56.17,73.41 54.81,72.05 48.59,72.05 v2(48.17,72.47)
  BOTTOM w0.076: v2(105.44,70.49) 105.45,70.49 105.45,70.41 105.83,70.03 UC1.AP65
  BOTTOM w0.102: v2(48.17,72.47) 47.77,72.06 46.39,72.06 46.07,72.38 JDIMM2.62
DDR_B_D19: length 72.2
  IN2 w0.076: v2(106.08,70.48) 106.08,70.19 105.98,70.09 104.08,70.09 103.94,69.95 102.46,69.95 100.62,71.79 100.62,72.23 100.17,72.68 99.5,72.68 98.42,73.76 97.24,73.76 97.16,73.84 97.16,73.85
  IN2 w0.127: 97.16,73.85 97.19,73.89 97.19,74.08 93.97,77.3 93.23,77.3 91.3,79.22 88.52,79.22 88.39,79.35 88.39,79.58 88.26,79.71 88.01,79.71 87.88,79.58 87.88,79.35 87.75,79.22 87.5,79.22 87.37,79.35 87.37,79.58 87.25,79.71 86.99,79.71 86.86,79.58 86.86,79.35 86.74,79.22 86.48,79.22 86.36,79.35 86.36,79.58 86.23,79.71 85.98,79.71 85.85,79.58 85.85,79.35 85.72,79.22 85.47,79.22 85.34,79.35 85.34,79.58 85.21,79.71 84.96,79.71 84.83,79.58 84.83,79.35 84.71,79.22 82.59,79.22 82.08,79.73 70.65,79.73 68.97,78.05 68.79,78.05 68.66,78.17 68.66,78.46 68.53,78.59 68.28,78.59 68.15,78.46 68.15,78.14 68.03,78.01 67.77,78.01 67.64,78.14 67.64,78.63 67.52,78.76 67.33,78.76 67.2,78.63 67.2,78.2 67.01,78.01 66.76,78.01 66.63,78.14 66.63,78.62 66.5,78.75 66.25,78.75 66.12,78.62 66.12,78.14 65.99,78.01 60.28,78.01 57.74,75.47 57.45,75.47 55.82,73.84 55.82,73.55 54.92,72.64 54.44,72.64 54.19,72.39 53.93,72.39 53.68,72.64 53.42,72.64 53.17,72.39 52.92,72.39 52.67,72.64 52.41,72.64 52.16,72.39 51.9,72.39 51.65,72.64 51.4,72.64 v2(51.22,72.47)
  BOTTOM w0.076: v2(106.08,70.48) 106.53,70.03 UC1.AN65
  BOTTOM w0.102: v2(51.22,72.47) 51.88,73.13 JDIMM2.59
DDR_B_D20: length 71.1
  IN2 w0.076: v2(106.19,71.39) 103.45,74.12 103.21,74.12
  IN2 w0.127: 103.21,74.12 102.67,74.66 102.67,75.59 101.32,76.95 100.5,76.95 98.76,78.7 98.13,78.7 93.14,83.68 68.19,83.68 67.11,82.61 59.63,82.61 53.39,76.37 47.75,76.37 v2(46.65,75.26)
  BOTTOM w0.076: v2(106.19,71.39) 106.56,71.01 UC1.AN66
  BOTTOM w0.102: JDIMM2.50 46.54,75.38 v2(46.65,75.26)
DDR_B_D21: length 70.6
  IN2 w0.076: 102.6,74.28 102.64,74.28 105.54,71.38 v2(105.55,71.38)
  IN2 w0.127: 102.6,74.28 102.31,74.57 102.31,75.47 101.19,76.59 100.38,76.59 98.63,78.34 97.85,78.34 92.85,83.34 69.81,83.34 68.74,82.26 59.77,82.26 53.53,76.02 48.94,76.02 v2(48.17,75.26)
  BOTTOM w0.076: UC1.AP66 v2(105.55,71.38)
  BOTTOM w0.102: JDIMM2.46 45.75,76.38 45.87,76.26 47.17,76.26 v2(48.17,75.26)
DDR_B_D22: length 70.2
  IN2 w0.076: v2(104.27,70.49) 104.18,70.49 103.81,70.12 102.53,70.12 100.86,71.78 100.86,72.22 100.21,72.87 99.9,72.87 98.43,74.34 98.42,74.34
  IN2 w0.127: 98.42,74.34 98.29,74.47 98.29,74.75 97.53,75.51 97.03,75.51 94.83,77.7 93.84,78.69 92.58,78.69 91.57,79.71 88.75,79.71 88.39,80.07 84.49,80.07 84.36,79.94 84.36,79.69 84.24,79.57 83.98,79.57 83.85,79.69 83.85,79.94 83.73,80.07 83.47,80.07 83.35,79.94 83.35,79.69 83.22,79.57 82.97,79.57 82.84,79.69 82.84,79.94 82.71,80.07 70.15,80.07 69.59,79.51 68.03,79.51 67.9,79.38 67.9,79.23 67.77,79.1 67.52,79.1 67.39,79.23 67.39,79.38 67.27,79.51 67.01,79.51 66.86,79.36 66.86,79.22 66.74,79.09 66.5,79.09 66.38,79.22 66.38,79.38 66.25,79.51 66,79.51 65.84,79.36 65.84,78.82 65.62,78.6 60.39,78.6 57.6,75.81 57.31,75.81 55.48,73.98 55.48,73.69 54.77,72.98 49.61,72.98 49.49,72.86 49.49,72.68 v2(49.7,72.47)
  BOTTOM w0.076: v2(104.27,70.49) 104.61,70.14 UC1.AT65
  BOTTOM w0.102: JDIMM2.63 52.16,72.13 51.91,71.88 50.29,71.88 v2(49.7,72.47)
DDR_B_D23: length 69.6
  IN2 w0.076: v2(103.66,70.49) 102.94,70.49 102.32,71.1 102.32,71.84 100.45,73.71
  IN2 w0.089: 100.45,73.71 100.12,74.04 100.12,74.63 99.12,75.63 98.95,75.63 98.89,75.69
  IN2 w0.127: v2(46.65,72.47) 47.51,73.33 54.63,73.33 55.14,73.84 55.14,74.12 57.17,76.15 57.46,76.15 57.7,76.4 57.7,76.47 61.09,79.85 69.45,79.85 70.01,80.41 89.05,80.41 89.18,80.29 89.18,80.18 89.31,80.05 89.56,80.05 89.69,80.18 89.69,80.29 89.82,80.41 90.18,80.41 90.31,80.29 90.31,80.18 90.43,80.05 90.69,80.05 90.81,80.18 90.81,80.29 90.94,80.41 91.19,80.41 91.32,80.29 91.32,80.18 91.45,80.05 91.7,80.05 91.83,80.18 91.83,80.29 91.96,80.41 92.61,80.41 96.93,76.09 98.49,76.09 98.89,75.69
  BOTTOM w0.076: UC1.AU65 103.96,70.18 v2(103.66,70.49)
  BOTTOM w0.102: v2(46.65,72.47) 46.65,72.72 46.14,73.23 45.85,73.23 45.7,73.38 JDIMM2.58
DDR_B_D24: length 68.9
  IN2 w0.076: v2(104.27,68.66) 104.13,68.66 103.68,69.1 101.53,69.1 98.53,72.1 96.11,72.1 95.09,73.12
  IN2 w0.127: 95.09,73.12 93.26,74.95 92.76,74.95 89.97,77.74 75.91,77.74 75.79,77.86 75.79,78.12 75.66,78.24 75.41,78.24 75.28,78.12 75.28,77.86 75.15,77.74 74.9,77.74 74.77,77.86 74.77,78.08 74.64,78.21 74.39,78.21 74.26,78.08 74.26,77.86 74.14,77.74 73.88,77.74 73.76,77.86 73.76,78.08 73.63,78.21 73.37,78.21 73.25,78.08 73.25,77.86 73.12,77.74 72.87,77.74 72.74,77.86 72.74,78.08 72.61,78.21 72.36,78.21 72.23,78.08 72.23,77.86 72.1,77.74 71.85,77.74 71.66,77.93 71.48,77.93 70.03,76.48 68.68,76.48 68.24,76.04 60.68,76.04 57.96,73.32 57.96,72.76 57.72,72.52 57.43,72.52 56.83,71.91 56.83,71.62 56.13,70.93 55.95,70.93 55.72,71.16 55.54,71.16 55.36,70.98 55.36,70.8 55.59,70.57 55.59,70.39 55.41,70.21 55.23,70.21 55,70.44 54.82,70.44 54.64,70.26 54.64,70.08 54.87,69.85 54.87,69.67 54.45,69.25 53.42,69.25 53.3,69.38 53.3,69.46 53.17,69.58 52.91,69.58 52.79,69.46 52.79,69.38 52.66,69.25 52.41,69.25 52.28,69.38 52.28,69.46 52.15,69.58 51.9,69.58 51.77,69.46 51.77,69.38 51.64,69.25 51.39,69.25 v2(51.22,69.42)
  BOTTOM w0.076: v2(104.27,68.66) 104.61,68.31 UC1.AT61
  BOTTOM w0.102: v2(51.22,69.42) 51.93,70.13 JDIMM2.71
DDR_B_D25: length 68.7
  IN2 w0.076: v2(103.63,68.63) 103.33,68.94 101.46,68.94 98.46,71.93 95.92,71.93 94.19,73.66
  IN2 w0.127: 94.19,73.66 93.16,74.7 92.65,74.7 89.87,77.48 71.39,77.48 69.55,75.65 68.57,75.65 68.43,75.79 60.79,75.79 59.66,74.66 59.66,74.48 59.76,74.38 59.76,74.2 59.58,74.02 59.4,74.02 59.3,74.12 59.12,74.12 58.94,73.94 58.94,73.76 59.04,73.66 59.04,73.48 57.82,72.26 57.54,72.26 57.08,71.81 57.08,71.52 54.56,69 48.6,69 v2(48.17,69.42)
  BOTTOM w0.076: UC1.AU61 103.63,68.53 v2(103.63,68.63)
  BOTTOM w0.102: v2(48.17,69.42) 47.2,70.39 46.81,70.39 45.82,71.38 JDIMM2.66
DDR_B_D26: length 71.9
  IN2 w0.076: v2(105.54,67.74) 105.16,67.37 104.58,67.37 104.15,66.94 101.51,66.94 100.29,68.15 99.83,68.15 98.38,69.6 98.38,70.01 98.11,70.29
  IN2 w0.127: v2(49.7,66.32) 49.59,66.21 49.59,66.03 49.71,65.9 51.62,65.9 51.75,66.03 51.75,66.06 51.87,66.19 52.13,66.19 52.25,66.06 52.25,66.03 52.38,65.9 52.63,65.9 52.76,66.03 52.76,66.06 52.89,66.19 53.14,66.19 53.27,66.06 53.27,66.03 53.4,65.9 53.65,65.9 53.78,66.03 53.78,66.06 53.9,66.19 54.16,66.19 54.29,66.06 54.29,66.03 54.41,65.9 54.7,65.9 60.76,71.96 62.54,71.96 62.67,71.83 62.67,71.79 62.79,71.66 63.05,71.66 63.18,71.79 63.18,71.83 63.3,71.96 63.56,71.96 63.68,71.83 63.68,71.79 63.81,71.66 64.06,71.66 64.19,71.79 64.19,71.83 64.32,71.96 64.57,71.96 64.7,71.83 64.7,71.79 64.83,71.66 65.08,71.66 65.21,71.79 65.21,71.83 65.33,71.96 65.59,71.96 65.72,71.83 65.72,71.79 65.84,71.66 66.13,71.66 66.25,71.79 66.25,72.09 66.38,72.22 66.63,72.22 66.76,72.09 66.76,71.81 66.89,71.69 67.07,71.69 68.43,73.05 70.05,73.05 72.45,75.46 88.53,75.46 93.7,70.29 98.11,70.29
  BOTTOM w0.076: v2(105.54,67.74) 105.91,67.36 UC1.AP60
  BOTTOM w0.102: v2(49.7,66.32) 51.09,67.72 51.84,67.72 52.25,68.13 JDIMM2.79
DDR_B_D27: length 71.5
  IN2 w0.076: 98.06,70.07 98.22,69.91 98.22,69.46 99.73,67.94 100.11,67.94 101.29,66.77 104.25,66.77 104.67,67.2 105.62,67.2 v2(106.17,67.74)
  IN2 w0.127: v2(46.65,66.32) 46.65,65.77 46.78,65.65 54.81,65.65 60.56,71.41 60.87,71.41 60.99,71.53 60.99,71.58 61.12,71.71 61.37,71.71 61.5,71.58 61.5,71.53 61.63,71.41 61.88,71.41 62.01,71.53 62.01,71.58 62.14,71.71 62.39,71.71 62.52,71.58 62.52,71.53 62.64,71.41 67.15,71.41 68.54,72.8 70.15,72.8 72.56,75.2 88.43,75.2 93.56,70.07 98.06,70.07
  BOTTOM w0.076: v2(106.17,67.74) 106.56,67.35 UC1.AN60
  BOTTOM w0.102: v2(46.65,66.32) 46.1,66.87 JDIMM2.84
DDR_B_D28: length 71.3
  IN2 w0.076: v2(106.17,68.66) 105.64,69.19 104.06,69.19 103.82,69.43 101.67,69.43 98.67,72.43 96.49,72.43 95.39,73.53
  IN2 w0.127: v2(46.65,69.42) 47.32,70.09 53.75,70.09 60.21,76.55 68.03,76.55 68.47,76.99 69.5,76.99 71.26,78.75 80.66,78.75 80.79,78.62 80.79,78.37 80.91,78.24 81.17,78.24 81.29,78.37 81.29,78.62 81.42,78.75 81.68,78.75 81.8,78.62 81.8,78.37 81.93,78.24 90.18,78.24 92.97,75.46 93.47,75.46 94.91,74.02 94.91,74.01 95.39,73.53 95.39,73.53
  BOTTOM w0.076: v2(106.17,68.66) 106.56,68.26 UC1.AN61
  BOTTOM w0.102: JDIMM2.70 45.79,70.38 46.65,69.52 v2(46.65,69.42)
DDR_B_D29: length 70.7
  IN2 w0.076: 95.76,72.81 96.3,72.26 98.6,72.26 101.6,69.27 103.75,69.27 103.99,69.03 105.17,69.03 v2(105.54,68.66)
  IN2 w0.127: 95.76,72.81 94.66,73.91 94.66,73.91 93.37,75.2 92.87,75.2 90.08,77.99 79.36,77.99 79.23,78.12 79.23,78.37 79.11,78.5 78.85,78.5 78.73,78.37 78.73,78.12 78.6,77.99 78.34,77.99 78.22,78.12 78.22,78.37 78.09,78.5 77.84,78.5 77.71,78.37 77.71,78.12 77.58,77.99 77.33,77.99 77.2,78.12 77.2,78.37 77.07,78.5 76.82,78.5 76.69,78.37 76.69,78.12 76.57,77.99 76.31,77.99 76.19,78.12 76.19,78.37 76.06,78.5 71.51,78.5 69.76,76.74 68.58,76.74 68.14,76.3 60.31,76.3 53.86,69.84 50.12,69.84 v2(49.7,69.42)
  BOTTOM w0.076: UC1.AP61 105.91,68.28 v2(105.54,68.66)
  BOTTOM w0.102: v2(49.7,69.42) 49.7,69.55 51.28,71.13 JDIMM2.67
DDR_B_D30: length 71.2
  IN2 w0.076: 98.36,70.5 98.49,70.38 98.49,70.2 98.55,70.14 98.55,69.67 99.81,68.41 100.35,68.41 101.42,67.34 103.96,67.34 v2(104.28,67.66)
  IN2 w0.127: 98.36,70.5 93.84,70.5 88.64,75.71 72.35,75.71 70.06,73.43 67.81,73.43 67.69,73.3 67.69,72.66 67.56,72.54 67.33,72.54 67.2,72.66 67.2,73.28 67.05,73.43 66.8,73.43 66.63,73.26 66.63,72.64 66.5,72.51 66.29,72.51 66.16,72.64 66.16,73.3 66.04,73.43 65.78,73.43 65.65,73.3 65.65,72.87 65.53,72.75 65.27,72.75 65.15,72.87 65.15,73.3 65.02,73.43 64.77,73.43 64.64,73.3 64.64,72.93 64.51,72.8 64.26,72.8 64.13,72.93 64.13,73.3 64,73.43 63.75,73.43 63.62,73.3 63.62,72.92 63.5,72.8 63.24,72.8 63.11,72.92 63.11,73.3 62.99,73.43 62.73,73.43 62.61,73.3 62.61,72.87 62.48,72.75 62.23,72.75 62.1,72.87 62.1,73.3 61.97,73.43 61.5,73.43 59.99,71.92 59.99,71.59 54.9,66.49 54.34,66.49 54.11,66.72 51.35,66.72 51.22,66.59 v2(51.22,66.32)
  BOTTOM w0.076: v2(104.28,67.66) 104.61,67.32 UC1.AT60
  BOTTOM w0.102: v2(51.22,66.32) 51.87,66.97 52.03,66.97 52.18,67.13 JDIMM2.83
DDR_B_D31: length 70.3
  IN2 w0.076: v2(103.63,67.7) 101.5,67.7 100.54,68.66 99.79,68.66 98.8,69.65 98.8,70.12 98.65,70.27 98.65,70.52 98.35,70.82
  IN2 w0.127: 98.35,70.82 93.89,70.82 89.53,75.18 89.53,75.36 89.6,75.42 89.6,75.6 89.42,75.78 89.24,75.78 89.17,75.72 88.99,75.72 88.74,75.96 72.22,75.96 70.09,73.84 69.8,73.84 69.57,74.07 69.31,74.07 69.19,73.94 69.19,73.81 69.06,73.68 67.85,73.68 67.73,73.81 67.73,73.94 67.6,74.07 67.34,74.07 67.22,73.94 67.22,73.81 67.09,73.68 66.84,73.68 66.71,73.81 66.71,73.94 66.58,74.07 66.33,74.07 66.2,73.94 66.2,73.81 66.07,73.68 65.82,73.68 65.69,73.81 65.69,73.94 65.57,74.07 65.31,74.07 65.19,73.94 65.19,73.81 65.06,73.68 61.39,73.68 59.74,72.03 59.74,71.69 54.79,66.75 54.44,66.75 54.22,66.97 48.83,66.97 v2(48.17,66.32)
  BOTTOM w0.076: v2(103.63,67.7) 103.63,67.68 103.96,67.35 UC1.AU60
  BOTTOM w0.102: JDIMM2.80 45.63,67.87 45.63,67.87 46.62,67.87 v2(48.17,66.32)
DDR_B_D32: length 70
  IN2 w0.076: v2(103.62,56.76) 103.62,56.76 103.54,56.84 102.4,56.84 101.51,55.96 101.51,55.48 100.35,54.31 92.1,54.31 91.85,54.06 91.51,54.06
  IN2 w0.127: 91.51,54.06 90.11,54.06 88.87,52.83 78.89,52.83 75,48.94 74.35,48.94 67.72,42.31 67.72,41.58 66.02,39.88 60.27,39.88 59.53,40.61 59.35,40.61 58.91,40.17 58.73,40.17 58.55,40.35 58.55,40.53 59,40.97 59,41.15 58.8,41.35 58.62,41.35 58,40.74 57.82,40.74 57.69,40.87 57.11,40.87 56.46,41.52 56.46,41.7 56.51,41.75 56.51,41.99 56.38,42.11 56.15,42.11 56.1,42.06 55.92,42.06 55.27,42.71 54.36,42.71 53.92,43.15 50.12,43.15 v2(49.7,42.72)
  BOTTOM w0.076: v2(103.62,56.76) 103.62,56.55 103.85,56.31 UC1.AU40
  BOTTOM w0.102: v2(49.7,42.72) 50.1,43.13 51.61,43.13 52.1,43.63 JDIMM2.169
DDR_B_D33: length 70.9
  IN2 w0.076: v2(104.29,56.67) 104.05,56.67 103.77,56.39 103.46,56.39 103.3,56.55 102.34,56.55 101.68,55.89 101.68,55.41 100.33,54.06 92.22,54.06 91.89,53.72 91.39,53.72
  IN2 w0.127: 91.39,53.72 90.25,53.72 89.02,52.49 79.03,52.49 75,48.45 74.82,48.45 74.67,48.6 74.49,48.6 74.31,48.42 74.31,48.24 74.48,48.07 74.48,47.89 74.3,47.71 74.12,47.71 73.95,47.88 73.77,47.88 73.54,47.64 73.54,47.4 73.65,47.29 73.65,47.05 73.52,46.93 73.29,46.93 73.18,47.04 73,47.04 72.82,46.86 72.82,46.68 72.93,46.57 72.93,46.33 72.78,46.18 72.6,46.18 72.46,46.32 72.28,46.32 69.4,43.44 69.4,42.43 69.12,42.14 68.31,42.14 68.06,41.9 68.06,41.44 65.85,39.23 65.85,39.2 65.49,38.84 60.25,38.84 60.01,39.08 60.01,39.65 59.88,39.78 59.63,39.78 59.5,39.65 59.5,39.08 59.38,38.95 59.12,38.95 58.95,39.13 58.95,39.47 58.03,40.39 57.68,40.39 57.55,40.53 56.97,40.53 55.13,42.37 53.74,42.37 53.61,42.5 53.61,42.68 53.48,42.81 53.23,42.81 53.1,42.68 53.1,42.5 52.97,42.37 52.72,42.37 52.59,42.5 52.59,42.68 52.47,42.81 52.21,42.81 52.09,42.68 52.09,42.5 51.96,42.37 51.35,42.37 51.22,42.5 v2(51.22,42.72)
  BOTTOM w0.076: v2(104.29,56.67) 104.61,56.34 UC1.AT40
  BOTTOM w0.102: JDIMM2.173 52.04,42.63 51.81,42.39 51.37,42.39 51.22,42.55 v2(51.22,42.72)
DDR_B_D34: length 71.5
  IN2 w0.076: 99.63,52.25 99.91,52.25 101.54,53.88 101.54,53.9 102.18,54.54 102.77,54.54 102.86,54.45 103.65,54.45 103.92,54.72 104.03,54.72 v2(104.26,54.95)
  IN2 w0.127: 99.63,52.25 92.3,52.25 91.99,51.94 91.63,51.94 89.97,50.28 80.79,50.28 80.42,50.28 75.7,45.56 75.7,45.24 75.52,45.06 75.3,45.06 75.16,45.2 74.98,45.2 74.8,45.02 74.8,44.84 75.17,44.47 75.17,44.29 74.99,44.11 74.81,44.11 74.44,44.48 74.26,44.48 74.08,44.3 74.08,44.12 74.45,43.75 74.45,43.57 74.27,43.39 74.1,43.39 73.73,43.76 73.55,43.76 73.37,43.58 73.37,43.4 73.74,43.03 73.74,42.85 69.1,38.22 68.16,38.22 65.55,35.61 64.65,35.61 64.53,35.73 64.53,36.16 64.4,36.29 64.15,36.29 64.02,36.16 64.02,35.8 63.83,35.61 60.77,35.61 60.64,35.73 60.64,36.09 60.45,36.28 60.14,36.28 60.02,36.15 60.02,35.73 59.89,35.61 59.64,35.61 59.51,35.73 59.51,36.15 59.38,36.28 58.39,36.28 58.03,36.64 57.74,36.64 54.87,39.52 51.28,39.52 v2(51.19,39.6)
  BOTTOM w0.076: UC1.AT37 v2(104.26,54.95)
  BOTTOM w0.102: v2(51.19,39.6) 51.71,40.12 JDIMM2.183
DDR_B_D35: length 70.8
  IN2 w0.076: v2(103.6,54.92) 103.39,54.71 102.08,54.71 100.63,53.26 99.88,53.26 99.17,52.55 97.87,52.55
  IN2 w0.127: 97.87,52.55 97.86,52.55 92.29,52.55 91.9,52.15 91.36,52.15 89.83,50.63 80.1,50.63 75.02,45.54 74.84,45.54 74.84,45.54 74.81,45.54 72.78,43.5 72.78,43.33 73.16,42.94 73.16,42.76 72.98,42.58 72.8,42.58 72.45,42.93 72.27,42.93 72.09,42.75 72.09,42.57 72.44,42.22 72.44,42.04 70.88,40.48 70.7,40.48 70.58,40.6 70.4,40.6 70.22,40.42 70.22,40.23 70.33,40.12 70.33,39.94 70.15,39.76 69.97,39.76 69.85,39.88 69.67,39.88 69.49,39.7 69.49,39.52 69.61,39.4 69.61,39.22 68.96,38.56 68.02,38.56 66.08,36.63 58.52,36.63 58.17,36.98 57.89,36.98 55.01,39.86 51.53,39.86 51.33,40.05 49.82,40.05 49.67,39.89 v2(49.67,39.6)
  BOTTOM w0.076: v2(103.6,54.92) 103.71,54.92 103.96,54.67 UC1.AU37
  BOTTOM w0.102: v2(49.67,39.6) 50.14,39.12 JDIMM2.187
DDR_B_D36: length 71.4
  IN2 w0.076: 99.22,54.57 99.99,55.35 100.67,55.35 102.45,57.13 105.13,57.13 v2(105.56,56.7)
  IN2 w0.127: v2(48.17,43.97) 47.99,43.97 47.86,43.84 47.86,43.66 47.99,43.54 48.17,43.54 48.18,43.55 57.08,43.55 60.42,40.22 65.87,40.22 67.38,41.72 67.38,42.45 74.21,49.28 74.86,49.28 78.75,53.18 84.74,53.18 84.85,53.29 88.85,53.29 89.96,54.41 91.73,54.41 91.9,54.57 99.22,54.57
  BOTTOM w0.076: v2(105.56,56.7) 105.56,56.66 105.26,56.37 UC1.AR40
  BOTTOM w0.102: JDIMM2.170 46.16,43.38 46.18,43.36 46.9,43.36 46.92,43.38 47.58,43.38 v2(48.17,43.97)
DDR_B_D37: length 72.3
  IN2 w0.076: v2(105.54,55.86) 105.09,56.3 104.13,56.3 104.09,56.34 103.96,56.34 103.84,56.22 103.39,56.22 103.28,56.34 103.02,56.34 102.86,56.19 102.86,56.03 102.65,55.82 102.32,55.82 100.32,53.82 92.36,53.82 91.92,53.38
  IN2 w0.127: 91.92,53.38 90.43,53.38 89.65,52.6 89.61,52.6 89.16,52.15 79.39,52.15 74.28,47.04 74.16,47.04 72.8,45.67 72.12,45.67 69.74,43.3 69.74,42.1 69.45,41.8 68.54,41.8 68.41,41.67 68.41,41.3 66.19,39.08 66.19,39.06 65.64,38.5 59.09,38.5 57.4,40.18 56.83,40.18 54.99,42.03 50.69,42.03 50.48,42.23 47.54,42.23 47.41,42.36 v2(47.41,42.72)
  BOTTOM w0.076: UC1.AP40 v2(105.54,55.86)
  BOTTOM w0.102: v2(47.41,42.72) 47.41,42.55 47.18,42.32 45.81,42.32 45.75,42.38 JDIMM2.174
DDR_B_D38: length 72.9
  IN2 w0.076: v2(105.54,54.94) 105.54,54.67 105.42,54.55 103.99,54.55 103.72,54.29 102.79,54.29 102.7,54.38 102.25,54.38 101.71,53.84 101.71,53.81 99.92,52.02 99.42,52.02
  IN2 w0.127: v2(48.14,39.6) 48.02,39.48 48.02,39.3 48.15,39.17 54.72,39.17 57.6,36.29 57.89,36.29 58.25,35.93 59.04,35.93 59.16,35.81 59.16,35.39 59.29,35.26 65.69,35.26 68.3,37.88 69.24,37.88 75.52,44.15 75.52,44.34 76.37,45.19 76.37,45.37 76.28,45.47 76.28,45.65 80.56,49.94 80.81,49.94 80.81,49.94 90.12,49.94 91.17,50.99 91.17,51.03 91.78,51.64 92,51.64 92.23,51.88 98.11,51.88 98.25,52.02 99.42,52.02
  BOTTOM w0.076: UC1.AP37 v2(105.54,54.94)
  BOTTOM w0.102: v2(48.14,39.6) 47.69,39.15 45.99,39.15 45.77,39.38 JDIMM2.186
DDR_B_D39: length 72.5
  IN2 w0.076: v2(105.57,54.04) 105.21,54.39 104.06,54.39 103.79,54.12 102.73,54.12 102.63,54.21 102.33,54.21 101.87,53.75 101.87,53.74 100.94,52.81 100.94,52.77
  IN2 w0.127: 100.94,52.77 99.94,51.77 98.47,51.77 97.58,50.88 91.54,50.88 90.26,49.6 80.95,49.6 80.71,49.6 76.81,45.7 76.81,45.15 75.86,44.19 75.86,44.01 69.39,37.53 68.44,37.53 65.83,34.92 58.78,34.92 57.75,35.95 57.46,35.95 54.58,38.83 47.39,38.83 v2(46.62,39.6)
  BOTTOM w0.076: UC1.AR37 v2(105.57,54.04)
  BOTTOM w0.102: v2(46.62,39.6) 46.62,39.93 46.18,40.38 JDIMM2.182
DDR_B_D40: length 73.9
  IN2 w0.076: 91.73,49.03 91.96,49.26 99.05,49.26 99.64,49.85 99.64,50.13 99.78,50.28 100.71,50.28 101.66,51.23 101.66,51.79 103.34,53.47 103.78,53.47 104.13,53.11 v2(104.27,53.11)
  IN2 w0.127: v2(48.14,38.03) 47.95,37.83 47.95,37.42 48.09,37.28 48.29,37.28 48.51,37.06 48.9,37.06 49.03,37.19 49.03,37.56 49.15,37.69 49.41,37.69 49.53,37.56 49.53,37.19 49.66,37.06 54.48,37.06 58.69,32.85 59.98,32.85 60.55,32.28 65.71,32.28 67.97,34.54 68.91,34.54 72.63,38.25 72.63,38.75 82.16,48.28 90.98,48.28 91.73,49.03
  BOTTOM w0.076: v2(104.27,53.11) 104.4,52.93 UC1.AT33
  BOTTOM w0.102: v2(48.14,38.03) 47.68,38.49 46.16,38.49 46.04,38.38 JDIMM2.190
DDR_B_D41: length 73.1
  IN2 w0.076: 92.04,48.85 92.22,49.03 99.05,49.03 99.56,49.54 100.2,49.54 101.85,51.18 101.85,51.67 102.02,51.84 102.36,52.18 102.37,52.18 103.29,53.1 v2(103.62,53.1)
  IN2 w0.127: v2(46.62,38.03) 46.62,37.07 46.75,36.94 47.01,36.94 47.14,37.07 47.14,37.48 47.26,37.61 47.48,37.61 47.61,37.48 47.61,37.07 47.73,36.94 48.15,36.94 48.37,36.72 54.34,36.72 58.55,32.5 59.84,32.5 60.41,31.93 65.86,31.93 68.11,34.19 69.06,34.19 72.97,38.11 72.97,38.61 82.3,47.94 91.12,47.94 92.04,48.85
  BOTTOM w0.076: v2(103.62,53.1) 103.96,52.76 UC1.AU33
  BOTTOM w0.102: JDIMM2.194 45.97,37.38 v2(46.62,38.03)
DDR_B_D42: length 72.5
  IN2 w0.076: v2(103.66,51.31) 103.03,50.68 102.47,50.68 100.66,48.88 100.23,48.88 99.35,47.99 99.35,47.72 98.76,47.13 98.19,47.13
  IN2 w0.127: v2(49.67,34.71) 49.54,34.58 49.54,34.4 49.68,34.27 53.58,34.27 58.13,29.71 58.53,29.71 58.66,29.58 58.66,29.34 58.79,29.22 59.04,29.22 59.17,29.34 59.17,29.58 59.3,29.71 59.55,29.71 59.68,29.58 59.68,29.34 59.8,29.22 60.06,29.22 60.18,29.34 60.18,29.58 60.31,29.71 65.75,29.71 65.88,29.58 65.88,29.34 66.01,29.22 66.26,29.22 66.39,29.34 66.39,29.58 66.51,29.71 67.14,29.71 69.56,32.13 69.96,32.13 71.57,33.74 74,36.17 74.84,37.01 74.84,37.81 83.08,46.06 91.89,46.06 92.96,47.13 98.19,47.13
  BOTTOM w0.076: UC1.AU30 103.66,51.24 v2(103.66,51.31)
  BOTTOM w0.102: JDIMM2.207 52.24,34.12 51.99,33.87 50.51,33.87 v2(49.67,34.71)
DDR_B_D43: length 72.8
  IN2 w0.076: v2(104.27,51.31) 104.38,51.31 104.48,51.41 104.48,51.62 104.33,51.77 103.46,51.77 102.54,50.85 102.4,50.85 100.59,49.04 100.17,49.04 99.16,48.04 99.16,47.77 98.89,47.5 98.18,47.5
  IN2 w0.127: v2(51.19,34.71) 51.27,34.63 51.61,34.63 51.74,34.75 51.74,34.87 51.86,35 52.12,35 52.25,34.87 52.25,34.75 52.37,34.63 52.63,34.63 52.75,34.75 52.75,34.87 52.88,35 53.13,35 53.26,34.87 53.26,34.75 53.39,34.63 53.7,34.63 54.63,33.7 54.91,33.7 55.16,33.45 55.16,33.17 55.35,32.99 55.63,32.99 55.88,32.74 55.88,32.45 56.06,32.27 56.35,32.27 56.6,32.02 56.6,31.73 57.45,30.88 57.85,30.88 57.97,30.75 57.97,30.63 58.1,30.5 58.35,30.5 58.48,30.63 58.48,30.75 58.61,30.88 58.96,30.88 59.09,30.75 59.09,30.18 59.22,30.05 59.47,30.05 59.6,30.18 59.6,30.27 59.73,30.4 59.98,30.4 60.11,30.27 60.11,30.18 60.23,30.05 60.49,30.05 60.74,30.31 61,30.31 61.25,30.05 66.12,30.05 66.61,30.54 66.79,30.54 67.05,30.29 67.23,30.29 67.41,30.46 67.41,30.64 67.15,30.9 67.15,31.08 67.33,31.26 67.51,31.26 67.77,31 67.95,31 68.13,31.18 68.13,31.36 67.87,31.62 67.87,31.8 68.51,32.44 68.69,32.44 68.91,32.22 69.16,32.22 69.41,32.47 69.81,32.47 71.23,33.89 73.25,35.9 73.66,36.32 73.66,36.32 74.49,37.15 74.49,37.98 82.93,46.42 91.76,46.42 92.82,47.48 92.9,47.48 92.92,47.5 98.18,47.5
  BOTTOM w0.076: UC1.AT30 104.61,50.85 v2(104.27,51.31)
  BOTTOM w0.102: v2(51.19,34.71) 51.61,35.12 JDIMM2.203
DDR_B_D44: length 74.1
  IN2 w0.076: 100.66,50.65 100.84,50.65 101.49,51.29 101.49,51.86 103.27,53.63 103.84,53.63 103.99,53.49 105.11,53.49 105.19,53.41 105.19,53.24 105.06,53.11 v2(104.9,53.11)
  IN2 w0.127: 100.66,50.65 100.48,50.47 99.7,50.47 99.42,50.18 92.23,50.18 90.67,48.62 82.02,48.62 72.29,38.89 72.29,38.39 72.11,38.21 71.93,38.21 71.78,38.36 71.6,38.36 71.42,38.18 71.42,38 71.57,37.85 71.57,37.67 71.39,37.49 71.21,37.49 71.06,37.64 70.88,37.64 70.7,37.46 70.7,37.28 70.85,37.14 70.85,36.96 70.67,36.78 70.49,36.78 70.34,36.93 70.16,36.93 69.98,36.75 69.98,36.57 70.13,36.42 70.13,36.24 69.95,36.06 69.77,36.06 69.62,36.21 69.44,36.21 69.26,36.03 69.26,35.85 69.41,35.7 69.41,35.52 68.77,34.88 67.83,34.88 66.14,33.19 58.84,33.19 54.62,37.4 50.29,37.4 v2(49.67,38.03)
  BOTTOM w0.076: v2(104.9,53.11) 105.04,52.93 UC1.AR33
  BOTTOM w0.102: v2(49.67,38.03) 49.67,38.09 50.01,38.43 51.9,38.43 52.2,38.12 JDIMM2.191
DDR_B_D45: length 75.4
  IN2 w0.076: 99.64,50.87 100.83,50.87 101.33,51.36 101.33,51.92 101.58,52.18 103.2,53.8 103.91,53.8 104.06,53.65 105.18,53.65 105.22,53.61 105.73,53.61 105.8,53.54 105.8,53.19 105.73,53.11 v2(105.54,53.11)
  IN2 w0.127: 99.64,50.87 99.27,50.5 92.06,50.5 90.52,48.96 81.6,48.96 81.29,48.65 81.11,48.65 80.97,48.78 80.79,48.78 80.61,48.6 80.61,48.42 80.75,48.29 80.75,48.11 80.57,47.93 80.39,47.93 80.25,48.06 80.07,48.06 79.89,47.89 79.89,47.71 80.03,47.57 80.03,47.39 79.85,47.21 79.67,47.21 79.53,47.35 79.35,47.35 79.17,47.17 79.17,46.99 79.31,46.85 79.31,46.67 79.13,46.49 78.95,46.49 78.81,46.63 78.63,46.63 78.45,46.45 78.45,46.27 78.59,46.13 78.59,45.95 78.44,45.8 78.2,45.8 78.09,45.91 77.91,45.91 77.73,45.73 77.73,45.55 77.83,45.45 77.83,45.27 76.49,43.93 76.49,43.74 69.14,36.39 68.2,36.39 67.31,35.51 67.31,35.33 67.46,35.18 67.46,35 67.28,34.82 67.1,34.82 66.95,34.97 66.77,34.97 66.59,34.79 66.59,34.61 66.74,34.46 66.74,34.28 66.56,34.1 66.38,34.1 66.24,34.25 66.06,34.25 65.81,34.01 65.81,33.78 65.57,33.53 60.02,33.53 59.89,33.66 59.89,34.16 59.77,34.29 59.51,34.29 59.39,34.16 59.39,33.8 59.26,33.67 58.95,33.67 58.82,33.8 58.82,33.98 58.13,34.67 57.85,34.67 54.75,37.76 53.87,37.76 53.74,37.89 53.74,38.07 53.61,38.19 53.36,38.19 53.23,38.07 53.23,37.89 53.1,37.76 52.85,37.76 52.72,37.89 52.72,38.07 52.6,38.19 52.34,38.19 52.21,38.07 52.21,37.89 52.09,37.76 51.45,37.76 v2(51.19,38.03)
  BOTTOM w0.076: v2(105.54,53.11) 105.68,52.93 UC1.AP33
  BOTTOM w0.102: v2(51.19,38.03) 52.06,37.16 52.15,37.16 52.19,37.12 JDIMM2.195
DDR_B_D46: length 73.8
  IN2 w0.076: v2(104.9,51.31) 104.53,50.93 104.06,50.93 103.65,50.52 102.53,50.52 100.73,48.71 100.3,48.71 99.51,47.92 99.51,47.65 98.64,46.77 98.19,46.77
  IN2 w0.127: 98.19,46.77 93.11,46.77 92.04,45.7 83.21,45.7 75.18,37.67 75.18,37.15 75.18,36.86 74.95,36.64 73.29,34.97 70.1,31.78 69.7,31.78 66.79,28.87 58.49,28.87 53.45,33.91 48.27,33.91 48.03,34.15 48.03,34.59 v2(48.14,34.71)
  BOTTOM w0.076: UC1.AR30 105.26,50.85 v2(104.9,51.31)
  BOTTOM w0.102: JDIMM2.204 45.86,34.87 46.1,35.12 47.74,35.12 v2(48.14,34.71)
DDR_B_D47: length 74.7
  IN2 w0.076: 97.92,46.42 98.51,46.42 99.68,47.58 99.68,47.86 100.37,48.55 100.8,48.55 102.6,50.35 103.71,50.35 104.13,50.77 104.6,50.77 104.71,50.88 105.1,50.88 v2(105.54,51.31)
  IN2 w0.127: v2(46.62,34.71) 46.62,34.06 47.12,33.57 53.31,33.57 58.34,28.53 66.93,28.53 69.84,31.44 70.24,31.44 72.26,33.46 74.69,35.89 75.53,36.73 75.53,37.53 83.34,45.34 92.19,45.34 93.26,46.42 97.82,46.42 97.82,46.42 97.92,46.42
  BOTTOM w0.076: v2(105.54,51.31) 105.91,50.85 UC1.AP30
  BOTTOM w0.102: v2(46.62,34.71) 45.78,33.87 JDIMM2.208
DDR_B_D48: length 75.6
  IN2 w0.076: 95.41,44.56 95.41,44.58 95.85,45.03 99.02,45.03 99.63,45.63 99.95,45.63 100.32,46 100.32,46.76 101.65,48.08 101.65,48.46 102.48,49.3 103.49,49.3 v2(103.64,49.45)
  IN2 w0.127: 95.41,44.56 95.31,44.47 93.75,44.47 92.91,43.63 84.27,43.63 77.19,36.55 77.19,36.04 74.12,32.97 73.82,32.67 73.82,31.32 69.12,26.62 68.81,26.62 68.3,26.11 68.02,26.11 67.89,26.24 67.89,26.49 67.76,26.62 67.51,26.62 67.38,26.49 67.38,26.24 67.26,26.11 58.12,26.11 52.9,31.33 52.35,31.33 52.22,31.21 52.22,31 52.09,30.87 51.9,30.87 51.77,31 51.77,31.14 51.58,31.33 46.75,31.33 46.62,31.46 v2(46.62,32.44)
  BOTTOM w0.076: v2(103.64,49.45) 103.63,49.45 103.63,49.44 UC1.AU27
  BOTTOM w0.102: JDIMM2.216 46.26,31.87 46.62,32.23 v2(46.62,32.44)
DDR_B_D49: length 76.3
  IN2 w0.076: v2(104.27,49.45) 104.17,49.45 103.81,49.81 102.77,49.81 101.48,48.53 101.48,48.15 99.98,46.64 99.9,46.64 99.52,46.26 99.52,45.76 98.99,45.22 95.56,45.22 95.17,44.83
  IN2 w0.127: 95.17,44.83 95.16,44.83 93.6,44.83 92.77,43.99 83.85,43.99 76.85,36.98 76.85,36.18 73.98,33.31 73.48,32.81 73.48,31.47 68.98,26.96 67.14,26.96 66.98,26.81 66.98,26.58 66.86,26.45 66.6,26.45 66.48,26.58 66.48,26.86 66.35,26.99 66.1,26.99 65.97,26.86 65.97,26.58 65.84,26.45 58.27,26.45 53.04,31.68 47.81,31.68 47.69,31.8 47.69,32.15 47.97,32.44 v2(48.14,32.44)
  BOTTOM w0.076: v2(104.27,49.45) UC1.AT27
  BOTTOM w0.102: v2(48.14,32.44) 47.71,32.87 JDIMM2.212
DDR_B_D50: length 75.5
  IN2 w0.076: v2(104.27,48.54) 104.11,48.54 103.52,47.94 102.45,47.94 100.98,46.48 100.98,45.73 100.23,44.97 99.91,44.97 98.51,43.58 97.11,43.58
  IN2 w0.127: v2(49.67,29.31) 50.09,28.89 52.14,28.89 54.87,26.15 55.16,26.15 56.49,24.82 57.06,24.25 58.08,24.25 58.21,24.12 58.21,23.64 58.34,23.51 58.59,23.51 58.72,23.64 58.72,23.89 58.84,24.02 59.1,24.02 59.23,23.89 59.23,23.55 59.35,23.42 59.61,23.42 59.73,23.55 59.73,23.92 59.86,24.04 65.78,24.04 66.09,23.73 68.44,23.73 68.95,24.25 69.31,24.25 70.33,24.25 74.69,28.61 74.69,28.61 75.78,29.7 75.78,32 79.05,35.27 79.05,35.57 84.35,40.87 85.23,40.87 85.23,40.87 89.77,40.87 90.66,41.76 93.68,41.76 94.5,42.58 96.11,42.58 97.11,43.58
  BOTTOM w0.076: v2(104.27,48.54) 104.27,48.54 UC1.AT25
  BOTTOM w0.102: v2(49.67,29.31) 50.51,30.15 51.55,30.15 52.08,29.63 JDIMM2.225
DDR_B_D51: length 74.7
  IN2 w0.076: 96.93,43.91 98.61,43.91 99.84,45.14 100.16,45.14 100.82,45.8 100.82,46.55 102.38,48.11 103.29,48.11 103.59,48.41 v2(103.59,48.54)
  IN2 w0.127: v2(51.19,29.31) 51.23,29.36 52.2,29.36 52.42,29.13 52.66,29.13 52.88,28.92 52.88,28.63 53.1,28.41 53.38,28.41 53.6,28.2 53.6,27.91 55.01,26.5 55.3,26.5 56.83,24.96 57.21,24.59 60.4,24.59 60.6,24.39 65.52,24.39 65.73,24.59 67.04,24.59 67.17,24.46 67.17,24.2 67.3,24.08 67.55,24.08 67.68,24.2 67.68,24.46 67.8,24.59 69.45,24.59 70.19,24.59 72.48,26.88 72.48,27.06 72.19,27.36 72.19,27.54 72.37,27.72 72.55,27.72 72.84,27.42 73.02,27.42 73.2,27.6 73.2,27.78 72.9,28.08 72.9,28.26 73.08,28.44 73.26,28.44 73.56,28.14 73.74,28.14 73.92,28.32 73.92,28.5 73.62,28.79 73.62,28.97 73.8,29.15 73.98,29.15 74.28,28.86 74.46,28.86 74.64,29.04 74.64,29.22 74.34,29.51 74.34,29.69 74.52,29.87 74.7,29.87 75,29.58 75.18,29.58 75.43,29.84 75.43,30.02 75.2,30.25 75.2,30.55 75.44,30.8 75.44,32.14 78.71,35.41 78.71,35.71 84.32,41.32 89.71,41.32 90.5,42.11 93.54,42.11 94.37,42.94 95.97,42.94 96.93,43.91
  BOTTOM w0.076: UC1.AU25 103.96,48.14 103.59,48.51 v2(103.59,48.54)
  BOTTOM w0.102: JDIMM2.229 51.88,28.63 v2(51.19,29.31)
DDR_B_D52: length 77
  IN2 w0.076: v2(105.54,49.45) 105.15,49.84 104.05,49.84 103.87,50.02 102.74,50.02 101.45,48.74 101.46,48.74 101.32,48.6 101.32,48.22 99.91,46.81 99.84,46.81 99.33,46.3 99.33,45.8 98.95,45.42 95.33,45.42 95.22,45.31 95.22,45.28
  IN2 w0.127: 95.22,45.28 95.12,45.18 93.46,45.18 92.62,44.35 83.73,44.35 76.5,37.13 76.5,36.32 73.83,33.65 73.14,32.96 73.14,31.61 72.96,31.43 72.76,31.43 72.63,31.56 72.45,31.56 72.28,31.39 72.28,31.21 72.42,31.07 72.42,30.89 68.83,27.3 68.48,27.3 68.23,27.55 67.86,27.55 67.63,27.32 67.45,27.32 67.21,27.55 66.84,27.55 66.61,27.32 66.43,27.32 66.2,27.55 65.83,27.55 65.59,27.32 65.41,27.32 65.18,27.55 64.81,27.55 64.56,27.3 60.43,27.3 60.3,27.18 60.3,26.92 60.18,26.8 59.92,26.8 59.8,26.92 59.8,27.18 59.67,27.3 59.41,27.3 59.29,27.18 59.29,26.92 59.16,26.8 58.91,26.8 58.78,26.92 58.78,27.18 58.65,27.3 57.9,27.3 53.19,32.02 49.68,32.02 49.55,32.15 49.55,32.33 v2(49.67,32.44)
  BOTTOM w0.076: v2(105.54,49.45) UC1.AP27
  BOTTOM w0.102: v2(49.67,32.44) 50.52,33.29 51.96,33.29 52.12,33.12 JDIMM2.211
DDR_B_D53: length 77.1
  IN2 w0.076: v2(106.17,49.45) 105.61,50.02 104.12,50.02 103.96,50.19 102.67,50.19 100.87,48.38 100.44,48.38 99.84,47.79 99.84,47.39 99.14,46.69 99.14,45.85 98.88,45.59 95.17,45.59
  IN2 w0.127: 95.17,45.59 95.04,45.59 95,45.54 93.31,45.54 92.47,44.71 83.6,44.71 76.16,37.27 76.16,36.99 76.16,36.46 73.69,33.99 73.69,33.99 72.89,33.2 71.58,31.88 71.58,30.53 71.4,30.35 71.22,30.35 70.7,30.87 70.52,30.87 70.34,30.69 70.34,30.51 70.86,29.99 70.86,29.82 70.68,29.64 70.5,29.64 70,30.14 69.82,30.14 69.64,29.96 69.64,29.78 70.14,29.28 70.14,29.1 68.94,27.9 64.64,27.9 64.39,27.65 64.13,27.65 63.88,27.9 63.63,27.9 63.38,27.65 63.12,27.65 62.87,27.9 62.61,27.9 62.36,27.65 62.1,27.65 61.85,27.9 61.59,27.9 61.34,27.65 61.09,27.65 60.84,27.9 60.58,27.9 60.33,27.65 60.07,27.65 59.82,27.9 59.56,27.9 59.31,27.65 59.05,27.65 58.8,27.9 58.55,27.9 58.3,27.65 58.04,27.65 56.99,28.7 56.99,28.99 56.78,29.2 56.49,29.2 56.27,29.42 56.27,29.7 56.06,29.92 55.77,29.92 55.55,30.14 55.55,30.42 55.34,30.64 55.05,30.64 54.83,30.85 54.83,31.14 54.62,31.36 54.33,31.36 53.25,32.44 52.37,32.44 52.25,32.56 52.25,32.81 52.12,32.93 51.86,32.93 51.74,32.81 51.74,32.56 51.61,32.44 v2(51.19,32.44)
  BOTTOM w0.076: v2(106.17,49.45) UC1.AN27
  BOTTOM w0.102: v2(51.19,32.44) 51.5,32.12 JDIMM2.215
DDR_B_D54: length 77.5
  IN2 w0.076: v2(106.17,48.54) 105.63,48 104.05,48 103.66,47.61 102.58,47.61 101.31,46.34 101.31,45.59 100.37,44.64 100.05,44.64 98.47,43.07 97.59,43.07
  IN2 w0.127: v2(46.62,29.31) 47.75,28.19 51.87,28.19 54.59,25.47 54.88,25.47 55.81,24.54 57.61,22.73 65.75,22.73 66.06,23.05 70.1,23.05 74.98,27.93 76.47,29.42 76.47,31.71 79.74,34.98 79.74,35.28 84.64,40.19 84.94,40.19 90.08,40.19 90.97,41.08 93.97,41.08 94.77,41.88 96.4,41.88 97.59,43.07
  BOTTOM w0.076: v2(106.17,48.54) UC1.AN25
  BOTTOM w0.102: JDIMM2.228 46.18,28.87 v2(46.62,29.31)
DDR_B_D55: length 76.9
  IN2 w0.076: 97.36,43.33 98.49,43.33 99.98,44.81 100.3,44.81 101.15,45.66 101.15,46.41 102.51,47.78 103.59,47.78 103.98,48.17 105.48,48.17 105.56,48.25 v2(105.56,48.57)
  IN2 w0.127: 97.36,43.33 96.26,42.22 94.63,42.22 93.83,41.42 90.83,41.42 89.93,40.53 85.08,40.53 85.08,40.53 84.5,40.53 79.39,35.43 79.39,35.12 76.13,31.86 76.13,29.56 74.84,28.27 69.96,23.39 65.92,23.39 65.61,23.08 57.75,23.08 57.19,23.63 56.15,24.68 55.02,25.81 54.73,25.81 52.01,28.53 48.93,28.53 v2(48.14,29.31)
  BOTTOM w0.076: UC1.AP25 105.91,48.21 v2(105.56,48.57)
  BOTTOM w0.102: JDIMM2.224 47.58,29.87 v2(48.14,29.31)
DDR_B_D56: length 80.3
  IN2 w0.076: 98.43,42.25 99.6,43.42 100.33,43.42 100.7,43.79 100.7,44.19 102.75,46.24 102.75,46.87 103,47.12 103.75,47.12 104.15,46.72 v2(104.27,46.72)
  IN2 w0.127: v2(48.14,27.15) 48.03,27.04 48.03,26.5 48.18,26.35 48.51,26.35 48.64,26.48 48.64,26.61 48.76,26.74 49.02,26.74 49.14,26.61 49.14,26.48 49.27,26.35 51.54,26.35 57.32,20.57 59.61,20.57 59.74,20.45 59.74,19.96 59.87,19.83 60.12,19.83 60.25,19.96 60.25,20.45 60.37,20.57 60.63,20.57 60.75,20.45 60.75,19.96 60.88,19.83 61.14,19.83 61.26,19.96 61.26,20.45 61.39,20.57 67.98,20.57 68.36,20.96 69.88,20.96 75.53,26.61 77.79,28.87 77.79,31.14 85.52,38.86 90.62,38.86 90.79,39.03 92.92,39.03 93.07,38.88 94.48,38.88 95.49,39.89 96.25,39.89 96.86,40.5 97.79,40.5 98.43,41.14 98.43,42.25
  BOTTOM w0.076: UC1.AT22 104.27,46.71 v2(104.27,46.72)
  BOTTOM w0.102: JDIMM2.232 47.42,27.87 v2(48.14,27.15)
DDR_B_D57: length 79.5
  IN2 w0.076: v2(103.63,46.72) 103.42,46.51 103.19,46.51 102.92,46.25 102.92,46.17 100.87,44.12 100.87,43.72 100.39,43.25 99.72,43.25 98.67,42.2
  IN2 w0.127: v2(46.62,27.15) 46.62,26.14 46.75,26.01 51.4,26.01 57.18,20.23 58.92,20.23 59.66,19.49 61.4,19.49 62.15,20.23 63.49,20.23 64.17,19.55 64.43,19.55 64.55,19.68 64.55,20.1 64.68,20.23 64.93,20.23 65.06,20.1 65.06,19.68 65.19,19.55 65.44,19.55 65.57,19.68 65.57,19.99 65.7,20.12 65.95,20.12 66.08,19.99 66.08,19.7 66.2,19.58 66.46,19.58 66.58,19.7 66.58,19.99 66.71,20.12 69.52,20.12 75.67,26.26 78.24,28.84 78.24,31.11 85.66,38.52 90.76,38.52 90.93,38.69 92.78,38.69 92.93,38.54 94.62,38.54 95.63,39.55 96.4,39.55 96.99,40.14 97.74,40.14 98.67,41.06 98.67,42.2
  BOTTOM w0.076: v2(103.63,46.72) 103.63,46.69 103.96,46.35 UC1.AU22
  BOTTOM w0.102: v2(46.62,27.15) 46.34,26.87 JDIMM2.236
DDR_B_D58: length 78.3
  IN2 w0.076: 99.32,40.56 99.32,41.92 100.16,42.76 100.6,42.76 103.58,45.74 103.6,45.74 103.68,45.81 v2(103.68,45.81)
  IN2 w0.127: v2(51.19,24.23) 50.76,23.8 50.76,23.62 55.67,18.71 56.25,18.71 56.38,18.59 56.38,18 56.51,17.88 56.76,17.88 56.89,18 56.89,18.59 57.02,18.71 57.27,18.71 57.4,18.59 57.4,18.2 57.52,18.07 57.78,18.07 57.91,18.2 57.91,18.41 58.06,18.56 58.44,18.56 59.43,17.57 69.12,17.57 69.92,18.36 70.1,18.36 70.65,17.81 70.83,17.81 71.01,17.99 71.01,18.17 70.46,18.72 70.46,18.9 70.64,19.08 70.82,19.08 71.37,18.53 71.55,18.53 71.73,18.71 71.73,18.89 71.18,19.44 71.18,19.62 80.17,28.62 80.17,30.76 85.97,36.56 94.09,36.56 94.54,37.01 95.37,37.01 96.39,38.03 96.79,38.03 99.32,40.56
  BOTTOM w0.076: v2(103.68,45.81) 103.67,45.72 UC1.AU21
  BOTTOM w0.102: v2(51.19,24.23) 51.8,23.63 JDIMM2.249
DDR_B_D59: length 79.2
  IN2 w0.076: v2(104.27,45.81) 104.26,45.81 103.78,45.33 103.41,45.33 100.67,42.59 100.23,42.59 99.52,41.88 99.52,40.41 98.69,39.58
  IN2 w0.127: v2(49.67,24.23) 56.68,17.22 71.24,17.22 73.1,19.09 73.1,19.27 72.76,19.62 72.76,19.8 72.94,19.98 73.12,19.98 73.46,19.63 73.64,19.63 73.82,19.81 73.82,19.99 73.48,20.34 73.48,20.52 73.66,20.7 73.84,20.7 74.18,20.35 74.36,20.35 80.51,26.5 80.51,30.62 86.11,36.21 94.23,36.21 94.64,36.62 95.47,36.62 96.54,37.69 96.79,37.69 98.69,39.58
  BOTTOM w0.076: UC1.AT21 104.27,45.8 v2(104.27,45.81)
  BOTTOM w0.102: v2(49.67,24.23) 50.18,24.75 51.56,24.75 51.68,24.63 JDIMM2.245
DDR_B_D60: length 80.9
  IN2 w0.076: 97.76,42.34 98.24,42.82 98.45,42.82 100.11,44.48 100.43,44.48 101.48,45.52 101.48,46.28 102.65,47.45 103.88,47.45 104.08,47.25 104.48,47.25 105.06,47.83 106.16,47.83 106.59,47.4 106.59,46.97 106.33,46.71 v2(106.17,46.71)
  IN2 w0.127: 97.76,42.34 96.67,41.24 95.03,41.24 94.23,40.44 91.23,40.44 90.51,39.72 90.34,39.55 85.2,39.55 77.1,31.45 77.1,29.15 75.24,27.29 70.16,22.21 68.28,22.21 67.83,21.76 66.85,21.76 66.72,21.88 66.72,22.2 66.59,22.32 66.34,22.32 66.21,22.2 66.21,21.88 66.09,21.76 65.58,21.76 65.45,21.88 65.45,21.97 65.32,22.1 65.07,22.1 64.94,21.97 64.94,21.88 64.82,21.76 64.56,21.76 64.43,21.88 64.43,21.97 64.31,22.1 64.05,22.1 63.93,21.97 63.93,21.88 63.8,21.76 63.55,21.76 63.42,21.88 63.42,21.97 63.29,22.1 63.04,22.1 62.91,21.97 62.91,21.88 62.78,21.76 62.53,21.76 62.4,21.88 62.4,21.97 62.28,22.1 62.02,22.1 61.89,21.97 61.89,21.88 61.77,21.76 61.51,21.76 61.39,21.88 61.39,21.97 61.26,22.1 61.08,22.1 60.95,21.97 60.95,21.88 60.83,21.76 60.16,21.76 60.03,21.88 60.03,21.97 59.91,22.1 59.65,22.1 59.53,21.97 59.53,21.88 59.4,21.76 59.15,21.76 59.02,21.88 59.02,21.97 58.89,22.1 58.64,22.1 58.51,21.97 58.51,21.88 58.38,21.76 58.13,21.76 58,21.88 58,21.97 57.88,22.1 57.62,22.1 57.49,21.97 57.49,21.88 57.37,21.76 57.11,21.76 56.87,22 56.87,22.18 56.98,22.29 56.98,22.47 56.8,22.65 56.62,22.65 56.51,22.54 56.33,22.54 55.76,23.11 55.76,23.29 55.87,23.39 55.87,23.57 55.69,23.75 55.51,23.75 55.4,23.65 55.22,23.65 55.04,23.83 55.04,24.01 55.15,24.11 55.15,24.29 54.97,24.47 54.79,24.47 54.68,24.36 54.5,24.36 53.92,24.95 53.92,25.23 53.7,25.45 53.42,25.45 53.24,25.63 53.24,25.92 53.02,26.13 52.73,26.13 52.52,26.35 52.52,26.64 52.3,26.85 52.02,26.85 51.84,27.03 51.84,27.31 51.6,27.55 51.25,27.55 51.11,27.41 51.11,27.23 v2(51.19,27.15)
  BOTTOM w0.076: UC1.AN22 v2(106.17,46.71)
  BOTTOM w0.102: JDIMM2.237 52.3,26.63 51.88,27.04 51.3,27.04 v2(51.19,27.15)
DDR_B_D61: length 80.8
  IN2 w0.076: v2(105.54,46.71) 105.75,46.92 105.75,47.05 105.64,47.15 104.8,47.15 104.73,47.08 104.01,47.08 103.81,47.28 102.72,47.28 101.64,46.21 101.64,45.46 100.5,44.31 100.18,44.31 98.2,42.33 98.2,42.23
  IN2 w0.127: 98.2,42.23 96.84,40.87 95.34,40.87 94.67,40.19 94.67,39.61 94.28,39.22 93.21,39.22 93.06,39.38 90.65,39.38 90.48,39.21 85.37,39.21 77.45,31.28 77.45,29.01 75.38,26.95 75.38,26.95 70.3,21.87 69.78,21.87 69.65,21.74 69.65,21.43 69.53,21.3 69.27,21.3 69.14,21.43 69.14,21.74 69.02,21.87 68.42,21.87 67.97,21.41 67.62,21.41 67.49,21.28 67.49,21.04 67.37,20.92 67.11,20.92 66.99,21.04 66.99,21.28 66.86,21.41 66.61,21.41 66.48,21.28 66.48,21.04 66.35,20.92 66.1,20.92 65.97,21.04 65.97,21.28 65.84,21.41 65.51,21.41 60.49,21.41 60.37,21.29 60.37,21.04 60.24,20.92 59.99,20.92 59.86,21.04 59.86,21.29 59.73,21.41 59.48,21.41 59.35,21.29 59.35,21.04 59.22,20.92 58.97,20.92 58.84,21.04 58.84,21.29 58.72,21.41 58.46,21.41 58.34,21.29 58.34,21.04 58.21,20.92 57.95,20.92 57.83,21.04 57.83,21.29 57.7,21.41 56.97,21.41 51.66,26.73 49.7,26.73 49.56,26.87 49.56,27.05 v2(49.67,27.15)
  BOTTOM w0.076: UC1.AP22 v2(105.54,46.71)
  BOTTOM w0.102: JDIMM2.233 50.14,27.63 v2(49.67,27.15)
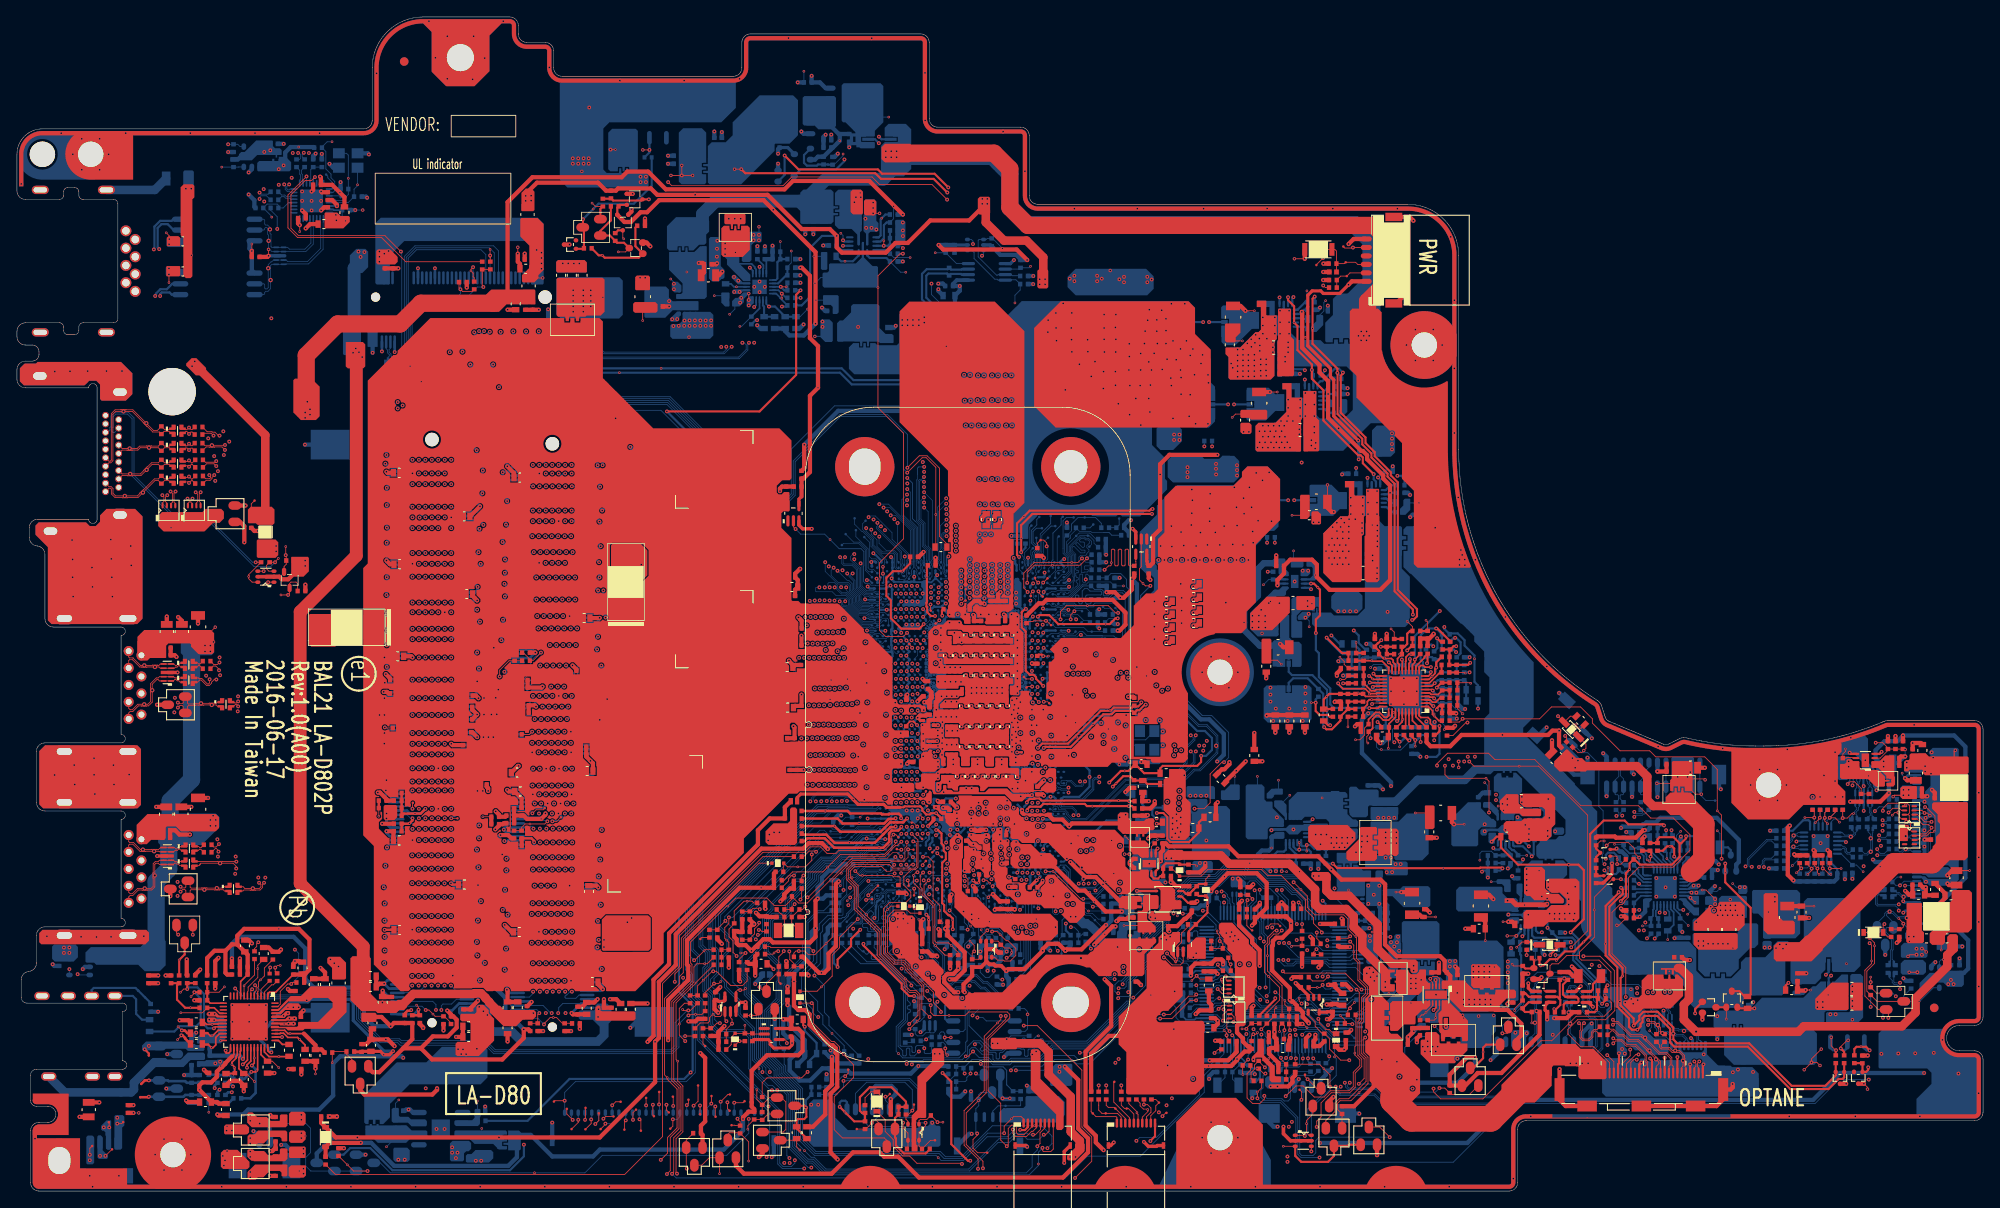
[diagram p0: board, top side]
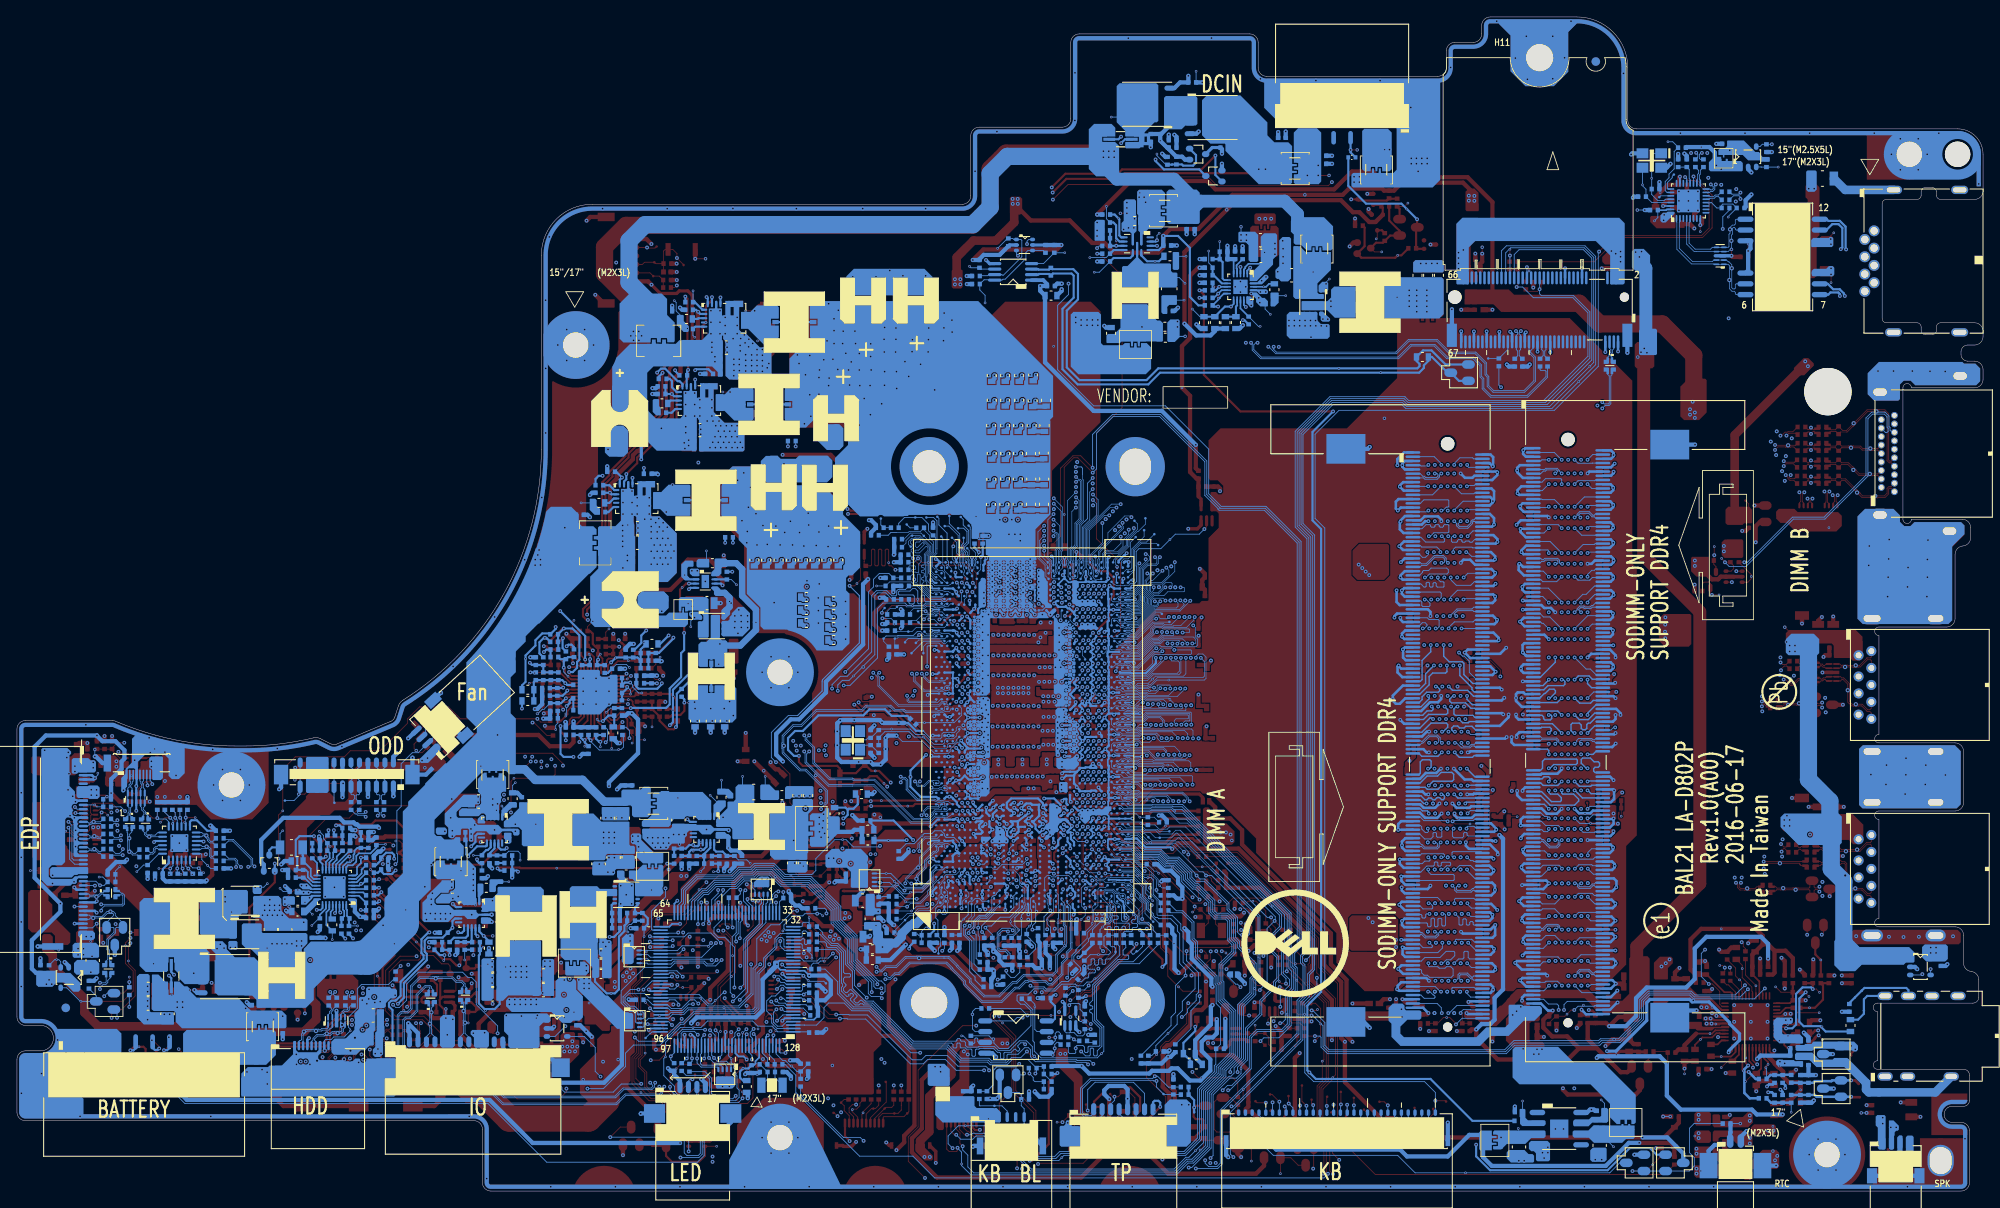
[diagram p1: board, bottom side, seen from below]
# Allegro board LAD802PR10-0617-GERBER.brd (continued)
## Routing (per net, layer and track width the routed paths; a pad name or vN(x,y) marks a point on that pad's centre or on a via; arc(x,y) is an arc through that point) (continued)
DDR_B_D62: length 80.1
  IN2 w0.076: v2(105.59,45.86) 105.18,45.45 104.33,45.45 103.96,45.08 103.39,45.08 100.74,42.43 100.3,42.43 99.69,41.82 99.69,40.24 99.47,40.02
  IN2 w0.127: 99.47,40.02 96.79,37.34 96.68,37.34 95.62,36.28 94.78,36.28 94.37,35.87 86.25,35.87 80.86,30.48 80.86,26.36 71.38,16.88 56.53,16.88 49.6,23.81 48.56,23.81 v2(48.14,24.23)
  BOTTOM w0.076: v2(105.59,45.86) 105.93,45.46 UC1.AP21
  BOTTOM w0.102: JDIMM2.250 45.73,23.38 45.75,23.39 47.3,23.39 v2(48.14,24.23)
DDR_B_D63: length 80.8
  IN2 w0.076: v2(106.21,45.87) 105.62,45.29 104.4,45.29 104.03,44.92 103.46,44.92 100.81,42.26 100.37,42.26 99.85,41.75 99.85,40.03
  IN2 w0.127: 99.85,40.03 95.76,35.94 94.92,35.94 94.52,35.53 86.39,35.53 81.2,30.33 81.2,26.22 71.52,16.54 56.39,16.54 49.46,23.47 47.38,23.47 v2(46.62,24.23)
  BOTTOM w0.076: UC1.AN21 106.2,45.76 v2(106.21,45.87)
  BOTTOM w0.102: v2(46.62,24.23) 46.36,24.23 46.22,24.38 JDIMM2.246
DDR_B_DQS0: length 83.6
  IN2 w0.076: v2(108.65,69.99) 108.18,70.46 108.18,71.82 107.47,72.52 107.47,73.42 106.04,74.86 106.04,75.12 105.87,75.29 105.82,75.29 105.81,75.31
  IN2 w0.127: v2(47.49,79.45) 47.71,79.22 47.71,79.07 47.99,78.8 52.05,78.8 54.52,81.27 54.8,81.27 55.74,82.2 55.74,82.28 60.17,86.71 64.36,86.71 64.63,86.99 64.63,87.59 64.76,87.72 65.14,87.72 65.26,87.59 65.26,86.99 65.54,86.71 66.12,86.71 66.4,86.99 66.4,87.59 66.52,87.72 66.9,87.72 67.03,87.59 67.03,86.99 67.3,86.71 67.89,86.71 68.16,86.99 68.16,87.59 68.3,87.73 71.29,87.73 72.13,86.88 72.69,86.88 73.41,87.61 86.24,87.61 87.23,86.62 93.67,86.62 98.57,81.72 101.71,81.72 104.59,78.84 104.59,77.33 105.46,76.46 105.46,76.18 105.47,76.17 105.47,75.65 105.81,75.31
  BOTTOM w0.076: UC1.AH65 109.07,70.27 v2(108.65,69.99)
  BOTTOM w0.102: v2(47.49,79.45) 47.49,79.48 47.68,79.68 47.68,79.76 47.5,79.95 46.52,79.95 46.11,79.53 45.84,79.53 45.68,79.38 JDIMM2.34
DDR_B_DQS1: length 87.6
  IN2 w0.076: 110.35,78.58 110.35,78.56 110.32,78.53 110.32,77.68 110.14,77.49 109.88,77.49 v2(109.64,77.25)
  IN2 w0.127: 110.35,78.58 110.35,78.96 110.94,79.55 110.94,79.55 110.93,79.57 110.93,80.19 110.96,80.22 110.96,83.44 110.76,83.63 110.76,84.92 103.14,92.54 80.76,92.54 79.45,92.54 79.06,92.94 58.79,92.94 56.16,90.31 56.16,89.92 56.28,89.81 56.28,89.63 56.01,89.36 55.83,89.36 55.71,89.47 55.33,89.47 54.91,89.06 54.91,88.67 55.03,88.56 55.03,88.38 54.76,88.11 54.58,88.11 54.46,88.22 54.08,88.22 52.62,86.77 52.62,85.68 51.21,84.27 50.95,84.27 50.92,84.24 50.41,84.24 50.3,84.35 50.3,84.5 v2(50.46,84.66)
  BOTTOM w0.076: UC1.AG70 109.69,73.15 109.69,72.96 109.62,72.89 109.52,72.89 109.44,72.98 109.39,73.08 109.39,73.3 109.43,73.38 109.43,73.65 109.37,73.78 109.37,73.91 109.45,74.07 109.45,75.66 109.23,75.88 109.23,77.43 109.32,77.53 109.55,77.53 109.64,77.44 v2(109.64,77.25)
  BOTTOM w0.102: JDIMM2.13 52.17,84.62 51.86,84.93 51.61,84.93 51.48,85.07 50.32,85.07 50.2,84.94 50.2,84.84 50.38,84.66 v2(50.46,84.66)
DDR_B_DQS2: length 70.1
  IN2 w0.076: v2(104.85,70.49) 104.97,70.49 105.07,70.59 105.07,70.71 104.92,70.86 102.79,70.86 102.48,71.17 102.48,72.48 102.57,72.57 102.57,73.04 102.41,73.2 101.64,73.2 101.14,73.7 101.14,74.36 100.86,74.64 100.81,74.64 98.71,76.74 97.94,76.74 97.92,76.76 97.91,76.76 97.9,76.75
  IN2 w0.127: 97.9,76.75 97.9,76.74 97.82,76.74 97.81,76.73 97.56,76.73 97.55,76.74 97.18,76.74 92.87,81.05 69.75,81.05 69.39,80.69 60.68,80.69 60.35,80.36 60.35,80.33 57.3,77.28 57.01,77.28 56.55,76.82 56.55,76.53 56.04,76.03 55.76,76.03 55.3,75.57 55.3,75.28 53.98,73.96 53.49,73.96 53.21,74.24 53.21,74.29 53.09,74.42 52.7,74.42 52.58,74.29 52.58,74.24 52.3,73.96 51.84,73.96 51.39,74.42 50.25,74.42 50.12,74.29 50.12,74.09 50.25,73.96 50.43,73.96 v2(50.46,73.99)
  BOTTOM w0.076: UC1.AR65 105.26,70.07 v2(104.85,70.49)
  BOTTOM w0.102: JDIMM2.55 52.21,74.13 52.05,74.28 51.78,74.28 51.62,74.44 50.25,74.44 50.14,74.34 50.14,74.09 50.24,73.99 v2(50.46,73.99)
DDR_B_DQS3: length 70.2
  IN2 w0.076: 93.49,73.11 93.55,73.05 93.61,72.99 93.64,72.99 95.03,71.6 98.32,71.6 98.53,71.4 98.53,70.87 98.82,70.59 98.82,70.39 98.97,70.23 98.97,69.72 99.79,68.9 100.71,68.9 101.74,67.87 103.06,67.87 103.17,67.98 103.18,67.98 103.28,68.08 104.56,68.08 104.58,68.06 104.58,68.06 v2(104.9,67.74)
  IN2 w0.127: v2(47.41,68.28) 47.67,68.02 47.67,67.88 47.94,67.61 54.42,67.61 61.51,74.7 69.98,74.7 71.87,76.6 89.5,76.6 92.29,73.81 92.79,73.81 93.41,73.19 93.42,73.19 93.49,73.12 93.49,73.12 93.49,73.11
  BOTTOM w0.076: v2(104.9,67.74) 105.26,67.38 UC1.AR60
  BOTTOM w0.102: JDIMM2.76 46.1,68.87 46.26,68.71 47.03,68.71 47.15,68.82 47.46,68.82 47.68,68.6 47.68,68.54 v2(47.41,68.28)
DDR_B_DQS4: length 71.7
  IN2 w0.076: 91.21,52.47 91.66,52.47 92.01,52.83 99.21,52.83 99.8,53.42 100.5,53.42 102.15,55.06 103.04,55.06 103.26,55.29 104.06,55.29 104.12,55.35 104.5,55.35 104.73,55.58 104.73,55.78 104.81,55.86 v2(104.95,55.86)
  IN2 w0.127: v2(49.7,41.4) 49.8,41.29 49.8,41.05 50.17,40.69 52.18,40.69 52.5,41.01 52.5,41.01 52.63,41.14 53.01,41.14 53.14,41.01 53.14,40.99 53.43,40.7 55.07,40.7 57.51,38.25 57.95,38.25 58.94,37.26 65.82,37.26 68.52,39.96 68.85,39.96 70.34,41.44 70.94,41.44 71.36,41.86 71.36,42.24 71.08,42.52 71.08,42.7 71.73,43.35 71.73,43.74 71.67,43.8 71.67,43.98 71.94,44.25 72.12,44.25 72.18,44.19 72.56,44.19 74.55,46.18 74.75,46.18 79.84,51.26 89.57,51.26 90.78,52.47 91.21,52.47
  BOTTOM w0.076: UC1.AR38 105.26,55.49 104.95,55.81 v2(104.95,55.86)
  BOTTOM w0.102: v2(49.7,41.4) 49.81,41.4 49.91,41.3 49.91,40.81 50.23,40.49 51.15,40.49 51.47,40.8 51.47,40.8 51.82,41.15 51.82,41.16 51.95,41.28 52.04,41.28 52.2,41.12 JDIMM2.179
DDR_B_DQS5: length 73.5
  IN2 w0.076: 92.73,48.6 92.74,48.61 92.77,48.61 92.88,48.72 99.12,48.72 99.78,49.37 100.46,49.37 102.01,50.93 102.01,51.6 102.07,51.66 102.43,52.01 102.54,52.01 103.16,52.64 103.27,52.64 103.36,52.73 103.77,52.73 103.79,52.74 104.4,52.74 104.67,52.48 104.67,52.43 v2(104.9,52.2)
  IN2 w0.127: v2(48.14,36.3) 48.02,36.19 48.02,36.01 48.16,35.88 53.99,35.88 58,31.87 59.57,31.87 60.17,31.27 66.09,31.27 68.17,33.35 69.12,33.35 73.61,37.85 73.61,38.34 82.56,47.3 91.39,47.3 92.57,48.48 92.6,48.48 92.73,48.6
  BOTTOM w0.076: v2(104.9,52.2) UC1.AR32
  BOTTOM w0.102: v2(48.14,36.3) 48.12,36.32 47.97,36.32 47.85,36.2 47.85,35.92 47.63,35.71 46.33,35.71 46.01,36.03 45.86,36.03 45.71,35.87 JDIMM2.200
DDR_B_DQS6: length 76
  IN2 w0.076: v2(104.9,49.45) 105.08,49.45 105.16,49.38 105.16,49.2 105.04,49.07 103.36,49.07 102.77,48.48 102.28,48.48 100.49,46.69 100.49,45.94 100.02,45.47 99.7,45.47 99.07,44.84 96.83,44.84
  IN2 w0.089: 96.21,44.51 96.22,44.52 96.29,44.52 96.3,44.53 96.33,44.53 96.64,44.84 96.83,44.84
  IN2 w0.127: 96.21,44.51 96.09,44.39 96.09,44.32 95.59,43.82 94.01,43.82 93.17,42.99 86.78,42.99 86.47,42.68 86.13,42.68 85.82,42.99 84.53,42.99 77.82,36.28 77.82,35.77 74.46,32.41 74.46,31.06 71.12,27.72 71.12,27.33 71.31,27.14 71.31,26.96 71.04,26.69 70.86,26.69 70.67,26.88 70.28,26.88 69.87,26.47 69.87,26.08 70.06,25.89 70.06,25.71 69.82,25.47 57.57,25.47 56.38,26.67 56.38,26.95 55.78,27.56 55.49,27.56 55.13,27.92 55.13,28.21 54.52,28.81 54.24,28.81 52.81,30.24 50.33,30.24 50.17,30.4 50.17,30.58 v2(50.43,30.84)
  BOTTOM w0.076: v2(104.9,49.45) 105.26,49.09 UC1.AR27
  BOTTOM w0.102: JDIMM2.221 52.25,30.63 52.09,30.78 51.86,30.78 51.37,31.27 50.22,31.27 50.12,31.16 50.12,31.04 50.32,30.84 v2(50.43,30.84)
DDR_B_DQS7: length 79.6
  IN2 w0.076: 97.11,39 99.03,40.92 99.03,42.05 99.9,42.92 100.53,42.92 101.2,43.59 101.2,43.98 103.25,46.04 103.25,46.11 103.33,46.18 104.83,46.18 104.93,46.09 v2(104.93,45.89)
  IN2 w0.127: 97.11,39 97.08,38.96 97.06,38.96 96.93,38.83 96.93,38.81 96.78,38.66 96,38.66 94.98,37.65 92.56,37.65 92.41,37.8 91.6,37.8 91.44,37.64 86.15,37.64 79.13,30.62 79.13,28.47 68.86,18.2 59.69,18.2 58.55,19.35 55.94,19.35 51.83,23.46 51.83,24.19 51.36,24.65 47.92,24.65 47.65,24.93 47.65,25.11 v2(47.38,25.38)
  BOTTOM w0.076: UC1.AR21 104.92,45.78 104.92,45.88 v2(104.93,45.89)
  BOTTOM w0.102: JDIMM2.242 45.73,25.38 45.88,25.53 46.12,25.53 46.56,25.96 47.5,25.96 47.68,25.78 47.68,25.68 v2(47.38,25.38)
DDR_B_DQS#0: length 83.7
  IN2 w0.076: 105.97,75.47 105.99,75.45 105.99,75.41 106.2,75.19 106.2,74.92 107.64,73.49 107.64,72.59 108.35,71.89 108.35,70.53 108.42,70.45 108.57,70.45 v2(108.72,70.6)
  IN2 w0.127: 105.97,75.47 105.72,75.72 105.72,76.28 105.71,76.28 105.71,76.57 104.84,77.44 104.84,78.95 101.82,81.97 98.67,81.97 93.78,86.87 87.33,86.87 86.34,87.86 73.31,87.86 72.58,87.13 72.24,87.13 71.39,87.98 68.2,87.98 67.92,87.69 67.92,87.09 67.79,86.96 67.41,86.96 67.28,87.09 67.28,87.69 67.01,87.97 66.42,87.97 66.15,87.69 66.15,87.09 66.02,86.96 65.64,86.96 65.51,87.09 65.51,87.69 65.24,87.97 64.65,87.97 64.38,87.69 64.38,87.09 64.25,86.96 60.06,86.96 55.49,82.39 55.49,82.3 54.7,81.51 54.41,81.51 51.95,79.05 48.09,79.05 47.96,79.18 47.96,79.34 48.09,79.47 v2(48.17,79.47)
  BOTTOM w0.076: v2(108.72,70.6) 109.09,70.87 UC1.AH66
  BOTTOM w0.102: v2(48.17,79.47) 48.1,79.47 47.88,79.69 47.88,79.84 47.58,80.14 46.44,80.14 46.03,79.72 45.87,79.72 45.72,79.87 JDIMM2.32
DDR_B_DQS#1: length 87.7
  IN2 w0.076: v2(109.64,77.9) 109.88,77.66 110.07,77.66 110.16,77.75 110.16,78.53 110.13,78.56 110.13,78.58
  IN2 w0.127: v2(49.7,84.66) 50.06,84.3 50.06,84.25 50.31,83.99 51.03,83.99 51.06,84.02 51.31,84.02 52.87,85.58 52.87,86.66 54.18,87.97 54.36,87.97 54.48,87.86 54.86,87.86 55.28,88.27 55.28,88.66 55.16,88.78 55.16,88.96 55.43,89.23 55.61,89.23 55.73,89.11 56.11,89.11 56.53,89.53 56.53,89.91 56.41,90.03 56.41,90.21 58.89,92.69 78.96,92.69 79.35,92.29 80.86,92.29 80.87,92.29 103.04,92.29 110.52,84.81 110.52,83.53 110.71,83.34 110.71,80.23 110.72,80.22 110.72,79.65 110.13,79.06 110.13,78.58
  BOTTOM w0.076: UC1.AG69 109.56,72.61 109.45,72.72 109.45,72.73 109.3,72.88 109.22,73.04 109.22,73.33 109.26,73.41 109.26,73.41 109.26,73.62 109.21,73.75 109.21,73.95 109.28,74.1 109.28,75.59 109.06,75.81 109.06,77.5 109.25,77.7 109.43,77.7 v2(109.64,77.9)
  BOTTOM w0.102: v2(49.7,84.66) 50,84.96 50,85.02 50.24,85.26 51.56,85.26 51.69,85.13 JDIMM2.11
DDR_B_DQS#2: length 70.2
  IN2 w0.076: 97.86,76.97 97.87,76.97 97.88,76.96 97.99,76.96 98.04,76.91 98.78,76.91 100.87,74.81 100.92,74.81 101.3,74.43 101.3,73.77 101.71,73.36 102.48,73.36 102.74,73.11 102.74,72.5 102.65,72.41 102.65,71.24 102.86,71.03 104.53,71.03 v2(104.9,71.4)
  IN2 w0.127: v2(49.65,73.99) 49.87,74.22 49.87,74.39 50.15,74.67 51.49,74.67 51.95,74.21 52.2,74.21 52.33,74.34 52.33,74.39 52.6,74.67 53.19,74.67 53.46,74.39 53.46,74.34 53.59,74.21 53.88,74.21 55.05,75.39 55.05,75.67 55.65,76.28 55.94,76.28 56.3,76.64 56.3,76.92 56.91,77.53 57.19,77.53 60.1,80.43 60.1,80.47 60.57,80.94 69.29,80.94 69.64,81.3 92.97,81.3 97.29,76.99 97.66,76.99 97.66,76.98 97.79,76.98 97.81,76.96 97.82,76.97 97.86,76.97
  BOTTOM w0.076: v2(104.9,71.4) 105.26,71.04 UC1.AR66
  BOTTOM w0.102: v2(49.65,73.99) 49.85,73.99 49.95,74.09 49.95,74.42 50.17,74.63 51.7,74.63 51.86,74.47 52.01,74.47 52.16,74.62 JDIMM2.53
DDR_B_DQS#3: length 70.4
  IN2 w0.076: v2(104.9,68.66) 104.49,68.24 103.2,68.24 102.99,68.03 101.81,68.03 100.78,69.07 99.86,69.07 99.13,69.79 99.13,70.3 98.98,70.45 98.98,70.65 98.7,70.94 98.7,71.46 98.39,71.77 95.1,71.77 93.72,73.15 93.72,73.17
  IN2 w0.127: v2(48.17,68.28) 47.92,68.02 47.92,67.98 48.04,67.86 54.32,67.86 61.41,74.95 69.87,74.95 71.77,76.85 89.6,76.85 92.39,74.06 92.89,74.06 93.59,73.37 93.59,73.37 93.67,73.3 93.67,73.29 93.67,73.29 93.67,73.27 93.72,73.22 93.72,73.17
  BOTTOM w0.076: UC1.AR61 105.26,68.29 v2(104.9,68.66)
  BOTTOM w0.102: JDIMM2.74 45.72,69.38 46.02,69.07 46.18,69.07 46.34,68.9 46.95,68.9 47.07,69.01 47.54,69.01 47.87,68.68 47.87,68.58 v2(48.17,68.28)
DDR_B_DQS#4: length 71.6
  IN2 w0.076: v2(104.24,55.91) 104.24,55.93 104.31,56.01 104.44,56.01 104.53,55.91 104.53,55.69 104.39,55.55 104.04,55.55 103.98,55.49 103.18,55.49 102.95,55.26 102.06,55.26 100.42,53.62 99.71,53.62 99.12,53.03 91.93,53.03 91.62,52.72 91.21,52.72
  IN2 w0.127: 91.21,52.72 90.68,52.72 89.47,51.51 79.74,51.51 74.65,46.42 74.45,46.42 72.46,44.44 72.28,44.44 72.22,44.5 71.84,44.5 71.42,44.08 71.42,43.69 71.48,43.64 71.48,43.46 70.83,42.81 70.83,42.42 71.11,42.14 71.11,41.96 70.84,41.69 70.24,41.69 68.75,40.21 68.41,40.21 65.72,37.51 59.04,37.51 58.05,38.5 57.62,38.5 55.17,40.95 53.53,40.95 53.37,41.11 53.37,41.14 53.11,41.39 52.53,41.39 52.25,41.12 52.25,41.11 52.08,40.93 50.27,40.93 50.1,41.1 50.1,41.3 50.24,41.44 50.42,41.44 v2(50.46,41.4)
  BOTTOM w0.076: v2(104.24,55.91) 104.26,55.94 104.37,55.94 104.61,55.7 UC1.AT38
  BOTTOM w0.102: v2(50.46,41.4) 50.36,41.5 50.22,41.5 50.12,41.39 50.12,41.39 50.1,41.37 50.1,40.89 50.31,40.68 51.07,40.68 51.39,40.99 51.39,40.99 51.63,41.23 51.63,41.24 51.87,41.47 52.04,41.47 52.19,41.63 JDIMM2.177
DDR_B_DQS#5: length 73.5
  IN2 w0.076: 92.88,48.45 92.98,48.55 99.19,48.55 99.85,49.21 100.53,49.21 102.18,50.86 102.18,51.53 102.49,51.85 102.6,51.85 103.23,52.48 103.34,52.48 103.43,52.57 103.84,52.57 103.86,52.58 104.34,52.58 104.44,52.47 104.44,52.43 104.44,52.38 v2(104.27,52.2)
  IN2 w0.127: v2(47.38,36.3) 47.49,36.3 47.77,36.02 47.77,35.91 48.06,35.63 53.89,35.63 57.9,31.62 59.47,31.62 60.07,31.02 66.2,31.02 68.28,33.11 69.22,33.11 71.54,35.42 73.86,37.74 73.86,38.24 82.67,47.05 91.49,47.05 92.76,48.31 92.76,48.33 92.88,48.45
  BOTTOM w0.076: v2(104.27,52.2) UC1.AT32
  BOTTOM w0.102: JDIMM2.198 45.7,36.38 45.85,36.22 46.09,36.22 46.41,35.9 47.55,35.9 47.65,36 47.65,36.22 47.55,36.32 47.4,36.32 v2(47.38,36.3)
DDR_B_DQS#6: length 76.1
  IN2 w0.076: 96.83,44.66 96.91,44.66 96.91,44.67 96.98,44.67 96.99,44.68 99.14,44.68 99.77,45.3 100.09,45.3 100.65,45.87 100.65,46.62 102.35,48.32 102.84,48.32 103.43,48.91 104.61,48.91 v2(104.95,48.57)
  IN2 w0.089: 96.83,44.66 96.72,44.66 96.38,44.33
  IN2 w0.127: v2(49.67,30.84) 49.66,30.56 50.23,29.99 52.71,29.99 54.13,28.56 54.42,28.56 54.88,28.1 54.88,27.82 55.39,27.31 55.67,27.31 56.13,26.85 56.13,26.56 57.47,25.23 69.92,25.23 70.31,25.61 70.31,26 70.12,26.19 70.12,26.37 70.39,26.64 70.57,26.64 70.76,26.44 71.14,26.44 71.56,26.86 71.56,27.25 71.37,27.44 71.37,27.62 74.71,30.96 74.71,32.31 78.07,35.67 78.07,36.14 84.67,42.74 85.72,42.74 86.02,42.44 86.58,42.44 86.88,42.74 93.28,42.74 94.11,43.58 95.69,43.58 96.33,44.22 96.33,44.28 96.38,44.33
  BOTTOM w0.076: v2(104.95,48.57) 105.26,48.25 UC1.AR25
  BOTTOM w0.102: JDIMM2.219 52.23,31.12 52.08,30.97 51.94,30.97 51.45,31.46 50.15,31.46 49.93,31.24 49.93,31.04 49.73,30.84 v2(49.67,30.84)
DDR_B_DQS#7: length 79.6
  IN2 w0.076: v2(104.9,46.73) 105,46.63 105,46.52 104.83,46.35 103.26,46.35 103.08,46.18 103.08,46.1 101.03,44.05 101.03,43.66 100.46,43.09 99.83,43.09 98.86,42.11 98.86,40.99 97.1,39.23 97.02,39.23
  IN2 w0.127: 97.02,39.23 97,39.21 96.96,39.21 96.68,38.94 96.68,38.91 95.89,38.91 94.88,37.9 92.67,37.9 92.52,38.05 91.5,38.05 91.33,37.89 86.05,37.89 78.88,30.72 78.88,28.58 68.76,18.45 59.8,18.45 58.65,19.6 56.04,19.6 52.07,23.56 52.07,24.29 51.47,24.9 48.03,24.9 47.9,25.03 47.9,25.25 48.03,25.38 v2(48.14,25.38)
  BOTTOM w0.076: UC1.AR22 104.9,46.71 v2(104.9,46.73)
  BOTTOM w0.102: JDIMM2.240 45.74,25.87 45.9,25.72 46.04,25.72 46.48,26.15 47.58,26.15 47.87,25.86 47.87,25.65 v2(48.14,25.38)
DDR_B_MA0: length 72.3
  IN2 w0.211: v2(46.65,51.51) 45.83,51.51 45.62,51.3 45.62,50.69 45.87,50.44 46.52,50.44 47.12,51.03 50.99,51.03 50.99,51.03 57.23,51.03 58.41,52.21 58.92,52.21 59.13,52.42 59.13,52.67 59.34,52.88 59.77,52.88 59.98,52.67 59.98,52.42 60.19,52.21 67.28,52.21 69.19,54.12 69.19,54.42 68.86,54.75 68.86,55.04 69.15,55.34 69.45,55.34 69.78,55.01 70.08,55.01 75.14,60.07 81.63,60.07 81.83,59.87 86.24,59.87 86.45,60.08 86.45,60.58 86.66,60.79 87.08,60.79 87.29,60.58 87.29,60.08 87.5,59.87 87.92,59.87 88.13,60.08 88.13,60.58 88.34,60.79 88.77,60.79 88.98,60.58 88.98,60.08 89.19,59.87 89.61,59.87 89.82,60.08 89.82,60.58 90.03,60.79 90.45,60.79 90.66,60.58 90.66,60.15 90.87,59.94 91.22,59.94 91.44,60.17 91.44,60.58 91.66,60.79 93.03,60.79 93.14,60.9 97.26,60.9 98.13,60.03 98.13,59.6 97.92,59.39 v2(97.78,59.39)
  BOTTOM w0.076: v2(97.78,59.39) 97.79,59.39 98.34,59.39 98.45,59.28 99.61,59.28 99.84,59.05 101.23,59.05 UC1.BA46
  BOTTOM w0.163: JDIMM2.144 45.64,51.87 46,51.51 v2(46.65,51.51)
DDR_B_MA1: length 74
  IN2 w0.076: 90.57,63.6 90.82,63.85 92.07,63.85 92.54,63.38 92.54,63.1 92.33,62.9 v2(92.26,62.9)
  IN2 w0.211: v2(51.22,54.03) 51.38,54.18 52.59,54.18 52.8,53.97 52.8,53.9 53.01,53.69 53.43,53.69 53.64,53.9 53.64,53.97 53.86,54.18 56.62,54.18 59.35,56.92 59.94,56.92 60.15,57.13 60.15,57.72 60.38,57.95 61.45,57.95 61.79,57.61 62.3,57.61 62.63,57.95 63.14,57.95 63.47,57.61 63.98,57.61 64.32,57.95 65.63,57.95 66.55,58.87 66.55,59.2 66.83,59.48 70.56,59.48 74.68,63.6 76.74,63.6 76.95,63.81 76.95,64.49 77.16,64.7 77.58,64.7 77.8,64.49 77.8,63.81 78.01,63.6 78.43,63.6 78.64,63.81 78.64,64.67 78.85,64.88 79.27,64.88 79.48,64.67 79.48,63.81 79.69,63.6 80.11,63.6 80.33,63.81 80.33,64.67 80.54,64.88 80.96,64.88 81.17,64.67 81.17,63.81 81.38,63.6 81.72,63.6 81.93,63.81 81.93,64.67 82.14,64.88 82.56,64.88 82.77,64.67 82.77,63.81 82.98,63.6 83.32,63.6 83.53,63.81 83.53,64.67 83.74,64.88 84.16,64.88 84.37,64.67 84.37,63.81 84.59,63.6 90.57,63.6
  BOTTOM w0.076: v2(92.26,62.9) 91.82,62.45 91.82,60.76 92.01,60.57 97.37,60.57 98.22,59.72 98.48,59.72 98.59,59.61 99.74,59.61 99.95,59.4 100.51,59.4 100.69,59.58 100.95,59.58 101.07,59.52 101.21,59.52 101.44,59.59 101.58,59.59 101.79,59.51 101.89,59.41 UC1.AY46
  BOTTOM w0.163: JDIMM2.133 52.16,54.62 52.07,54.71 51.1,54.71 50.93,54.55 50.93,54.32 v2(51.22,54.03)
DDR_B_MA2: length 72.9
  IN2 w0.076: v2(94.61,62.9) 94.76,63.04 94.76,63.71 94.44,64.03 93.06,64.03 92.54,64.56 92.25,64.56 91.9,64.91 89.56,64.91 89.36,65.11 88.22,65.11 87.27,66.05
  IN2 w0.211: v2(46.65,54.03) 46.49,54.18 44.74,54.18 44.53,54.39 44.53,55.71 44.85,56.03 45.58,56.03 45.95,55.65 52.95,55.65 54,56.7 57.05,56.7 61.31,60.96 69.96,60.96 75.23,66.23 77.26,66.23 77.38,66.35 86.97,66.35 87.27,66.05
  BOTTOM w0.076: v2(94.61,62.9) 94.61,61.14 94.86,60.9 97.86,60.9 98.56,60.21 99.99,60.21 100.08,60.3 100.39,60.3 100.48,60.21 100.98,60.21 100.98,60.21 101.07,60.24 101.27,60.24 101.3,60.23 101.32,60.21 101.36,60.21 101.37,60.2 101.38,60.2 101.51,60.2 101.52,60.21 101.63,60.21 101.71,60.24 102.08,60.24 102.13,60.19 102.3,60.19 102.47,60.02 UC1.AY47
  BOTTOM w0.163: v2(46.65,54.03) 45.8,54.87 JDIMM2.132
DDR_B_MA3: length 71.9
  IN2 w0.076: v2(92.85,62.9) 92.94,62.9 93.11,63.07 93.11,63.45 93,63.57 92.58,63.57 92,64.15 88.73,64.15 88.41,64.47 87.7,64.47 87.39,64.15 87.27,64.15
  IN2 w0.211: v2(49.7,54.03) 49.7,54.46 49.91,54.67 56.41,54.67 60.61,58.87 61.1,58.87 61.52,59.29 61.52,59.76 61.73,59.97 65,59.97 65.21,59.76 65.21,59.35 65.42,59.14 65.85,59.14 66.06,59.35 66.06,59.76 66.27,59.97 70.35,59.97 74.47,64.09 75.76,64.09 75.97,64.3 75.97,65.04 76.18,65.25 77.67,65.25 77.79,65.37 84.78,65.37 85.08,65.08 85.08,64.3 85.29,64.09 85.71,64.09 85.92,64.3 85.92,64.98 86.13,65.19 86.59,65.19 86.76,65.02 86.76,64.37 86.98,64.15 87.27,64.15
  BOTTOM w0.076: v2(92.85,62.9) 92.85,63.08 92.57,63.35 92.02,63.35 91.65,62.99 91.65,60.47 91.84,60.28 v1(96.03,60.28) 97.42,60.28 98.15,59.56 98.41,59.56 98.52,59.44 99.68,59.44 99.88,59.24 100.77,59.24 UC1.BB46
  BOTTOM w0.163: v2(49.7,54.03) 50.8,55.13 JDIMM2.131
DDR_B_MA4: length 72.3
  IN2 w0.211: v2(94.03,62.9) 94.05,62.92 94.05,62.95 94.34,63.24 94.34,63.57 94.11,63.8 92.97,63.8 92.49,64.28 92.2,64.28 91.93,64.56 89.41,64.56 89.17,64.79 87.84,64.79 86.77,65.86 77.59,65.86 77.46,65.74 75.66,65.74 75.46,65.54 75.46,64.84 75.2,64.58 74.27,64.58 70.16,60.47 61.52,60.47 56.82,55.78 56.43,55.78 56.22,55.57 56.22,55.33 56.06,55.16 54.68,55.16 54.46,55.39 54.46,55.54 54.25,55.76 53.82,55.76 53.61,55.54 53.61,55.39 53.39,55.16 47.89,55.16 47.67,54.94 47.67,54.64 48.17,54.14 v2(48.17,54.03)
  BOTTOM w0.076: v2(94.03,62.9) 94.03,61.02 94.3,60.74 97.61,60.74 v1(97.96,60.39) 98.45,59.9 99.69,59.9 100.02,59.57 100.45,59.57 100.62,59.74 100.99,59.74 101.02,59.73 101.1,59.7 101.22,59.7 101.44,59.76 101.61,59.76 UC1.BA47
  BOTTOM w0.163: v2(48.17,54.03) 48.32,54.03 48.6,54.31 48.6,55.03 48.44,55.2 47.61,55.2 47.39,54.97 47.39,54.59 47.23,54.42 46.9,54.42 46.74,54.59 46.74,55.03 46.57,55.2 46.33,55.2 45.65,55.87 JDIMM2.128
DDR_B_MA5: length 72.9
  IN2 w0.076: v2(96.97,62.9) 96.97,62.96 97.17,63.16 97.31,63.16 98.13,63.98 98.13,64.6 97.59,65.14 92.37,65.14 91.9,65.61 90.57,65.61 90.44,65.74 89.65,65.74 89.56,65.84
  IN2 w0.211: v2(48.17,56.16) 48.17,56.39 47.94,56.62 46.94,56.62 46.75,56.82 46.75,57.03 46.89,57.18 52.4,57.18 53.87,58.65 56.92,58.65 59.14,60.86 59.14,61.28 59.53,61.67 59.94,61.67 61.22,62.95 61.92,62.95 62.92,63.95 67.73,63.95 68.24,63.44 70.35,63.44 74.62,67.7 76.51,67.7 77.19,68.38 87.03,68.38 89.56,65.85 89.56,65.84
  BOTTOM w0.076: v2(96.97,62.9) 96.97,62.5 98.64,60.82 100.6,60.82 100.67,60.89 101.89,60.89 UC1.AY48
  BOTTOM w0.163: v2(48.17,56.16) 47.62,55.61 46.56,55.61 45.8,56.38 JDIMM2.126
DDR_B_MA6: length 71.8
  IN2 w0.076: v2(95.8,62.9) 95.8,63.19 95.88,63.26 96.23,63.26 96.43,63.47 96.43,64.12 96.35,64.2 93.13,64.2 92.61,64.72 92.32,64.72 91.92,65.12 89.85,65.12 89.68,65.3 88.35,65.3 87.47,66.18 87.47,66.55 87.46,66.55
  IN2 w0.211: 87.46,66.55 87.13,66.88 86.67,66.88 86.46,67.09 86.46,67.18 86.25,67.39 85.83,67.39 85.68,67.24 85.68,67.01 85.54,66.87 84.99,66.87 84.78,67.08 84.78,67.18 84.57,67.39 84.14,67.39 83.93,67.18 83.93,67.09 83.72,66.88 83.3,66.88 83.09,67.09 83.09,67.18 82.88,67.39 82.46,67.39 82.25,67.18 82.25,67.09 82.04,66.88 81.61,66.88 81.4,67.09 81.4,67.18 81.19,67.39 80.77,67.39 80.56,67.18 80.56,67.09 80.35,66.88 80.01,66.88 79.8,67.09 79.8,67.18 79.59,67.39 79.17,67.39 78.96,67.18 78.96,67.05 78.75,66.84 78.4,66.84 78.19,67.05 78.19,67.2 78.04,67.35 77.54,67.35 77.27,67.07 77.27,66.93 77.06,66.72 75.02,66.72 70.74,62.44 70,62.44 69.75,62.19 69.75,61.61 69.59,61.45 67.7,61.45 67.43,61.72 67.43,62.33 67.22,62.54 66.73,62.54 66.52,62.33 66.52,61.66 66.31,61.45 61.11,61.45 56.85,57.19 53.79,57.19 52.75,56.15 51.24,56.15 v2(51.22,56.16)
  BOTTOM w0.076: v2(95.8,62.9) 95.8,62.65 95.69,62.54 94.97,62.54 94.78,62.35 94.78,61.34 95.05,61.07 97.93,61.07 98.5,60.49 100.46,60.49 100.58,60.37 100.95,60.37 101.04,60.41 101.06,60.41 101.3,60.41 101.39,60.37 101.6,60.37 101.68,60.4 101.79,60.44 101.86,60.58 101.8,60.73 101.57,60.73 101.5,60.65 UC1.BA48
  BOTTOM w0.163: v2(51.22,56.16) 50.98,56.16 50.89,56.07 50.89,55.97 50.88,55.97 50.88,55.73 51.05,55.57 51.67,55.57 51.84,55.73 51.84,55.93 52.03,56.13 JDIMM2.127
DDR_B_MA7: length 74
  IN2 w0.076: 92.5,66.06 93.22,65.33 97.66,65.33 99.1,63.89 99.1,62.53 99.94,61.69 105.29,61.69 v2(105.56,61.42)
  IN2 w0.089: 90.04,66.06 92.5,66.06
  IN2 w0.211: 90.04,66.06 87.23,68.87 76.99,68.87 76.31,68.19 74.41,68.19 70.58,64.36 68.22,64.36 68.14,64.44 66.54,64.44 66.05,64.93 62.72,64.93 61.77,63.98 60.95,63.98 58.44,61.47 58.44,60.86 57.27,59.7 55.23,59.7 54.68,59.14 53.66,59.14 52.19,57.67 46.17,57.67 45.93,57.43 45.93,56.37 46.14,56.16 v2(46.65,56.16)
  BOTTOM w0.076: UC1.AP48 105.91,60.89 105.55,61.33 105.56,61.42 v2(105.56,61.42)
  BOTTOM w0.163: v2(46.65,56.16) 46.65,56.36 45.64,57.38 JDIMM2.122
DDR_B_MA8: length 69.5
  IN2 w0.076: 87.81,66.9 89.16,65.55 90,65.55 90.19,65.36 91.92,65.36 92.31,64.97 96.97,64.97 97.14,64.8 97.14,63.88 97.17,63.85 97.17,63.53 96.9,63.26 96.81,63.26 96.46,62.9 v2(96.38,62.9)
  IN2 w0.211: v2(49.7,56.16) 49.68,56.18 49.68,56.48 49.89,56.69 52.6,56.69 53.59,57.68 56.64,57.68 61.42,62.46 62.58,62.46 62.91,62.79 62.91,63.25 63.12,63.46 63.42,63.46 63.63,63.25 63.63,62.67 63.84,62.46 64.27,62.46 64.48,62.67 64.48,63.25 64.69,63.46 65.11,63.46 65.32,63.25 65.32,62.67 65.53,62.46 65.95,62.46 66.16,62.67 66.16,63.25 66.37,63.46 67.53,63.46 67.74,63.25 67.74,62.74 67.99,62.49 69.11,62.49 69.56,62.95 70.56,62.95 74.82,67.21 76.71,67.21 77.39,67.89 86.82,67.89 87.81,66.9
  BOTTOM w0.076: v2(96.38,62.9) 96.38,62.85 98.57,60.66 100.53,60.66 100.59,60.6 100.81,60.6 UC1.BB48
  BOTTOM w0.163: JDIMM2.125 50.16,56.62 v2(49.7,56.16)
DDR_B_MA9: length 69.1
  IN2 w0.076: 90.7,66.79 92.58,66.79 93.04,66.32 97.72,66.32 98.08,65.97 98.08,65.41 100.86,62.63 105.2,62.63 v2(105.6,62.22)
  IN2 w0.211: v2(49.7,58.14) 50.22,58.66 51.8,58.66 53.81,60.68 56.26,60.68 61.49,65.91 70.53,65.91 73.88,69.26 74.09,69.26 75.56,70.72 78.46,70.72 79.33,69.86 87.63,69.86 90.7,66.79
  BOTTOM w0.076: UC1.AP50 105.92,61.83 105.6,62.21 v2(105.6,62.22)
  BOTTOM w0.163: JDIMM2.121 50.22,57.62 v2(49.7,58.14)
DDR_B_MA10: length 72.6
  IN2 w0.211: v2(46.65,49.87) 47.32,50.54 50.77,50.54 50.77,50.54 57.53,50.54 58.1,51.11 58.96,51.11 59.2,51.36 59.2,51.68 59.4,51.88 59.79,51.88 60,51.67 60,51.15 60.22,50.94 60.51,50.94 60.86,51.29 61.35,51.29 61.7,50.94 62.2,50.94 62.54,51.29 63.04,51.29 63.39,50.94 63.88,50.94 64.23,51.29 64.73,51.29 65.07,50.94 66.01,50.94 66.22,51.15 66.22,51.52 66.43,51.72 67.48,51.72 75.34,59.58 81.43,59.58 81.63,59.38 91.35,59.38 92.19,60.22 92.22,60.22 93.15,60.22 93.36,60.42 96.27,60.42 96.49,60.2 96.49,59.9 v2(95.87,59.28)
  BOTTOM w0.076: v2(95.87,59.28) 95.87,59.61 95.94,59.69 97.34,59.69 97.41,59.61 97.41,59.14 97.54,59.02 v1(98.32,59.02) 99.63,59.02 99.76,58.88 101.49,58.88 101.73,59.12 102.19,59.12 102.78,59.42 UC1.AW46
  BOTTOM w0.163: JDIMM2.146 45.77,49.38 45.93,49.54 45.93,49.83 45.77,49.99 45.39,49.99 45.23,50.15 45.23,50.48 45.39,50.64 45.88,50.64 46.32,51.08 47.23,51.08 47.39,50.91 47.39,50.47 46.79,49.87 v2(46.65,49.87)
DDR_B_MA11: length 74.4
  IN2 w0.076: 95.9,66.63 96.02,66.5 97.78,66.5 98.24,66.04 98.24,65.48 100.93,62.79 105.3,62.79 105.5,62.59 105.77,62.59 105.83,62.54 106.41,62.54 106.61,62.34 106.61,61.81 v2(106.24,61.44)
  IN2 w0.089: 95.9,66.63 93.79,66.63 93.32,67.1 91.69,67.1 91.33,67.46 90.72,67.46
  IN2 w0.211: v2(48.17,58.14) 48.17,58.43 48.8,59.05 49.61,59.05 49.7,59.15 51.59,59.15 53.61,61.17 56.05,61.17 60.74,65.85 60.74,66.25 61.32,66.83 66.37,66.83 66.8,66.4 70.33,66.4 73.68,69.75 73.89,69.75 75.35,71.21 79.5,71.21 79.71,71 79.71,70.56 79.92,70.35 87.83,70.35 90.72,67.46
  BOTTOM w0.076: v2(106.24,61.44) 106.2,61.44 106.19,61.28 106.53,60.89 UC1.AN48
  BOTTOM w0.163: v2(48.17,58.14) 47.59,57.55 46.3,57.55 45.98,57.87 JDIMM2.120
DDR_B_MA12: length 73.8
  IN2 w0.076: v2(106.22,62.17) 105.91,61.86 100.02,61.86 100.01,61.86
  IN2 w0.089: 90.35,66.44 92.48,66.44 93.41,65.51 97.73,65.51 99.27,63.96 99.27,62.61 100.01,61.86
  IN2 w0.211: 90.35,66.44 87.43,69.36 78.82,69.36 78.61,69.57 78.61,69.88 78.36,70.13 77.94,70.13 77.73,69.92 77.73,69.57 77.52,69.36 77.18,69.36 76.97,69.57 76.97,70.02 76.76,70.23 75.81,70.23 75.6,70.02 75.6,69.71 76.07,69.23 76.07,68.93 75.82,68.68 75.43,68.68 75.06,69.05 74.57,69.05 70.46,64.93 69.98,64.93 69.6,65.31 69.11,65.31 68.73,64.93 68.14,64.93 67.9,65.17 67.46,65.17 67.22,64.93 66.81,64.93 66.32,65.42 61.71,65.42 61.5,65.21 61.5,64.68 61.29,64.47 60.74,64.47 57.95,61.67 57.95,61.06 57.07,60.19 54.99,60.19 54.44,59.63 53.46,59.63 51.99,58.16 51.24,58.16 v2(51.22,58.14)
  BOTTOM w0.076: UC1.AN50 106.54,61.8 v2(106.22,62.17)
  BOTTOM w0.163: v2(51.22,58.14) 51.08,58.14 50.44,58.78 50.44,59.04 50.6,59.2 51.14,59.2 51.65,58.69 51.75,58.69 52.18,58.26 52.2,58.26 52.34,58.13 JDIMM2.119
DDR_B_MA13: length 69.6
  IN2 w0.076: 87.52,54.87 88.78,54.87 89.86,55.95 95.58,55.95 96.69,57.06 v2(96.69,57.41)
  IN2 w0.211: 87.52,54.87 84.38,54.87 84.11,54.6 78.16,54.6 77.57,54.02 76.26,54.02 72.6,50.36 72.6,49.69 67.26,44.36 66.16,44.36 65.95,44.15 65.95,42.56 65.68,42.29 60.73,42.29 60.07,42.95 60.07,45.19 59.51,45.76 51.94,45.76 51.88,45.82 51.83,45.87 51.66,46.04 48.68,46.04 48.17,46.54 v2(48.17,47.26)
  BOTTOM w0.076: UC1.BA43 101.59,57.39 101.35,57.39 101.32,57.38 101.23,57.34 101.12,57.34 100.98,57.39 100.73,57.39 100.72,57.39 100.62,57.39 100.51,57.27 100.07,57.27 99.49,57.85 99.39,57.85 99.22,58.02 98.97,58.02 98.77,57.82 97.1,57.82 v2(96.69,57.41)
  BOTTOM w0.163: v2(48.17,47.26) 48.14,47.26 47.25,46.38 JDIMM2.158
DDR_B_ODT0: length 71.3
  IN2 w0.076: 89.68,56.47 92.05,56.47 93.25,57.67 93.78,57.67 94.38,58.27 95.28,58.27 95.36,58.2 95.36,57.73 95.28,57.66 94.98,57.66 v2(94.62,57.3)
  IN2 w0.211: 89.68,56.47 89.07,55.85 83.97,55.85 83.7,55.58 77.75,55.58 77.49,55.33 76.98,55.33 76.72,55.58 76.35,55.58 71.38,50.61 71.38,50.31 71.45,50.24 71.45,49.94 71.16,49.64 70.86,49.64 70.67,49.83 70.37,49.83 70.13,49.59 70.13,49.29 70.32,49.1 70.32,48.8 70.02,48.5 69.72,48.5 69.54,48.69 69.24,48.69 68.94,48.39 68.94,48.1 69.13,47.91 69.13,47.61 68.83,47.31 68.53,47.31 68.34,47.5 68.05,47.5 67.75,47.2 67.75,46.9 67.93,46.72 67.93,46.42 67.7,46.18 66.98,46.18 66.76,46.39 66.76,46.67 66.55,46.88 66.13,46.88 65.92,46.67 65.92,46.39 65.71,46.18 60.47,46.18 60.26,46.39 60.26,46.56 60.08,46.74 59.55,46.74 59.34,46.95 59.34,47.12 59.13,47.33 58.71,47.33 58.49,47.12 58.49,46.95 58.28,46.74 57.44,46.74 57.22,46.95 57.22,47.12 57.01,47.33 56.59,47.33 56.38,47.12 56.38,46.95 56.17,46.74 53.95,46.74 53.74,46.95 53.74,47.12 53.53,47.33 53.11,47.33 52.89,47.12 52.89,46.95 52.68,46.74 52.35,46.74 52.06,47.02 51.46,47.02 v2(51.22,47.26)
  BOTTOM w0.076: UC1.BA42 101.35,56.96 101.21,56.82 100.95,56.69 100.62,56.69 100.58,56.74 99.84,56.74 99.66,56.92 98.85,56.92 98.81,56.88 94.51,56.88 94.44,56.95 94.44,57.11 v2(94.62,57.3)
  BOTTOM w0.163: v2(51.22,47.26) 51.22,47.03 51.02,46.82 50.16,46.82 49.74,46.41 49.74,46.07 49.87,45.94 50.9,45.94 52.08,47.12 JDIMM2.155
DDR_B_ODT1: length 72.7
  IN2 w0.076: 91.49,55.36 91.54,55.41 98.72,55.41 99.06,55.75 99.06,56.54 99.21,56.69 99.21,57.51 v2(99.09,57.63)
  IN2 w0.211: 91.49,55.36 90.28,55.36 88.66,53.74 84.63,53.74 84.52,53.62 78.56,53.62 77.61,52.67 77.31,52.67 76.95,53.03 76.66,53.03 76.36,52.73 76.36,52.44 76.72,52.08 76.72,51.78 76.42,51.48 76.12,51.48 75.79,51.81 75.5,51.81 75.2,51.51 75.2,51.21 75.53,50.88 75.53,50.58 75.23,50.29 74.93,50.29 74.57,50.64 74.27,50.64 74.01,50.38 74.01,49.72 66.93,42.64 66.93,41.91 65.69,40.67 60.6,40.67 58.37,42.9 58.37,43.2 59.09,43.93 59.09,44.22 58.79,44.52 58.49,44.52 57.77,43.8 57.47,43.8 57.27,44 55.13,44 54.92,44.21 54.92,44.57 54.71,44.78 54.29,44.78 54.08,44.57 54.08,44.21 53.87,44 53.45,44 53.24,44.21 53.24,44.57 53.03,44.78 52.6,44.78 52.39,44.57 52.39,44.21 52.18,44 51.84,44 51.14,44.7 51.14,45 v2(51.22,45.09)
  BOTTOM w0.076: UC1.AW42 102.64,56.96 102.37,57.22 101.99,57.22 101.96,57.19 101.68,57.19 101.6,57.22 101.39,57.22 101.28,57.17 101.06,57.17 101.04,57.19 100.95,57.22 100.75,57.22 100.75,57.22 100.69,57.22 100.54,57.07 100,57.07 99.78,57.3 99.65,57.3 99.32,57.63 v2(99.09,57.63)
  BOTTOM w0.163: JDIMM2.161 51.76,45.63 v2(51.22,45.09)
DDR_B_PAR: length 75.7
  IN2 w0.076: 102.76,58.15 102.77,58.14 105.97,58.14 106.04,58.22 106.04,58.33 105.8,58.57 v2(105.65,58.57)
  IN2 w0.211: 102.76,58.15 101.94,58.15 101.66,58.42 101.66,58.73 101.39,59.01 98.64,59.01 98.43,59.22 98.43,60.55 97.53,61.45 92.96,61.45 92.79,61.28 86.18,61.28 85.97,61.07 85.97,60.7 85.76,60.49 85.35,60.49 85.14,60.7 85.14,61.02 84.92,61.23 84.63,61.23 84.42,61.02 84.42,60.57 84.21,60.36 83.78,60.36 83.57,60.57 83.57,61.02 83.36,61.23 82.94,61.23 82.73,61.02 82.73,60.57 82.52,60.36 82.1,60.36 81.89,60.57 81.89,61.02 81.68,61.23 81.22,61.23 81.01,61.02 81.01,60.77 80.8,60.56 80.38,60.56 80.17,60.77 80.17,61.02 79.96,61.23 79.53,61.23 79.32,61.02 79.32,60.77 79.11,60.56 76.01,60.56 75.75,60.83 75.2,60.83 70.09,55.72 69.76,55.72 69.44,56.04 68.35,56.04 67.77,55.46 67.77,55.14 68.49,54.41 68.49,54.12 68.19,53.82 67.89,53.82 67.16,54.55 66.86,54.55 66.58,54.27 66.58,53.97 67.25,53.3 67.25,53 66.95,52.7 66.32,52.7 65.66,53.36 64.89,53.36 64.52,53.73 64.18,53.73 63.79,53.33 63.34,53.33 62.94,53.73 62.5,53.73 62.1,53.33 61.65,53.33 61.26,53.73 60.81,53.73 60.41,53.33 59.97,53.33 59.57,53.73 59.23,53.73 57.03,51.52 51.23,51.52 v2(51.22,51.51)
  BOTTOM w0.076: v2(105.65,58.57) 105.65,58.57 105.91,58.24 UC1.AP43
  BOTTOM w0.163: v2(51.22,51.51) 51.22,51.96 51.38,52.12 JDIMM2.143
DDR_B_RAS#: length 64.1
  IN2 w0.076: v2(97.05,59.32) 97.05,59.12 96.8,58.88 93.43,58.88 92.47,57.91
  IN2 w0.211: 92.47,57.91 83.11,57.91 82.9,57.7 82.9,57.29 82.68,57.08 75.55,57.08 73.81,55.34 73.2,55.34 68.9,51.04 68.9,50.43 67.94,49.47 66.46,49.47 65.86,48.87 48.74,48.87 v2(48.17,48.31)
  BOTTOM w0.076: v2(97.05,59.32) 97.05,59.28 97.63,58.69 98.47,58.69 98.62,58.84 99.57,58.84 99.7,58.72 101.07,58.72 101.24,58.55 101.65,58.55 101.73,58.48 102.27,58.48 102.4,58.35 102.47,58.35 102.64,58.18 UC1.AW44
  BOTTOM w0.163: v2(48.17,48.31) 47.61,47.75 46.27,47.75 46.15,47.87 JDIMM2.152
DDR_B_WE#: length 63.5
  IN2 w0.076: 92.02,56.77 93.09,57.84 93.65,57.84 94.25,58.44 95.57,58.44 95.65,58.36 95.65,57.61 95.33,57.29 v2(95.21,57.29)
  IN2 w0.211: v2(49.7,48.31) 50.19,47.82 60.17,47.82 60.61,47.37 66.11,47.37 67.23,47.37 75.94,56.09 83.51,56.09 83.77,56.34 88.98,56.34 89.41,56.77 92.02,56.77
  BOTTOM w0.076: UC1.AY44 101.9,58.18 101.8,58.08 101.79,58.08 101.58,58.01 101.44,58.01 101.21,58.07 101.07,58.07 100.95,58.02 100.68,58.02 100.52,58.18 99.53,58.18 99.36,58.35 98.83,58.35 98.63,58.15 96.07,58.15 v1(95.91,57.99) v2(95.21,57.29)
  BOTTOM w0.163: JDIMM2.151 52.15,48.12 51.88,47.85 50.16,47.85 v2(49.7,48.31)
DDR_VTT_CNTL: length 17.1
  TOP w0.102: v2(91.84,78.09) 91.59,78.35 UC2.2
  BOTTOM w0.076: UC1.AW67 102.61,71.63 102.14,71.41 101.29,71.41 101.23,71.47 100.72,71.47 100.5,71.69
  BOTTOM w0.102: 100.5,71.69 100.05,71.69 99.84,71.9 99.84,73.69 99.89,73.74 99.89,75.45 99.56,75.77 96.98,75.77 v1(95.91,76.85) 95.27,77.49 92.45,77.49 v2(91.84,78.09)
DIMM_CHA_SA0: length 5
  TOP w0.102: v2(61.61,20.99) 61.42,20.8 RD4.1 RD1.2
  BOTTOM w0.102: v2(61.61,20.99) 61.61,21.1 61.32,21.4 60.45,21.4 60.43,21.38 JDIMM1.256
DIMM_CHA_SA1: length 7.4
  TOP w0.102: RD2.2 65.46,19.79 RD5.1 64.33,19.79 63.65,20.47 v1(63.27,20.47) 62.89,20.47 62.17,19.75 v2(62.17,19.66)
  BOTTOM w0.102: JDIMM1.260 61.45,20.38 v2(62.17,19.66)
DIMM_CHA_SA2: length 8.2
  TOP w0.102: RD3.2 RD6.1 59.52,42.88 59.94,43.3 v1(60.51,43.3) 62.25,43.3 v2(62.57,43.61)
  BOTTOM w0.102: JDIMM1.166 59.97,43.87 60.14,43.7 62.48,43.7 v2(62.57,43.61)
DIMM_CHB_SA0: length 7.3
  TOP w0.102: RD13.2 51.2,19.83 50.41,20.61 RD16.1 49.33,20.61 v1(49.07,20.87) 48.59,21.35 v2(48.22,21.35)
  BOTTOM w0.102: v2(48.22,21.35) 47.77,21.8 45.87,21.8 45.79,21.87 JDIMM2.256
DIMM_CHB_SA1: length 5
  TOP w0.102: v2(47.36,21.39) 47.36,21.7 v1(47.14,21.93)
  TOP w0.305: v2(47.36,21.39) 47.36,20.89 RD17.1 47.51,20.73 RD14.2
  BOTTOM w0.305: JDIMM2.260 45.52,20.87 45.55,20.85 46.82,20.85 v2(47.36,21.39)
DIMM_CHB_SA2: length 4.5
  TOP w0.305: RD18.1 RD15.2 46.25,43.33 v1(46.3,43.38) 46.65,43.73 v2(46.65,43.97)
  BOTTOM w0.102: JDIMM2.166 46.02,44.38 46.43,43.97 v2(46.65,43.97)
DMIC_CLK: length 2.2
  TOP w0.102: UA1.3 28.79,23.79 L5.2
DMIC_CLK_EDP: length 247.5
  TOP w0.102: L5.1 29.8,26.3 v2(29.87,26.37)
  IN2 w0.127: v2(222.1,36.06) 222.5,36.45 223.72,36.45 225.95,34.22 225.95,33.36 227.79,31.52 227.79,27.41 226.14,25.76 226.14,21.49 222.65,17.99 222.65,13.08 219.2,9.63 177.03,9.63 174.21,6.82 153.58,6.82 150.83,4.07 150.83,3.09 149.86,2.11 134.15,2.11 133.8,2.47 124.41,2.47 123.79,1.84 78.65,1.84 77.87,2.62 48.71,2.62 42.36,8.97 42.36,11.02 37.85,15.53 37.85,16.39 36.69,17.55 36.69,20.75 34.5,22.94 31.07,22.94 30.12,23.89 30.12,26.12 v2(29.87,26.37)
  BOTTOM w0.102: JEDP1.28 222.59,36.55 v2(222.1,36.06) 221.61,36.06 R56.1 221.77,37.04 v1(222.21,37.04)
DMIC_DATA: length 2.5
  TOP w0.102: UA1.2 29.19,23.47 30.04,24.33 30.25,24.33 RA42.2
DMIC_DATA_EDP: length 243
  TOP w0.102: RA42.1 30.46,25.91 v2(30.46,26.36) 30.71,26.61 v1(31.06,26.61)
  IN2 w0.127: v2(30.46,26.36) 30.37,26.27 30.37,24 31.18,23.2 34.61,23.2 36.94,20.86 36.94,17.65 38.1,16.49 38.1,15.64 42.61,11.13 42.61,9.07 48.81,2.88 77.98,2.88 78.76,2.1 123.68,2.1 124.31,2.72 133.9,2.72 134.26,2.37 149.75,2.37 150.58,3.19 150.58,4.17 153.47,7.07 174.11,7.07 176.93,9.89 219.1,9.89 222.4,13.19 222.4,18.1 225.89,21.59 225.89,25.86 227.54,27.51 227.54,31.41 225.7,33.25 225.7,34.12 223.79,36.02 v2(222.7,36.02)
  BOTTOM w0.102: v2(222.7,36.02) 222.73,36.05 JEDP1.29
DRMOS_EN: length 29.4
  TOP w0.254: v2(160.03,84.57) 158.74,85.86 158.74,86.54 158.49,86.79 158.2,86.79 154.1,90.9 154.1,94.45 152.73,95.82 v2(152.73,96.86) 152.73,97.51 151.04,99.21 151.04,102.05 v1(150.64,102.44) 150.64,104.37 149.92,105.09 v2(149.92,105.44)
  BOTTOM w0.254: PU605.12 152.91,96.17 PR655.2 152.85,96.74 v2(152.73,96.86) ; v2(160.03,84.57) 160.03,83.97 160.3,83.7 PU603.12 ; v2(149.92,105.44) PU604.12
E51_TX1: length 3.2
  TOP w0.102: v2(53.8,108.98) 53.55,108.73 v1(53.55,108.54) 53.81,108.28 53.81,107.85 53.93,107.73 53.93,107.28 RW6.2
  BOTTOM w0.102: JWLAN1.36 v2(53.8,108.98)
EC_AGND: length 15.7
  TOP w0.102: v1(152.17,19.26) 151.72,19.71 v2(151.6,19.71)
  TOP w0.508: v2(151.6,19.71) 151.6,19.71 CE1.2 RE4.1 ; RE6.1 CE2.2 148.79,15.1 147.68,16.21 CE21.2 147.86,16.88 RE50.1 148.58,17.51 148.53,17.56 CE25.2 148.32,18.15 v2(148.32,18.77) CE30.2
  IN1 w0.508: v2(148.32,18.77) 148.32,19.64 149.08,20.4 150.91,20.4 v2(151.6,19.71)
  BOTTOM w0.203: v2(148.32,18.77) 148.36,18.73 UE1.112
EC_MUTE#: length 166.2
  TOP w0.102: RA8.2 32.52,24.6 v2(32.35,24.43) 31.92,24.43 31.06,23.56 31.06,22.05 30.78,21.76 UA1.47 ; v2(147.12,11.23) 147.12,10.86 146.6,10.33 145.74,10.33 145.09,10.98 145.09,13.85 145.49,14.24 RE28.1
  IN1 w0.127: v2(32.79,28.48) 32.79,28.44 32.91,28.31 37.83,28.31 42.92,23.22 43.11,23.22 46.57,19.77 46.57,11.38 47.58,10.37 50.99,10.37 51.81,9.55 56.31,9.55 62.73,3.13 80.71,3.13 81.11,2.73 91.44,2.73 93.11,4.4 94.77,4.4 95.98,3.19 108.08,3.19 109.39,4.5 114.74,4.5 115.49,3.75 122.09,3.75 124.12,5.78 126.6,5.78 127.58,6.76 134.58,6.76 139.78,11.96 139.78,13.59 140.15,13.96 141.31,13.96 141.45,13.83 144.85,13.83 145.03,13.64 145.03,10.99 145.5,10.52 145.63,10.52 146.79,10.52 147.12,10.86 v2(147.12,11.23)
  BOTTOM w0.102: RE24.1 152.97,13.65 150.62,13.65 150.2,13.22 150.2,10.89 149.93,10.62 149.48,10.62 149.21,10.89 147.46,10.89 v2(147.12,11.23) ; v2(32.79,28.48) 33.23,28.03 33.23,25.31 v2(32.35,24.43)
EC_MUTE#_R: length 3.8
  TOP w0.102: v2(145.21,15.51) 144.57,14.87 RE28.2 144.57,13.77 v1(144.6,13.75)
  BOTTOM w0.102: v2(145.21,15.51) 145.21,16.02 145.56,16.36 UE1.119
EC_SPI_CLK: length 3.4
  BOTTOM w0.102: 138.46,31.59 v1(138.46,32.26) ; 138.46,31.59 RE33.2 ; 138.46,31.59 138.58,31.7 139.15,31.7 139.28,31.58 139.28,31.26 139.35,31.18 UE1.32
EC_SPI_CS0#: length 3.5
  BOTTOM w0.102: UE1.27 139.42,29.18 139.28,29.04 139.28,28.66 139.13,28.51 RE38.1 138.47,28.17 138.13,27.83 v1(138.13,27.46)
EC_SPI_MISO: length 2.6
  BOTTOM w0.102: UE1.29 139.38,29.98 139.28,30.08 139.28,30.55 139.14,30.69 138.86,30.69 RE35.2
EC_SPI_MOSI: length 2.6
  BOTTOM w0.102: UE1.28 139.43,29.58 139.24,29.77 139.12,29.77 139.02,29.67 139.02,29.18 138.92,29.08 138.78,29.08 RE34.2
EC_WAKE#: length 42.9
  IN1 w0.127: v2(142.36,34.79) 142.12,34.55 140.66,34.55 139.28,33.17 138.99,33.17 137.88,32.05 137.03,32.05 136.8,31.82 135.22,31.82 134.66,31.25 134.5,31.25 131.26,28.01 129.75,28.01 127.5,25.76 119.55,25.76 119.34,25.55 116.19,25.55 115.43,24.79 111.75,24.79 111.13,24.18 108.26,24.18 107.68,23.61 v2(107.36,23.61)
  BOTTOM w0.102: v2(142.36,34.79) 142.83,34.32 142.83,33.93 142.76,33.85 UE1.35 ; RC100.1 107.92,23.06 v2(107.36,23.61)
EDP_AUX: length 2.6
  BOTTOM w0.097: JEDP1.14 223.57,43.55 223.43,43.41 223.27,43.41 223.12,43.55 v3(222.85,43.55) 222.06,43.55 C11.2
EDP_AUX#: length 2.6
  BOTTOM w0.097: C10.2 222.06,43.37 222.53,43.37 222.56,43.33 223.07,43.33 223.19,43.22 223.39,43.22 223.56,43.05 JEDP1.15
EDP_AUX_DN: length 116.6
  IN2 w0.122: v2(120.39,58.62) 120.65,58.89 121.45,58.89 121.66,59.1 122.19,59.1 122.99,58.31 122.99,51.4 123.96,50.42 127.79,50.42 128.3,49.91 128.85,49.91 130.51,48.25 135.37,48.25 136.21,49.08 154.96,49.08 155.89,50.02 163.54,50.02 165.63,47.92 172.46,47.92 174.36,49.83 181.51,49.83 182.92,48.42 189.17,48.42 192.76,44.83 198.6,44.83 201.95,41.48 209.55,41.48 211.33,43.26 219.96,43.26 v2(220.05,43.17)
  BOTTOM w0.097: C10.1 220.45,43.36 220.24,43.36 v2(220.05,43.17) ; UC1.E45 120.39,58.69 v2(120.39,58.62)
EDP_AUX_DP: length 116.6
  IN2 w0.122: v2(220.05,43.75) 219.82,43.51 211.23,43.51 209.45,41.73 202.05,41.73 198.71,45.08 192.86,45.08 189.27,48.67 183.02,48.67 181.61,50.08 174.26,50.08 172.35,48.17 165.74,48.17 163.65,50.26 155.79,50.26 154.85,49.33 136.1,49.33 135.27,48.5 130.61,48.5 128.95,50.16 128.4,50.16 127.89,50.67 124.07,50.67 123.24,51.5 123.24,58.41 122.3,59.35 121.56,59.35 121.35,59.14 120.69,59.14 v2(120.37,59.45)
  BOTTOM w0.097: v2(120.37,59.45) 120.37,59.33 UC1.F45 ; C11.1 220.45,43.56 220.24,43.56 v2(220.05,43.75)
EDP_BKLT_CTRL: length 3.9
  TOP w0.102: v1(218.65,25.24) v2(218.65,24.65) R9.2 219.35,23.34 D3.2
  BOTTOM w0.102: R9.2 v2(218.65,24.65)
EDP_COMP: length 2
  TOP w0.102: v2(121.05,63.1) v1(121.66,63.1)
  TOP w0.254: RC4.2 120.51,63.28 120.87,63.28 v2(121.05,63.1)
  BOTTOM w0.254: UC1.E52 120.75,62.8 v2(121.05,63.1)
EDP_HPD: length 149.9
  TOP w0.102: v2(225.06,45.3) 225.17,45.3 226.23,44.24 226.23,42.54 v1(226.14,42.45) 225.98,42.28 225.64,42.28 225.25,41.9 224.7,41.9 224.2,41.41 RP1.6
  IN1 w0.127: v2(118.45,38.56) 118.45,38.54 118.93,38.05 120.67,38.05 120.91,38.3 124.4,38.3 124.58,38.48 126.05,38.48 130.26,42.69 134.5,42.69 134.87,43.06 134.87,45.94 137.07,48.15 155.11,48.15 159.3,52.34 159.38,52.42 160.98,52.42 161.02,52.47 167.27,52.47 168.23,53.43 171.7,53.43 173.1,53.43 181.17,45.36 181.83,45.36 185.29,41.9 185.29,40.21 185.69,39.81 185.69,34.06 187.22,32.53 187.22,31.3 189.41,29.11 193.8,29.11 194.27,29.58 194.27,30.3 196.96,32.99 196.96,33.34 195.98,34.32 195.98,37.46 198.92,40.4 208.08,40.4 210.81,43.13 215.11,43.13 217.7,45.73 221.99,45.73 222.42,45.3 v2(225.06,45.3)
  BOTTOM w0.102: JEDP1.11 224.81,45.05 v2(225.06,45.3) ; UC1.L10 117.81,38.55 118.44,38.55 v2(118.45,38.56)
EDP_TX0: length 2.6
  BOTTOM w0.097: JEDP1.18 223.41,41.55 223.28,41.68 223.1,41.68 223.07,41.64 222.44,41.64 222.36,41.57 222.04,41.57 C7.2
EDP_TX0#: length 2.6
  BOTTOM w0.097: JEDP1.17 223.47,42.05 223.29,41.86 v3(222.78,41.86) 222.4,41.86 222.29,41.75 222.08,41.75 C6.2
EDP_TX0_DN: length 121.7
  IN2 w0.122: v2(219.64,41.96) 219.86,41.73 220.12,41.73 220.47,42.08 220.47,43.93 220.24,44.17 219.71,44.17 219.56,44.02 217.22,44.02 216.78,44.47 211.41,44.47 209.32,42.37 208.3,42.37 207.75,42.92 201.91,42.92 199.25,45.58 193.07,45.58 189.48,49.17 183.23,49.17 181.82,50.58 174.05,50.58 172.15,48.68 165.95,48.68 163.86,50.77 155.58,50.77 154.64,49.83 135.89,49.83 135.06,49 130.81,49 129.16,50.66 128.61,50.66 128.1,51.17 125.57,51.17 124.29,52.45 124.29,56.69 123.81,57.16 123.81,59.51 124.8,60.5 124.8,60.81 v2(124.59,61.03)
  BOTTOM w0.076: UC1.C47 122.44,60.22 123.06,60.22 123.12,60.17 124.29,60.17 124.71,60.59 124.72,60.59 124.8,60.66 124.8,60.82 v2(124.59,61.03)
  BOTTOM w0.097: v2(219.64,41.96) 219.91,41.69 220.36,41.69 C6.1
EDP_TX0_DP: length 121.8
  IN2 w0.122: v2(125.17,61.03) 125.05,60.91 125.05,60.4 124.06,59.41 124.06,57.27 124.54,56.79 124.54,52.56 125.67,51.42 128.2,51.42 128.71,50.91 129.26,50.91 130.92,49.25 134.96,49.25 135.79,50.08 154.54,50.08 155.48,51.02 163.96,51.02 166.05,48.93 172.04,48.93 173.95,50.83 181.92,50.83 183.33,49.42 189.58,49.42 193.17,45.83 199.35,45.83 202.01,43.17 207.85,43.17 208.4,42.62 209.21,42.62 211.31,44.72 216.88,44.72 217.32,44.27 219.46,44.27 219.6,44.42 220.34,44.42 220.72,44.04 220.72,41.98 220.23,41.48 219.74,41.48 v2(219.64,41.38)
  BOTTOM w0.076: v2(125.17,61.03) 124.96,60.82 124.96,60.59 124.79,60.42 124.78,60.42 124.36,60 123.05,60 122.99,60.06 122.64,60.06 UC1.C46
  BOTTOM w0.097: v2(219.64,41.38) 219.76,41.5 220.53,41.5 C7.1
EDP_TX1: length 2.7
  BOTTOM w0.097: JEDP1.21 223.51,40.05 223.41,40.15 223.1,40.15 223.07,40.12 222.56,40.12 222.27,39.84 222.09,39.84 C9.2
EDP_TX1#: length 2.7
  BOTTOM w0.097: C8.2 222.03,40.02 222.19,40.02 222.51,40.34 v3(222.78,40.34) 223.35,40.34 223.56,40.55 JEDP1.20
EDP_TX1_DN: length 127.2
  IN2 w0.122: v2(219.41,40.34) 219.41,40.22 219.76,39.87 220.05,39.87 220.62,40.44 220.62,41.17 221.22,41.77 221.22,44.88 220.5,45.6 217.5,45.6 217.12,45.22 211.1,45.22 209.56,43.67 202.22,43.67 198.73,47.17 193.51,47.17 190.76,49.92 183.54,49.92 182.13,51.33 173.74,51.33 171.83,49.43 166.26,49.43 164.17,51.52 155.27,51.52 154.86,51.11 140.8,51.11 140.27,50.58 135.58,50.58 134.75,49.75 131.13,49.75 129.47,51.41 128.97,51.41 128.35,52.03 125.77,52.03 125.04,52.76 125.04,59.29 126.01,60.26 126.01,60.78 v2(125.75,61.03)
  BOTTOM w0.076: v2(125.75,61.03) 125.96,60.82 125.96,60.21 124.85,59.09 123.37,59.09 123.25,59.15 123.1,59.15 122.91,59.09 122.77,59.09 122.63,59.14 122.57,59.17 122.47,59.26 122.47,59.46 122.29,59.64 121.93,59.64 121.85,59.72 UC1.D46
  BOTTOM w0.097: v2(219.41,40.34) 219.41,40.2 219.8,39.81 220.26,39.81 C8.1
EDP_TX1_DP: length 127.1
  IN2 w0.122: v2(126.34,61.03) 126.26,60.95 126.26,60.15 125.29,59.18 125.29,52.87 125.88,52.28 128.46,52.28 129.07,51.66 129.57,51.66 131.23,50 134.65,50 135.48,50.83 140.17,50.83 140.69,51.36 154.75,51.36 155.16,51.77 164.27,51.77 166.36,49.68 171.73,49.68 173.64,51.58 182.23,51.58 182.38,51.44 183.64,50.17 190.86,50.17 193.62,47.42 198.83,47.42 202.32,43.92 209.45,43.92 211,45.47 217.02,45.47 217.4,45.85 220.61,45.85 221.47,44.98 221.47,41.67 220.87,41.06 220.87,40.34 220.16,39.62 v2(219.42,39.62)
  BOTTOM w0.076: v2(126.34,61.03) 126.13,60.82 126.13,60.14 124.92,58.93 123.33,58.93 123.21,58.99 123.13,58.99 122.93,58.93 122.74,58.93 122.36,59.06 122.12,59.06 121.92,59.12 121.87,59.34 121.94,59.44 122.04,59.47 122.17,59.39 UC1.C45
  BOTTOM w0.097: C9.1 220.63,39.62 v2(219.42,39.62)
EDP_VDD_EN: length 160.2
  TOP w0.102: v2(113.36,2.62) 113.37,2.62 113.37,3.76 111.72,5.41 111.72,9.49 112.13,9.9 114.09,11.86 114.09,18.27 v1(115.65,19.83) 116.05,20.22 v2(116.05,20.65)
  IN1 w0.127: v2(220.1,20.44) 217.58,20.44 215.87,18.73 194.79,18.73 192.87,20.64 187.98,20.64 187.48,20.14 187.48,19.82 185.09,17.42 172.81,17.42 168.91,13.53 166.75,13.53 163.91,10.69 162.73,10.69 154.14,2.1 125.7,2.1 125.32,2.47 124.41,2.47 123.79,1.84 114.14,1.84 v2(113.36,2.62)
  IN2 w0.142: v2(114.86,39.83) 114.92,39.83 115.42,39.33 115.42,38.29 116,37.71 116,34.77 116.29,34.48 116.29,32.81 115.95,32.47 115.95,29.79 115.72,29.57 115.72,24.84 115.89,24.68 115.89,23.41 116.53,22.76 116.53,21.16 116.05,20.67 v2(116.05,20.65)
  BOTTOM w0.102: D4.2 220.1,21.04 v2(220.1,20.44) ; v2(114.86,39.83) 114.86,40.38 UC1.U13
EDRAM_OPIO_RCOMP: length 10.4
  TOP w0.102: v2(126.2,74.63) 125.39,73.82 v1(122.13,73.82) 120,73.82 119.16,72.98 v2(119.16,71.75)
  BOTTOM w0.076: v2(126.2,74.63) 126.64,75.06 RC121.1 ; UC1.H66 118.87,71.46 v2(119.16,71.75)
EMMC_RCOMP: length 4
  BOTTOM w0.076: RC8.1 105.07,31.4 v1(105.07,31.59) 105.07,33.5 UC1.AT1
EN_0.6VSP: length 5.2
  BOTTOM w0.102: v1(91.33,110.89) 91.33,109.49 90.88,109.03 PR202.2
  BOTTOM w0.203: PU200.7 89.77,107.07
  BOTTOM w0.254: 89.77,107.07 90.74,108.03 PC203.1 PR202.2
EN_1.0V_VCCST_ON: length 7.4
  TOP w0.102: RZ9.1 138.97,38.51 v1(139.15,38.33)
  TOP w0.254: RZ9.1 137.17,38.51 DZ5.2 137.02,38.66 135.53,38.66 135.2,38.33 RZ1.2 CZ1.1 134.88,37.15 134.6,36.87 134.11,36.87 133.81,37.17 UZ1.3
EN_1.2V: length 3.4
  TOP w0.102: v2(90.09,106.67) v1(90.73,106.67)
  BOTTOM w0.203: PU200.8 89.9,106.67
  BOTTOM w0.254: 89.9,106.67 v2(90.09,106.67) 90.51,106.25 PR201.2 PC202.1
EN_1.8VALW: length 3.2
  BOTTOM w0.254: PR501.2 PR502.2 PC502.1 161.75,32.84 161.75,33.74 161.55,33.95 PU500.5
EN_2.5V: length 1.3
  BOTTOM w0.102: v1(54.31,10.62) PC805.1
EN_3V: length 3
  BOTTOM w0.102: v1(178.07,39.6) PR121.1
  BOTTOM w0.254: PU100.12 176.02,40.56 176.36,40.22 176.55,40.22 177.06,39.71 PR121.1
EN_5V: length 3.4
  BOTTOM w0.254: PR120.1 180.87,29.38 180.36,29.88 178.97,29.88 178.71,30.14 PU102.12
EN_+1VALW: length 5.1
  TOP w0.102: v2(152.14,40.82) v1(152.14,40.1)
  BOTTOM w0.254: PR301.2 PC304.1 PR302.1 153,40.4 152.58,40.82 v2(152.14,40.82) 152,40.68 151.59,40.68 151.47,40.81 PU300.11
EN_+VCCEOPIO: length 4.1
  TOP w0.102: v2(102.24,111.5) v1(102.24,112.11)
  BOTTOM w0.254: PC1204.1 102.97,112.4 PR1205.1 PR1204.1 102.95,111.5 v2(102.24,111.5) PU1200.5
ENLDO_3V5V: length 16.7
  IN2 w0.254: v2(178.67,39.48) 178.96,39.18 178.96,33.26 179.74,32.48 179.74,30.66 179.86,30.54 v2(179.86,30.52)
  BOTTOM w0.254: v2(179.86,30.52) 179.79,30.45 179.43,30.45 179.16,30.71 PU102.11 ; PU100.11 176.47,40.81 176.61,40.66 177.62,40.66 178.67,39.62 v2(178.67,39.48) 178.9,39.71 178.9,41.31 PR102.1 PR103.1
EOPIO_RCOMP: length 12
  TOP w0.102: v2(125.62,74.63) 125.14,74.15 v1(124.42,74.15) 120,74.15 118.75,72.9 118.75,71.14 119.21,70.68 v2(119.21,70.67)
  BOTTOM w0.076: v2(119.21,70.67) 118.87,70.33 UC1.H65 ; v2(125.62,74.63) 126.07,74.18 RC122.1
FAN1_PWM: length 79.5
  TOP w0.102: ZT14.1 148.74,31.51 147.9,31.51 v2(147.48,31.09) ; v2(182.61,53.69) 182.78,53.52 R50.1
  IN2 w0.127: v2(187.26,38.56) 186.82,38.13 186.82,37.63 186.96,37.48 186.96,30.53 184.23,27.8 184.23,26.49 183.48,25.74 181.85,25.74 179.38,23.26 175.15,23.26 174.33,24.08 169.82,24.08 166.07,27.83 157.02,27.83 156.1,28.74 156.1,31.26 155.09,32.28 153.14,32.28 151.85,30.99 149.94,30.99 149.42,31.51 147.89,31.51 147.48,31.1 v2(147.48,31.09)
  BOTTOM w0.102: v2(187.26,38.56) 187,38.82 187,39.74 187.09,39.83 187.09,44.85 186.58,45.36 186.58,50.39 185.27,51.71 184.57,51.71 JFAN1.2 183.45,52.85 v2(182.61,53.69) ; UE1.47 147.56,31.17 v2(147.48,31.09)
FAN1_TACH: length 62.1
  TOP w0.102: v2(145.14,34.33) 145.07,34.25 CE28.1 RE13.1 145.07,31.31 145.63,30.75 ZT15.1 ; R55.2 183.21,56.01 D8.2 v2(181.77,56.02)
  IN1 w0.127: v2(145.14,34.33) 145.14,34.07 145.37,33.84 145.73,33.84 146.39,34.5 149.58,34.5 149.82,34.74 154.34,34.74 154.9,34.18 157.22,34.18 158.39,35.35 158.39,37.12 160.71,39.45 160.71,42.47 159.81,43.37 159.81,47.03 161.56,48.79 167.64,48.79 168.87,50.01 168.87,50.31 169.79,51.23 v2(171.13,51.23)
  IN2 w0.127: v2(181.77,56.02) 175.56,56.02 171.13,51.59 v2(171.13,51.23)
  BOTTOM w0.102: UE1.40 144.76,33.94 145.14,34.32 v2(145.14,34.33)
FB_1.2V: length 6
  BOTTOM w0.102: PR207.1 v1(90.04,112)
  BOTTOM w0.203: PU200.6 89.51,107.47 89.69,107.65
  BOTTOM w0.254: PC214.1 90.04,110.8 PR207.1 ; PC214.1 90.87,109.93 PR204.1 ; PC214.1 89.69,109.59 89.69,107.65
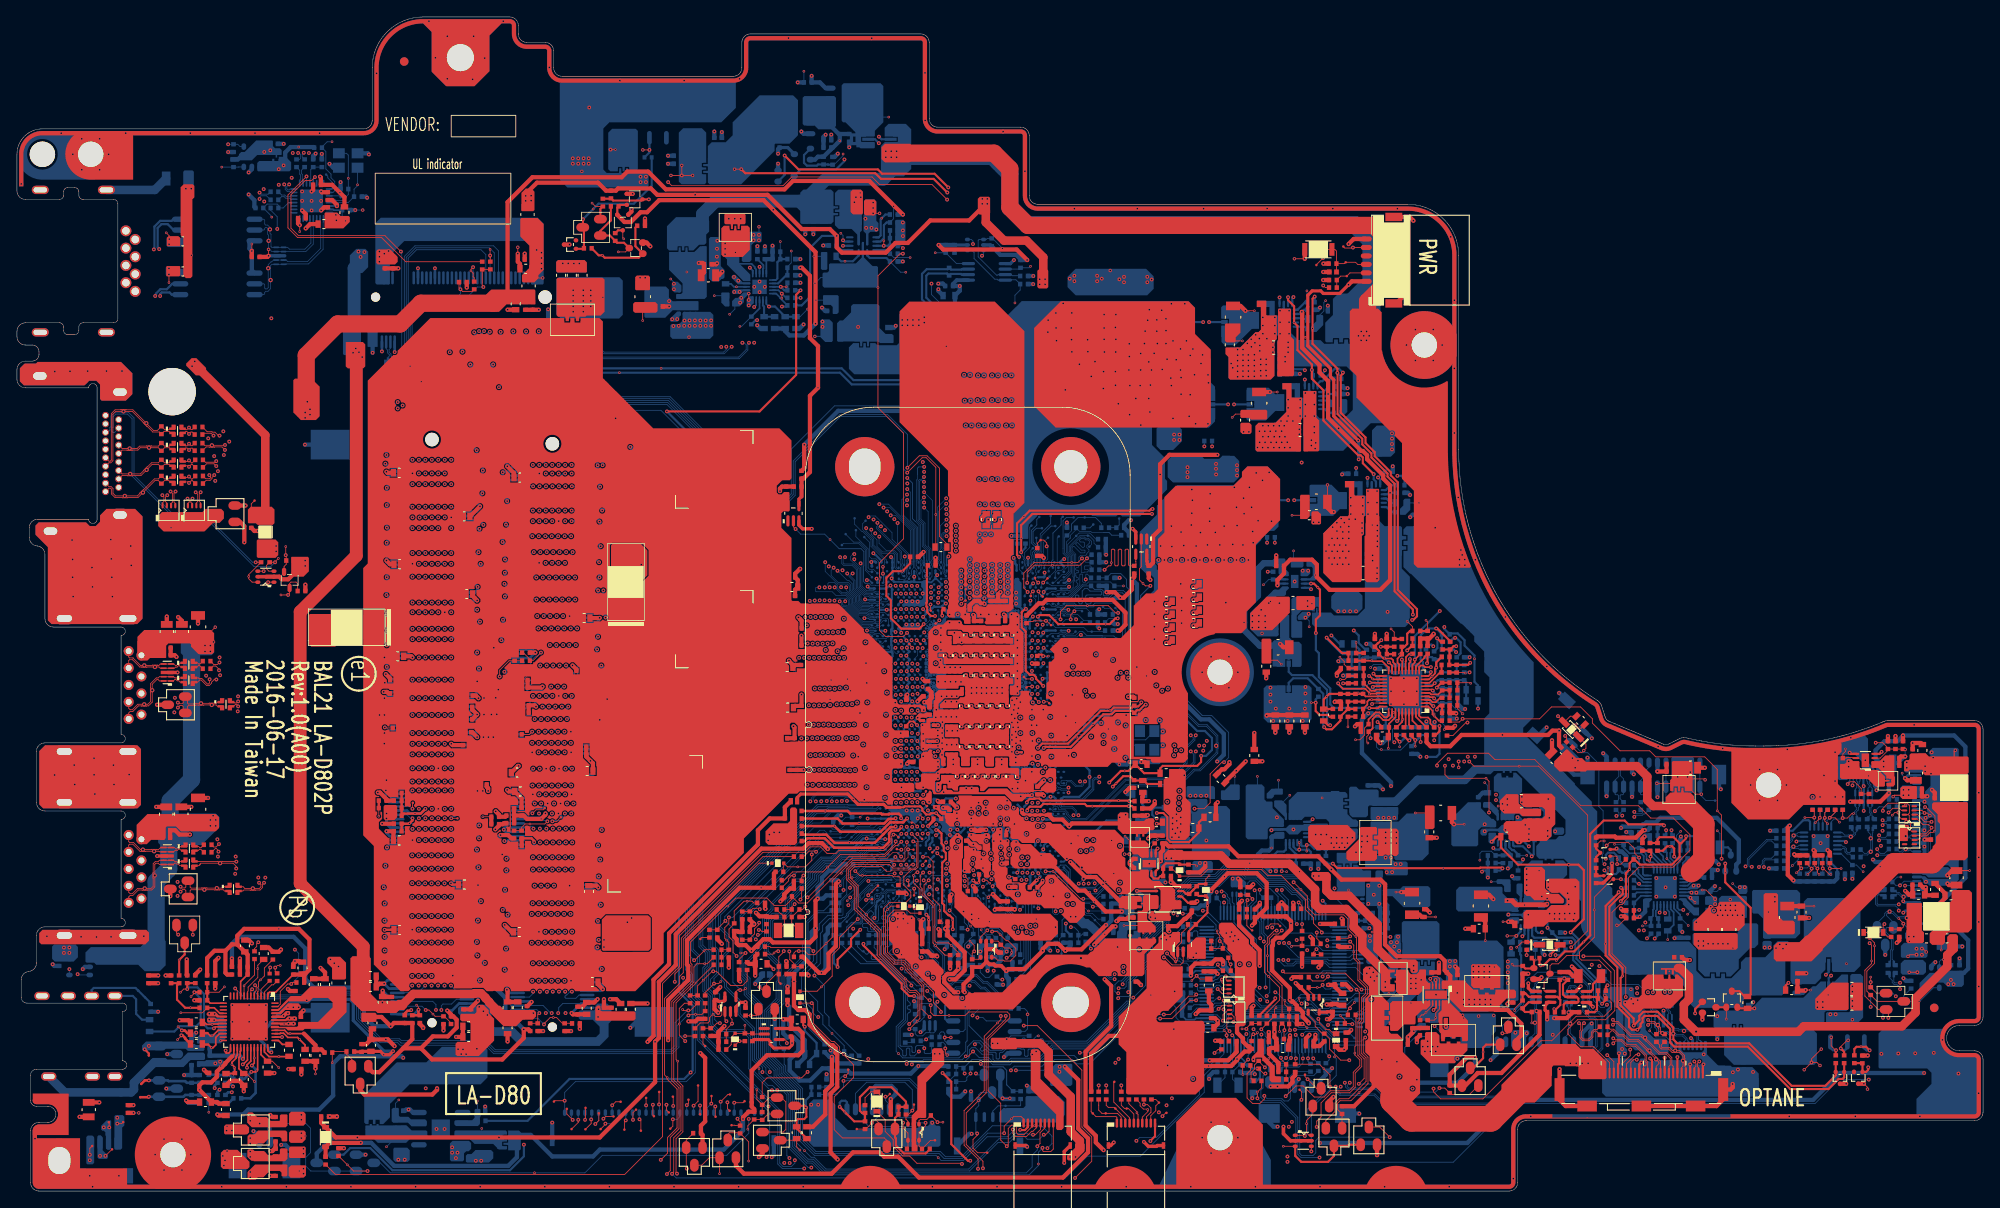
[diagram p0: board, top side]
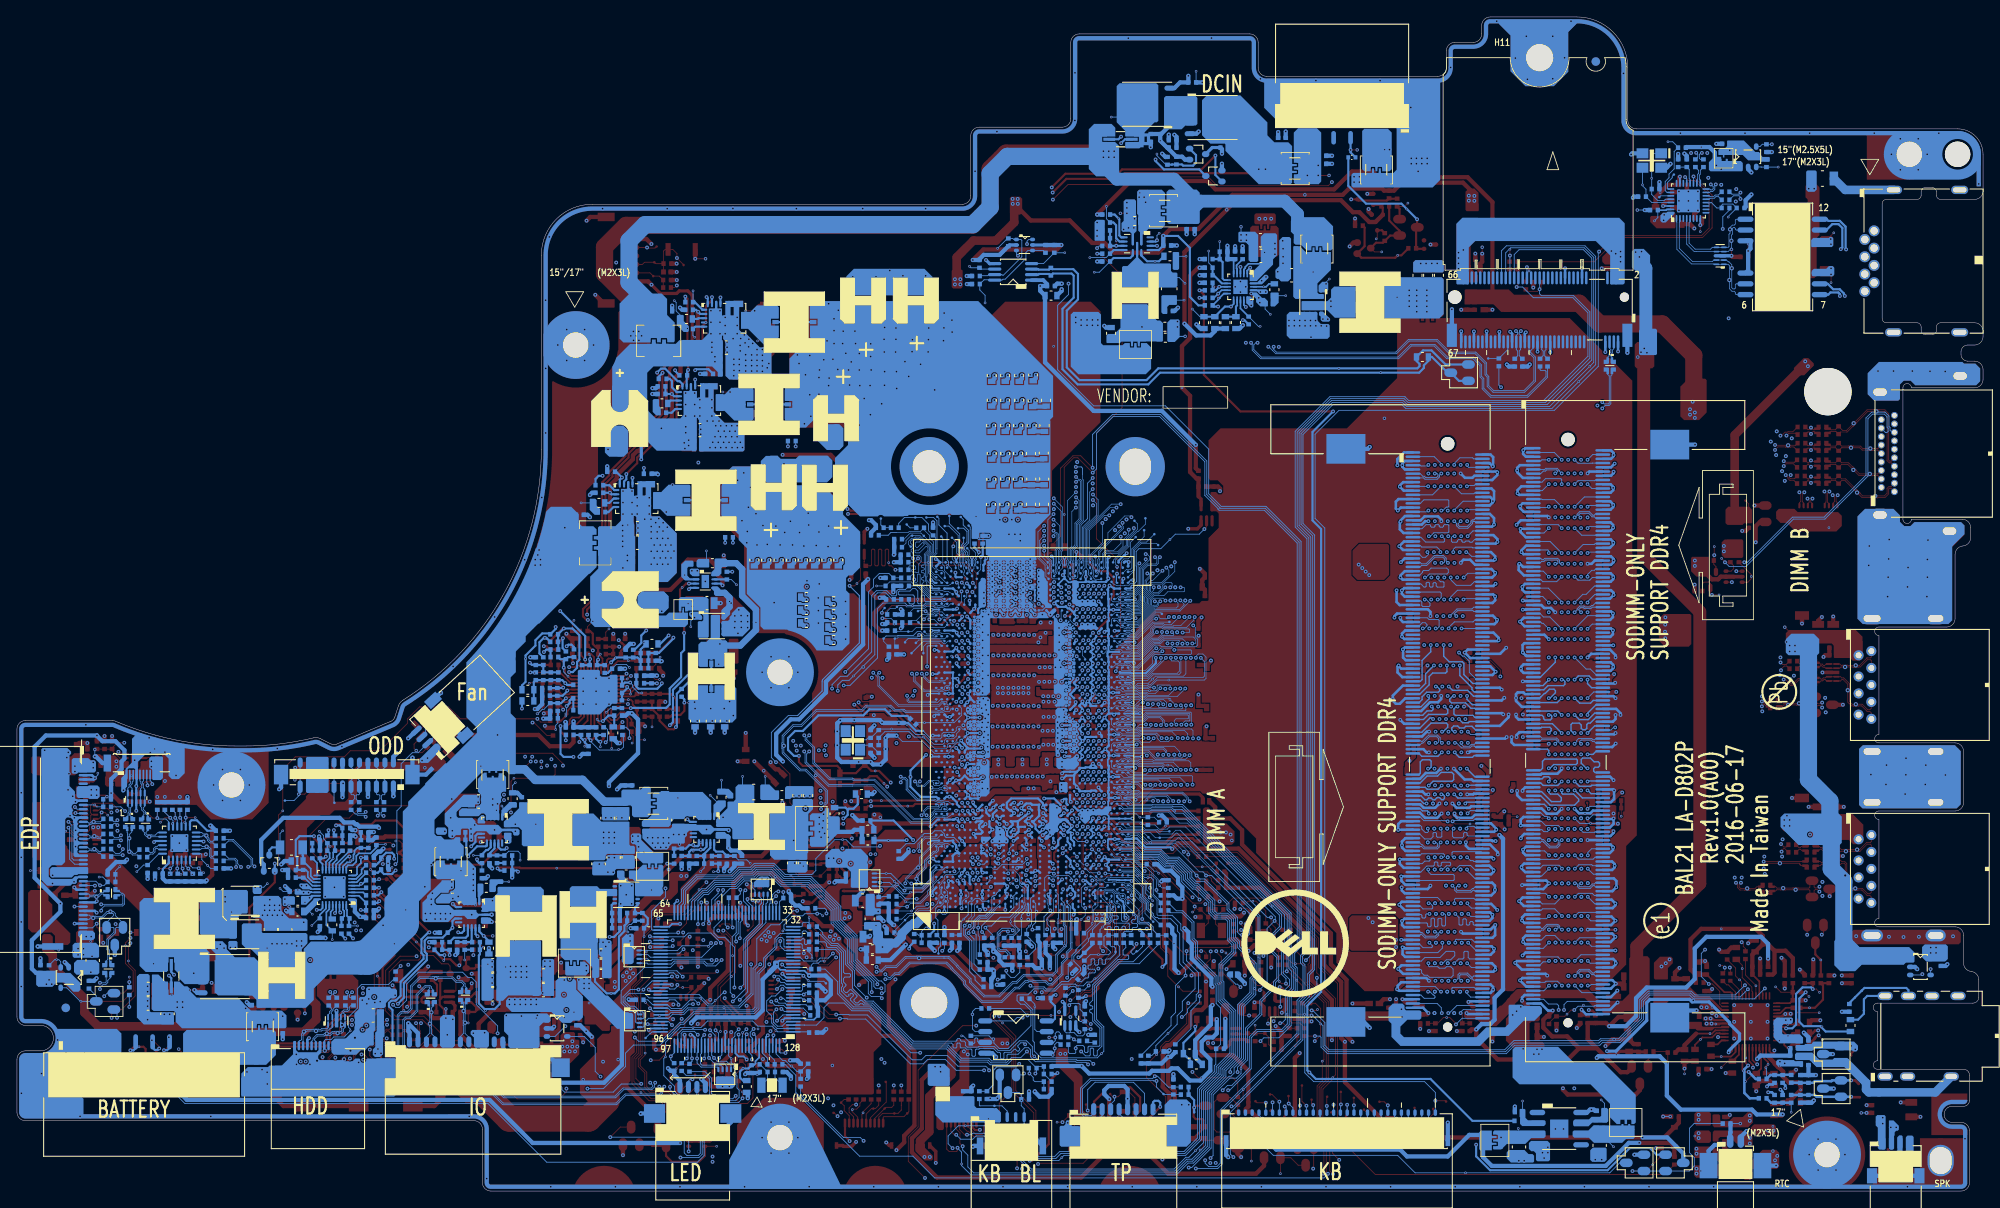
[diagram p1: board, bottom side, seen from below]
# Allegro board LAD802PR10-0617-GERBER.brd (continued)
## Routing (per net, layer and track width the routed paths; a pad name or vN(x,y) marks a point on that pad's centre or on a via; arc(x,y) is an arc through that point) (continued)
FB_1.8VALW: length 5.4
  BOTTOM w0.102: PR505.1 v1(157.93,30)
  BOTTOM w0.254: PU500.6 158.69,33.76 159.01,33.44 PC503.2 158.15,32.79 PR504.1 158.11,32.8 157.5,32.19 157.5,31.47 157.93,31.03 PR505.1
FB_+1VALW: length 4.8
  BOTTOM w0.102: v1(151.28,37.67) 150.84,38.11 PC309.2
  BOTTOM w0.254: PR309.1 150.84,39.76 150.12,40.49 PU300.14 ; PR309.1 150.86,39.53 PR310.1 ; PR309.1 PC309.2
FB_IA: length 7.2
  TOP w0.102: v1(163.98,67.2) 164.6,66.58 PR650.1
  TOP w0.203: PU602.17 163.02,61.46 163.02,62.14 162.83,62.33 162.83,62.81 PR648.2
  TOP w0.254: PR648.2 163.35,64.2 PR645.2 163.65,64.21 163.98,64.53 163.98,65.74 164.3,66.06 PR650.1
FB_VSA: length 4.5
  TOP w0.203: PU602.25 160.29,59.16 160.14,59.01 159.74,59.01 158.84,59.9 PR649.1
  TOP w0.254: PR649.1 158.84,59.91 PR646.1 PR652.1
FCCM_GT: length 53.1
  TOP w0.203: v2(166.77,61.81) 166.77,61.8 166.07,61.8 165.88,61.99 165.6,61.99 165.39,61.79 PU602.11
  TOP w0.254: v2(153.07,105.52) 152.81,105.26 v1(152.81,101.76) 152.81,99.95 155.75,97.01 v2(155.75,96.51) 155.76,96.5 155.76,91.66 158.68,88.74 158.68,88.08 159.76,87 159.76,86.54 161.66,84.64 161.66,84.28 162.49,83.44 162.49,70.76 164.65,68.6 v2(164.65,68)
  IN2 w0.254: v2(166.77,61.81) 166.77,61.98 166.88,62.09 166.88,62.64 165.76,63.77 165.76,64.12 165.06,64.82 165.06,67.59 v2(164.65,68)
  BOTTOM w0.254: PR671.2 156.2,96.06 v2(155.75,96.51) ; PR664.2 v2(153.07,105.52)
FCCM_IA: length 29.8
  TOP w0.203: v2(160,61.03) 160.27,60.76 PU602.21
  IN2 w0.254: v2(160,61.03) 161.17,61.03 162.3,62.16 162.3,63.19 163.41,64.29 163.41,70.21 161.47,72.14 161.47,83.02 v2(162.82,84.37)
  BOTTOM w0.254: v2(162.82,84.37) 163.29,84.37 163.66,84 PR659.2
FCCM_VSA: length 24.7
  TOP w0.102: v2(159.84,57.45) 159.95,57.56 PU602.29
  IN2 w0.254: v2(159.84,57.45) 159.84,57.45 159.42,57.45 158.62,58.25 156.5,58.25 154.02,60.73 154.02,64.25 149.44,68.83 149.44,72.03 148.41,73.06 v2(147.53,73.06)
  BOTTOM w0.254: PR679.2 v2(147.53,73.06)
FW_UPDATE: length 163.2
  TOP w0.102: v2(107.66,22.52) 107.51,22.52 106.96,23.06 106.96,24.27 104.99,26.23 104.99,26.54 104.53,27 103.54,27 102.45,28.09 102.45,32.97 v1(102.7,33.23) 103.09,33.61 DX3.2 ; v2(215.94,48.01) 216.21,48.28 216.74,48.28 217.53,47.49 RX13.2 RX10.2
  IN1 w0.127: v2(169.37,50.18) 169.37,50.16 167.75,48.53 161.67,48.53 160.06,46.93 160.06,43.52 160.99,42.59 160.99,39.26 158.8,37.07 158.8,35.18 156.97,33.36 153.56,33.36 152.46,34.46 150.17,34.46 149.3,33.58 144.8,33.58 144.62,33.76 142.8,33.76 142.53,34.04 v2(142.38,34.04) 141.45,34.04 140.06,32.65 139.2,32.65 138.09,31.54 137.24,31.54 137.01,31.31 135.44,31.31 134.01,29.88 134.01,29.19 132.32,27.5 129.96,27.5 127.78,25.32 127.78,20.93 125.91,19.06 118.52,19.06 117.75,19.83 112.03,19.83 109.11,22.75 107.91,22.75 107.65,22.5 107.65,22.52 v2(107.66,22.52)
  IN2 w0.127: v2(215.94,48.01) 214.5,49.45 212.29,49.45 211.18,48.33 211.18,46.37 209.24,44.43 202.53,44.43 199.04,47.92 194.49,47.92 191.73,50.68 189.71,50.68 187.85,52.53 186.71,52.53 186.27,52.09 173.43,52.09 171.52,50.18 v2(169.37,50.18)
  BOTTOM w0.102: J3D1.8 216.19,48.42 216.01,48.24 216.01,48.08 v2(215.94,48.01) ; v2(142.38,34.04) 142.36,34.02 UE1.34
FW_UPDATE_PCH: length 5.5
  TOP w0.102: DX3.1 105.67,33.61 v2(105.9,33.38)
  BOTTOM w0.076: v1(106.38,32.02) 105.9,32.51 v2(105.9,33.38) 106.1,33.38 106.33,33.61 106.33,35.78 UC1.AP5
GPP_B23: length 12.3
  TOP w0.102: RC39.1 109.48,27.83 v1(108.34,28.97) 108.03,29.28 108.03,33.67 106.76,34.94 106.76,35.68 106.55,35.89 106.55,37.24 v2(106.88,37.57)
  BOTTOM w0.076: UC1.AM7 106.88,37.45 v2(106.88,37.57)
GPP_C5: length 5.5
  BOTTOM w0.076: RC38.1 115.44,29.86 115.05,30.25 114.43,30.25 114.08,30.6 114.08,30.9 114.7,31.53 v1(114.7,31.77) 114.7,32.07 113.33,33.44 UC1.W1
GPU_B+:
  vias: v2(148.98,103.85) v2(148.98,102.49) v2(148.98,101.13) v2(149.58,98.42) v2(149.58,97.83) v2(149.93,100.12) v2(149.93,99.54) v2(149.93,98.95) v2(150.05,103.85) v2(150.05,102.49) v2(150.05,101.13) v2(151.96,94.14) v2(151.96,92.78) v2(151.96,91.42) v2(152.67,88.58) v2(152.67,87.94) v2(153.03,94.14) v2(153.03,92.78) v2(153.03,91.42) v2(153.02,90.15) v2(153.02,89.45) v2(153.19,88.26) v4(153.12,87.58)
GT1N: length 61.8
  IN2 w0.254: v2(169.63,65.26) 169.1,64.73 167.3,64.73 166.58,65.45 166.58,70.84 164.76,72.65 164.76,78.49 165.18,78.9 165.18,86.51 163.51,88.19 163.51,90.86 156.59,97.78 150.35,97.78 147.73,95.17 146.41,95.17 144.42,93.18 143.86,93.18 143.76,93.28 143.33,93.28 v2(142.85,92.8)
  BOTTOM w0.254: PR670.1 169.35,65.14 169.35,65.14 169.47,65.26 v2(169.63,65.26) 169.76,65.26 170.28,64.74 170.28,63.43 169.82,62.97 PR673.1 ; PL605.2 v2(142.85,92.8)
GT1P: length 66.4
  IN2 w0.254: v2(143.56,92.8) 144.58,92.8 146.57,94.79 147.89,94.79 150.5,97.4 156.43,97.4 163.13,90.71 163.13,88.03 164.8,86.35 164.8,79.06 164.38,78.64 164.38,72.49 166.2,70.68 166.2,65.29 167.06,64.44 v2(167.06,64.27) 170.45,60.87 170.45,58.79 v2(172.33,56.91)
  BOTTOM w0.254: v2(167.06,64.27) 167.09,64.27 167.09,64.22 166.86,64.45 166.5,64.45 166.2,64.15 PR675.1 ; PL605.3 v2(143.56,92.8) ; PR674.2 v2(172.33,56.91)
GT2N: length 64.7
  TOP w0.254: v2(167.5,65.21) 167.92,64.8 PR666.1
  IN2 w0.254: v2(139.91,102.51) 140.46,101.96 141.12,101.96 144.64,105.48 147.46,105.48 148.43,104.51 151.44,104.51 156.43,99.52 156.43,98.48 163.89,91.02 163.89,88.35 165.56,86.67 165.56,78.75 165.15,78.33 165.15,72.81 166.96,70.99 166.96,67.48 167.88,66.56 167.88,65.59 v2(167.5,65.21)
  BOTTOM w0.254: PR677.2 167.54,64.05 167.54,65.17 v2(167.5,65.21) ; PL604.2 v2(139.91,102.51)
GT2P: length 70
  IN2 w0.254: v2(140.61,102.51) 144,105.9 147.58,105.9 148.57,104.91 151.58,104.91 156.81,99.68 156.81,98.64 164.27,91.18 164.27,88.5 165.95,86.83 165.95,78.59 165.53,78.17 165.53,72.97 167.34,71.15 167.34,67.64 168.36,66.62 v2(168.36,66.53)
  BOTTOM w0.254: v2(168.36,66.53) 168.36,66.31 PR668.1 169.1,65.78 169.95,65.78 170.75,64.98 170.75,64.34 171.91,63.18 v1(171.91,62.79) 171.91,60.07 172.33,59.64 PR667.2 ; PL604.3 v2(140.61,102.51)
GT_SNUB1: length 1.7
  TOP w0.102: v1(143.34,91.27) 143.73,91.65 PC678.1
GT_SNUB2: length 0.9
  TOP w0.102: 143.68,100.28 v1(144.55,100.28)
GT_SW1: length 2.1
  TOP w0.102: v2(147.78,94.26) v1(148.65,94.26)
  TOP w0.508: PR676.1 v2(147.78,94.26)
GT_SW2: length 2.8
  TOP w0.102: v2(144.89,103.84) v1(145.96,103.84)
  TOP w0.508: v2(144.89,103.84) 144.32,104.41 PR669.1
H_CATERR#: length 5.8
  BOTTOM w0.076: RC111.2 126.56,68.3 126.12,68.74 124.85,68.74 124.61,68.99 123.83,68.99 123.69,68.85 123.28,68.85 123.27,68.87 123.12,68.87 123.02,68.84 122.74,68.84 122.56,68.9 122.35,68.99 122.06,68.99 121.78,69.27 UC1.D63
H_CPU_SVIDALRT#: length 12.8
  BOTTOM w0.102: RC153.1 126.69,69.38 126.59,69.27 126.16,69.27 126.06,69.37 126.06,70.18 126.19,70.31 127.84,70.31 127.95,70.42 127.95,70.66 127.83,70.77 126.57,70.77 126.26,71.07 125.94,71.07 125.65,70.78 v1(125.65,69.8) 125.65,69.37 125.55,69.27 125.35,69.27 125.24,69.37 125.24,70.2 125.14,70.3 124.94,70.3 124.84,70.2 124.84,69.65 124.74,69.55 122.93,69.55 122.83,69.44 UC1.B63
H_CPUPWRGD: length 12.6
  BOTTOM w0.076: 128.15,77.68 126.79,77.68 126.66,77.81 125.34,77.81 125.11,78.04 ; UC1.A68 123.59,72.4 124.22,73.03 124.22,74.85 123.78,75.29 123.78,76.56 124.22,77.01 124.22,77.01 124.26,77.05 124.26,77.36 124.91,78.01
  BOTTOM w0.102: 125.11,78.04 RC95.2 124.91,78.01 ; CC15.1 129.14,77.36 128.82,77.68 128.15,77.68
H_CPUPWRGD_R: length 1.3
  BOTTOM w0.102: RC95.1 125.83,78.23 126.56,78.23 TP7.1
H_DRAMRST#: length 98.9
  TOP w0.102: v2(93.24,34.65) 93.32,34.65 98.15,39.49 102.37,39.49 103.63,40.75 103.85,40.75 v2(104.31,41.21) ; v2(56.94,60.7) 56.94,61.44 58.05,62.55 RD7.2 58.71,62.57 59.58,62.57
  IN1 w0.127: v2(56.94,60.7) 59.44,58.2 59.44,53.49 60.28,52.64 60.28,47.77 59.46,46.94 59.44,46.94 59.44,23.15 59.86,22.73 60.87,22.73 60.91,22.68 63.87,22.68 65.14,21.41 66.66,21.41 67.95,20.12 69.91,20.12 72.59,22.79 75.11,22.79 78.15,25.83 80.72,25.83 81.77,26.88 82.82,26.88 83.37,27.42 83.4,27.42 83.93,27.42 87.02,30.51 87.02,30.9 87.33,31.22 88.05,31.22 88.67,31.83 89.06,31.83 92.03,34.8 93.09,34.8 v2(93.24,34.65)
  BOTTOM w0.102: UC1.AT13 104.31,41.07 v2(104.31,41.21)
H_PROCHOT#: length 166
  TOP w0.102: v2(189.19,36.79) PQ721.1 188.18,36.79 186.05,34.66 v1(186.05,33.17) 186.05,29.94 184.3,28.19 184.3,27.78 ; v2(157.14,15.44) 156.14,15.44 154.83,16.74 154.83,17.94 CE26.1 153.99,18.57 153.13,19.44 153.13,19.96 152.3,20.78 UE2.4 ; v2(167.09,12.08) 167.09,11.7 167.91,10.88 172.9,10.88 179.76,17.73 181.03,17.73 183.91,20.62 187.22,20.62 188.06,21.45 188.06,22.22 188.01,22.27 188.01,25.84 186.6,27.25 184.53,27.25 184.3,27.48 184.3,27.78 ; 184.3,27.78 182.79,27.78 181.81,26.8 181.06,26.8 180.81,26.56 PQ3.1 180.81,25.39 180.12,24.69 180.12,23.67 180.22,23.57 PQ2.6 ; v2(171.09,55.26) 170.91,55.26 169.37,53.73 PC605.2 ; v2(165.57,52.97) 165.56,52.97 165.56,53.6 PR678.1
  IN1 w0.127: v2(171.09,55.26) 173.42,55.26 181.8,46.88 182.46,46.88 186.81,42.53 186.81,40.85 187.98,39.68 187.98,39.13 187.7,38.85 187.7,38.27 v2(189.19,36.79)
  IN2 w0.127: v2(167.09,12.08) 166.64,11.64 162.86,11.64 159.42,15.08 157.5,15.08 v2(157.14,15.44) ; v2(165.57,52.97) 165.56,52.97 165.56,53.17 166.02,53.62 ; 166.02,53.62 169.45,53.62 v2(171.09,55.26) ; 166.02,53.62 163.77,53.62 162.9,54.5 159,54.5 158.3,53.8 154.32,53.8 153.91,53.39 145.54,53.39 138.06,60.86 134.56,60.86 v2(134.2,61.23)
  BOTTOM w0.102: v2(189.19,36.79) 189.31,36.66 PR777.1 ; v2(134.2,61.23) 131.47,63.96 131.47,70.67 130.87,71.27 130.87,72.17 130.18,72.85 129.05,72.85 RC113.2 RC117.1
H_PROCHOT#_R: length 8.3
  BOTTOM w0.076: UC1.C65 122.42,70.4 122.68,70.15 124.02,70.15 125.37,71.5 125.37,72.7 125.45,72.78 125.62,72.78 125.7,72.7 125.7,71.89 125.78,71.82 125.99,71.82 126.07,71.89 v2(126.07,72.15) 126.07,72.69 126.14,72.77 126.25,72.77 RC117.2
H_PROCHOT_EC: length 5.5
  TOP w0.102: v2(154.01,24.32) 153.7,24.01 v1(153.37,24.01) RE53.2 152.36,23.71 152.95,23.11 UE2.2
  BOTTOM w0.102: UE1.83 155.05,23.98 154.9,23.83 154.33,23.83 154.01,24.15 v2(154.01,24.32)
H_THERMTRIP#: length 8.1
  BOTTOM w0.076: UC1.C63 122.41,69.27 122.5,69.19 122.5,69.11 122.62,69.05 122.77,69.01 122.91,69.01 123.1,69.06 123.25,69.06 123.34,69.02 123.63,69.02 123.76,69.15 124.67,69.15 124.92,68.9 126.95,68.9 127.11,69.07 127.95,69.07 TP14.1 128.3,68.71 128.92,68.71 129.25,68.38 RC112.2
H_VCCST_PWRGD: length 16.8
  TOP w0.102: v2(128.28,73.29) 128.75,73.75 128.98,73.75 129.08,73.86 v1(129.08,74.12) 129.08,75.61 129.18,75.71 129.39,75.71 129.49,75.61 129.49,73.86 129.59,73.75 129.79,73.75 129.9,73.86 129.9,75.61 130,75.71 130.2,75.71 130.3,75.61 130.3,73.86 130.4,73.75 130.61,73.75 130.71,73.86 130.71,75.61 130.81,75.71 131.01,75.71 131.11,75.61 131.11,73.86 131.22,73.75 RC104.1 131.98,73.95 131.98,74.23 131.96,74.25 UC7.4
  BOTTOM w0.076: RC96.1 v2(128.28,73.29)
HDA_BIT_CLK: length 36.4
  TOP w0.102: RC124.2 81.17,23.42 v2(82.22,24.47) 82.76,24.47 v1(83.01,24.72)
  BOTTOM w0.089: 95.29,44.57 95.77,45.05 98.12,45.05 98.18,45.12 101.35,45.12 101.69,45.46 101.92,45.46 UC1.AY22
  BOTTOM w0.102: v2(82.22,24.47) 82.22,25.06 82.76,25.6 82.76,28.44 82.38,28.82 82.38,32.59 94.36,44.57 95.29,44.57
HDA_CODEC_BITCLK: length 63.3
  TOP w0.102: UA1.6 27.59,23.66 v2(27.74,23.8) ; v2(79.2,20.72) 79.33,20.85 v1(80.03,20.85) 80.79,20.85 CC16.1 RC124.1
  BOTTOM w0.102: v2(79.2,20.72) 79.08,20.72 77.86,19.5 77.86,17.08 77.22,16.44 56.32,16.44 55.3,17.46 45.31,17.46 45.25,17.52 45.25,17.52 45.04,17.73 42.9,17.73 40.27,20.37 40.27,22.48 39.4,23.35 34.5,23.35 34.06,22.9 28.64,22.9 v2(27.74,23.8)
HDA_CODEC_RST#: length 1.3
  TOP w0.102: TP74.1 80.92,17.36 RC127.1
HDA_CODEC_SDIN0: length 4.9
  TOP w0.102: UA1.8 v1(26.79,24.21) 26.79,24.25 28.02,25.49 RA7.2
HDA_CODEC_SDOUT: length 63
  TOP w0.102: v2(28.09,24.28) 28.21,24.15 28.21,23.65 27.99,23.42 UA1.5 ; v1(78.51,21.42) 78.62,21.31 v2(79.19,21.31) 79.43,21.31 RC125.1
  BOTTOM w0.102: v2(28.09,24.28) 29.23,23.13 33.96,23.13 34.41,23.58 39.49,23.58 40.49,22.57 40.49,20.47 43,17.96 45.13,17.96 45.34,17.75 55.33,17.75 56.42,16.67 77.12,16.67 77.63,17.17 77.63,19.87 79.06,21.31 v2(79.19,21.31)
HDA_CODEC_SYNC: length 61.5
  TOP w0.102: v2(25.74,23.9) 25.99,23.65 UA1.10 ; v2(78.81,18.28) 78.81,18.28 RC123.1
  BOTTOM w0.102: v2(78.81,18.28) 78.22,18.28 78.08,18.14 78.08,16.98 77.31,16.21 56.23,16.21 55.24,17.2 45.2,17.2 44.89,17.51 42.81,17.51 40.04,20.28 40.04,22.38 39.3,23.12 34.6,23.12 34.15,22.67 26.96,22.67 v2(25.74,23.9)
HDA_RST#: length 42.9
  TOP w0.102: v2(82.91,19.81) 82.56,19.81 81.96,19.21 CC89.1 80.93,19.21 RC127.2
  BOTTOM w0.076: UC1.AW22 102.54,45.95 101.03,45.95 101.02,45.96 100.71,45.96 100.37,45.62 97.98,45.62 97.94,45.59 95.51,45.59
  BOTTOM w0.102: 95.51,45.59 95.51,45.59 94.4,45.59 81.62,32.8 81.62,28.62 81.88,28.36 81.88,26.25 81.58,25.95 81.58,23.93 82.3,23.21 82.3,20.22 82.72,19.81 v2(82.91,19.81)
HDA_SDIN0: length 139.6
  TOP w0.102: RA7.1 28.02,28.59 28.28,28.85 28.28,29.16 v2(28.47,29.36)
  IN2 w0.127: v2(28.47,29.36) 33.37,29.36 37.2,25.52 37.2,17.76 38.48,16.47 38.48,15.62 42.87,11.23 42.87,9.29 49,3.15 55.38,3.15 56.32,4.09 81.99,4.09 83.03,3.05 87.55,3.05 89.42,3.05 90.26,3.89 v2(91.11,3.89)
  BOTTOM w0.089: UC1.BA21 101.61,45.13 101.42,44.94 98.26,44.94 98.19,44.87 96,44.87 95.01,43.88
  BOTTOM w0.102: v2(91.11,3.89) 90.81,4.19 90.81,11.34 88.83,13.31 88.08,13.31 87.52,13.87 v1(87.52,14.45) 87.52,14.69 86.77,15.44 86.77,19.12 85.07,20.82 85.07,22.4 83.46,24.01 83.46,24.59 83.08,24.97 83.08,27.64 83.74,28.3 83.74,30.11 82.74,31.11 82.74,32.63 93.99,43.88 95.01,43.88
HDA_SDOUT: length 42.1
  TOP w0.102: RC129.2 86.13,24.78 85.59,24.25 84.18,24.25 82.51,25.92 v2(82.13,25.92) 81.99,25.92 v1(80.95,24.88) 80.28,24.21 RC125.2 RC126.2
  BOTTOM w0.076: UC1.BB22 100.61,45.46 98.05,45.46 98,45.41 97.62,45.41
  BOTTOM w0.102: v2(82.13,25.92) 82.11,25.94 82.11,28.45 81.85,28.71 81.85,32.71 94.47,45.33 95.53,45.33 95.6,45.41 97.62,45.41
HDA_SYNC: length 42
  TOP w0.102: RC123.2 80.6,19.83 81.5,19.83 81.68,20.01 81.68,20.45 v1(82.1,20.87) 82.37,20.6 82.96,20.6 83.14,20.78 83.14,21.48 v2(82.89,21.74)
  BOTTOM w0.076: UC1.BA22 101.29,45.7 100.89,45.29 98.11,45.29 98.05,45.22 95.69,45.22 95.64,45.17 95.62,45.17
  BOTTOM w0.089: 95.62,45.17 95.48,45.02
  BOTTOM w0.102: v2(82.89,21.74) 82.89,23.2 81.81,24.27 81.81,24.98 82.53,25.7 82.53,28.35 82.07,28.81 82.07,32.61 94.49,45.02 95.48,45.02
HDD_DEVSLP: length 100
  IN1 w0.127: v2(186.65,26.55) 186.62,26.57 186.62,32.41 185.19,33.85 185.19,39.6 184.78,40 184.78,41.68 181.62,44.85 180.96,44.85 172.89,52.92 171.91,52.92 168.44,52.92 167.48,51.96 161.23,51.96 161.19,51.91 159.59,51.91 155,47.33 138.13,47.33 137.71,46.91 137.71,44.79 138.01,44.5 138.01,41.91 137.01,40.91 134.45,40.91 133.78,40.24 131.12,40.24 130.01,39.13 128.86,39.13 126.68,36.95 125.21,36.95 125.03,36.77 124.66,36.77 121.96,34.07 119.21,34.07 v2(118.31,33.17)
  BOTTOM w0.076: v2(118.31,33.17) 118.64,33.5 UC1.J1
  BOTTOM w0.102: v2(186.65,26.55) 187.24,25.95 RS1.2
HDD_DEVSLP_R: length 14.6
  BOTTOM w0.102: JHDD1.8 195.65,17.73 195.51,17.87 194.84,17.87 194.53,18.18 193.3,18.18 v1(192.58,18.9) 192.58,19.11 192.8,19.32 192.8,20.52 191.75,21.57 191.75,23.87 191.26,24.36 188.09,24.36 187.48,24.97 RS1.1
HDMI_CLK: length 130.1
  TOP w0.097: v2(24.54,87.43) 24.18,87.78 23.32,87.78 23.29,87.75 22.7,87.75 22.67,87.78 22.32,87.78 CI1.1
  IN2 w0.076: 121.76,66.52 121.69,66.44 120.38,66.44 119.87,65.92 v2(119.78,65.92)
  IN2 w0.122: 121.76,66.52 122.19,66.94 122.19,69.64 122.38,69.83 122.38,73.47 121.52,74.32 121.52,74.9 120.65,75.77 120.65,78.48 119.95,79.18 119.95,86.64 117.94,88.64 111.41,88.64 104.47,95.59 82.89,95.59 82.48,96 56.13,96 55.43,95.29 33.14,95.29 25.53,87.68 24.79,87.68 v2(24.54,87.43)
  BOTTOM w0.076: UC1.G56 119.45,65.59 v2(119.78,65.92)
HDMI_CLK#: length 130.1
  TOP w0.097: CI2.1 22.14,87.97 v3(22.99,87.97) 24.49,87.97 v2(24.54,88.01)
  IN2 w0.076: v2(120.45,65.84) 120.31,65.98 120.31,66.08 120.47,66.24 121.8,66.24 121.83,66.27 121.87,66.27 121.94,66.34
  IN2 w0.122: 121.94,66.34 122.43,66.84 122.43,69.54 122.63,69.73 122.63,73.57 121.77,74.42 121.77,75 120.9,75.88 120.9,78.58 120.2,79.28 120.2,86.74 118.04,88.89 111.52,88.89 104.57,95.84 82.99,95.84 82.58,96.25 56.03,96.25 55.33,95.54 33.04,95.54 25.43,87.93 24.62,87.93 v2(24.54,88.01)
  BOTTOM w0.076: v2(120.45,65.84) 120.1,65.48 UC1.F56
HDMI_CLK#_R: length 11.2
  TOP w0.097: RPI2.6 18.18,81.1 18.33,81.26 18.33,82.31 v2(18.12,82.52) ; CI2.2 20.66,87.93 20.52,87.93 v2(20.3,88.15) 20.04,87.9 19.9,87.9 19.77,88.03 LI1.2 19.4,88.2 RI1.1
  IN1 w0.122: v2(18.12,82.52) 18.31,82.71 18.31,82.94 18.05,83.2 18.05,86.88 19.07,87.9 20.04,87.9 v2(20.3,88.15)
HDMI_CLK#_R_C: length 7.3
  TOP w0.097: RI1.2 18.32,88.06 LI1.1 18.12,88.03 17.96,87.87 17.4,87.87 RI3.2 16.67,87.87 15.9,87.87 15.87,87.91 15.29,87.91 15.25,87.87 14.46,87.87 14.18,87.59 v3(13.29,87.59) 12.41,87.59 JHDMI1.12
HDMI_CLK_R: length 10.7
  TOP w0.097: CI1.2 20.66,87.64 20.52,87.64 v2(20.3,87.41) 20.05,87.65 19.9,87.65 19.78,87.53 LI1.3 19.4,87.36 RI2.1 ; v2(18.71,82.52) 18.52,82.34 18.52,81.28 18.68,81.12 RPI2.5
  IN1 w0.122: v2(20.3,87.41) 20.05,87.65 19.17,87.65 18.3,86.78 18.3,83.3 18.56,83.04 18.56,82.67 v2(18.71,82.52)
HDMI_CLK_R_C: length 7.3
  TOP w0.097: RI2.2 18.48,87.36 LI1.4 18.11,87.53 17.95,87.69 17.4,87.69 RI3.1 16.67,87.69 v3(15.58,87.69) 14.54,87.69 14.26,87.41 13.62,87.41 13.58,87.37 13,87.37 12.97,87.41 12.41,87.41 JHDMI1.10
HDMI_DATA0: length 145.2
  TOP w0.097: v2(23.18,89.11) 22.91,89.39 22.02,89.39 CI3.1
  IN2 w0.089: 121.94,63.4 121.83,63.4 121.75,63.48 120.82,63.48 120.61,63.26 120.11,63.26 119.72,63.65 119.72,64.01 v2(119.65,64.08)
  IN2 w0.122: 121.94,63.4 122.13,63.4 122.13,63.4 122.59,63.4 124.73,65.54 124.73,66.21 125.59,67.07 125.59,71.17 125.19,71.57 125.19,77.14 127.84,79.79 127.84,86.91 119.86,94.89 107.69,94.89 105.24,97.34 83.61,97.34 83.21,97.75 57.15,97.75 56.73,98.17 54.73,98.17 53.61,97.05 31.39,97.05 31.21,96.86 31.21,96.8 24.82,90.42 23.65,90.42 23.26,90.04 23.26,89.2 v2(23.18,89.11)
  BOTTOM w0.076: UC1.G53 119.65,63.83 v2(119.65,64.08)
HDMI_DATA0#: length 145.1
  TOP w0.097: CI4.1 22.43,89.57 22.99,89.57 23.05,89.52 23.35,89.52 23.76,89.11 v2(23.9,89.11)
  IN2 w0.089: 121.94,63.65 121.88,63.65 121.87,63.66 120.7,63.66 120.52,63.48 120.2,63.48 120.02,63.66 120.02,63.99 120.11,64.08 v2(120.41,64.08)
  IN2 w0.122: 121.94,63.65 122.48,63.65 124.48,65.65 124.48,66.31 125.34,67.17 125.34,71.07 124.94,71.47 124.94,77.25 127.59,79.9 127.59,86.81 119.75,94.65 107.59,94.65 105.14,97.09 83.51,97.09 83.1,97.5 57.05,97.5 56.63,97.92 54.83,97.92 53.71,96.8 31.49,96.8 31.45,96.76 31.45,96.7 24.92,90.17 23.75,90.17 23.51,89.93 23.51,89.37 23.77,89.11 v2(23.9,89.11)
  BOTTOM w0.076: v2(120.41,64.08) 120.1,63.77 UC1.F53
HDMI_DATA0#_R: length 13.1
  TOP w0.097: RPI2.8 17.18,81.18 17.33,81.34 17.33,81.9 v2(17.15,82.09) ; CI4.2 20.66,89.83 20.52,89.83 v2(20.3,90.06) 20.04,89.81 19.83,89.81 19.7,89.94 LI2.2 19.4,90.1 RI5.1
  IN1 w0.122: v2(20.3,90.06) 20.04,89.81 19.39,89.81 17.3,87.72 17.3,82.24 v2(17.15,82.09)
HDMI_DATA0#_R_C: length 15.5
  TOP w0.097: RI5.2 18.51,90.13 LI2.1 18.06,89.94 17.92,89.8 17.44,89.8 RI6.2 16.56,89.73 16.1,89.73 v3(15.26,90.57) 13.67,92.16 12.89,92.16 12.86,92.19 12.28,92.19 12.25,92.16 11.58,92.16 11.13,91.71 11.13,86.23 10.99,86.09 10.86,86.09 JHDMI1.9
HDMI_DATA0_R: length 12.7
  TOP w0.097: v2(17.73,82.09) 17.52,81.88 17.52,81.32 17.68,81.17 RPI2.7 ; CI3.2 20.66,89.54 20.52,89.54 v2(20.3,89.31) 20.3,89.34 20.03,89.61 19.95,89.61 19.78,89.44 LI2.3 19.4,89.27 RI4.1
  IN1 w0.122: v2(20.3,89.31) 20.05,89.56 19.49,89.56 17.55,87.61 17.55,82.27 v2(17.73,82.09)
HDMI_DATA0_R_C: length 15.4
  TOP w0.097: RI4.2 18.48,89.27 LI2.4 18.11,89.44 17.93,89.61 17.35,89.61 RI6.1 16.79,89.54 16.02,89.54 15.36,90.21 15.31,90.21 14.9,90.62 14.9,90.66 13.59,91.97 v3(12.57,91.97) 11.66,91.97 11.32,91.63 11.32,86.16 11.07,85.91 10.86,85.91 JHDMI1.7
HDMI_DATA1: length 126.3
  TOP w0.097: CI7.1 22.36,85.79 23.24,85.79 v2(23.5,85.52)
  IN2 w0.076: 120.9,67.76 120.9,67.74 120.91,67.73 120.91,67.63 120.78,67.5 120.78,67.13 120.67,67.01 120.55,67.01 v2(120.35,66.81)
  IN2 w0.122: 120.9,67.76 120.9,68.02 121.43,68.55 121.43,69.96 121.62,70.15 121.62,73.16 119.89,74.89 119.89,78.16 119.18,78.87 119.18,85.21 118.83,85.56 113.46,85.56 111.82,87.2 111.8,87.2 104.15,94.84 82.57,94.84 82.17,95.25 56.45,95.25 55.74,94.54 33.46,94.54 24.69,85.77 23.76,85.77 v2(23.5,85.52)
  BOTTOM w0.076: UC1.F58 120.35,66.62 v2(120.35,66.81)
HDMI_DATA1#: length 126.3
  TOP w0.097: v2(23.5,86.1) 23.37,85.97 22.22,85.97 CI8.1
  IN2 w0.076: v2(120.99,66.81) 120.99,67.42 121.11,67.55 121.11,67.65 121.13,67.66 121.13,67.72 121.15,67.75 121.15,67.76
  IN2 w0.122: v2(23.5,86.1) 23.59,86.02 24.59,86.02 33.35,94.79 55.64,94.79 56.34,95.5 82.27,95.5 82.68,95.09 104.26,95.09 111.9,87.45 111.92,87.45 113.56,85.81 118.93,85.81 119.42,85.31 119.42,78.97 120.14,78.26 120.14,75 121.87,73.26 121.87,70.04 121.68,69.85 121.68,68.44 121.15,67.91 121.15,67.76
  BOTTOM w0.076: UC1.E58 120.99,66.6 v2(120.99,66.81)
HDMI_DATA1#_R: length 9.1
  TOP w0.097: RPI1.8 20.16,81.12 20.32,81.28 20.32,81.48 v2(20.12,81.68) ; CI8.2 20.65,85.89 20.59,85.89 v2(20.3,86.19) 20.17,86.06 LI3.2 19.4,86.23 RI7.1
  IN1 w0.122: v2(20.12,81.68) 20.28,81.84 20.28,82.22 18.8,83.7 18.8,85.16 19.58,85.93 20.04,85.93 v2(20.3,86.19)
HDMI_DATA1#_R_C: length 7.7
  TOP w0.097: RI7.2 18.48,86.23 LI3.1 18.12,86.06 17.96,85.91 17.4,85.91 RI9.2 16.67,85.91 15.87,85.91 15.39,85.43 15.35,85.43 14.94,85.02 14.94,84.97 14.56,84.59 v3(13.36,84.59) 12.41,84.59 JHDMI1.6
HDMI_DATA1_R: length 8.7
  TOP w0.097: CI7.2 20.69,85.7 20.56,85.7 v2(20.3,85.44) 20.17,85.56 LI3.3 19.4,85.39 RI8.1 ; RPI1.7 20.66,81.1 20.51,81.26 20.51,81.48 v2(20.7,81.68)
  IN1 w0.122: v2(20.7,81.68) 20.53,81.86 20.53,82.33 19.05,83.81 19.05,85.05 19.68,85.68 20.05,85.68 v2(20.3,85.44)
HDMI_DATA1_R_C: length 7.7
  TOP w0.097: RI8.2 18.48,85.39 LI3.4 18.11,85.56 17.95,85.72 17.4,85.72 RI9.1 16.67,85.72 15.95,85.72 v3(15.3,85.07) 14.63,84.41 13.68,84.41 13.65,84.37 13.06,84.37 13.03,84.41 12.41,84.41 JHDMI1.4
HDMI_DATA2: length 139.3
  TOP w0.097: v2(23.27,84.46) 23,84.19 23,84.05 22.8,83.84 22.32,83.84 CI5.1
  IN2 w0.076: v2(120.43,64.9) 120.62,64.9 120.78,65.07 120.78,65.26 121.02,65.5 121.8,65.5 121.84,65.53 121.94,65.53
  IN2 w0.122: 121.94,65.53 122.84,65.53 123.11,65.81 123.11,66.86 123.51,67.26 123.51,67.81 123.13,68.19 123.13,73.78 122.28,74.63 122.28,75.93 121.42,76.78 121.42,78.8 120.72,79.5 120.72,89.74 118.81,91.66 109.46,91.66 104.78,96.34 83.2,96.34 82.79,96.75 55.82,96.75 55.12,96.05 31.86,96.05 25.24,89.42 25.19,89.42 23.49,87.72 22.79,87.72 22.31,87.23 22.31,86 23.02,85.29 23.02,84.71 v2(23.27,84.46)
  BOTTOM w0.076: UC1.F55 120.3,64.54 120.43,64.67 v2(120.43,64.9)
HDMI_DATA2#: length 139.4
  TOP w0.097: v2(22.69,84.46) 22.82,84.33 22.82,84.13 22.72,84.03 22.26,84.03 CI6.1
  IN2 w0.076: v2(121.11,64.9) 120.99,65.03 120.99,65.18 121.11,65.3 121.92,65.3 121.93,65.28 121.94,65.28
  IN2 w0.122: v2(22.69,84.46) 22.77,84.54 22.77,85.18 22.06,85.89 22.06,87.34 22.69,87.97 23.39,87.97 25.09,89.67 25.13,89.67 31.76,96.29 55.01,96.29 55.72,97 82.89,97 83.3,96.59 104.88,96.59 109.56,91.91 118.91,91.91 120.97,89.85 120.97,79.61 121.67,78.91 121.67,76.89 122.52,76.04 122.52,74.74 123.38,73.88 123.38,68.29 123.76,67.91 123.76,67.16 123.36,66.76 123.36,65.7 122.94,65.28 121.94,65.28
  BOTTOM w0.076: v2(121.11,64.9) 120.75,64.54 UC1.E55
HDMI_DATA2#_R: length 9.6
  TOP w0.097: CI6.2 20.65,83.98 20.59,83.98 v2(20.3,84.28) 20.17,84.16 LI4.2 19.4,84.32 RI10.1 ; RPI1.6 21.16,81.17 21.32,81.32 21.32,82.2 v2(21.08,82.43)
  IN1 w0.122: v2(21.08,82.43) 21.29,82.22 21.29,82.06 21.62,81.73 22.15,81.73 22.54,82.12 22.54,83.28 21.53,84.28 v2(20.3,84.28)
HDMI_DATA2#_R_C: length 10
  TOP w0.097: JHDMI1.3 10.86,83.09 11.11,83.09 11.32,82.89 11.32,82.31 11.64,82 v3(12.72,82) 14.2,82 14.5,82.3 14.5,82.34 14.91,82.76 14.96,82.76 16.2,84 16.67,84 RI12.2 17.4,84 17.9,84 18.06,84.16 LI4.1
HDMI_DATA2_R: length 8.6
  TOP w0.097: CI5.2 20.69,83.79 20.56,83.79 v2(20.3,83.53) 20.17,83.66 LI4.3 19.4,83.49 RI11.1 ; v2(21.67,82.43) 21.51,82.27 21.51,81.34 21.66,81.18 RPI1.5
  IN1 w0.122: v2(20.3,83.53) 20.3,83.69 20.64,84.03 21.43,84.03 22.29,83.17 22.29,82.23 22.05,81.98 21.72,81.98 21.54,82.16 21.54,82.31 v2(21.67,82.43)
HDMI_DATA2_R_C: length 10
  TOP w0.097: JHDMI1.1 10.86,82.91 11.04,82.91 11.14,82.81 11.14,82.24 11.56,81.81 12.4,81.81 12.43,81.78 13.01,81.78 13.04,81.81 14.28,81.81 v3(14.86,82.39) 16.28,83.81 16.67,83.81 RI12.1 17.4,83.81 17.89,83.81 18.04,83.66 LI4.4
HDMI_HPD: length 160.1
  TOP w0.102: QI3.3 31.51,73.68 31.76,73.94 RI15.2 31.76,74.95 v2(31.7,75.01) v1(31.7,76.02)
  IN2 w0.127: v2(31.7,75.01) 31.7,74.75 30.5,73.55 28.91,73.55 28.53,73.17 28.53,71.73 31.6,68.66 31.6,68.64 39.84,60.4 39.84,39.88 43.78,35.94 43.78,20.34 47.29,16.83 48.39,16.83 52.01,13.21 80.52,13.21 82.6,15.28 93.89,15.28 96.54,17.93 96.54,23.32 100.98,27.76 100.98,29.46 103.14,31.63 105.63,31.63 107.16,33.16 109.1,33.16 110.8,34.85 110.8,35.99 111.21,36.4 111.21,37.77 112.62,39.18 v2(112.8,39.18)
  BOTTOM w0.076: 116.31,37.94 116.68,37.94 116.96,38.21 UC1.L9
  BOTTOM w0.089: 116.31,37.94 115.7,38.54 113.28,38.54 112.8,39.02 v2(112.8,39.18)
HDMI_HPD_B: length 44.3
  TOP w0.102: v1(31.14,70.32) v2(31.98,70.32) 32.16,70.49 QI3.1 32.16,71.66 32.33,71.83 32.91,71.83 33.1,71.65 RI16.1
  IN1 w0.127: JHDMI1.19 10.73,91.78 16.21,91.78 16.87,91.12 26.65,91.12 32.53,85.24 32.53,70.87 v2(31.98,70.32)
HDMI_PLL_GND:
  vias: v1(18.18,78.25)
HOST_DEBUG_TX: length 248
  TOP w0.102: v2(153.31,7.56) 153.31,8.25 153.82,8.76 153.82,10.4 155.01,11.6 157.21,11.6 157.85,12.24 157.85,13.92 158.62,14.69 158.62,15.56 158.16,16.02 158.16,19.98 158.33,20.15 158.33,23.44 v2(158,23.76) ; ZT57.1 135.51,9.23 v2(135.11,8.83) ; RE59.2 v2(132.92,10.2) 133.35,10.2 133.75,9.8 133.75,9.29 133.24,8.77 JDEG1.8 ; RW6.1 53.69,106.13 52.56,106.13 v2(52.31,106.38) 52.14,106.55 RW8.1
  IN2 w0.127: v2(153.31,7.56) 150.69,7.56 149.25,6.11 149.25,3.83 148.54,3.13 139.78,3.13 135.11,7.8 v2(135.11,8.83) 135.11,9.9 134.81,10.2 v2(132.92,10.2) 128.58,10.2 121.9,3.51 113.49,3.51 112.33,2.35 93.16,2.35 v2(92.86,2.66)
  BOTTOM w0.102: v2(158,23.76) 158,23.77 156.99,24.78 UE1.81 ; JWLAN1.30 52.3,106.39 v2(52.31,106.38) 52.31,105.83 52.09,105.62 48.29,105.62 46.38,103.71 46.38,98.25 51.62,93.01 67.82,93.01 68.29,93.48 76.95,93.48 80.9,89.53 80.9,78.43 79.52,77.05 79.52,28.44 79.66,28.3 80.28,27.68 80.28,27 79.98,26.7 79.98,23.11 80.69,22.4 80.69,18.52 89.73,9.48 89.73,3.2 90.27,2.66 v2(92.86,2.66)
HPOUT_L: length 13.2
  TOP w0.305: ZT19.1 15.51,11.07 v2(15.56,11.12)
  IN2 w0.305: v2(15.56,11.12) 13.17,13.52 JHP1.1
  BOTTOM w0.305: RA36.2 RA30.1 CA35.1 19.84,11.33 19.63,11.12 DA4.2 v2(15.56,11.12)
HPOUT_R: length 27.4
  TOP w0.305: v2(15.56,13.05) 15.08,13.05 ZT22.1
  IN2 w0.305: v2(15.56,13.05) 14.37,14.24 14.37,22.5 13.04,23.83 6.86,23.83 JHP1.2
  BOTTOM w0.305: v2(15.56,13.05) DA4.3 17.8,13.05 17.89,12.96 19.84,12.96 20.04,12.77 CA34.1 RA34.1 21.56,12.78 RA37.2
I2C_SCL_TP: length 37.6
  TOP w0.102: Q10.1 106.4,8.3 106.55,8.46 107.33,8.46 R34.2 v2(108.58,8.13) v1(109.22,8.13)
  IN2 w0.127: v2(108.58,8.13) 108.35,8.35 108.35,9.44 111.28,12.37 113.3,12.37 114.46,13.53 114.46,20.96 114.13,21.29 114.13,24.28 112.8,25.61 112.8,27.26 112.35,27.7 112.35,28.34 113.75,29.73 113.75,35.71 v2(113.94,35.9)
  BOTTOM w0.076: UC1.U6 114.06,35.9 v2(113.94,35.9)
I2C_SCL_TP_Q: length 14.6
  TOP w0.102: ZT9.1 107.77,5.99 R46.2 106.4,5.33 Q10.6 106.4,6.95 107.17,7.73 v2(107.17,8.05)
  BOTTOM w0.102: JTP1.6 99.9,8.22 100.49,7.63 105.61,7.63 106.03,8.05 v2(107.17,8.05)
I2C_SDA_TP: length 41.8
  TOP w0.102: v2(104.52,8.06) 104.52,7.4 105.1,6.83 Q10.4 105.1,5.1 R33.2 ; v2(114.01,36.66) 114.39,36.66 v1(114.74,36.31)
  IN2 w0.127: v2(104.52,8.06) 106.29,8.06 106.71,8.47 107.02,8.47 111.18,12.62 113.19,12.62 114.21,13.63 114.21,20.86 113.86,21.21 113.86,24.19 112.54,25.51 112.54,27.01 111.59,27.96 111.59,29 113.49,30.9 113.49,36.15 v2(114.01,36.66)
  BOTTOM w0.076: UC1.U7 v2(114.01,36.66)
I2C_SDA_TP_Q: length 14.9
  TOP w0.102: Q10.3 105.1,8.23 104.86,8.46 R47.2 105.14,9.02 v2(105.61,9.49) 105.8,9.68 ZT8.1
  BOTTOM w0.102: v2(105.61,9.49) 105.61,11.96 104.73,12.83 100.21,12.83 98.9,11.52 JTP1.7
I_ADP: length 70.1
  TOP w0.102: v2(149.18,30.73) 148.77,30.32 148.25,30.32 147.71,29.78 147.71,29.17 147.5,28.96 v1(147.5,27.77) 147.5,25.95 149.22,24.23 RE51.2
  IN2 w0.127: v2(187.24,37.83) 187.27,37.8 187.27,29.86 185.43,28.01 185.43,27.32 183.59,25.48 181.96,25.48 179.48,23.01 175.05,23.01 174.22,23.83 169.71,23.83 165.97,27.58 156.91,27.58 155.85,28.64 155.85,31.15 154.98,32.02 153.25,32.02 151.95,30.73 v2(149.18,30.73)
  BOTTOM w0.254: PR774.1 189.32,37.55 PC748.1 188.94,37.72 188.62,37.39 187.68,37.39 v2(187.24,37.83)
I_ADP_R: length 5
  TOP w0.102: 149.5,19 149.5,19.48 RE51.1 148.93,19.47 v1(148.93,18.83) ; 149.5,19 v2(149.5,18.97) ; 149.5,19 149.45,18.95 CE25.1
  BOTTOM w0.102: UE1.110 149.16,18.63 v2(149.5,18.97)
I_BATT: length 72.7
  TOP w0.102: RE54.2 147.43,21.03 148.93,22.53 148.93,24.01 v1(147.62,25.32) 147.15,25.79 147.15,28.94 147.48,29.27 147.48,29.88 148.33,30.73 v2(148.58,30.73)
  IN2 w0.127: v2(148.58,30.73) 149.12,30.19 151.77,30.19 152.5,30.92 154.27,30.92 154.35,30.84 154.98,30.84 155.6,30.22 155.6,28.53 156.8,27.32 165.86,27.32 169.61,23.58 174.12,23.58 174.94,22.75 179.59,22.75 182.07,25.23 183.69,25.23 185.68,27.22 185.68,27.91 187.71,29.94 187.71,38.89 v2(187.41,39.2)
  BOTTOM w0.254: v2(187.41,39.2) 187.41,39.65 187.66,39.91 188.37,39.91 PC749.2 188.94,39.05 189.55,38.44 PR775.1
I_BATT_R: length 5.5
  TOP w0.102: v1(148.51,21.63) 148.32,21.44 CE30.1 RE54.1 147.43,19.74 v2(146.77,19.08)
  BOTTOM w0.102: UE1.114 147.56,17.94 147.23,18.27 147.23,18.63 v2(146.77,19.08)
I_SYS: length 166.5
  TOP w0.102: v2(147.26,13.86) 147.05,13.86 RE44.1 ; PR620.1 169.14,55.33 170.14,55.33 v2(170.52,55.71) 179.6,55.71 181,57.1 184.42,57.1 185.82,55.71 185.82,55.2 189.08,51.94 192.58,51.94 193.29,51.22 199.07,51.22 200.55,49.74 v1(200.55,44.85) 201.06,44.34 v2(201.06,39.2) ; v2(191.33,39.33) 190.81,39.85 190.81,40.36 190.08,41.1 187.85,41.1 v2(187.51,40.76)
  IN1 w0.127: v2(201.06,39.2) 200.62,39.64 199.24,39.64 196.74,37.15 196.74,34.63 197.72,33.66 197.72,32.67 195.03,29.98 195.03,29.26 191.6,25.83 191.6,22.15 191.12,21.67 189.57,21.67 188.49,22.75 186.03,22.75 185.14,21.86 181.28,21.86 178.59,19.18 172.13,19.18 167.49,14.54 163.37,14.54 162.09,13.27 162.09,11.49 154.56,3.96 v2(153.64,3.96) ; v2(170.52,55.71) 173.59,55.71 181.98,47.31 182.64,47.31 187.24,42.71 187.24,41.02 v2(187.51,40.76)
  BOTTOM w0.102: v2(153.64,3.96) 151.45,3.96 151.07,4.34 151.07,8.7 149.11,10.66 147.11,10.66 146.72,11.05 146.72,11.91 146.97,12.16 146.97,13.58 v2(147.26,13.86)
  BOTTOM w0.203: PU703.8 191.95,37.23 191.79,37.39 191.79,38.23 191.33,38.69 v2(191.33,39.33) PR727.1
ICSP_CLK: length 34.1
  TOP w0.102: RE60.1 v2(127.59,12.46)
  IN1 w0.127: v2(152.9,15.64) 152,14.75 148.89,14.75 147.62,16.02 143.46,16.02 143,15.55 141.45,15.55 141.13,15.87 140.51,15.87 138.31,13.67 138.31,11.85 136.57,10.11 v2(135.59,10.11)
  IN2 w0.127: v2(135.59,10.11) 134.01,11.7 128.42,11.7 127.66,12.46 v2(127.59,12.46)
  BOTTOM w0.102: RE24.2 153.46,15.09 v2(152.9,15.64) 152.76,15.78 UE1.101
ICSP_CLK_R: length 5
  TOP w0.102: RE60.2 127.59,10.12 127.59,10.11 127.59,9.54 127.97,9.16 ZT53.1 129.8,9.16 130.24,8.73 JDEG1.2
ICSP_CLR: length 51.1
  TOP w0.102: v2(128.48,12.46) RE61.1
  IN1 w0.127: v2(153.87,21.96) 153.87,21.6 152.99,20.72 152.99,19.7 154.1,18.6 154.1,14.99 152.78,13.67 152.1,13.67 151.6,13.17 151.6,13.04 150.74,12.18 150.74,10.55 149.85,9.66 149.85,7.74 v2(150.02,7.57)
  IN2 w0.127: v2(128.48,12.46) 128.99,11.96 134.41,11.96 136.46,9.9 136.46,6.81 139.89,3.38 148.43,3.38 148.99,3.94 148.99,6.24 150.02,7.27 v2(150.02,7.57)
  BOTTOM w0.102: v2(153.87,21.96) 153.87,22.16 154.27,22.55 154.94,22.55 155.11,22.38 UE1.87
ICSP_CLR_R: length 4.1
  TOP w0.102: RE61.2 128.48,10.8 128.48,10.11 128.73,9.87 129.42,9.87 ZT54.1 130.74,8.56 JDEG1.3
ICSP_DAT: length 30.1
  TOP w0.102: RE63.1 v2(130.26,12.46)
  IN1 w0.127: v2(136.23,10.94) 137.62,12.34 137.62,13.72 140.71,16.81 143.62,16.81 144.16,16.27 147.83,16.27 149.09,15 151.81,15 152.27,15.47 v2(152.27,15.65)
  IN2 w0.127: v2(136.23,10.94) 134.71,12.46 v2(130.26,12.46)
  BOTTOM w0.102: UE1.102 152.36,15.74 v2(152.27,15.65) 152.27,15.3 RE26.2
ICSP_DAT_R: length 3.7
  TOP w0.102: JDEG1.5 131.74,9.08 131.08,9.73 ZT56.1 130.64,9.73 130.26,10.12 RE63.2
ILMT_+1VALW: length 5
  TOP w0.102: v2(151.24,40.27) v1(151.24,41.12)
  BOTTOM w0.254: PR304.2 PR305.1 152.61,40.01 152.36,40.27 v2(151.24,40.27) 150.91,40.27 150.57,40.61 PU300.13
IMON_IA: length 3.7
  TOP w0.203: PU602.14 164.19,62.25 164.35,62.41 164.35,62.7 v2(164.29,62.76)
  BOTTOM w0.102: v2(164.29,62.76) 164.29,63.2 v1(164.42,63.33)
  BOTTOM w0.254: v2(164.29,62.76) 164.35,62.7 PC625.2 PR629.2
IMON_VSA: length 5.6
  TOP w0.203: PU602.23 159.6,59.96 v2(159.57,59.99)
  BOTTOM w0.102: v1(158.2,58.76) 158.58,58.76 159.28,59.45 159.28,59.69 v2(159.57,59.99)
  BOTTOM w0.254: v2(159.57,59.99) 160.19,59.99 PC643.1 PR651.1
IMVP_VR_ON: length 112.9
  TOP w0.254: PR616.1 167.35,53.8 167.79,54.23 v2(167.79,54.85)
  IN1 w0.254: v2(123.72,31.55) 123.81,31.64 124.83,31.64 125.07,31.88 125.07,31.88 125.36,32.16 125.36,32.17 125.37,32.18 125.37,33.12 126.54,34.28 127.46,34.28 127.99,34.81 127.99,36.93 129.33,38.27 129.35,38.27 129.36,38.28 131.63,38.28 133.02,39.67 134.84,39.67 135.51,40.34 137.24,40.34 138.58,41.67 138.58,44.74 138.41,44.9 138.41,45.3 139.26,46.15 140.83,46.15 141.42,46.73 155.22,46.73 159.18,50.69 165.74,50.69 v2(166.26,51.21)
  IN2 w0.254: v2(154.27,96.83) 154.27,95.72 161.59,88.4 161.59,87.37 162.17,86.78 162.96,86.78 164.09,85.65 164.09,83.79 163.2,82.9 163.2,72.21 165.15,70.26 165.15,68.79 165.82,68.12 165.82,65.14 166.52,64.44 166.52,64.09 168.36,62.25 168.36,55.43 v2(167.79,54.85)
  BOTTOM w0.254: PR655.1 154.27,96.74 v2(154.27,96.83) ; v2(166.26,51.21) 167.42,51.21 167.79,51.58 v2(167.79,54.85) ; RC107.2 123.72,30.74 v2(123.72,31.55)
INT_TP#: length 5.9
  TOP w0.102: Q9.3 101.63,8.07 101.4,8.3 101.07,8.3 v2(100.83,8.06) 100.83,8.02 100.12,7.31 R39.2 ZT10.1
  BOTTOM w0.102: v2(100.83,8.06) 101.9,9.13 JTP1.4
INTRUDER#: length 31.7
  TOP w0.102: RC91.1 85.17,27.32 v2(85.93,28.09) v1(85.36,28.09)
  IN2 w0.135: v2(105.59,42.95) 105.17,42.54 102.78,42.54 101.42,41.18
  IN2 w0.142: 101.42,41.18 101.42,38.29 98.71,35.57 98.71,34.46 98.42,34.16 97.25,34.16 95.6,32.51 93.7,32.51 93.08,31.9 89.17,31.9 88.5,31.22 87.28,31.22 87.08,31.02 87.08,30.53 86.72,30.17 86.72,29.38 85.93,28.59 v2(85.93,28.09)
  BOTTOM w0.102: v2(105.59,42.95) 105.88,42.6 UC1.AP16
IR_CAM_DETECT#: length 150
  IN1 w0.127: v2(174.45,46.75) 172.42,48.79 172.42,51.39 171.91,51.91 168.86,51.91 167.81,50.86 167.43,50.86 167.22,50.86 166.16,49.8 161.14,49.8 158.79,47.45 158.79,47.03 158.79,42.95 159.7,42.04 159.7,39.87 157.37,37.55 157.37,35.77 156.8,35.2 155.32,35.2 154.76,35.76 150.13,35.76 149.38,36.5 147.39,36.5 146.35,37.55 142.98,37.55 142.88,37.45 138.44,37.45 136.14,35.15 133.16,35.15 132.24,34.22 131.85,34.22 131.04,33.42 129.89,33.42 126.2,29.74 126.07,29.74 125.37,29.03 121.05,29.03 v2(119.65,30.43)
  IN2 w0.127: v2(174.45,46.75) 174.71,47.01 176.95,47.01 177.92,47.97 180.74,47.97 184.88,43.83 189.91,43.83 190.27,43.48 191.42,43.48 192.26,44.32 197.52,44.32 201.19,40.65 210.01,40.65 210.89,39.77 213.91,39.77 214.23,40.09 217.31,40.09 219.12,38.29 219.12,38.08 219.12,35.45 219.93,34.64 224.04,34.64 v2(225.11,33.56)
  BOTTOM w0.102: JEDP1.34 225.1,33.55 v2(225.11,33.56) ; RC64.2 119.02,26.8 119.02,29.74 119.65,30.37 v2(119.65,30.43) 119.65,30.62 119.1,31.18 119.1,31.82 118.38,32.53 117.67,32.53 116.92,33.28 116.92,34.67 116.76,34.82 116.66,34.82 116.62,34.87 116.53,34.87 116.36,35.04 116.36,35.13 116,35.49 UC1.P4
IR_GND: length 2.8
  TOP w0.127: R54.1 v1(230.31,37.8)
  TOP w0.508: v2(227.69,37.24) 228.25,37.8 R54.1
ISEN1_GT: length 8.2
  TOP w0.203: v2(167.41,61.74) 167.26,61.59 167.26,61.06 166.55,60.36 PU602.9
  TOP w0.254: v2(167.41,61.74) 167.41,62.37 PC635.2
  BOTTOM w0.102: v1(166.9,60.72) 167.41,61.23 v2(167.41,61.74)
  BOTTOM w0.254: PR615.2 167.81,62.74 PR677.1 ; PR677.1 167.41,62.49 v2(167.41,61.74) ; PR677.1 166.91,62.98 PR675.2
ISEN2_GT: length 13.4
  TOP w0.203: PU602.10 166.49,60.76 166.77,61.04 v2(166.77,61.22)
  TOP w0.254: v2(167.39,66.36) 167.55,66.36 169.06,64.85 PC638.2
  BOTTOM w0.254: PR634.2 168.05,64.76 PR670.2 PR668.2 v2(167.39,66.36) 166.37,66.36 165.56,65.56 165.56,62.68 165.83,62.42 165.83,61.73 166.34,61.22 v2(166.77,61.22)
ISOLATE#: length 3.1
  BOTTOM w0.102: UL1.20 34.55,119.32 34.65,119.42 34.65,120.5 RL3.2 RL4.1
ISUMN_GT: length 58.5
  TOP w0.254: v2(169.75,64.27) 169.45,64.27 PC638.1 ; v2(171.41,62.31) 171.17,62.08 PR632.1 169.8,62.06 PR638.1 168.94,62.99 PC635.1 168.97,63.8 PC638.1 ; PR666.2 PC638.1
  IN1 w0.254: v2(169.75,64.27) 167.83,64.27 167.36,64.75 166.95,64.75 166.35,65.35 166.35,67.24 163.16,70.43 163.16,77.68 162.44,78.4 162.44,80.27 162.44,83.47 159.86,86.05 159.31,86.05 158.28,87.08 156.72,87.08 156.17,86.53 142.58,86.53 141.28,87.84 v2(140.96,87.84)
  BOTTOM w0.102: PH602.2 v2(140.96,87.84)
  BOTTOM w0.254: PC624.2 PC626.2 PR633.2 PR673.2 PC641.1 170.73,62.08 171.17,62.08 v2(171.41,62.31)
ISUMN_IA: length 33.5
  TOP w0.254: v2(154.48,65.28) 156.3,63.46 PR644.2 PR640.2
  IN2 w0.254: v2(147.45,76.48) 148.24,77.27 150.07,77.27 ; v2(149.94,81.49) 150.07,81.36 150.07,77.27 ; v2(154.48,65.28) 154.2,65.56 154.2,71.1 153.09,72.2 153.09,75.23 151.62,76.7 150.64,76.7 150.07,77.27
  BOTTOM w0.254: v2(154.48,65.28) 154.48,65.17 156.17,63.47 PC645.1 156.56,63.46 PC646.2 PC642.2 PR656.2 ; PL603.2 v2(149.94,81.49) ; PH605.2 v2(147.45,76.48)
ISUMN_VSA: length 17.4
  TOP w0.254: PR641.2 157.85,56.87 PR636.2 ; PR641.2 156.99,56.87 156.1,55.98 PC644.1 156.1,55.48 155.09,54.47 154.44,54.47 v2(154.18,54.73) ; PR641.2 PC637.2 PR643.1 PC633.2
  BOTTOM w0.254: PL601.2 150,59.96 150.53,60.48 152.25,60.48 PH604.2 154.07,58.66 154.07,54.84 v2(154.18,54.73)
ISUMP_GT: length 8.5
  TOP w0.203: v2(167.22,59.91) 166.87,59.56 PU602.7
  BOTTOM w0.254: PR674.1 PR667.1 170.94,60.04 PR628.1 PR633.1 PC626.1 PC624.1 167.58,60.27 v2(167.22,59.91) 167.02,59.71 PR637.1
ISUMP_IA: length 8.1
  TOP w0.203: v2(161.82,62.36) 161.83,62.36 162.19,62 PU602.19
  BOTTOM w0.254: PR656.1 PC642.1 ; PC642.1 PC646.1 158.34,63.89 PR661.2 ; PC642.1 158.71,62.94 PR657.1 PR653.1 161.24,62.94 v1(161.3,62.88) v2(161.82,62.36)
ISUMP_VSA: length 9.6
  TOP w0.203: PC633.1 159.07,58.35 160.51,58.35 160.52,58.36 PU602.27
  TOP w0.254: PC633.1 PR643.2 PC637.1 PR654.1 154.79,58.65 v1(154.48,58.34) 154.13,57.99 PR624.2 154.15,56.87 PR642.1
JACK_PLUG: length 6.3
  BOTTOM w0.254: JHP1.5 13.66,23.02 14.05,22.62 ZT20.1 14.05,20.91 14.75,20.22 RA39.2
JACK_PLUG_DET: length 8.6
  BOTTOM w0.254: RA40.1 15.77,22.18 15.12,22.83 15.11,22.83 ZT21.1 13.99,23.96 9.05,23.96 8.8,23.7 JHP1.6
KB_BL_CTRL#: length 10.3
  TOP w0.102: v2(113.26,6.8) 113.26,6.57 112.76,6.08 112.76,5.07 113.3,4.53 ZT52.1
  BOTTOM w0.102: Q8.1 113.69,11.62 113.44,11.38 EC3001.1 113.44,10.06 113.1,9.72 JKBBL1.4 113.1,6.95 v2(113.26,6.8)
KB_DET#: length 62.6
  TOP w0.102: ZT24.1 63.44,10.66 v2(64.6,10.66) ; v2(89.79,28.3) 89.51,28.3 v1(89.3,28.09) 89.16,27.95 RC45.1
  IN1 w0.127: v2(78.57,25.15) 78.74,25.32 80.93,25.32 81.98,26.37 83.37,26.37 83.88,26.88 87.71,26.88 88.98,28.15 89.36,28.15 89.51,28.3 v2(89.79,28.3)
  IN2 w0.142: v2(89.79,28.3) 91.13,29.64 92.92,29.64 93.12,29.85 93.12,31.4 93.97,32.25 95.71,32.25 97.32,33.85 97.94,33.85 v2(98.06,33.72)
  BOTTOM w0.076: v2(98.06,33.72) 98.06,33.89 98.98,34.8 98.98,35.9 100.32,37.24 UC1.BB7
  BOTTOM w0.102: v2(78.57,25.15) 78.57,23.45 80,22.01 80,13.96 78.95,12.91 65.87,12.91 64.6,11.64 v2(64.6,10.66) JKB1.30
KB_LED_BL_DET: length 32.5
  IN2 w0.127: v2(113.69,15) 113.95,15.27 113.95,20.75 113.6,21.1 113.6,24.09 112.29,25.4 112.29,26.9 111.08,28.11 111.08,29.68 111.58,30.18 112.06,30.18 113.24,31.36 113.24,36.91 v2(112.89,37.26)
  BOTTOM w0.076: UC1.W8 113.19,37.56 v2(112.89,37.26)
  BOTTOM w0.127: R26.1 R27.1 116.73,12.53 116.73,14.24 116.32,14.65 114.03,14.65 v2(113.69,15)
KB_LED_DET_C: length 5
  BOTTOM w0.102: JKBBL1.2 115.1,9.43 115.72,10.05 ZT51.1 118.32,10.05 118.38,10.11 118.38,10.12 R26.2
KB_LED_PWM: length 46.8
  IN1 w0.127: v2(146.64,29.83) 146.64,29.83 145.87,29.05 140.87,29.05 140.3,28.49 138.74,28.49 134.51,24.27 134.51,22.45 133.12,21.06 133.12,20.12 128.71,15.72 126.44,15.72 125.86,15.13 124.78,15.13 124.19,15.72 122.12,15.72 121.08,14.68 119.15,14.68 118.66,15.17 116.86,15.17 116.75,15.07 114.7,15.07 113.96,14.33 113.58,14.33 113.11,13.86 v2(113.11,13.87)
  BOTTOM w0.102: UE1.44 146.36,31.93 146.6,31.68 146.6,29.86 v2(146.64,29.83) ; v2(113.11,13.87) 113.11,13.86 113.27,13.7 Q8.2
KSI0: length 101.6
  TOP w0.102: v2(69.41,7.95) 69.41,7.87 ZT32.1 ; RPE1.4 142.8,20.37 142.7,20.27 142.7,19.18 v2(143.02,18.86)
  IN1 w0.127: v2(150.74,19.03) 150.73,19.03 150.05,19.7 149.37,19.7 149.05,19.39 149.05,18.52 148.57,18.04 147.31,18.04 146.81,17.54 144.68,17.54 144.08,18.14 144.08,18.48 143.69,18.86 v2(143.02,18.86) 140.97,18.86 135.59,13.48 135.59,12.79 133.55,10.76 133.55,10.23 132.44,9.12 125.48,9.12 124.29,7.94 115.48,7.94 115.08,7.53 110.48,7.53 109.81,6.86 106.96,6.86 106.02,5.92 89.79,5.92 88.81,4.95 77.36,4.95 76.2,6.11 71.48,6.11 71.35,6.24 71.11,6.24 v2(69.41,7.95)
  BOTTOM w0.102: UE1.98 153.96,18.52 153.41,19.07 150.78,19.07 v2(150.74,19.03) ; v2(69.41,7.95) 70.24,7.95 71,8.7 JKB1.22
KSI1: length 101.1
  TOP w0.102: RPE1.3 143.25,20.87 143.56,20.55 143.56,20.01 v2(143.49,19.94) ; v2(69.17,8.53) 69.43,8.79 ZT30.1
  IN1 w0.127: v2(151.59,18.43) 151.59,18.87 150.51,19.96 149.27,19.96 148.8,19.49 148.8,18.63 148.46,18.29 147.21,18.29 146.74,17.82 144.76,17.82 144.33,18.25 144.33,19.11 v2(143.49,19.94) 143.01,19.94 142.22,19.15 140.89,19.15 135.33,13.59 135.33,12.9 133.68,11.25 133.23,11.25 131.49,9.5 125.5,9.5 124.18,8.19 115.38,8.19 114.97,7.78 110.37,7.78 109.71,7.12 106.85,7.12 105.91,6.18 89.68,6.18 88.71,5.2 77.47,5.2 76.3,6.37 71.58,6.37 69.42,8.53 v2(69.17,8.53)
  BOTTOM w0.102: JKB1.24 69.4,8.76 v2(69.17,8.53) ; v2(151.59,18.43) 152,18.84 153.32,18.84 153.56,18.6 UE1.99
KSI2: length 89
  TOP w0.102: v2(142.25,20.09) 142.25,20.78 142.84,21.37 RPE1.2 ; ZT28.1 67.72,7.96 v2(67.72,8.45)
  IN1 w0.127: v2(67.72,8.45) 68.23,8.95 69.58,8.95 69.93,8.6 69.93,8.45 71.63,6.75 72.75,6.75 72.88,6.62 76.41,6.62 77.58,5.45 88.6,5.45 89.58,6.43 105.81,6.43 106.75,7.37 109.6,7.37 110.27,8.04 114.86,8.04 115.27,8.45 124.08,8.45 125.39,9.76 131.38,9.76 133.12,11.5 133.57,11.5 135.08,13 135.08,13.7 140.79,19.4 141.57,19.4 v2(142.25,20.09)
  BOTTOM w0.102: JKB1.26 67.8,8.53 v2(67.72,8.45) ; v2(142.25,20.09) 141.56,20.78 UE1.6
KSI3: length 84.6
  TOP w0.102: v2(141.74,21.48) 141.75,21.48 142.14,21.87 RPE1.1 ; ZT31.1 70.63,10.53 v2(70.21,10.11)
  IN1 w0.127: v2(141.74,21.48) 141.75,21.48 141.75,21.48 141.54,21.27 141.09,21.27 139.53,19.71 139.52,19.71 133.03,13.22 133.03,12.85 130.96,10.77 124.97,10.77 123.66,9.46 114.85,9.46 114.44,9.05 106.84,9.05 105.23,7.45 89.16,7.45 88.18,6.47 78,6.47 76.7,7.77 75.71,7.77 73.55,9.92 70.4,9.92 v2(70.21,10.11)
  BOTTOM w0.102: UE1.7 141.39,21.18 141.69,21.48 141.75,21.48 141.75,21.48 v2(141.74,21.48) ; JKB1.23 70.2,10.11 v2(70.21,10.11)
KSI4: length 101.6
  TOP w0.102: v2(67.01,8.4) 67.06,8.46 ZT27.1
  IN1 w0.127: v2(151.68,15.64) 150,17.32 147.31,17.32 147.02,17.03 144.47,17.03 143.8,17.7 142.4,17.7 141.78,18.32 141.14,18.32 136.09,13.27 136.09,12.58 134.06,10.55 134.06,10 132.68,8.62 125.69,8.62 124.5,7.43 123.44,7.43 122.23,6.22 107.04,6.22 106.23,5.42 90,5.42 89.02,4.44 77.15,4.44 75.99,5.61 69.48,5.61 67.01,8.08 v2(67.01,8.4)
  BOTTOM w0.102: JKB1.27 67.01,9.24 v2(67.01,8.4) ; UE1.104 151.56,16.41 151.68,16.28 v2(151.68,15.64) 151.68,15.1 151.2,14.62 149.27,14.62 149.17,14.52 RPE2.4
KSI5: length 101.2
  TOP w0.102: ZT29.1 68.64,8.33 v2(68.22,7.91)
  IN1 w0.127: v2(68.22,7.91) 68.22,7.54 69.9,5.86 76.09,5.86 77.26,4.69 88.92,4.69 89.9,5.67 106.12,5.67 107.06,6.61 109.92,6.61 110.59,7.28 115.18,7.28 115.59,7.68 124.39,7.68 125.58,8.87 132.57,8.87 133.8,10.1 133.8,10.65 135.84,12.69 135.84,13.38 141.04,18.58 141.88,18.58 142.51,17.95 143.91,17.95 144.58,17.29 146.92,17.29 147.2,17.57 149.98,17.57 v2(150.83,18.42)
  BOTTOM w0.102: v2(150.83,18.42) 151.16,18.09 UE1.105 151.16,16.24 151.26,16.13 151.26,15.01 151.11,14.85 148.88,14.85 148.67,14.64 RPE2.3 ; JKB1.25 68.6,8.29 v2(68.22,7.91)
KSI6: length 100.6
  TOP w0.102: ZT26.1 66.21,8.1 v2(66.21,8.4)
  IN1 w0.127: v2(150.27,15.7) 150.27,15.93 149.14,17.06 147.41,17.06 147.13,16.78 144.37,16.78 143.83,17.32 140.5,17.32 137.12,13.94 137.12,12.73 136.46,12.08 135.95,12.08 134.31,10.44 134.31,9.89 132.78,8.36 125.79,8.36 124.61,7.18 123.54,7.18 122.33,5.97 107.14,5.97 106.34,5.16 90.84,5.16 89.17,3.49 87.33,3.49 86.64,4.18 77.05,4.18 75.88,5.35 69.05,5.35 66.21,8.19 v2(66.21,8.4)
  BOTTOM w0.102: UE1.107 150.36,15.79 v2(150.27,15.7) 149.65,15.08 148.55,15.08 148.17,14.7 RPE2.2 ; JKB1.28 66.2,8.41 v2(66.21,8.4)
KSI7: length 101
  TOP w0.102: ZT25.1 64.85,9.09 v2(65.55,8.39)
  IN1 w0.127: v2(65.55,8.39) 68.84,5.1 75.77,5.1 76.94,3.93 86.53,3.93 87.22,3.24 89.28,3.24 90.95,4.91 106.44,4.91 107.25,5.72 122.44,5.72 123.65,6.92 124.71,6.92 125.9,8.11 132.89,8.11 134.57,9.79 134.57,10.34 136.06,11.83 136.57,11.83 137.37,12.63 137.37,13.83 140.6,17.06 143.72,17.06 144.26,16.52 147.24,16.52 147.52,16.81 149.04,16.81 149.69,16.16 v2(149.69,15.7)
  BOTTOM w0.102: RPE2.1 147.67,14.77 148.2,15.31 149.29,15.31 v2(149.69,15.7) 149.69,15.74 149.96,16.02 UE1.108 ; v2(65.55,8.39) 65.4,8.54 JKB1.29
KSO0: length 84.7
  TOP w0.102: v2(141.62,23.83) 142.13,23.32 RPE3.8 ; ZT41.1 77.36,7.66 v2(77.36,8.46)
  IN1 w0.127: v2(141.62,23.83) 141.58,23.83 140.29,22.54 140.29,21.54 139.22,20.47 139.2,20.47 132.27,13.54 132.27,13.16 130.64,11.54 124.65,11.54 123.36,10.24 114.55,10.24 114.12,9.82 106.52,9.82 105.69,8.98 100.45,8.98 99.67,8.21 88.84,8.21 87.86,7.23 78.59,7.23 v2(77.36,8.46)
  BOTTOM w0.102: v2(77.36,8.46) 77.87,8.46 78.2,8.79 JKB1.13 ; UE1.2 142.24,19.18 142.88,19.82 142.88,20.66 143.47,21.24 143.47,22.43 142.9,23.01 142.44,23.01 v2(141.62,23.83)
KSO1: length 80.4
  TOP w0.102: ZT39.1 76.61,9.55 v2(76.61,10.18) ; RPE3.7 142.28,23.82 v2(142.26,23.84)
  IN1 w0.127: v2(142.26,23.84) 141.81,24.28 141.19,24.28 140.27,23.36 140.27,22.9 140.04,22.67 140.04,22.03 139.51,21.51 138.92,21.51 138.2,20.78 138.2,19.82 132.02,13.65 132.02,13.27 130.54,11.79 124.55,11.79 123.25,10.5 114.44,10.5 114.02,10.07 105.49,10.07 104.66,9.24 100.34,9.24 99.57,8.46 88.74,8.46 87.76,7.49 79,7.49 76.61,9.88 v2(76.61,10.18)
  BOTTOM w0.102: JKB1.15 76.6,10.17 v2(76.61,10.18) ; UE1.14 141.2,23.98 141.5,24.28 141.81,24.28 v2(142.26,23.84)
KSO2: length 80
  TOP w0.102: RPE3.6 142.4,24.31 142.13,24.59 v2(142.13,24.94) ; v2(77.41,10.04) 77.41,11.09 ZT40.1
  IN1 w0.127: v2(142.13,24.94) 141.85,24.67 141.21,24.67 140.01,23.47 140.01,23 139.78,22.77 139.78,22.14 139.41,21.76 138.81,21.76 137.94,20.89 137.94,19.93 131.76,13.75 131.76,13.38 130.43,12.04 124.44,12.04 123.15,10.75 117.73,10.75 117.12,11.36 114.94,11.36 113.91,10.32 105.39,10.32 104.56,9.49 100.24,9.49 99.46,8.72 88.63,8.72 87.65,7.74 79.7,7.74 v2(77.41,10.04)
  BOTTOM w0.102: UE1.15 141.16,24.38 141.38,24.61 141.79,24.61 v2(142.13,24.94) ; JKB1.14 77.4,10.03 v2(77.41,10.04)
KSO3: length 82.8
  TOP w0.102: RPE3.5 142.72,24.81 142.62,24.92 142.62,25.28 v2(142.58,25.32) ; ZT38.1 75.74,11.68 v2(75.74,10.22)
  IN1 w0.127: v2(75.74,10.22) 76.12,10.6 77.44,10.6 80.04,7.99 87.55,7.99 88.52,8.97 99.36,8.97 100.13,9.75 104.45,9.75 105.28,10.58 113.81,10.58 114.84,11.61 117.22,11.61 117.83,11 123.04,11 124.63,12.59 126.91,12.59 127.25,12.93 130.47,12.93 133.69,16.15 133.69,17.1 138.6,22.01 139.3,22.01 139.53,22.24 139.53,22.88 139.76,23.11 139.76,23.57 141.15,24.96 141.55,24.96 141.98,25.39 142.5,25.39 v2(142.58,25.32)
  BOTTOM w0.102: v2(75.74,10.22) 75.8,10.15 JKB1.16 ; UE1.16 141.17,24.78 141.32,24.94 141.52,24.94 141.98,25.39 142.5,25.39 v2(142.58,25.32)
KSO4: length 98.5
  TOP w0.102: v2(72.66,8.4) 72.66,9.25 ZT34.1
  IN1 w0.127: v2(72.66,8.4) 72.66,8.08 73.62,7.13 76.62,7.13 77.79,5.96 88.39,5.96 89.37,6.94 105.45,6.94 107.05,8.55 114.65,8.55 115.06,8.95 123.87,8.95 125.18,10.27 131.17,10.27 132.91,12.01 133.36,12.01 134.57,13.22 134.57,13.98 141.35,20.76 143.02,20.76 144.82,22.56 v2(146.64,22.56)
  BOTTOM w0.102: JKB1.20 72.6,8.46 v2(72.66,8.4) ; v2(146.64,22.56) 146.64,22.56 145.72,23.48 145.72,29.5 143.56,31.66 UE1.37 143.56,33.88 143.35,34.09 RPE4.8
KSO5: length 100.5
  TOP w0.102: ZT33.1 71.65,8.18 v2(71.81,8.34)
  IN1 w0.127: v2(147.47,22.37) 147.4,22.37 145.54,20.51 141.45,20.51 134.82,13.88 134.82,13.11 133.47,11.75 133.02,11.75 131.27,10.01 125.28,10.01 123.97,8.7 115.17,8.7 114.76,8.29 110.16,8.29 109.5,7.63 106.64,7.63 105.7,6.69 89.47,6.69 88.5,5.71 77.68,5.71 76.51,6.88 72.98,6.88 71.81,8.05 v2(71.81,8.34)
  BOTTOM w0.102: v2(71.81,8.34) 71.81,9.24 JKB1.21 ; RPE4.7 143.85,33.8 143.96,33.69 UE1.38 143.96,31.58 145.95,29.6 145.95,23.89 147,22.84 147,22.84 147.24,22.6 147.24,22.6 v2(147.47,22.37)
KSO6: length 95.8
  TOP w0.102: ZT36.1 74.21,10.98 v2(74.21,10.11)
  IN1 w0.127: v2(74.21,10.11) 76.24,8.08 76.74,8.08 78.1,6.72 88.07,6.72 89.05,7.7 99.88,7.7 100.66,8.48 105.9,8.48 106.73,9.31 114.34,9.31 114.75,9.72 123.55,9.72 124.86,11.03 130.85,11.03 132.78,12.95 132.78,13.33 139.41,19.96 139.43,19.96 140.8,21.33 140.8,22.33 141.63,23.16 144.29,23.16 145.29,24.15 146.41,24.15 v2(146.58,23.98)
  BOTTOM w0.102: RPE4.6 144.35,34.75 144.08,34.48 144.08,33.95 144.36,33.67 UE1.39 144.36,31.51 146.17,29.69 146.17,24.39 v2(146.58,23.98) ; v2(74.21,10.11) 74.2,10.11 JKB1.18
KSO7: length 104.2
  TOP w0.102: v2(73.43,8.46) 73.59,8.3 ZT35.1
  IN1 w0.127: v2(147.4,23.01) 147.15,23.26 145.16,23.26 142.92,21.01 141.2,21.01 139.64,19.45 139.62,19.45 133.29,13.12 133.29,12.74 131.06,10.52 125.07,10.52 123.76,9.21 114.96,9.21 114.55,8.8 106.95,8.8 105.34,7.19 89.26,7.19 88.29,6.22 77.89,6.22 76.6,7.51 75.61,7.51 75.48,7.64 73.81,7.64 73.43,8.02 v2(73.43,8.46)
  BOTTOM w0.102: v2(147.4,23.01) 147.4,23.07 147.77,23.43 147.77,29.29 148.4,29.93 149.18,29.93 149.69,30.43 149.69,31.07 148.76,32 UE1.50 148.76,33.77 148.75,33.78 148.75,34.74 147.79,35.69 147,35.69 146.1,36.59 145.43,36.59 145.17,36.33 145.17,35.82 144.85,35.5 RPE4.5 ; JKB1.19 73.4,8.49 v2(73.43,8.46)
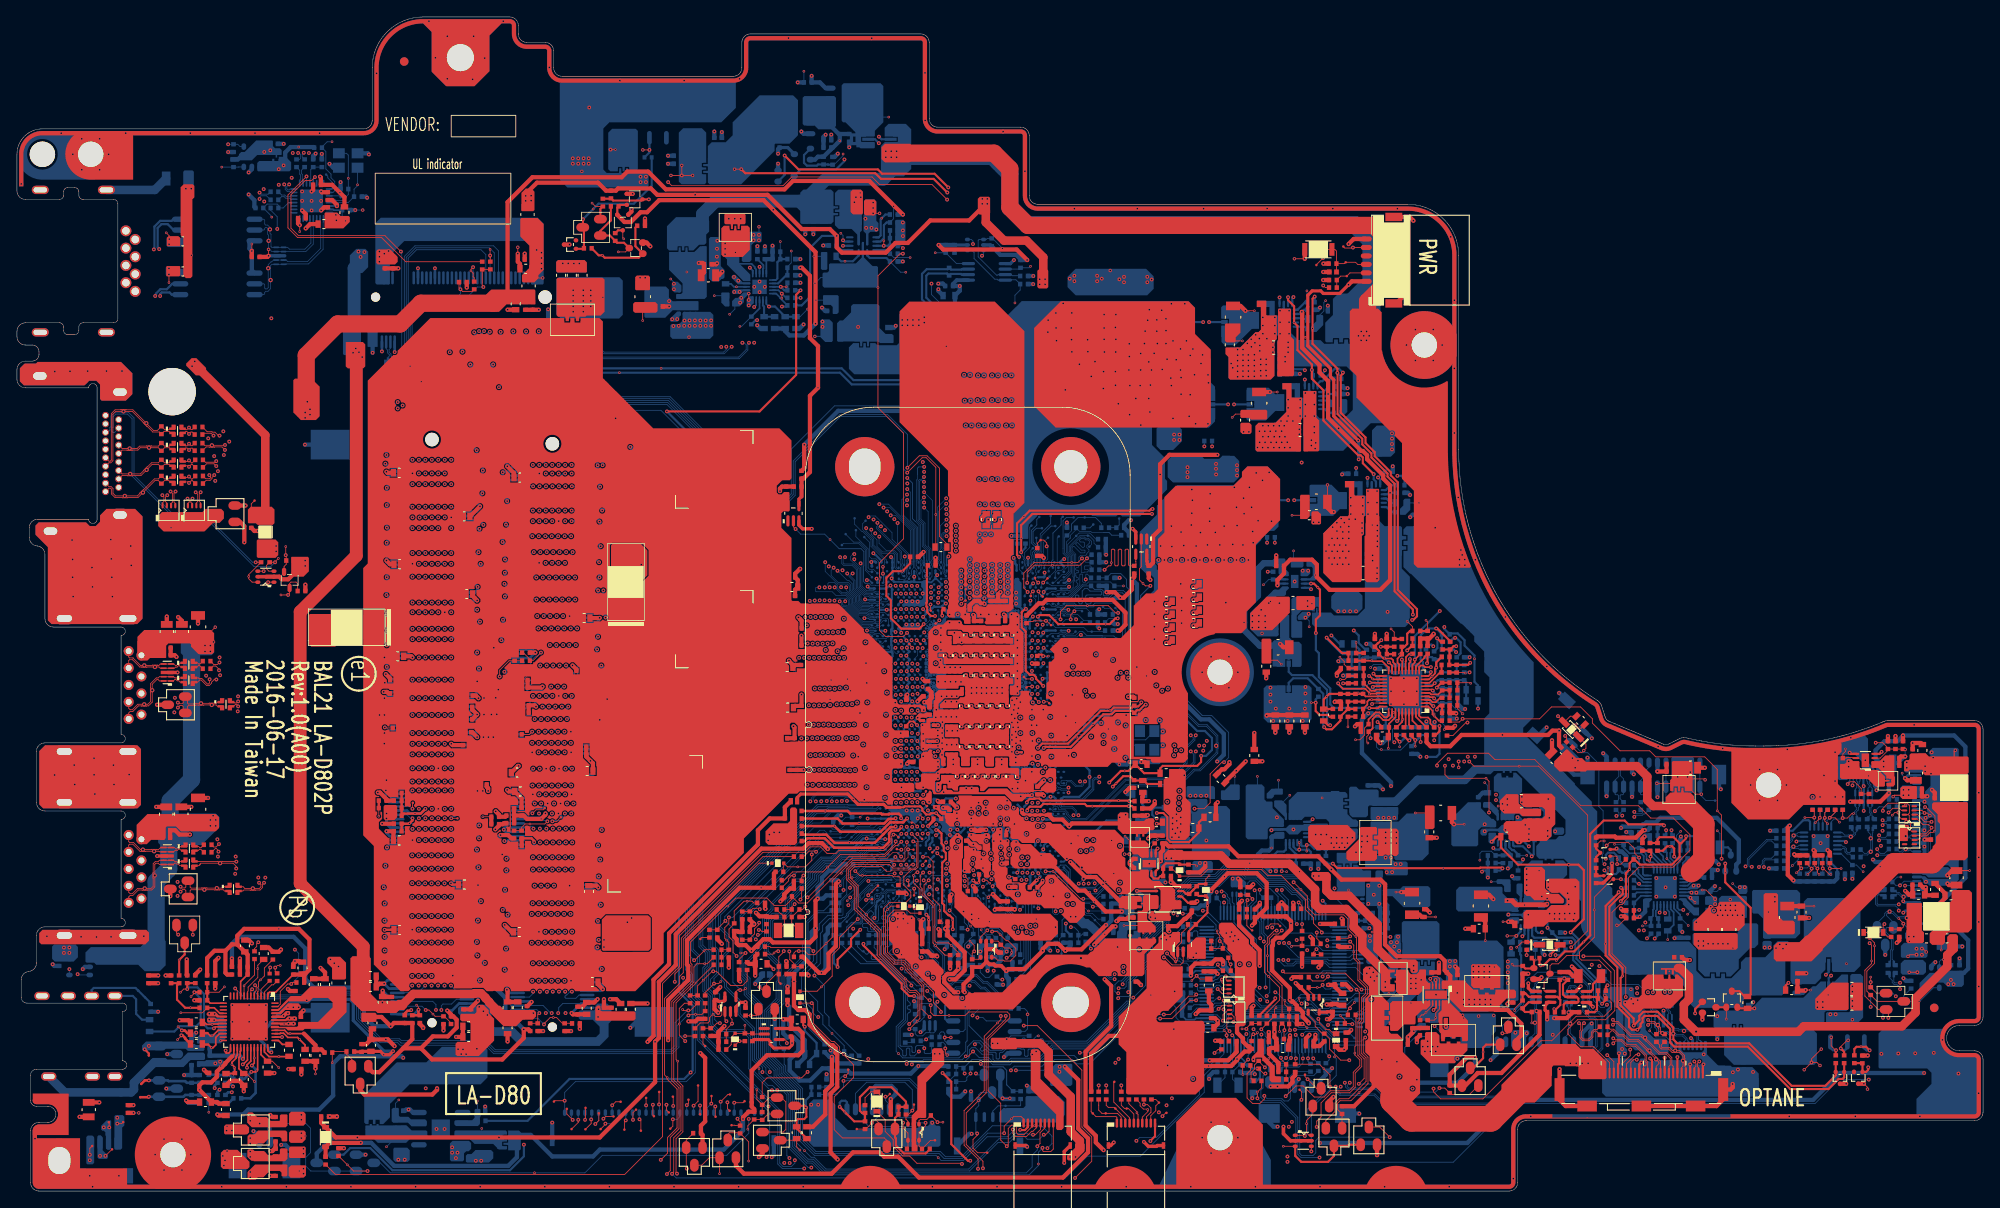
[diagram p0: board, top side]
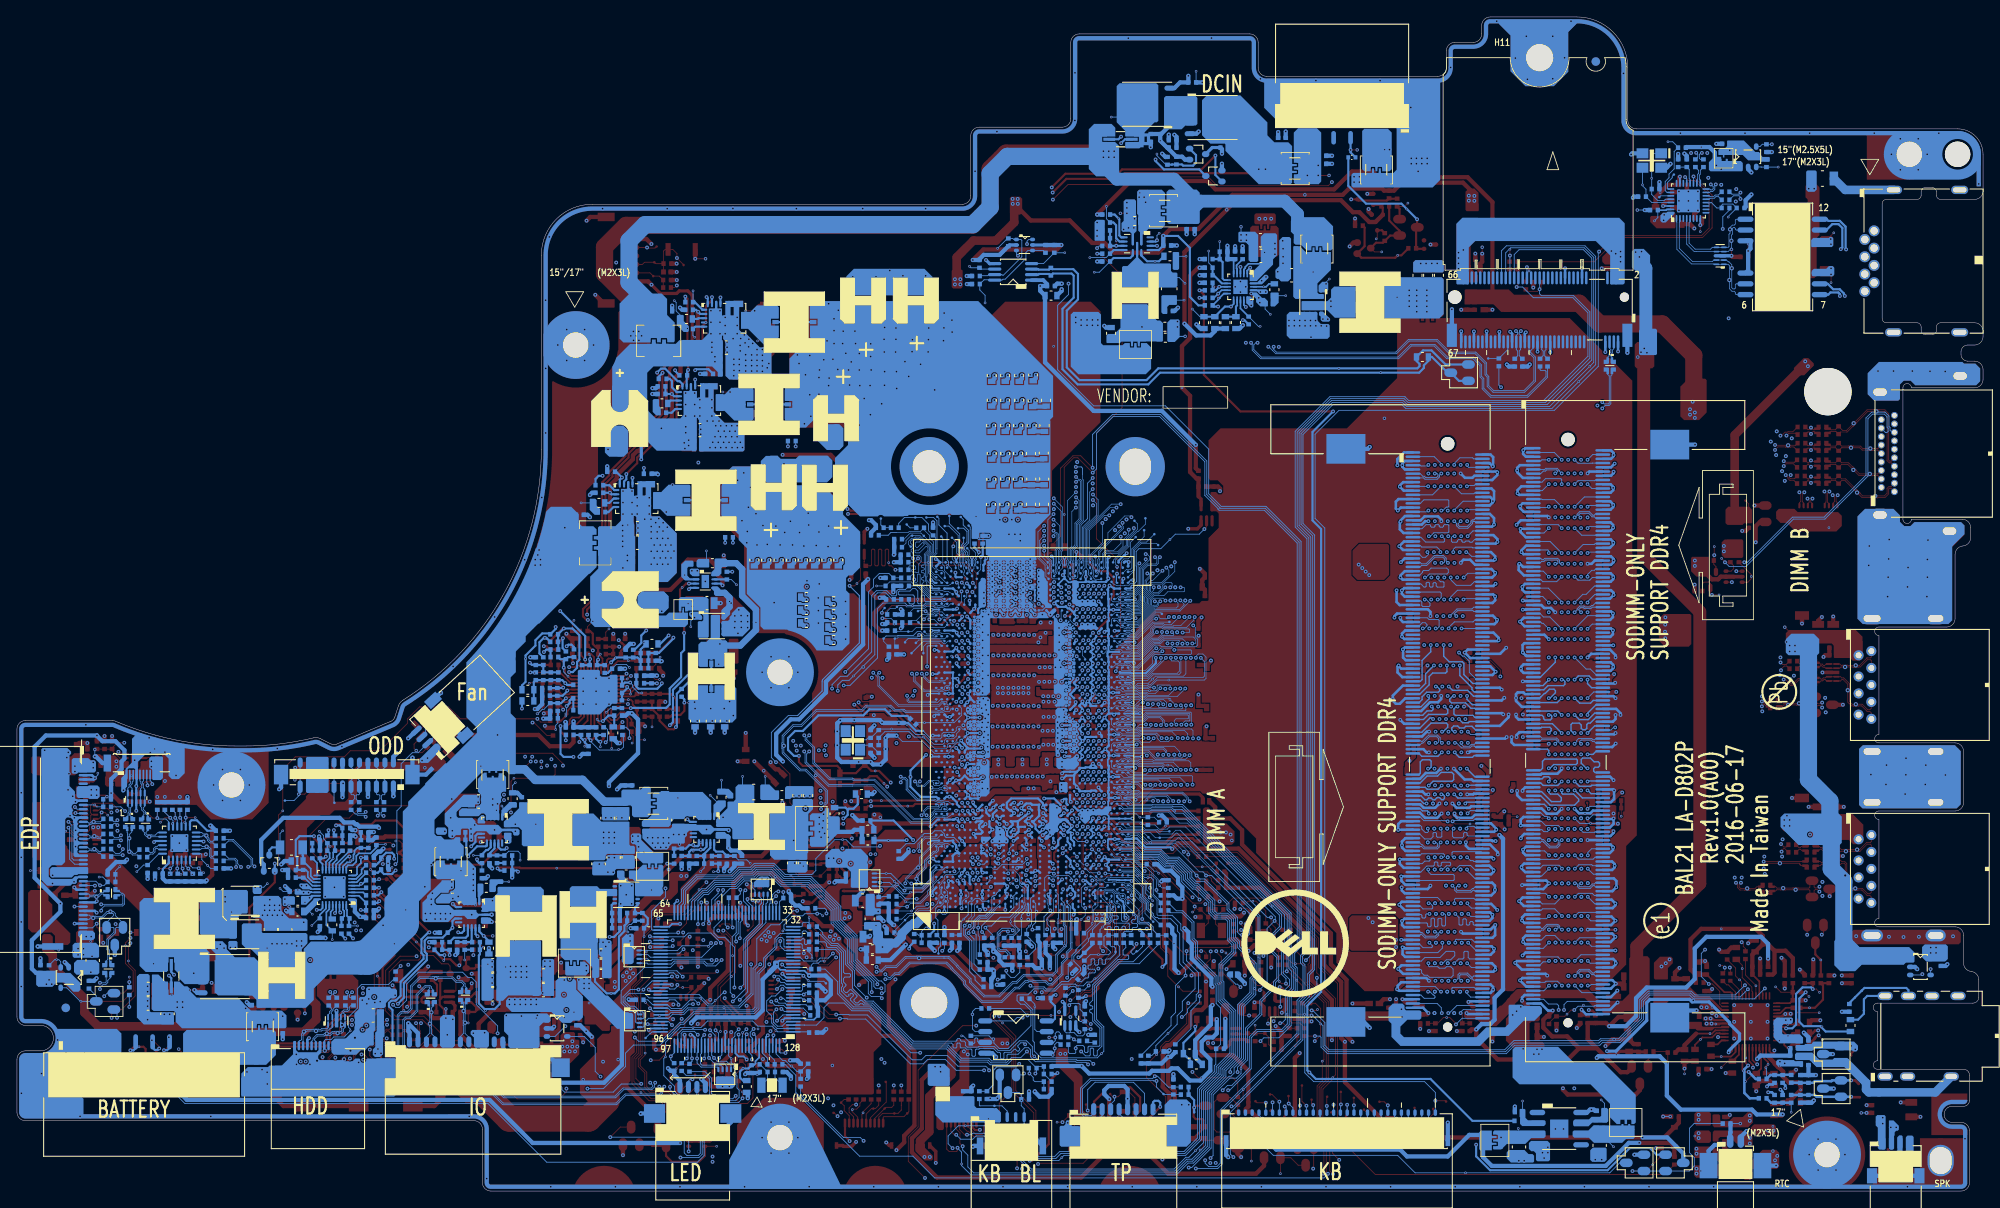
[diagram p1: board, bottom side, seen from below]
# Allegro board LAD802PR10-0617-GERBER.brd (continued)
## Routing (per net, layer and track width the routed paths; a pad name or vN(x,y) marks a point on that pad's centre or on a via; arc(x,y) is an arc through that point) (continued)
KSO8: length 111.7
  TOP w0.102: v2(75.01,10.18) 75.01,8.95 ZT37.1 ; v2(149.31,25.93) 149.52,25.71 156.65,25.71 v2(158.59,23.77)
  IN1 w0.127: v2(75.01,10.18) 78.21,6.98 87.97,6.98 88.95,7.96 99.78,7.96 100.55,8.73 105.8,8.73 106.63,9.56 114.23,9.56 114.59,9.92 114.59,9.92 114.64,9.97 123.45,9.97 124.76,11.28 130.75,11.28 132.53,13.06 132.53,13.44 139.3,20.21 139.32,20.21 140.55,21.44 140.55,22.43 141.52,23.41 144.19,23.41 145.18,24.4 146.89,24.4 v2(147.28,24.01) 149.19,25.93 v2(149.31,25.93)
  BOTTOM w0.102: RPE6.8 158.66,20.84 158.73,20.91 158.73,21.16 159.15,21.57 159.69,21.57 160.41,22.29 160.41,22.92 159.56,23.77 v2(158.59,23.77) ; JKB1.17 75,10.17 v2(75.01,10.18) ; UE1.46 147.06,32.71 147.06,30.47 147.54,29.99 147.54,29.04 147.28,28.77 v2(147.28,24.01)
KSO9: length 90.1
  TOP w0.102: v2(83,10.54) 83.86,11.4 ZT47.1 ; RE15.1 157.01,29.82 v2(157.25,30.05)
  IN1 w0.127: v2(83,10.54) 85.47,13.01 94.47,13.01 95.16,12.32 98.11,12.32 99.04,13.25 109.6,13.25 109.65,13.19 113.55,13.19 114.91,14.56 116.97,14.56 117.07,14.66 118.45,14.66 118.94,14.17 121.3,14.17 121.55,14.42 121.55,14.42 122.33,15.21 123.98,15.21 124.56,14.63 126.07,14.63 126.65,15.21 128.92,15.21 133.62,19.91 133.62,20.85 135.02,22.24 135.02,24.05 137.86,26.9 138.29,26.9 139.43,26.9 141.08,28.55 148.15,28.55 v2(148.86,29.26)
  BOTTOM w0.102: JKB1.7 83,10.54 v2(83,10.54) ; v2(148.86,29.26) 150.04,30.43 152.74,30.43 153.18,29.99 155.03,29.99 155.09,29.93 155.93,29.93 UE1.68 157.17,29.98 v2(157.25,30.05)
KSO10: length 87.3
  TOP w0.102: ZT49.1 85.64,10.42 v2(84.6,10.42)
  IN1 w0.127: v2(84.6,10.42) 86.68,12.5 94.25,12.5 94.95,11.81 98.32,11.81 99.25,12.74 109.25,12.74 109.31,12.69 113.76,12.69 114.46,13.39 123.27,13.39 124,14.12 126.28,14.12 126.62,14.46 129.84,14.46 132.16,16.78 132.16,17.73 134.13,19.7 134.13,20.63 135.53,22.03 135.53,23.84 138.08,26.39 139.64,26.39 141.29,28.04 148.82,28.04 150.03,29.25 v2(150.03,29.26)
  BOTTOM w0.102: v2(150.03,29.26) 150.36,28.93 153.44,28.93 154,28.38 UE1.72 156.95,28.38 156.96,28.37 157.54,28.37 157.55,28.39 RPE5.8 ; v2(84.6,10.42) JKB1.5
KSO11: length 88.4
  TOP w0.102: v2(83.8,10.46) 83.8,9.74 ZT48.1
  IN1 w0.127: v2(149.45,29.26) 149.45,29.25 148.49,28.29 141.18,28.29 139.53,26.64 138.18,26.64 137.97,26.64 135.28,23.95 135.28,22.14 133.88,20.74 133.88,19.81 131.91,17.84 131.91,16.89 129.73,14.71 126.52,14.71 126.18,14.37 123.89,14.37 123.17,13.65 114.36,13.65 113.65,12.94 109.41,12.94 109.36,13 99.15,13 98.21,12.06 95.05,12.06 94.36,12.76 86.09,12.76 v2(83.8,10.46)
  BOTTOM w0.102: RPE5.7 157.5,27.89 157.19,27.58 UE1.74 151.13,27.58 v2(149.45,29.26) ; v2(83.8,10.46) JKB1.6
KSO12: length 92.2
  TOP w0.102: v2(79.01,10.14) 79.2,10.34 ZT42.1
  IN1 w0.127: v2(79.01,10.14) 80.2,8.95 88.14,8.95 88.42,9.23 99.25,9.23 100.02,10 104.35,10 105.18,10.83 113.7,10.83 114.73,11.87 117.33,11.87 117.94,11.26 122.94,11.26 124.53,12.85 126.81,12.85 127.15,13.19 130.37,13.19 133.43,16.25 133.43,17.2 137.88,21.65 137.88,23.31 138.41,23.84 139.67,23.84 140.99,25.16 140.99,25.8 141.24,26.05 145.2,26.05 146.16,27.01 147.66,27.01 148.17,26.5 149.21,26.5 v2(149.96,27.25)
  BOTTOM w0.102: RPE5.6 157.5,27.39 157.29,27.18 UE1.75 154.75,27.18 154.58,27.35 150.06,27.35 v2(149.96,27.25) ; JKB1.12 79,10.13 v2(79.01,10.14)
KSO13: length 89.4
  TOP w0.102: ZT45.1 81.92,10.35 v2(81.9,10.32)
  IN1 w0.127: v2(149.37,27.26) 149.37,27.32 148.91,27.78 141.39,27.78 139.74,26.14 138.18,26.14 135.78,23.74 135.78,21.93 134.39,20.53 134.39,19.6 132.42,17.63 132.42,16.68 129.94,14.2 126.73,14.2 126.39,13.86 124.1,13.86 123.38,13.14 114.57,13.14 113.86,12.43 109.2,12.43 109.15,12.49 99.36,12.49 98.34,11.47 87.21,11.47 85.74,10 82.95,10 82.49,10.46 82.03,10.46 v2(81.9,10.32)
  BOTTOM w0.102: v2(149.37,27.26) 149.55,27.08 149.55,27.08 149.84,26.79 150.48,26.79 150.82,27.12 154.4,27.12 154.74,26.78 UE1.76 157.47,26.78 157.58,26.89 RPE5.5 ; v2(81.9,10.32) 81.4,9.82 JKB1.9
KSO14: length 97
  TOP w0.102: ZT46.1 82.37,8.8 v2(82.37,9.97)
  IN1 w0.127: v2(82.37,9.97) 82.6,9.75 85.84,9.75 87.31,11.22 98.45,11.22 99.46,12.24 109.04,12.24 109.1,12.18 113.97,12.18 114.67,12.88 123.48,12.88 124.21,13.61 126.49,13.61 126.83,13.95 130.05,13.95 132.67,16.57 132.67,17.52 137.12,21.97 137.12,24.71 138.29,25.88 139.85,25.88 141.39,27.42 148.62,27.42 v2(148.79,27.26)
  BOTTOM w0.102: RPE6.6 158.84,19.84 158.96,19.96 158.96,21.06 159.09,21.19 159.63,21.19 160.64,22.2 160.64,23.62 157.87,26.38 UE1.77 154.82,26.38 154.3,26.9 150.91,26.9 150.58,26.56 149.49,26.56 v2(148.79,27.26) ; JKB1.8 82.2,9.81 v2(82.37,9.97)
KSO15: length 101.7
  TOP w0.102: v2(80.56,10.09) ZT44.1
  IN1 w0.127: v2(80.56,10.09) 81.2,9.45 85.91,9.45 87.39,10.94 98.53,10.94 99.57,11.98 108.94,11.98 109.58,11.34 113.49,11.34 113.72,11.58 114.52,12.37 117.54,12.37 118.15,11.77 122.73,11.77 124.32,13.36 126.6,13.36 126.94,13.7 130.16,13.7 132.93,16.47 132.93,17.42 137.37,21.86 137.37,24.26 138.07,24.96 139.62,24.96 140.33,25.68 140.33,26.01 141.5,27.17 144.89,27.17 v2(145.31,26.75)
  BOTTOM w0.102: v2(145.31,26.75) 145.31,23.32 146.79,21.84 150.41,21.84 151.36,22.78 155.12,22.78 155.12,22.78 UE1.86 157.34,22.78 157.88,23.32 159.68,23.32 160.18,22.83 160.18,22.39 159.59,21.8 159.02,21.8 158.37,21.14 158.12,21.14 157.94,20.97 157.94,20.44 158.04,20.34 RPE6.7 ; JKB1.10 80.6,10.05 v2(80.56,10.09)
KSO16: length 98.7
  TOP w0.102: ZT43.1 80.33,10.59 v2(79.81,10.06)
  IN1 w0.127: v2(144.23,26.75) 143.78,26.3 141.14,26.3 140.59,25.76 140.59,25.57 139.72,24.71 138.17,24.71 137.62,24.16 137.62,21.76 133.18,17.31 133.18,16.36 130.26,13.44 127.04,13.44 126.7,13.1 124.42,13.1 122.83,11.51 118.04,11.51 117.44,12.12 114.63,12.12 113.59,11.09 109.47,11.09 108.86,11.7 99.65,11.7 98.63,10.69 88.73,10.69 87.24,9.2 80.67,9.2 v2(79.81,10.06)
  BOTTOM w0.102: JKB1.11 79.8,10.06 v2(79.81,10.06) ; v2(144.23,26.75) 144.84,26.14 144.84,21.68 145.14,21.38 152.7,21.38 153.23,20.85 154.58,20.85 155.04,20.38 UE1.92 157.39,20.38 157.94,19.83 157.94,19.44 158.04,19.34 RPE6.5
L_BKLT_CTRL: length 157.3
  TOP w0.102: v2(116.63,20.66) 116.63,20.29 114.32,17.98 114.32,11.58 v1(113.43,10.69) 111.97,9.23 111.97,5.48 113.94,3.51 v2(113.94,2.69)
  IN1 w0.127: v2(113.94,2.69) 114.53,2.1 123.68,2.1 124.31,2.72 125.43,2.72 125.8,2.35 154.03,2.35 165.72,14.03 167.7,14.03 171.6,17.93 179.97,17.93 183.07,21.04 186.13,21.04 186.25,21.15 193.08,21.15 195,19.23 215.57,19.23 218.06,21.72 v2(218.65,21.72)
  IN2 w0.142: v2(116.63,20.66) 116.63,20.66 116.8,20.83 116.8,24.97 116.26,25.51 116.26,29.35 116.49,29.57 116.49,32.24 116.89,32.65 116.89,34.75 116.54,35.1 116.54,38.84 v2(116.16,39.22)
  BOTTOM w0.102: UC1.R11 115.79,39.22 v2(116.16,39.22) ; R8.1 v2(218.65,21.72)
L_BKLT_EN_EC: length 69.4
  IN1 w0.127: v2(116.22,24.94) 116.57,25.29 119.44,25.29 119.66,25.51 127.61,25.51 129.85,27.75 132.21,27.75 133.75,29.29 133.75,29.99 135.33,31.57 136.91,31.57 137.14,31.79 137.98,31.79 139.1,32.91 139.72,32.91 v2(139.88,33.07)
  IN2 w0.142: v2(116.22,24.94) 115.99,25.17 115.99,29.46 116.22,29.68 116.22,32.36 116.56,32.69 116.56,34.54 116.23,34.87 116.23,37.9 115.69,38.44 115.69,39.4 v2(116.09,39.8)
  BOTTOM w0.102: UC1.R12 115.86,39.8 v2(116.09,39.8) ; UE1.91 155.03,20.78 154.73,21.07 153.33,21.07 152.8,21.61 146.7,21.61 145.08,23.22 145.08,26.25 144.63,26.7 144.63,29.76 142.98,31.41 141.98,31.41 140.32,33.07 v2(139.88,33.07) ; v2(116.22,24.94) 115.95,24.94 RC6.2
LAN_EN: length 251.5
  IN2 w0.127: v2(24.91,123.48) 25.79,122.6 25.79,118.13 30.27,113.65 30.27,107.1 29.5,106.33 29.5,99.54 22.27,92.31 20.78,92.31 15.45,86.98 15.45,78.58 15.58,78.45 15.58,78.44 19.51,74.5 19.51,37.23 26.11,30.63 32.83,30.63 37.72,25.74 37.72,17.97 39.01,16.69 39.01,15.83 43.39,11.45 43.39,9.5 47.04,5.85 53.85,5.85 54.03,5.67 54.47,5.23 55.08,4.62 82.59,4.62 83.64,3.57 89.2,3.57 90.24,4.62 98.66,4.62 99.64,3.63 110.17,3.63 112.02,5.49 113.7,5.49 116.51,8.29 119.29,8.29 125.37,14.37 v2(125.37,16.31)
  BOTTOM w0.102: v2(125.37,16.31) 126.43,16.31 131.38,21.26 133.42,21.26 134.33,22.18 136.16,22.18 136.71,21.63 136.71,20.45 137.59,19.58 139.02,19.58 139.03,19.58 UE1.3 ; UL3.4 26.31,123.21 26.04,123.48 RL6.2 v2(24.91,123.48)
LAN_MDI0N: length 15.6
  BOTTOM w0.089: TL1.5 29.12,107.02 29.22,106.92 29.22,106.52 29.32,106.42 29.49,106.42 29.64,106.56 v3(29.64,108.86) 29.64,109.28 29.97,109.61 30.05,109.61 30.26,109.82 EU3501.2 EU3501.8 31.76,109.82 31.93,109.65 34.27,109.65 35.83,111.21 35.83,114.26 35.75,114.34 UL1.2
LAN_MDI0P: length 15.6
  BOTTOM w0.089: UL1.1 36.15,114.32 36.11,114.28 36.11,111.09 34.38,109.37 31.77,109.37 31.73,109.32 EU3501.9 EU3501.1 30.08,109.32 29.92,109.17 v3(29.92,107.46) 29.92,106.45 29.61,106.14 29.35,106.14 29.22,106.01 29.22,105.84 29.12,105.75 TL1.6
LAN_MDI1N: length 12.9
  BOTTOM w0.089: TL1.1 29.12,114.64 29.22,114.54 29.22,114.07 29.35,113.95 29.57,113.95 29.84,113.68 v3(29.84,113.44) 29.84,113 29.97,112.87 29.97,111.41 30.06,111.32 EU3501.5 EU3501.6 31.93,111.32 32.15,111.11 33.95,111.11 34.67,111.82 34.67,114.21 34.55,114.33 UL1.5
LAN_MDI1P: length 13
  BOTTOM w0.089: UL1.4 34.95,111.7 34.07,110.82 33.84,110.82 EU3501.7 EU3501.4 30.07,110.82 29.68,111.21 v3(29.68,112.1) 29.68,112.75 29.56,112.88 29.56,113.56 29.45,113.67 29.32,113.67 29.22,113.57 29.22,113.46 29.12,113.37 TL1.2
LAN_TXN_C_PCH_RXN6: length 2.1
  BOTTOM w0.097: CL2.2 33.55,120.41 33.55,120.04 33.66,119.94 33.66,119.38 33.75,119.28 UL1.18
LAN_TXP_C_PCH_RXP6: length 2.1
  BOTTOM w0.097: UL1.17 33.35,119.27 33.45,119.36 33.45,119.85 33.35,119.95 33.35,120.41 CL1.2
LAN_WAKE#: length 33
  TOP w0.076: 102.54,37.72 103.02,37.72
  TOP w0.089: v2(105.71,41.24) 105.88,41.24 106.09,41.03 106.09,38.3 105.88,38.09 105.37,38.09 105.15,37.87 103.16,37.87 103.02,37.72
  TOP w0.102: 102.54,37.72 101.97,38.3 98.83,38.3 98.33,37.8 98.33,36.91 99.22,36.02 99.22,33.6 v1(100.22,32.59) 100.22,32.48 101.93,30.77 101.93,27.96 105.49,24.4 v2(105.49,24.25)
  BOTTOM w0.102: v2(105.49,24.25) 105.49,24.21 105.99,23.72 RC85.2 107.1,24.12 107.68,24.12 107.83,23.97 RC100.2 ; UC1.AM15 106.78,41.24 v2(105.71,41.24)
LANXIN: length 8.4
  BOTTOM w0.102: YL1.1 38.87,122.41 39.08,122.2 v1(39.08,119.46) CL10.1 39.08,117.56 38.38,116.86 37.61,116.86 37.47,117 UL1.28
LANXOUT: length 6.8
  BOTTOM w0.102: UL1.29 39.06,116.6 CL11.1 39.76,118.18 40.17,118.59 v1(40.17,118.7) YL1.3
LCD_BRIGHTNESS: length 8.3
  TOP w0.102: v2(225.83,43.55) 225.02,43.55 224.18,44.4 RP2.2
  BOTTOM w0.102: JEDP1.23 225.21,39.05 225.42,39.26 225.42,43.15 v2(225.83,43.55)
LCD_TST: length 128.3
  TOP w0.102: RP2.6 222.29,44.9 222.03,45.15 221.25,45.15 v2(220.76,44.66) ; v2(218.52,29.24) 218.75,29.01 v1(218.75,27.15) 218.75,26.83 217.96,26.04 217.96,23.01 219.56,21.41 D3.3 220.73,21.14 v2(220.73,20.43)
  IN1 w0.127: v2(220.73,20.43) 220.25,20.91 217.7,20.91 215.76,18.98 194.9,18.98 192.98,20.9 187.88,20.9 187.23,20.25 187.23,19.92 184.99,17.68 172.71,17.68 168.81,13.78 166.31,13.78 v2(164.61,12.08) ; v2(220.76,44.66) 220.76,38.89 219.3,37.43 219.3,30.02 v2(218.52,29.24)
  BOTTOM w0.102: v2(164.61,12.08) 162.73,12.08 160.12,14.7 160.12,16.27 159.16,17.23 156.05,17.23 153.6,19.68 153.24,19.68 151.99,20.92 144.95,20.92 144.38,21.5 144.38,25.64 143.59,26.43 143.59,27.39 142.28,28.7 142.28,29.66 142.04,29.9 141.66,29.9 141.43,29.67 141.43,28.88 141.33,28.78 UE1.26
LCD_TST_C: length 3.1
  TOP w0.102: v4(225.64,44.28) 225.32,44.6 v2(225,44.6) 224.7,44.9 RP2.3
  BOTTOM w0.102: JEDP1.12 224.96,44.55 v2(225,44.6)
LCD_VCC_TEST_EN: length 6.8
  TOP w0.102: v2(147.19,14.58) 146.46,15.31 RE44.2 145.97,14.86 145.97,14.38 145.56,13.98 145.56,13.3 RE64.2
  BOTTOM w0.102: v2(147.19,14.58) 147.19,14.67 147.66,15.14 v1(147.66,15.64) 147.66,15.65 147.96,15.95 UE1.113
LCD_VCC_TEST_EN_R: length 96.6
  TOP w0.102: v2(146.31,10.94) v1(146.31,11.69) 146.78,12.16 RE64.1
  IN2 w0.127: v2(218.42,13.15) 219.2,13.92 219.2,20.57 v2(221.61,22.98)
  BOTTOM w0.102: D4.3 221.25,23.34 v2(221.61,22.98) ; v2(218.42,13.15) 214.92,13.15 212.08,10.32 176.33,10.32 169.41,3.4 151.65,3.4 150.85,4.2 150.85,8.61 149.02,10.43 146.8,10.43 146.31,10.92 v2(146.31,10.94)
LCDVDD_EN: length 6.7
  BOTTOM w0.102: R10.1 222.55,23.02 D4.1 v1(224.37,22.38) 224.43,22.38 226.04,23.98 U1.4
LDO1_CAP: length 4.5
  TOP w0.203: UA1.27 25.99,16.03 25.85,15.9 25.85,15.68 25.36,15.19 v1(25.36,14.94) 25.7,14.6 RA41.2
  TOP w0.254: RA41.2 25.66,13.87 CA20.2
LDO2_CAP: length 4.7
  TOP w0.203: UA1.39 31.01,18.56 31.07,18.62 31.45,18.62 31.95,18.12 33.1,18.12 v1(33.33,17.89) 33.98,17.24 CA21.2
LDO3_CAP: length 5.1
  TOP w0.102: UA1.7 27.19,23.51 27.27,23.59 27.27,24.05 28.4,25.19 v1(28.4,26.24) 28.4,26.63 CA22.2
LDO_+1VALW: length 3.4
  BOTTOM w0.508: 147.97,41.74 148,41.72 148,40.49 v1(147.98,40.47) 147.68,40.17 146.84,40.17 146.39,39.72 PC306.1
LED1: length 8
  BOTTOM w0.102: v1(37.17,123.78) 36.6,123.78 35.97,123.16 RL1.2 36.43,122.62 36.43,120.58 37.04,119.97 37.04,119.53 37.48,119.09 37.48,118.01 37.28,117.8 UL1.26
LG_1.2V: length 8.2
  TOP w0.102: v2(86.32,105.11) v4(86.32,105.87)
  IN1 w0.762: 78.51,103.57 78.81,103.88 85.63,103.88 85.77,104.02
  vias: v2(77.29,102.85) v2(77.87,102.86) v2(86.32,104.48)
LGATE_CHG: length 4.8
  IN2 w0.762: 203.35,36.6 203.21,36.75 199.87,36.75 199.73,36.6
  BOTTOM w0.102: v1(202.37,36.26) 202.8,35.84 v2(203.22,35.84)
  vias: v2(197.76,36.03) v2(198.34,36.03) v2(203.8,35.84)
LID_CLOSE#: length 175.7
  TOP w0.102: v2(168.43,50.17) 168.43,49.12 168.86,48.69 v1(173.28,48.69) 173.63,48.34 v2(173.63,44.66) ; v2(154.07,106.83) 154.32,106.58 R22.1 ; v2(145.73,34.45) 145.73,34.47 145.26,34.94 CE19.1 RE25.2 ; D5.1 v2(218.51,30.5)
  IN1 w0.127: v2(145.73,34.45) 146.03,34.75 149.48,34.75 149.72,34.99 154.44,34.99 155,34.44 157.12,34.44 158.14,35.45 158.14,37.23 160.46,39.55 160.46,42.36 159.56,43.26 159.56,47.14 161.46,49.04 167.31,49.04 v2(168.43,50.17) ; v2(217.82,38.32) 218.51,37.63 v2(218.51,30.5)
  IN2 w0.127: v2(168.43,50.17) 168.43,50.4 168.45,50.41 168.45,51.65 173.1,56.3 173.1,67.51 167.33,73.27 167.33,90.9 161.75,96.47 161.75,101.59 156.52,106.83 v2(154.07,106.83) ; v2(217.82,38.32) 216.55,39.58 214.44,39.58 214.12,39.26 210.68,39.26 209.8,40.14 200.98,40.14 197.31,43.82 192.47,43.82 191.63,42.97 190.06,42.97 189.7,43.33 184.67,43.33 183.14,44.85 173.82,44.85 v2(173.63,44.66)
  BOTTOM w0.102: v2(145.73,34.45) 145.79,34.38 145.79,34.22 145.16,33.59 UE1.41
LID_CLOSE#_C: length 4.7
  TOP w0.102: R22.2 EC2902.1 156.14,107.93 ZT3.1 157.23,108.31 JPWR1.2
LINE1-L_C: length 15.6
  TOP w0.102: v1(18.94,17.86) 19.39,18.31 v2(19.39,18.37)
  TOP w0.305: CA32.2 19.83,17.99 19.83,18.06 19.53,18.37 v2(19.39,18.37)
  IN2 w0.305: v2(19.39,18.37) 19.53,18.37 19.83,18.06 19.83,17.67 19.83,17.67 19.83,17.17 20.4,16.6 20.4,12.16 21.65,10.91 24.61,10.91 v2(25.34,11.65)
  BOTTOM w0.305: RA28.1 24.91,11.65 v2(25.34,11.65)
LINE1-L_R: length 15.6
  TOP w0.102: v2(19.45,18.95) 19.44,18.95 v1(19.01,19.39)
  TOP w0.305: v2(19.45,18.95) 19.45,18.94 19.79,18.94 20.11,18.62 CA33.2
  IN2 w0.305: v2(19.45,18.95) 19.45,18.94 19.77,18.94 20.34,18.37 20.34,17.88 20.34,17.88 20.34,17.38 20.91,16.81 20.91,12.37 21.86,11.42 24.4,11.42 25.31,12.34 v2(25.48,12.34)
  BOTTOM w0.305: RA32.1 24.79,12.58 25.24,12.58 v2(25.48,12.34)
LINE1_L: length 3.9
  TOP w0.203: 22.56,17.29 v1(22.94,16.91) 23.12,16.91 23.45,17.24 23.45,18.12 23.9,18.56 UA1.22
  TOP w0.305: CA32.1 21.93,17.29 22.56,17.29
LINE1_R: length 2.9
  TOP w0.203: 22.46,18.62 22.5,18.62 22.82,18.31 v1(23.01,18.31) 23.07,18.31 23.72,18.96 UA1.21
  TOP w0.305: CA33.1 22.46,18.62
LOM_TCT: length 6.1
  TOP w0.102: v2(27.7,110.89) v1(27.7,111.72)
  TOP w0.508: v2(27.7,110.89) 27.69,110.88 CL12.1
  BOTTOM w0.508: TL1.4 27.7,108.6 v2(27.7,110.89) 27.43,111.17 27.43,111.89 27.64,112.1 TL1.3
LP#_+VCCEOPIO: length 4.4
  BOTTOM w0.102: PR1201.1 103.43,110.11 v1(105.35,110.11)
  BOTTOM w0.254: PR1201.1 102.54,111 PU1200.6
LPC_LAD0: length 142.9
  TOP w0.102: JDB1.8 122.24,4.95 121.94,4.65 121.09,4.65 120.99,4.76 120.99,5.1 v2(120.96,5.1)
  IN2 w0.127: v2(120.96,5.1) 120.99,5.1 121.81,5.92 121.81,8.64 128.25,15.07 128.25,16.46 131.19,19.4 131.19,23.36 v2(131.08,23.47)
  BOTTOM w0.076: 99.88,41.01 100.57,41.01 100.68,41.12 100.95,41.12 101.07,41.07 101.21,41.07 101.44,41.13 101.56,41.13 101.77,41.06 101.88,40.96 101.99,40.85 UC1.AY13
  BOTTOM w0.102: v2(120.96,5.1) 120.99,5.1 120.99,5.1 120.48,4.59 v1(120.48,3.19) 120.48,3 119.39,1.91 95.14,1.91 93.75,3.29 93.14,3.29 91.27,5.16 91.27,11.53 89.3,13.5 89.3,14.21 87.69,15.82 87.69,21.9 86.24,23.35 86.24,25 85.75,25.5 85.75,26.87 87.69,28.81 87.69,29.44 88.18,29.93 88.18,32.19 89.17,33.19 89.17,33.87 91.85,36.54 92.83,36.54 93.33,37.03 93.33,37.58 94.94,39.2 96.11,39.2 97,40.09 98.95,40.09 99.88,41.01 ; UE1.59 152.36,34.13 151.05,35.43 150.56,35.43 149.62,36.38 147.28,36.38 146.39,37.27 145.02,37.27 144.56,37.74 142.98,37.74 141.66,36.42 138.52,36.42 135.41,33.31 135.41,31.77 133.5,29.85 133.5,27.05 131.08,24.62 v2(131.08,23.47)
LPC_LAD1: length 137.6
  TOP w0.102: v2(121.11,6.64) 121.32,6.64 121.74,7.05 JDB1.7
  IN2 w0.127: v2(129.94,23.92) 129.97,23.92 130.31,23.58 130.31,23.28 130.68,22.92 130.68,19.61 127.74,16.68 127.74,15.28 121.31,8.85 121.31,6.83 v2(121.11,6.64)
  BOTTOM w0.076: UC1.BA13 101.29,40.85 101.04,40.6 100.22,40.6 99.53,39.91
  BOTTOM w0.102: 99.53,39.91 99.33,39.71 97.16,39.71 96.27,38.82 95.21,38.82 93.83,37.44 93.83,36.89 93.02,36.08 92.72,36.08 90.86,34.23 90.86,32.96 90.44,32.54 89.18,32.54 88.63,32 88.63,29.74 88.15,29.25 88.15,28.1 89.67,26.57 89.67,24.79 89.54,24.67 89.54,22.69 88.15,21.3 88.15,16.01 89.76,14.4 89.76,13.68 91.73,11.72 91.73,5.35 93.33,3.75 93.94,3.75 95.33,2.37 112.35,2.37 115.72,5.73 117.05,5.73 117.82,6.51 118.77,6.51 119.16,6.11 120.59,6.11 v2(121.11,6.64) ; UE1.60 152.76,34.05 151.15,35.66 150.66,35.66 149.71,36.61 147.37,36.61 146.48,37.5 145.11,37.5 144.65,37.97 142.88,37.97 141.56,36.64 138.43,36.64 135.19,33.41 135.19,31.86 133.27,29.95 133.27,27.14 130.83,24.7 130.83,24.13 130.62,23.92 v2(129.94,23.92)
LPC_LAD2: length 141.5
  TOP w0.102: JDB1.6 121.24,7.44 120.67,6.88 120.67,5.61 v2(120.35,5.29)
  IN2 w0.127: v2(130.42,24.4) 130.42,23.92 130.56,23.78 130.56,23.39 130.93,23.02 130.93,19.5 128,16.57 128,15.18 121.56,8.74 121.56,6.3 120.54,5.29 v2(120.35,5.29)
  BOTTOM w0.076: UC1.BB13 100.76,40.77 100.11,40.77 99.24,39.9
  BOTTOM w0.102: v2(130.42,24.4) 130.42,24.61 133.04,27.24 133.04,30.04 134.96,31.96 134.96,33.5 138.33,36.87 141.47,36.87 142.79,38.19 144.74,38.19 145.21,37.73 146.58,37.73 147.47,36.84 151.61,36.84 153.06,35.39 153.06,33.86 153.16,33.76 UE1.61 ; v2(120.35,5.29) 120.35,4.84 119.74,4.23 119.74,2.84 119.04,2.14 95.23,2.14 93.85,3.52 93.23,3.52 91.5,5.26 91.5,11.62 89.53,13.59 89.53,14.3 87.92,15.91 87.92,21.99 86.47,23.44 86.47,25.1 85.97,25.59 85.97,26.78 87.92,28.72 87.92,29.35 88.4,29.84 88.4,32.09 89.08,32.77 90.35,32.77 90.61,33.04 90.61,34.3 92.62,36.31 92.93,36.31 93.55,36.94 93.55,37.49 95.07,39.01 96.19,39.01 97.08,39.9 99.24,39.9
LPC_LAD3: length 139.2
  TOP w0.102: v2(119.84,6.64) 120.11,6.64 120.74,7.26 JDB1.5
  IN2 w0.127: v2(119.84,6.64) 120.16,6.96 120.16,8.06 127.49,15.39 127.49,16.78 130.42,19.71 130.42,22.81 129.9,23.34 v2(129.89,23.34)
  BOTTOM w0.076: 99.72,39.83 100.33,40.44 101.52,40.44 101.65,40.56 101.99,40.56 101.99,40.57 102,40.57 102.28,40.28 UC1.AY12
  BOTTOM w0.102: v2(119.84,6.64) 119.34,6.64 119.17,6.81 117.75,6.81 117.11,6.18 115.84,6.18 115.63,5.96 115.62,5.96 112.26,2.6 95.42,2.6 94.04,3.98 93.67,3.98 v1(92.9,4.76) 91.96,5.7 91.96,11.81 89.99,13.78 89.99,14.49 88.37,16.1 88.37,21.2 89.77,22.6 89.77,24.57 89.9,24.7 89.9,26.67 88.37,28.19 88.37,29.16 88.86,29.65 88.86,31.9 89.27,32.31 90.54,32.31 91.09,32.87 91.09,34.13 92.81,35.85 93.12,35.85 94.06,36.79 94.06,37.34 95.34,38.63 96.35,38.63 97.24,39.52 99.41,39.52 99.72,39.83 ; v2(129.89,23.34) 129.71,23.34 129.51,23.54 129.51,24.35 129.94,24.78 130.27,24.78 132.81,27.33 132.81,30.14 134.73,32.05 134.73,33.6 138.24,37.1 138.83,37.1 141.37,37.1 142.69,38.42 144.84,38.42 145.3,37.96 146.67,37.96 147.56,37.07 151.71,37.07 153.29,35.49 153.29,33.96 153.56,33.68 UE1.62
LPC_LFRAME#: length 134.2
  TOP w0.102: v2(117.47,7.26) 117.47,6.77 117.81,6.43 119.06,6.43 119.68,7.05 119.83,7.05 120.24,7.46 JDB1.4
  IN2 w0.127: v2(129.89,22.75) 129.89,19.54 127.24,16.89 127.24,15.5 119.51,7.77 117.98,7.77 v2(117.47,7.26)
  BOTTOM w0.089: UC1.BA12 101.8,40.26 100.43,40.26 100.42,40.26
  BOTTOM w0.102: UE1.58 151.96,34.2 150.96,35.2 150.47,35.2 149.52,36.15 147.19,36.15 146.29,37.04 144.92,37.04 144.46,37.51 143.07,37.51 141.75,36.19 138.61,36.19 135.64,33.22 135.64,31.67 133.73,29.76 133.73,26.95 131.48,24.71 131.48,23.3 131.13,22.94 130.08,22.94 v2(129.89,22.75) ; 100.42,40.26 99.49,39.32 97.32,39.32 96.43,38.44 95.47,38.44 94.28,37.25 94.28,36.7 93.21,35.62 92.91,35.62 91.32,34.04 91.32,32.77 90.63,32.08 89.37,32.08 89.09,31.81 89.09,29.55 88.6,29.06 88.6,28.29 90.13,26.76 90.13,24.61 90,24.48 90,22.5 88.6,21.11 88.6,16.2 90.22,14.59 90.22,13.87 92.18,11.91 92.18,6.08 94.05,4.21 108.4,4.21 v1(108.66,3.95) 109.01,3.6 111.64,3.6 114.44,6.41 116.83,6.41 117.47,7.04 v2(117.47,7.26)
LPSS_UART2_CTS#: length 16.8
  TOP w0.102: v2(107.54,36.66) 106.99,36.11 106.99,35.03 108.26,33.76 108.26,29.5 108.48,29.28 109.89,29.28 v1(110.19,28.97) 111.02,28.15 RC43.1
  BOTTOM w0.089: UC1.AD4 110.68,36.93 110.38,37.23 110,37.23 109.83,37.05 109.41,37.05 109.25,37.21 107.84,37.21 107.54,36.91 v2(107.54,36.66)
LX_1.2V: length 9
  TOP w0.508: PC207.1 v2(76.92,104.35)
  IN2 w0.762: 84.59,105.16 78.37,105.16 78,104.79
  BOTTOM w0.102: PC200.2 84.68,104.04 v1(84.06,103.43)
  vias: v2(76.92,104.98) v2(85.3,104.79) v2(85.43,105.36)
LX_1.8VALW: length 1.9
  TOP w0.102: v2(163.28,35.27) v1(162.64,35.27)
  TOP w0.508: PR506.1 v2(163.28,35.27)
LX_3V: length 2.6
  TOP w0.102: v2(169.5,43.27) v1(170.7,43.27)
  TOP w0.508: PR106.1 169.25,43.52 v2(169.5,43.27)
  vias: v2(173.12,43.27) v2(176.99,44.09)
LX_5V: length 2.5
  TOP w0.508: PR112.1 173.63,34.95 v2(174.14,34.44)
  BOTTOM w0.254: v2(180.49,33.87) 180.12,33.5 PU102.6
  vias: v1(177.82,33.74) v2(175.81,34.26)
LX_+1VALW: length 2.7
  BOTTOM w0.102: PR307.1 v1(146.31,48.91)
  BOTTOM w0.254: PU300.6 152.51,43.55 v2(152.82,43.86)
  vias: v2(148.61,44.09)
M2_SLOT2_PEDET: length 115.5
  TOP w0.102: v2(191.06,15.49) 190.66,15.49 190.35,15.18 JSSD1.18 ; v2(124.8,1.54) 126.77,3.51 126.77,6.39 125.61,7.55 125.61,14.26 120.35,19.51 v2(118.75,19.51)
  IN1 w0.127: v2(191.06,15.49) 190.81,15.25 186.38,15.25 185.6,16.03 173.56,16.03 170.29,12.76 167.07,12.76 164.23,9.92 163.04,9.92 154.45,1.33 125.01,1.33 v2(124.8,1.54)
  IN2 w0.127: v2(118.75,19.51) 118.79,19.55 118.79,24.41 119.22,24.83 119.22,29.07 120.71,30.56 120.71,33.13 v2(120.48,33.36)
  BOTTOM w0.076: UC1.G4 119.62,35.14 119.62,34.78 119.71,34.7 119.71,34.69 119.86,34.54 120.02,34.54 120.35,34.2 120.35,33.48 v2(120.48,33.36)
MCT:
  vias: v1(20.58,110.38) v2(19.92,118.24) v2(20.56,118.24)
MCT0: length 1
  TOP w0.102: v2(17.93,108.13) v1(17.93,107.16)
  vias: v2(17.93,108.84)
MCT1: length 0.9
  TOP w0.102: v1(17.61,113.04) 17.97,112.68 v2(17.97,112.3)
  vias: v2(17.94,111.69)
MDO0+: length 16.8
  IN2 w0.178: JLAN1.1 12.87,113.29 18.19,113.29 18.73,112.76 18.73,111.07 16.89,109.22 v2(16.89,105.59)
  BOTTOM w0.267: v2(16.89,105.59) 16.89,105.82 17.07,106 18,106 18.26,105.75 TL1.7
MDO0-: length 16.8
  IN2 w0.178: JLAN1.2 13.95,112.81 14.13,112.98 18.07,112.98 18.42,112.63 18.42,111.19 16.58,109.35 16.58,105.91 16.3,105.63 v2(16.3,105.59)
  BOTTOM w0.267: v2(16.3,105.59) 16.4,105.69 16.4,105.87 16.91,106.38 17.67,106.38 18.31,107.02 TL1.8
MDO1+: length 11.3
  IN2 w0.178: v2(16.78,111.12) 16.52,111.38 16.52,111.66 16.21,111.97 15.7,111.97 15.26,111.52 15.26,110.88 15.05,110.67 14.91,110.67 14.35,111.23 JLAN1.3
  BOTTOM w0.267: TL1.11 18.47,113.37 17.77,114.06 17.05,114.06 16.59,113.61 16.59,111.3 v2(16.78,111.12)
MDO1-: length 11.3
  IN2 w0.178: v2(16.15,111.08) 16.21,111.14 16.21,111.54 16.09,111.66 15.83,111.66 15.56,111.4 15.56,110.75 15.01,110.19 15.01,110.04 13.95,108.99 JLAN1.6
  BOTTOM w0.267: v2(16.15,111.08) 16.21,111.14 16.21,113.76 16.89,114.45 18.24,114.45 18.44,114.64 TL1.12
ME_FWP_EC: length 103.8
  TOP w0.102: v2(154.64,25.31) 154.12,24.78 152.82,24.78 RE19.1 ; v2(78.82,17.69) 78.13,18.38 v1(78.13,19.7) 78.13,21.54 78.74,22.16 RC126.1
  IN1 w0.127: v2(154.64,25.31) 154.64,26.82 153.81,27.65 153.81,29.81 154.49,30.49 154.49,31.67 154.2,31.96 152.6,31.96 152.02,32.54 150.43,32.54 150.21,32.31 144.28,32.31 144.1,32.49 141.7,32.49 139.47,30.27 138,30.27 136.19,28.45 135.07,28.45 130.35,23.73 130.35,21.4 126.7,17.75 117.92,17.75 117.11,18.56 110.6,18.56 108.21,20.95 105.15,20.95 104.99,20.78 104.67,20.78 101.18,17.29 92.67,17.29 91.85,18.1 81.49,18.1 81.08,17.69 v2(78.82,17.69)
  BOTTOM w0.102: v2(154.64,25.31) 154.77,25.18 UE1.80
ME_SUS_PWR_ACK: length 88.2
  TOP w0.089: 101.85,39.01 103.05,39.01 103.08,39.03 104.53,39.03 104.73,39.24 104.73,40.47 104.97,40.71 v2(104.97,41.16)
  TOP w0.102: 101.85,39.01 98.57,39.01 96.17,36.6 96.17,29.93 v1(95.43,29.2) 94.12,27.88 93.35,27.88 92.92,28.31 v2(92.22,28.31) 91.88,28.31 91.64,28.07 RC84.2
  IN1 w0.127: v2(92.22,28.31) 92.64,28.72 95.03,28.72 95.52,28.23 100.92,28.23 100.96,28.28 101.07,28.28 102.02,29.23 111.23,29.23 111.72,29.72 114.29,29.72 115.07,28.93 117.88,28.93 120.04,26.78 127.06,26.78 129.3,29.02 129.59,29.02 131.13,30.57 131.6,30.57 132.52,31.48 132.52,32.17 133.83,33.48 136.81,33.48 139.12,35.8 144.73,35.8 145.04,35.48 v2(145.98,35.48)
  BOTTOM w0.089: v2(104.97,41.16) 104.97,41.06 UC1.AR13
  BOTTOM w0.102: UE1.42 145.56,33.58 146.2,34.22 146.2,35.27 v2(145.98,35.48)
MEC_XTAL1: length 3.2
  BOTTOM w0.102: YE1.1 143.36,13.21 CE3.1 144.27,14.95 RE47.2
MEC_XTAL1_R: length 2.4
  BOTTOM w0.102: RE47.1 143.39,15.69 143.96,16.26 UE1.123
MEC_XTAL2: length 5.3
  BOTTOM w0.102: YE1.2 142.49,13.38 CE4.1 142.49,14.91 RE45.1 142.53,15.42 143.16,16.05 UE1.125
MIC_CAP: length 2.6
  TOP w0.203: UA1.19 23.77,19.76 23.71,19.7 23.07,19.7 v1(23.03,19.66) 22.35,19.66 22.12,19.89 CA26.1
MODEL_ID: length 5.8
  TOP w0.102: v1(149.55,22.47) 149.55,21.99 RE3.2 RE4.2 CE1.1 150.06,19.1 150.16,19 v2(150.16,18.97)
  BOTTOM w0.102: UE1.109 149.56,18.38 v2(150.16,18.97)
MPHYP_PWR_EN: length 1.3
  TOP w0.089: v2(106.83,38.44) 106.83,38.55 TP13.1
  BOTTOM w0.076: v2(106.83,38.44) 106.83,38.55 UC1.AM10
NCT7718_DXN: length 68.7
  BOTTOM w0.254: U2.3 111.46,108.76 111.4,108.69 110.17,108.69 C23.2 109.79,108.74 107.3,108.74 106.75,108.19 106.75,105.18 108.07,103.86 108.07,97.16 106.57,95.66 98.67,95.66 97.28,97.05 v1(75.98,97.05) 66.72,97.05 66.46,97.3 66.46,97.56 66.82,97.92 C22.2 66.05,99.17 65.06,99.17 63.39,97.5 Q14.3
NCT7718_DXP: length 68.4
  BOTTOM w0.254: Q14.2 61.82,95.57 Q14.1 63.15,96.54 65,98.39 C22.1 65.43,97.92 65.95,97.39 65.95,97.09 66.51,96.54 v1(71.05,96.54) 97.07,96.54 98.46,95.15 106.78,95.15 108.58,96.95 108.58,104.07 107.26,105.39 107.26,107.98 107.51,108.23 109.71,108.23 C23.1 110.14,108.18 111.35,108.18 111.43,108.11 U2.2
NRB_BIT: length 11.4
  BOTTOM w0.076: 100.57,36.2 100.69,36.32 101.23,36.32 101.32,36.41 102.17,36.41 102.22,36.46 102.67,36.46 102.71,36.43 103.55,36.43 103.72,36.59 104.38,36.59 104.55,36.76 104.67,36.76 105.02,37.11 UC1.AR7
  BOTTOM w0.102: 100.57,36.2 99.35,34.97 99.35,34.65 98.67,33.97 98.67,33.24 98.06,32.64 98.06,32.45 97.68,32.07 97.68,32.07 RC44.2
NTC_IA: length 2.5
  TOP w0.203: PR635.2 164.22,63.38 163.84,63 163.84,62.52 163.79,62.48 PU602.15
ONE_DIMM#: length 7.8
  BOTTOM w0.102: RC182.1 RC181.2 120.54,30.39 120.54,31.77 v1(120.23,32.09) 119.7,32.61 119.7,34.01 119.51,34.2 119.19,34.2 118.89,34.5 118.38,34.5 118.06,34.19 UC1.M2
PANEL_BKEN_EC: length 109.4
  TOP w0.102: v1(221.19,44.34) 221.51,44.66 v2(221.91,44.66) 222.04,44.53 222.04,44.13 222.27,43.9 RP2.8
  IN1 w0.127: v2(145.86,19.09) 147.64,20.88 152.54,20.88 153.23,21.58 153.23,21.92 153.82,22.5 154.76,22.5 159.39,27.13 161.44,27.13 163.34,25.23 163.34,21.84 166.3,18.88 167.66,18.88 167.79,19 167.79,20.13 169.25,21.59 177.51,21.59 179.19,23.27 179.19,26.92 179.32,27.04 181.02,27.04 182.77,25.29 185.69,25.29 186.33,25.93 191.33,25.93 194.77,29.37 194.77,30.09 197.47,32.78 197.47,33.55 196.49,34.53 196.49,37.25 199.13,39.9 209.15,39.9 211.88,42.63 215.41,42.63 216.75,43.96 219.03,43.96 219.58,44.51 219.58,44.98 219.91,45.31 221.27,45.31 v2(221.91,44.66)
  BOTTOM w0.102: UE1.117 146.36,18.21 146.31,18.26 146.31,18.64 v2(145.86,19.09)
PBAT_CHG_SMBCLK: length 111.5
  TOP w0.254: v2(189.2,35.78) 189.4,35.57 189.4,35.06 189.09,34.75 189.04,34.75 187.83,33.54 187.83,27.89 189.38,26.33 v1(189.38,25.35) 189.15,25.13 189.15,21.9 190.69,20.36 v2(190.69,19.52) 191.36,20.18 191.36,20.67 191.84,21.15 193.52,21.15 195.37,19.3 195.37,17.88 195.83,17.42 204.31,17.42 209.32,12.41 213.29,12.41 214.52,13.64 PD2.3 214.52,15.09 PR18.2
  IN2 w0.127: v2(190.69,19.52) 190.69,16.87 190.7,16.87 190.7,16.52 190.69,16.51 190.69,16.5 189.77,15.58 186.39,15.58 185.93,16.04 180.12,16.04 179.87,16.28 175.28,16.28 172.79,13.79 164.17,13.79 163.31,14.64 162.5,14.64 160.14,17.01 158.39,17.01 157.49,17.91 156.63,17.91 156.05,18.49 154.15,18.49 153.44,19.2 151.52,19.2 151.01,19.7 149.83,19.7 148.76,20.77 145.3,20.77 144.1,21.97 143.3,22.77 142.62,22.77 v2(142.33,22.48)
  BOTTOM w0.102: v2(142.33,22.48) 142.02,22.17 141.29,22.17 141.1,21.98 UE1.9 138.83,21.98 138.46,21.61 RE9.1
  BOTTOM w0.254: v2(189.2,35.78) 189.56,35.78 189.57,35.77 PR770.1
PBAT_CHG_SMBDAT: length 113.4
  TOP w0.254: PR20.2 215.52,15.08 PD2.2 215.52,13.42 215.33,13.23 214.85,13.23 213.66,12.03 209.16,12.03 204.16,17.04 195.47,17.04 194.99,17.52 194.99,19.14 193.46,20.67 191.99,20.67 191.74,20.41 191.74,19.94 191.51,19.71 191.51,19.41 v2(191.13,19.03) 190.49,19.03 190.14,19.39 190.14,20.37 188.77,21.74 188.77,26.4 187.38,27.79 v1(187.38,29.16) 187.38,33.63 188.92,35.17 v2(188.92,35.26)
  IN2 w0.127: v2(191.13,19.03) 191.13,16.58 189.88,15.32 186.28,15.32 185.84,15.77 175.13,15.77 172.89,13.53 164.07,13.53 163.21,14.39 162.4,14.39 160.03,16.75 158.29,16.75 157.39,17.66 156.53,17.66 155.95,18.24 154.04,18.24 153.33,18.94 151.42,18.94 150.91,19.45 149.72,19.45 148.66,20.51 145.2,20.51 143.36,22.35 v2(142.93,22.35)
  BOTTOM w0.102: RE8.1 138.33,20.75 139.16,21.58 UE1.8 140.42,21.67 141.24,21.67 141.47,21.9 142.48,21.9 v2(142.93,22.35)
  BOTTOM w0.254: PR769.1 189.29,34.89 v2(188.92,35.26)
PBAT_PRES#: length 134
  TOP w0.254: v2(218.36,14.6) 218.36,14.31 218.1,14.06 PD3.2 217.68,15.05 PR16.1 217.64,15.09 PR15.2 ; v2(194.27,43.13) 194.14,43.26 190.07,43.26 189.62,43.71 187.15,43.71 185.57,42.12 185.57,30.16 v1(184.79,29.39) 183.67,28.26 182.59,28.26 181.68,27.35 180.79,27.35 180.07,26.62 v2(179.73,26.62) 179.58,26.77 PC14.1
  IN1 w0.127: v2(154.78,15.89) 154.78,18.27 154,19.06 154,21.09 154.33,21.42 155.15,21.42 155.72,21.99 155.72,23.1 159.5,26.88 161.33,26.88 163.09,25.12 163.09,21.73 166.2,18.62 167.79,18.62 168.04,18.88 168.04,20.02 169.36,21.34 177.62,21.34 180.23,23.95 180.23,26.12 v2(179.73,26.62)
  IN2 w0.254: v2(194.27,43.13) 197.54,43.13 200.85,39.83 207.98,39.83 209.13,38.68 216.4,38.68 218.54,36.54 218.54,32.76 219.22,32.09 219.22,21.29 218.69,20.76 218.69,17.79 217.68,16.78 217.68,15.27 v2(218.36,14.6)
  BOTTOM w0.102: CE16.1 154.78,15.48 v2(154.78,15.89) 154.36,16.32 UE1.97
  BOTTOM w0.254: PR764.1 193.5,41.92 PC753.2 PR756.1 193.83,43.13 v2(194.27,43.13)
PCH_BATLOW#: length 16.1
  TOP w0.102: v2(103.65,41.25) 103.65,41.03 102.33,39.71 97.12,39.71 v1(95.62,38.21) 95.05,37.64 91.49,37.64 90.51,36.67 RC89.1
  BOTTOM w0.076: UC1.AU13 103.96,40.94 v2(103.65,41.25)
PCH_DPWROK: length 4.1
  BOTTOM w0.076: RC87.1 97.19,43.53 97.76,44.1 RC97.2 v1(99.46,44.1) 99.47,44.1 99.88,44.5 UC1.BB20
PCH_HDMI_CLK: length 168.7
  TOP w0.102: QI2.1 v2(29.62,71.82)
  IN2 w0.076: 109.29,34.48 109.46,34.65 109.46,35.2 110.7,36.45 110.7,38.01 112.52,39.83 113.16,39.83 114.24,40.91 114.57,40.91 114.76,41.1 114.76,41.48 114.94,41.66 116.16,41.66 116.39,41.43 116.39,41 v2(117.04,40.35) 117.5,39.89 117.5,39.24 117.81,38.93 119.65,38.93
  IN2 w0.127: 109.29,34.48 108.47,33.66 106.95,33.66 106.11,32.83 105.83,32.83 105.19,33.47 103.66,33.47 102.48,32.29 102.48,31.68 100.36,29.56 100.36,28.05 96.03,23.72 96.03,18.14 93.68,15.79 82.39,15.79 81.09,14.5 77.09,14.5 76.31,13.72 52.22,13.72 48.6,17.34 47.5,17.34 44.29,20.55 44.29,36.17 40.36,40.1 40.36,60.62 29.62,71.36 v2(29.62,71.82) ; 119.65,38.93 121.17,38.93 124.61,35.49 124.61,33.93 v2(124.54,33.86)
  BOTTOM w0.076: RC1.1 128.07,33.04 v1(126.39,33.04) 126.32,33.04 125.75,33.61 124.8,33.61 v2(124.54,33.86) ; UC1.L13 v2(117.04,40.35)
PCH_HDMI_DATA: length 170.9
  TOP w0.102: QI2.4 v2(29.1,73.12)
  IN2 w0.076: 119.4,38.14 117.83,38.14 117.04,38.94 v2(117.04,39.69) 116.67,40.06 116.67,40.49 116.25,40.91 115.6,40.91 115.35,40.66 114.27,40.66 113.24,39.63 112.61,39.63 110.89,37.91 110.89,36.35 109.66,35.12 109.66,34.53
  IN2 w0.127: v2(123.92,33.87) 124.35,34.31 124.35,35.39 121.49,38.25 119.5,38.25 119.4,38.14 ; v2(29.1,73.12) 28.98,73 28.98,71.65 40.1,60.53 40.1,39.99 44.04,36.05 44.04,20.45 47.4,17.09 48.49,17.09 52.12,13.46 80.42,13.46 82.49,15.54 93.78,15.54 96.29,18.04 96.29,23.62 100.61,27.94 100.61,29.46 102.73,31.58 102.73,32.18 103.76,33.21 105.09,33.21 105.72,32.58 106.22,32.58 107.05,33.41 108.57,33.41 109.66,34.49 109.66,34.53
  BOTTOM w0.076: v2(117.04,39.69) 117.5,40.15 UC1.L12 ; RC2.1 127.54,32.07 126.89,32.72 126.19,32.72 125.62,33.29 124.49,33.29 v2(123.92,33.87)
PCH_JTAG_TCK1: length 8.8
  BOTTOM w0.076: TPC3.1 129.69,64.86 RC147.1 ; 125.31,65.99 124.84,65.53 123.81,65.53 123.63,65.71 123.37,65.71 123.25,65.65 123.03,65.65 UC1.B56
  BOTTOM w0.102: 125.31,65.99 125.71,65.99 126.17,65.54 127.99,65.54 128.05,65.48 129.38,65.48 TPC3.1
PCH_PCIE_WAKE#: length 9.5
  TOP w0.102: v2(94.25,40.02) 94.16,40.11 93.45,40.11 92.79,39.45 RC99.2
  BOTTOM w0.076: UC1.BB15 100.8,42.13 99.66,42.13 98.55,41.01 95.25,41.01 v2(94.25,40.02)
PCH_PLTRST#: length 37.9
  TOP w0.102: v2(105.7,38.51) 105.45,38.51 105.04,38.1 103.31,38.1 102.89,38.52 98.74,38.52 98.1,37.89 98.1,36.82 98.99,35.93 98.99,33.32 101.7,30.61 101.7,27.87 104.88,24.69 104.88,24.12 105.36,23.64 106.07,23.64 106.5,23.22 106.5,20.35 v1(106.18,20.03) v2(105.25,19.1)
  BOTTOM w0.076: v2(105.7,38.51) 105.72,38.48 106.11,38.48 UC1.AN10
  BOTTOM w0.102: 107.66,18.76 107.75,18.66 108.13,18.66 108.31,18.84 UC4.1 ; 107.66,18.76 UC4.2 ; 107.66,18.76 107.59,18.69 107.21,18.69 106.83,18.31 106.19,18.31 105.95,18.55 RC108.1 v2(105.25,19.1)
PCH_PLTRST#_EC: length 341.2
  TOP w0.102: v2(184.77,27.7) 186.72,27.7 188.41,26.01 188.41,22.44 188.46,22.38 188.46,21.29 187.39,20.21 184.08,20.21 182.93,19.06 182.93,18.53 184.44,17.02 185.96,17.02 187.85,15.13 JSSD1.23 ; v2(151.17,34.04) 151.48,33.73 CE27.1 ; v2(107.78,21.93) 107.78,21.93 107.78,21.06 108.12,20.72 v1(109.94,20.72) 111.84,20.72 112.25,21.13 116.81,21.13 117.1,20.83 117.1,20.44 114.55,17.89 114.55,11.83 116.03,10.34 116.03,6.01 v2(116.75,5.29) 116.92,5.46 116.92,7.39 117.3,7.77 117.8,7.77 117.88,7.7 117.88,6.88 118.08,6.67 118.8,6.67 119.74,7.61 JDB1.3 ; RW4.2 54.89,108.72 RL12.1 54.88,106.77 v2(55.01,106.64)
  IN1 w0.127: v2(107.78,21.93) 107.78,21.93 107.84,21.86 109.26,21.86 111.55,19.58 117.54,19.58 118.3,18.81 126.32,18.81 128.71,21.2 128.71,25.77 130.06,27.12 132.3,27.12 134.26,29.08 134.26,29.78 135.54,31.06 137.12,31.06 137.35,31.29 138.19,31.29 139.3,32.4 140.16,32.4 141.28,33.51 144.52,33.51 144.7,33.33 149.78,33.33 150.01,33.56 150.69,33.56 v2(151.17,34.04) 151.96,34.04 153.03,32.98 153.99,32.98 161.63,32.98 161.88,33.23 161.88,36.02 162.77,36.91 172.3,36.91 172.8,36.4 175.59,36.4 177.63,34.37 177.63,30.82 178.98,29.47 180.97,29.47 181.38,29.88 183.56,29.88 184.77,28.67 v2(184.77,27.7)
  IN2 w0.127: v2(116.75,5.29) 115.74,4.27 111.55,4.27 110.39,3.11 96.25,3.11 95.66,3.7 91.82,3.7 v2(91.75,3.64)
  BOTTOM w0.102: v2(107.78,21.93) 107.78,21.93 107.59,22.12 106.64,22.12 106.51,21.99 106.51,21.43 RC109.1 RC108.2 106.5,20.01 107.01,20.52 UC4.4 ; UE1.56 151.16,34.02 v2(151.17,34.04) ; v2(55.01,106.64) 54.3,106.64 53.05,105.39 48.38,105.39 46.61,103.61 46.61,98.47 51.83,93.24 67.72,93.24 68.19,93.71 77.04,93.71 81.13,89.62 81.13,78.33 79.75,76.96 79.75,28.53 80.51,27.78 80.51,26.9 80.21,26.61 80.21,23.2 80.92,22.5 80.92,18.62 89.97,9.57 89.97,3.28 90.35,2.9 91.36,2.9 91.75,3.3 v2(91.75,3.64)
PCH_POPIRCOMP: length 12.9
  TOP w0.305: RC120.1 92.68,42.04 95.46,42.04 96.42,41.09 v1(98.19,41.09) 101.19,41.09 102.2,42.1 102.21,42.1 103.03,42.92 103.55,42.92 v2(103.63,43.01)
  BOTTOM w0.254: v2(103.63,43.01) 103.63,42.92 103.96,42.6 UC1.AU16
PCH_RSMRST#: length 106.2
  TOP w0.102: v2(83.68,20.04) 83.68,20.04 83.51,20.22 UC5.1 ; v2(151.53,22.12) 151.24,22.41 v1(151.24,22.75)
  IN1 w0.127: v2(151.53,22.12) 151.53,22.12 152.68,23.26 154.44,23.26 155.35,24.17 155.35,26.48 154.07,27.76 154.07,29.71 154.74,30.39 154.74,31.78 154.31,32.21 152.71,32.21 152.13,32.8 150.33,32.8 150.1,32.57 144.38,32.57 144.2,32.75 141.59,32.75 139.37,30.52 137.84,30.52 136.02,28.71 134.97,28.71 131.13,24.87 130.3,24.87 129.47,24.04 129.47,20.88 126.59,18 118.03,18 117.22,18.81 110.7,18.81 108.32,21.2 104.73,21.2 101.07,17.54 92.77,17.54 91.96,18.36 85.13,18.36 83.68,19.81 v2(83.68,20.04)
  BOTTOM w0.102: RE20.1 157.5,22.56 156.92,21.98 UE1.88 155.17,21.98 154.72,21.53 153.52,21.53 152.5,22.55 151.97,22.55 151.53,22.12 v2(151.53,22.12)
PCH_RSMRST#_Q: length 37.3
  TOP w0.102: v1(85.94,23.89) 85.75,23.7 v2(85.3,23.7) 85.24,23.77 85.05,23.77 84.81,23.53 UC5.4 ; v2(83.56,31.87) 82.61,30.92 RC94.2 RC148.1
  BOTTOM w0.076: 90.05,38.94 94.06,42.94 95.97,42.94 96.22,42.69 97.18,42.69 97.67,43.19 RC97.1 98.93,43.19 99.28,43.54 101.89,43.54 UC1.AY17
  BOTTOM w0.102: 90.05,38.94 83.48,32.37 83.48,31.95 v2(83.56,31.87) 84.45,30.98 84.45,24.62 85.3,23.77 v2(85.3,23.7)
PCH_RTCRST#: length 36.2
  TOP w0.102: RC78.1 CC5.1 89.86,27.63 90.44,28.21 v2(90.44,28.3) ; RC78.1 89.86,24.67 TPS7.1 ; RC78.1 89.54,25.6 88.41,24.47 QC2.1 88.1,23.54 v2(87.59,24.05)
  IN2 w0.127: v2(90.44,28.3) 90.53,28.3 91.35,29.12 93.12,29.12 93.64,29.64 93.64,31.19 94.18,31.73 95.93,31.73 97.43,33.23 98.25,33.23 99.02,33.99 99.02,34.03 99.23,34.24 99.23,35.36 100.02,36.15 100.6,36.15 101.95,37.49 101.95,40.35 103.24,41.65 105.31,41.65 105.34,41.67 106.34,41.67 v2(106.83,42.17)
  BOTTOM w0.102: JCMOS1.1 88.83,25.09 88.15,24.4 87.94,24.4 v2(87.59,24.05) ; UC1.AM16 107.14,42.59 v2(106.83,42.17)
PCH_RTCX1: length 25.9
  TOP w0.102: YC2.1 91.38,31.62 CC8.1 91.41,32.33 RC82.2 92.63,33.22 v2(92.98,33.57) 92.98,33.17 v1(93.24,32.91)
  IN2 w0.076: v2(107.48,43.92) 107,43.44 106.64,43.44 106.59,43.38 103.06,43.38 101,41.32 101,38.97 100.58,38.55
  IN2 w0.127: 100.58,38.55 100.58,38.03 99.27,36.72 99.2,36.72 99.17,36.7 98.1,36.7 96.98,35.57 96.98,35.39 95.15,33.57 v2(92.98,33.57)
  BOTTOM w0.102: v2(107.48,43.92) 107.21,43.65 UC1.AM18
PCH_RTCX2: length 24
  TOP w0.102: v2(106.83,43.93) 106.83,44.05 v1(106.51,44.38) ; RC83.2 RC82.1 91.38,33.5 v2(91.73,33.85)
  IN2 w0.076: v2(106.83,43.93) 106.49,43.59 103.51,43.59 103.48,43.62
  IN2 w0.127: v2(91.73,33.85) 91.84,33.74 92.48,33.74 92.48,33.78 92.77,34.08 94.72,34.08 95.34,34.7 95.57,34.7 96.73,35.86 96.96,35.86 98.01,36.91 99.08,36.91 99.97,37.8 99.97,38.68 100.38,39.09 100.38,41.07 102.93,43.62 103.48,43.62
  BOTTOM w0.102: v2(106.83,43.93) 107.21,44.31 UC1.AM20
PCH_RTCX2_R: length 3.2
  TOP w0.102: RC83.1 89.6,33.18 90.08,32.71 90.14,32.71 CC9.1 90.52,31.5 YC2.2
PCH_SMB_ALERT#: length 17.6
  IN2 w0.127: v2(115.21,25.99) 115.21,29.78 115.43,30.01 115.43,32.68 115.77,33.02 115.77,37.35 114.93,38.19 v2(114.93,39.17)
  BOTTOM w0.102: UC1.R10 115.19,39.17 v2(114.93,39.17) ; RC37.1 113.62,25.8 114.23,25.19 114.66,25.19 115.21,25.74 v2(115.21,25.99)
PCH_SMBCLK: length 88.4
  TOP w0.102: QC1.1 115.72,29.48 116.03,29.16 RC28.2 116.09,29.05 116.48,28.66 117.09,28.66 117.33,28.43 v1(117.33,28.15) 117.33,27.98 116.86,27.51 v2(116.73,27.51)
  IN1 w0.127: v2(50.06,21.36) 49.93,21.23 49.93,20.85 50.7,20.08 57.87,20.08 59.52,21.74 63.24,21.74 63.51,21.46 63.51,21.32 v2(63.84,20.99) 63.55,20.71 63.55,20.53 64.06,20.02 67.33,20.02 67.74,19.61 70.12,19.61 70.53,20.02 75.88,20.02 76.99,21.13 76.99,22.22 78.28,23.51 78.73,23.51 78.74,23.51 80.31,23.51 81.93,25.14 83.37,25.14 84.6,26.37 88.26,26.37 88.9,27.01 89.6,27.01 90.39,27.79 91,27.79 91.49,27.31 91.55,27.38 96.57,27.38 96.66,27.47 103.59,27.47 103.87,27.2 104.69,27.2 105.96,28.47 108.71,28.47 109.28,27.89 111.84,27.89 112.91,28.96 113.97,28.96 114.78,28.15 116.22,28.15 116.73,27.64 v2(116.73,27.51)
  BOTTOM w0.102: v2(50.06,21.36) 50.06,21.87 50.25,22.06 51.26,22.06 51.83,22.63 JDIMM2.253 ; v2(63.84,20.99) 63.9,21.05 63.9,21.64 64.39,22.12 JDIMM1.253
PCH_SMBDATA: length 85.4
  TOP w0.102: v1(112.42,29.48) 112.9,28.99 v2(112.9,28.28) 112.67,28.04 RC27.2 113.42,27.34 QC1.4
  IN1 w0.127: v2(112.9,28.28) 112.73,28.28 112.1,27.64 109.18,27.64 108.61,28.21 106.07,28.21 104.8,26.94 103.76,26.94 103.49,27.22 96.77,27.22 96.68,27.12 91.66,27.12 91.49,26.95 90.9,27.54 90.49,27.54 89.7,26.75 89,26.75 88.37,26.12 84.71,26.12 83.48,24.88 82.04,24.88 80.41,23.26 78.84,23.26 78.83,23.25 78.38,23.25 77.25,22.11 77.25,21.03 75.98,19.77 70.64,19.77 70.23,19.36 67.64,19.36 67.22,19.77 63.96,19.77 63.3,20.42 63.3,20.74 63.14,20.91 63.14,20.93 v2(63.08,20.99) 63.26,21.17 63.26,21.35 63.13,21.48 59.63,21.48 57.97,19.83 50.59,19.83 49.68,20.74 49.68,21.1 v2(49.42,21.36)
  BOTTOM w0.102: v2(49.42,21.36) 49.42,21.99 49.04,22.38 JDIMM2.254 ; v2(63.08,20.99) 62.95,20.99 62.06,21.88 59.06,21.88 JDIMM1.254
PCH_SPI_CLK_0_R: length 3.9
  TOP w0.102: v2(109.43,18.12) v4(110.15,18.12)
  BOTTOM w0.102: UC3.6 109.63,17.53 109.43,17.73 v2(109.43,18.12) 109.43,18.6 109.26,18.77 109.01,18.77 108.81,18.57 RC178.1
PCH_SPI_CLK_R: length 70.2
  IN2 w0.127: v2(107.24,17.89) 106.38,17.04 v2(106.38,16.46) 104.94,15.02 v2(104.94,15)
  BOTTOM w0.102: v2(106.38,16.46) 105.86,15.94 105.41,15.94 105.31,16.05 105.31,16.75 105.21,16.85 105.01,16.85 104.9,16.75 104.9,16.05 104.8,15.94 104.58,15.94 104.48,16.05 104.48,16.55 103.93,17.09 103.93,19.3 104.79,20.15 104.79,24.24 101.98,27.05 100.25,27.05 98.25,29.04 RC24.2 ; RC21.2 107.06,17.72 v2(107.24,17.89) 107.51,18.17 RC178.2 ; RE33.1 136.86,30.51 136.86,30.28 135.78,29.2 135.07,29.2 134.18,28.31 134.18,26.76 133.34,25.92 133.34,23.92 131.84,22.41 130.91,22.41 126.18,17.68 121.13,17.68 121.03,17.78 121.03,17.89 120.93,17.99 120.72,17.99 120.62,17.89 120.62,17.78 120.52,17.68 120.17,17.68 120.04,17.54 120.04,17.2 119.81,16.97 118.53,16.97 118.46,17.04 116.61,17.04 116.16,16.59 114.78,16.59 113.65,17.72 112.82,17.72 112.14,17.04 112.14,16.13 111.49,15.49 106.93,15.49 106.85,15.41 105.35,15.41 v2(104.94,15)
PCH_SPI_CLK_R1: length 10.2
  BOTTOM w0.076: UC1.AV2 103.68,34.8 103.68,35.24 103.48,35.44 102.65,35.44 102.31,35.1 102.02,35.1 101.77,34.86 101.77,34.64 101.65,34.52 101.37,34.52 101.15,34.31 101.15,33.83 100.49,33.17
  BOTTOM w0.102: 100.49,33.17 99.75,32.43 99.75,31.74 99.52,31.51 98.51,31.51 98.06,31.07 98.06,30.38 RC24.1
PCH_SPI_CS#0_R1: length 67
  TOP w0.102: v4(111.91,15.89) 112.2,15.89 v2(112.77,16.46)
  IN2 w0.127: v2(112.36,24.22) 112.75,24.22 113.1,23.88 113.1,20.89 113.28,20.71 v2(113.28,20.47) 113.28,20.26 113.44,20.09 113.44,17.14 v2(112.77,16.46)
  BOTTOM w0.076: UC1.AU3 104.05,34.68 103.08,33.7 103.08,32.38 ; 105.93,29.02 105.52,29.42
  BOTTOM w0.102: UC3.1 114.33,20.07 113.94,20.47 v2(113.28,20.47) ; 103.08,32.38 102.94,32.24 102.94,31.93 103.16,31.7 104.16,31.7 105.05,30.82 RC18.2 105.52,29.72 105.52,29.42 ; v2(112.36,24.22) 112.22,24.08 110.75,24.08 110.5,23.83 109.58,23.83 108.69,24.72 107.91,24.72 107.87,24.76 107.87,24.76 107.63,25 107.63,25 107.42,25.2 107.26,25.2 106.46,26 106.46,26.34 107.24,27.12 107.24,27.71 105.93,29.02 ; RE38.2 135.36,28.51 134.87,28.02 134.87,24.79 134.87,24.79 134.87,23.36 133.23,21.72 131.19,21.72 126.47,17 122.15,17 120.59,15.44 117.33,15.44 117.02,15.12 115.22,15.12 114.61,15.74 113.49,15.74 v2(112.77,16.46)
PCH_SPI_D0_0_R: length 3.7
  TOP w0.102: v4(109.72,16.05) 109.49,16.27 v2(109.49,16.83)
  BOTTOM w0.102: RC179.1 109.08,17.55 109.22,17.55 109.49,17.28 v2(109.49,16.83) 109.49,16.43 109.66,16.26 UC3.5
PCH_SPI_D0_R: length 70
  IN2 w0.127: v2(105.56,14.94) 107.02,16.4 v2(107.02,16.85)
  BOTTOM w0.102: RE34.1 136.63,29.4 136.42,29.19 136.42,28.91 136.25,28.74 135.26,28.74 134.64,28.12 134.64,24.89 134.64,24.88 134.64,24.53 134.51,24.4 134.51,24.15 134.64,24.03 134.64,23.58 134.03,22.97 133.89,22.97 v1(133.74,23.12) 133.54,23.32 133.4,23.32 133.25,23.18 133.25,23.03 133.6,22.68 133.6,22.54 133.01,21.95 132.58,21.95 132.44,22.09 132.17,22.09 132.03,21.95 131.1,21.95 126.37,17.23 122.06,17.23 120.5,15.66 117.24,15.66 116.92,15.35 115.32,15.35 115.12,15.55 115.12,16.03 115.02,16.14 113.82,16.14 113.05,16.91 112.6,16.91 112.36,16.67 112.36,15.84 111.78,15.26 107.02,15.26 106.95,15.18 105.8,15.18 v2(105.56,14.94) ; RC179.2 107.89,16.38 107.73,16.22 107.12,16.22 107.02,16.32 v2(107.02,16.85) 107.02,17.04 106.89,17.16 106.16,17.16 105.98,16.98 105.98,16.44 105.87,16.34 105.67,16.34 105.57,16.44 105.57,16.98 105.47,17.08 104.26,17.08 104.16,17.18 104.16,19.2 105.02,20.05 105.02,20.87 105.19,21.04 105.26,21.04 105.37,21.14 105.37,21.35 105.26,21.45 105.12,21.45 105.02,21.55 105.02,21.75 105.12,21.85 105.26,21.85 105.37,21.96 105.37,22.16 105.02,22.51 105.02,24.33 102.02,27.32 100.87,27.32 100.77,27.42 100.77,27.73 100.87,27.83 101.33,27.83 101.43,27.93 101.43,28.4 101.11,28.72 101.11,29.02 RC23.2
PCH_SPI_D0_R1: length 13.3
  BOTTOM w0.076: 101.61,33.33 101.61,33.6 101.9,33.89 102.24,33.89 102.48,34.13 102.48,35.04 102.72,35.28 103.25,35.28 UC1.AV3
  BOTTOM w0.102: 101.61,33.33 101.61,31.95 101.49,31.83 100.97,31.83 100.75,32.05 100.75,32.37 101.03,32.65 101.03,32.79 100.78,33.04 100.64,33.04 99.94,32.35 99.94,32.13 100.05,32.03 100.31,32.03 100.41,31.93 100.41,31.67 100.31,31.57 99.85,31.57 99.74,31.46 99.74,31.2 99.84,31.09 100.25,31.09 100.35,30.99 100.35,30.7 100.45,30.6 101.26,30.6 101.37,30.5 RC23.1 RC40.2
PCH_SPI_D1_0_R: length 4.9
  BOTTOM w0.102: RC180.1 118.83,21.54 119.2,21.17 v4(119.2,20.85) 119.2,19.12 118.88,18.8 UC3.2
PCH_SPI_D1_R: length 71.9
  IN2 w0.127: v2(112.99,17.32) 112.71,17.59 v2(112.71,20.72) 112.71,23.11 110.66,25.16 110.66,25.34 111.78,26.46 111.78,26.69 110.7,27.77 110.52,27.77 109.55,26.81 109.37,26.81 109.19,26.99 109.19,27.17 110.16,28.13 110.16,28.31 109.84,28.63 109.84,28.72 109.14,29.41 108.53,29.41 107.42,28.3 106.32,28.3 106.2,28.17 106.2,27.83 106.07,27.7 105.82,27.7 105.69,27.83 105.69,28.17 105.56,28.3 105.31,28.3 105.18,28.17 105.18,28.09 105.05,27.96 104.8,27.96 104.67,28.09 104.67,28.17 104.55,28.3 v2(103.79,28.3)
  BOTTOM w0.102: RE35.1 137.19,30.29 135.87,28.97 135.17,28.97 134.41,28.21 134.41,25.81 134.25,25.65 133.67,25.65 133.57,25.55 133.57,25.34 133.67,25.24 134.25,25.24 134.41,25.08 134.41,24.91 134.41,24.66 134.13,24.38 134.13,24.21 134.41,23.93 134.41,23.67 134.14,23.4 134,23.4 133.65,23.75 133.51,23.75 132.82,23.07 132.82,22.93 133.17,22.58 133.17,22.43 132.93,22.19 132.72,22.19 132.41,22.51 132.26,22.51 131.93,22.18 131,22.18 126.28,17.45 121.66,17.45 121.5,17.29 121.5,16.98 121.39,16.88 121.15,16.88 121.04,16.98 121.04,17.35 120.94,17.45 120.74,17.45 120.64,17.35 120.64,16.98 120.54,16.88 120.04,16.88 119.91,16.74 119.36,16.74 119.26,16.64 119.26,15.99 119.16,15.89 118.96,15.89 118.85,15.99 118.85,16.64 118.75,16.74 118.43,16.74 118.37,16.81 116.7,16.81 116.26,16.36 116,16.36 115.9,16.26 115.9,15.68 115.79,15.58 115.59,15.58 115.49,15.68 115.49,16.26 115.39,16.36 114.63,16.36 114.27,16.72 114.13,16.72 113.92,16.51 113.77,16.51 113.63,16.65 113.63,16.8 113.84,17.01 113.84,17.15 113.5,17.49 113.17,17.49 v2(112.99,17.32) ; RC180.2 113.54,21.54 v2(112.71,20.72) ; v2(103.79,28.3) 104.16,28.67 RC22.2
PCH_SPI_D1_R1: length 5.7
  BOTTOM w0.076: 102.9,32.47 102.9,33.79 103.07,33.95 103.07,34.34 102.8,34.61 UC1.AW3
  BOTTOM w0.102: 102.9,32.47 102.75,32.32 102.75,31.85 103.09,31.51 103.49,31.51 v1(103.85,31.15) 104.16,30.84 RC22.1
PCH_SPI_D2_0_R: length 4.1
  BOTTOM w0.102: v1(120.48,18.31) 120.29,18.31 RC176.2 119.03,17.4 118.92,17.51 118.92,17.95 118.82,18.05 118.68,18.05 118.57,17.95 118.57,17.63 118.47,17.53 UC3.3
PCH_SPI_D2_R: length 29.5
  BOTTOM w0.102: RC26.2 102.24,29.26 101.84,28.86 101.84,27.83 104.56,25.11 104.66,25.11 104.73,25.04 v1(104.78,25.04) 105.16,24.66 105.68,24.66 106.13,24.21 106.87,24.21 107.06,24.4 108.68,24.4 109.48,23.6 110.59,23.6 110.85,23.86 111.95,23.86 112.66,23.14 113.82,23.14 113.94,23.03 113.94,22.46 113.51,22.03 113.05,22.03 112.3,21.28 112.3,19.5 114.98,16.82 116.03,16.82 116.67,17.46 116.67,17.74 117.24,18.31 119.38,18.31 RC176.1
PCH_SPI_D2_R1: length 18.9
  BOTTOM w0.076: 102.33,33.45 102.33,33.65 102.8,34.12 UC1.AW2
  BOTTOM w0.102: RC26.1 RC41.2 ; RC41.2 103.53,30.18 103.69,30.02 103.69,28.95 103.46,28.72 103.4,28.72 102.93,28.25 102.93,28.11 103.15,27.88 v1(104.34,27.88) 105.3,27.88 RC19.2 ; RC41.2 103.31,30.34 103.31,31.11 103.21,31.21 102.95,31.21 102.85,31.11 102.85,30.88 102.75,30.78 102.53,30.78 102.43,30.88 102.43,31.11 102.33,31.21 102.06,31.21 101.99,31.13 101.99,30.92 101.87,30.8 101.66,30.8 101.56,30.9 101.56,31.13 101.46,31.23 101.26,31.23 101.15,31.13 101.15,30.9 101.05,30.8 100.81,30.8 100.69,30.92 100.69,31.5 100.79,31.6 102.46,31.6 102.56,31.7 102.56,31.95 102.46,32.05 102.12,32.05 102.01,32.16 102.01,32.36 102.12,32.47 102.62,32.47 102.72,32.57 102.72,32.81 102.62,32.91 102.43,32.91 102.33,33.01 102.33,33.45
PCH_SPI_D3_0_R: length 5.4
  BOTTOM w0.102: UC3.7 110.45,18.81 111.59,18.81 111.84,19.07 v1(111.84,21.74) 111.84,22.04 112.47,22.66 RC177.2
PCH_SPI_D3_R: length 33.2
  BOTTOM w0.102: RC177.1 112.07,21.38 112.07,17.72 111.91,17.55 111.91,16.51 111.11,15.72 104.48,15.72 v1(103.98,16.22) 103.71,16.49 103.71,19.39 104.56,20.24 104.56,24.14 101.88,26.82 99.52,26.82 97.3,29.04 RC25.2
PCH_SPI_D3_R1: length 11.2
  BOTTOM w0.076: 99.56,33.14 100.72,34.3 100.91,34.3 101.17,34.56 101.17,34.93 101.34,35.09 101.78,35.09 101.95,35.27 102.24,35.27 102.58,35.61 103.55,35.61 103.67,35.49 UC1.AU4
  BOTTOM w0.102: 99.56,33.14 99.56,31.82 99.45,31.7 98.43,31.7 97.87,31.15 97.87,30.77 97.3,30.2 RC25.1 RC20.2
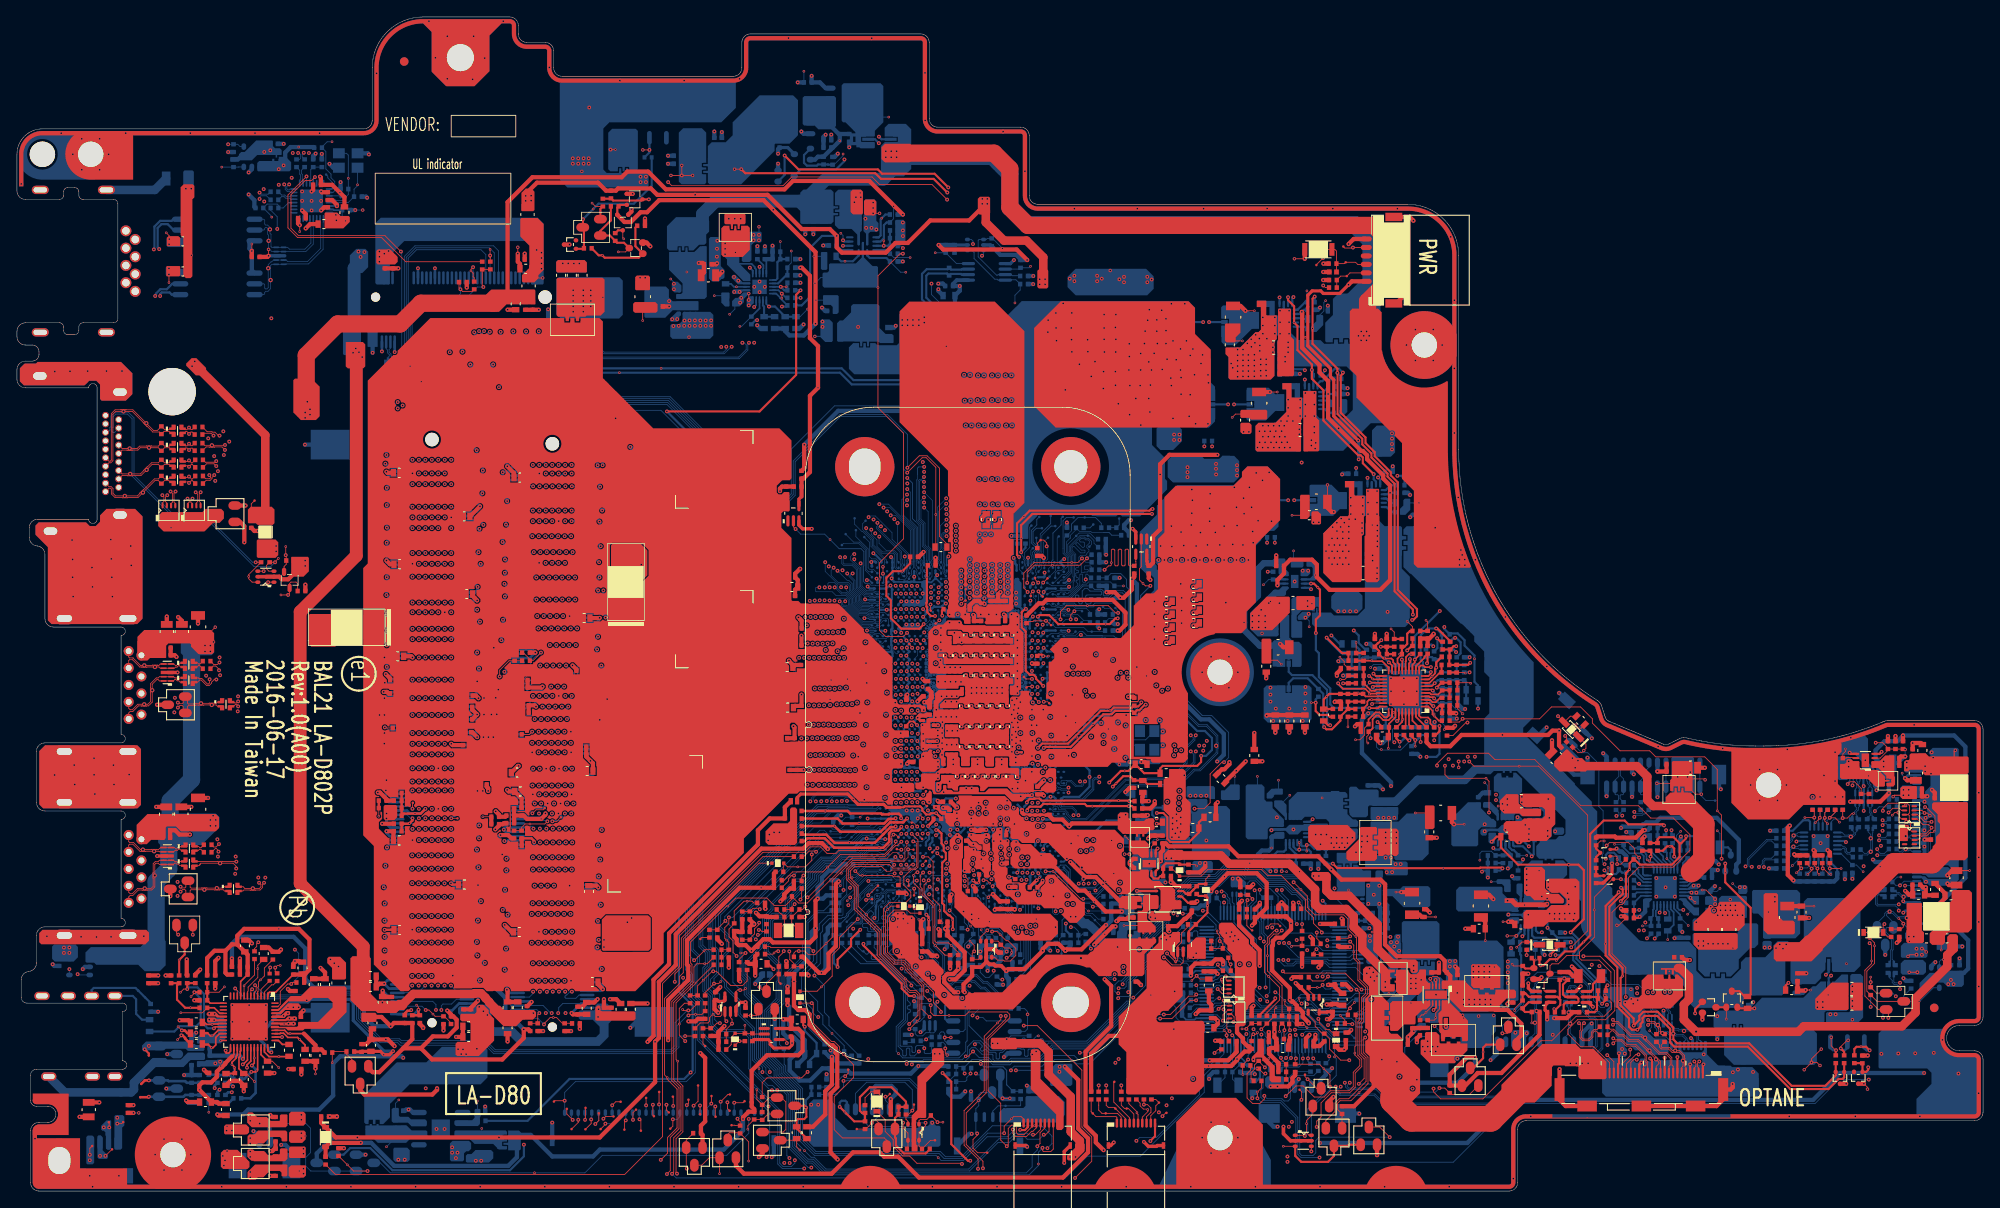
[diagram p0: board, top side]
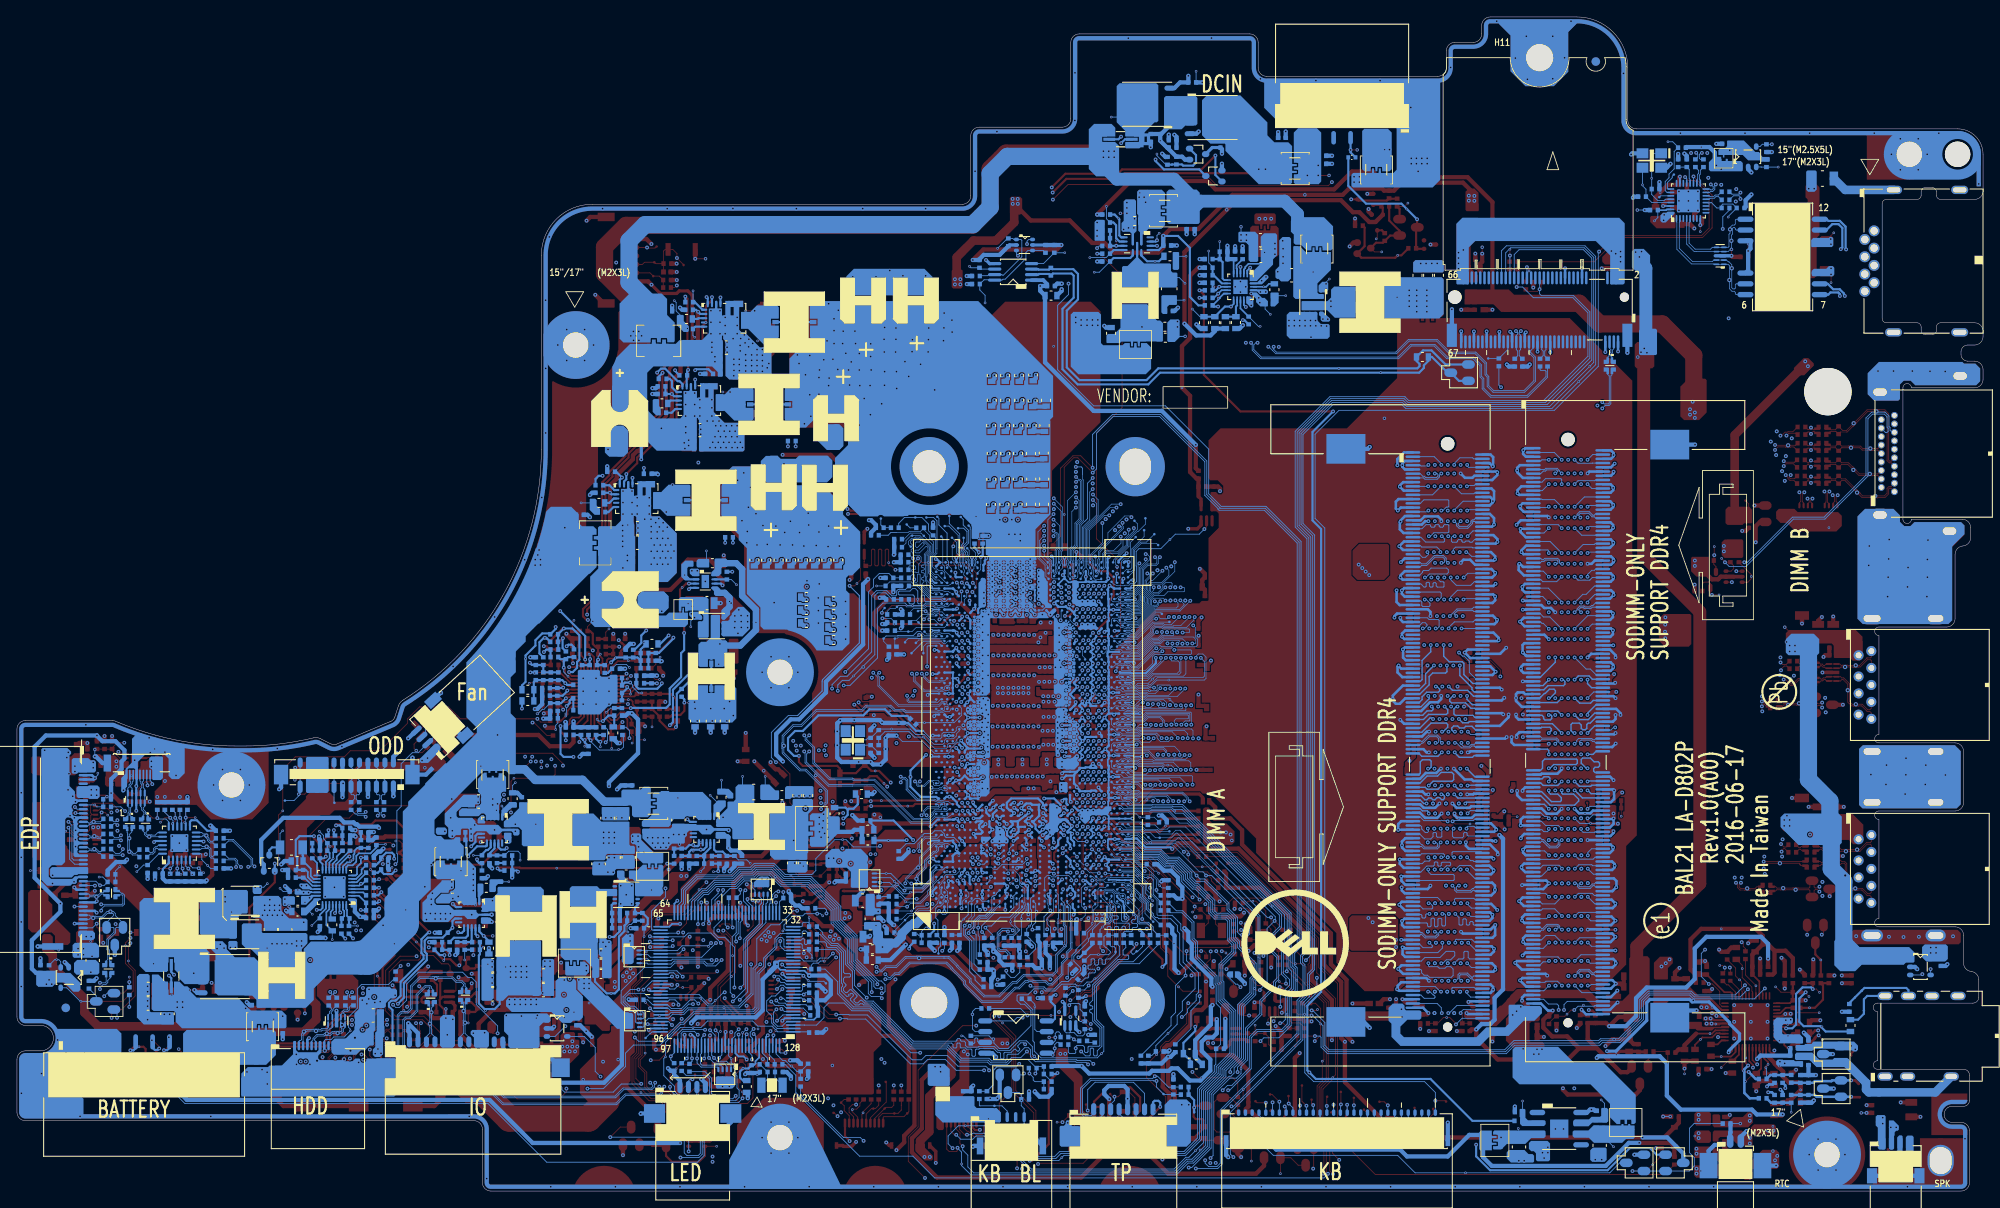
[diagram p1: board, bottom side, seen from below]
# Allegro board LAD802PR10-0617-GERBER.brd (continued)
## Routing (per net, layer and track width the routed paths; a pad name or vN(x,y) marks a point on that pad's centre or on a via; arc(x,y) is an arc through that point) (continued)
PCI_CLK_LPC1: length 9
  BOTTOM w0.076: 100.1,38.18 101.66,38.18 101.92,38.43 UC1.AY9
  BOTTOM w0.102: 100.1,38.18 98.89,36.98 v1(98.51,36.98) 98.13,36.98 97.87,36.72 97.87,34.99 97,34.12 RC16.1 RC15.1
PCIE_CRX_LANTX_N6: length 204.5
  IN1 w0.076: v2(119.78,43.87) 119.95,44.04 119.95,44.2 120.24,44.49 121.66,44.49 121.76,44.39 121.79,44.39 121.84,44.35 121.87,44.35 121.88,44.34
  IN1 w0.122: v2(140.03,52.54) 139.89,52.68 139.89,52.97 139.59,53.27 136.23,53.27 135.78,52.81 135.78,50.99 133.7,48.91 131.56,48.91 126.42,43.76 122.45,43.76 121.88,44.34
  IN2 w0.122: v2(140.03,52.54) 139.91,52.66 139.91,55.54 137.07,58.38 134.46,58.38 133.04,59.81 133.04,87.62 114.59,106.06 114.59,107.72 111.63,110.69 111.63,112.95 107.8,116.77 107.8,124.24 106.12,125.93 106.12,132.06 103.46,134.71 90.02,134.71 85.35,130.04 53.15,130.04 42.82,119.7 36.91,119.7 35.62,120.99 34.1,120.99 33.73,121.36 33.73,122.37 v2(33.83,122.48)
  BOTTOM w0.076: v2(119.78,43.87) 119.78,43.84 UC1.G18
  BOTTOM w0.097: v2(33.83,122.48) 33.65,122.29 33.65,121.98 CL2.1
PCIE_CRX_LANTX_P6: length 204.5
  IN1 w0.076: 121.7,44.16 121.58,44.29 120.32,44.29 120.15,44.11 120.15,44.01 120.29,43.87 v2(120.43,43.87)
  IN1 w0.122: v2(139.44,52.54) 139.48,52.54 139.64,52.7 139.64,52.87 139.49,53.02 136.33,53.02 136.02,52.71 136.02,50.88 133.8,48.66 131.67,48.66 126.52,43.52 122.35,43.52 121.7,44.16
  IN2 w0.122: v2(33.17,122.46) 33.48,122.14 33.48,121.26 33.99,120.74 35.52,120.74 36.81,119.45 42.92,119.45 53.26,129.79 85.45,129.79 90.12,134.46 103.36,134.46 105.87,131.95 105.87,125.82 107.56,124.13 107.56,116.67 111.38,112.84 111.38,110.58 114.35,107.62 114.35,105.96 132.79,87.52 132.79,59.7 134.36,58.13 136.97,58.13 139.66,55.44 139.66,52.76 v2(139.44,52.54)
  BOTTOM w0.076: v2(120.43,43.87) 120.28,43.87 120.1,43.69 UC1.F18
  BOTTOM w0.097: v2(33.17,122.46) 33.3,122.46 33.46,122.29 33.46,121.82 33.34,121.7 CL1.1
PCIE_CRX_SSDTX_N11: length 93.4
  TOP w0.097: v2(188.25,20.2) 188.45,20 188.85,20 190.38,18.46 191.66,18.46 v3(192.04,18.08) 193.77,16.35 194.59,16.35 195.19,15.74 195.19,14.88 195.35,14.72 JSSD1.8
  IN2 w0.122: v2(121.31,49.95) 122.07,49.19 122.53,49.19 123.29,48.43 124.44,48.43 125.7,47.18 126.13,47.18 130.08,43.22 131.99,43.22 132.95,42.26 133.77,42.26 135.43,40.6 136.71,40.6 137.76,39.55 137.76,37.96 140.45,35.27 140.45,35.17 141.56,34.05 141.56,33.2 144.74,30.02 144.74,29.23 146.73,27.24 147.27,27.24 147.89,26.62 150.77,26.62 151.42,25.97 154.92,25.97 156.22,24.67 156.22,24.28 157.49,23.02 158.76,23.02 160.86,20.92 169.23,20.92 169.91,20.24 175.76,20.24 175.98,20.02 179.99,20.02 180.2,19.81 182.11,19.81 182.62,19.3 183.88,19.3 183.93,19.35 186.89,19.35 187.64,20.1 188.14,20.1 v2(188.25,20.2)
  BOTTOM w0.076: v2(121.31,49.95) 121.26,49.91 UC1.E28
PCIE_CRX_SSDTX_N12: length 94.3
  TOP w0.097: v2(188.28,18.01) 188.39,17.9 189.28,17.9 189.89,17.28 190.96,17.28 192.22,16.02 192.22,15.37 192.35,15.25 JSSD1.14
  IN2 w0.122: v2(188.28,18.01) 188.25,17.97 184.41,17.97 184.39,17.95 182.11,17.95 182.09,17.97 180.88,17.97 180.67,18.19 175.02,18.19 174.32,18.89 170.05,18.89 169.27,18.11 167.92,18.11 166.46,19.57 160.3,19.57 158.77,21.09 157.11,21.09 154.98,23.22 151.44,23.22 149.94,24.72 148.97,24.72 148.48,25.21 146.12,25.21 144.89,26.44 144.89,27.03 143.86,28.06 142.66,28.06 139.45,31.28 139.45,33.07 137.22,35.3 135.59,35.3 134.51,36.38 134.51,37.68 134.29,37.9 134.29,38.82 131.49,41.62 131.29,41.62 131.29,41.62 129.71,41.62 125.59,45.74 124.04,45.74 122.17,47.6 121.27,47.6 120.56,48.31 120.56,49.58 120.84,49.87 120.84,50.77 v2(120.42,51.2)
  BOTTOM w0.076: v2(120.42,51.2) 120.75,50.86 UC1.E30
PCIE_CRX_SSDTX_P11: length 93.4
  TOP w0.097: JSSD1.9 194.85,14.72 195.01,14.88 195.01,15.66 194.51,16.16 193.7,16.16 192.14,17.72 192.08,17.72 191.66,18.14 191.66,18.18 191.57,18.27 190.31,18.27 188.77,19.81 188.44,19.81 v2(188.25,19.62)
  IN2 w0.122: v2(121,49.42) 121.12,49.54 121.37,49.54 121.96,48.94 122.42,48.94 122.5,48.87 122.5,48.87 123.18,48.18 124.34,48.18 125.6,46.93 126.02,46.93 129.98,42.97 131.89,42.97 132.85,42.01 133.67,42.01 135.33,40.35 136.61,40.35 137.51,39.45 137.51,37.85 140.2,35.17 140.2,35.07 141.31,33.95 141.31,33.09 144.49,29.92 144.49,29.13 146.62,26.99 147.17,26.99 147.79,26.37 150.67,26.37 151.32,25.72 154.82,25.72 155.98,24.56 155.98,24.18 157.38,22.77 158.65,22.77 160.75,20.67 169.13,20.67 169.81,19.99 175.66,19.99 175.88,19.77 179.89,19.77 180.1,19.56 182,19.56 182.51,19.05 183.99,19.05 184.04,19.1 187,19.1 187.74,19.85 188.02,19.85 v2(188.25,19.62)
  BOTTOM w0.076: v2(121,49.42) 120.75,49.17 UC1.E27
PCIE_CRX_SSDTX_P12: length 94.2
  TOP w0.097: JSSD1.15 191.85,14.67 191.96,14.78 192.07,14.78 192.16,14.87 192.16,15.17 192.04,15.29 192.04,15.94 190.88,17.1 189.82,17.1 189.2,17.71 188.57,17.71 v2(188.28,17.42)
  IN2 w0.122: v2(120.43,50.27) 120.58,50.12 120.58,49.95 120.31,49.69 120.31,48.2 121.16,47.35 122.07,47.35 123.93,45.49 125.49,45.49 129.61,41.37 131.39,41.37 134.04,38.72 134.04,37.79 134.26,37.58 134.26,36.28 135.49,35.05 137.12,35.05 139.2,32.97 139.2,31.18 142.56,27.82 143.75,27.82 144.65,26.92 144.65,26.33 146.02,24.96 148.38,24.96 148.87,24.47 149.84,24.47 151.34,22.97 154.87,22.97 157,20.85 158.67,20.85 160.19,19.32 166.36,19.32 167.82,17.86 169.37,17.86 170.16,18.64 174.21,18.64 174.92,17.94 180.56,17.94 180.78,17.72 181.98,17.72 182.01,17.7 184.39,17.7 184.41,17.72 187.98,17.72 188.28,17.42 v2(188.28,17.42)
  BOTTOM w0.076: v2(120.43,50.27) 120.61,50.45 120.61,50.58 120.36,50.83 UC1.F30
PCIE_CRX_WLANTX_N5: length 158.6
  IN1 w0.076: 122.74,42.36 122.61,42.36 122.61,42.36 120.66,42.36 120.48,42.54 120.48,42.98 v2(120.4,43.05)
  IN1 w0.122: v2(137.32,51.99) 137.29,51.96 137.29,51.79 137.29,51.78 137.29,51.2 134.08,47.99 132.6,47.99 127.37,42.76 124.87,42.76 124.46,42.36 122.74,42.36
  IN2 w0.122: v2(83.67,99.59) 83.72,99.65 83.72,99.68 83.78,99.74 83.78,100.1 84.05,100.36 84.79,100.36 85.06,100.1 85.06,99.4 85.68,98.78 117.99,98.78 129.26,87.51 129.26,78.97 127.87,77.58 127.87,70.8 127.1,70.04 127.1,64.64 128,63.74 128,59.59 130.4,57.19 130.77,57.19 131.72,56.24 135.94,56.24 137.32,54.86 v2(137.32,51.99)
  BOTTOM w0.097: v2(120.4,43.05) UC1.F16 ; v2(83.67,99.59) 83.67,99.29 83.34,98.96 69.26,98.96 67.75,100.46 64.39,100.46 62.89,98.96 59.83,98.96 58.55,97.69 58.55,96.35 58.3,96.1 58.3,95 57.72,94.42 54.16,94.42 52.98,95.6 52.98,98.29 53.55,98.86 JWLAN1.35
PCIE_CRX_WLANTX_P5: length 158.6
  IN1 w0.076: v2(121.01,43.05) 120.92,43.05 120.68,42.81 120.68,42.63 120.75,42.56 122.6,42.56 122.62,42.58 122.68,42.58 122.71,42.61 122.74,42.61
  IN1 w0.122: 122.74,42.61 124.36,42.61 124.76,43.01 127.27,43.01 132.5,48.23 133.98,48.23 137.05,51.3 137.05,51.68 136.73,51.99 v2(136.67,51.99)
  IN2 w0.122: v2(84.3,99.59) 84.26,99.59 84.03,99.82 84.03,99.99 84.15,100.11 84.69,100.11 84.81,99.99 84.81,99.3 85.57,98.53 117.88,98.53 129.01,87.4 129.01,79.08 127.62,77.68 127.62,70.91 126.85,70.14 126.85,64.53 127.75,63.64 127.75,59.49 130.3,56.94 130.66,56.94 131.62,55.99 135.83,55.99 137.07,54.75 137.07,52.39 v2(136.67,51.99)
  BOTTOM w0.097: JWLAN1.33 53.05,99.45 53.36,99.14 53.36,98.94 52.79,98.37 52.79,95.52 54.08,94.23 57.8,94.23 58.49,94.92 58.49,96.02 58.74,96.27 58.74,97.61 59.91,98.78 62.96,98.78 64.46,100.28 67.68,100.28 69.18,98.78 83.42,98.78 83.8,99.16 84.24,99.59 v2(84.3,99.59) ; v2(121.01,43.05) UC1.E16
PCIE_CTX_C_SSDRX_N11: length 6.1
  TOP w0.097: CS18.2 193.75,17.22 193.75,16.97 193.95,16.76 194.8,16.76 195.19,16.37 195.27,16.37 195.31,16.34 195.89,16.34 195.92,16.37 196.05,16.37 196.51,15.91 v3(196.51,15.37) 196.51,14.74 196.35,14.59 JSSD1.6
PCIE_CTX_C_SSDRX_N12: length 9.2
  TOP w0.097: JSSD1.12 193.35,14.72 193.66,15.03 193.66,15.2 v3(193.32,15.54) 192.66,16.2 192.61,16.2 192.2,16.61 192.2,16.66 191.18,17.68 190.06,17.68 189.44,18.3 188.86,18.3 188.26,18.91 188.08,18.91 CS16.2
PCIE_CTX_C_SSDRX_P11: length 6.1
  TOP w0.097: CS19.2 193.94,17.2 193.94,17.04 194.03,16.95 194.88,16.95 195.27,16.56 v3(195.6,16.56) 196.13,16.56 196.69,15.99 196.69,15.7 196.73,15.66 196.73,15.08 196.69,15.05 196.69,14.75 196.85,14.59 JSSD1.5
PCIE_CTX_C_SSDRX_P12: length 9.3
  TOP w0.097: CS17.2 187.9,19.09 188.33,19.09 188.94,18.49 189.52,18.49 190.14,17.87 191.25,17.87 v3(192.56,16.56) 193.22,15.9 193.27,15.9 193.85,15.32 JSSD1.11
PCIE_CTX_LANRX_N6: length 207.4
  IN2 w0.122: v2(139.04,53.76) 138.86,53.94 138.86,55.34 136.55,57.65 133.85,57.65 132.51,58.98 130.53,58.98 129.39,60.11 129.39,61.75 129.97,62.32 129.97,63.97 130.85,64.85 130.85,87.83 113.17,105.51 113.17,107.13 110.15,110.15 110.15,112.44 106.31,116.28 106.31,123.82 104.73,125.4 104.73,131.46 102.84,133.35 90.57,133.35 85.91,128.69 53.84,128.69 38.84,113.69 34.92,113.69 31.1,117.51 28.88,117.51 v2(28.61,117.78)
  BOTTOM w0.076: 133.37,48.52 133.26,48.42 130.79,48.42 126.17,43.79 124.4,43.79 123.81,44.38 123.81,44.56 123.56,44.81 122.82,44.81 122.77,44.76 122.32,44.76 122.28,44.81 122.21,44.81 121.96,45.06 UC1.D20
  BOTTOM w0.097: CL4.1 29.63,117.59 28.8,117.59 v2(28.61,117.78) ; v2(139.04,53.76) 138.93,53.66 138.93,53.19 138.02,52.28 138.02,50.46 136.08,48.52 133.37,48.52
PCIE_CTX_LANRX_P6: length 207.4
  IN2 w0.122: v2(138.45,53.76) 138.61,53.91 138.61,55.24 136.45,57.4 133.74,57.4 132.41,58.73 130.42,58.73 129.15,60.01 129.15,61.86 129.72,62.43 129.72,64.07 130.6,64.95 130.6,87.73 112.92,105.41 112.92,107.03 109.9,110.05 109.9,112.34 106.06,116.18 106.06,123.72 104.48,125.3 104.48,131.36 102.74,133.1 90.67,133.1 86.01,128.44 53.94,128.44 38.95,113.44 34.82,113.44 31,117.26 28.85,117.26 v2(28.61,117.03)
  BOTTOM w0.076: 133.37,48.71 133.36,48.71 133.35,48.7 133.3,48.7 133.19,48.6 133.18,48.6 133.16,48.58 130.72,48.58 126.1,43.96 124.47,43.96 123.97,44.45 123.97,44.63 123.63,44.98 122.92,44.98 122.85,45.05 122.85,45.2 122.7,45.35 122.29,45.35 122.2,45.26 122.2,45.05 122.28,44.97 122.42,44.97 UC1.C20
  BOTTOM w0.097: v2(138.45,53.76) 138.74,53.47 138.74,53.27 137.83,52.36 137.83,50.54 136,48.71 133.37,48.71 ; v2(28.61,117.03) 28.61,117.25 28.78,117.41 29.44,117.41 CL3.1
PCIE_CTX_SSDRX_N11: length 93.1
  TOP w0.097: CS18.1 193.66,18.79 193.66,19.17 193.16,19.66 193.16,19.7 193.07,19.8 192.59,19.8 v2(192.39,19.6)
  IN2 w0.122: v2(192.39,19.6) 192.53,19.75 192.88,19.75 193.19,20.05 193.19,20.66 192.7,21.14 189.96,21.14 188.95,20.12 188.95,19.1 188.52,18.67 184.21,18.67 184.16,18.62 182.34,18.62 181.85,19.11 179.83,19.11 179.59,19.34 175.7,19.34 175.48,19.57 169.63,19.57 168.95,20.24 160.58,20.24 158.48,22.34 156.81,22.34 155.26,23.9 152.48,23.9 150.64,25.74 150.01,25.74 149.69,25.42 149.23,25.42 148.76,25.88 146.4,25.88 146.13,26.16 146.13,26.88 144.23,28.78 142.9,28.78 142.53,29.15 142.53,29.77 142.14,30.16 141.88,30.16 140.55,31.49 140.55,34.08 139.77,34.85 139.77,34.99 137.09,37.68 137.09,39.27 136.43,39.93 134.26,39.93 131.7,42.49 129.85,42.49 125.85,46.5 125.42,46.5 124.49,47.43 124.2,47.43 v2(124.03,47.59)
  BOTTOM w0.076: v2(124.03,47.59) 123.89,47.45 123.21,47.45 123.08,47.58 122.85,47.58 122.62,47.81 122.3,47.81 122.02,47.53 UC1.D24
PCIE_CTX_SSDRX_N12: length 84.9
  TOP w0.097: v2(184.25,19.8) 184.44,19.61 184.44,19.01 184.34,18.9 184.34,18.08 184.68,17.74 185.45,17.74 185.88,18.17 185.88,18.67 186.1,18.88 186.25,18.88 CS16.1
  IN2 w0.122: v2(125.39,48.32) 125.65,48.07 125.65,47.95 125.8,47.8 125.8,47.8 126,47.6 126.36,47.6 130.32,43.65 132.17,43.65 132.75,43.07 133.59,43.07 135.63,41.03 136.88,41.03 138.19,39.73 138.19,38.13 140.17,36.15 140.37,36.15 142,36.15 142.84,35.32 142.84,32.52 145.16,30.2 145.16,29.41 146.87,27.7 150.91,27.7 151.79,26.82 154.67,26.82 157.27,24.22 158.76,24.22 161.19,21.8 167.35,21.8 167.7,21.46 169.3,21.46 170.09,20.67 180.54,20.67 181.55,21.68 184,21.68 184.42,21.27 184.42,19.98 v2(184.25,19.8)
  BOTTOM w0.076: UC1.A25 123.2,48.1 123.15,48.15 123.15,48.34 123.21,48.41 123.78,48.41 123.82,48.44 124.36,48.44 124.93,47.87 125.55,47.87 125.62,47.95 125.62,48.22 125.52,48.32 v2(125.39,48.32)
PCIE_CTX_SSDRX_P11: length 93
  TOP w0.097: v2(192.39,20.18) 192.59,19.98 193.16,19.98 v3(193.55,19.6) 193.85,19.3 193.85,18.63 193.97,18.51 CS19.1
  IN2 w0.122: v2(124.03,47.01) 124.2,47.18 124.39,47.18 125.32,46.25 125.74,46.25 129.75,42.25 131.59,42.25 134.16,39.68 136.33,39.68 136.84,39.17 136.84,37.57 139.52,34.89 139.52,34.75 140.3,33.97 140.3,31.39 141.77,29.91 142.04,29.91 142.29,29.67 142.29,29.04 142.8,28.53 144.13,28.53 145.88,26.78 145.88,26.05 146.3,25.63 148.66,25.63 149.12,25.17 149.79,25.17 150.11,25.49 150.54,25.49 152.38,23.65 155.15,23.65 156.71,22.1 158.37,22.1 160.47,19.99 168.85,19.99 169.53,19.32 175.38,19.32 175.6,19.1 179.48,19.1 179.72,18.86 181.75,18.86 182.23,18.37 184.27,18.37 184.32,18.43 188.62,18.43 189.19,19 189.19,20.02 190.06,20.89 192.6,20.89 192.94,20.55 192.94,20.16 192.78,20 192.57,20 v2(192.39,20.18)
  BOTTOM w0.076: UC1.C24 122.25,47.53 122.18,47.47 122.18,47.33 122.27,47.24 122.67,47.24 122.84,47.41 123.01,47.41 123.14,47.28 123.76,47.28 v2(124.03,47.01)
PCIE_CTX_SSDRX_P12: length 84.8
  TOP w0.097: v2(184.83,19.8) 184.63,19.61 184.63,18.93 184.53,18.82 184.53,18.16 184.76,17.92 185.38,17.92 185.7,18.24 185.7,18.74 186.02,19.07 186.38,19.07 CS17.1
  IN2 w0.122: v2(184.83,19.8) 184.67,19.96 184.67,21.37 184.11,21.93 181.45,21.93 180.43,20.92 170.19,20.92 169.4,21.7 167.8,21.7 167.46,22.05 161.29,22.05 158.86,24.47 157.37,24.47 154.78,27.07 151.9,27.07 151.01,27.95 146.97,27.95 145.41,29.51 145.41,30.3 143.09,32.63 143.09,35.42 142.1,36.4 140.27,36.4 138.44,38.24 138.44,39.83 136.99,41.28 135.74,41.28 133.7,43.32 133.49,43.32 132.85,43.32 132.27,43.9 130.42,43.9 126.47,47.85 126.1,47.85 125.9,48.05 125.9,48.24 v2(125.98,48.32)
  BOTTOM w0.076: UC1.B25 123.08,47.84 123.68,47.84 123.77,47.93 123.77,47.99 123.77,47.99 123.77,48.17 123.89,48.28 124.29,48.28 124.86,47.71 125.62,47.71 125.79,47.88 125.79,48.13 v2(125.98,48.32)
PCIE_CTX_WLANRX_N5: length 2.2
  BOTTOM w0.097: JWLAN1.29 52.05,99.25 51.88,99.09 51.88,98.55 CW1.2
PCIE_CTX_WLANRX_N5_C: length 157.5
  IN2 w0.122: v2(138.45,51.86) 138.46,51.86 138.77,52.17 138.77,52.5 137.78,53.49 137.78,55.04 136.12,56.7 132.02,56.7 131.08,57.64 130.56,57.64 128.47,59.73 128.47,64.32 128.95,64.79 128.95,77.76 129.69,78.51 129.69,87.68 118.16,99.21 86.46,99.21 86.06,99.6 86.06,99.76 85.75,100.07 85.57,100.07 v2(85.57,100.06)
  BOTTOM w0.076: 133.37,47.96 133.35,47.96 133.34,47.95 130.8,47.95 126.4,43.55 124.31,43.55 123.63,44.24 122.71,44.24 122.65,44.26 122.58,44.26 122.58,44.26 122.51,44.26 122.21,44.26 122.13,44.34 122.13,44.45 UC1.C19
  BOTTOM w0.097: v2(85.57,100.06) 85.6,100.1 85.74,100.1 86.02,99.82 86.02,99.27 85.12,98.37 69.01,98.37 67.51,99.88 64.66,99.88 63.16,98.37 60.07,98.37 59.14,97.44 59.14,96.11 58.89,95.86 58.89,94.71 58.01,93.83 53.79,93.83 51.55,96.07 51.55,96.7 51.65,96.8 52.16,96.8 52.25,96.89 CW1.1 ; v2(138.45,51.86) 138.75,51.56 138.75,50.59 136.12,47.96 133.37,47.96
PCIE_CTX_WLANRX_P5: length 2.2
  BOTTOM w0.097: JWLAN1.27 51.55,99.25 51.7,99.11 51.7,98.51 CW2.2
PCIE_CTX_WLANRX_P5_C: length 157.5
  IN2 w0.122: v2(139.05,51.86) 139.02,51.89 139.02,52.6 138.03,53.59 138.03,55.15 136.22,56.95 132.13,56.95 131.19,57.89 130.66,57.89 128.72,59.83 128.72,64.21 129.2,64.69 129.2,77.66 129.94,78.4 129.94,87.79 118.27,99.46 86.56,99.46 86.31,99.71 86.31,100.03 v2(86.34,100.06)
  BOTTOM w0.076: 133.37,47.77 133.35,47.77 133.34,47.78 130.87,47.78 126.47,43.39 124.25,43.39 123.56,44.07 122.69,44.07 122.62,44.09 122.54,44.09 122.54,44.1 122.44,44.1 122.12,44.1 UC1.D19
  BOTTOM w0.097: v2(86.34,100.06) 86.21,99.93 86.21,99.2 85.2,98.19 68.93,98.19 67.43,99.69 64.74,99.69 63.24,98.19 60.15,98.19 59.33,97.36 59.33,96.03 59.08,95.78 59.08,94.64 58.08,93.64 53.72,93.64 51.36,95.99 CW2.1 ; v2(139.05,51.86) 138.94,51.76 138.94,50.51 136.2,47.77 133.37,47.77
PCIE_PTX_LANRX_N6_C: length 2.1
  BOTTOM w0.097: CL4.2 31.22,117.49 31.59,117.49 31.78,117.3 32.19,117.3 32.29,117.4 UL1.14
PCIE_PTX_LANRX_P6_C: length 2.1
  BOTTOM w0.097: CL3.2 31.21,117.31 31.51,117.31 31.7,117.11 32.19,117.11 32.31,117 UL1.13
PCIE_RCOMPN: length 2.2
  TOP w0.102: v2(120.28,36.65) v1(120.62,37)
  TOP w0.381: v2(120.28,36.65) 120.25,36.65 119.45,35.85 RC65.1
  BOTTOM w0.254: v2(120.28,36.65) 120.1,36.48 UC1.F5
PCIE_RCOMPP: length 1.6
  TOP w0.381: v2(120.98,36.62) 120.98,36.44 RC65.2
  BOTTOM w0.254: v2(120.98,36.62) 120.75,36.4 UC1.E5
PCIE_WAKE#: length 304.6
  TOP w0.102: v2(45.29,110.83) 43.41,112.71 33.2,112.71 32.32,113.59 v1(32.32,116.54) 32.32,117.53 34,119.2 34.74,119.2 v2(35.15,119.61) ; v2(77.59,24.68) 77.59,25.61 78.37,26.38 78.37,29.83 87.98,39.45 RC99.1 ; v2(191.26,16.11) 190.96,16.11 189.85,15.01 JSSD1.19
  IN1 w0.127: v2(136.42,32.75) 135.94,33.23 133.94,33.23 132.87,32.16 132.87,30.69 130.94,28.77 129.43,28.77 127.19,26.52 119.93,26.52 117.78,28.68 114.97,28.68 114.18,29.47 111.83,29.47 111.34,28.97 102.13,28.97 101.13,27.98 96.45,27.98 96.36,27.89 92.05,27.89 91.65,28.29 91.65,28.31 91.24,28.72 89.2,28.72 87.61,27.13 83.78,27.13 83.27,26.62 81.88,26.62 80.83,25.57 78.4,25.57 77.73,24.9 77.73,24.82 v2(77.59,24.68)
  IN2 w0.127: v2(136.42,32.75) 136.42,30.72 137.27,29.87 137.27,28.46 139.74,26 139.74,24.81 141.34,23.2 141.34,22.56 142.32,21.58 v2(142.32,21.43) 143.92,21.43 145.09,20.26 148.55,20.26 149.05,19.76 149.05,18.83 149.94,17.94 155.73,17.94 156.27,17.4 157.18,17.4 158.13,16.44 159.98,16.44 162.29,14.14 163.1,14.14 163.96,13.28 173,13.28 175.23,15.51 185.73,15.51 186.18,15.07 189.98,15.07 191.03,16.11 v2(191.26,16.11)
  BOTTOM w0.102: UE1.4 141.1,19.98 141.63,19.45 142.19,19.45 142.66,19.92 142.66,21.09 v2(142.32,21.43) ; RE12.2 136.62,33.36 136.42,33.15 v2(136.42,32.75) ; v2(35.15,119.61) 34.95,119.42 UL1.21 ; v2(45.29,110.83) 45.38,110.73 45.38,97.27 50.56,92.1 75.96,92.1 78.79,89.27 78.79,79.35 77.65,78.21 77.65,24.73 v2(77.59,24.68)
PECI_EC: length 77.6
  TOP w0.102: v2(153.5,20.31) 153.61,20.2 153.61,19.84 154.39,19.07 154.77,19.07 155.29,18.55 DE1.1 155.6,19.03 155.58,19.04 155.58,19.18 155.71,19.31 RE23.2
  IN2 w0.122: 125.38,44.85 125.26,44.98 122.51,44.98 122.13,45.36 119.46,45.36
  IN2 w0.127: 119.46,45.36 118.89,45.36 118.7,45.55 118.7,47.22 118.49,47.44 118.49,52.11 119.23,52.86 119.23,60.52 119.57,60.85 120.73,60.85 121.75,61.87 v2(124.54,61.87) ; v2(153.5,20.31) 152.81,21 150.21,21 149.25,21.95 146.66,21.95 146.22,22.39 146.22,23.03 143.07,26.18 141.5,26.18 140.94,26.73 140.94,28.1 138.26,30.79 138.26,32.58 136.73,34.11 134.89,34.11 133.27,35.73 133.27,36.91 131.99,38.18 131.99,38.97 131.73,39.23 131,39.23 125.38,44.85
  BOTTOM w0.102: UC1.A54 124.44,64.32 124.54,64.22 v2(124.54,61.87)
PECI_MEC1404: length 3.7
  TOP w0.102: v2(157.51,19.69) 157.39,19.69 157.31,19.77 RE23.1 156.62,20.17 v1(156.08,20.72)
  BOTTOM w0.102: v2(157.51,19.69) 157.36,19.69 157.25,19.58 UE1.94
PHASE_CHG: length 6.8
  IN2 w0.762: 206.27,34.25 205.89,34.63 201.56,34.63 200.97,35.22 199.84,35.22
  vias: v1(206.59,32.91) v2(197.5,35.2) v2(198.09,35.2) v2(207.35,34.71) v2(207.35,34.12)
PIRQA#: length 4.5
  BOTTOM w0.076: UC1.BB11 100.34,39.66 99.25,38.56 RC187.2 98.57,38.56 97.75,37.74 97.49,37.74 v1(97.24,37.48)
PLT_RST#_LAN: length 32.4
  TOP w0.102: RL12.2 45.85,109.63 43.01,112.48 33.1,112.48 31.96,113.62 31.96,117.49 v2(34.15,119.69)
  BOTTOM w0.102: UL1.19 v2(34.15,119.69)
PLT_RST_NGFF#: length 4.1
  TOP w0.102: RW4.1 55.84,110.11 55.81,110.14 v2(55.81,110.36) v1(55.81,111.1)
  BOTTOM w0.102: v2(55.81,110.36) 55.8,110.35 JWLAN1.44
PM_ZVM#: length 53.1
  TOP w0.102: v2(104.99,65.85) 104.56,65.42 102.45,65.42 101.74,66.13 101.74,72.01 101.8,72.07 101.8,72.41 101.74,72.46 101.74,74.12 104.56,76.93 104.56,89.41 101.56,92.41 v1(101.56,106.57) 101.56,107.97 104.16,110.57 v2(104.49,110.57)
  BOTTOM w0.076: v2(104.99,65.85) 105.26,65.57 UC1.AR56
  BOTTOM w0.254: PR1201.2 v2(104.49,110.57)
PME#: length 1.1
  TOP w0.089: v2(104.31,40.27) 103.85,40.27 TP12.1
  BOTTOM w0.076: v2(104.31,40.27) 104.31,40.2 UC1.AU11
POK: length 165.9
  TOP w0.102: RC102.1 CC10.1 83.66,19.07 v2(84.34,19.75) 84.34,20.27 84.16,20.45 UC5.2
  TOP w0.254: v2(175.22,38.06) 175.12,38.16 172.6,38.16 172.53,38.09 v1(168.23,38.09) 162.41,38.09 162.4,38.1 155.73,38.1 v2(155.21,38.62) ; PR13.1 187.4,22.54 186.97,22.11 186.97,22.09 v2(186.97,22.09)
  IN1 w0.127: v2(162,29.98) 159.25,32.72 154.1,32.72 152.92,32.72 152.34,33.3 150.12,33.3 149.89,33.08 144.59,33.08 144.41,33.26 141.38,33.26 139.16,31.03 137.63,31.03 135.81,29.22 134.76,29.22 132.41,26.87 130.17,26.87 128.96,25.66 128.96,21.09 126.38,18.51 118.24,18.51 117.43,19.32 111.44,19.32 109.22,21.54 108.81,21.54 108.75,21.48 104.65,21.48 100.96,17.8 92.88,17.8 92.06,18.61 85.48,18.61 v2(84.34,19.75)
  IN1 w0.254: v2(178.33,40.66) 177.25,40.66 175.22,38.62 v2(175.22,38.06)
  IN2 w0.127: v2(162,29.98) 158.36,33.61 155.91,33.61 154.26,35.26 154.26,38.12 154.76,38.62 v2(155.21,38.62)
  IN2 w0.254: v2(180.53,31.05) 180.12,31.46 180.12,32.64 179.34,33.42 179.34,39.65 v2(178.33,40.66)
  BOTTOM w0.254: v2(162,29.98) 161.47,29.98 160.79,30.66 PR501.1 ; PR107.2 174.96,37.81 v2(175.22,38.06) ; PU100.9 177.57,42.15 177.82,41.9 177.82,41.17 v2(178.33,40.66) ; PU102.9 180.24,32.15 180.53,31.86 v2(180.53,31.05) PR113.2 181.69,29.89 183.45,29.89 183.81,29.54 183.81,28.23 183.56,27.98 183.56,27.23 186.27,24.53 186.27,22.79 v2(186.97,22.09) ; PR301.1 v2(155.21,38.62)
POWER_SW#_MB: length 221.5
  TOP w0.102: v2(189.76,22.88) 189.76,26.38 188.13,28.01 188.13,32.87 189.05,33.79 189.34,33.79 189.58,34.03 189.58,34.17 190.09,34.68 190.09,36.98 191.31,38.21 195.34,38.21 197.33,40.2 197.33,42.04 195.37,44 192.71,44 191.25,45.46 184.46,45.46 179.03,50.89 174.33,50.89 173.58,51.64 168.72,51.64 167.5,50.42 v2(167.5,50.19) ; ED2901.1 155.64,109.4 EC2901.1 ; JPWR1.3 158.14,109.31 157.89,109.56 ZT2.1 156.57,109.4 EC2901.1 ; TPS8.1 153.27,109.28 v2(154.06,110.06) 154.06,110.6 154.54,111.08 SW1.1 155.44,111.08 155.63,110.89 EC2901.1
  IN1 w0.127: v2(189.76,22.88) 189.64,23.01 185.93,23.01 185.04,22.12 181.17,22.12 178.49,19.43 171.46,19.43 167.09,15.06 163.53,15.06 161.84,13.37 161.84,11.59 154.62,4.37 153.39,4.37 152.73,3.71 150.12,3.71 v2(149.85,3.45)
  IN2 w0.127: v2(154.06,110.06) 153.59,109.59 153.59,106.71 154.04,106.27 156.71,106.27 161.5,101.48 161.5,96.37 167.08,90.79 167.08,73.17 172.84,67.4 172.84,56.4 167.5,51.06 v2(167.5,50.19) ; v2(132.04,5.92) 135.34,2.62 149.03,2.62 v2(149.85,3.45)
  BOTTOM w0.102: v2(132.04,5.92) 132.42,6.3 134.38,6.3 139.47,11.39 RE43.2
POWER_SW_IN#: length 6.9
  BOTTOM w0.102: CE33.1 138.58,15 RE41.2 ; RE41.2 139.9,14.11 v1(140.55,14.75) 140.56,14.76 140.64,14.76 141.29,15.41 141.58,15.41 142.36,16.18 UE1.127 ; RE41.2 139.47,14.11 RE43.1
PROG: length 6.6
  BOTTOM w0.102: PR753.2 189.4,40.91 v1(188.43,40.91)
  BOTTOM w0.203: PU703.9 193.06,38.22 192.85,38.42 192.31,38.42 191.88,38.85 191.88,39.53 191.57,39.84 190.19,39.84 189.5,40.53 PR753.2
PROH: length 8.4
  TOP w0.102: PQ720.2 188.64,39.5 188.74,39.4 v1(188.74,39.13) v2(188.74,38.57) 189.21,38.57 PR781.2
  IN2 w0.127: v2(188.74,38.57) 188.93,38.57 191.25,36.24 v2(191.32,36.24)
  BOTTOM w0.203: PR777.2 191.14,36.24 v2(191.32,36.24) 191.54,36.03 PU703.5
PROJECT_ID1: length 30.7
  BOTTOM w0.076: UC1.AY8 102.25,37.86 101.97,37.58 101.68,37.58 101.57,37.7 100.1,37.7 98.65,36.25 98.65,35.52 97.43,34.3 97.43,32.61 97.35,32.53 97.05,32.53
  BOTTOM w0.102: RC51.2 98.06,15.97 RC52.1 97.57,17.16 v1(96.13,18.6) 95.05,19.67 95.05,20.68 94.44,21.29 94.44,22.37 92.95,23.87 92.95,25.59 94.35,27 94.35,30.55 94.62,30.83 94.62,31.5 95.65,32.53 97.05,32.53
PROJECT_ID2: length 19.2
  TOP w0.102: v2(87.62,33.25) 87.62,33.25 87.51,33.36 86.82,33.36 RC54.1 RC53.2
  IN2 w0.142: v2(87.62,33.25) 87.62,33.2 88,32.82 90.18,32.82 90.42,33.05 95.38,33.05 97.08,34.75 97.7,34.75 98.25,35.31 v2(98.25,35.77)
  BOTTOM w0.076: v2(98.25,35.77) 98.25,36.09 100.03,37.86 UC1.BA8
PS_ID: length 209
  TOP w0.102: v2(109.71,116.95) 107.94,118.72 101.76,118.72 100.86,119.63 91.38,119.63 90.35,118.6 77.22,118.6 v2(76.8,119.02)
  TOP w0.254: PR4.2 70.02,117.06 PR3.1 70.31,116.85 73.64,116.85 PD5.1 v2(74.53,116.99)
  IN1 w0.127: v2(168.86,50.94) 168.62,50.94 168.01,50.34 168.01,50.11 167.2,49.29 161.35,49.29 159.3,47.24 159.3,43.16 160.2,42.26 160.2,39.66 157.88,37.33 157.88,35.56 157.01,34.69 155.11,34.69 154.55,35.25 149.61,35.25 149.43,35.07 145.1,35.07 144.82,35.34 v2(142.09,35.34)
  IN2 w0.127: v2(76.8,119.02) 74.77,116.99 v2(74.53,116.99) ; v2(109.71,116.95) 110.71,115.95 110.71,114.84 113.15,112.4 159.94,112.4 162.01,110.33 162.01,96.58 167.58,91 167.58,73.38 173.38,67.59 173.38,56.22 168.86,51.71 v2(168.86,50.94)
  BOTTOM w0.102: UE1.36 143.16,33.83 143.06,33.93 143.06,34.47 142.77,34.76 142.77,34.97 142.39,35.34 v2(142.09,35.34)
PSID: length 3.3
  TOP w0.102: v2(74.6,122.81) v4(73.82,122.81)
  BOTTOM w0.254: PJPDC1.3 v2(74.6,122.81) 74.6,122.52 PL2.2
PSID-1: length 10.4
  TOP w0.254: PR9.2 72.94,113.66 72.94,111.46 PQ5.2 73.34,110.1 69.32,110.1 v1(69.04,110.38) 68.61,110.38 PR6.1
PSID-2: length 9.5
  TOP w0.102: PQ5.1 71.78,110.79 v1(70.92,110.79)
  TOP w0.254: PR8.2 70.05,114.5 68.82,113.26 PQ6.2 69.93,112.72 PR11.1 70.78,111.87 71.6,111.87 72.22,111.24 PQ5.1
PSID-3: length 3.1
  TOP w0.102: v1(67.84,116.54) 68.23,116.15 PR4.1
  TOP w0.254: PR4.1 68.82,115.85 PQ6.3
PTP_DIS#: length 85.8
  TOP w0.102: v2(111.46,3.19) 111.38,3.28 106.15,3.28 105.29,4.13 104.49,4.13 103.36,5.26 103.36,6.06 102.41,7.01 102.41,8.43 D6.1 ; RE22.1 157.93,20.74 157.93,17.15 157.8,17.02 v1(157.8,16.27) 157.8,16.05 158.39,15.47 158.39,14.79 157.62,14.02 157.62,12.33 157.11,11.83 154.92,11.83 154.18,11.09 153.02,11.09 151.71,12.4 150.86,12.4 v2(149.65,11.19)
  IN1 w0.127: v2(149.65,11.19) 148.83,11.19 147.68,10.05 145.61,10.05 144.78,10.88 144.78,13.54 144.74,13.57 141.34,13.57 141.21,13.71 140.26,13.71 140.04,13.49 140.04,11.86 134.69,6.51 127.69,6.51 126.7,5.52 124.23,5.52 122.19,3.49 115.39,3.49 114.63,4.25 111.82,4.25 111.46,3.89 v2(111.46,3.19)
  BOTTOM w0.102: v2(149.65,11.19) 149.97,11.51 149.97,13.31 150.74,14.09 RE26.1
PTP_DIS#_R: length 3.2
  TOP w0.102: RE22.2 156.98,21.31 v2(157.23,21.56) 157.23,21.72 v1(157.75,22.24)
  BOTTOM w0.102: UE1.90 156.85,21.18 v2(157.23,21.56)
PWM1_GT: length 47
  TOP w0.203: PU602.12 164.99,61.89 166.02,62.92 166.02,63.02 166.38,63.37
  TOP w0.254: v2(156.4,96.55) 156.4,96.42 156.14,96.17 156.14,91.82 159.06,88.9 159.06,88.24 160.14,87.16 160.14,86.7 162.04,84.8 162.04,84.43 162.87,83.6 162.87,70.92 165.13,68.65 165.13,67.8 164.7,67.37 v2(164.56,67.37) ; v2(166.31,62.26) 166.38,62.33 166.38,63.37 PR680.1
  IN2 w0.254: v2(164.56,67.37) 164.68,67.25 164.68,64.66 165.37,63.96 165.37,63.62 166.31,62.68 v2(166.31,62.26)
  BOTTOM w0.254: PU605.13 153.41,95.2 153.74,95.53 153.97,95.53 155.45,97.01 155.93,97.01 v2(156.4,96.55)
PWM2_GT: length 58.8
  TOP w0.203: PU602.13 164.59,62.06 164.87,62.34 164.87,62.68 v2(164.88,62.69) 165.51,63.33 PR681.1
  IN2 w0.254: v2(150.56,105.45) 152.33,105.45 152.8,104.98 157.55,104.98 161.18,101.35 161.18,96.14 166.76,90.57 166.76,73.04 168.68,71.12 168.68,69.27 v2(167.83,68.42)
  BOTTOM w0.254: PU604.13 150.42,105.32 v2(150.56,105.45) ; v2(167.83,68.42) 164.88,65.47 v2(164.88,62.69)
PWM_IA: length 30.2
  TOP w0.203: v2(159.48,60.77) 159.55,60.77 v1(159.91,60.41) 159.96,60.36 PU602.22
  IN2 w0.254: v2(159.48,60.77) 159.5,60.79 159.5,61.77 160.79,63.06 161.64,63.06 163.02,64.45 163.02,70.05 161.09,71.98 161.09,83.62 v2(160.54,84.17)
  BOTTOM w0.254: PR662.1 161.22,84.85 v2(160.54,84.17) 160.8,83.92 PU603.13
PWM_VSA: length 23.1
  TOP w0.203: v2(159.51,56.97) 160.54,56.97 160.73,57.16 PU602.30
  TOP w0.254: v2(153.21,65.83) 153.21,67.42 153.69,67.9 153.69,70.95 v1(153.44,71.2) 152.98,71.66 v2(152.64,71.66)
  BOTTOM w0.254: v2(153.21,65.83) 153.21,63.81 153.56,63.45 153.56,60.63 154.91,59.28 154.91,57.41 155.32,56.99 159.48,56.99 v2(159.51,56.97) ; PU606.3 v2(152.64,71.66)
PWR_LED_R#: length 5.4
  TOP w0.254: Q16.1 171.79,14.53 172.93,15.67 v1(172.93,16.4) 172.93,16.91 173.29,17.27 Q15.2
RESET_OUT#: length 126.8
  TOP w0.102: RE16.1 CE31.1 152.93,28.18 v2(153.28,28.53)
  IN1 w0.127: v2(153.28,28.53) 153.28,28.68 151.4,30.56 149.94,30.56 149,31.51 147.27,31.51 146.77,31.01 146.15,31.01 146.02,30.88 144.61,30.88 143.75,31.73 142.01,31.73 139.79,29.51 138.32,29.51 133.5,24.69 133.5,22.87 132.1,21.48 132.1,21.27 132.1,20.54 128.29,16.73 121.7,16.73 120.66,15.69 119.58,15.69 118.54,16.73 114,16.73 112.68,15.42 101.46,15.42 100.57,14.52 91.64,14.52 90.74,13.62 88.35,13.62 v2(87.93,14.04)
  BOTTOM w0.076: 89.71,39.28 93.84,43.41 94.79,43.41 95.17,43.79 95.17,43.8 96.07,44.7 98.26,44.7 98.33,44.77 101.23,44.77 UC1.BA20
  BOTTOM w0.102: v2(153.28,28.53) 153.82,27.98 UE1.73 ; 89.71,39.28 83,32.57 83,31.17 83.97,30.21 83.97,28.21 83.31,27.55 83.31,25.07 83.69,24.69 83.69,24.11 85.3,22.5 85.3,20.92 87,19.21 87,15.54 87.93,14.61 v2(87.93,14.04)
RING2: length 5.3
  IN2 w1.016: 23.32,15.96 23.32,17.67 22.05,18.94 22.05,19.45 21.74,19.77 21.74,20.59
  vias: v1(24.02,14.75) v2(22.69,20.91) v2(23.32,20.89) v2(23.4,15.06) v2(23.96,15.26)
RING2_R: length 15.7
  BOTTOM w1.016: JHP1.4 5.63,11.64 ZT23.1 13.47,11.64 13.8,11.97 13.8,12.78 16.21,15.19 DA5.2
RTC_DET#: length 108.2
  IN2 w0.127: v2(118.53,31.07) 118.53,30.82 118.65,30.69 118.65,26.68 118.53,26.56 118.53,20.03 118.33,19.83 118.33,16.67 118.53,16.46 118.53,14.35 116.98,12.8 114.16,12.8 112.7,11.34 112.43,11.34 108.7,7.61 102.8,7.61 101.69,8.72 86.53,8.72 v2(86.32,8.5)
  BOTTOM w0.076: UC1.P1 116.18,33.54 116.55,33.16 116.55,33.13 117.51,32.16 118.23,32.16 118.53,31.87 v2(118.53,31.07) 118.53,30.13 118.38,29.99 118.38,29.15
  BOTTOM w0.102: v2(86.32,8.5) 86.32,6.81 83.71,4.21 69.04,4.21 66.99,2.15 v1(61.04,2.15) 44.03,2.15 42.85,3.33 Q1.1 ; RC46.1 118.38,27.95 118.38,29.15
RTC_PWR: length 20.5
  TOP w0.102: R2.1 v1(38.97,3.09) 39.71,2.36 v2(41.35,2.36)
  BOTTOM w0.102: R1.1 34.08,7.96 34.63,7.42 34.63,4.53 34.06,3.96 34.06,2.96 34.65,2.36 D1.3 Q1.2 v2(41.35,2.36)
RTCRST_ON: length 67
  TOP w0.102: RC164.1 v2(86.57,20.71) 87.24,20.71 87.45,20.91 QC2.2
  IN1 w0.127: v2(137.51,32.72) 137.34,32.72 136.7,32.07 135.12,32.07 134.55,31.51 134.4,31.51 131.15,28.26 129.64,28.26 127.4,26.01 119.72,26.01 119.14,26.6 116.69,26.6 115.88,25.8 115.88,25.71 115.22,25.05 111.64,25.05 111.03,24.43 108.15,24.43 107.74,24.03 107.19,24.03 106.74,23.58 104.48,23.58 102.62,25.44 98.59,25.44 94.44,21.29 87.15,21.29 v2(86.57,20.71)
  BOTTOM w0.102: UE1.31 141.27,30.78 141.43,30.94 141.43,31.39 140.35,32.47 139.21,32.47 138.96,32.72 v2(137.51,32.72) 137.12,32.72 v1(136.86,32.47)
RUNPWROK: length 1.8
  BOTTOM w0.102: RE42.1 147.94,33.81 147.96,33.78 UE1.48
SA_SNUB: length 2
  TOP w0.102: PC622.1 148.66,62.62 v1(149.13,62.15)
SA_SW: length 15.4
  TOP w0.508: v2(148.99,64.53) 149.37,64.15 PR627.1
  BOTTOM w0.762: 148.17,74.06 147.06,74.06 146.36,73.36 146.36,70.22 144.74,68.6 v1(144.74,67.07) 144.74,66.19 146.58,64.34 148.23,64.34
SATA3_CRX_HDDTX_N0: length 105.6
  IN2 w0.122: v2(192.96,23.45) 192.87,23.37 192.87,22.95 193.23,22.59 194.51,22.59 195.01,22.1 195.01,18.76 193.77,17.52 193.77,15.07 193.05,14.34 182.8,14.34 182.31,14.83 175.51,14.83 173.28,12.6 162.51,12.6 159.6,15.51 157.75,15.51 157.32,15.94 156.14,15.94 155.13,16.95 149.61,16.95 148.77,17.79 144.48,17.79 144.14,18.13 144.14,18.38 143.24,19.28 141.41,19.28 140.56,20.13 140.56,21.82 140.4,21.99 140.4,22.67 139.47,23.6 138.62,23.6 136.92,25.3 136.92,27.58 135.74,28.76 134.9,28.76 133.61,30.06 133.61,31.4 131.41,33.6 131.41,36.75 127.43,40.72 125.84,40.72 124.82,41.74 124.09,41.74 121.53,44.31 120.9,44.31 v2(120.36,44.86)
  BOTTOM w0.076: UC1.F20 120.36,44.68 v2(120.36,44.86)
  BOTTOM w0.097: v2(192.96,23.45) 192.88,23.38 192.88,23.08 CS3.1
SATA3_CRX_HDDTX_P0: length 105.3
  IN2 w0.122: v2(121.13,44.86) 121.13,44.68 121.26,44.56 121.63,44.56 124.2,41.99 124.92,41.99 125.95,40.97 127.54,40.97 131.66,36.85 131.66,33.71 133.86,31.51 133.86,30.16 135,29.01 135.84,29.01 137.17,27.69 137.17,25.4 138.72,23.85 139.57,23.85 140.65,22.78 140.65,22.09 140.81,21.93 140.81,20.24 141.52,19.53 143.34,19.53 144.39,18.48 144.39,18.23 144.58,18.04 148.87,18.04 149.71,17.2 155.24,17.2 156.25,16.19 157.42,16.19 157.85,15.76 159.7,15.76 162.61,12.85 173.18,12.85 175.41,15.08 182.41,15.08 182.9,14.59 192.94,14.59 193.52,15.17 193.52,17.63 194.76,18.86 194.76,21.99 194.41,22.34 193.13,22.34 192.63,22.85 192.63,23.2 v2(192.37,23.45)
  BOTTOM w0.076: v2(121.13,44.86) 121.04,44.96 120.87,44.96 120.75,44.84 UC1.E20
  BOTTOM w0.097: CS4.1 192.6,22.81 192.69,22.9 192.69,23.14 192.38,23.45 v2(192.37,23.45)
SATA3_CTX_HDDRX_N0: length 102.8
  IN2 w0.122: v2(124.62,44.33) 124.82,44.13 124.82,43.19 125.76,42.25 126.87,42.25 132.52,36.59 132.52,35.42 134.58,33.36 136.4,33.36 136.85,32.91 136.85,31.13 140.16,27.82 140.16,25.62 140.75,25.04 140.75,24.65 141.15,24.25 143.67,24.25 145.12,22.8 145.12,21.56 145.48,21.2 148.94,21.2 149.89,20.24 152.5,20.24 153.11,19.64 153.6,19.64 154.32,18.92 156.47,18.92 157.05,18.34 157.67,18.34 158.57,17.44 160.32,17.44 161.88,15.88 163.59,15.88 164.61,14.85 170.08,14.85 171.94,16.71 180.05,16.71 180.29,16.46 188.44,16.46 190,18.02 190,19.68 190.44,20.12 190.7,20.12 191.89,18.93 193.45,18.93 194.12,19.6 194.12,20.73 191.78,23.06 191.78,23.77 192.05,24.05 194.24,24.05 194.53,23.77 194.53,23.65 v2(194.37,23.49)
  BOTTOM w0.076: v2(124.62,44.33) 124.69,44.33 124.84,44.48 124.84,44.76 124.43,45.17 123.19,45.17 123.02,45.34 123.02,45.53 123.01,45.53 UC1.B21
  BOTTOM w0.097: v2(194.37,23.49) 194.56,23.3 194.56,23.19 CS2.1
SATA3_CTX_HDDRX_P0: length 102.8
  IN2 w0.122: v2(194.95,23.49) 194.77,23.67 194.77,23.87 194.35,24.3 191.95,24.3 191.53,23.87 191.53,22.96 193.87,20.62 193.87,19.71 193.34,19.18 191.99,19.18 190.8,20.37 190.34,20.37 189.75,19.78 189.75,18.12 188.34,16.71 180.4,16.71 180.16,16.96 171.83,16.96 169.98,15.1 164.71,15.1 163.69,16.13 161.98,16.13 160.42,17.69 158.67,17.69 157.77,18.59 157.15,18.59 156.57,19.17 154.43,19.17 153.71,19.89 153.21,19.89 152.6,20.49 150,20.49 149.05,21.45 145.59,21.45 145.37,21.66 145.37,22.9 143.77,24.5 141.26,24.5 141,24.76 141,25.14 140.41,25.73 140.41,27.92 137.1,31.24 137.1,33.01 136.5,33.6 134.68,33.6 132.77,35.52 132.77,36.7 126.97,42.49 125.86,42.49 125.06,43.29 125.06,44.21 125.19,44.33 v2(125.2,44.33)
  BOTTOM w0.076: UC1.A21 123.28,45.62 123.18,45.52 123.18,45.41 123.22,45.37 123.22,45.37 123.26,45.33 124.5,45.33 125,44.83 125,44.53 v2(125.2,44.33)
  BOTTOM w0.097: v2(194.95,23.49) 194.75,23.29 194.75,23.18 CS1.1
SATA_CRX_ODDTX_N1: length 87.5
  IN2 w0.122: v2(190.77,44.73) 190.55,44.51 190.38,44.51 190.25,44.63 190.25,45.86 188.2,47.92 182.71,47.92 181.3,49.33 174.57,49.33 172.67,47.42 165.43,47.42 163.34,49.51 156.1,49.51 155.16,48.58 136.42,48.58 135.58,47.74 130.3,47.74 128.64,49.4 128.09,49.4 127.58,49.92 122.76,49.92 121.6,51.08 121.6,51.28 121.01,51.87 120.26,51.87 120.15,51.98 119.42,51.98 119.02,51.59 119.02,48.09 120.15,46.97 120.15,46.46 119.97,46.28 119.97,46.02 v2(119.76,45.8)
  BOTTOM w0.097: UC1.G21 119.76,45.64 v2(119.76,45.8) ; v2(190.77,44.73) 190.98,44.52 191.63,44.52 191.73,44.62 191.73,44.77 CS10.2
SATA_CRX_ODDTX_P1: length 87.6
  IN2 w0.122: v2(190.77,44.14) 190.65,44.26 190.27,44.26 190,44.53 190,45.76 188.09,47.67 182.6,47.67 181.2,49.08 174.67,49.08 172.77,47.17 165.32,47.17 163.23,49.26 156.2,49.26 155.27,48.33 136.52,48.33 135.68,47.49 130.19,47.49 128.53,49.15 127.99,49.15 127.47,49.67 122.66,49.67 121.35,50.97 121.35,51.18 120.91,51.62 120.15,51.62 120.04,51.73 119.52,51.73 119.27,51.48 119.27,48.2 120.4,47.07 120.4,46.35 120.22,46.18 120.22,46.01 v2(120.42,45.81)
  BOTTOM w0.097: UC1.F21 120.43,45.75 v2(120.42,45.81) ; v2(190.77,44.14) 190.96,44.33 191.71,44.33 191.86,44.49 192.01,44.49 CS9.2
SATA_CTX_ODDRX_N1: length 77.1
  IN2 w0.122: v2(127.66,48.87) 127.81,48.73 128.11,48.73 128.4,48.43 128.4,47.8 129.54,46.66 135.45,46.66 136.7,47.9 155.44,47.9 156.38,48.84 163.06,48.84 164.44,47.45 165.15,46.75 172.95,46.75 174.85,48.65 181.02,48.65 182.43,47.24 187.9,47.24 189.35,45.79 v2(189.35,44.29)
  BOTTOM w0.076: 125.48,46.24 123.71,46.24 123.36,46.06 123.35,46.06 123.22,46.02 123.05,46.02 122.99,46.04 122.93,46.06 122.75,46.06 122.64,46.02 122.06,45.94 UC1.D21
  BOTTOM w0.097: v2(189.35,44.29) 189.15,44.48 189.15,44.62 CS11.2 ; 125.48,46.24 125.65,46.24 126.83,47.43 126.83,48.51 127.12,48.8 127.59,48.8 v2(127.66,48.87)
SATA_CTX_ODDRX_P1: length 77.1
  IN2 w0.122: v2(188.65,44.25) 189.1,44.69 189.1,45.69 187.79,46.99 182.32,46.99 180.92,48.4 174.95,48.4 173.05,46.5 165.04,46.5 164.19,47.35 162.95,48.59 156.48,48.59 155.55,47.65 136.8,47.65 135.56,46.41 129.44,46.41 128.16,47.69 128.16,48.33 128,48.48 127.79,48.48 127.66,48.34 v2(127.66,48.21)
  BOTTOM w0.076: 125.48,46.05 125.47,46.05 125.46,46.06 125.41,46.06 125.4,46.07 123.75,46.07 123.75,46.08 123.25,45.83 123.1,45.83 122.91,45.89 122.8,45.89 122.67,45.86 122.6,45.83 122.51,45.83 122.45,45.77 122.45,45.73 122.5,45.67 122.5,45.55 122.47,45.51 122.28,45.51 UC1.C21
  BOTTOM w0.097: 125.48,46.05 125.72,46.05 127.02,47.35 127.02,48.43 127.2,48.62 127.38,48.62 127.66,48.35 v2(127.66,48.21) ; v2(188.65,44.25) 188.83,44.25 188.95,44.37 188.95,44.62 CS12.2
SATA_LED#: length 84.5
  TOP w0.102: v2(150.58,36.43) v1(151.45,35.56) 152.2,34.8 152.2,33.47 153.09,32.58 156.5,32.58 156.98,32.1 156.98,30.9 158.01,29.87 158.01,27.43 158.39,27.05 158.39,24.97 159.28,24.08 159.28,23.2 158.83,22.75 158.83,20.01 158.62,19.79 158.62,16.21 159.13,15.7 159.13,12.93 157.09,10.89 155.97,10.89 155.47,10.39 155.47,9.39 154.37,8.3 Q5.3
  IN1 w0.127: v2(150.58,36.43) 150,37.01 147.61,37.01 146.56,38.05 142.77,38.05 142.67,37.96 138.23,37.96 135.92,35.66 132.95,35.66 132.03,34.73 131.64,34.73 130.83,33.93 129.68,33.93 125.99,30.24 125.86,30.24 125.16,29.54 121.69,29.54 120.12,31.11 v2(120.12,31.32)
  BOTTOM w0.076: UC1.H1 119.3,32.44 119.63,32.11 119.63,31.81 v2(120.12,31.32)
  BOTTOM w0.102: v2(120.12,31.32) 120.23,31.21 120.23,30.2 119.53,29.5 119.53,25.88 118.89,25.24 118.89,24.89 118.08,24.08 RC69.1
SATA_LED_EN: length 41.1
  TOP w0.102: Q5.2 156.29,7.43 R23.2 155.77,9.61 155.77,10.37 156.06,10.66 157.35,10.66 v1(158.29,11.61) 159.35,12.67 159.35,15.8 158.85,16.3 158.85,17.94 v2(159.02,18.12)
  BOTTOM w0.102: v2(159.02,18.12) 158.58,17.67 155.93,17.67 153.69,19.91 153.33,19.91 152.09,21.15 145.05,21.15 144.61,21.59 144.61,25.74 143.82,26.52 143.82,27.48 142.5,28.8 142.5,29.76 141.88,30.38 UE1.30
SATA_ODD_DA#: length 5.9
  BOTTOM w0.102: TP46.1 199.21,46.06 198.5,46.78 198.5,46.78 JODD1.23 JODD1.24
SATA_ODD_PRSNT#: length 4.8
  BOTTOM w0.102: TP47.1 194.5,45.84 JODD1.15 JODD1.16
SATA_RXN0_R: length 8.4
  BOTTOM w0.097: JHDD1.5 197.15,17.67 196.98,17.84 196.98,18.02 196.52,18.48 195.74,18.48 195.64,18.58 v3(195.36,18.58) 194.97,18.58 194.8,18.76 194.71,18.76 194.65,18.81 194.43,18.81 194.4,18.85 193.78,18.85 193.75,18.81 193.67,18.81 193.57,18.91 193.57,19.19 193.7,19.32 EU3101.4 EU3101.7 193.7,20.81 193.55,20.97 193.55,21.16 193.34,21.36 192.97,21.36 192.89,21.44 192.89,21.62 CS3.2
SATA_RXN2_R: length 5.5
  BOTTOM w0.097: JODD1.10 191.5,50.03 191.92,49.61 191.92,48.85 191.5,48.43 JODD1.9 191.5,46.85 191.5,46.85 191.59,46.75 191.81,46.75 191.9,46.65 191.9,46.25 CS10.1
SATA_RXP0_R: length 8.7
  BOTTOM w0.097: CS4.2 192.5,21.89 192.71,21.68 192.71,21.36 192.89,21.18 193.26,21.18 193.36,21.08 193.36,20.97 193.2,20.81 EU3101.6 EU3101.5 193.2,19.29 193.39,19.11 193.39,18.84 193.6,18.63 v3(194.08,18.63) 194.57,18.63 194.63,18.57 194.72,18.57 194.92,18.36 195.59,18.36 195.66,18.29 196.44,18.29 196.79,17.94 196.79,17.8 196.65,17.65 JHDD1.6
SATA_RXP2_R: length 5.5
  BOTTOM w0.097: CS9.1 192.09,46.27 192.09,46.65 192.19,46.75 192.4,46.75 192.5,46.85 JODD1.11 192.5,48.46 192.11,48.85 192.11,49.61 192.5,50 JODD1.12
SATA_TXN0_R: length 8
  BOTTOM w0.097: JHDD1.3 198.15,18.4 197.68,18.88 v3(196.63,18.88) 195.98,18.88 195.88,18.98 195.14,18.98 194.96,19.16 194.88,19.16 194.7,19.33 EU3101.2 EU3101.8 194.7,20.83 194.84,20.96 194.84,21.09 194.64,21.29 194.64,21.43 CS2.2
SATA_TXN2_R: length 5.5
  BOTTOM w0.097: JODD1.6 189.5,50.02 189.12,49.64 189.12,49 189.5,48.62 JODD1.5 189.5,46.85 189.4,46.75 189.19,46.75 189.09,46.65 189.09,46.28 CS11.1
SATA_TXP0_R: length 8
  BOTTOM w0.097: JHDD1.2 198.65,17.66 198.55,17.76 198.43,17.76 198.34,17.86 198.34,18.53 v3(198.06,18.81) 197.8,19.07 196.95,19.07 196.92,19.1 196.34,19.1 196.31,19.07 196.06,19.07 195.95,19.17 195.3,19.17 195.2,19.26 EU3101.1 EU3101.9 195.2,20.79 195.03,20.96 195.03,21.16 194.82,21.37 194.82,21.58 CS1.2
SATA_TXP2_R: length 5.4
  BOTTOM w0.097: CS12.1 188.9,46.17 188.9,46.65 188.81,46.75 188.59,46.75 188.5,46.85 188.5,46.85 JODD1.3 188.5,48.48 188.93,48.91 188.93,49.56 188.5,49.99 JODD1.4
SD_RCOMP: length 2.6
  TOP w0.102: v2(111.77,37.17) 112.17,36.76 112.17,35.83 112.15,35.81 RC130.1
  BOTTOM w0.076: UC1.AB7 112.02,36.91 v2(111.77,37.17)
SERIRQ: length 94.1
  TOP w0.102: RC14.2 92.55,34.52 v2(92.41,34.38)
  IN1 w0.127: v2(92.41,34.38) 92.81,33.99 93.62,33.99 95.78,31.83 98.84,31.83 99,31.67 99.35,31.67 99.52,31.83 99.8,31.83 100.32,31.31 107.08,31.31 109.76,33.99 111.74,33.99 111.85,34.1 116.55,34.1 117.03,34.58 121.74,34.58 124.45,37.28 124.82,37.28 125,37.46 126.47,37.46 128.65,39.64 129.8,39.64 130.91,40.75 133.57,40.75 134.24,41.42 134.67,41.42 135.63,42.38 135.63,44.28 136.38,45.03 136.38,46.49 v2(137.12,47.22)
  IN2 w0.127: v2(137.12,47.22) 137.42,47.22 137.97,46.68 137.97,46.46 138.24,46.18 139.15,46.18 139.82,45.51 139.82,41.09 142.34,38.56 145.6,38.56 147.85,36.32 147.85,34.69 150.96,31.58 v2(150.96,31.49)
  BOTTOM w0.076: UC1.AY11 101.52,40.08 100.51,40.08 99.95,39.52
  BOTTOM w0.102: UE1.55 150.76,31.78 150.96,31.58 v2(150.96,31.49) ; v2(92.41,34.38) 92.41,34.4 94.51,36.5 94.51,37.15 95.61,38.25 96.51,38.25 97.4,39.13 99.57,39.13 99.95,39.52
SIO_EXT_SCI#: length 58.5
  IN1 w0.127: v2(155.4,35.71) 155.1,36.01 150.23,36.01 149.49,36.75 147.5,36.75 146.45,37.8 142.87,37.8 142.78,37.7 138.33,37.7 136.03,35.4 133.06,35.4 132.13,34.48 131.74,34.48 130.94,33.67 129.78,33.67 126.1,29.99 125.96,29.99 125.26,29.29 121.53,29.29 v2(119.53,31.28)
  BOTTOM w0.076: UC1.J2 118.64,34.05 118.96,33.74 118.96,32.47 119.27,32.15 119.27,31.54 v2(119.53,31.28)
  BOTTOM w0.102: v2(119.53,31.28) 120.04,30.78 120.04,30.28 119.27,29.51 119.27,26.24 118.01,24.97 RC70.1 ; UE1.66 156.96,30.78 157.06,30.88 157.06,33.04 155.4,34.69 v2(155.4,35.71)
SIO_EXT_SMI#: length 70.9
  TOP w0.102: v2(117.01,37.08) 117.47,37.08 RC5.2
  IN1 w0.127: v2(135.68,45.93) 135.12,45.37 135.12,42.95 134.61,42.44 130.37,42.44 126.15,38.22 124.68,38.22 124.51,38.04 124.11,38.04 122.22,36.15 118.21,36.15 117.28,37.08 v2(117.01,37.08) ; v2(141.81,22.74) 141.86,22.74 142.03,22.9 144.4,22.9 145.01,23.51 147.49,23.51 150.52,26.54 150.52,27.68 150.96,28.12 150.96,29.61 v2(150.95,29.61)
  IN2 w0.127: v2(135.68,45.93) 136.56,46.8 137.48,46.8 137.71,46.57 137.71,46.35 138.14,45.93 139.04,45.93 139.57,45.4 139.57,40.98 142.24,38.31 145.5,38.31 147.59,36.21 147.59,32.68 147.02,32.11 147.02,30.95 148.04,29.94 150.31,29.94 150.64,29.61 v2(150.95,29.61)
  BOTTOM w0.102: v2(141.81,22.74) 141.5,22.74 141.14,22.38 UE1.10 ; UC1.L6 117.13,36.63 117.13,36.96 v2(117.01,37.08)
SIO_EXT_WAKE#: length 86.1
  IN1 w0.127: v2(137.12,46.39) 137.08,46.39 136.63,45.94 136.63,44.92 135.88,44.17 135.88,42.28 134.77,41.17 134.34,41.17 133.67,40.5 131.02,40.5 129.91,39.39 128.76,39.39 126.58,37.21 125.11,37.21 124.93,37.03 124.55,37.03 121.85,34.33 117.14,34.33 116.66,33.85 111.95,33.85 111.21,33.1 v2(110,33.1) ; v2(146.78,18.46) 146.4,18.08 144.86,18.08 144.59,18.35 144.59,19.66 145.18,20.25 146.05,20.25 147.98,22.18 147.98,23.64 150.77,26.43 150.77,27 v2(152.18,28.42)
  IN2 w0.127: v2(137.12,46.39) 137.32,46.39 138.03,45.67 138.94,45.67 139.31,45.3 139.31,40.87 142.13,38.05 145.39,38.05 147.34,36.11 147.34,32.78 146.77,32.21 146.77,30.85 147.93,29.68 150.21,29.68 150.83,29.06 151.54,29.06 v2(152.18,28.42)
  BOTTOM w0.076: UC1.AD3 110.68,34.7 110.39,34.41 110.39,33.98 110.26,33.7 110.26,33.36 v2(110,33.1)
  BOTTOM w0.102: v2(146.78,18.46) 146.76,18.44 UE1.116 ; RC47.1 110.76,30.38 110.76,32.34 v2(110,33.1)
SIO_PWRBTN#: length 96.3
  TOP w0.102: RC93.2 91.02,36.59 91.02,36.85 91.39,37.22 v2(91.65,37.22)
  IN1 w0.127: v2(148.61,35.51) 148.39,35.74 147.08,35.74 146.09,36.72 144.86,36.72 144.19,36.05 139.01,36.05 136.71,33.75 133.74,33.75 132.27,32.28 132.27,31.59 131.5,30.82 131.03,30.82 129.48,29.28 129.2,29.28 126.95,27.03 120.14,27.03 117.99,29.19 115.18,29.19 114.39,29.97 111.62,29.97 111.12,29.48 101.81,29.48 100.81,28.49 95.63,28.49 94.72,29.4 87.89,29.4 87.86,29.42 87.41,29.42 87.15,29.68 v2(87.15,29.69)
  BOTTOM w0.076: 92.02,37.66 92.42,37.66 95.61,40.85 98.64,40.85 99.75,41.96 100.49,41.96 100.62,41.83 101.07,41.83 101.33,42.08 UC1.BA15
  BOTTOM w0.102: UE1.52 149.56,33.87 149.56,33.87 149.56,34.33 148.61,35.28 v2(148.61,35.51) ; v2(87.15,29.69) 87.14,29.69 86.55,30.29 86.55,32.78 90.98,37.22 v2(91.65,37.22) 91.65,37.29 92.02,37.66
SIO_RCIN#: length 94.7
  TOP w0.102: RC13.2 92.55,37.01 v2(92.76,37.22)
  IN1 w0.127: v2(149.19,35.51) 149.19,35.69 148.9,35.99 147.18,35.99 146.2,36.98 144.76,36.98 144.09,36.31 138.91,36.31 136.61,34 133.63,34 132.01,32.38 132.01,31.7 131.39,31.08 130.92,31.08 129.38,29.53 129.09,29.53 126.85,27.28 120.25,27.28 118.09,29.44 117.88,29.44 115.28,29.44 114.5,30.23 111.51,30.23 111.02,29.74 101.71,29.74 100.71,28.74 95.73,28.74 94.82,29.65 87.99,29.65 87.42,30.22 v2(87.4,30.22)
  BOTTOM w0.076: UC1.AW13 102.29,41.1 101.82,41.25 101.74,41.25 101.58,41.3 101.44,41.3 101.22,41.24 101.1,41.24 101.02,41.27 100.99,41.29 100.61,41.29 100.5,41.18 99.94,41.18 99.93,41.19 99.79,41.19
  BOTTOM w0.102: v2(149.19,35.51) 149.19,35.12 149.96,34.36 UE1.53 ; 99.79,41.19 98.87,40.28 96.92,40.28 96.03,39.39 94.84,39.39 92.96,37.51 92.96,37.41 v2(92.76,37.22) 92.36,36.81 91.8,36.81 88.95,33.96 88.95,33.28 87.95,32.28 87.95,30.54 87.65,30.24 87.42,30.24 v2(87.4,30.22)
SIO_SLP_A#: length 1.4
  TOP w0.076: TPS6.1 105.72,43.46 v2(106.18,43)
  BOTTOM w0.102: v2(106.18,43) 106.56,42.6 UC1.AN16
SIO_SLP_LAN#: length 99.2
  TOP w0.102: RC88.1 37.57,1.95 71.68,1.95 76.14,6.42 76.14,24.48 78.14,26.47 78.14,30.11 87.99,39.96 92.92,39.96 93.56,40.61 94.77,40.61 95.54,39.83 96.6,39.83 96.94,40.17 102.27,40.17 103.18,41.09 103.18,41.84 v2(103.39,42.05) 103.66,42.05 TP10.1
  BOTTOM w0.076: v2(103.39,42.05) 103.31,42.13 UC1.AW15
SIO_SLP_S0#: length 73.2
  TOP w0.076: TPS2.1 105.71,40.31 v2(105.11,40.31) 105.11,39.37 104.6,38.86 103.15,38.86 103.04,38.75 102.05,38.75
  TOP w0.102: v2(105.24,19.7) 106.27,20.74 106.27,23.12 105.98,23.41 105.26,23.41 104.66,24.02 104.66,24.59 101.47,27.78 101.47,30.52 98.76,33.23 98.76,35.84 97.87,36.72 97.87,37.99 98.64,38.75 102.05,38.75 ; UC9.2 137.56,27 137.23,26.68 136.26,26.68 135.38,27.56 v2(135.28,27.56)
  IN1 w0.127: v2(135.28,27.56) 135.18,27.56 131.5,23.87 131.5,23.24 130.86,22.59 130.86,21.19 126.91,17.24 117.71,17.24 116.9,18.05 110.39,18.05 108.74,19.7 v2(105.24,19.7)
  BOTTOM w0.102: v2(105.11,40.31) 105.01,40.21 104.97,40.21 UC1.AT11
SIO_SLP_S3#: length 262
  TOP w0.102: v2(105.54,42.14) 106.27,41.4 106.27,38.22 105.95,37.9 105.45,37.9 104.6,37.06 104.6,36.09 105.43,35.26 105.43,34.63 104.86,34.05 102.95,34.05 102.22,33.32 102.22,28 103.44,26.78 104.39,26.78 104.76,26.4 104.76,26.14 106.73,24.17 106.73,21.45 v2(107.65,20.53) ; RZ2.1 138.12,31.18 137.37,30.43 137.37,29.36 136.91,28.89 UC9.1 136.91,27.24 TPS3.1 135.65,28.02 v2(135.65,28.03) ; UZ3.3 167.78,25.04 167.52,25.31 166.98,25.31 v2(166.71,25.04) 166.71,24.85 166.98,24.57 UZ3.5 ; CE29.1 153.76,29.34 153.32,29.79 v2(153.32,30.5) ; DZ4.1 85.19,17.69 v2(85.22,17.69) RC103.1
  IN1 w0.127: v2(85.22,17.69) 85.87,17.04 101.28,17.04 104.77,20.53 v2(107.65,20.53) 108.27,20.53 110.49,18.31 117.01,18.31 117.82,17.5 126.8,17.5 130.6,21.29 130.6,23.59 135.04,28.03 v2(135.65,28.03) 136.12,28.03 138.11,30.02 139.58,30.02 141.8,32.24 143.99,32.24 144.17,32.06 149.16,32.06 150.16,31.07 152.75,31.07 v2(153.32,30.5)
  IN2 w0.127: v2(104.5,111.23) 107.87,107.87 v2(107.87,107.04) ; v2(166.71,25.04) 166.14,25.04 165.63,25.55 163.28,25.55 162.01,26.82 156.59,26.82 155.15,28.26 154.15,28.26 153.32,29.09 v2(153.32,30.5)
  BOTTOM w0.102: v2(105.54,42.14) UC1.AP15 ; v2(104.5,111.23) 104.25,111.49 PR1204.2 ; v2(135.65,28.03) 136.2,27.48 137.17,27.48 137.52,27.13 139.09,27.13 139.53,27.58 UE1.23 ; v2(85.22,17.69) 84.83,18.08 83.05,18.08 81.6,19.52 81.6,22.89 80.9,23.59 80.9,26.33 81.05,26.48 81.19,26.62 81.19,28.07 80.44,28.82 80.44,76.63 84.57,80.76 89.85,80.76 91.33,82.25 91.33,87.52 96.44,92.63 104.9,92.63 109.15,96.88 109.15,104.48 107.87,105.76 v2(107.87,107.04)
SIO_SLP_S4#: length 284.8
  TOP w0.102: RZ1.1 136.24,38.04 DZ5.1 139.68,37.15 140.44,37.91 146.85,37.91 147.53,37.23 149.12,37.23 151.98,34.37 151.98,33.2 152.93,32.25 152.93,31.58 153.9,30.6 v2(153.9,30.5)
  TOP w0.254: v2(92.42,106.25) 91.9,105.73 91.9,96.28 87.59,91.97 v2(76.66,91.97)
  IN1 w0.127: v2(79.46,13.99) 79.93,14.46 88.37,14.46 v2(88.79,14.04) 90.16,14.04 90.9,14.78 100.46,14.78 101.36,15.67 112.58,15.67 113.89,16.99 128.18,16.99 131.85,20.65 131.85,21.16 131.85,21.58 133.24,22.98 133.24,24.79 138.21,29.76 139.68,29.76 141.91,31.99 143.89,31.99 144.07,31.81 149.06,31.81 150.05,30.82 152.36,30.82 153.09,30.08 153.52,30.08 153.9,30.46 v2(153.9,30.5)
  BOTTOM w0.076: UC1.BA16 101.62,42.5 99.35,42.5 99.01,42.15 98.86,42.15 TPS4.1 98.05,41.34 95.28,41.34 94.95,41.67 94.83,41.67 91.07,37.92
  BOTTOM w0.102: v2(153.9,30.5) 153.99,30.42 155.04,30.42 155.08,30.38 UE1.67 ; 91.07,37.92 85.51,32.36 85.51,27.58 85.52,27.58 85.52,25.4 86.01,24.91 86.01,23.25 87.46,21.8 87.46,15.73 88.79,14.39 v2(88.79,14.04)
  BOTTOM w0.254: PR201.1 v2(92.42,106.25) ; PR803.1 60.22,8.28 65.17,13.23 78.7,13.23 v2(79.46,13.99) 79.7,14.23 79.7,21.87 78.08,23.5 78.08,78.1 79.09,79.11 79.09,89.54 v2(76.66,91.97)
SIO_SLP_S5#: length 172.6
  TOP w0.254: v2(197.94,20.96) 197.94,21.47 PQ711.2
  IN1 w0.127: v2(93.69,2.77) 94.62,1.84 112.46,1.84 112.94,2.32 112.94,2.79 113.25,3.1 114.16,3.1 114.91,2.35 123.57,2.35 124.2,2.98 125.53,2.98 125.91,2.6 153.93,2.6 165.61,14.29 167.6,14.29 171.5,18.19 179.86,18.19 182.96,21.29 186.03,21.29 186.14,21.4 193.19,21.4 195.02,19.58 196.56,19.58 v2(197.94,20.96)
  BOTTOM w0.076: UC1.AY16 102.19,42.98 101.71,42.98 101.39,42.67 99.29,42.67 98.94,42.32 98.26,42.32 97.62,41.67 TPS5.1 95.71,41.67 95.16,42.23 95.05,42.23 90.91,38.08
  BOTTOM w0.102: v2(93.69,2.77) 93.34,2.77 91.04,5.07 91.04,11.43 88.93,13.54 88.71,13.54 88.34,13.92 88.34,14.53 87.23,15.63 87.23,21.71 85.78,23.16 85.78,24.81 85.29,25.31 85.29,27.48 85.29,27.48 85.29,32.46 90.91,38.08
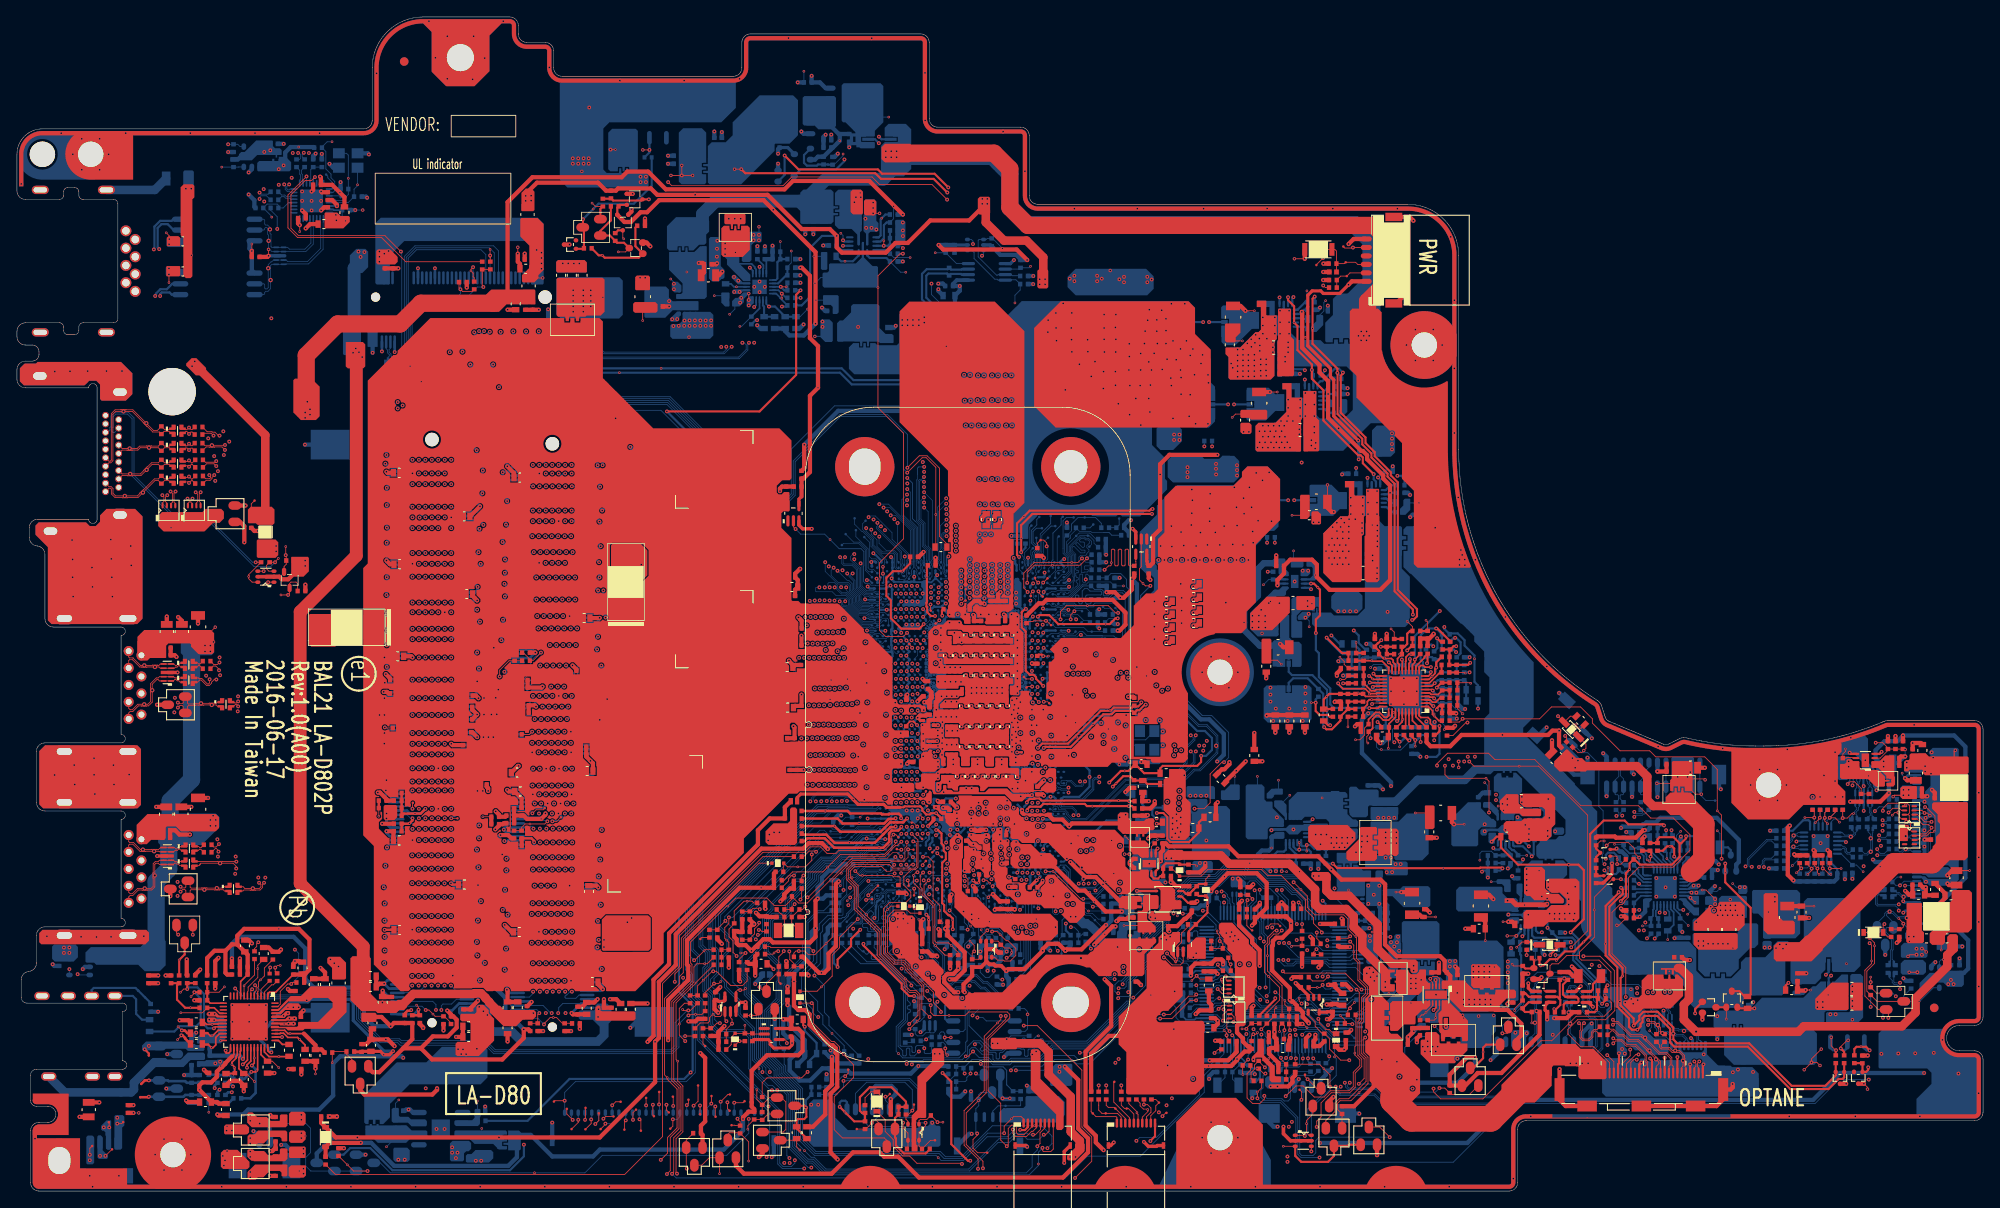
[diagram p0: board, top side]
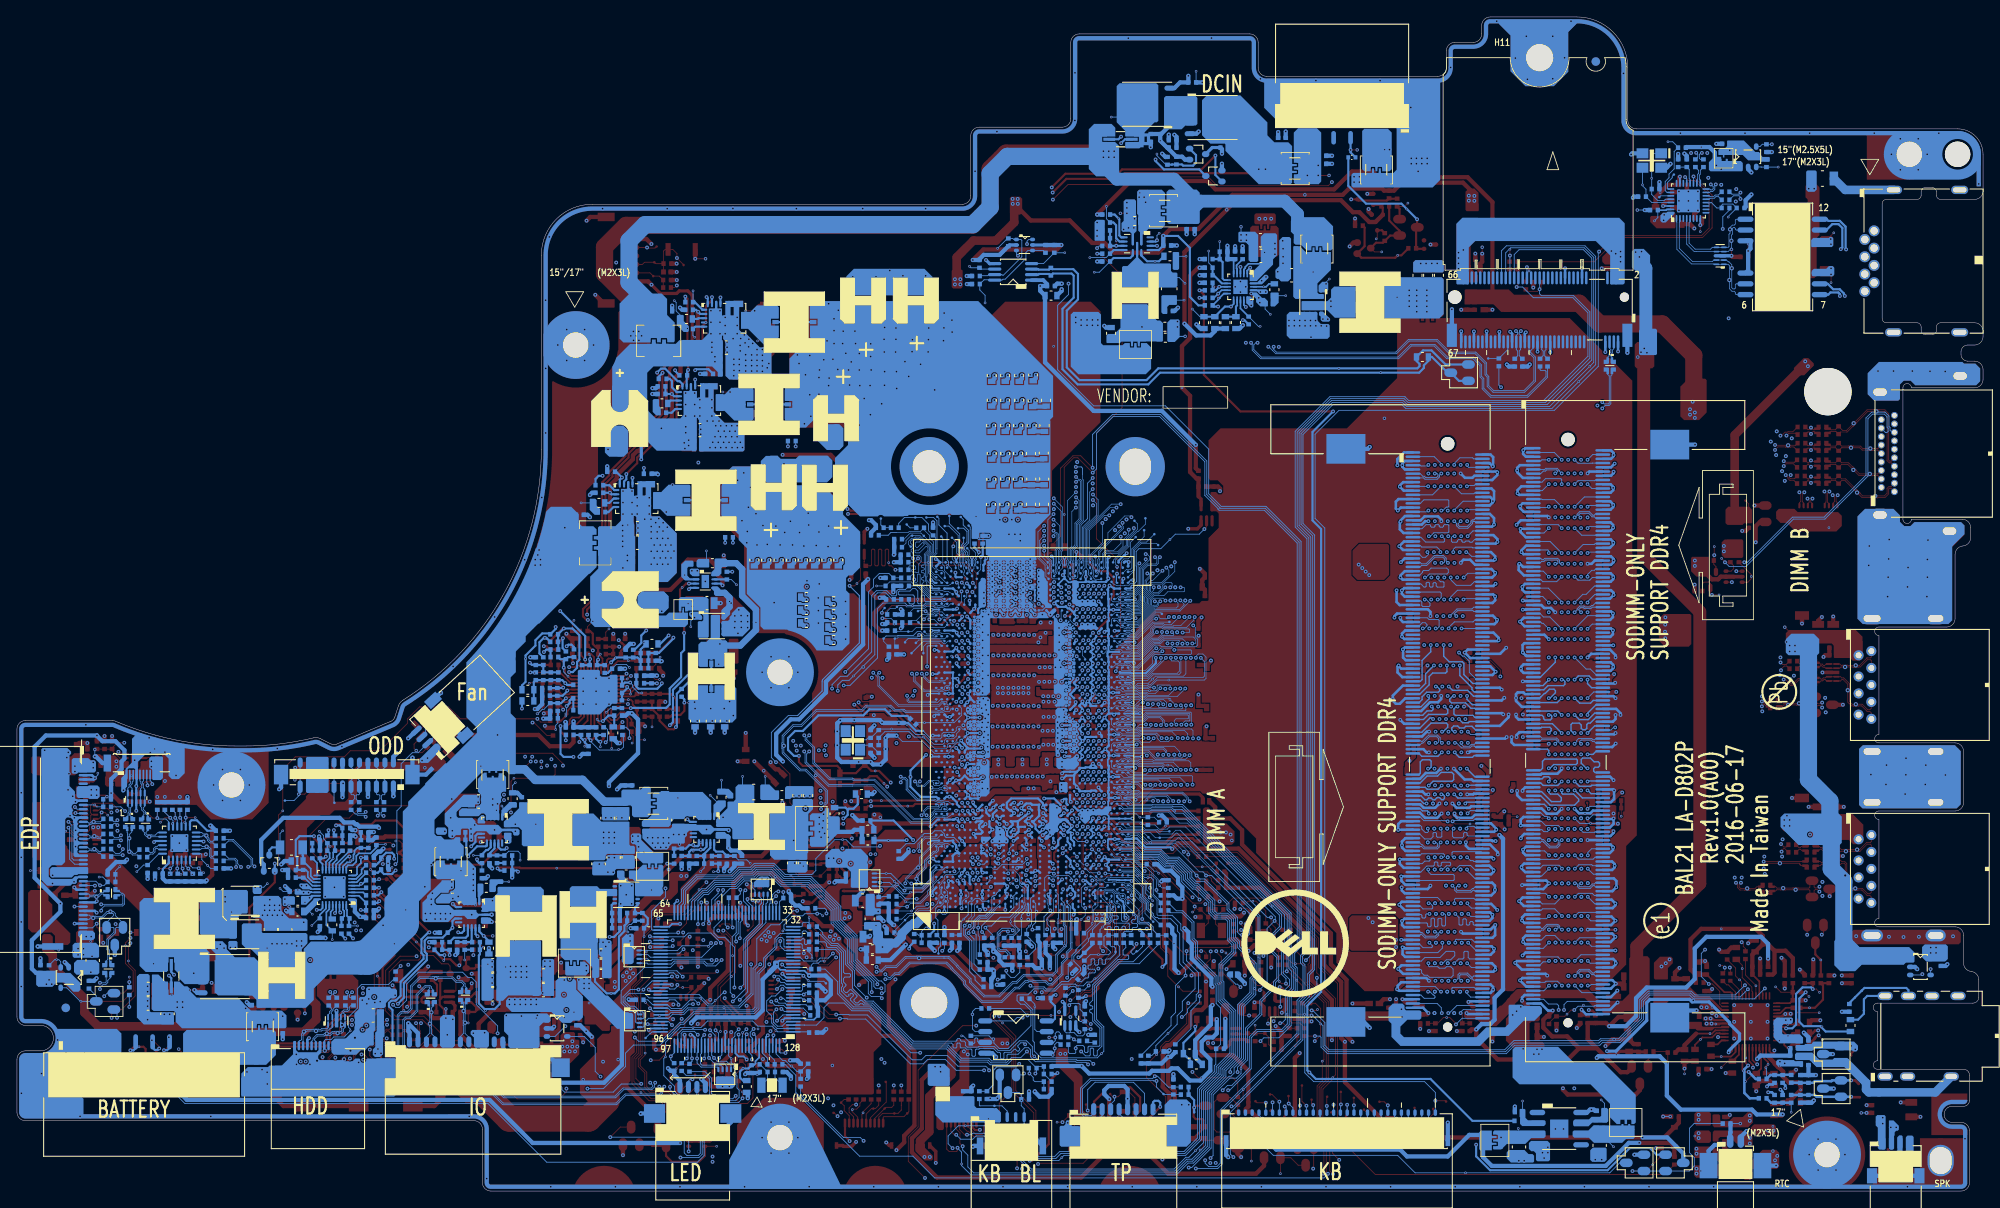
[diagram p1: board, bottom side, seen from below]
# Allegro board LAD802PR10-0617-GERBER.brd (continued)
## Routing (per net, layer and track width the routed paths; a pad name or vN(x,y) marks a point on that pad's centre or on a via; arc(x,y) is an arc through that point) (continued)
SIO_SLP_SUS#: length 1.4
  TOP w0.076: TP75.1 106.2,42.11 v2(106.2,42.12)
  BOTTOM w0.076: UC1.AN15 106.56,41.76 v2(106.2,42.12)
SIO_SLP_WLAN#: length 5.2
  BOTTOM w0.076: TP11.1 97.18,42.44 97.4,42.66 98.82,42.66 99.15,43 100.57,43 UC1.BB17
SLEEVE: length 1.6
  BOTTOM w1.016: 24.09,18.18 24.09,18.24 24.19,18.35 24.19,19.72
  vias: v1(24.02,17.73) v2(22.68,20.21) v2(23.26,20.16)
SLEEVE_R: length 19.2
  TOP w0.254: v2(15.07,16.72) 15.55,16.24 ZT18.1
  IN1 w1.016: JHP1.3 2.95,23.28 3.82,24.15 13.94,24.15 15.24,22.85 15.24,18.05
  vias: v2(15.56,17.12)
SM_RCOMP0: length 13.9
  TOP w0.305: v2(104.99,43.96) 104.52,43.49 103.84,43.49 103.83,43.49 103.43,43.49 103.43,43.49 102.98,43.49 101.88,42.39 97.1,42.39 v1(96.44,43.04) 96.43,43.05 RC10.1
  BOTTOM w0.254: v2(104.99,43.96) 105.09,43.86 105.09,43.68 UC1.AR18
SM_RCOMP1: length 12.9
  TOP w0.305: v2(104.28,43.98) 104.28,44.25 104.02,44.51 102.91,44.51 102.84,44.43 102.04,44.43 101.93,44.54 98.27,44.54 97.98,44.83 v1(95.33,44.83) 95.33,44.84 RC11.1
  BOTTOM w0.254: UC1.AT18 104.61,43.65 104.28,43.98 v2(104.28,43.98)
SM_RCOMP2: length 12.2
  TOP w0.305: RC12.1 96.8,43.94 97.38,43.36 v1(99.33,43.36) 102.29,43.36 102.82,43.88 102.99,43.88 103.01,43.9 103.55,43.9 v2(103.64,43.98)
  BOTTOM w0.254: v2(103.64,43.98) 103.64,43.83 UC1.AU18
SMBCLK: length 19.9
  TOP w0.102: v2(115.02,30.61) 115.6,30.61 v1(115.97,30.24) 116.68,29.53 116.91,29.53 117.81,28.63 117.81,27.78 117.16,27.13 116.46,27.13 116.35,27.23 115.67,27.23 115.33,27.58 QC1.6
  IN2 w0.127: v2(115.02,30.61) 114.89,30.74 114.89,30.9 114.69,31.1 114.69,36.52 v2(114.95,36.78)
  BOTTOM w0.102: v2(114.95,36.78) 115.08,36.91 UC1.R7 ; RC29.1 114.76,27.83 114.76,28.02 115.21,28.47 115.9,28.47 116.09,28.65 116.09,30.32 115.65,30.75 115.15,30.75 v2(115.02,30.61)
SMBDATA: length 15.3
  TOP w0.102: v2(114.45,30.75) 113.67,29.97 QC1.3
  IN2 w0.127: v2(114.45,30.75) 114.4,30.8 114.4,36.91 v2(114.98,37.48)
  BOTTOM w0.102: v2(114.98,37.48) 115.41,37.48 UC1.R8 ; RC30.1 115.27,27.58 115.02,27.83 115.02,27.96 115.34,28.28 115.98,28.28 116.28,28.57 116.28,30.45 115.73,31 114.69,31 v2(114.45,30.75)
SML0_SMBCLK: length 10.3
  BOTTOM w0.076: UC1.R9 115.15,37.87 114.29,37.87 113.87,37.45 113.64,37.13 113.64,36.15 113.38,35.89 113.28,35.89 113.02,35.64 113.02,34.04 113.01,34 112.87,33.55 112.87,33.27
  BOTTOM w0.102: RC33.1 113.43,30.14 v1(113.43,32.15) 113.43,32.54 112.87,33.1 112.87,33.27
SML0_SMBDATA: length 5.4
  BOTTOM w0.076: 113.07,33.38 113.07,33.6 113.2,34.05 UC1.W2
  BOTTOM w0.102: RC34.1 114.56,29.87 113.74,30.69 v1(113.74,30.82) 113.74,30.87 114.19,31.32 114.19,32.25 113.07,33.38
SML1CLK: length 287.9
  TOP w0.102: v2(135.28,20.82) 136.03,20.82 138.2,22.99 138.91,22.99 v2(139.1,23.18)
  IN1 w0.127: v2(113.83,110.33) 113.53,110.63 113.53,110.85 113.8,111.12 148.3,111.12 154.03,105.39 154.5,105.39 155.23,104.66 155.23,98.84 158.07,95.99 158.07,89.26 160.87,86.46 162.84,86.46 163.79,85.51 163.79,83.07 163.39,82.68 163.39,78.8 164.12,78.07 164.12,70.81 167.49,67.44 168.08,67.44 170.83,64.69 170.83,64.07 171.83,63.07 171.83,61.08 168.8,58.05 168.8,55.6 168.61,55.41 168.61,54.42 169.08,53.95 172.94,53.95 172.94,53.96 173.29,53.96 181.38,45.87 182.04,45.87 185.8,42.11 185.8,40.42 186.2,40.02 186.2,34.27 187.73,32.74 187.73,31.7 188.68,30.75 v2(191.31,30.75)
  IN2 w0.127: v2(117.24,14.24) 117.24,14.37 117.31,14.44 117.31,26.88 117.43,27 117.43,27.97 117.64,28.18 117.64,31.03 v2(117.67,31.07) ; v2(139.1,23.18) 139.75,22.53 139.87,22.41 139.87,21.79 140.02,21.63 140.02,19.65 141.02,18.66 141.76,18.66 143.15,17.28 146.93,17.28 149.16,15.05 153.7,15.05 154.07,15.42 156.37,15.42 157.23,14.56 159.22,14.56 162.74,11.04 172.44,11.04 175.23,13.84 198.84,13.84 199.56,14.55 199.56,16.62 196.6,19.58 196.6,25.21 195.51,26.31 191.66,26.31 190.56,27.42 190.56,29.56 191.35,30.35 191.35,30.71 v2(191.31,30.75)
  BOTTOM w0.102: v2(117.24,14.24) 117.24,14.34 117.63,14.72 120.91,14.72 122.18,15.99 124.69,15.99 125.2,15.49 126.31,15.49 131.6,20.77 133.74,20.77 133.79,20.82 v2(135.28,20.82) ; UC1.W3 113.69,34.49 113.69,33.41 114.79,32.3 115.93,32.3 116.97,31.26 117.48,31.26 v2(117.67,31.07) 116.86,30.26 RC31.1 ; Q11.3 114.01,110.51 v2(113.83,110.33) ; UE1.12 v2(139.1,23.18) 138.89,23.39 RE11.1
SML1DATA: length 289
  TOP w0.102: v2(134.83,20.34) 136.23,20.34 138.39,22.5 v2(139.07,22.5)
  IN1 w0.127: v2(191.89,30.75) 191.89,30.89 191.52,31.26 188.89,31.26 188.23,31.92 188.23,32.95 186.71,34.48 186.71,40.23 186.3,40.63 186.3,42.32 182.25,46.37 181.59,46.37 173.5,54.46 172.73,54.46 172.73,54.46 169.29,54.46 169.12,54.63 169.12,55.2 169.31,55.39 169.31,57.84 172.33,60.87 172.33,63.28 171.33,64.28 171.33,64.9 168.29,67.95 167.7,67.95 164.63,71.02 164.63,78.28 163.9,79.01 163.9,82.47 164.29,82.86 164.29,85.72 163.05,86.96 161.08,86.96 158.58,89.47 158.58,96.2 155.73,99.05 155.73,104.87 154.71,105.9 154.24,105.9 148.51,111.63 113.59,111.63 113.26,111.3 113.22,111.3 113.2,111.28 112.98,111.28 112.76,111.49 v2(112.76,111.71)
  IN2 w0.127: v2(118.07,30.56) 118.15,30.48 118.15,26.9 117.82,26.57 117.82,14.56 117.83,14.56 v2(117.83,14.24) ; v2(191.89,30.75) 191.85,30.71 191.85,30.14 191.07,29.35 191.07,27.63 191.87,26.82 195.72,26.82 197.11,25.43 197.11,19.79 200.07,16.83 200.07,14.34 199.05,13.33 175.44,13.33 172.65,10.53 162.53,10.53 159.01,14.05 157.02,14.05 156.16,14.92 154.28,14.92 153.91,14.55 148.95,14.55 146.72,16.77 142.94,16.77 141.55,18.15 140.8,18.15 139.52,19.44 139.52,21.42 139.36,21.58 139.36,22.2 139.07,22.49 v2(139.07,22.5)
  BOTTOM w0.102: RE10.1 v2(139.07,22.5) 139.35,22.78 UE1.11 ; UC1.V3 114.32,34.84 114.32,33.45 114.99,32.78 116.61,32.78 118.14,31.25 118.14,30.64 v2(118.07,30.56) 117.81,30.31 RC32.1 ; v2(117.83,14.24) 121.11,14.24 122.38,15.51 124.49,15.51 125,15 126.51,15 131.8,20.29 133.94,20.29 133.99,20.34 v2(134.83,20.34) ; v2(112.76,111.71) 112.76,112.05 112.57,112.25 Q11.6
SNUB_+1VALW: length 1.8
  BOTTOM w0.102: PR307.2 v1(143.64,48.91)
SOC_XDP_TDI: length 4.4
  TOP w0.102: TPC5.1 121.46,67.26 v2(121.37,67.26) 119.92,67.26 119.84,67.19 119.28,67.19 RC141.1
  BOTTOM w0.076: UC1.D59 121.85,67.12 UC1.D60 121.46,67.36 v2(121.37,67.26)
SOC_XDP_TDO: length 9.9
  IN1 w0.119: v2(124.92,67.44) 124.92,66.17 v2(125.49,65.61)
  BOTTOM w0.076: RC142.1 128.35,64.41 TPC1.1 128.29,65.23 128.04,65.23 127.91,65.36 125.73,65.36 v2(125.49,65.61) 125.3,65.61 125.05,65.36 123.56,65.36 UC1.A56 ; v2(124.92,67.44) 124.53,67.84 123.56,67.84 UC1.A61
SOC_XDP_TMS: length 7.2
  BOTTOM w0.076: UC1.C59 122.47,66.5 125.82,66.5 126.32,65.99 TPC4.1 128.22,65.99 RC140.1
  BOTTOM w0.089: UC1.C59 122.17,67.03 UC1.C60
SOC_XDP_TRST#: length 6.7
  TOP w0.102: v2(124.72,68.4) 124.29,67.96 v2(124.29,67.44)
  BOTTOM w0.076: UC1.C61 122.38,67.92 122.77,68.32 123.24,68.32 123.3,68.34 123.33,68.35 123.7,68.35 123.87,68.18 124.51,68.18 v2(124.72,68.4) 124.8,68.47 125.56,68.47 TPC6.1 ; v2(124.29,67.44) 123.71,67.44 123.3,67.03 123.07,66.79 UC1.B59
SPKR: length 126.5
  TOP w0.102: v2(19.02,30.24) 18.82,30.45 DA3.3
  IN1 w0.127: v2(19.02,30.24) 19.45,30.24 19.58,30.12 19.58,29.52 19.96,29.14 26.74,29.14 27.4,29.8 38.63,29.8 44.03,24.4 44.03,22.69 46.95,19.77 46.95,16.99 48.41,15.53 48.41,12.31 v2(48.22,12.12)
  IN2 w0.127: v2(108.03,25.16) 106.51,23.64 106.51,21.35 106.08,20.92 106.08,18.32 102.26,14.5 97.92,14.5 96.05,12.62 82.78,12.62 81.23,11.07 51.3,11.07 49.84,12.54 48.64,12.54 v2(48.22,12.12)
  BOTTOM w0.076: 106.47,29.02 105.67,29.82 105.67,30.44 104.73,31.38 104.73,31.79 104.91,31.97 104.91,33.16 104.4,33.67 104.4,35.62 104.23,35.78 103.54,35.78 UC1.AW5
  BOTTOM w0.102: v2(108.03,25.16) 107.9,25.29 107.9,26.51 RC128.2 107.47,26.95 107.47,27.8 106.99,28.28 106.99,28.38 106.98,28.39 106.98,28.51 106.47,29.02
SRTCRST#: length 30.3
  TOP w0.102: v2(91.1,28.27) 91.15,28.21 91.15,27.33 91.65,26.83 RC77.1 CC4.1
  IN2 w0.127: v2(91.1,28.27) 91.48,27.89 92.61,27.89 93.7,28.97 93.89,28.97 97.64,32.72 98.47,32.72 99.59,33.84 99.59,33.89 99.74,34.03 99.74,35.15 100.23,35.64 100.83,35.64 101.2,36 102.18,36.99 102.18,39.68 103.26,40.76 106.83,40.76 107.89,41.83 107.89,42.43 107.71,42.6 107.25,42.6 106.85,43 v2(106.85,43.05)
  BOTTOM w0.102: v2(106.85,43.05) UC1.AN18
SUS_STAT#/LPCPD#: length 7.4
  BOTTOM w0.076: UC1.BA11 101.44,39.66 101.13,39.35 101.02,39.35 100.95,39.27 100.19,39.27 99.07,38.16 98.67,38.16 97.3,36.78 97.3,36.21 v1(97.11,36.02) 96.85,35.76 96.67,35.76
  BOTTOM w0.102: RC35.1 96.67,35.76
SUSCLK: length 29.3
  TOP w0.102: v2(83.97,32.28) 83.97,32.28 83.97,31.56 83.48,31.08 83.48,29.81 v1(83.7,29.6) 83.97,29.33 RC110.1 83.09,28.47 RC74.2 RC75.2 RC189.2
  BOTTOM w0.076: UC1.BA17 101.05,42.83 99.22,42.83 98.89,42.5 97.56,42.5 97.17,42.12 95.65,42.12 95.21,42.56 94.71,42.56
  BOTTOM w0.102: v2(83.97,32.28) 84.43,32.28 94.71,42.56
SUSCLK_EC: length 100.3
  TOP w0.102: RC75.1 81.41,26.82 v1(81.11,26.82) 80.22,26.82 79.84,26.44 79.84,24.63 79.6,24.39 77.46,22.25 77.46,13.12 78.32,12.27 78.32,7.13 77.47,6.28 77.47,2.23 v2(77.27,2.04)
  BOTTOM w0.102: v2(77.27,2.04) 77.75,1.55 123.66,1.55 126.22,4.11 132.51,4.11 140.04,11.64 140.04,13.67 141.31,14.95 RE45.2
SUSCLK_SSD: length 146.2
  TOP w0.102: v2(77.85,2.05) 77.74,2.16 77.74,6.19 78.54,6.99 78.54,12.39 77.93,13 v1(77.93,15.32) 77.74,15.51 77.74,22.21 79.37,23.83 80.07,24.53 80.07,24.58 RC189.1 ; v2(187.57,16.03) 188.35,15.26 JSSD1.22
  IN1 w0.127: v2(77.85,2.05) 78.31,1.59 123.89,1.59 124.52,2.22 125.22,2.22 125.59,1.84 154.24,1.84 162.83,10.43 164.02,10.43 166.86,13.27 170.08,13.27 173.34,16.54 187.07,16.54 v2(187.57,16.03)
SUSCLK_WLAN: length 128.9
  TOP w0.102: v2(79.87,27.23) 79.93,27.23 v1(81.05,28.34) 81.17,28.47 RC74.1
  BOTTOM w0.102: v2(79.87,27.23) 79.3,27.8 79.3,77.15 80.67,78.52 80.67,89.43 76.85,93.25 68.38,93.25 67.91,92.78 51.4,92.78 46.15,98.03 46.15,110.06 47.14,111.05 54.73,111.05 55.3,110.47 JWLAN1.42
SW_VCCEOPIO: length 2.1
  BOTTOM w0.102: PR1208.1 94.81,107.76 v1(94.13,107.08)
SYS_PWROK: length 53.2
  TOP w0.102: v2(131.21,39.74) v4(130.64,39.74)
  IN1 w0.127: v2(123.13,33.04) 123.13,33.68 123.74,34.29 123.95,34.29 124.92,35.26 126.81,35.26 127.04,35.03 127.38,35.03 127.63,35.28 127.63,37.39 129.09,38.84 129.1,38.84 129.14,38.88 130.35,38.88 v2(131.21,39.74)
  IN2 w0.127: v2(152.17,22.05) 152.17,22.08 151.7,22.54 151.68,22.54 151.67,22.55 151.16,22.55 149.81,23.89 148.61,23.89 147.97,24.53 145.84,24.53 143.81,26.56 143.81,26.92 143.34,27.39 142.38,27.39 138.77,31 138.77,32.79 136.94,34.62 135.1,34.62 133.78,35.94 133.78,37.12 132.5,38.39 132.5,39.18 131.94,39.74 v2(131.21,39.74)
  BOTTOM w0.076: v2(123.13,33.04) 122.72,32.63 122.36,32.63 122.14,32.84 122.14,33.4 122.15,33.41 122.15,33.96 122.07,34.05 122.07,34.29 122.13,34.36 122.13,35.32 122.5,35.69 UC1.B6
  BOTTOM w0.102: v2(152.17,22.05) 152.67,22.05 153.42,21.3 154.81,21.3 155.09,21.58 UE1.89
SYS_RESET#: length 9
  BOTTOM w0.076: RC86.2 122.96,29.75 122.96,29.15
  BOTTOM w0.102: 122.96,29.15 122.96,28.91 123.21,28.66 TPS1.1 ; RC86.2 123.27,30.32 123.27,31.96 123.53,32.21 123.53,33.37 123.28,33.61 122.95,33.61 122.66,33.9 122.66,34.3 122.54,34.42 122.54,34.78 122.71,34.96 122.72,34.96 122.83,35.07 UC1.B5
SYSPWR_PRES: length 4.6
  TOP w0.102: v1(144.49,19.12) v2(145.01,19.12) 145.01,19.21 145.57,19.77 RE32.1 RE29.1
  BOTTOM w0.102: v2(145.01,19.12) 145.41,18.72 145.41,18.28 145.16,18.03 UE1.120
T_CRIT#: length 4.4
  BOTTOM w0.102: U2.4 110.82,109.41 R29.2 v1(108.31,110.69)
THM_SML1_CLK: length 12.4
  BOTTOM w0.102: v1(117.71,104.77) 117.71,105.67 118.33,106.29 C24.1 117.83,107.5 117.28,107.5 117.24,107.46 U2.8 115.72,107.46 115.61,107.56 115.34,107.56 112.9,110.01 112.9,110.71 112.66,110.95 Q11.4 110.85,110.95 R49.2
THM_SML1_DATA: length 11.3
  BOTTOM w0.102: v1(116.24,111.21) 115.07,112.37 R48.2 114.44,112.37 114.32,112.25 Q11.1 113.48,112.25 113.38,112.15 113.38,110.21 115.54,108.05 115.68,108.05 115.74,108.11 U2.7 117.26,108.11 117.38,107.98 118.3,107.98 C25.1
TON_1.2V: length 2.6
  TOP w0.102: v2(90.22,105.86) v1(90.22,105.33)
  BOTTOM w0.203: PR208.2 90.71,105.36 v2(90.22,105.86) 89.81,106.27 PU200.9
TOUCH_SCREEN_PD#: length 124.4
  TOP w0.102: R19.2 220.64,29.98 D5.2 220.12,31.35 v2(220.26,31.49)
  IN1 w0.127: v2(174.45,46.12) 174.9,46.56 174.9,47.07 172.68,49.29 172.68,51.49 172.01,52.16 168.75,52.16 167.71,51.11 167.54,51.11 167.11,51.11 166.06,50.06 161.04,50.06 158.18,47.2 158.18,41.35 157.44,40.6 157.44,38.27 155.57,36.4 151.38,36.4 150.52,37.26 147.71,37.26 146.66,38.31 142.66,38.31 142.57,38.21 138.12,38.21 136.76,36.85 135,36.85 134.29,36.14 131.47,36.14 130.83,35.5 v2(129.95,35.5)
  IN2 w0.127: v2(220.26,31.49) 218.86,32.9 218.86,38.18 217.21,39.84 214.34,39.84 214.02,39.52 210.79,39.52 209.91,40.4 201.09,40.4 197.42,44.07 192.37,44.07 191.52,43.22 190.16,43.22 189.81,43.58 184.77,43.58 180.63,47.72 178.02,47.72 177.06,46.75 175.09,46.75 v2(174.45,46.12)
  BOTTOM w0.102: RC118.1 129.81,34.75 129.88,34.69 RC115.2 130.26,35.2 v2(129.95,35.5)
TOUCH_SCREEN_PD#_R: length 6.8
  BOTTOM w0.076: RC118.2 127.72,34.75 v1(127.08,34.12) 127.05,34.08 125.38,34.08 124.48,34.99 124.48,35.39 123.95,35.92 123.95,36.22 123.48,36.7 UC1.A7
TOUCHPAD_INTR#: length 85
  TOP w0.102: Q9.1 102.6,5.98 102.31,6.27 97.37,6.27 96.4,7.23 96.4,11.12 98.69,13.41 98.69,14.89 v1(97.49,16.08) 97.01,16.57 97.01,17.02 96.4,17.63 96.08,17.63 93.92,19.79 93.92,21.99 v2(93.75,22.17) DZ3.1
  IN1 w0.127: v2(141.51,35.27) 141.04,34.81 140.56,34.81 139.46,33.71 137.72,33.71 136.84,32.82 136.84,32.57 136.59,32.33 135.01,32.33 134.44,31.76 134.29,31.76 131.05,28.51 129.54,28.51 127.29,26.27 119.83,26.27 119.24,26.85 116.58,26.85 115.63,25.9 115.63,25.82 115.38,25.57 109.07,25.57 108.19,24.69 108.04,24.69 107.64,24.28 107.08,24.28 106.63,23.83 104.58,23.83 102.72,25.69 98.02,25.69 94.5,22.17 v2(93.75,22.17)
  BOTTOM w0.102: v2(141.51,35.27) RE14.1 141.96,34.12 UE1.33
TOUCHPAD_INTR#_D: length 25.3
  TOP w0.102: v2(99.18,32.09) 97.03,29.94 97.03,28.71 96.16,27.84 96.16,25.35 v1(94.89,24.08) 94.37,23.57 DZ3.2 92.35,23.05 v2(92.4,22.99)
  BOTTOM w0.076: v2(99.18,32.09) 99.18,34 99.95,34.78 99.95,35.03 100.66,35.74 100.93,35.74 101.32,36.13 UC1.BA5
  BOTTOM w0.102: RC114.2 93.43,19.14 93.43,21.29 92.4,22.32 v2(92.4,22.99)
TP_EN: length 4.5
  TOP w0.102: v1(221.95,32.15) 222.5,31.6 v2(222.5,31.54) 222.5,31.16 222.24,30.9 C16.1 R19.1
  BOTTOM w0.102: v2(222.5,31.54) 222.99,31.05 JEDP1.39
TP_LOCK#: length 6.1
  TOP w0.102: R41.2 100.03,11 100.74,11.71 D6.2 102.01,11.13 v2(102.45,11.13) 102.64,11.13 ZT11.1
  BOTTOM w0.102: JTP1.3 102.9,10.23 102.45,10.69 v2(102.45,11.13)
TP_ON#_GATE: length 12.4
  TOP w0.102: R38.2 88.75,11.02 Q12.2 90.17,11.02 90.69,10.51 90.69,7.27 90.37,6.96 Q13.2 ; R38.2 87.9,10.18 87.27,10.81 v1(87.27,11.96) ; R38.2 C18.2
TP_PW_EN#: length 75
  TOP w0.102: v2(93.25,14.05) 92.55,13.35 v1(92.22,13.35) 88.48,13.35 87.9,12.78 R38.1
  IN1 w0.127: v2(93.25,14.05) 93.47,14.27 106.47,14.27 107.37,15.17 112.79,15.17 114.1,16.48 118.43,16.48 119.47,15.44 120.77,15.44 121.81,16.48 124.51,16.48 125.09,15.9 125.54,15.9 126.13,16.48 128.39,16.48 132.35,20.44 132.35,21.37 133.75,22.77 133.75,24.58 138.42,29.25 139.9,29.25 142.12,31.48 143.65,31.48 144.5,30.63 146.13,30.63 146.26,30.75 147.22,30.75 147.3,30.67 147.65,30.67 147.9,30.92 147.9,30.93 v2(148.06,31.09)
  BOTTOM w0.102: UE1.49 148.36,31.39 v2(148.06,31.09)
UG_1.2V: length 6.3
  IN2 w0.762: 83.75,106.37 78.23,106.37
  BOTTOM w0.102: v1(77.11,107.59) 77.49,107.21 v2(77.49,107.02)
  vias: v2(77.49,106.38) v2(84.6,106.06) v2(85.24,106.06)
UGATE_CHG: length 0.8
  TOP w0.102: v2(197.39,34.59) v1(197.93,34.05)
USB2_ID: length 5.4
  BOTTOM w0.076: 110,31.13 110.38,31.51 v1(110.38,31.96) 110.38,32.2 109.63,32.95 109.63,34.44 109.36,34.71 UC1.AG3
  BOTTOM w0.102: 110,31.13 110,30.51 RC67.1
USB2_VBUSSENSE: length 5.6
  BOTTOM w0.076: 109.05,32.58 109.05,34.93 109.36,35.24 UC1.AG4
  BOTTOM w0.089: 109.05,32.58 109.05,32.18
  BOTTOM w0.102: RC68.1 109.11,30.51 v1(109.11,31.64) 109.11,32.11 109.05,32.18
USB3_CM_P0: length 4.2
  TOP w0.102: RX17.2 211.99,44.77 v2(211.99,44.05) v1(210.88,44.05)
  BOTTOM w0.102: UX2.14 v2(211.99,44.05) 211.99,44.77 RX17.2
USB3_CRX_C_RD_DTX_N3: length 3
  BOTTOM w0.097: UX2.11 210.1,41.79 209.98,41.91 209.84,41.91 209.44,41.52 209.44,41.36 209.16,41.07 208.78,41.07 CX6.2
USB3_CRX_C_RD_DTX_P3: length 3
  BOTTOM w0.097: CX7.2 208.8,41.26 209.08,41.26 209.26,41.43 209.26,41.64 v3(209.56,41.94) 209.74,42.12 209.92,42.12 210.1,42.29 UX2.12
USB3_CRX_DTX_N1: length 170.2
  TOP w0.097: RU5.2 20.73,59.87 LU3.3 21.3,60.04 21.55,60.28 21.72,60.28 22.38,59.63 22.67,59.63 22.94,59.9 22.94,60.02 23.27,60.34 v2(23.52,60.34)
  IN2 w0.089: 118.34,35.46 118.01,35.8 118.01,36.16 117.9,36.27 117.9,36.67 117.9,36.67 117.9,36.94 118.24,37.28 118.44,37.28 118.6,37.44 v2(118.6,37.55)
  IN2 w0.122: v2(23.52,60.34) 23.29,60.34 22.97,60.03 22.97,51.02 27.13,46.86 27.13,34.98 28.36,33.76 35.32,33.76 41.18,27.9 41.18,19.52 42.47,18.22 42.47,16.73 47.5,11.7 50.07,11.7 52.57,9.2 82.72,9.2 83.84,8.09 100.21,8.09 101.12,7.18 108.88,7.18 112.61,10.91 112.88,10.91 114.34,12.37 117.16,12.37 118.96,14.18 118.96,16.76 119.22,17.02 119.22,24.23 119.65,24.66 119.65,28.89 121.14,30.39 121.14,33.49 120.44,34.19 119.62,34.19 118.34,35.46
  BOTTOM w0.076: v2(118.6,37.55) 118.8,37.76 UC1.H8
USB3_CRX_DTX_N1_C: length 10.6
  TOP w0.097: JUSB1.5 13.18,56.4 13.35,56.57 13.65,56.57 13.66,56.59 13.68,56.59 14.32,57.23 14.68,57.23 14.71,57.2 15.3,57.2 15.33,57.23 15.51,57.23 15.96,57.67 v3(15.96,59.07) 15.96,59.79 16.51,60.34 16.64,60.34 16.81,60.17 EU2601.9 EU2601.1 18.45,60.17 18.62,60.34 18.76,60.34 18.9,60.19 19.09,60.19 19.25,60.04 LU3.4 19.82,59.87 RU5.1
USB3_CRX_DTX_N2: length 152.8
  TOP w0.097: RU11.2 20.8,38.21 LU6.3 21.47,38.38 21.57,38.49 21.58,38.49 21.6,38.5 21.6,38.58 21.69,38.67 v3(23.96,38.67) 25.49,38.67 25.86,38.3 v2(25.86,38.05)
  IN2 w0.122: v2(25.86,38.05) 25.86,38.28 25.53,38.61 25.19,38.61 24.91,38.33 24.91,35.84 27.66,33.08 35.04,33.08 40.5,27.62 40.5,19.24 41.8,17.94 41.8,16.45 47.3,10.95 49.86,10.95 52.42,8.39 62.22,8.39 63.2,7.41 99.93,7.41 100.84,6.5 109.16,6.5 112.89,10.23 113.16,10.23 114.62,11.7 117.44,11.7 120.63,14.89 120.63,17.4 119.9,18.13 119.9,23.95 120.32,24.38 120.32,28.61 121.81,30.11 121.81,34.82 120.99,35.64 119.19,35.64 118.83,36 118.83,36.35 v2(118.49,36.69)
  BOTTOM w0.097: UC1.J6 118.39,37.11 118.49,37.01 v2(118.49,36.69)
USB3_CRX_DTX_N2_C: length 11
  TOP w0.097: RU11.1 19.88,38.21 LU6.4 19.21,38.38 19.03,38.56 18.87,38.56 18.74,38.69 18.63,38.69 18.45,38.52 EU2603.1 EU2603.9 16.81,38.52 16.66,38.67 16.38,38.67 16.26,38.54 v3(16.26,37.23) 16.26,35.88 15.9,35.51 15.39,35.51 15.36,35.48 14.78,35.48 14.75,35.51 14.31,35.51 13.67,34.87 13.35,34.87 13.18,34.7 JUSB2.5
USB3_CRX_DTX_N3: length 164.1
  IN2 w0.122: v2(118.57,39.36) 118.99,39.78 119.23,39.78 119.35,39.89 121.16,39.89 124.09,36.97 127.4,36.97 128.02,36.35 128.02,30.87 134.23,24.66 134.23,16.68 137.03,13.88 137.03,13.4 139.51,10.93 144.14,10.93 144.86,10.22 148.06,10.22 148.18,10.34 151.29,10.34 151.76,9.87 155.6,9.87 155.69,9.79 158.61,9.79 159.07,9.33 173.17,9.33 175.99,12.15 212,12.15 216.15,16.29 217.8,17.95 217.8,36.24 216.68,37.36 208.74,37.36 208.45,37.65 207.02,39.08 204.48,39.08 204.31,38.91 204.31,38.37 204.44,38.25 v2(204.62,38.25)
  BOTTOM w0.076: UC1.J10 118.38,38.94 118.57,39.13 v2(118.57,39.36)
  BOTTOM w0.097: v2(204.62,38.25) 204.39,38.25 204.29,38.34 204.29,39.12 206.46,41.3 206.96,41.3 CX6.1
USB3_CRX_DTX_P1: length 170.2
  TOP w0.097: v2(22.72,60.37) 22.72,59.94 22.59,59.81 22.46,59.81 21.8,60.47 21.47,60.47 21.4,60.54 LU3.2 20.73,60.7 RU6.2
  IN2 w0.089: v2(119.18,37.55) 118.7,37.07 118.33,37.07 118.11,36.85 118.11,36.76 118.11,36.36 118.22,36.25 118.22,35.89 118.42,35.69 118.44,35.69 118.49,35.64 118.51,35.64 118.52,35.63
  IN2 w0.122: 118.52,35.63 119.72,34.44 120.54,34.44 121.39,33.59 121.39,30.28 119.9,28.79 119.9,24.55 119.47,24.13 119.47,16.92 119.21,16.65 119.21,14.07 117.26,12.12 114.45,12.12 112.98,10.66 112.71,10.66 108.98,6.93 101.02,6.93 100.11,7.84 83.73,7.84 82.62,8.95 52.47,8.95 49.96,11.45 47.4,11.45 42.23,16.63 42.23,18.12 40.93,19.41 40.93,27.8 35.22,33.51 28.25,33.51 26.88,34.88 26.88,46.75 22.72,50.91 v2(22.72,60.37)
  BOTTOM w0.076: v2(119.18,37.55) 119.18,37.76 UC1.G8
USB3_CRX_DTX_P1_C: length 10.6
  TOP w0.097: RU6.1 19.82,60.7 LU3.1 19.26,60.54 19.11,60.38 18.98,60.38 18.83,60.53 18.63,60.53 18.48,60.67 EU2601.2 EU2601.8 16.81,60.67 16.66,60.53 16.43,60.53 15.77,59.87 15.77,59.4 15.74,59.36 15.74,58.78 15.77,58.75 15.77,57.75 15.44,57.42 v3(15.01,57.42) 14.24,57.42 13.6,56.78 13.35,56.78 13.18,56.95 JUSB1.6
USB3_CRX_DTX_P2: length 152.9
  TOP w0.097: v2(25.88,38.86) 24.28,38.86 24.25,38.89 23.67,38.89 23.64,38.86 21.49,38.86 21.47,38.88 LU6.2 20.8,39.05 RU12.2
  IN2 w0.122: v2(25.88,38.86) 25.08,38.86 24.66,38.44 24.66,35.73 27.56,32.83 34.94,32.83 40.25,27.52 40.25,19.13 41.55,17.84 41.55,16.35 47.19,10.7 49.76,10.7 52.32,8.14 62.12,8.14 63.1,7.16 99.83,7.16 100.74,6.25 109.26,6.25 112.99,9.99 113.26,9.99 114.72,11.45 117.54,11.45 120.88,14.78 120.88,17.5 120.15,18.23 120.15,23.85 120.57,24.27 120.57,28.51 122.06,30 122.06,34.92 121.09,35.89 119.29,35.89 119.08,36.1 v2(119.08,36.71)
  BOTTOM w0.097: v2(119.08,36.71) 118.8,36.99 UC1.H6
USB3_CRX_DTX_P2_C: length 11
  TOP w0.097: JUSB2.6 13.18,35.25 13.35,35.08 13.61,35.08 14.23,35.7 v3(15.07,35.7) 15.82,35.7 16.07,35.95 16.07,36.91 16.04,36.94 16.04,37.52 16.07,37.55 16.07,38.62 16.3,38.86 16.64,38.86 16.81,39.02 EU2603.8 EU2603.2 18.48,39.02 18.63,38.88 18.82,38.88 18.94,38.75 19.08,38.75 19.21,38.88 LU6.1 19.88,39.05 RU12.1
USB3_CRX_DTX_P3: length 164.2
  IN2 w0.122: v2(203.89,38.3) 204.07,38.48 204.07,39.02 204.38,39.33 207.12,39.33 208.7,37.75 208.85,37.6 216.79,37.6 218.05,36.34 218.05,17.85 216.4,16.19 212.1,11.9 176.09,11.9 173.28,9.08 158.96,9.08 158.5,9.54 155.58,9.54 155.5,9.62 151.66,9.62 151.19,10.09 148.29,10.09 148.17,9.97 144.75,9.97 144.04,10.68 139.4,10.68 136.78,13.3 136.78,13.78 133.98,16.58 133.98,24.55 127.77,30.77 127.77,36.24 127.29,36.72 123.99,36.72 121.06,39.64 119.45,39.64 119.19,39.39 v2(119.19,39.35)
  BOTTOM w0.076: UC1.H10 118.8,38.95 v2(119.19,39.35)
  BOTTOM w0.097: v2(203.89,38.3) 204.1,38.51 204.1,39.2 206.38,41.48 207.39,41.48 CX7.1
USB3_CRX_L_DTX_N3: length 5.8
  BOTTOM w0.097: RX9.2 217.19,43.84 LX2.2 217.02,44.32 216.92,44.42 216.92,44.68 217.19,44.95 217.19,45.24 217.32,45.38 DX1.4 DX1.7 217.32,47.44 217.17,47.6 217.17,47.94 217.28,48.05 217.28,48.27 217.39,48.37 J3D1.5
USB3_CRX_L_DTX_P3: length 5.8
  BOTTOM w0.097: RX8.2 216.47,43.96 LX2.1 216.47,44.27 216.74,44.53 216.74,44.76 217,45.03 217,45.2 216.83,45.38 DX1.5 DX1.6 216.83,47.41 216.98,47.56 216.98,48.02 217.1,48.13 217.1,48.27 216.99,48.37 J3D1.6
USB3_CRX_RD_DTX_N3: length 3.3
  BOTTOM w0.097: RX9.1 217.19,42.92 LX2.3 217.02,42.44 216.87,42.29 216.87,42.07 216.59,41.79 v3(216.3,41.79) UX2.20
USB3_CRX_RD_DTX_P3: length 3.1
  BOTTOM w0.097: RX8.1 216.47,42.81 LX2.4 216.47,42.53 216.68,42.32 216.68,42.15 216.55,42.01 216.01,42.01 215.98,41.98 215.59,41.98 215.28,42.29 UX2.19
USB3_CTX_C_DRX_N3: length 4.6
  BOTTOM w0.097: CX11.2 217.7,39.64 218.27,39.64 v3(218.65,40.02) 218.84,40.21 218.84,41.29 218.87,41.32 218.87,42.02 218.84,42.06 218.84,42.21 218.9,42.27 LX1.3 218.9,42.73 RX4.1
USB3_CTX_C_DRX_P3: length 4.4
  BOTTOM w0.097: CX9.2 217.91,39.83 218.19,39.83 218.29,39.93 218.29,39.97 218.65,40.34 v3(218.65,41.61) 218.65,42.06 218.35,42.37 LX1.4 218.35,42.83 RX7.1
USB3_CTX_C_RD_DRX_N3: length 3.4
  BOTTOM w0.097: CX8.2 208.77,39.28 209,39.28 209.2,39.48 209.2,40.28 209.33,40.41 210.11,40.41 210.23,40.29 UX2.8
USB3_CTX_C_RD_DRX_P3: length 3.5
  BOTTOM w0.097: CX10.2 208.81,39.46 208.92,39.46 209.01,39.56 209.01,40.36 209.29,40.63 v3(209.53,40.63) 210.03,40.63 210.19,40.79 UX2.9
USB3_CTX_DRX_N1: length 188.4
  TOP w0.097: v2(23.83,61.44) 23.83,61.55 23.45,61.93 23.14,61.93 CU2.1
  IN2 w0.122: v2(126.4,36.28) 126.58,36.28 126.75,36.11 126.75,35.94 126.52,35.71 126.52,34.12 126.21,33.81 126.21,30.19 125.06,29.04 125.06,26.48 127.78,23.75 127.78,20.82 122.14,15.17 122.14,13.1 118.64,9.6 115.96,9.6 115.24,8.88 113.45,8.88 109.72,5.15 100.28,5.15 99.37,6.06 61.67,6.06 60.69,7.04 51.86,7.04 50.87,8.03 47,8.03 44.47,10.56 44.47,11.87 40.45,15.89 40.45,17.38 39.15,18.68 39.15,27.06 34.48,31.73 27.03,31.73 21.86,36.9 21.86,61.39 22.41,61.93 24.1,61.93 24.22,61.81 24.22,61.56 24.1,61.44 v2(23.83,61.44)
  BOTTOM w0.076: UC1.C13 122.17,40.56 122.3,40.43 122.41,40.43 122.5,40.52 122.5,40.82 122.54,40.85 122.77,40.93 122.91,40.93 123.1,40.87 123.25,40.87 123.34,40.92 123.67,40.92 125.26,39.32 125.26,38.49 v3(125.6,38.16) 126.95,36.81 126.95,36.65 126.57,36.28 v2(126.4,36.28)
USB3_CTX_DRX_N1_C: length 8.3
  TOP w0.097: JUSB1.8 13.18,62.57 13.29,62.68 13.62,62.68 14.48,61.82 14.7,61.82 14.73,61.79 15.31,61.79 15.34,61.82 v3(16.28,61.82) 16.75,61.82 16.9,61.67 EU2601.7 EU2601.4 18.56,61.67 18.69,61.81 18.88,61.81 19.05,61.97 19.16,61.97 19.31,61.81 LU2.4 19.82,61.65 RU3.1
USB3_CTX_DRX_N1_R: length 1.5
  TOP w0.097: CU2.2 21.55,61.98 21.41,61.98 21.24,61.81 LU2.3 20.73,61.65 RU3.2
USB3_CTX_DRX_N2: length 159.2
  TOP w0.097: v2(23.77,40.04) 23.77,40.15 23.52,40.4 23.39,40.4 CU4.1
  IN2 w0.122: v2(23.77,40.04) 23.96,40.04 24.09,40.17 24.09,40.34 23.93,40.49 22.78,40.49 22.63,40.34 22.63,37.09 27.31,32.4 34.76,32.4 39.83,27.34 39.83,18.96 41.12,17.66 41.12,16.17 47.02,10.28 49.58,10.28 52.14,7.71 61.35,7.71 62.33,6.73 99.65,6.73 100.56,5.83 109.44,5.83 113.17,9.56 114.96,9.56 115.68,10.28 118.07,10.28 121.46,13.67 121.46,16.43 121.82,16.79 121.82,18.58 120.57,19.83 120.57,23.67 124.38,27.48 124.38,29.32 125.53,30.47 125.53,33.6 125.06,34.08 125.06,34.98 125.47,35.39 125.47,36.03 v2(125.23,36.27)
  BOTTOM w0.094: v2(125.23,36.27) 125.62,36.65 125.62,37.16 124.67,38.11 124.67,38.94 123.71,39.9 123.46,39.9 123.22,40.15 123.22,40.51 123.06,40.66 UC1.B13
USB3_CTX_DRX_N2_C: length 8.3
  TOP w0.097: RU9.1 19.88,39.99 LU5.4 19.38,40.16 19.2,40.34 19.07,40.34 18.91,40.18 18.65,40.18 18.5,40.02 EU2603.4 EU2603.7 16.81,40.02 16.74,40.09 v3(16.17,40.09) 15.18,40.09 15.15,40.05 14.53,40.05 13.67,40.92 13.29,40.92 13.18,40.81 JUSB2.8
USB3_CTX_DRX_N2_R: length 1.6
  TOP w0.097: CU4.2 21.69,40.32 21.52,40.32 21.37,40.16 LU5.3 20.8,39.99 RU9.2
USB3_CTX_DRX_N3: length 150.4
  IN2 w0.122: v2(206.06,38.22) 205.97,38.14 205.97,37.33 207.07,36.23 216.44,36.23 217.38,35.3 217.38,18.13 212.3,13.05 200.13,13.05 199.65,12.57 175.81,12.57 173,9.75 161.98,9.75 158.46,13.27 156.62,13.27 156.1,13.79 148.59,13.79 146.37,16.01 142.19,16.01 141.28,16.91 140.81,16.91 138.26,19.47 138.26,22.43 136.25,24.44 136.25,25.51 133.71,28.05 133.71,29 132.93,29.78 132.93,31.12 130.73,33.32 130.73,36.47 128.23,38.97 125.92,38.97 125.51,39.39 125.51,40.05 v2(125.46,40.1)
  BOTTOM w0.076: v2(125.46,40.1) 125.46,40.9 124.75,41.61 123.34,41.61 122.93,42.01 UC1.B15
  BOTTOM w0.097: CX8.1 207.4,39.07 206.22,39.07 206.06,38.91 v2(206.06,38.22)
USB3_CTX_DRX_P1: length 188.6
  TOP w0.097: v2(23.89,62.36) 23.65,62.12 23.21,62.12 CU1.1
  IN2 w0.122: v2(127.12,36.3) 127.02,36.2 127.02,35.86 126.77,35.61 126.77,34.02 126.46,33.71 126.46,30.09 125.3,28.94 125.3,26.58 128.03,23.85 128.03,20.71 122.39,15.07 122.39,13.2 122.39,13 118.74,9.35 116.06,9.35 115.35,8.63 113.55,8.63 109.82,4.9 100.18,4.9 99.27,5.81 61.57,5.81 60.59,6.79 51.76,6.79 50.77,7.78 46.9,7.78 44.22,10.46 44.22,11.77 40.2,15.79 40.2,17.28 38.9,18.57 38.9,26.96 34.38,31.48 26.93,31.48 21.62,36.79 21.62,61.49 22.3,62.18 23.71,62.18 v2(23.89,62.36)
  BOTTOM w0.076: v2(127.12,36.3) 127.12,36.88 125.97,38.02 125.97,38.05 125.43,38.59 125.43,39.39 123.74,41.08 123.31,41.08 123.24,41.06 123.05,41.06 122.93,41.09 122.74,41.09 122.51,41.02 122.16,41.02 UC1.D13
USB3_CTX_DRX_P1_C: length 8.1
  TOP w0.097: RU4.1 19.82,62.48 LU2.1 19.33,62.31 19.17,62.16 18.97,62.16 18.8,61.99 18.69,61.99 18.51,62.17 EU2601.5 EU2601.6 16.9,62.17 16.74,62.01 16.6,62.01 16.57,62.04 15.98,62.04 15.95,62.01 v3(15.02,62.01) 14.56,62.01 13.7,62.87 13.68,62.89 13.29,62.89 13.18,63 JUSB1.9
USB3_CTX_DRX_P1_R: length 1.5
  TOP w0.097: RU4.2 20.73,62.48 LU2.2 21.29,62.31 21.44,62.17 21.57,62.17 CU1.2
USB3_CTX_DRX_P2: length 159.1
  TOP w0.097: CU3.1 23.22,40.58 23.48,40.58 v2(23.83,40.94)
  IN2 w0.122: v2(23.83,40.94) 23.71,40.81 22.75,40.81 22.38,40.44 22.38,36.99 27.21,32.15 34.66,32.15 39.58,27.24 39.58,18.85 40.87,17.56 40.87,16.07 46.91,10.03 49.48,10.03 52.04,7.46 61.25,7.46 62.23,6.48 99.55,6.48 100.46,5.58 109.54,5.58 113.27,9.31 115.07,9.31 115.78,10.03 118.17,10.03 121.71,13.57 121.71,16.33 122.07,16.68 122.07,18.69 120.82,19.93 120.82,23.57 124.63,27.38 124.63,29.22 125.78,30.37 125.78,33.71 125.31,34.18 125.31,34.88 125.71,35.29 125.71,36.15 v2(125.82,36.25)
  BOTTOM w0.094: UC1.A13 123.4,40.59 123.4,40.22 123.54,40.08 123.79,40.08 124.85,39.01 124.85,38.19 125.81,37.23 v3(125.81,36.84) 125.81,36.26 v2(125.82,36.25)
USB3_CTX_DRX_P2_C: length 8.3
  TOP w0.097: JUSB2.9 13.18,41.23 13.31,41.11 13.75,41.11 14.58,40.27 v3(14.85,40.27) 15.85,40.27 15.88,40.31 16.47,40.31 16.5,40.27 16.69,40.27 16.94,40.52 EU2603.6 EU2603.5 18.57,40.52 18.73,40.36 18.83,40.36 18.99,40.53 19.2,40.53 19.33,40.66 LU5.1 19.88,40.83 RU10.1
USB3_CTX_DRX_P2_R: length 1.6
  TOP w0.097: CU3.2 22.04,40.83 21.71,40.5 21.57,40.5 21.42,40.66 LU5.2 20.8,40.83 RU10.2
USB3_CTX_DRX_P3: length 150.4
  IN2 w0.122: v2(205.47,38.22) 205.73,37.97 205.73,37.23 206.97,35.99 216.34,35.99 217.13,35.2 217.13,18.23 212.2,13.3 200.03,13.3 199.55,12.82 175.71,12.82 172.89,10 162.08,10 158.56,13.52 156.73,13.52 156.2,14.04 148.7,14.04 146.48,16.26 142.29,16.26 141.38,17.16 140.91,17.16 138.51,19.57 138.51,22.53 136.49,24.55 136.49,25.62 133.96,28.15 133.96,29.1 133.18,29.88 133.18,31.23 130.98,33.43 130.98,36.57 128.33,39.22 126.03,39.22 125.76,39.49 125.76,39.73 v2(126.13,40.1)
  BOTTOM w0.076: v2(126.13,40.1) 125.99,40.1 125.63,40.46 125.63,40.97 124.82,41.78 123.55,41.78 123.48,41.85 UC1.A15
  BOTTOM w0.097: CX10.1 206.94,39.26 206.14,39.26 205.87,38.99 205.87,38.62 v2(205.47,38.22)
USB3_CTX_L_DRX_N3: length 5.7
  BOTTOM w0.097: RX4.2 219,43.86 LX1.2 218.9,44.19 218.79,44.3 218.79,44.6 218.68,44.72 218.68,45.25 218.83,45.39 DX1.1 DX1.10 218.83,47.51 218.67,47.67 218.67,47.95 218.48,48.13 218.48,48.27 218.59,48.37 J3D1.2
USB3_CTX_L_DRX_P3: length 5.7
  BOTTOM w0.097: J3D1.3 218.19,48.37 218.3,48.27 218.3,48.05 218.48,47.87 218.48,47.67 218.32,47.51 DX1.9 DX1.2 218.32,45.39 218.49,45.22 218.49,44.64 218.61,44.53 218.61,44.35 218.35,44.09 LX1.1 218.24,43.86 RX7.2
USB3_CTX_RD_DRX_N3: length 2.5
  BOTTOM w0.097: CX11.1 216.19,39.75 215.87,39.75 215.62,40.01 215.62,40.31 215.51,40.42 215.33,40.42 215.21,40.29 UX2.23
USB3_CTX_RD_DRX_P3: length 2.5
  BOTTOM w0.097: CX9.1 216.2,39.94 215.95,39.94 215.8,40.08 215.8,40.39 215.59,40.6 215.41,40.6 215.22,40.79 UX2.22
USB3_DE1_P0: length 3.6
  TOP w0.102: v1(213.95,37.36) 213.76,37.36 213.06,38.05 v2(212.99,38.05) 212.93,38.11 RX29.2
  BOTTOM w0.102: RX28.2 212.99,37.5 v2(212.99,38.05) UX2.3
USB3_DE2_P0: length 4.1
  TOP w0.102: v1(213.57,43.33) 213.23,43.66 v2(213.23,44.02) 213.23,44.63 RX23.2
  BOTTOM w0.102: UX2.16 212.99,43.78 v2(213.23,44.02) 213.23,44.63 RX23.2
USB3_EQ1_P0: length 3.7
  TOP w0.102: RX31.2 v2(213.82,38.05) v1(215.16,38.05)
  BOTTOM w0.102: RX30.2 v2(213.82,38.05) 213.49,38.38 UX2.2
USB3_EQ2_P0: length 4.9
  TOP w0.102: RX25.2 214.46,44.67 v2(213.82,44.03) 214.45,44.03 v1(214.97,43.52)
  BOTTOM w0.102: UX2.17 213.49,43.71 v2(213.82,44.03) 214.46,44.67 RX25.2
USB3_ERD_P0: length 3.7
  TOP w0.102: RX19.2 211.16,38.57 v2(211.69,38.04) 211.69,37.82 v1(211.22,37.36)
  BOTTOM w0.102: UX2.5 211.99,38.34 211.69,38.03 ; 211.69,38.03 211.16,37.5 RX18.2 ; 211.69,38.03 v2(211.69,38.04)
USB3_OS1_P0: length 3.4
  TOP w0.102: v1(212.55,37.36) 212.36,37.55 v2(212.36,38.05) 212.05,38.36 RX27.2
  BOTTOM w0.102: UX2.4 212.49,38.17 v2(212.36,38.05) 212.36,37.76 RX26.2
USB3_OS2_P0: length 3.8
  TOP w0.102: v1(212.11,43.45) 212.65,43.99 v2(212.65,44.03) 212.68,44.07 RX21.2
  BOTTOM w0.102: RX21.2 212.68,44.07 v2(212.65,44.03) 212.49,43.88 UX2.15
USB3_P0_PIN6: length 4
  TOP w0.102: v1(209.89,37.55) 210.41,38.07 v2(210.46,38.07) 210.27,38.27 RX12.2
  BOTTOM w0.102: UX2.6 211.49,38.45 211.16,38.12 210.5,38.12 v2(210.46,38.07) 210.27,37.88 RX11.2
USB3_P0_PIN18: length 5.5
  TOP w0.102: RX15.2 v2(215.35,44) 215.89,44 216.43,44.53 v1(216.62,44.53)
  BOTTOM w0.102: RX15.2 v2(215.35,44) 215.23,43.88 214.32,43.88 213.99,43.56 UX2.18
USB20_VCCA:
  vias: v4(170.52,20.73) v4(172.4,20.64) v4(174.19,20.71)
USB30_VCCA: length 34.7
  TOP w0.102: v4(23.39,66.52) 22.71,65.84 22.5,65.84
  BOTTOM w2.032: 20.59,64.34 20.59,48.53 18.07,46 18.07,44.4 ; 16.4,29.36 16.42,29.37 16.42,36.51 17.9,37.99 17.9,41.28
  vias: v2(22.18,64.35) v2(22.18,63.65) v2(22.82,64.35) v2(22.82,63.65) v2(22.82,43.78) v2(22.82,43.08) v2(23.45,43.78) v2(23.45,43.08) v4(23.13,44.28) v4(23.18,64.78)
USB_CAMERA_EDP: length 3.2
  BOTTOM w0.097: JEDP1.32 223.49,34.55 223.33,34.71 v3(222.52,34.71) 222.25,34.71 221.91,35.05 221.74,35.05 221.58,34.89 L3.4 221.37,34.86 R18.1
USB_CAMERA_EDP#: length 3.2
  BOTTOM w0.097: R17.1 221.37,35.42 L3.1 221.57,35.39 221.73,35.23 221.99,35.23 222.3,34.93 222.82,34.93 222.85,34.9 223.3,34.9 223.46,35.05 JEDP1.31
USB_EN#: length 222.3
  IN1 w0.127: v2(6.18,26.18) 6.76,26.18 8.64,28.06 37.72,28.06 42.82,22.97 43.01,22.97 46.31,19.66 46.31,11.28 47.48,10.11 47.69,10.11 50.88,10.11 58.5,2.49 78,2.49 78.65,1.84 92.84,1.84 93.27,2.28 93.27,3.17 93.4,3.29 94.62,3.29 95.82,2.1 112.36,2.1 112.69,2.43 112.69,2.9 113.14,3.36 114.27,3.36 115.02,2.6 123.47,2.6 124.1,3.23 125.64,3.23 126.01,2.86 153.82,2.86 163.07,12.1 v2(163.07,13.5)
  IN2 w0.127: v2(163.07,13.5) 162.57,13.5 159.88,16.19 158.03,16.19 157.07,17.15 156.17,17.15 155.62,17.69 149.83,17.69 148.8,18.72 148.8,19.66 148.45,20.01 144.99,20.01 144.02,20.97 141.63,20.97 141.29,21.3 141.29,22.09 141.08,22.3 141.08,23.01 139.81,24.28 v2(139.1,24.28)
  BOTTOM w0.102: UE1.13 139.4,23.58 139.24,23.74 139.24,24.15 v2(139.1,24.28) RE17.1 ; UU1.4 v2(6.18,26.18) ; UU3.4 164.99,18.24 163.69,16.94 163.69,14.13 v2(163.07,13.5)
USB_OC#0_1: length 178.3
  IN2 w0.142: v2(7.16,25.58) 7.16,26.21 7.65,26.69 22.12,26.69 25.8,30.37 32.72,30.37 37.46,25.63 37.46,17.87 38.75,16.58 38.75,15.72 43.13,11.34 43.13,9.39 46.94,5.59 53.74,5.59 53.92,5.41 54.36,4.96 54.97,4.36 82.49,4.36 83.53,3.31 87.44,3.31 89.31,3.31 90.31,4.32 98.59,4.32 99.53,3.37 110.28,3.37 112.13,5.23 113.81,5.23 116.61,8.03 119.4,8.03 126.97,15.6 126.97,16.99 129.31,19.33 129.31,24.56 128.98,24.89 128.98,28.61 127.33,30.25 127.33,35.33 v2(127.21,35.45)
  BOTTOM w0.102: UU1.3 7.25,25.49 v2(7.16,25.58) ; UC1.A9 123.48,38.08 123.58,38.08 124.04,37.62 124.04,36.66 125.05,35.64 127.02,35.64 v2(127.21,35.45) 127.34,35.45 v1(128.42,36.53) 128.85,36.96 RPC1.3
USB_OC#2_3: length 127.7
  IN1 w0.127: v2(167.22,19.45) 167.22,20.85 169.5,23.13 177.98,23.13 178.94,24.08 178.94,27.02 179.21,27.3 181.13,27.3 182.88,25.55 185.39,25.55 186.2,26.36 186.2,32.11 184.68,33.64 184.68,39.39 184.23,39.83 184.23,41.51 181.4,44.34 180.75,44.34 172.68,52.41 168.65,52.41 167.6,51.37 167.01,51.37 165.95,50.31 160.93,50.31 157.93,47.31 157.93,47.1 157.93,41.46 157.18,40.71 157.18,38.37 155.47,36.66 151.48,36.66 149.58,38.56 140.99,38.56 140.35,39.2 138.75,39.2 136.65,37.1 134.89,37.1 134.18,36.39 v2(130.1,36.39)
  BOTTOM w0.102: UC1.C9 122.4,38.19 122.7,37.89 123.5,37.89 123.85,37.54 123.85,36.58 125.16,35.26 v1(126.51,35.26) 126.7,35.07 127.4,35.07 128.42,36.09 128.66,36.09 128.96,36.39 v2(130.1,36.39) 130.17,36.46 RPC1.2 ; UU3.3 168.43,18.24 v2(167.22,19.45)
USB_OC#4_5: length 11.9
  TOP w0.102: v2(121.33,37.71) v1(122.21,37.71) 122.22,37.71 125.46,34.47 v2(125.77,34.47)
  BOTTOM w0.076: v2(121.33,37.71) 121.33,37.99 UC1.D9
  BOTTOM w0.102: RPC1.1 130.32,35.96 130.26,35.9 128.5,35.9 127.07,34.47 v2(125.77,34.47)
USB_OC#6_7: length 10.5
  BOTTOM w0.102: UC1.B9 123.09,38.45 123.7,38.45 124.23,37.93 124.23,36.73 124.95,36.01 125.13,35.83 127.19,35.83 128.82,37.46 v1(129.37,37.46) RPC1.4
USB_PN1: length 147.9
  TOP w0.097: RU1.2 25.11,57.85 LU1.2 25.61,57.68 25.72,57.57 25.89,57.57 v2(26.09,57.76)
  IN2 w0.089: v2(112.8,37.85) 112.72,37.93 112.48,37.93 112.37,37.82 112.37,34.52 112.41,34.48
  IN2 w0.122: v2(26.09,57.76) 25.99,57.66 25.32,57.66 24.95,57.29 24.95,50.13 27.63,47.45 27.63,35.27 28.64,34.26 35.53,34.26 41.68,28.11 41.68,19.72 42.98,18.43 42.98,16.94 44.87,15.04 48.04,15.04 51.51,11.58 81.02,11.58 82.57,13.13 95.84,13.13 98.87,16.16 99.83,16.16 104.19,20.52 104.19,24.29 102.49,25.99 102.49,28.84 103.45,29.8 106.8,29.8 108.65,31.65 110.63,31.65 111.97,32.99 111.97,33.7 112.41,34.14 112.41,34.48
  BOTTOM w0.097: UC1.AB9 v2(112.8,37.85)
USB_PN1_C: length 13
  TOP w0.097: RU1.1 24.2,57.85 LU1.1 23.66,57.68 23.51,57.53 23.31,57.53 23.27,57.56 22.69,57.56 22.66,57.53 v3(21.71,57.53) 21.02,57.53 20.94,57.45 20.23,57.45 20.11,57.57 20.11,58.08 EU2602.3 19.6,58.08 19.6,57.59 19.49,57.49 19.11,57.49 v2(18.98,57.62)
  IN2 w0.122: v2(18.98,57.62) 18.78,57.42 17.99,57.42 15.59,59.82 14.8,59.82 14.68,59.95 JUSB1.2
USB_PN2: length 121.3
  TOP w0.097: RU8.1 26,36.07 LU4.2 26.67,35.9 26.87,35.7 v3(27.82,35.7) 28.59,35.7 28.77,35.88 28.77,36.15 v2(28.56,36.37)
  IN2 w0.122: v2(28.56,36.37) 28.73,36.2 28.73,35.51 29.1,35.14 35.94,35.14 42.43,28.64 42.43,20.04 46.39,16.08 48.08,16.08 51.7,12.46 80.84,12.46 82.88,14.5 95.08,14.5 95.75,15.16 96.4,15.16 98.14,16.91 99.52,16.91 103.43,20.83 103.43,23.98 101.73,25.68 101.73,29.15 103.34,30.76 106.52,30.76 108.16,32.4 110.32,32.4 110.69,32.77 110.69,33.6 111.43,34.34 111.43,35.89 111.66,36.12 v2(111.79,35.99)
  BOTTOM w0.097: UC1.AD6 111.79,35.99 v2(111.79,35.99)
USB_PN2_C: length 13.8
  TOP w0.097: v2(19.3,35.9) 19.44,35.76 19.8,35.76 19.92,35.88 19.92,36.36 EU2604.3 20.43,36.36 20.43,35.85 20.55,35.73 21.78,35.73 21.81,35.76 22.4,35.76 22.43,35.73 v3(23.58,35.73) 24.29,35.73 24.46,35.9 LU4.1 25.09,36.07 RU8.2
  IN2 w0.122: JUSB2.2 14.68,38.25 14.8,38.12 16.07,38.12 16.34,37.86 16.34,37.81 18.42,35.73 19.13,35.73 v2(19.3,35.9)
USB_PN3: length 131.9
  IN2 w0.122: v2(155.55,12.31) 155.79,12.55 155.79,12.75 155.61,12.94 154.81,12.94 154.16,12.29 150.84,12.29 150.37,12.75 147.35,12.75 146.52,13.58 146.52,13.87 145.65,14.74 140.35,14.74 137.18,17.91 137.18,21.34 135.49,23.03 135.49,25.2 132.96,27.74 132.96,28.69 132.04,29.6 132.04,30.11 130.29,31.86 130.29,31.99 129.27,33.01 129.27,36.86 127.92,38.22 125.58,38.22 121.62,42.18 119.85,42.18 117.96,44.08 117.96,46.1 117.5,46.56 116.35,46.56 116.02,46.23 112.91,46.23 111.91,45.23 111.91,41.31 111.72,41.12 111.72,40.53 110.38,39.2 109.75,39.2 108.54,37.99 108.54,37.42 108.14,37.02 108.14,36.49 108.25,36.37 108.25,35.87 v2(108.52,35.61)
  BOTTOM w0.076: UC1.AH3 108.52,35.34 v2(108.52,35.61)
  BOTTOM w0.097: v2(155.55,12.31) 155.74,12.13 155.74,11.56 156.04,11.26 160.09,11.26 161.16,10.19 174.62,10.19 180.23,15.8 186.06,15.8 187.05,16.79 187.05,20.75 186.61,21.19 185.86,21.19 185.48,21.57 185.48,24.2 184.42,25.27 182.88,25.27 182.85,25.31 182.2,25.31 182.17,25.27 180.5,25.27 180.03,24.8 179.39,24.8 179.04,24.45 179.04,24.16 178.9,24.03 LU7.3 178.74,23.46 RU14.1
USB_PN3_C: length 5.3
  BOTTOM w0.097: JIOB1.8 178.6,18.15 179.04,18.6 v3(179.04,19.86) 179.04,20.92 179.01,20.95 179.01,21.53 179.04,21.56 179.04,22.24 LU7.4 178.74,22.55 RU14.2
USB_PN5: length 170.7
  IN2 w0.122: v2(129.47,25.58) 129.73,25.32 130.03,25.32 130.19,25.16 131.02,25.16 132.73,23.46 132.73,16.06 135.53,13.26 135.53,13.2 135.53,12.78 138.88,9.43 143.52,9.43 144.23,8.71 148.69,8.71 148.8,8.82 150.65,8.82 151.13,8.34 155,8.34 155.52,7.82 173.8,7.82 176.62,10.64 218.65,10.64 221.14,13.13 221.14,17.91 224.95,21.72 224.95,26.78 225.77,27.59 225.77,31.72 224.02,33.46 222.35,33.46 v2(221.97,33.08)
  BOTTOM w0.097: R17.2 220.29,35.56 L3.2 219.86,35.39 219.6,35.13 219.43,35.13 219.22,34.92 219.22,33.84 219.43,33.64 221.58,33.64 221.97,33.25 v2(221.97,33.08) ; v2(129.47,25.58) 129.08,25.18 128.92,25.18 128.37,25.73 127.91,25.73 126.64,27 122.22,27 121.57,26.35 121.57,26.31 120.04,24.77 120.04,24.42 118.05,22.43 115.81,22.43 114.19,24.04 113.76,24.04 112.99,24.81 112.72,24.81 112.64,24.89 112.09,24.89 112.01,24.81 110.54,24.81 110.22,24.5 109.85,24.5 108.72,25.63 108.72,26.94 108.14,27.52 108.14,28.18 107.65,28.67 107.65,29.22 107.66,29.23 107.66,31.8 107.84,31.98 107.84,33.44 107.94,33.54 UC1.AJ1
USB_PN6: length 120
  IN2 w0.122: v2(109.68,36.02) 109.68,36.04 110.38,36.74 110.38,38.12 112.29,40.02 112.29,41.04 112.61,41.36 113.31,41.36 113.88,41.92 113.88,43.39 114.32,43.83 115.08,43.83 115.59,44.34 116.99,44.34 117.19,44.14 117.19,43.68 117.05,43.54 117.05,43.04 117.22,42.88 117.22,42.6 119.2,40.63 120.69,40.63 120.85,40.79 121.17,40.79 124.48,37.47 127.6,37.47 128.52,36.55 128.52,32.7 128.89,32.33 128.89,30.71 134.74,24.86 134.74,22.49 135.71,21.52 135.71,18.04 139.76,13.99 144.56,13.99 146.89,11.66 150.07,11.66 150.31,11.43 153.23,11.43 154.25,10.41 156.26,10.41 156.95,11.11 156.95,12.52 v2(157.21,12.78)
  BOTTOM w0.089: UC1.AF6 109.93,36.26 v2(109.68,36.02)
  BOTTOM w0.097: v2(157.21,12.78) 156.9,12.47 156.9,12.34 157.09,12.15 160.41,12.15 161.36,11.19 174.42,11.19 179.88,16.66 185.71,16.66 186.2,17.14 186.2,20.14 186,20.34 185.51,20.34 184.63,21.21 184.63,23.12 183.68,24.07 183.27,24.07 183.2,24.01 183.2,23.89 183.34,23.76 LU8.2 183.51,23.21 RU15.1
USB_PN6_C: length 5
  BOTTOM w0.097: JIOB1.3 183.6,18.23 183.2,18.62 v3(183.2,19.74) 183.2,20.75 183.24,20.78 183.24,21.37 183.2,21.4 183.2,21.99 LU8.1 183.51,22.29 RU15.2
USB_PN7: length 154
  IN2 w0.122: v2(222.11,23.82) 222.11,23.98 222.45,24.32 222.88,24.32 223.1,24.09 223.1,21.33 220.34,18.57 220.34,13.47 218.27,11.39 176.3,11.39 173.49,8.58 155.84,8.58 155.32,9.1 151.45,9.1 150.97,9.58 148.49,9.58 148.37,9.46 144.55,9.46 143.83,10.18 139.2,10.18 136.28,13.09 136.28,13.57 133.48,16.37 133.48,24.34 131.71,26.11 130.85,26.11 130.52,26.45 v2(130.51,26.45)
  BOTTOM w0.097: UC1.AH1 108.48,33.65 108.48,31.32 108.32,31.16 108.32,28.95 109.38,27.88 109.38,25.96 109.78,25.56 113.18,25.56 114.03,24.71 114.47,24.71 116.08,23.1 117.78,23.1 119.37,24.69 119.37,25.04 120.91,26.58 120.91,26.63 121.95,27.67 121.99,27.67 122,27.67 122.55,27.67 122.7,27.67 125.14,27.67 125.17,27.7 125.79,27.7 125.82,27.67 127.13,27.67 128.23,26.57 129.43,26.57 129.94,26.05 130.12,26.05 v2(130.51,26.45) ; v2(222.11,23.82) 222.11,24 221.73,24.38 221.4,24.38 221.19,24.6 221.19,24.85 220.88,25.16 L4.2 220.71,25.73 R20.2
USB_PN7_TPNL: length 12
  BOTTOM w0.097: R20.1 220.71,26.64 L4.1 220.88,27.07 221,27.2 221,28.43 221.1,28.54 221.1,29.63 220.27,30.47 220.27,31 220.17,31.1 DA6.2 219.4,31.6 220.3,32.5 220.3,32.75 220.53,32.97 v3(220.87,32.97) 221.28,32.97 221.86,32.4 222.58,32.4 222.61,32.43 223.25,32.43 223.37,32.55 JEDP1.36
USB_PN8: length 163.6
  IN2 w0.122: v2(44.91,93.07) 44.69,92.85 43.89,92.85 41.3,90.26 41.3,41.63 45.23,37.7 45.23,20.94 47.89,18.28 48.99,18.28 52.36,14.91 72.86,14.91 73.38,15.43 80.7,15.43 82,16.73 93.29,16.73 94.06,17.5 94.06,21.54 94.41,21.89 94.41,22.82 99.2,27.61 99.2,29.51 101.02,31.33 101.41,31.33 101.97,31.89 101.97,32.5 103.65,34.17 107.88,34.17 108.16,34.45 108.37,34.45 109.28,35.36 109.28,37.05 109.11,37.22 109.11,37.49 109.23,37.61 109.41,37.61 v2(109.59,37.43)
  BOTTOM w0.097: UC1.AF8 109.72,37.56 v2(109.59,37.43) ; RW1.2 44.44,96.91 LW1.3 44.28,96.34 44.09,96.16 44.09,92.95 44.19,92.86 44.7,92.86 v2(44.91,93.07)
USB_PN8_R: length 2.7
  BOTTOM w0.097: RW1.1 44.44,97.82 LW1.4 44.28,98.36 44.12,98.51 44.12,98.73 43.89,98.96 43.89,99.26 44.05,99.42 JWLAN1.5
USB_PP1: length 147.4
  TOP w0.097: v2(26.09,57.18) 26.09,57.24 25.95,57.38 25.75,57.38 25.54,57.18 LU1.3 25.11,57.01 RU2.2
  IN2 w0.076: 112.16,34.5 112.16,34.48
  IN2 w0.089: v2(112.69,38.59) 112.72,38.59 112.82,38.48 112.82,38.35 112.69,38.22 112.47,38.22 112.19,37.94 112.19,34.53 112.16,34.5
  IN2 w0.122: v2(26.09,57.18) 25.85,57.41 25.43,57.41 25.2,57.19 25.2,50.24 27.88,47.55 27.88,35.37 28.75,34.51 35.63,34.51 41.93,28.21 41.93,19.83 43.23,18.53 43.23,17.04 44.98,15.29 48.15,15.29 51.61,11.83 80.92,11.83 82.47,13.37 95.74,13.37 98.77,16.41 99.72,16.41 103.94,20.62 103.94,24.19 102.24,25.89 102.24,28.94 103.35,30.05 106.7,30.05 108.55,31.9 110.53,31.9 111.72,33.09 111.72,33.81 112.16,34.24 112.16,34.48
  BOTTOM w0.094: v2(112.69,38.59) 112.57,38.59 UC1.AB10
USB_PP1_C: length 13
  TOP w0.097: RU2.1 24.2,57.01 LU1.4 23.65,57.18 23.49,57.34 v3(22.98,57.34) 22.04,57.34 22,57.31 21.4,57.31 21.37,57.34 21.1,57.34 21.02,57.26 20.21,57.26 20.11,57.16 20.11,56.65 EU2602.2 19.6,56.65 19.6,57.16 19.48,57.29 19.23,57.29 v2(18.98,57.03)
  IN2 w0.122: JUSB1.3 14.68,59.45 14.8,59.58 15.48,59.58 17.89,57.17 18.84,57.17 v2(18.98,57.03)
USB_PP2: length 121.3
  TOP w0.097: v2(29.14,36.37) 28.96,36.19 28.96,35.81 28.67,35.51 28.14,35.51 28.11,35.48 27.53,35.48 27.5,35.51 26.77,35.51 26.65,35.4 LU4.3 26,35.23 RU7.1
  IN2 w0.122: v2(111.79,36.57) 111.58,36.36 111.55,36.36 111.18,36 111.18,34.44 110.44,33.7 110.44,32.87 110.22,32.65 108.06,32.65 106.42,31.01 103.24,31.01 101.49,29.25 101.49,25.58 103.19,23.88 103.19,20.93 99.41,17.16 98.04,17.16 96.29,15.41 95.64,15.41 94.98,14.75 82.78,14.75 80.73,12.71 51.8,12.71 48.32,16.18 48.18,16.33 46.5,16.33 42.68,20.14 42.68,28.75 36.04,35.39 29.2,35.39 28.98,35.61 28.98,36.2 v2(29.14,36.37)
  BOTTOM w0.097: v2(111.79,36.57) UC1.AD7
USB_PP2_C: length 13.9
  TOP w0.097: v2(19.3,35.32) 19.55,35.57 19.79,35.57 19.92,35.44 19.92,34.94 EU2604.2 20.43,34.94 20.43,35.44 20.53,35.54 v3(22.11,35.54) 23.25,35.54 23.29,35.51 23.87,35.51 23.9,35.54 24.32,35.54 24.47,35.4 LU4.4 25.09,35.23 RU7.2
  IN2 w0.122: JUSB2.3 14.68,37.75 14.8,37.88 15.97,37.88 16.09,37.75 16.09,37.71 18.31,35.48 19.13,35.48 v2(19.3,35.32)
USB_PP3: length 132
  IN2 w0.122: v2(156.14,12.31) 156.04,12.41 156.04,12.86 155.71,13.19 154.71,13.19 154.06,12.54 150.94,12.54 150.47,13 147.45,13 146.77,13.68 146.77,13.97 145.75,14.99 140.45,14.99 137.43,18.02 137.43,21.44 135.74,23.13 135.74,25.31 133.2,27.84 133.2,28.79 132.29,29.7 132.29,30.21 130.54,31.96 130.54,32.09 129.52,33.11 129.52,36.97 128.02,38.47 125.69,38.47 121.73,42.43 119.96,42.43 118.17,44.22 118.17,46.19 117.58,46.77 116.21,46.77 115.92,46.48 112.81,46.48 111.66,45.33 111.66,41.41 111.47,41.22 111.47,40.63 110.28,39.45 109.64,39.45 108.29,38.09 108.29,37.52 107.93,37.16 107.93,36.4 108.04,36.29 108.04,35.46 v2(107.59,35.01)
  BOTTOM w0.076: v2(107.59,35.01) 107.86,35.01 UC1.AJ3
  BOTTOM w0.097: RU13.1 179.57,23.46 LU7.2 179.4,24.04 179.23,24.21 179.23,24.38 179.46,24.61 180.11,24.61 180.58,25.08 v3(182.51,25.08) 184.34,25.08 185.29,24.12 185.29,21.49 185.78,21 186.53,21 186.86,20.67 186.86,16.87 185.98,15.99 180.16,15.99 174.54,10.38 161.24,10.38 160.17,11.45 156.12,11.45 155.93,11.64 155.93,12.1 v2(156.14,12.31)
USB_PP3_C: length 5.3
  BOTTOM w0.097: RU13.2 179.57,22.55 LU7.1 179.23,22.21 v3(179.23,21.24) 179.23,20.18 179.26,20.15 179.26,19.56 179.23,19.53 179.23,18.6 179.6,18.23 JIOB1.7
USB_PP5: length 171.1
  IN2 w0.122: v2(129.47,24.99) 129.55,25.08 129.93,25.08 130.09,24.92 130.92,24.92 132.48,23.35 132.48,15.96 135.28,13.16 135.28,12.68 138.78,9.18 143.42,9.18 144.13,8.46 148.79,8.46 148.9,8.58 150.55,8.58 151.03,8.1 154.9,8.1 155.42,7.57 173.9,7.57 176.72,10.39 218.75,10.39 221.39,13.03 221.39,17.81 225.2,21.62 225.2,26.68 226.02,27.49 226.02,31.82 224.12,33.71 222.07,33.71 v2(221.97,33.82)
  BOTTOM w0.097: R18.2 220.29,34.72 L3.3 219.78,34.89 219.73,34.94 219.51,34.94 219.41,34.85 219.41,33.92 219.51,33.82 v2(221.97,33.82) ; v2(129.47,24.99) 128.84,24.99 128.29,25.55 127.83,25.55 126.56,26.81 122.3,26.81 121.76,26.28 121.76,26.23 120.23,24.69 120.23,24.34 118.13,22.24 115.73,22.24 114.12,23.85 113.68,23.85 112.91,24.63 112.64,24.63 112.56,24.7 112.16,24.7 112.09,24.63 110.62,24.63 110.3,24.31 109.78,24.31 108.53,25.56 108.53,26.86 107.95,27.44 107.95,28.11 107.46,28.59 107.46,29.3 107.47,29.31 107.47,31.87 107.65,32.06 107.65,33.61 108.03,33.99 UC1.AJ2
USB_PP6: length 120.4
  IN2 w0.122: v2(156.62,12.78) 156.71,12.7 156.71,11.21 156.15,10.66 154.36,10.66 153.33,11.68 150.41,11.68 150.18,11.91 146.99,11.91 144.66,14.24 139.86,14.24 135.96,18.14 135.96,21.62 134.99,22.59 134.99,24.96 129.14,30.82 129.14,32.43 128.77,32.8 128.77,36.66 127.71,37.72 124.58,37.72 121.27,41.03 120.75,41.03 120.59,40.87 119.3,40.87 117.43,42.74 117.43,42.96 117.27,43.13 117.27,43.46 117.4,43.59 117.4,44.22 117.07,44.55 115.5,44.55 115.47,44.52 115.41,44.52 114.98,44.08 114.22,44.08 113.63,43.49 113.63,42.02 113.17,41.57 112.52,41.57 112.48,41.53 112.43,41.53 112.04,41.14 112.04,40.13 110.13,38.22 110.13,36.84 109.95,36.66 v2(109.68,36.66)
  BOTTOM w0.089: UC1.AF7 109.91,36.66 v2(109.68,36.66)
  BOTTOM w0.097: RU16.1 182.67,23.21 LU8.3 182.84,23.77 183.01,23.94 183.01,24.08 183.19,24.26 183.75,24.26 184.82,23.2 184.82,21.29 185.58,20.52 186.08,20.52 186.38,20.22 186.38,17.07 185.78,16.47 179.96,16.47 174.5,11 161.29,11 160.33,11.96 157.02,11.96 156.72,12.26 156.72,12.55 156.69,12.58 156.69,12.71 v2(156.62,12.78)
USB_PP6_C: length 5.1
  BOTTOM w0.097: JIOB1.4 182.6,18.15 183.02,18.57 183.02,19.41 182.99,19.44 182.99,20.03 183.02,20.06 v3(183.02,21.07) 183.02,21.59 182.84,21.77 LU8.4 182.67,22.29 RU16.2
USB_PP7: length 154.4
  IN2 w0.122: v2(130.51,25.86) 131.61,25.86 133.23,24.24 133.23,16.27 136.03,13.47 136.03,12.99 139.09,9.93 143.73,9.93 144.44,9.22 148.48,9.22 148.59,9.33 150.87,9.33 151.35,8.85 155.21,8.85 155.73,8.33 173.59,8.33 176.41,11.14 218.37,11.14 220.59,13.36 220.59,18.47 223.35,21.23 223.35,24.2 222.98,24.57 v2(222.11,24.57)
  BOTTOM w0.097: R21.2 221.54,25.73 L4.3 221.38,24.67 221.48,24.57 v2(222.11,24.57) ; UC1.AH2 108.69,34.32 108.37,33.99 108.37,33.8 108.3,33.73 108.3,31.4 108.13,31.23 108.13,28.87 109.19,27.8 109.19,25.88 109.7,25.37 113.1,25.37 113.96,24.52 114.39,24.52 116,22.91 117.85,22.91 119.56,24.61 119.56,24.97 121.1,26.5 121.1,26.55 122.03,27.48 122.07,27.48 122.07,27.48 122.47,27.48 122.62,27.48 v3(125.5,27.48) 127.05,27.48 128.16,26.38 129.35,26.38 129.86,25.86 v2(130.51,25.86)
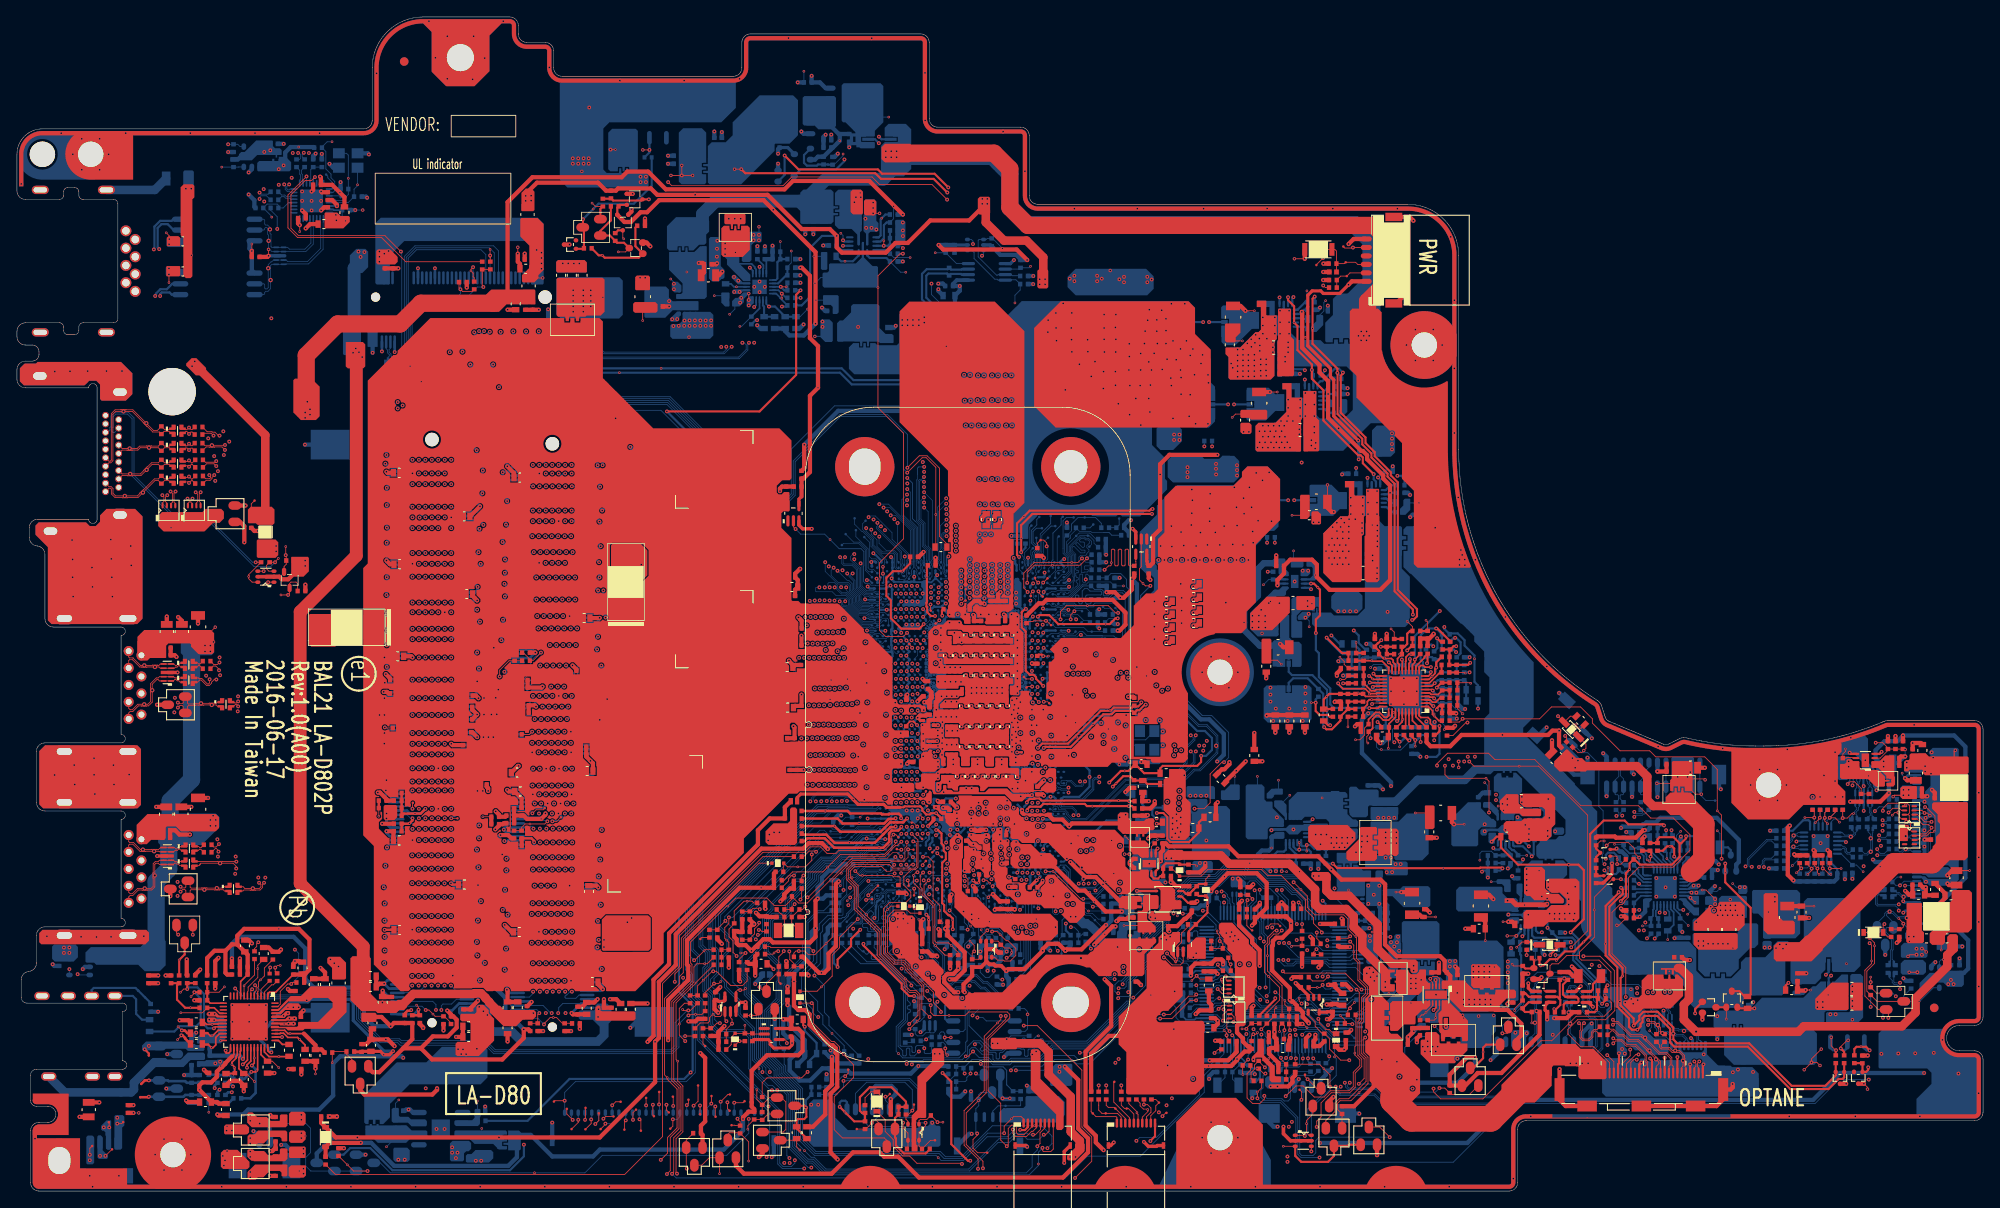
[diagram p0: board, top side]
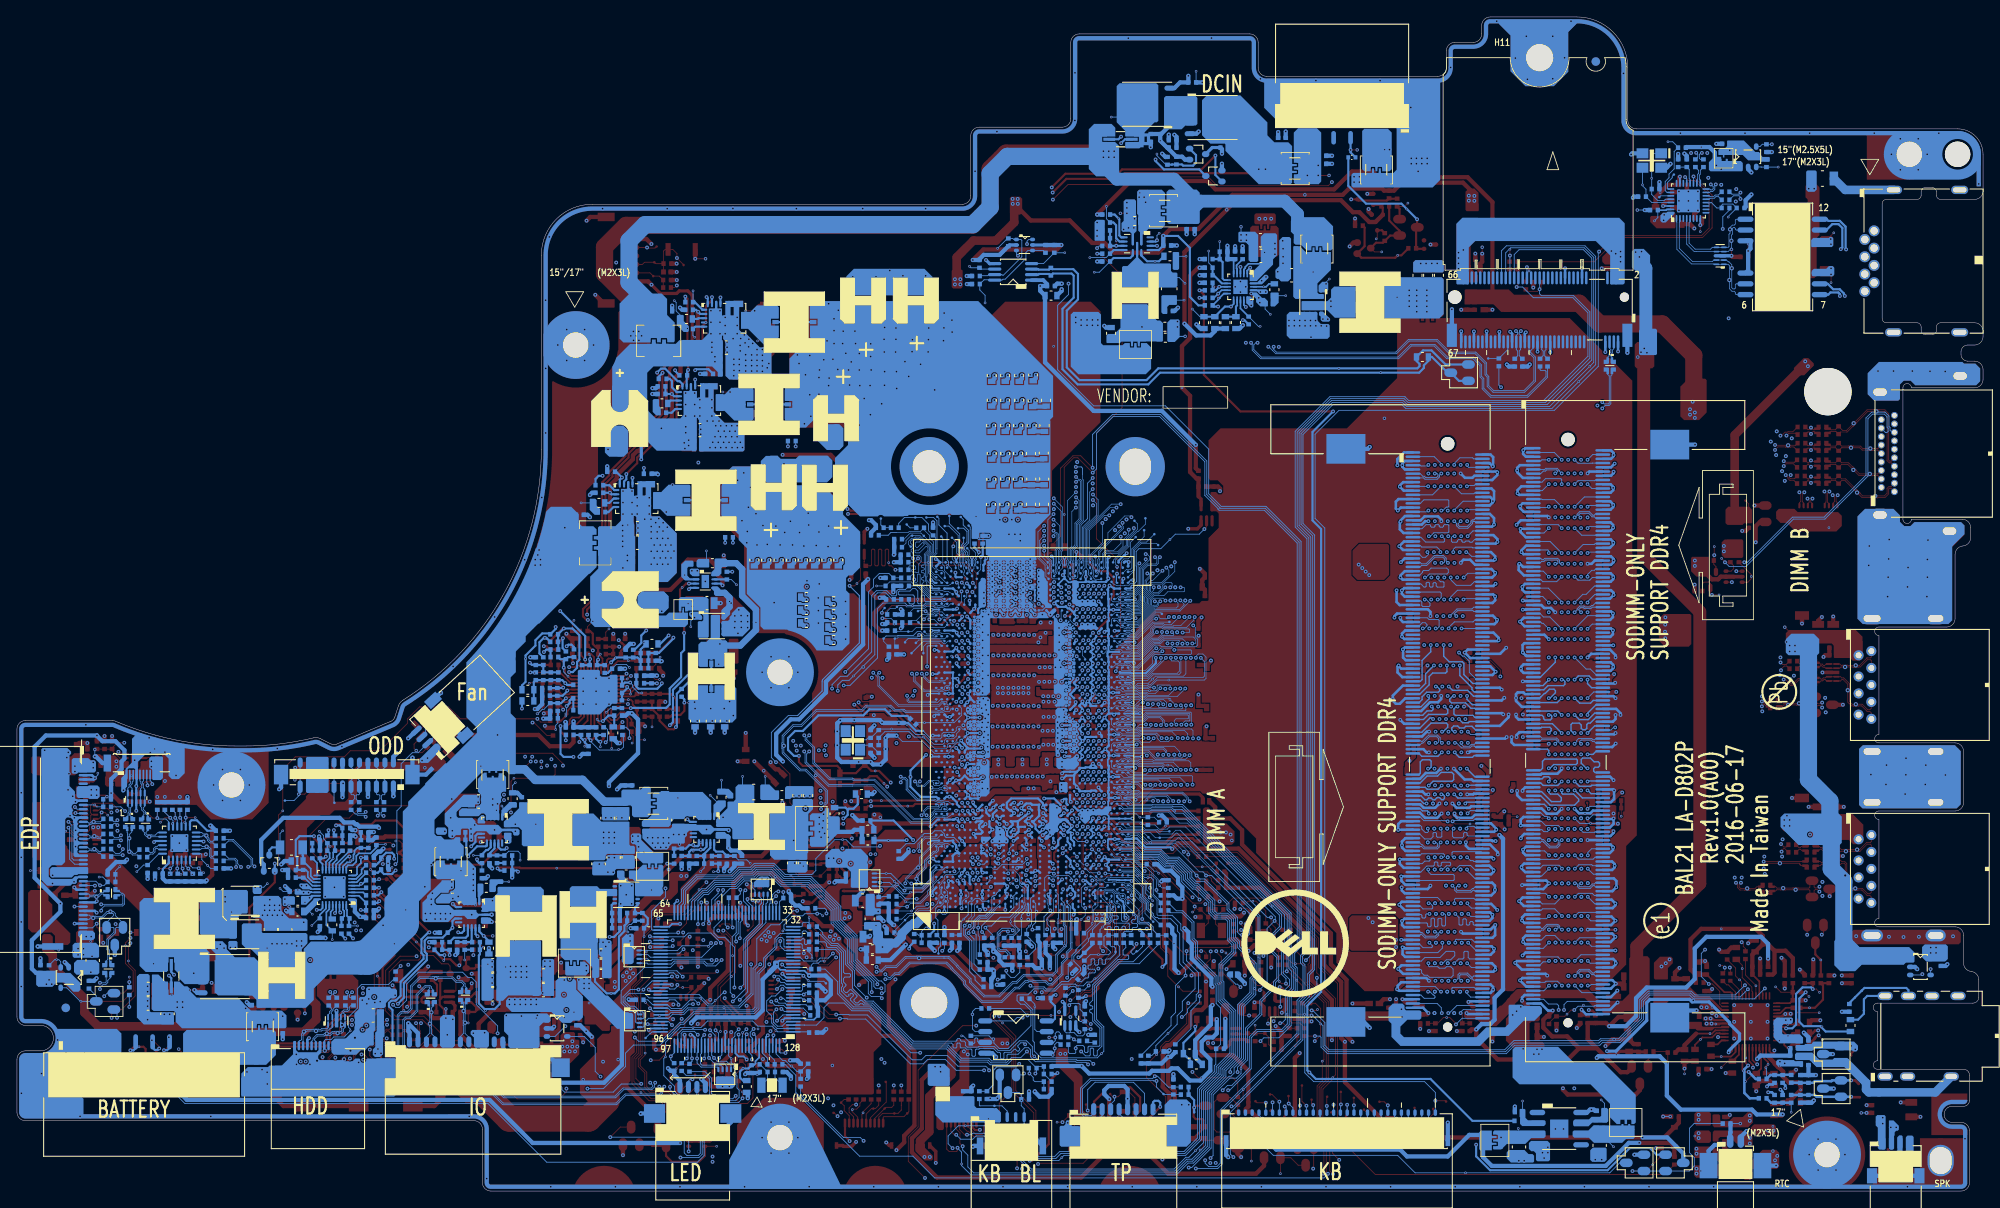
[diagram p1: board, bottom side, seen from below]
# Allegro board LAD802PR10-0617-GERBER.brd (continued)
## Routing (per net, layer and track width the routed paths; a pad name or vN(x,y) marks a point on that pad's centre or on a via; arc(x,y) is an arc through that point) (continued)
USB_PP7_TPNL: length 11.6
  BOTTOM w0.097: R21.1 221.54,26.64 L4.4 221.38,27.14 221.19,27.33 221.19,28.36 221.29,28.46 221.29,29.71 220.46,30.54 220.46,31 220.55,31.1 DA6.3 221.33,31.68 220.51,32.5 220.51,32.66 220.6,32.75 221.23,32.75 221.78,32.21 v3(222.91,32.21) 223.24,32.21 223.4,32.05 JEDP1.37
USB_PP8: length 163.3
  IN2 w0.122: v2(44.91,92.32) 44.63,92.6 44,92.6 41.55,90.15 41.55,41.73 45.48,37.8 45.48,21.04 48,18.53 49.09,18.53 52.46,15.16 72.76,15.16 73.28,15.68 80.6,15.68 81.89,16.98 93.19,16.98 93.81,17.6 93.81,21.64 94.16,21.99 94.16,22.92 98.95,27.71 98.95,29.61 100.92,31.58 101.31,31.58 101.73,32 101.73,32.6 103.54,34.42 107.78,34.42 108.06,34.7 108.27,34.7 109.03,35.46 109.03,36.95 108.86,37.12 108.86,37.59 109.13,37.86 109.41,37.86 v2(109.59,38.04)
  BOTTOM w0.097: RW2.2 43.61,96.91 LW1.2 43.78,96.28 43.9,96.15 43.9,92.87 44.11,92.67 44.57,92.67 v2(44.91,92.32) ; v2(109.59,38.04) 109.72,37.91 109.85,37.91 UC1.AF9
USB_PP8_R: length 2.7
  BOTTOM w0.097: RW2.1 43.61,97.82 LW1.1 43.78,98.37 43.93,98.52 43.93,98.66 43.71,98.88 43.71,99.21 43.55,99.36 JWLAN1.3
USBCOMP: length 2.4
  TOP w0.254: RC66.1 113.48,36.44 v1(113.41,36.37) 113.07,36.37 v2(112.8,36.64)
  BOTTOM w0.254: v2(112.8,36.64) 112.67,36.64 UC1.AB6
VCI_IN1: length 2.8
  TOP w0.102: RE30.1 142.94,17.88 142.67,18.15 142.67,18.38 v2(142.67,18.38) 142.67,18.65 v1(142.39,18.94)
  BOTTOM w0.102: v2(142.67,18.38) 142.67,18.38 142.67,18.15 142.76,18.06 UE1.126
VCIN0_PH: length 182.6
  TOP w0.102: R44.1 109.68,76.35 108.81,77.22 108.81,85.27 107.35,86.73 106.43,86.73 v2(105.02,85.33)
  IN2 w0.127: v2(89.05,11.89) 89.52,12.37 94.33,12.37 95.18,11.51 98.53,11.51 100.31,13.29 110.38,13.29 110.96,13.87 111.78,13.87 v2(111.78,13.87)
  BOTTOM w0.102: C32.1 111.45,14.69 R43.2 R42.2 110.76,13.8 C33.1 ; C32.1 112.65,15.51 114.51,15.51 115.13,14.9 117.11,14.9 117.42,15.21 120.69,15.21 122.25,16.77 126.56,16.77 131.29,21.49 133.32,21.49 135.1,23.27 135.1,24.69 136.58,26.18 RE37.1 ; C32.1 111.64,14.01 v2(111.78,13.87) ; v2(89.05,11.89) 88.85,11.89 86.32,14.43 86.32,18.08 85.59,18.81 82.83,18.81 82.64,18.81 81.83,19.62 81.83,22.98 81.13,23.69 81.13,26.23 81.42,26.53 81.42,28.17 80.67,28.92 80.67,76.54 84.67,80.54 90.01,80.54 90.01,80.61 91.56,82.16 91.56,86.12 97.04,91.6 102.69,91.6 105.03,89.26 105.03,85.33 v2(105.02,85.33)
VCREF0: length 7
  TOP w0.102: CE23.1 RE48.1 142.2,28.6 RE46.2 142.22,29.14 141.87,29.49 v2(141.87,29.49) 141.87,30.13 141.56,30.43 v1(141.56,30.69)
  BOTTOM w0.102: UE1.25 141.35,28.38 141.88,28.91 141.88,29.48 v2(141.87,29.49)
VD_IN1_C: length 150.5
  TOP w0.102: v2(105.01,84.74) 105.02,84.74 106.78,86.51 107.25,86.51 108.38,85.38 v1(108.38,79.81) 108.38,76.05 R44.2
  IN2 w0.127: v2(89.68,11.89) 89.9,12.11 94.23,12.11 95.08,11.26 98.64,11.26 100.41,13.04 110.49,13.04 110.62,13.16 111.77,13.16 v2(112.48,13.87)
  BOTTOM w0.102: v2(105.01,84.74) 104.56,85.19 104.56,89.4 102.59,91.37 97.13,91.37 91.79,86.03 91.79,82.06 90.24,80.51 90.24,80.44 90.11,80.31 84.76,80.31 80.9,76.44 80.9,29.01 81.65,28.26 81.65,26.43 81.35,26.14 81.35,23.83 82.06,23.13 82.06,19.71 82.73,19.04 85.68,19.04 86.55,18.18 86.55,14.52 88.6,12.46 89.11,12.46 v2(89.68,11.89) ; R45.1 C33.2 111.84,12.91 112.03,13.1 112.03,13.42 112.48,13.86 v2(112.48,13.87) 112.48,14.43 C32.2
VIDALERT_N: length 47.6
  IN2 w0.127: v2(159.66,53.42) 159.02,52.78 154.74,52.78 154.33,52.37 145.06,52.37 137.59,59.85 135.59,59.85 135.08,59.35 v2(135.08,59.01)
  BOTTOM w0.102: PR607.1 160.05,54.71 159.66,54.32 v2(159.66,53.42) ; RC153.2 RC152.2 128.65,69.79 129.42,70.57 130.39,70.57 130.72,70.24 130.72,63.28 v1(133.23,60.76) 133.75,60.24 134.54,60.24 135.08,59.7 v2(135.08,59.01)
VIDSCLK: length 57.2
  IN2 w0.127: v2(134.39,59.64) 134.66,59.64 135.37,60.36 137.85,60.36 145.33,52.88 154.12,52.88 154.53,53.29 158.51,53.29 159.21,53.99 162.69,53.99 164.41,52.27 166.7,52.27 167.16,52.73 v2(167.16,53.17)
  BOTTOM w0.102: v2(134.39,59.64) 133.64,59.64 130.39,62.89 130.39,68.72 129.75,69.36 127.15,69.36 126.87,69.08 125,69.08 124.72,69.36 123.56,69.36 UC1.A63 ; v2(167.16,53.17) PR606.1
VIDSOUT: length 57.6
  IN2 w0.127: v2(162.46,52.94) 161.92,53.49 160.44,53.49 159.23,52.27 154.95,52.27 154.54,51.86 144.81,51.86 137.4,59.27 v2(135.76,59.27)
  BOTTOM w0.102: v2(162.46,52.94) 162.25,53.16 162.25,54.45 162.51,54.71 PR609.1 ; UC1.D64 122.09,69.84 122.38,69.54 122.49,69.54 122.5,69.54 122.65,69.54 122.92,69.8 124.16,69.8 125.74,71.38 RC154.2 127.11,70.96 127.96,70.96 128.14,70.78 128.14,70.31 128.24,70.21 128.7,70.21 129.31,70.82 130.53,70.82 131.08,70.26 131.08,63.61 133.97,60.72 134.77,60.72 135.76,59.73 v2(135.76,59.27)
VL: length 3.2
  TOP w0.102: v2(176.85,30.1) v4(175.78,30.1)
  BOTTOM w0.254: PU102.15 177.36,30.61 v2(176.85,30.1) 176.23,29.48 PC126.1
VR_ALERT#: length 1.9
  TOP w0.203: PU602.36 163.79,54.91 PR625.2
VR_CAP: length 6.7
  TOP w0.102: v1(138.58,24.85) 139.12,25.39 v2(139.14,25.39) 139.53,25 CE24.1
  BOTTOM w0.102: TP44.1 136.72,24.74 138.49,24.74 139.14,25.39 v2(139.14,25.39) 139.33,25.58 UE1.18
VR_SCLK: length 1.9
  TOP w0.203: PU602.37 164.19,55 PR618.2
VR_SDA: length 2.1
  TOP w0.203: PU602.35 163.39,55.37 162.74,54.71 PR626.2
VRALERT#: length 9.4
  TOP w0.102: RC92.1 v1(108.85,33.1) 108.85,33.69 108.06,34.48 108.06,38.85 107.49,39.43 v2(106.87,39.43)
  BOTTOM w0.102: v2(106.87,39.43) 106.87,39.5 UC1.AM11
VRAM_ID1: length 36.3
  TOP w0.102: RC60.1 86.89,33.99 86.69,34.19 v1(86.13,34.19) 85.76,34.19 84.6,33.04 RC59.2 84.6,31.51 83.99,30.9 83.99,29.99 84.46,29.52 84.46,28.16 84.88,27.74 v2(84.88,27.73)
  IN2 w0.127: v2(104.29,37.5) 104.29,36.69 101.27,33.68
  IN2 w0.142: 101.27,33.68 100.17,32.58 100.17,32.1 99.45,31.37 98.18,31.37 93.31,26.5 89.52,26.5 88.47,27.55 85.39,27.55 85.17,27.77 84.92,27.77 v2(84.88,27.73)
  BOTTOM w0.089: v2(104.29,37.5) 104.34,37.55 105.37,37.55 105.84,38.02 UC1.AP8
VRAM_ID2: length 26.1
  TOP w0.102: v2(87.51,30.8) 87.52,30.82 87.67,30.82 87.86,30.63 RC61.2 RC62.1
  IN2 w0.127: 100.8,33.59 103.53,36.31 v2(103.53,37.46)
  IN2 w0.142: 100.8,33.59 99.91,32.69 99.91,32.21 99.34,31.64 98.07,31.64 93.81,27.38 91.07,27.38 90.9,27.55 89.46,27.55 88.86,28.15 88.86,29.63 87.69,30.8 v2(87.51,30.8)
  BOTTOM w0.076: UC1.AW7 102.98,37.46 v2(103.53,37.46)
VSA_SEN+: length 52.1
  TOP w0.254: v2(156.42,59.89) PC640.2 157.07,59.9 PR649.2 ; v2(119.16,44.88) 119.16,45.04 119.46,45.34 120.72,45.34 121.05,45.67 125.94,45.67 126.2,45.41 v1(126.83,45.41) v2(131.15,45.41) 131.53,45.41 RC159.2
  IN1 w0.254: v2(156.42,59.89) 156.42,53.28 155.47,52.33 142.01,52.33 138.85,49.17 136.74,49.17 134.69,47.11 133.03,47.11 131.33,45.41 v2(131.15,45.41)
  BOTTOM w0.254: v2(119.16,44.88) 119.16,44.78 UC1.H20 ; v2(156.42,59.89) PC640.2 157.07,59.9 PR649.2
VSA_SEN-: length 58.8
  TOP w0.203: PU602.26 160.44,58.76 160.36,58.68 159.6,58.68 159.02,59.26 156.41,59.26 155.83,59.83 v2(155.83,59.9)
  TOP w0.254: v2(119.12,45.85) 119.12,45.93 119.45,46.25 119.52,46.25 119.94,46.25 120,46.31 120.58,46.31 120.84,46.05 v1(129.94,46.05) 131.14,46.05 v2(131.2,45.99) RC160.1
  IN1 w0.254: v2(131.2,45.99) 131.38,45.99 132.88,47.49 134.53,47.49 136.59,49.55 138.69,49.55 141.85,52.71 155.31,52.71 156.04,53.43 156.04,59.59 155.94,59.69 155.94,59.8 v2(155.83,59.9)
  BOTTOM w0.254: PC649.1 PC650.2 158.84,59.51 158.59,59.26 156.37,59.26 155.83,59.79 v2(155.83,59.9) ; v2(119.12,45.85) 119.12,45.66 UC1.H21
VTTREF_1.2V: length 2
  BOTTOM w0.203: PU200.4 87.99,108.77 88.05,108.83 88.05,109.21 PC210.1
WHITE_LED_BAT: length 24.8
  TOP w0.102: v2(151.5,10.76) 151.52,10.76 151.52,11.71 ZT16.1 ; Q4.1 160.73,7.55 v2(161.92,6.36)
  BOTTOM w0.102: v2(161.92,6.36) 153.59,6.36 153.19,5.96 153.19,4.5 152.88,4.18 151.55,4.18 151.3,4.43 151.3,10.56 v2(151.5,10.76) 151.52,10.76 151.7,10.94 JLED1.3
WHITE_LED_PWR: length 133.4
  TOP w0.102: JPWR1.5 157.59,111.31 v2(157.58,111.3) 157.53,111.24 156.62,111.24 ZT1.1 ; Q15.1 175.91,18.75 175.77,18.61 v2(175.2,18.61)
  IN1 w0.127: v2(157.58,111.3) 156.34,110.06 156.34,99.16 159.19,96.31 159.19,93.56 165.14,87.61 165.14,71.82 171.84,65.12 171.84,64.49 172.84,63.5 172.84,56.81 182.09,47.57 182.74,47.57 187.5,42.81 187.5,41.41 187.99,40.91 187.99,40.28 189.62,38.65 189.62,34.44 189.88,34.17 189.88,32.34 190.33,31.9 191.86,31.9 v2(192.07,31.68)
  IN2 w0.127: v2(192.07,31.68) 191.86,31.9 190.71,31.9 189.25,30.43 189.25,24.78 187.54,23.07 v2(187.54,21.98)
  BOTTOM w0.102: v2(175.2,18.61) 175.2,19.48 177.72,22 177.72,24.65 178.28,25.2 178.72,25.2 179.33,25.81 184.55,25.81 185.96,24.4 185.96,22.48 186.8,21.65 187.21,21.65 v2(187.54,21.98)
WLAN_RADIO_DIS#: length 227
  IN2 w0.127: v2(88.42,4.01) 89.32,4.91 98.73,4.91 99.75,3.89 110.06,3.89 111.92,5.74 113.6,5.74 116.4,8.54 119.18,8.54 124.8,14.16 124.8,14.26 124.8,16.34 129.04,20.58 129.04,24.45 128.71,24.78 128.71,28.5 126.9,30.31 v2(126.9,33.55)
  BOTTOM w0.076: RC3.1 127.84,33.55 v2(126.9,33.55) 126.89,33.55 126.52,33.92 125.7,33.92 125.32,33.92 124.28,34.96 124.28,35.36 123.78,35.85 123.78,36.16 123.3,36.64 123.24,36.64 UC1.B7
  BOTTOM w0.102: JWLAN1.48 56.8,110.92 56.21,111.5 46.95,111.5 45.69,110.25 45.69,97.47 v1(47.69,95.48) 50.84,92.32 68.1,92.32 68.57,92.79 76.66,92.79 80.21,89.24 80.21,78.76 78.84,77.38 78.84,26.11 78.97,25.98 79.44,25.51 79.44,22.96 80.23,22.17 80.23,17.83 88.79,9.28 88.79,4.37 v2(88.42,4.01)
XCLK_BIASREF: length 7.1
  BOTTOM w0.076: UC1.E42 120.47,56.95 120.47,56.14
  BOTTOM w0.089: 123.34,55.25 122.63,55.25 122.62,55.25 122.38,55.25 122.37,55.25 122.29,55.25 121.98,55.25 121.97,55.25 121.73,55.25 121.72,55.25 121.64,55.25 121.41,55.25 121.4,55.25 121.36,55.25 120.47,56.14
  BOTTOM w0.102: 123.34,55.25 v1(124.86,55.25) 125.67,55.25 RC76.1
XDP_HOOK0: length 1.1
  TOP w0.102: TPC32.1 80.77,29.9 RC148.2
XDP_ITP_PMODE: length 12.6
  BOTTOM w0.076: UC1.E8 120.75,37.72 121.14,37.34 122.31,37.34 122.52,37.13 122.52,36.76 122.8,36.48 122.8,36.33 123.1,36.02 123.1,35.69 123,35.58 123,35.02 123.15,34.88 123.15,34.3 123.3,34.14 123.3,33.97 124.16,33.1 125.5,33.1 126.07,32.53 126.58,32.53 TPC7.1 128.4,30.7 RC143.2
XDP_OBS0_R: length 3.6
  BOTTOM w0.076: UC1.C55 122.62,65 125.54,65 TP15.1
XDP_OBS1_R: length 5.3
  BOTTOM w0.076: UC1.D55 122.09,64.88 122.38,64.59 122.62,64.59 122.86,64.82 125.02,64.82
  BOTTOM w0.102: TP16.1 125.02,64.82
XDP_OBS2_R: length 3.2
  BOTTOM w0.076: UC1.B54 123.15,64.64 124.56,64.64 124.99,64.22 TP17.1
XDP_OBS3_R: length 5.3
  BOTTOM w0.076: 125.38,65.18 122.44,65.18 UC1.C56
  BOTTOM w0.102: TP18.1 127.15,64.8 126.77,65.18 125.38,65.18
XDP_PRDY#: length 3.7
  BOTTOM w0.076: UC1.D56 121.85,65.66 121.98,65.79 122.87,65.79 122.91,65.84 123.26,65.84 123.33,65.88 123.7,65.88 123.86,65.71 124.58,65.71 TPC31.1
XDP_PREQ#: length 10.9
  TOP w0.102: v2(123.09,67.43) 123.09,68.36 123.79,69.06 v1(126.26,69.06) 128.72,69.06 129.58,68.2 v2(129.88,68.2)
  BOTTOM w0.076: v2(123.09,67.43) 122.9,67.43 122.62,67.71 122.51,67.71 122.28,67.6 122.09,67.6 UC1.D61 ; v2(129.88,68.2) 129.83,68.25 129.83,68.51 TPC30.1
XDP_PRSENT_CPU: length 2.1
  BOTTOM w0.102: TPC33.1 130,78.58 RC144.1 RC175.2
XDP_SPI_IO2: length 12.6
  BOTTOM w0.076: 102.97,29.02 102.97,29.08 RC41.1
  BOTTOM w0.102: 102.97,29.02 102.97,28.97 102.82,28.82 102.48,28.82 102.32,28.66 TPC9.1 102.32,28.03 102.98,27.37 103.4,27.37 103.5,27.27 103.5,26.85 103.6,26.75 103.8,26.75 103.91,26.85 103.91,27.3 104.01,27.4 104.22,27.4 104.33,27.3 104.33,26.78 104.45,26.65 104.68,26.65 104.78,26.75 104.78,27.3 104.88,27.4 105.1,27.4 105.2,27.3 105.2,26.75 105.31,26.65 105.47,26.65 105.57,26.55 105.57,26.27 105.47,26.17 104.83,26.17 104.7,26.03 104.7,25.84 104.8,25.74 105.39,25.74 105.49,25.63 105.49,25.24 105.6,25.14 105.88,25.14 106.33,24.69 106.5,24.69 RC145.1
XDP_SPI_SI: length 3.7
  BOTTOM w0.076: 100.27,29.02 100.48,29.23 RC40.1 ; RC139.2 99.14,29.02
  BOTTOM w0.102: 99.14,29.02 99.14,28.83 99.7,28.28 TPC8.1 100.17,27.95 100.31,27.95 100.5,28.15 100.5,28.29 100.09,28.7 100.09,28.84 100.27,29.02
XTAL24_IN: length 16.3
  BOTTOM w0.076: UC1.E37 120.75,54.28 121.09,53.94 121.09,53.69 121.42,53.36 122.31,53.36 122.49,53.18 122.49,52.9 122.69,52.7 123.72,52.7 124.89,53.87
  BOTTOM w0.102: 124.89,53.87 125.92,53.87 126.55,54.5 v1(128.73,54.5) 130.13,54.5 RC80.2 131.17,53.46 CC6.1 131.49,53.46 131.72,53.23 133.13,53.23 YC1.3
XTAL24_OUT: length 12.3
  BOTTOM w0.076: UC1.E35 121.08,53.25 121.08,53.11 121.41,52.77 122,52.77 122.14,52.63 122.14,52.33 122.28,52.19 123.63,52.19 124.79,53.35
  BOTTOM w0.102: RC81.2 RC80.1 129.53,54.19 126.68,54.19 126.04,53.55 v1(124.99,53.55) 124.79,53.35
XTAL24_OUT_R: length 2.8
  BOTTOM w0.102: YC1.1 131.91,52.6 CC7.1 131.17,52.6 RC81.1
N16875033: length 6.8
  TOP w0.102: UC6.2 86.82,18.52 CC14.1 RC103.2 ; RC192.1 84.25,17.28 84.25,18.14 DZ4.2 RC103.2 ; v1(85.86,19.56) RC103.2
N17003698: length 2.1
  BOTTOM w0.102: TP71.1 157.25,18.56 157.21,18.56 156.99,18.78 UE1.96
N17003752: length 3.2
  TOP w0.102: v2(60.77,54.19) 60.44,53.87 RD23.2
  BOTTOM w0.102: v2(60.77,54.19) 60.45,53.87 JDIMM1.134
N17004366: length 2.6
  TOP w0.102: v2(43.39,54.69) 43.45,54.63 RD24.2
  BOTTOM w0.102: JDIMM2.134 43.9,54.38 43.58,54.69 v2(43.39,54.69)
N17230024: length 1.4
  BOTTOM w0.102: TP48.1 38.02,117.4 UL1.27
N17230026: length 2.4
  BOTTOM w0.102: UL1.25 37.13,118.2 37.23,118.3 37.23,118.96 36.66,119.53 36.66,119.72 TP49.1
N17231159: length 3
  BOTTOM w0.102: RL2.2 38.36,114.84 v1(38.76,114.45)
  BOTTOM w0.203: UL1.31 37.28,115.8 37.38,115.71 38.35,115.71 RL2.2
N17237617:
  vias: v1(202.39,28.66) v2(198.33,29.5) v2(198.33,28.92) v2(198.91,29.5) v2(198.91,28.92) v2(199.47,29.17) v2(200.06,29.17) v2(200.64,29.17) v2(201.22,29.17) v2(201.81,29.17)
N17268429: length 3.3
  TOP w0.102: PR791.2 186.26,40.78 186.77,41.29 v1(187.22,41.29)
  TOP w0.254: PR791.2 186.26,40.41 PQ720.1 186.26,39.4 PR790.1
N17273333: length 4.9
  TOP w0.102: v1(37.19,15.13) RA5.2 37.31,16.46 RA6.1 38.87,16.16 39.52,15.51 QA1.3
N17274212: length 2.6
  BOTTOM w0.102: v1(24.16,120.79) RL7.2 26.16,120.79 26.18,120.81 UL3.3
N17415515: length 0.6
  TOP w0.102: v2(70.01,122.85) v1(70.58,122.85)
N17421985: length 4.2
  TOP w0.102: v2(164.93,53.21) v1(164.93,52.47)
  TOP w0.254: v2(164.93,53.21) 164.48,53.65 PR618.1
  BOTTOM w0.254: PC695.2 164.93,52.93 v2(164.93,53.21) 165.12,53.21 165.37,53.46 PR601.2 166.24,53.8 PR606.2
N17563414: length 5
  TOP w0.102: UA1.4 28.39,23.5 28.44,23.55 28.44,24.06 28.49,24.11 28.49,24.68 v1(28.72,24.91) 29.18,25.37 29.18,26.31 RA9.1
N17751623: length 2
  BOTTOM w0.102: v1(219.77,38.27) 220.29,37.75 C13.1 220.29,36.47 R56.2
N17772976: length 9.1
  IN2 w0.508: v2(92.52,124.99) 92.1,125.41 v2(92.1,130.78)
  BOTTOM w0.102: PR778.1 v1(92.82,132.1)
  BOTTOM w0.508: PQ740.4 92.78,124.73 v2(92.52,124.99) ; v2(92.1,130.78) PR778.1
N17902584: length 5.4
  TOP w0.102: RE58.2 126.7,9.35 ZT60.1 127.27,8.78 129.63,8.78 129.74,8.68 JDEG1.1
N17902623: length 3.9
  TOP w0.102: JDEG1.9 133.74,8.89 134.32,9.48 134.32,10.05 ZT58.1 134.33,10.81 RE56.2
N17902681: length 5.7
  TOP w0.102: JDEG1.4 131.24,8.63 129.37,10.5 129.37,12.82 ZT55.1
N17902688: length 3.9
  TOP w0.102: RE57.2 132.48,10.36 132.48,10.05 132.86,9.67 133.31,9.67 v1(133.37,9.61) 133.39,9.58 133.39,9.38 132.74,8.72 132.74,8.02
N17902690: length 3.2
  TOP w0.102: RE55.2 131.15,10.31 132.1,9.35 v1(132.1,9.23) 132.1,9.16 132.24,9.03 JDEG1.6
N18234461: length 8.4
  TOP w0.102: R30.1 184.11,51.72 184.56,51.72 v4(184.81,51.96) 185.06,52.22 185.06,52.73 D8.1 183.66,54.12 183.66,54.88 v2(183.73,54.95) 183.87,54.95 184.21,54.6 184.5,54.6 R55.1
  BOTTOM w0.102: v2(183.73,54.95) 183.73,53.96 JFAN1.3
N18336277: length 3.5
  TOP w0.102: v1(92.35,4.84) 91.97,5.23 R37.1 91.78,5.99 Q13.1
N18336387: length 4.5
  TOP w0.102: v1(86.2,7.3) 86.2,7.7 R35.2 87.84,8.45 C18.1 88.6,9.09 Q12.3
N18359999: length 2.4
  BOTTOM w0.102: U1.3 226.74,27.07 226.97,27.3 v1(227.21,27.3) 227.45,27.3 R57.2
N18390627: length 2.6
  TOP w0.102: v1(201.62,20.27) PQ710.2
  TOP w0.254: PQ710.2 200.4,21.68 PQ711.1
N18517471: length 3
  TOP w0.102: UZ3.12 167.78,21.47 167.34,21.04 v1(167.34,20.47) 167.34,20.34 167.16,20.15 CZ10.1
N18517492: length 2.7
  TOP w0.102: CZ11.1 165.5,20.6 165.68,20.78 165.88,20.78 v1(166.2,21.1) 166.98,21.88 UZ3.10
N18941428: length 2
  TOP w0.102: v1(156.1,60.34) 156.61,60.34 157.05,60.79 PC640.1
  TOP w0.254: PR646.2 157.08,60.78 PC640.1
N18941436: length 2.6
  TOP w0.102: v1(156.04,62.98) 156.55,62.47 156.55,62.12 156.99,61.68 PC601.1
  TOP w0.254: PR652.2 157.08,61.67 PC601.1
N18941447: length 3.9
  TOP w0.203: PU602.28 160.58,57.96 160.57,57.97 v1(159.79,57.97) 159.51,57.97 159.28,57.74 159.28,57.38 158.78,56.89 PR636.1
  TOP w0.254: PC632.1 PR636.1
N18941448: length 2.1
  TOP w0.102: v1(156.99,54.76) PR641.1
  TOP w0.254: PC632.2 157,55.97 PR641.1
N18941457: length 4.6
  TOP w0.102: v2(153.18,57.61) v1(152.67,57.61)
  TOP w0.254: v2(153.18,57.61) 153.18,56.63 153.65,56.16 154.62,56.16 154.83,55.95 PR642.2
  BOTTOM w0.254: PH604.1 153.18,57.99 v2(153.18,57.61)
N18941471: length 7.7
  TOP w0.254: v2(164.23,53.17) 164.1,53.17 163.59,53.68 PR625.1
  BOTTOM w0.102: PR607.2 160.37,53.68 160.37,52.35 160.64,52.09 v1(160.93,52.09) 160.99,52.02 163.22,52.02 164.23,53.04 v2(164.23,53.17)
  BOTTOM w0.254: v2(164.23,53.17) 164.48,53.42 PR604.2
N18941481: length 3.5
  TOP w0.254: PR626.1 162.71,53.38 v2(163.09,53)
  BOTTOM w0.102: v2(163.09,53) v1(163.09,52.41)
  BOTTOM w0.254: v2(163.09,53) 163.24,53 163.59,53.36 PR605.2 PR626.1
N18941485: length 3
  TOP w0.203: PR616.2 166.71,55.15 166.71,55.59 166.44,55.86 165.6,55.86 165.39,56.06 PU602.40
N18941487: length 2.3
  TOP w0.203: PR612.2 166.24,54.71 164.99,55.96 PU602.39
N18941496: length 2.1
  TOP w0.203: PR678.2 164.59,55.49 PU602.38
N18941497: length 4.9
  TOP w0.203: PU602.34 162.99,55.64 v2(162.79,55.44)
  BOTTOM w0.102: v2(162.79,55.44) 163.26,55.44 v1(163.47,55.64)
  BOTTOM w0.254: PC603.1 161.45,54.87 PR602.1 162.14,56.09 v2(162.79,55.44)
N18941498: length 4.6
  TOP w0.102: v1(161.75,52.22) PC604.1
  TOP w0.203: PU602.33 162.59,55.89 161.83,55.13 PR603.1
  TOP w0.254: PR603.1 161.83,53.69 PC604.1
N18941511: length 6.6
  TOP w0.102: PR608.1 159.42,53.81 159.21,53.61 159.21,52.98 v1(159.34,52.85)
  TOP w0.203: PU602.32 162.19,55.96 161.79,55.56 161.15,55.56 160.63,56.09 160.34,56.09 159.9,55.65 159.9,54.58 159.7,54.37 159.6,54.37 PR608.1
N18941513: length 6.8
  TOP w0.102: v1(157.88,53.23) 158.39,53.23 158.96,53.8 158.96,54.63 159.41,55.08 PR611.1
  TOP w0.203: PR611.1 159.42,55.63 160.04,56.26 160.04,56.27 160.24,56.47 160.71,56.47 161.29,55.89 161.58,55.89 161.79,56.1 PU602.31
N18941562: length 4.5
  TOP w0.203: PC630.1 v1(159.8,62.56) 159.86,62.5 161.03,62.5 161.79,61.74 PU602.20
  TOP w0.254: PC630.1 157.97,62.56 PR640.1
N18941580: length 22.8
  IN1 w0.254: v2(148.37,76.48) 148.37,76.42 147.02,75.08 147.02,70.21 150.74,66.49 157.31,66.49 v2(157.68,66.12)
  BOTTOM w0.254: PR657.2 159.06,63.85 158.26,64.65 158.26,65.54 v2(157.68,66.12) ; PH605.1 v2(148.37,76.48)
N18941616: length 2.2
  TOP w0.102: PC639.2 162.45,65.93 v1(162.07,66.31)
  TOP w0.254: PC639.2 PR645.1
N18941625: length 2.2
  TOP w0.102: PC647.2 166.39,67.14 v1(166.2,67.33)
  TOP w0.254: PC647.2 166.38,66.06 PR650.2
N18941629: length 3.5
  BOTTOM w0.102: v1(159.66,61.76) 160.02,62.12 161.2,62.12 PC629.2
  BOTTOM w0.254: PC629.2 162.2,61.12 PR639.1
N18941656: length 1.9
  TOP w0.102: PR632.2 170.78,61.16 v1(170.84,61.11)
  TOP w0.254: PR632.2 169.8,61.17 PC627.1
N18941661: length 53.9
  IN1 w0.254: v2(171.34,61.19) 170.6,61.19 170.26,61.53 170.26,64.46 169.95,64.76 169.55,64.76 169.55,64.75 168.87,64.75 167.88,65.74 167.88,66.56 167.59,66.84 167.28,66.84 163.54,70.58 163.54,77.84 162.82,78.56 162.82,83.63 160.02,86.43 159.47,86.43 158.44,87.46 156.56,87.46 156.01,86.91 142.74,86.91 141.33,88.32 140.53,88.32 v2(140.05,87.84)
  BOTTOM w0.102: PH602.1 v2(140.05,87.84)
  BOTTOM w0.254: PR628.2 v2(171.34,61.19)
N18941667: length 3.4
  TOP w0.203: PC627.2 167.84,61.17 166.62,59.96 PU602.8
  TOP w0.254: PR638.2 PC627.2
N18941711: length 2.1
  TOP w0.102: v1(170.55,56.31) 169.89,56.97 PC621.2
  TOP w0.254: PC621.2 PR623.1
N18941712: length 4.1
  TOP w0.203: PU602.5 166.63,58.76 166.8,58.58 167.64,58.58 168.1,59.04
  TOP w0.254: 168.1,59.04 PR622.2 168.13,59.08 168.98,59.08 ; 168.98,59.08 PR621.2 ; 168.98,59.08 PR623.2
N18941722: length 5.3
  TOP w0.203: v2(167.15,58.13) 167.15,58.13 167.02,58.25 166.67,58.25 166.56,58.36 PU602.4
  BOTTOM w0.102: v1(170.47,56.29) 169.93,56.82 169.74,56.82 PC616.2
  BOTTOM w0.254: PC616.2 PR617.2 167.72,57.56 167.15,58.12 v2(167.15,58.13)
N18941723: length 2.3
  BOTTOM w0.102: v1(168.36,54.44) 168.36,54.95 168.1,55.2 PC614.2
  BOTTOM w0.254: PR617.1 168.1,56.63 PC614.2
N18941731: length 2.4
  TOP w0.203: PR610.2 167.86,58.19 167.35,57.67 166.96,57.67 166.7,57.92 166.53,57.92 166.49,57.96 PU602.3
N18941735: length 4.9
  TOP w0.203: v2(167.07,57.21) 166.95,57.21 166.6,57.56 PU602.2
  BOTTOM w0.102: v1(167.15,56.28) 167.07,56.36 v2(167.07,57.21)
  BOTTOM w0.254: v2(167.07,57.21) 167.06,57.21 166.71,57.56 166.71,57.87 166.45,58.12 PC613.2 PR613.2
N18941759: length 2.5
  TOP w0.102: v1(171.47,59.9) 171.4,59.97 PC617.2
  TOP w0.254: PC617.2 PR621.1
N18941760: length 2.1
  BOTTOM w0.102: v1(162.39,56.47) 161.89,56.97 PC631.1
  BOTTOM w0.254: PC631.1 PR630.2
N18941767: length 2.1
  TOP w0.102: v1(157.96,64.72) PR644.1
  TOP w0.254: PC630.2 157.97,63.47 PR644.1
N18941770:
  vias: v1(153.14,72.66)
N18941771: length 1.5
  BOTTOM w0.102: PR619.1 v1(150.58,75.52)
N18941791: length 52.7
  TOP w0.254: PR631.2 168.1,56.41 PR610.1 167.8,57.27 167.48,56.96 v2(167.48,56.79)
  IN2 w0.254: v2(167.48,56.79) 167.98,57.28 167.98,62.09 166.14,63.93 166.14,64.28 165.44,64.98 165.44,67.96 164.77,68.63 164.77,70.1 162.82,72.05 162.82,83.06 163.71,83.95 163.71,85.49 162.8,86.4 162.02,86.4 161.21,87.21 161.21,88.25 153.23,96.22 152.52,96.22 v2(151.91,96.83)
  BOTTOM w0.254: v2(151.91,96.83) 151.8,96.94 150.34,96.94 PH601.2
N18941811: length 30.9
  TOP w0.254: v2(163.98,63.77) 164.5,64.3 PR635.1 164.61,65.16 PR647.2
  IN2 w0.254: v2(163.98,63.77) 163.79,63.96 163.79,70.37 162.44,71.71 162.44,83.22 163.33,84.1 163.33,85.34 162.64,86.02 161.56,86.02 160.84,85.3 v2(157.96,85.3)
  BOTTOM w0.254: PH603.2 v2(157.96,85.3)
N18941826: length 3.2
  BOTTOM w0.762: 148.4,68.36 147.85,68.92 v1(147.85,69.55) 147.85,69.99 148.42,70.57 148.99,70.57
N18941830: length 5.3
  IN1 w0.762: 151.58,68.26 151.09,68.75 151.09,70.44 151.63,70.99 151.63,71.84
  BOTTOM w0.102: v1(152.42,66.57) 152.42,67.26 152.04,67.65 v2(151.98,67.65)
  vias: v2(151.66,73.17) v2(152.29,73.17) v2(152.36,68.09)
N18941848: length 2.9
  BOTTOM w0.102: PR679.1 147.64,72.14 v1(147.02,71.52)
  BOTTOM w0.254: PR679.1 148.18,72.16 PU606.7
N18941869: length 11.7
  TOP w0.254: PR624.1 154.64,54.95 v2(154.89,54.95)
  BOTTOM w0.254: v2(154.89,54.95) 154.53,55.31 v1(154.53,56.72) 154.53,59.12 152.79,60.86 150.39,60.86 150,61.25 PL601.3
N18944084: length 22.4
  IN2 w0.254: v2(155.04,65.54) 154.58,65.99 154.58,71.26 153.47,72.36 153.47,75.39 151.78,77.08 150.79,77.08 150.45,77.42 150.45,81.3 v2(150.65,81.49)
  BOTTOM w0.254: PR661.1 156.03,64.54 v2(155.04,65.54) ; PL603.3 v2(150.65,81.49)
N18944130: length 1.7
  BOTTOM w0.254: PU605.5 154.24,92.25 154.68,91.81 PC671.2
N18944131: length 1.4
  BOTTOM w0.254: PU605.3 154.79,93.25 PR672.2
N18944141: length 1.5
  BOTTOM w0.254: PC655.2 162.13,80.1 161.54,80.69 PU603.5
N18944142: length 1.6
  BOTTOM w0.254: PU603.3 161.51,81.69 162.03,81.18 PR660.2
N18944143: length 1.4
  BOTTOM w0.102: PR660.1 v1(165.36,81.18)
N18944153: length 1.8
  BOTTOM w0.254: PR659.1 162.01,83.26 161.44,82.69 PU603.1
N18944154: length 2.5
  BOTTOM w0.102: v1(151.95,100.72) 152.17,100.93 PC663.2
  BOTTOM w0.254: PU604.5 151.9,101.96 PC663.2
N18944155: length 1.4
  BOTTOM w0.254: PU604.3 151.52,102.96 151.61,102.88 PR665.2
N18944156: length 2.5
  BOTTOM w0.102: v1(154.36,105.03) 154.15,104.82 154.15,103.82 153.64,103.31 PR665.1
N18944237: length 3
  BOTTOM w0.102: v1(152.15,106.19) PR664.1
  BOTTOM w0.254: PU604.1 151.04,103.96 151.94,104.86 PR664.1
N18944256: length 2.5
  BOTTOM w0.254: PU605.1 154.09,94.25 154.64,94.81 154.64,95.54 154.91,95.81 PR671.1
N18987516: length 19.1
  TOP w0.254: v2(180.86,27.84) 180.86,27.9 PD102.2
  IN2 w0.254: v2(177.64,39.12) 176.87,38.35 176.87,34.82 179.27,32.42 179.27,29.45 180.86,27.85 v2(180.86,27.84)
  BOTTOM w0.102: PR122.1 177.06,38.68 PR121.2
  BOTTOM w0.254: PR121.2 177.38,38.68 177.64,38.94 v2(177.64,39.12) ; v2(180.86,27.84) 180.86,28.45 PR120.2 181.73,28.46 PR114.2 PC128.1
N19006308: length 1.9
  TOP w0.102: v1(54.95,44.16) RD11.1
  TOP w0.508: RD11.1 CD30.2
N19034361: length 1.5
  TOP w0.102: CZ3.1 133.81,40.63 UZ1.6
N19055432: length 3.9
  BOTTOM w0.102: v1(217.76,37.67) 216.98,38.45 RX6.1 215.15,39.79 UX2.24
N19055471: length 3.4
  BOTTOM w0.102: RX5.1 209.07,38.06 v1(209.41,38.4) 210.1,39.1 210.1,39.69 210.21,39.79 UX2.7
N19675639: length 2.8
  TOP w0.102: UX1.6 216.55,51.07 216.49,51.14 215.79,51.14 215.73,51.07 CX3.1 215.36,51.55 215.67,51.86 v1(215.67,52.15)
N19910104: length 2.1
  TOP w0.102: v1(150.32,28.85) 150.41,28.93 CE18.1 RE27.1
N23700319: length 17.6
  TOP w0.254: PD4.2 66.82,111.15 PR6.2 66.87,113.54 PQ6.1 66.76,113.71 v2(66.76,114.64)
  BOTTOM w0.254: PL2.1 74.87,118.57 72.77,116.48 68.6,116.48 v1(67.97,115.84) v2(66.76,114.64)
N27266810: length 26.7
  IN2 w0.508: v2(93.73,131.55) 91.59,131.55 89.34,129.3 89.34,122.8 v2(89.77,122.37) 90.24,122.84 93.62,122.84 v2(95.38,124.61)
  BOTTOM w0.381: PC742.1 89.96,123.1 90.91,123.1 PQ709.1
  BOTTOM w0.508: v2(93.73,131.55) PR778.2 94.71,130.78 95.38,130.1 PQ718.4 ; PC744.1 PR762.1 95.13,124.35 v2(95.38,124.61) ; PC742.1 89.77,122.9 v2(89.77,122.37)
N27286345: length 4.1
  BOTTOM w0.102: PR743.2 200.87,42.18 v1(200.55,42.5)
  BOTTOM w0.254: PD704.1 202.14,40.22 201.82,40.54 PR743.2
N28424999: length 6.2
  BOTTOM w0.076: TP30.1 99.75,78.73 99.75,78.03 100.89,76.89 100.89,76.11 102.57,74.44 102.57,74.21 UC1.AW71
N28425002: length 7.4
  BOTTOM w0.076: TP31.1 98.8,78.66 99.68,77.78 99.77,77.78 100.73,76.82 100.73,76.04 102.33,74.44 102.33,73.96 102.13,73.76 UC1.AW70
N28483977: length 5
  TOP w0.254: PR13.2 186.37,22.6 186.37,21.39 v1(186.27,21.29) 186.08,21.1 PR2.1 ; PR13.2 186.3,22.89 PQ1.2 ; PR13.2 186.49,22.73 PR12.2
N28483985: length 2.8
  TOP w0.254: PQ1.3 185.63,23.54 185.88,23.8 185.88,24.4 PR5.2
N28484391: length 4.5
  TOP w0.102: PR28.2 v1(178.67,19.83)
  TOP w0.254: PQ2.3 178.3,22.27 PC16.1 177.59,21.4 177.87,21.12 PR28.2
N28484395: length 4.2
  TOP w0.102: v1(176.65,21.29) 176.65,21.53 PC16.2
  TOP w0.254: PC16.2 PR29.1 177.91,23.33 178.33,22.92 PQ2.2
N28484412: length 5.2
  TOP w0.254: 181.87,22.74 181.69,22.92 PQ2.5 ; 181.87,22.74 181.97,22.83 PR31.1 ; 181.87,22.74 182.04,22.57 182.04,21.96 181.4,21.32 PR33.2
N28484439: length 4.1
  TOP w0.102: PR32.1 176.56,26.55 v1(176.36,26.75)
  TOP w0.254: PC14.2 178.93,27.21 178.93,26.31 PQ3.2 178.87,26.25 177.9,26.25 PR32.1
N28484451: length 7.1
  TOP w0.254: PR10.2 182.43,21.99 182.68,22.24 PQ1.6 184.07,22.24 184.17,22.34 184.17,22.7 183.98,22.89 PQ1.5 182.65,22.89 182.35,23.19 182.35,24.35 PR7.1
N28714500: length 1.8
  BOTTOM w0.203: PU703.3 191.06,35.23 PR769.2
N28714504: length 1.7
  BOTTOM w0.203: PU703.4 190.87,35.63 PR770.2
N28714507: length 7.6
  BOTTOM w0.381: 94.53,125.93 94.52,125.94
  BOTTOM w0.508: 96.2,125.43 96.93,124.69 97.05,124.69 ; 97.05,124.69 PR763.1 ; 97.05,124.69 v1(97.05,123.89) 96.24,123.08 PC744.2 96.04,122.92 PR737.1 94.47,122.01 94.12,121.67 PQ709.3
N28714524: length 4.6
  BOTTOM w0.102: PC750.1 v1(194.71,29.66)
  BOTTOM w0.203: PC750.1 195.41,31.39 195.41,32.89 195.06,33.25 PU703.27
N28714534: length 0.9
  BOTTOM w0.254: PR754.1 191.33,41.86 191.35,41.88 PC752.2
N28714559: length 2.2
  BOTTOM w0.203: PR774.2 190.72,37.52 191.82,36.43 PU703.6
N28714562: length 2.6
  BOTTOM w0.203: PU703.7 191.89,36.83 191.25,37.46 191.25,37.92 PR775.2
N28714564: length 6.6
  IN1 w0.508: v2(200.28,35.97) 199.48,35.17 199.48,33.45 199.84,33.09 v2(200.16,33.09)
  BOTTOM w0.102: PC721.1 200.5,35.33 v1(200.87,35.71)
  BOTTOM w0.508: PC721.1 199.74,35.42 v2(200.28,35.97) ; v2(200.16,33.09) 200.05,32.98 PR771.2
N28714572: length 4.7
  BOTTOM w0.203: PU703.18 196.92,36.83 197.25,37.15 197.25,38.03 PC757.2
  BOTTOM w0.254: PC757.2 198.15,39.52 198.2,39.56 PR743.1
N28714582: length 3
  BOTTOM w0.203: PU703.12 194.26,38.53 192.65,40.14 PR755.2
N28714583: length 3.4
  BOTTOM w0.203: PR776.1 194.39,40.17 PC708.1 194.6,39.93 v1(194.6,39.21) 195.06,38.76 PU703.14
N28714585: length 5.3
  BOTTOM w0.102: PR742.1 195.28,41.1 195.74,41.56 195.74,41.94 v1(196.24,42.44)
  BOTTOM w0.203: PR742.1 195.28,40.17 PC708.2 195.01,39.88 195.01,39.27 195.46,38.83 PU703.15
N28714598: length 2.7
  BOTTOM w0.203: PU703.31 193.46,33.2 193.3,33.04 193.3,32.43 PC747.1
  BOTTOM w0.254: PC747.1 193.63,32.1 PR740.2
N28714599: length 3.7
  BOTTOM w0.102: v1(191.73,31.28) PR772.2
  BOTTOM w0.203: PC747.2 192.97,32.46 192.97,33.18 193.06,33.27 PU703.32
  BOTTOM w0.254: PC747.2 192.74,32.08 PR772.2
N28714601: length 1.9
  BOTTOM w0.203: PC750.2 194.9,32.28 194.9,32.94 194.66,33.18 PU703.28
N28714604: length 20.4
  TOP w0.254: v2(208.94,24.56) 208.62,24.24 PR773.1
  IN2 w0.127: v2(196.54,33.17) 196.54,32.74 196.72,32.56 196.72,31.74 197.99,30.47 201.93,30.47 204.76,27.64 208.49,27.64 208.94,27.19 v2(208.94,24.56)
  BOTTOM w0.203: PU703.25 195.86,33.38 196.07,33.17 v2(196.54,33.17)
N28714606: length 10.3
  TOP w0.102: v2(200.3,34.44) 199.23,35.51 v1(198.77,35.51)
  IN2 w0.762: 205.19,28.92 205.19,29.42 202.94,31.67 200.04,31.67 199.03,32.69 199.03,32.98
  vias: v2(200.3,33.86) v2(206.14,28.73) v2(206.72,28.73)
N28714608: length 3.2
  BOTTOM w0.102: v1(197.12,31.32) 196.28,32.17 PR745.1
  BOTTOM w0.203: PU703.26 195.46,33.31 196.17,32.6 PR745.1
N28714612: length 0.9
  BOTTOM w0.102: v1(197.06,32.66) 197.38,32.97 197.38,33.42
N28714614: length 2.3
  BOTTOM w0.203: PU703.17 196.51,38.7 PR757.2
N28714617: length 0.7
  BOTTOM w0.102: 102.09,126.69 v1(102.83,126.69)
N28714625: length 0.9
  BOTTOM w0.254: PR757.1 197.06,41.03 PR779.2
N28714693: length 1
  TOP w0.508: PC779.1 v2(211.04,25.69)
  vias: v1(215.79,26.82)
N28714721: length 33.3
  IN2 w0.127: v2(213.37,25.52) 213.37,25.21 213.24,25.09 212.6,25.09 212.31,25.37 212.31,26.03 210.19,28.15 204.97,28.15 202.14,30.97 198.2,30.97 197.23,31.95 197.23,33.79 196.44,34.57 196.44,40.3 195.03,41.71 195.03,42.44 v2(195.15,42.57)
  BOTTOM w0.254: v2(195.15,42.57) 195.15,42.07 PR742.2 ; v2(213.37,25.52) 213.7,25.84 PR765.2
N28714724: length 34.4
  IN2 w0.127: v2(194.52,42.57) 194.77,42.31 194.77,41.61 196.18,40.2 196.18,34.45 196.97,33.66 196.97,31.84 198.09,30.72 202.04,30.72 204.86,27.89 210.09,27.89 212.06,25.92 212.06,25.27 212.49,24.83 213.4,24.83 v2(213.98,25.41)
  BOTTOM w0.254: PR765.3 213.7,25.13 v2(213.98,25.41) ; v2(194.52,42.57) 194.52,42.07 PR776.2
N28714743: length 7.4
  BOTTOM w0.102: PR738.1 96.37,121.07 97.44,122.14 v1(97.44,122.33)
  BOTTOM w0.254: PQ709.2 92.83,122.21 92.83,121.3 93.17,120.96 94.36,120.96 94.5,121.1 PR737.2 95.65,121.1 95.68,121.07 PR738.1
N28714752: length 169.2
  IN1 w0.254: v2(101.66,123.61) 101.84,123.79 105.3,123.79 111.09,118 111.09,116.19 112.89,114.39 158.31,114.39 160.13,112.58 160.13,105.81 161.87,104.07 161.87,94.27 167.57,88.58 167.57,72.54 174.07,66.04 174.07,65.42 175.25,64.23 175.25,57.74 183.13,49.87 186.28,49.87 188.92,47.22 190.58,47.22 191.32,46.48 191.32,43.72 190.95,43.36 190.95,41.59 191.84,40.7 192.64,40.7 193.17,40.17 193.17,39.15 192.48,38.46 192.48,36.58 195.35,33.71 195.35,32.9 v2(192.26,29.81)
  BOTTOM w0.254: v2(101.66,123.61) 101.2,124.07 PR703.2 ; PR772.1 192.74,30.29 v2(192.26,29.81)
N28714753: length 169.8
  IN1 w0.254: v2(101.67,124.38) 101.87,124.17 105.46,124.17 111.48,118.15 111.48,116.35 113.05,114.78 158.49,114.78 160.51,112.76 160.51,105.97 162.25,104.23 162.25,94.43 167.96,88.72 167.96,72.68 174.45,66.19 174.45,65.57 175.64,64.38 175.64,57.9 183.29,50.25 186.44,50.25 189.08,47.6 190.74,47.6 191.7,46.64 191.7,43.57 191.35,43.21 191.35,41.74 191.94,41.14 192.74,41.14 193.56,40.33 193.56,38.99 192.86,38.3 192.86,36.74 195.73,33.87 195.73,32.5 193.85,30.62 193.85,30.46 v2(193.17,29.79)
  BOTTOM w0.254: v2(193.17,29.79) 193.63,30.24 PR740.1 ; PR703.3 101.98,124.07 v2(101.67,124.38)
N28714782: length 3.2
  TOP w0.102: v1(211.96,33.62) PC767.1
  TOP w0.508: PC767.1 PR766.2
N28714793: length 3.7
  TOP w0.102: v1(211.55,23.71) v2(210.97,23.71)
  TOP w0.508: v2(210.97,23.71) 210.91,23.65 210.07,23.65 PR773.2 PC779.2
  BOTTOM w0.508: PQ717.4 210.65,23.39 v2(210.97,23.71)
N28842863: length 3.2
  TOP w0.254: v2(107.27,32.59) 107.53,32.34 v1(107.53,32.02) 107.54,32.01 CC56.1
  BOTTOM w0.254: v2(107.27,32.59) 107.14,32.72 107.14,33.17 107.37,33.39 UC1.AL1
N28843886: length 9.4
  TOP w0.102: CC69.1 103.98,36.1 104.16,36.28 104.16,36.98 104.06,37.08 103.37,37.08 103.22,37.23 v1(99.72,37.23) 99.4,37.23 v2(98.88,37.74)
  BOTTOM w0.102: v2(98.88,37.74) 98.91,37.74 100.27,39.1 UC1.BB10
N28856399: length 4.7
  BOTTOM w0.076: TP19.1 100.56,76.52 100.56,74.84 100.83,74.57 101.33,74.57 101.62,74.29 101.62,73.73 101.48,73.59 UC1.BA70
N28856402: length 6.4
  BOTTOM w0.076: UC1.BA68 101.02,73.34 100.57,73.34 100.4,73.51 100.4,75.75 99.6,76.54 98.95,77.19 TP20.1
N28857231: length 6.7
  BOTTOM w0.076: UC1.BB68 100.85,72.44 100.07,73.22 100.07,75.61 99.29,76.39 97.48,76.39 TP21.1
N28857234: length 6.3
  BOTTOM w0.076: TP22.1 98.68,76.55 99.36,76.55 100.23,75.68 100.23,73.29 100.47,73.05 UC1.BB69
N28857237: length 1.4
  TOP w0.102: TP23.1 108.47,40.46 v2(108.57,40.46)
  BOTTOM w0.076: UC1.AK13 108.51,40.46 v2(108.57,40.46)
N28857240: length 1.3
  TOP w0.102: TP24.1 109.01,39.39 v2(108.55,39.85)
  BOTTOM w0.076: v2(108.55,39.85) 108.23,40.17 UC1.AK12
N28861827: length 9
  BOTTOM w0.076: UC1.C64 122.65,69.84 122.79,69.98 124.09,69.98 125.7,71.6 126.14,71.6 126.4,71.85 128.97,71.85 RC138.1 129.87,71.38
  BOTTOM w0.102: v1(130.51,71.38) 129.87,71.38
N28938912: length 1
  BOTTOM w0.102: CC2.2 105.48,17.51 RC21.1
N29189918: length 2.7
  BOTTOM w0.203: PU703.13 194.66,38.6 194.18,39.08 194.18,39.47 PR764.2
N29708559: length 4
  TOP w0.102: TP28.1 100.42,34.89 v2(100.41,34.89)
  BOTTOM w0.076: v2(100.41,34.89) 100.41,35.26 100.73,35.58 101,35.58 101.24,35.82 101.87,35.82 UC1.AY4
N29708561: length 1.6
  TOP w0.102: TP29.1 100.25,34.44 v2(100.16,34.34)
  BOTTOM w0.076: v2(100.16,34.34) 100.39,34.34 100.69,34.65 UC1.BB3
N29708599: length 2
  TOP w0.076: 105.15,36.56 v2(105.07,36.64)
  TOP w0.102: TP25.1 105.18,36.53 105.15,36.56
  BOTTOM w0.076: UC1.AU5 104.22,36.2 104.62,36.6 105.02,36.6 v2(105.07,36.64)
N29708601: length 2.2
  TOP w0.102: TP26.1 105.83,34.89 v2(105.83,35.67)
  BOTTOM w0.076: UC1.AT5 104.7,36.2 105.02,35.87 105.62,35.87 v2(105.83,35.67)
N29708639: length 5.6
  BOTTOM w0.076: UC1.BB5 100.71,36.06 99.52,34.88 99.52,34.58 98.85,33.9 98.85,32.74 TP27.1
N32842463: length 21.8
  IN2 w0.076: 119.65,37.91 119.48,37.91 119.44,37.95 117.79,37.95 116.67,39.07 116.67,39.82 116.33,40.17 115.76,40.17 115.59,40.34 114.53,40.34 v2(114.01,39.82)
  IN2 w0.127: v2(122.77,28.34) 122.77,30.63 123.15,31.01 123.15,31.77 123.78,32.4 123.78,33.17 123.08,33.86 123.08,34.91 121.5,36.5 121.5,36.95 120.91,37.54 120.91,37.69 120.68,37.91 119.65,37.91
  BOTTOM w0.076: UC1.U12 114.35,40.17 v2(114.01,39.82) 114.32,39.52 UC1.U11
  BOTTOM w0.102: v2(122.77,28.34) 122.51,28.59 RC137.2
N33124395: length 3.3
  BOTTOM w0.203: PU200.12 87.99,104.47
  BOTTOM w0.254: 87.99,104.47 88.12,104.34 PC204.2 PR210.1
N33124472: length 1.5
  TOP w0.102: v1(73.81,102.68) 73.8,102.69 PR203.1
N33188643: length 6
  TOP w0.254: CA31.1 v1(20.47,21.61) 19.84,21.61 18.88,22.58 18.88,24.26 RA23.2 RA24.1
N36085760: length 2.1
  TOP w0.102: v1(71.57,112.32) 71.46,112.44 PD6.1
  TOP w0.254: PD6.1 70.9,113.33 PR11.2
N39282118:
  vias: v1(157.06,35.51)
N39282176: length 2.9
  TOP w0.102: PC504.1 v1(167.34,32.33)
  TOP w0.508: PR506.2 165.43,32.6 165.7,32.33 PC504.1
N39282188: length 2.8
  BOTTOM w0.102: PR503.1 159.47,31.44 159.68,31.44 159.94,31.19 159.94,30.65 v1(159.84,30.55)
  BOTTOM w0.254: PR504.2 159,31.89 PR503.1
N39880170: length 5.7
  BOTTOM w0.102: v1(104.83,108.39) 104.23,108.39 PR1202.2
  BOTTOM w0.254: PU1200.7 100.28,110.37 100.59,110.06 102.56,110.06 PR1202.2
N39880453: length 1.8
  BOTTOM w0.102: PR1208.2 v1(94.24,105.09)
N40598435: length 2.6
  BOTTOM w0.102: v1(173.12,48.18) 173.44,47.86 PR100.2
  BOTTOM w0.508: PC102.1 172.88,46.98 PR100.2
N40598492: length 1.5
  TOP w0.102: v2(175.92,31.77) v1(175.28,31.77)
  TOP w0.508: PC119.1 176.36,31.77 v2(175.92,31.77)
N40598500: length 1
  BOTTOM w0.102: PC114.1 v1(173.88,36.49)
N40598503: length 0.9
  BOTTOM w0.254: PR108.1 175.27,38.7 PC113.2
N40598539: length 2.1
  BOTTOM w0.102: v1(179.09,27.26) PC127.2
  BOTTOM w0.254: PR117.1 179.08,28.47 PC127.2
N40598619: length 3.1
  TOP w0.102: PR116.2 177.51,29.37 v1(176.89,28.76)
  TOP w0.254: PR116.2 178.55,29.37 178.88,29.04 PD102.1
N40605947: length 5.8
  BOTTOM w0.102: PC305.1 146.81,39.07 145.81,39.07 v1(145.41,38.67)
  BOTTOM w0.254: PC305.1 PR303.2 148.16,39.54 148.67,40.04 149.44,40.04 149.67,40.27 PU300.15
N40606056: length 0.9
  BOTTOM w0.254: PR309.2 149.07,39.52 PR308.1
N40664383: length 5.5
  TOP w0.102: TP41.1 63.68,43.61 v2(63.15,43.61)
  BOTTOM w0.102: v2(63.15,43.61) 63.23,43.7 65.95,43.7 66.38,44.13 JDIMM1.165
N40665360: length 2.9
  TOP w0.102: TP42.1 51.95,43.97 v2(51.22,43.97)
  BOTTOM w0.102: v2(51.22,43.97) 51.22,43.99 51.41,44.18 51.73,44.18 52.17,44.63 JDIMM2.165
N40665398: length 2.7
  TOP w0.102: TP43.1 46.65,45.76 v2(46.65,45.09)
  BOTTOM w0.102: JDIMM2.162 46.36,45.38 v2(46.65,45.09)
N41315323: length 4.3
  TOP w0.254: PR15.1 216.72,16.76 216.98,17.02 v1(217.51,17.02) 218.1,17.02 v2(218.52,16.6)
  BOTTOM w0.254: v2(218.52,16.6) 218.15,16.6 217.9,16.85 PBATT1.5
N41321201: length 3.1
  TOP w0.102: v1(187.66,38.18) 187.66,37.55 187.31,37.19 PQ721.2
  TOP w0.254: PQ721.2 186.32,37.19 PC790.1 PR790.2
N41527020: length 3.6
  TOP w0.102: v2(60.8,44.56) 60.82,44.56 61.23,44.98 62.06,44.98 TP40.1
  BOTTOM w0.102: JDIMM1.162 60.46,44.87 60.78,44.56 v2(60.8,44.56)
N124753277: length 1.8
  TOP w0.102: v1(42.68,44.21) RD22.1
  TOP w0.305: RD22.1 CD59.2
N200649300: length 2.9
  TOP w0.203: PR620.2 167.71,55.49 v1(167.16,56.04) 166.96,56.24 166.96,56.66 166.46,57.16 PU602.1

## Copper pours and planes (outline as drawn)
2.5V_VIN on BOTTOM (solid shape): 54.66,7.15 54.82,7.1 54.98,7.15 57.63,7.15 57.8,6.99 57.8,6.65 57.23,6.65 57.23,6.09 57.8,6.09 57.8,5.84 57.23,5.84 57.23,5.3 57.8,5.3 57.8,4.97 57.72,4.89 56.83,4.89 56.16,5.56 53.98,5.56 53.3,6.24 51.79,6.24 51.6,6.43 51.6,7.02 51.73,7.15
3V_SN on TOP (solid shape): 167.21,45.36 167.21,42.89 167.02,42.7 166.2,42.7 166.07,42.82 166.07,45.43 166.13,45.49 167.09,45.49
3V_VIN on TOP (solid shape): 177.12,46.69 177.12,45.75 177.22,45.65 177.25,45.61 177.29,45.58 177.77,45.1 179.66,45.1 179.79,44.98 179.79,44.35 179.66,44.22 177.81,44.22 177.81,44.21 177.57,44.21 177.25,44.53 175.41,44.53 174.9,45.04 174.9,46.06 175.66,46.82 176.99,46.82
3V_VIN on BOTTOM (solid shape): 177.53,48.63 177.53,47.1 177.18,46.75 177.18,46.66 177.15,46.5 177.18,46.35 177.18,46.34 177.18,46.03 177.18,46.02 177.15,45.87 177.18,45.71 177.19,45.67 177.38,45.48 177.63,45.48 177.76,45.36 177.76,45.17 177.76,45.13 178.82,45.13 178.82,45.17 179.42,45.17 179.76,44.82 179.76,44.32 179.66,44.22 177.44,44.22 177.12,44.54 176.8,44.54 176.55,44.28 176.55,43.9 176.42,43.78 175.04,43.78 175.02,43.79 175.02,45.64 174.75,45.91 174.81,46.15 174.71,46.37 174.68,46.44 174.71,46.51 174.75,46.95 174.34,47.09 174.24,47.1 174.2,47.19 174.2,48.85 174.65,49.29 175.09,49.29 175.09,48.79 176.49,48.79 176.49,49.36 176.8,49.36
5V_VIN on TOP (solid shape): 180.23,37.86 180.23,35.72 180.33,35.62 180.36,35.58 180.4,35.55 180.87,35.08 181.81,35.07 182.46,34.42 182.46,34.06 182.33,33.93 180.92,33.93 180.87,33.99 180.87,34.04 180.87,34.12 180.68,34.31 178.96,34.31 178.46,34.82 178.07,34.82 177.76,35.13 177.76,38.05 177.95,38.25 179.85,38.25
5V_VIN on BOTTOM (solid shape): 182.84,38.57 182.84,37.29 182.32,36.78 181.82,36.78 181.81,36.79 180.77,36.79 180.61,36.82 180.45,36.79 180.43,36.79 180.4,36.75 180.36,36.72 180.33,36.68 180.23,36.58 180.23,35.72 180.33,35.62 180.36,35.58 180.4,35.54 180.5,35.45 180.68,35.45 180.86,35.27 180.86,35.1 180.98,35.1 181.01,35.07 181.83,35.07 182.52,34.38 182.52,34.06 182.39,33.93 180.87,33.93 180.83,33.97 180.82,33.98 180.74,34.12 180.6,34.21 180.59,34.21 180.55,34.25 180.23,34.25 179.91,33.93 179.41,33.93 179.22,33.74 177.76,33.74 177.69,33.81 177.69,34.5 177.76,34.57 177.76,38.12 178.64,39.01 179.98,39.01 179.98,38.5 181.44,38.5 181.44,39.01 181.44,39.01 182.39,39.01
+0.6V_DDR_VTT on TOP (solid shape): 41.08,99.88 41.08,97.28 40.85,97.05 39.02,97.05 38.78,97.29 38.78,100.09 38.85,100.16 40.8,100.16
+0.6V_DDR_VTT on TOP (solid shape): 57.49,21.35 60.98,21.35 61.23,21.1 61.23,20.59 60.85,20.21 59.65,20.21 58.88,19.45 57.39,19.45 55.77,21.07 55.77,21.42 56.22,21.86 56.98,21.86
+0.6V_DDR_VTT on TOP (solid shape): 85.95,115.16 85.95,114.18 85.8,114.03 85.25,114.03 85.25,113.48 85,113.48 85,114.03 84.45,114.03 84.45,113.48 84.2,113.48 84.2,114.04 83.57,114.04 83.43,114.18 83.43,115.17 83.59,115.33 85.77,115.33
+0.6V_DDR_VTT on TOP (solid shape): 41.74,27.45 41.74,23.26 42.54,22.46 44.47,22.46 44.5,22.43 44.79,22.43 44.91,22.56 45.55,22.56 45.99,22.12 45.99,21.67 45.68,21.35 45.11,21.35 44.75,21 42.53,21 42.31,21.21 40.65,21.21 39.33,22.54 39.33,27.45 39.58,27.7 41.49,27.7
+0.6V_DDR_VTT on BOTTOM (solid shape): 40.58,101.51 40.58,98.75 40.45,98.62 38.58,98.62 38.45,98.74 38.45,101.57 38.6,101.72 40.37,101.72
+0.6V_DDR_VTT on BOTTOM (solid shape): 41.42,110.83 41.42,108.98 40.72,108.29 39.52,108.29 39.26,108.54 39.26,110.38 40.03,111.14 41.1,111.14
+0.6V_DDR_VTT on IN2 (solid shape): 42.18,112.1 42.18,111.14 40.91,109.87 40.34,109.87 39.96,110.25 39.96,112.41 40.22,112.67 41.61,112.67
+0.6V_DDR_VTT on IN2 (solid shape): 85.73,115.49 85.73,114.28 85.53,114.08 82.64,114.08 82.47,114.24 82.47,115.5 82.65,115.68 85.54,115.68
+0.6VSP on TOP (solid shape): 83.58,113.88 84.05,113.88 84.05,113.33 84.61,113.33 84.61,113.33 84.61,113.88 84.85,113.88 84.85,113.33 85.41,113.33 85.41,113.33 85.41,113.88 86.19,113.88 86.44,113.63 86.44,111.02 85.62,110.19 83.33,110.19 83.08,110.44 83.08,113.58 83.38,113.88 83.58,113.88
+0.6VSP on BOTTOM (solid shape): 85.21,112.57 85.21,109.4 86.51,108.1 86.51,107.4 86.44,107.33 85.7,107.33 83.74,109.28 83.74,109.9 83.27,110.38 83.27,112.79 83.46,112.98 84.79,112.98
+1.0V_AMPHYPLL on TOP (solid shape): outline of 243 points within 117.18,38.05 122.7,41.4
+1.0V_AMPHYPLL on BOTTOM (solid shape): 131.81,34.94 131.81,32.58 131.72,32.49 130.85,32.49 130.7,32.64 130.09,32.64 130,32.73 130,33.28 130.08,33.36 130.61,33.36 130.72,33.47 130.72,34.97 130.81,35.07 131.67,35.07
+1.0V_MPHYGT on TOP (solid shape): outline of 680 points within 115.02,31.63 125.96,42.86
+1.0V_MPHYGT on BOTTOM (solid shape): 126.02,32.1 126.37,32.1 126.72,31.75 126.72,31.08 126.62,30.98 125.6,30.98 124.91,31.67 124.1,31.67 123.98,31.79 123.98,32.61 124.1,32.72 125.4,32.72
+1.0V_MPHYGT on BOTTOM (solid shape): 132,31.65 132,30.91 131.92,30.83 131.58,30.83 131.58,30.83 131.08,30.83 130.96,30.71 130.96,30.33 130.89,30.12 130.96,29.9 130.96,29.26 130.62,28.92 130.62,28.08 130.58,28.04 129.19,28.04 128.53,28.69 128.53,29.69 128.65,29.81 129.67,29.81 129.75,29.89 129.75,30.04 129.75,30.04 129.75,30.58 129.94,30.77 129.94,31.51 129.96,31.53 129.99,31.57 130.02,31.62 130.14,31.75 131.9,31.75
+1.0V_MPHYGT on BOTTOM (solid shape): 116.5,43.03 116.5,42.7 116.5,42.65 116.5,42.6 116.5,41.89 117.06,41.33 117.06,41.12 116.94,41 116.74,41 116.61,41.07 116.46,41.05 116.45,41.04 116.22,41.04 116.17,41 115.9,41 115.85,41.04 115.61,41.04 115.6,41.05 115.45,41.07 115.32,41 115.08,41 114.93,41.15 114.93,41.48 115.26,41.81 115.34,41.87 115.34,41.89 115.36,41.91 115.36,42.32 115.37,42.33 115.37,42.39 115.39,42.4 115.45,42.5 115.48,42.61 115.48,42.63 115.55,42.71 115.57,42.71 115.7,42.78 115.77,42.92 115.78,42.94 115.83,42.99 115.86,42.97 116.09,42.96 116.28,43.11 116.43,43.11
+1.0V_MPHYGT on IN1 (solid shape): 116.42,42.76 116.42,42.42 116.61,42.23 117.12,42.23 117.31,42.04 117.31,41 117.24,40.93 115.25,40.93 115,41.17 115,41.75 115.64,42.39 115.64,42.77 115.75,42.89 116.29,42.89
+1.0V_PRIM on TOP (solid shape): outline of 221 points within 135.23,41.42 138.45,49.79
+1.0V_PRIM on TOP (solid shape): outline of 1232 points within 108.03,31.88 137.37,46.67
+1.0V_PRIM on BOTTOM (solid shape): 136.61,45.1 136.61,44.91 136.67,44.85 136.71,44.85 136.99,44.56 138.12,44.56 138.39,44.3 138.39,43.74 137.84,43.74 137.84,42.98 138.39,42.98 138.39,42.54 137.84,42.54 137.84,41.78 138.39,41.78 138.39,40.79 138.19,40.6 136.64,40.6 134.84,42.4 134.84,44.06 134.98,44.2 135.93,44.2 136.1,44.37 136.1,45.1 136.16,45.17 136.55,45.17
+1.0V_PRIM on VCC: 110.55,24.28 105.56,29.28 105.56,35.98 105.56,36.19 105.56,45.55 112.65,45.55 113.22,46.12 116.39,46.12 116.71,46.44 117.26,46.44 117.5,46.2 117.5,43.92 120.18,41.23 129.98,41.23 133.73,44.98 134.13,44.98 136.35,44.98 138.39,44.98 138.39,34.6 134.26,30.48 134.26,27.43 132.74,25.9 132.74,24.28
+1.0V_VCCST on TOP (solid shape): 131.11,44.53 131.11,44 131.46,43.64 132.93,43.64 133.18,43.9 133.33,43.9 133.39,43.96 134.08,43.96 134.11,43.83 134.18,43.71 134.2,43.7 134.2,43.59 134.18,43.57 134.08,43.31 134.2,43.06 134.2,42.75 134.01,42.56 133.62,42.56 133.18,42.12 130.82,42.12 130.81,42.12 130.7,42.14 130.59,42.12 130.58,42.12 130.43,42.12 129.83,42.72 129.83,44.39 130.11,44.68 130.96,44.68
+1.0V_VCCST on TOP (solid shape): 118.77,45.09 118.77,44.77 118.96,44.58 119.02,44.58 119.16,44.55 119.28,44.57 119.29,44.58 119.57,44.58 119.74,44.53 119.92,44.58 120.19,44.58 120.2,44.57 120.36,44.53 120.52,44.57 120.53,44.58 120.96,44.58 120.97,44.57 121.13,44.53 121.3,44.57 121.31,44.58 121.43,44.58 121.5,44.64 122.07,44.64 122.07,44.13 121.26,44.13 121.01,44.25 120.76,44.13 120.62,44.13 120.61,44.14 120.42,44.2 120.23,44.13 119.97,44.13 119.78,44.2 119.58,44.13 119.36,44.13 119.12,44.29 118.85,44.21 118.82,44.2 118.79,44.21 118.72,44.25 118.65,44.26 118.57,44.26 118.32,44.51 118.32,45.09 118.4,45.17 118.69,45.17
+1.0V_VCCST_C on TOP (solid shape): 133.5,40.91 133.5,39.39 133.43,39.32 132.61,39.32 132.23,39.71 131.57,39.71 131.57,39.75 131.47,39.99 131.24,40.09 131.17,40.13 131.15,40.2 131.15,41.29 131.21,41.36 133.05,41.36
+1.0V_VCCSTG on TOP (solid shape): 132.69,34.59 132.69,34.13 132.14,34.13 132.14,33.7 132.69,33.7 132.69,33.4 132.64,33.35 132.12,33.35 132,33.23 130.7,33.23 130.58,33.35 130.39,33.35 130.32,33.36 130.03,33.36 129.96,33.43 129.96,34.42 130.35,34.82 132.46,34.82
+1.0V_VCCSTG_C on TOP (solid shape): 134.65,34.76 134.65,33.43 134.49,33.27 133.72,33.27 133.31,32.87 133.31,32.05 133.62,31.75 133.77,31.75 134.32,31.2 134.32,30.63 134.2,30.5 132.29,30.5 132.16,30.63 132.16,33.01 132.22,33.07 132.68,33.07 132.81,33.21 132.81,34.73 133,34.92 134.49,34.92
+1.0VS_VCCIO on TOP (solid shape): 108.15,58.53 108.15,58.06 107.96,57.87 107.96,56.89 107.87,56.8 107.42,56.8 107.37,56.85 107.37,57.28 107.25,57.41 106.89,57.41 106.79,57.51 106.79,57.79 106.93,57.93 107.26,57.93 107.29,57.96 107.32,57.96 107.32,57.99 107.53,58.2 107.53,58.48 107.65,58.6 108.07,58.6
+1.0VS_VCCIO on TOP (solid shape): 107.88,52.09 107.98,52.03 107.96,51.92 107.91,51.73 108,51.56 108.04,51.5 108.03,51.43 108.1,51.05 108.49,50.99 108.75,50.99 108.83,50.92 108.83,50.71 108.83,50.65 108.83,50.59 108.83,50.22 108.86,50.18 108.86,50.04 108.29,49.47 106.7,49.47 106.38,49.79 106.38,50.87 106.64,51.12 106.64,51.56 106.89,51.82 107.34,51.82 107.35,51.83 107.39,51.83 107.64,52.09
+1.0VS_VCCIO on TOP (solid shape): outline of 614 points within 102.86,21.42 134.39,32.97
+1.0VS_VCCIO on BOTTOM (solid shape): 107.4,51.1 107.4,51.11 107.5,51.11 107.64,51.03 107.79,51.05 107.8,51.05 108.09,51.05 108.4,50.96 108.64,51.18 108.71,51.25 108.81,51.22 108.83,51.2 108.87,51.2 108.97,51.1 109.32,51.1 109.32,50.03 109.06,49.78 108.56,49.78 108.54,49.78 108.33,49.8 108.15,49.71 107.8,49.71 107.79,49.71 107.69,49.73 107.58,49.71 107.57,49.71 107.2,49.71 106.8,50.1 106.78,50.13 106.75,50.15 106.64,50.26 106.64,50.58 106.67,50.59 106.8,50.74 106.8,50.93 106.74,51.01 106.69,51.05 106.64,51.09 106.64,51.39 106.77,51.53 106.98,51.53
+1.0VS_VCCIO on IN1 (solid shape): outline of 4258 points within 101.62,31.83 109.7,58
+1.0VS_VCCOPC on TOP (solid shape): outline of 3818 points within 104.1,66.84 118.83,104.92
+1.0VS_VCCOPC on BOTTOM (solid shape): 107.61,103.38 107.61,97.26 106.7,96.35 98.76,96.35 98.13,96.98 98.13,99.52 98.64,100.03 99.33,100.03 99.33,99.51 99.83,99.51 99.83,100.03 100.13,100.03 100.13,99.51 100.63,99.51 100.63,100.03 101.24,100.03 101.49,99.78 103.78,99.78 104.03,100.03 104.03,103.4 104.35,103.71 107.28,103.71
+1.0VS_VCCOPCP on BOTTOM (solid shape): 101.75,104.41 101.75,101.81 102.45,101.11 103.21,101.11 103.4,100.92 103.4,100.09 103.33,100.03 101.8,100.03 101.64,100.19 100.5,100.19 100.5,99.64 100.26,99.64 100.26,100.19 99.7,100.19 99.7,99.64 99.45,99.64 99.45,100.19 98.76,100.19 98.74,100.22 96.79,100.22 96.73,100.28 96.73,102.38 97.05,102.7 97.43,102.7 98.38,103.65 98.38,104.39 98.61,104.62 101.54,104.62
+1.2V_DDR on TOP (solid shape): 80.27,35.84 70.27,35.84 70.27,50.84 80.27,50.84
+1.2V_DDR on TOP (solid shape): 86.25,81.12 78.25,81.12 78.25,89.12 86.25,89.12
+1.2V_DDR on TOP (solid shape): 86.25,62.3 78.25,62.3 78.25,70.3 86.25,70.3
+1.2V_DDR on TOP (solid shape): outline of 29136 points within 40.83,23.58 107.91,102.98
+1.2V_DDR on BOTTOM: 41.98,44.34 40.03,46.3 40.03,59.02 41.75,60.75 71.31,60.75 73.48,58.58 73.48,44.96 72.85,44.34 68.3,44.34 68.3,44.95 65.72,44.95 65.72,44.85 65.71,44.85 65.71,44.34 ; 12 cut-outs
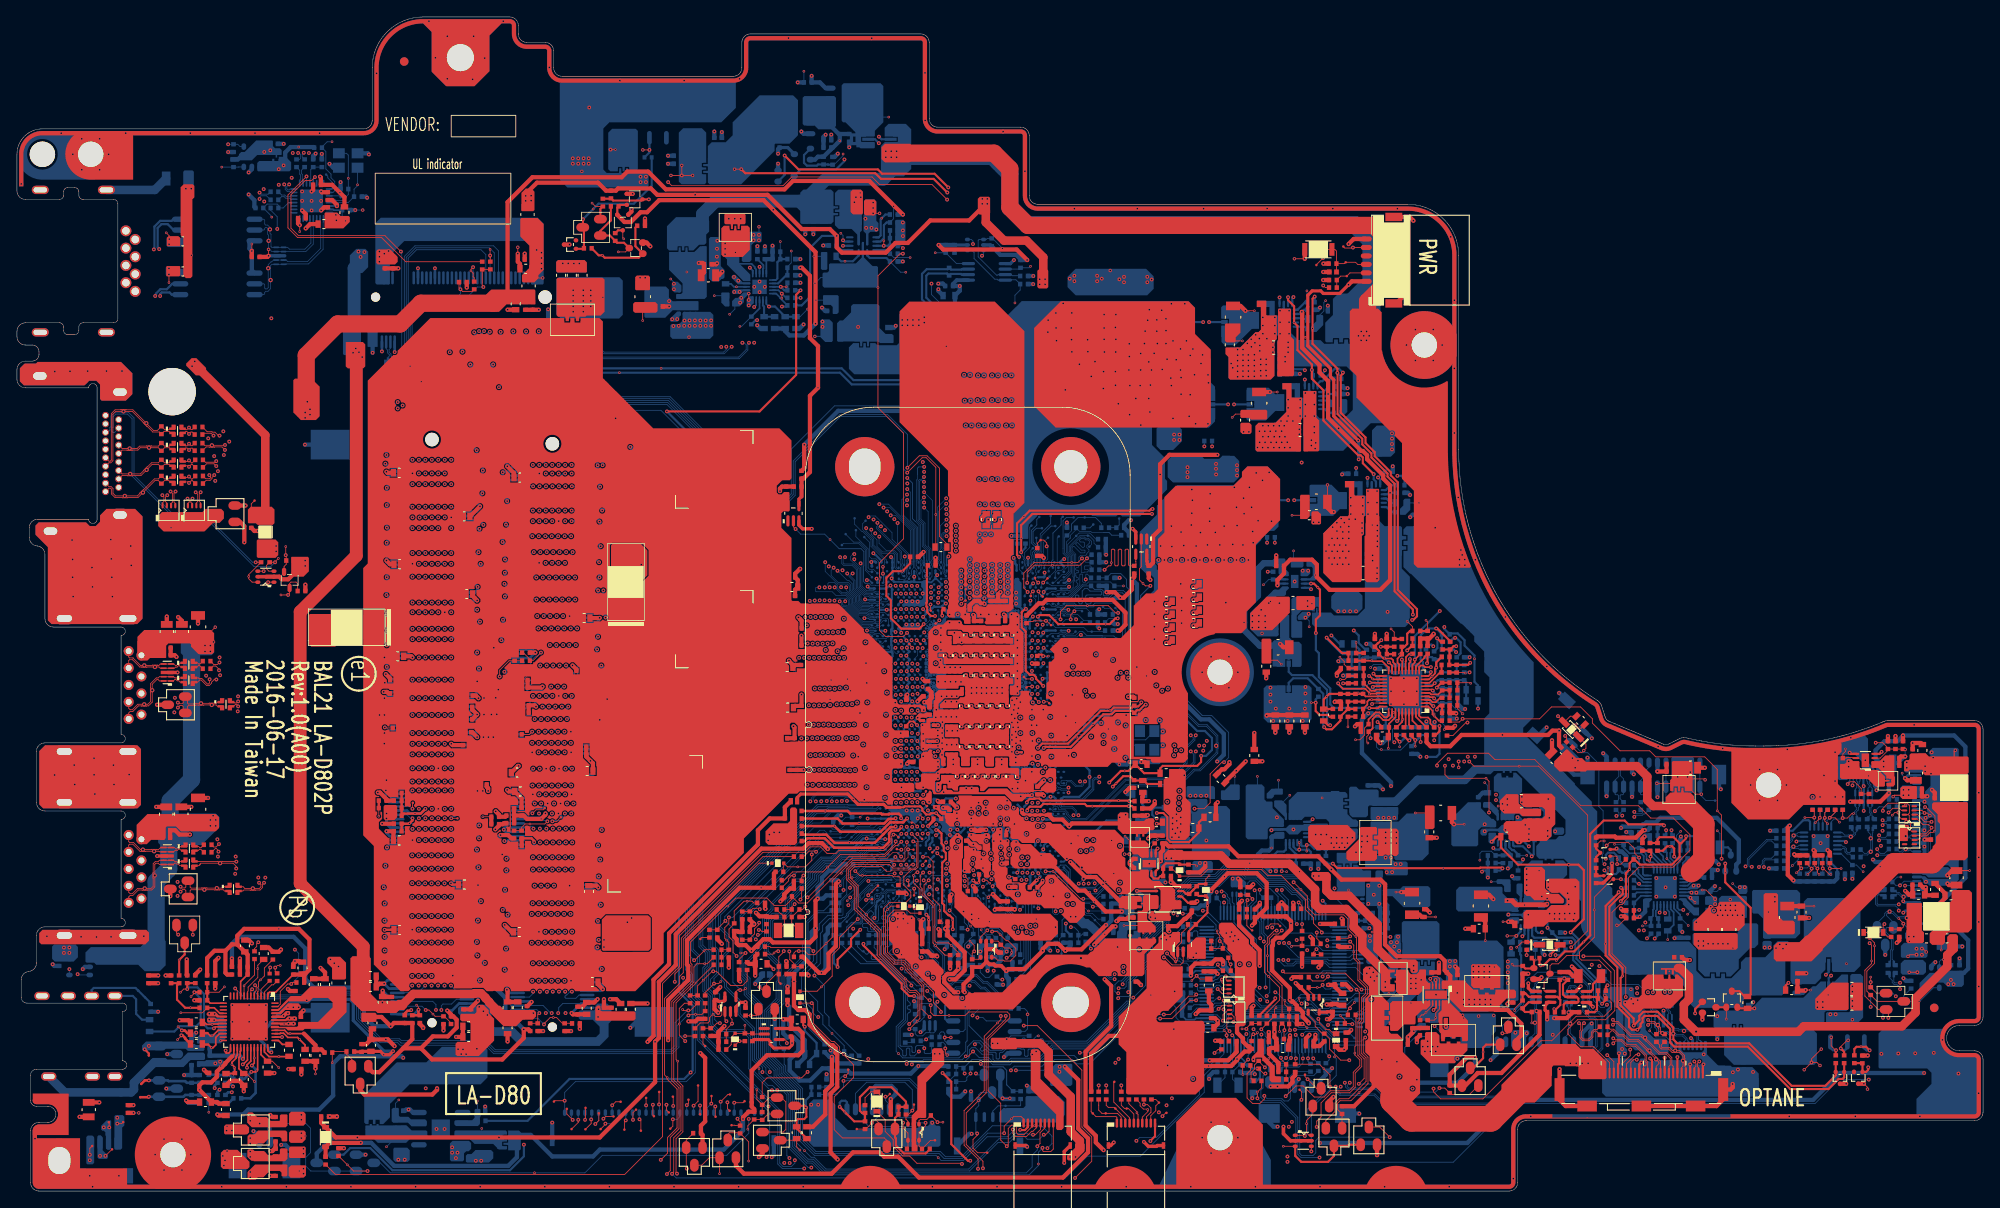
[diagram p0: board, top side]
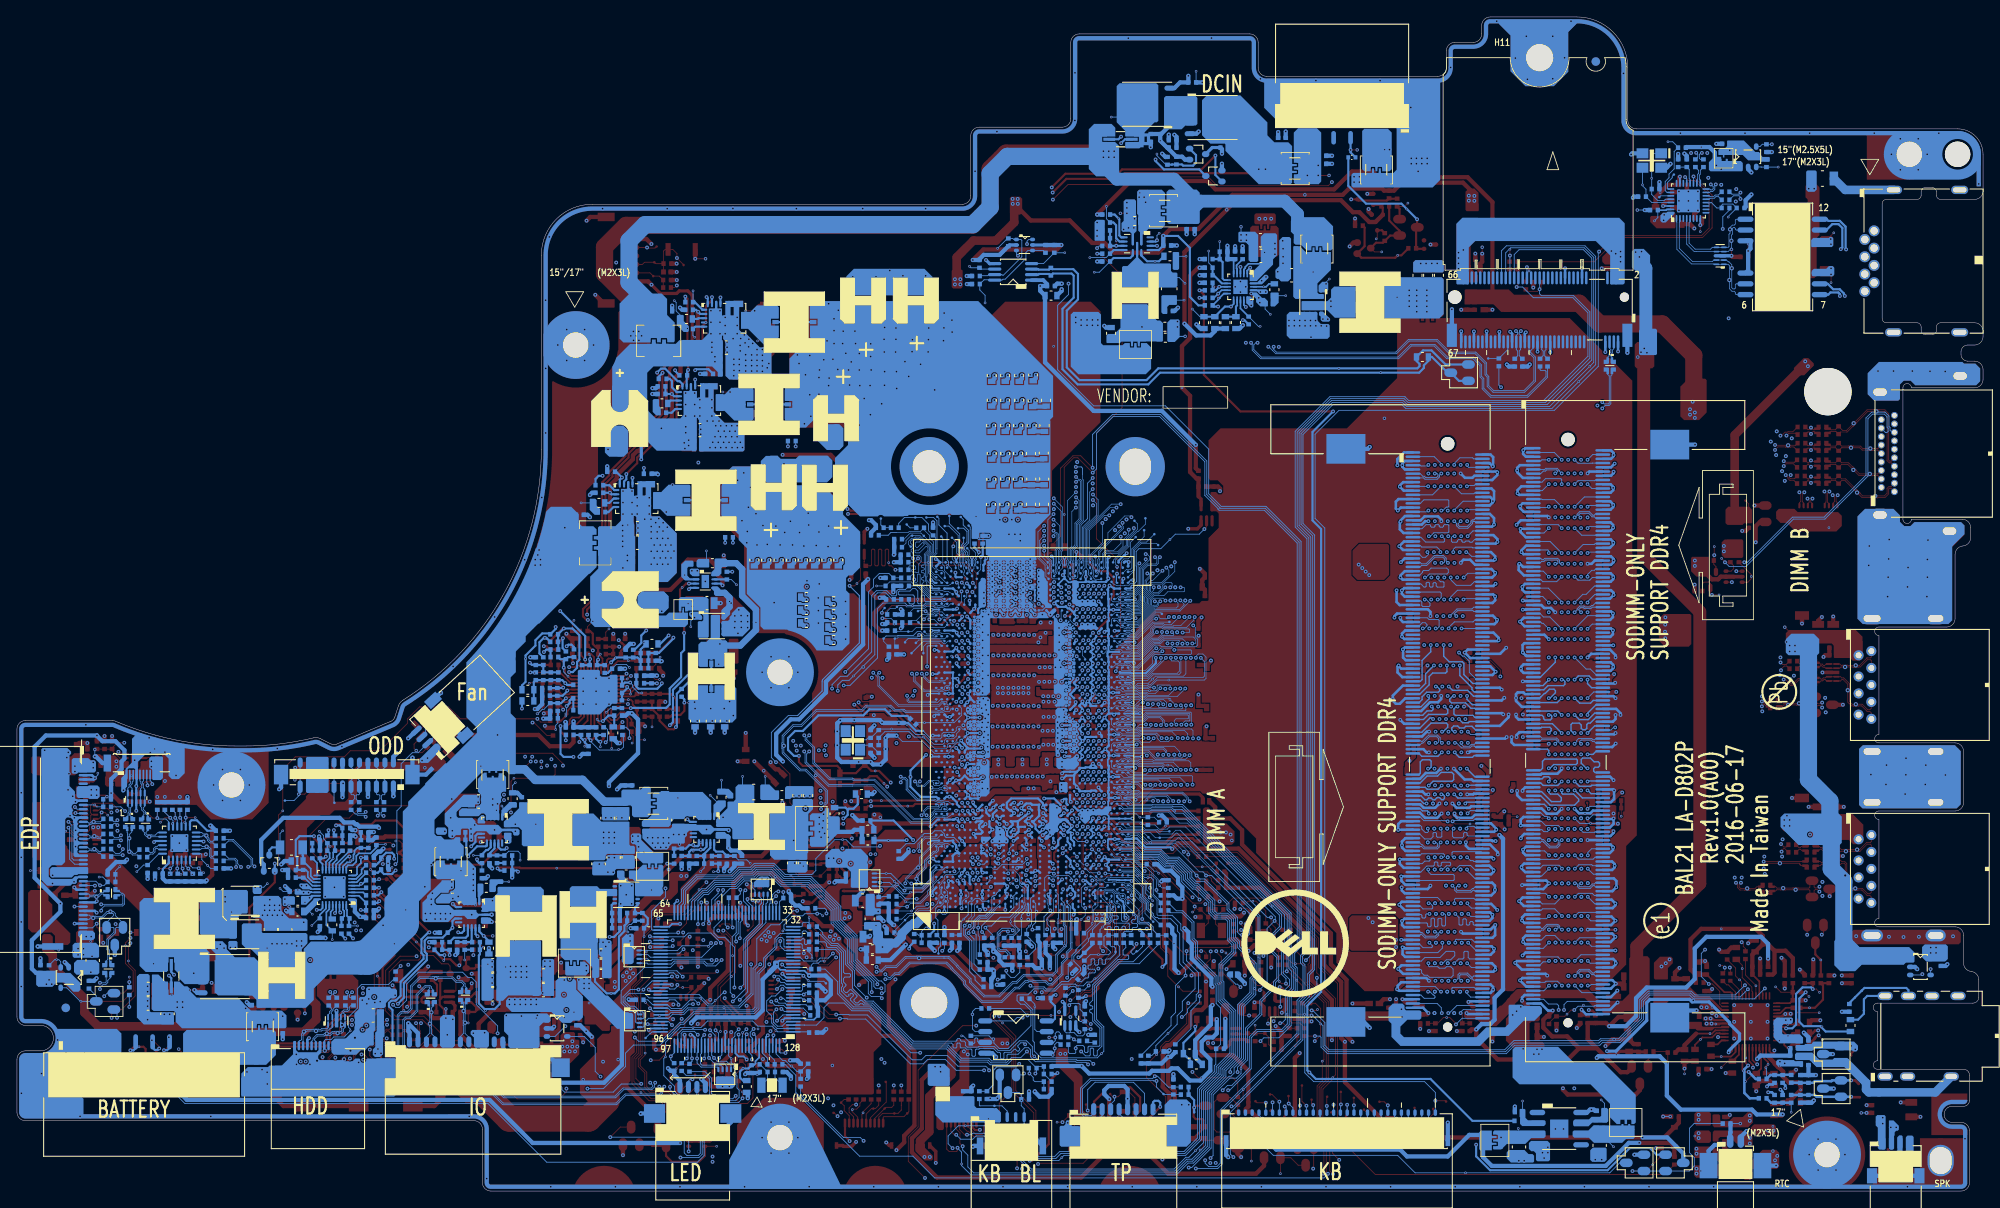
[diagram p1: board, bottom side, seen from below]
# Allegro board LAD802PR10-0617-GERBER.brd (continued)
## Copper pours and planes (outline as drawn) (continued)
+1.2VP on TOP (solid shape): 69.34,107.49 69.31,107.46 69.31,103.73 68.85,103.27 67.18,103.27 67.04,103.13 66.31,103.13 66.31,102.61 65.91,102.61 65.91,103.13 65.11,103.13 65.11,102.61 64.71,102.61 64.71,103.13 63.82,103.13 63.63,103.32 63.63,107.59 63.77,107.73 69.1,107.73
+1.2VP on BOTTOM (solid shape): 71.46,107.4 71.46,103.36 71.03,102.93 64.13,102.93 63.61,103.45 63.61,107.55 63.86,107.8 71.05,107.8
+1.2VP on BOTTOM (solid shape): 85.6,107.21 86.44,107.21 86.51,107.14 86.51,107.02 86.44,106.95 85.05,106.95 84.28,107.71 84.28,107.9 84.46,108.08 84.72,108.08
+1.2VP on IN1 (solid shape): 67.95,107.09 67.95,106.13 67.83,106.01 66.68,106.01 66.56,106.14 66.56,106.67 67.18,107.29 67.74,107.29
+1.2VP on IN1 (solid shape): 85.34,107.57 85.34,107.31 85.18,107.15 84.7,107.15 84.58,107.27 84.57,107.26 83.63,107.26 83.5,107.4 83.5,107.95 83.66,108.11 84.81,108.11
+1.8V_PRIM on TOP (solid shape): 154.96,37.36 154.96,36.66 154.9,36.59 153.82,36.59 153.82,36.6 153.11,36.6 152.67,37.04 152.67,37.51 152.8,37.64 154.68,37.64
+1.8V_PRIM on TOP (solid shape): 165.24,27.05 165.24,25.92 165.06,25.74 164.53,25.74 164.34,25.93 164.34,26.21 164.25,26.31 163.16,26.31 163,26.46 163,27.21 163.11,27.32 164.97,27.32
+1.8V_PRIM on TOP (solid shape): outline of 444 points within 109.84,29.53 122.78,42.23
+1.8V_PRIM on BOTTOM (solid shape): 165.48,26.56 165.99,26.56 165.99,27.07 166.28,27.07 166.28,26.56 166.79,26.56 166.79,27.07 167.18,27.07 167.24,27.02 167.24,25.56 167.11,25.42 164.8,25.42 164.42,25.8 164.42,26.57 164.93,27.07 165.48,27.07
+1.8V_PRIM on IN1 (solid shape): 152.51,37.65 152.61,37.64 152.71,37.65 152.71,37.66 153.39,37.66 153.4,37.65 153.5,37.64 153.6,37.65 153.6,37.66 153.8,37.66 153.99,37.47 153.99,36.85 151.74,36.85 151.74,37.61 151.79,37.66 152.5,37.66
+1.8VALWP on BOTTOM (solid shape): 167.79,31.52 167.79,27.72 167.3,27.23 166.66,27.23 166.66,27.2 166.66,26.68 166.41,26.68 166.41,27.24 165.86,27.24 165.86,26.68 165.61,26.68 165.61,27.2 165.61,27.23 164.86,27.23 164.04,26.41 164.04,25.23 163.98,25.16 163.34,25.16 163.22,25.29 163.22,27.32 163.4,27.51 163.4,29.3 163.34,29.36 163.34,30.3 163.34,30.3 163.34,31.65 163.53,31.84 167.47,31.84
+1VALWP on BOTTOM (solid shape): 140.41,46.13 140.41,45.58 140.57,45.43 142.64,45.43 143.08,44.98 143.08,39.58 142.58,39.08 138.73,39.08 138.66,39.15 138.66,39.85 138.58,39.93 138.58,41.29 138.54,41.33 138.54,41.93 138,41.93 138,42.4 138.54,42.4 138.54,43.14 138,43.14 138,43.59 138.54,43.59 138.54,44.5 138,45.04 138,45.09 138.51,45.09 138.52,45.03 138.53,44.98 138.56,44.93 138.58,44.88 138.62,44.84 138.66,44.8 138.71,44.77 138.76,44.75 138.81,44.73 138.87,44.72 138.92,44.72 138.98,44.73 139.03,44.75 139.08,44.77 139.13,44.8 139.17,44.84 139.2,44.88 139.23,44.93 139.26,44.98 139.27,45.03 139.28,45.09 139.27,45.14 139.26,45.2 139.25,45.25 139.22,45.3 139.19,45.35 139.15,45.39 139.11,45.42 139.06,45.45 139,45.47 138.95,45.48 138.89,45.48 138.84,45.48 138.78,45.47 138.73,45.45 138.68,45.42 138.64,45.39 138.6,45.35 138.57,45.3 138.54,45.25 138.53,45.2 138.52,45.14 138.51,45.09 138,45.09 138,46.12 138.13,46.25 140.29,46.25
+2.5V_MEM on TOP (solid shape): 68.83,21.79 68.83,21.25 68.96,21.25 69.01,21.2 72.82,21.2 72.97,21.05 72.97,20.31 72.76,20.1 68.3,20.1 68.21,20.19 68.21,21.64 68.46,21.89 68.73,21.89
+2.5V_MEM on TOP (solid shape): 55.65,21.33 55.65,21.02 55.66,21 55.66,20.95 56.28,20.33 56.28,17.73 54.46,15.92 51.91,15.92 51.73,16.1 51.73,17.37 51.96,17.61 53.39,17.61 53.5,17.72 53.5,19.77 53.27,20 53.04,20 53.04,20.01 52.47,20.01 52.28,20.2 52.28,20.37 52.28,20.78 52.41,20.91 54,20.91 54.19,21.1 54.19,21.71 54.44,21.97 55.01,21.97
+2.5V_MEM on BOTTOM (solid shape): 55.5,16.69 55.5,13.4 54.69,12.59 46.31,12.59 44,10.28 44,8.69 43.2,7.89 42.79,7.89 42.79,8.41 42.28,8.41 42.28,7.89 41.99,7.89 41.99,8.41 41.48,8.41 41.48,7.89 41.15,7.89 40.96,8.08 40.96,11.35 44.8,15.19 48.29,15.19 50.12,17.02 55.17,17.02
+2.5V_MEM on BOTTOM (solid shape): 70.12,21.61 70.12,20.08 69.78,19.74 69.78,18.18 68.72,17.12 59.32,17.12 58.14,18.3 55.96,18.3 54.17,20.08 52.92,20.08 52.03,20.97 52.03,21.6 52.27,21.85 53.77,21.85 53.82,21.85 53.87,21.86 54.25,21.86 54.38,21.99 55.84,21.99 55.96,21.86 55.96,19.72 56.36,19.32 58.59,19.32 59.76,18.16 68.31,18.16 68.72,18.57 68.72,19.4 68.48,19.64 68.47,19.64 67.9,20.21 66.44,20.21 66.25,20.4 66.25,21.16 66.38,21.29 68.03,21.29 68.13,21.39 68.17,21.43 68.23,21.49 68.23,21.52 68.25,21.63 68.23,21.73 68.23,21.74 68.23,21.87 68.47,22.12 69.62,22.12
+2.5VP on BOTTOM (solid shape): 46.55,7.15 48.26,7.15 48.41,7 48.41,6.48 48.22,6.29 46.86,6.29 46.86,6.28 46.5,6.28 45.9,5.69 42.56,5.69 42.11,6.13 41.25,6.13 41.09,6.29 41.09,7.69 41.15,7.75 44.55,7.75 44.56,7.75 45.95,7.75
+3.3V_OUT on TOP (solid shape): 166.71,22.31 166.71,21.89 166.22,21.4 165.78,21.4 164.97,20.59 164.97,19.76 164.85,19.64 163.63,19.64 162.88,18.89 162.05,18.89 161.96,18.98 161.96,22.13 162.24,22.41 166.61,22.41
+3.3V_WLAN on TOP (solid shape): 44.91,110.19 44.91,109.62 44.6,109.3 42.57,109.3 42.38,109.5 42.38,110.89 42.57,111.08 44.03,111.08
+3.3V_WLAN on TOP (solid shape): 62.12,114.07 62.12,108.66 61.51,108.05 61.51,107.67 61.04,107.19 59.69,107.19 59.57,107.31 59.57,108.04 60.43,108.9 60.43,111.54 59.37,112.6 59.37,114.65 59.51,114.8 61.39,114.8
+3.3V_WLAN on BOTTOM (solid shape): 62.13,114.1 62.13,107.06 62.02,106.95 60.71,106.95 60.65,107 60.65,108.42 60.65,108.43 60.65,111.31 59.9,112.07 45.68,112.07 43.98,110.37 43.98,107.02 43.89,106.93 42.44,106.93 42.26,107.11 42.26,114.17 42.91,114.81 61.41,114.81
+3VALW on TOP (solid shape): 61.04,117.9 61.04,115.73 60.9,115.58 59.57,115.58 59.5,115.65 59.5,117.76 60.01,118.26 60.68,118.26
+3VALW on TOP (solid shape): 121.65,108.55 121.65,106.65 121.47,106.46 120.54,106.46 120.35,106.65 120.35,108.57 120.48,108.7 121.5,108.7
+3VALW on TOP (solid shape): 114.79,117.15 114.79,115.38 114.59,115.18 113.56,115.18 113.33,115.41 113.33,117.04 113.58,117.29 114.64,117.29
+3VALW on TOP (solid shape): 160.42,42.82 160.42,42.06 159.9,42.06 159.9,41.36 160.42,41.36 160.42,40.86 159.9,40.86 159.9,40.16 160.42,40.16 160.42,39.2 160.17,38.95 157.05,38.95 156.8,39.2 156.8,40.03 158.32,41.55 158.32,42.76 158.51,42.95 160.29,42.95
+3VALW on TOP (solid shape): 166.2,26.09 166.2,24.85 166.52,24.53 166.64,24.53 166.71,24.47 166.71,23.89 166.62,23.8 165.98,23.8 165.32,23.14 163.08,23.14 162.66,23.56 162.66,26.09 162.68,26.12 164.04,26.12 164.17,26 164.17,25.86 164.43,25.59 165.09,25.59 165.38,25.88 165.38,26.06 165.46,26.14 166.15,26.14
+3VALW on TOP (solid shape): outline of 162 points within 141.76,19.45 146.26,31.67
+3VALW on TOP (solid shape): outline of 209 points within 129.94,11.38 140.04,30.56
+3VALW on BOTTOM (solid shape): 149.47,13.41 149.47,12.23 149.32,12.08 147.53,12.08 147.21,12.4 147.21,13.29 147.46,13.53 149.34,13.53
+3VALW on BOTTOM (solid shape): 144.99,36.4 144.99,35.9 144.93,35.83 143.28,35.83 143.15,35.96 143.15,36.98 143.28,37.1 144.29,37.1
+3VALW on BOTTOM (solid shape): 59.44,6.91 59.44,4.94 59.3,4.8 57.93,4.8 57.93,5.45 57.37,5.45 57.37,5.69 57.93,5.69 57.93,6.25 57.37,6.25 57.37,6.5 57.93,6.5 57.93,7.13 59.21,7.13
+3VALW on BOTTOM (solid shape): 159.62,30.37 159.81,30.27 160.02,30.34 160.55,29.81 160.55,27.04 160.29,26.78 159.34,26.78 159.15,26.97 159.15,30.2 159.32,30.37
+3VALW on BOTTOM (solid shape): 165.79,25.13 165.79,23.8 161.12,19.13 159.34,19.13 159.21,19.26 159.21,20.85 159.38,21.01 159.7,21.01 159.79,21.1 160.23,21.1 162.2,23.07 162.45,23.07 163.98,24.59 163.98,24.59 164.17,24.78 164.17,25.04 164.17,25.15 164.29,25.28 165.64,25.28
+3VALW on BOTTOM (solid shape): 159.47,42 159.47,41.11 159.28,40.92 159.02,40.92 158.83,40.73 158.83,39.42 158.05,38.64 157.47,38.64 157.47,38.12 157.18,38.12 157.18,38.64 156.67,38.64 156.67,38.12 156.38,38.12 156.38,38.64 155.8,38.64 155.66,38.78 155.66,39.84 155.72,39.9 156.74,39.9 158.26,41.43 158.26,42 158.45,42.19 159.28,42.19
+3VALW on BOTTOM (solid shape): 30.19,123.86 30.19,123.27 30.45,123.01 31.01,123.01 31.22,122.8 31.22,122.27 31.17,122.22 28.34,122.22 27.7,121.58 26.73,121.58 26.72,121.58 26.31,121.58 26.15,121.42 25.19,121.42 25.14,121.47 25.14,121.91 25.22,121.99 25.99,121.99 26.19,122.18 26.19,122.32 26.44,122.57 26.86,122.57 28.21,123.93 30.12,123.93
+3VALW on IN1 (solid shape): 30.18,122.89 30.18,121.56 29.8,121.18 28.85,121.18 28.6,121.43 28.6,122.57 29.04,123.02 30.06,123.02
+3VALW on IN1 (solid shape): 114.74,117.97 114.74,116.47 114.74,116.46 114.74,116.32 114.62,116.2 113.61,116.2 113.48,116.32 113.48,117.64 113.37,117.75 113.37,118.4 113.54,118.57 114.15,118.57
+3VALW on IN1 (solid shape): 61.83,118.08 61.83,116.9 61.47,116.54 59.39,116.54 58.95,116.99 58.95,117.94 59.27,118.27 61.63,118.27
+3VALW on VCC: 163.72,23.33 163.72,25.97 161.92,27.77 138.53,27.77 135.04,24.28 133.24,24.28 133.24,25.69 134.77,27.22 134.77,30.27 138.89,34.39 138.89,45.19 141.3,47.6 144.78,51.07 151.45,51.07 153.12,52.74 153.12,59.62 151.7,61.04 147.15,61.04 147.15,73.89 149.05,75.8 149.05,84.66 147.72,86 145.6,86 145.09,86.51 141.31,86.51 141.31,103.69 139.51,105.49 117.24,105.49 117.24,107.61 117.6,107.97 122.68,107.97 124.09,109.38 139.35,109.38 143.02,105.7 143.02,90.21 144.57,88.66 149.77,88.66 152.17,86.27 152.17,74.8 150.13,72.77 150.13,66.84 156.87,60.11 156.87,51.18 149.75,44.07 149.75,42.2 149.9,42.06 150.11,42.06 164.63,42.06 170.64,36.05 170.64,23.33
+3VALW_EC on TOP (solid shape): 147.07,17.87 147.07,16.03 148.37,14.74 148.37,13.63 148.47,13.53 149.02,13.53 149.11,13.44 149.11,12.91 149.02,12.82 147.99,12.82 147.72,13.09 147.72,14.6 146.97,15.35 146.87,15.35 146.87,15.74 146.06,15.74 146.06,15.2 146.05,15.19 145.87,15.19 145.87,15.22 145.69,15.22 145.65,15.26 145.65,15.82 146.34,16.5 146.34,17.87 146.44,17.98 146.97,17.98
+3VALW_EC on BOTTOM (solid shape): 142.73,27.06 142.73,26.64 143.38,25.99 143.38,25.71 143.13,25.46 143.02,25.46 142.01,26.48 142.01,27.15 142.06,27.2 142.59,27.2
+3VALW_PCH on TOP (solid shape): 117.94,17.93 117.94,16.83 117.83,16.72 115.08,16.72 114.86,16.94 114.86,17.95 115,18.09 117.78,18.09
+3VALW_PCH on TOP (solid shape): 125.94,5.54 125.94,4.71 124.84,3.61 124,3.61 123.86,3.75 123.86,4.16 124.55,4.85 124.57,4.85 124.57,4.87 124.8,5.1 124.8,5.54 124.99,5.73 125.75,5.73
+3VALW_PCH on TOP (solid shape): 137.6,40.1 137.6,39.41 137.21,39.02 136.89,39.02 136.88,39.03 135.48,39.03 135.32,39.19 135.32,39.71 135.32,39.71 135.32,39.78 135.79,40.24 137.46,40.24
+3VALW_PCH on TOP (solid shape): 161.81,26.12 162.51,26.12 162.53,26.1 162.53,25.8 162.01,25.8 161.99,25.78 161.99,24.96 161.99,24.95 161.99,24.43 162.01,24.4 162.53,24.4 162.53,23.66 162.39,23.52 161.05,23.52 160.86,23.71 160.86,25.61 160.8,25.67 160.8,26.31 160.99,26.5 161.44,26.5
+3VALW_PCH on BOTTOM (solid shape): outline of 137 points within 131.51,35.77 136.55,40.37
+3VALW_PCH on IN1 (solid shape): 126.45,4.23 126.45,3.64 126.13,3.32 125.82,3.32 125.72,3.42 123.97,3.42 123.97,4.11 124.33,4.46 126.21,4.46
+3VALW_PCH on IN1 (solid shape): 155.09,6.43 155.09,6.05 154.1,5.06 152.33,5.06 152.04,5.35 152.04,6.05 152.23,6.24 153.5,6.24 154.07,6.81 154.71,6.81
+3VALW_PCH on IN1 (solid shape): 162.5,24.08 162.5,22.77 162.34,22.62 161.48,22.62 160.93,23.17 160.93,24.59 161.25,24.91 161.67,24.91
+3VALW_PCH on IN1 (solid shape): outline of 1782 points within 107.47,35.07 117.3,46.6
+3VALW_PCH on IN2 (solid shape): 114.76,28.33 114.76,25.99 114.88,25.69 115.15,25.55 115.53,25.18 115.53,24.78 115.34,24.59 115.34,23.87 115.69,23.51 115.69,18.98 115.92,18.75 115.92,17.21 115.77,17.07 114.9,17.07 114.65,17.32 114.65,21.04 114.32,21.37 114.32,24.47 113.26,25.53 113.26,28.44 113.39,28.57 114.52,28.57
+3VALWP on TOP (solid shape): 162.96,42.51 162.96,39.77 162.71,39.52 162.37,39.52 162.11,39.68 161.82,39.59 161.75,39.56 161.68,39.59 161.39,39.68 161.13,39.52 160.61,39.52 160.55,39.58 160.55,40.26 160.55,40.26 160.55,40.28 160.03,40.28 160.03,40.73 160.55,40.73 160.55,40.76 160.55,40.76 160.55,41.46 160.55,41.46 160.55,41.48 160.03,41.48 160.03,41.93 160.55,41.93 160.55,41.96 160.55,41.96 160.55,42.74 160.55,42.74 160.55,42.76 162.71,42.76
+3VALWP on BOTTOM (solid shape): 166.52,44.28 166.52,39.77 165.75,39.01 162.64,39.01 162.45,39.2 162.45,39.58 162.26,39.77 159.09,39.77 159.02,39.84 159.02,40.6 159.15,40.73 159.53,40.73 159.66,40.85 159.66,43.51 159.72,43.58 162.95,43.58 163.91,44.54 166.26,44.54
+3VLP on BOTTOM (solid shape): 174.45,42.18 174.45,41.61 174.33,41.48 174.33,41.04 174.26,40.98 173.76,40.98 173.57,41.17 173.57,42.18 173.63,42.25 174.39,42.25
+3VS on TOP (solid shape): 34.44,74.69 34.44,73.11 33.8,72.47 32.72,72.47 32.34,72.85 32.34,74.76 32.41,74.82 34.31,74.82
+3VS on TOP (solid shape): 35.71,94.89 35.71,91.39 35.26,90.95 33.48,90.95 32.6,91.84 32.6,95.65 32.79,95.84 34.75,95.84
+3VS on TOP (solid shape): 42.4,20.9 42.4,20.03 42.32,19.95 40.72,19.95 40.61,20.06 40.61,20.98 40.68,21.05 42.26,21.05
+3VS on TOP (solid shape): 120.73,16.46 120.73,13.23 123.46,10.49 123.46,7.45 123.21,7.19 122.7,7.19 122.58,7.32 122.58,9.04 119.58,12.03 119.58,16.58 119.72,16.73 120.46,16.73
+3VS on TOP (solid shape): 61.15,106.24 61.15,104.63 61.12,104.59 57.74,104.59 56.86,103.71 55.84,103.71 55.33,104.22 55.33,105.75 55.81,106.23 55.83,106.23 55.94,106.35 61.04,106.35
+3VS on TOP (solid shape): 184.42,16.78 185.95,16.78 187.47,15.26 187.47,13.35 187.31,13.19 184.46,13.19 184.17,13.48 184.17,14.62 184.11,14.69 183.92,14.69 183.88,14.72 182.61,14.72 182.52,14.81 181.25,14.81 181.06,14.62 181.06,13.61 181.03,13.58 181.03,12.43 179.03,10.43 176.36,10.43 175.09,11.7 175.09,12.53 179.92,17.35 183.85,17.35
+3VS on TOP (solid shape): 109.14,16.83 109.19,16.65 109.32,16.52 109.32,16.2 109.37,16.14 109.37,14.94 107.24,12.81 107.24,8.7 107.18,8.63 106.48,8.63 106.46,8.61 106.33,8.61 106.07,8.35 106.07,8.1 106.06,8.04 106.05,7.98 106.05,7.81 106.06,7.75 106.07,7.69 106.07,6.2 106.06,6.14 106.05,6.08 106.05,5.91 106.06,5.85 106.07,5.79 106.07,5.52 106.22,5.37 106.22,5.25 106.23,5.24 106.23,4.74 106.18,4.69 105.56,4.69 105.52,4.73 105.52,8.9 106.2,9.58 106.21,9.59 106.21,13.5 107.93,15.21 107.93,16.65 108.13,16.85 109.12,16.85
+3VS on TOP (solid shape): outline of 213 points within 158.77,10.62 165.5,26.49
+3VS on BOTTOM (solid shape): 229.64,25.86 229.64,24.34 229.38,24.08 227.73,24.08 227.22,24.59 226.33,24.59 225.25,23.51 224.64,23.51 224.41,23.74 224.41,24.54 225.6,25.74 227.1,25.74 227.35,25.99 229.51,25.99
+3VS on IN1 (solid shape): outline of 280 points within 173.57,9.59 228.94,25.23
+3VS on VCC: 62.54,15.71 58.87,19.38 55.83,22.42 50.04,28.21 44.13,28.22 41.17,31.24 41.17,37.97 33.61,45.53 33.61,93.07 34.03,93.49 36.62,93.49 37.99,92.11 37.99,49.19 45.3,41.89 45.3,37.7 61.57,21.42 66.27,21.42 67.35,20.34 70.42,20.34 71.5,21.42 76.2,21.42 81.72,26.94 83.69,26.94 85.22,28.47 87.69,28.47 95.06,35.83 105.05,35.83 105.05,29.07 110.34,23.77 135.25,23.77 138.74,27.27 161.71,27.27 163.21,25.76 163.21,23.18 162.16,22.12 160.27,22.12 159.06,23.33 144.65,23.33 144.29,23.18 136.88,15.71
+5V_CAM on TOP (solid shape): 216.6,50.71 217.24,50.71 217.33,50.62 217.33,49.99 217.65,49.68 219.54,49.68 220.33,48.88 220.33,48.5 220.87,48.5 220.87,48.31 220.33,48.31 220.33,47.8 220.23,47.7 219.23,47.7 218.33,48.6 215.22,48.6 215.03,48.79 215.03,50.31 215.11,50.39 215.59,50.39 215.79,50.59 215.79,50.82 215.92,50.95 216.36,50.95
+5V_CAM on BOTTOM (solid shape): 216.3,51.04 216.3,49.98 216.16,49.84 216.14,49.84 216.03,49.77 215.97,49.66 215.96,49.64 215.94,49.62 215.94,48.57 215.85,48.48 214.92,48.48 214.68,48.72 214.68,51.15 214.8,51.27 216.08,51.27
+5V_HDD on TOP (solid shape): outline of 175 points within 189.46,21.06 196.52,25.55
+5V_HDD on BOTTOM (solid shape): outline of 210 points within 187.07,16.08 194.81,24.09
+5V_HDMI on TOP (solid shape): 22.31,97.11 22.31,96.54 21.99,96.22 21.1,96.22 19.96,97.36 19.96,97.62 20.59,98.25 21.17,98.25
+5V_HDMI on TOP (solid shape): 30.37,80.41 30.37,78.78 30.18,78.59 28.36,78.59 28.19,78.76 27.34,78.76 27.24,78.86 27.24,80.38 27.58,80.73 30.06,80.73
+5V_HDMI on IN2 (solid shape): 13.29,92.03 13.29,91.39 12.47,90.57 11.83,90.57 11.58,90.82 11.58,91.2 12.78,92.41 12.91,92.41
+5V_HDMI on IN2 (solid shape): 21.93,97.49 21.93,97.11 21.74,96.92 20.4,96.92 19.51,97.81 19.51,98.32 19.77,98.57 20.85,98.57
+5V_KB_BL on BOTTOM (solid shape): 123.59,10.5 123.59,8.97 122.7,8.08 115.97,8.08 115.84,8.21 115.84,9.29 116.35,9.8 116.49,9.8 116.5,9.79 116.61,9.77 116.71,9.79 116.72,9.8 118.7,9.8 118.96,10.05 118.96,11.07 119.08,11.19 122.89,11.19
+5V_OUT on TOP (solid shape): 169.18,22.06 171.15,20.09 171.15,19.33 171.15,19.33 171.15,17.79 171.03,17.67 170.45,17.67 170.45,18.18 168.42,18.18 168.42,17.67 167.98,17.67 167.98,18.56 167.75,18.78 167.75,19.8 167.66,19.89 167.66,20.15 168.16,20.15 168.16,19.24 168.3,19.1 168.34,19.06 168.39,19.04 168.44,19.02 168.5,19.01 168.55,19 168.61,19.01 168.66,19.02 168.71,19.04 168.76,19.07 168.81,19.1 168.84,19.14 168.88,19.19 168.9,19.24 168.92,19.29 168.93,19.35 168.93,19.4 168.92,19.46 168.92,19.48 168.92,20.15 168.92,20.55 168.16,20.55 168.16,20.15 167.66,20.15 167.66,20.97 168.04,21.35 168.04,22.43 168.1,22.5 168.74,22.5 168.74,22.5
+5V_PVDD on TOP (solid shape): 38.88,23.96 38.88,21.1 36.91,19.13 33.93,19.13 33.74,18.94 31.96,18.94 31.71,19.2 29.99,19.2 29.93,19.26 29.93,19.45 29.99,19.51 30.82,19.51 30.94,19.39 33.04,19.39 33.17,19.51 33.17,19.89 33.23,19.96 35.52,19.96 37.23,21.67 37.23,22.24 36.69,22.78 34.91,22.78 34.5,22.37 32.02,22.37 30.88,21.23 30.06,21.23 29.99,21.29 29.99,21.42 30.06,21.48 30.75,21.48 30.81,21.54 30.94,21.6 31.01,21.73 32.28,23.01 33.48,23.01 34.63,24.15 38.69,24.15
+5VALW on TOP (solid shape): 221.44,51.33 221.44,47.83 221.32,47.71 220.62,47.71 220.49,47.83 220.49,48.15 221.06,48.15 221.06,48.66 220.49,48.66 220.49,48.98 219.56,49.91 218.82,49.91 218.71,50.02 218.71,50.62 218.81,50.72 219.69,50.72 220.37,51.39 221.38,51.39
+5VALW on TOP (solid shape): 171.78,23.77 172.36,23.77 172.36,23.77 172.36,23.2 174.39,23.2 174.39,23.77 176.61,23.77 176.8,23.58 176.8,22.88 176.66,22.73 175.72,22.73 174.9,21.91 174.9,21.55 174.52,21.17 170.45,21.17 168.93,22.69 168.93,23.64 168.74,23.83 168.17,23.83 168.17,23.83 168.1,23.83 168.04,23.89 168.04,24.73 168.17,24.85 170.7,24.85
+5VALW on BOTTOM (solid shape): 7.19,28.78 7.19,27.58 6.69,27.07 4.47,27.07 4.15,27.39 4.15,28.85 4.39,29.1 6.88,29.1
+5VALW on BOTTOM (solid shape): 53.57,5.66 53.57,4.98 53.29,4.7 52.98,4.7 52.73,4.45 52.73,3.68 52.56,3.51 51.24,3.51 51.07,3.68 51.07,5.61 51.37,5.92 53.31,5.92
+5VALW on BOTTOM (solid shape): outline of 143 points within 165.14,19.84 174.21,25.26
+5VALW on VCC: 40.66,1.27 40.66,16 33.65,23.01 32.02,23.01 31.64,23.39 31.64,24.78 31.9,25.04 31.9,26.94 31.2,27.64 28.28,27.64 27.45,26.82 3.57,26.82 3.57,26.9 3.57,29.9 12.28,29.9 13.48,30.36 14.04,31.52 32.65,31.52 36.15,28.02 36.15,26.82 36.72,26.24 36.72,23.6 44.02,16.3 44.02,10.46 47.79,6.69 109.22,6.69 112.84,10.31 120.56,10.31 125.01,5.87 140.84,5.87 143.47,8.49 143.47,12.24 146.05,14.81 169.48,14.81 171.01,16.35 172.04,17.38 172.04,19.05 170.14,20.96 170.14,22.82 178.28,22.82 180.1,21 180.1,19.05 180.11,17.38 180.11,16.35 180.11,12.61 181.4,11.32 222.63,11.32 224.43,13.12 224.43,19.72 228.87,24.17 228.87,46.99 226.19,49.68 219.45,49.68 218.97,50.16 218.97,53.54 219.84,53.87 220.7,54.23 230.63,54.23 230.63,20.81 229.1,20.81 226.33,18.04 229.1,15.27 230.63,15.27 230.63,9.57 178,9.57 176.39,8.91 175.73,7.3 175.73,1.27
+5VALWP on TOP (solid shape): 174.96,26.31 174.96,23.96 174.94,23.94 173.18,23.94 173.18,23.94 171.82,23.94 171.52,24.24 171.52,26.62 171.65,26.76 174.52,26.76
+5VALWP on BOTTOM (solid shape): 175.34,28.79 175.34,22.5 175.28,22.44 174.58,22.44 173.95,23.07 170.14,23.07 170.07,23.14 170.07,23.8 170.08,23.81 170.11,23.96 170.08,24.11 170.07,24.12 170.07,24.44 170.08,24.45 170.11,24.6 170.08,24.75 170.07,24.76 170.07,25.07 170.08,25.08 170.11,25.23 170.08,25.38 170.07,25.39 170.07,25.71 170.08,25.72 170.11,25.87 170.08,26.02 170.07,29.42 170.2,29.55 174.58,29.55
+5VS on TOP (solid shape): 30.82,76.54 30.82,75.01 30.51,74.7 28.41,74.7 28.28,74.82 28.28,76.73 28.41,76.85 30.51,76.85
+5VS on TOP (solid shape): 228.94,30.12 228.94,28.34 228.75,28.15 227.99,28.15 227.67,28.47 227.67,29.99 227.99,30.31 228.75,30.31
+5VS on TOP (solid shape): 38.82,26.94 38.82,25.09 38.7,24.97 37.24,24.97 37.17,25.04 37.17,26.31 36.6,26.88 36.6,27.45 36.79,27.64 38.12,27.64
+5VS on TOP (solid shape): 183.92,51.07 184.61,51.07 185.12,50.56 185.12,49.55 185.06,49.48 181.95,49.48 181.31,50.12 181.31,50.69 182.71,52.09 182.9,52.09
+5VS on TOP (solid shape): 196.57,47.03 197.12,47.03 197.12,47.01 197.38,47.01 197.82,46.56 197.82,45.17 197,44.34 195.03,44.34 194.46,44.91 194.46,46.45 195.03,47.02 195.52,47.02 195.52,47.57 195.77,47.57 195.77,47.02 196.31,47.02 196.31,47.57 196.57,47.57
+5VS on TOP (solid shape): 167.79,18.37 167.79,17.54 167.82,17.51 167.82,17.49 167.84,17.49 167.91,17.42 171.03,17.42 171.09,17.35 171.09,16.59 170.33,15.83 170.25,15.8 170.18,15.84 169.64,15.88 169.68,15.34 169.72,15.27 169.69,15.19 169.57,15.07 166.64,15.07 165.56,16.15 165.56,17.73 165.69,17.86 166.01,17.86 166.07,17.93 166.07,18.62 166.2,18.75 167.41,18.75
+5VS on BOTTOM (solid shape): 124.48,14.91 124.48,12.59 124.29,12.4 122,12.4 121.88,12.53 121.88,14.38 122.51,15.02 124.37,15.02
+5VS on BOTTOM (solid shape): 184.36,51.01 184.36,50.63 184.23,50.5 183.41,50.5 181.95,51.96 181.95,52.47 182.27,52.79 182.58,52.79
+5VS on IN1 (solid shape): 191.41,24.02 191.41,23.26 191.22,23.07 190.08,23.07 189.63,23.51 189.63,23.83 190.27,24.47 190.96,24.47
+5VS on IN1 (solid shape): 169.01,18.17 169.01,17.61 167.6,16.21 167.22,16.21 167.09,16.34 167.09,16.53 167.34,16.78 167.34,17.57 168.35,18.58 168.6,18.58
+5VS on TOP: 194.37,25.18 194.37,25.71 193.27,25.71 193.25,25.74 192.23,25.74 191.73,25.23 191.73,25.21 191.41,24.89 191.41,23.2 191.22,23.01 190.39,23.01 189.95,23.45 189.95,29.55 190.69,30.28 190.69,31.13 191.69,32.14 191.69,36.96 192.74,38.02 195.4,38.02 196.3,38.92 197.15,38.92 198.44,37.62 198.44,36.87 196.98,35.41 196.98,34.45 197.11,34.32 197.11,32.83 196.06,31.78 196.06,29.3 195.85,29.1 195.85,26.82 196.04,26.62 196.04,25.8 196.04,25.8 196.04,25.72 195.43,25.72 195.43,25.18 195.18,25.18 195.18,25.73 194.62,25.73 194.62,25.18
+5VS on VCC: 125.22,6.37 120.77,10.82 112.63,10.82 109.01,7.2 48,7.2 44.53,10.67 44.53,16.51 37.25,23.79 37.25,26.5 36.66,27.09 36.66,28.21 32.85,32.02 29.1,32.02 29.1,33.95 30.44,35.28 30.44,37.84 24.98,43.3 24.98,54.59 27.07,56.69 27.07,58.73 24.98,60.83 24.98,75.99 25.84,76.85 33.1,76.85 33.1,45.32 40.66,37.76 40.66,31.03 43.92,27.71 49.83,27.7 55.47,22.06 58.51,19.02 62.33,15.2 137.09,15.2 144.65,22.82 158.85,22.82 160.06,21.61 162.37,21.61 163.57,22.82 169.63,22.82 169.63,20.75 171.53,18.84 171.53,17.59 170.65,16.71 169.27,15.32 145.84,15.32 142.96,12.45 142.96,8.7 140.63,6.37
+5VS_ODD on TOP (solid shape): 197.05,50.72 197.46,50.72 197.64,50.54 197.64,47.24 197.57,47.17 196.72,47.17 196.72,47.72 196.17,47.72 196.17,47.17 195.92,47.17 195.92,47.73 195.37,47.73 195.37,47.17 195.06,47.17 194.99,47.24 194.99,48.47 195.19,48.67 195.19,50.57 195.33,50.72 197.05,50.72
+5VS_ODD on BOTTOM (solid shape): 197.81,51.08 197.81,47.12 197.65,46.96 195.31,46.96 195.14,47.14 195.14,51.09 195.26,51.21 197.68,51.21
+17.4V_BATT+ on TOP (solid shape): 216.05,24.53 216.05,21.48 215.92,21.35 212.3,21.35 212.11,21.54 212.11,22.69 214.02,24.59 215.98,24.59
+17.4V_BATT+ on BOTTOM (solid shape): 215.98,25.49 215.98,21.42 215.79,21.23 213.38,21.23 213.19,21.04 213.19,19.96 212.43,19.2 203.62,19.2 203.62,19.72 203.07,19.72 203.07,19.2 202.81,19.2 202.81,19.72 202.26,19.72 202.26,19.2 202.26,19.2 200.25,19.2 200.11,19.34 200.11,20.72 200.67,21.29 204.3,21.29 204.55,21.54 204.59,21.54 205.17,22.12 205.17,22.16 205.83,22.82 210.71,22.82 211.41,23.52 211.41,23.77 211.79,24.15 212.17,24.15 212.74,24.73 213.38,24.73 213.38,23.2 213.44,23.14 214.01,23.14 214.08,23.2 214.08,24.66 214.14,24.73 214.39,24.73 215.22,25.55 215.92,25.55
+17.4V_BATT++ on BOTTOM (solid shape): 202.67,19.03 203.22,19.03 203.22,19.57 203.47,19.57 203.47,19.02 211.88,19.02 212.3,18.59 212.3,15.2 211.98,14.88 202.52,14.88 201.35,16.05 201.35,18.76 201.61,19.02 202.41,19.02 202.41,19.57 202.67,19.57
+19V_ADPIN on BOTTOM (solid shape): 81.3,124.86 81.3,121.3 80.78,121.3 80.78,120.74 81.3,120.74 81.3,120.49 80.79,120.49 80.79,119.94 81.3,119.94 81.3,118.95 81.11,118.76 78.38,118.76 78.06,119.08 78.06,124.86 78.57,125.37 80.79,125.37
+19V_VIN on BOTTOM (solid shape): 92.12,128.68 92.12,125.05 92.09,124.9 92.12,124.75 92.12,124.54 91.13,123.55 89.44,123.55 89.36,123.47 89.36,122.7 85.43,118.76 81.68,118.76 81.49,118.95 81.49,120.1 80.94,120.1 80.94,120.35 81.49,120.35 81.49,120.91 80.94,120.91 80.94,121.15 81.48,121.15 81.48,121.87 81.49,121.87 81.49,123.27 81.94,123.72 83.59,123.72 84.41,124.54 84.41,126.07 87.6,129.25 91.55,129.25
+19VB on TOP (solid shape): 105.76,123.11 105.76,121.85 105.26,121.35 102.36,121.35 101.96,121.75 101.96,123.13 102.37,123.54 105.33,123.54
+19VB on TOP (solid shape): 212.97,28.7 212.97,28.39 211.67,27.09 207.52,27.09 207.21,27.4 207.21,28.9 207.68,29.37 210.25,29.37 211.01,30.13 211.54,30.13
+19VB on TOP (solid shape): 230.11,45.72 230.11,39.38 229.76,39.02 226.64,39.02 225.96,39.71 225.96,40.65 226.35,41.05 226.35,41.8 226.81,42.26 226.81,43.32 226.55,43.58 226.55,44.42 225.89,45.08 225.89,45.68 226.08,45.87 229.97,45.87
+19VB on TOP (solid shape): 160.97,103.66 160.97,99.19 161.03,99.14 161.05,98.97 161.08,98.81 161.47,97.64 162.14,96.6 165.2,94.85 168.65,95.54 168.68,95.56 168.78,95.46 168.78,87.5 169.47,80.48 171.5,73.72 171.51,73.69 171.35,73.53 165.2,73.53 164.76,73.96 164.76,82.61 163.37,84.01 163.37,88.22 162.45,89.14 162.47,89.18 162.42,89.66 161.94,89.65 157.98,93.61 157.98,96.18 157.21,96.96 157.21,103.79 157.51,104.09 160.54,104.09
+19VB on BOTTOM (solid shape): 105.48,125.25 105.48,120.57 104.6,119.69 102.39,119.69 101.9,120.19 101.9,123.28 102.37,123.75 103.89,123.75 103.89,124.39 102.34,124.39 102.34,125.43 102.8,125.89 104.85,125.89
+19VB on BOTTOM (solid shape): 96.31,117.85 96.31,116.16 96.86,116.16 96.86,115.92 96.32,115.92 96.32,115.37 96.86,115.37 96.86,115.11 96.32,115.11 96.32,114.36 96.04,114.08 92.54,114.08 92.39,114.24 92.39,117.77 92.76,118.14 96.02,118.14
+19VB on BOTTOM (solid shape): 81.64,114.42 81.64,113.18 81.3,112.83 81.3,111.83 81.1,111.63 80.46,111.63 79.78,110.95 79.22,110.95 79.22,111.45 78.72,111.45 78.72,110.95 78.42,110.95 78.42,111.45 77.92,111.45 77.92,110.95 76.92,110.95 76.66,111.21 76.66,113.81 77.74,114.89 81.17,114.89
+19VB on BOTTOM (solid shape): 158.3,47.37 160.44,47.37 160.61,47.2 160.61,45.67 160.42,45.48 159.53,45.48 159.52,45.49 159.36,45.33 159.36,44.32 159.13,44.09 157.5,44.09 157.18,44.41 157.18,44.59 157.14,44.64 157.14,45.2 156.58,45.2 156.58,45.45 157.13,45.45 157.13,46 156.58,46 156.58,46.26 157.13,46.26 157.13,47.53 157.3,47.71 157.97,47.71
+19VB on BOTTOM (solid shape): 158.77,105.86 159.65,105.86 160.82,104.69 160.82,100.55 160.37,100.1 157.15,100.1 157.15,100.62 156.45,100.62 156.45,100.61 156.4,100.61 156.4,100.12 156.07,100.12 156.07,100.1 155.95,100.1 155.95,100.62 155.25,100.62 155.25,100.61 155.2,100.61 155.2,100.12 154.87,100.12 154.87,100.12 154.44,100.12 154.31,100.24 154.31,102.44 155.21,103.35 155.21,105.24 155.85,105.87 158.76,105.87
+19VB on BOTTOM (solid shape): outline of 103 points within 190.77,21.61 209,29.48
+19VB on BOTTOM (solid shape): outline of 87 points within 163.53,32.79 188.55,80.72
+19VB_1.2V on BOTTOM (solid shape): 81.36,111.4 81.36,105.49 81.11,105.24 77.81,105.24 77.74,105.3 77.74,105.75 77.81,105.81 78.32,105.81 78.51,106 78.51,107.08 76.92,108.67 76.92,110.77 78.04,110.77 78.04,111.32 78.29,111.32 78.29,110.77 78.84,110.77 78.84,111.32 79.09,111.32 79.09,110.82 79.1,110.82 79.1,110.78 79.9,110.78 80.58,111.46 81.3,111.46
+19VB_+1VALW on BOTTOM (solid shape): 156.93,46.82 156.93,46.4 156.44,46.4 156.44,45.85 156.93,45.85 156.93,45.6 156.44,45.6 156.44,45.05 156.93,45.05 156.93,44.47 157.56,43.84 157.94,43.84 158.2,43.58 158.2,43.08 158.07,42.95 155.02,42.95 154.77,43.2 154.77,43.52 154.41,43.87 153.21,43.87 153.17,43.91 153.17,43.93 152.96,44.19 152.62,44.16 151.91,44.16 151.53,43.78 150.07,43.78 150.01,43.84 150.01,46.06 151.02,47.08 156.67,47.08
+VCC_CORE on TOP (solid shape): outline of 3402 points within 106.57,50.04 148.99,85.49
+VCC_CORE on BOTTOM (solid shape): outline of 419 points within 132.43,63.77 148.8,85.49
+VCC_CORE on BOTTOM (solid shape): outline of 679 points within 106.56,51.22 109.41,57.02
+VCC_CORE on BOTTOM (solid shape): outline of 775 points within 117.12,50.74 120.07,58.3
+VCC_CORE on IN1 (solid shape): outline of 731 points within 133.71,63.81 148.36,85.49
+VCC_CORE on IN1 (solid shape): outline of 1355 points within 108.01,49.99 118.57,58.6
+VCC_CORE on IN2 (solid shape): outline of 734 points within 133.71,63.73 148.99,85.49
+VCC_CORE on IN2 (solid shape): outline of 1595 points within 106.57,49.57 118.73,58.82
+VCC_CORE on VCC: 105.56,50.95 105.56,56.34 105.56,56.4 105.56,56.41 107.93,56.41 108.34,56.82 108.34,57.96 109.08,58.71 111.01,58.71 112.17,57.55 117.47,57.55 117.98,58.06 123.51,58.06 124.67,59.22 124.67,64.11 125.12,64.56 125.12,69.45 133.18,77.51 133.18,79.61 139.57,86 144.89,86 145.41,85.48 147.53,85.48 148.55,84.46 148.55,76.01 146.64,74.1 146.64,57.74 137.35,57.75 137.14,57.75 133.96,57.74 127.17,50.95 118.78,50.95 118.14,50.3 117.35,50.3 116.71,50.95
+VCC_GT on TOP (solid shape): 138.96,104.2 138.96,101.11 140.82,99.25 140.82,90.5 140.38,90.06 122.51,90.06 119.97,92.6 119.97,101.81 123.13,104.97 138.18,104.97
+VCC_GT on TOP (solid shape): outline of 428 points within 107.49,58.48 118.73,68.28
+VCC_GT on BOTTOM (solid shape): outline of 708 points within 109.68,76.15 141.31,104.98
+VCC_GT on BOTTOM (solid shape): outline of 1092 points within 107.03,57.09 109.8,67.96
+VCC_GT on BOTTOM (solid shape): outline of 3119 points within 110.2,58.43 119.2,78.03
+VCC_GT on IN1 (solid shape): outline of 7634 points within 104.03,57.55 140.82,104.97
+VCC_GT on IN2 (solid shape): 138.89,104.25 138.89,101.17 140.8,99.27 140.8,90.07 140.53,89.81 132.61,89.81 125.27,97.15 125.25,97.15 121.34,101.06 121.34,103.14 123.18,104.98 138.16,104.98
+VCC_GT on IN2 (solid shape): outline of 2726 points within 107.43,58.49 119.01,84.55
+VCC_GT on VCC: 105.56,56.92 105.41,59.84 105.11,60.13 105.11,66.16 104.71,66.57 101.51,66.57 100.75,65.8 100.2,65.8 99.97,66.04 99.97,72.15 109.62,81.81 109.62,97.51 117.09,104.98 139.3,104.98 140.8,103.48 140.8,86.51 139.38,86.51 132.67,79.8 132.67,77.72 124.61,69.66 124.61,64.77 124.16,64.32 124.16,59.43 123.3,58.57 117.77,58.57 117.26,58.06 112.56,58.06 112.55,58.05 112.41,58.05 111.26,59.2 108.86,59.2 107.84,58.19 107.84,57.02 107.75,56.92
+VCC_SA on TOP (solid shape): outline of 367 points within 108.42,46.99 122.58,49.91
+VCC_SA on BOTTOM (solid shape): 149.62,58.75 150.38,58.75 150.38,59.65 152.4,59.65 152.7,59.34 152.7,55.67 152.29,55.26 147.53,55.26 147.04,55.75 147.04,59.3 147.39,59.65 149.62,59.65
+VCC_SA on BOTTOM (solid shape): 108.99,48.12 108.99,47.17 108.8,46.98 108.54,47.08 108.29,46.98 108.1,46.98 107.98,47.11 107.98,48.12 108.1,48.25 108.86,48.25
+VCC_SA on BOTTOM (solid shape): outline of 496 points within 117.18,46.53 119.96,50.96
+VCC_SA on IN1 (solid shape): outline of 431 points within 108.46,46.75 118.72,49.48
+VCC_SA on IN2 (solid shape): outline of 387 points within 108.37,46.57 118.26,49.46
+VCC_SA on VCC: 120.39,41.74 118,44.13 118,46.41 117.47,46.94 116.5,46.94 116.18,46.63 113.01,46.63 112.44,46.06 105.56,46.06 105.56,50.44 116.52,50.44 117.16,49.8 118.36,49.8 118.99,50.44 127.38,50.44 134.17,57.23 137.24,57.24 146.79,57.23 147.06,57.23 147.21,57.38 147.21,57.59 147.15,57.65 147.15,60.53 151.49,60.53 152.61,59.41 152.61,52.96 151.24,51.58 144.57,51.58 141.01,48.03 140.86,47.88 138.47,45.49 136.25,45.49 134.13,45.48 133.52,45.48 129.77,41.74
GND on TOP (solid shape): 14.63,52.15 14.63,45.55 14.21,45.13 3.1,45.13 2.62,45.61 2.62,51.9 3.32,52.6 14.18,52.6
GND on TOP (solid shape): 15.58,30.5 15.58,29.55 15.13,29.1 2.88,29.1 2.62,29.36 2.62,30.43 3,30.82 15.26,30.82
GND on TOP (solid shape): 38.23,67.51 38.23,64.9 37.53,64.21 34.72,64.21 34.4,64.53 34.4,67.92 34.56,68.07 37.66,68.07
GND on TOP (solid shape): 44.85,45.39 44.85,44.09 44.5,43.74 43.44,43.74 43.25,43.93 43.25,45.4 43.4,45.55 44.69,45.55
GND on TOP (solid shape): 67.22,109.55 67.22,108.44 67.14,108.36 63.74,108.36 63.6,108.5 63.6,109.61 63.81,109.82 66.95,109.82
GND on TOP (solid shape): 74.67,107.83 74.67,106.37 74.56,106.26 73.03,106.26 72.92,106.37 72.92,107.8 73.12,108.01 74.49,108.01
GND on TOP (solid shape): 74.76,32.21 74.76,28.59 74.51,28.34 69.11,28.34 68.98,28.47 68.98,32.02 69.49,32.53 74.44,32.53
GND on TOP (solid shape): 101.37,116.73 101.37,115.33 101.11,115.08 100.1,115.08 99.91,115.27 99.91,116.79 100.08,116.97 101.12,116.97
GND on TOP (solid shape): 145.63,90.38 145.63,89.49 145.44,89.3 144.55,89.3 144.29,89.55 144.29,90.51 144.42,90.63 145.37,90.63
GND on TOP (solid shape): 146.96,7.83 146.96,0.72 146.51,0.27 137.05,0.27 136.74,0.59 136.74,8.15 139.59,11 143.78,11
GND on TOP (solid shape): 153.82,79.84 153.82,78.76 153.69,78.63 152.8,78.63 152.67,78.76 152.67,80.03 152.8,80.16 153.5,80.16
GND on TOP (solid shape): 157.88,42.25 157.88,41.42 156.67,40.21 153.31,40.21 152.29,41.23 152.29,42.94 152.55,43.2 156.93,43.2
GND on TOP (solid shape): 217.7,24.53 217.7,21.35 217.63,21.29 216.49,21.29 216.24,21.54 216.24,24.28 216.56,24.59 217.63,24.59
GND on TOP (solid shape): 74.36,75.57 74.36,72.64 73.82,72.1 70.64,72.1 70.06,72.68 70.06,76.15 70.25,76.35 73.58,76.35
GND on TOP (solid shape): 140.23,29.8 140.23,27.45 140.16,27.39 138.2,27.39 138.01,27.58 138.01,29.04 138.07,29.1 138.26,29.1 139.09,29.93 140.1,29.93
GND on TOP (solid shape): 223.17,43.06 223.17,42.59 223.03,42.45 223.03,41.32 222.99,41.28 222.05,41.28 221.91,41.42 221.91,43.05 222.06,43.19 223.04,43.19
GND on TOP (solid shape): 27.43,3.44 27.43,2.83 27.19,2.59 25.49,2.59 25.47,2.61 24.31,2.61 24.05,2.87 24.05,4.51 24.4,4.86 26.01,4.86
GND on TOP (solid shape): 27.38,7.51 27.38,6.92 27.14,6.68 24.56,6.68 24.43,6.82 24.43,7.65 24.64,7.86 27.02,7.86
GND on TOP (solid shape): 150.13,70 150.13,68.22 148.42,66.5 148.41,66.5 148.05,66.15 145.65,66.15 145.46,66.34 145.46,68.18 147.4,70.12 150.01,70.12
GND on TOP (solid shape): 92.02,45.04 92.02,41.09 91.75,40.82 89.17,40.82 89.16,40.84 88.61,40.84 88.29,41.17 88.29,42.44 89.23,43.38 90.9,43.38 91.19,43.66 91.19,45.08 91.37,45.26 91.81,45.26
GND on TOP (solid shape): 13.61,96.47 13.61,94 12.85,93.24 9.99,93.24 9.8,93.43 9.8,95.14 9.35,95.59 8.53,95.59 7.99,95.05 0.81,95.05 0.34,95.52 0.34,97.05 0.91,97.62 2.24,97.62 2.43,97.81 12.28,97.81
GND on TOP (solid shape): 14.82,79.58 14.82,67.52 14.18,66.88 4.08,66.88 3.64,67.33 3.64,75.96 2.18,77.42 2.18,78.5 2.56,78.89 8.15,78.89 8.59,78.44 9.29,78.44 9.8,78.95 9.8,79.71 10.56,80.47 13.93,80.47
GND on TOP (solid shape): 184.3,36.47 184.3,32.15 183.86,31.72 180.62,31.72 180.09,31.18 178.89,31.18 178.65,30.95 177.82,30.95 177.69,31.08 177.69,32.85 178.02,33.17 180.42,33.17 180.99,33.74 182.26,33.74 182.27,33.74 182.58,33.74 182.77,33.93 182.77,34.44 182.01,35.2 180.93,35.2 180.36,35.77 180.36,36.59 180.61,36.85 183.92,36.85
GND on TOP (solid shape): 150.34,95.28 150.34,93.6 151.57,93.6 151.58,93.59 151.58,91.08 151.46,90.97 151.46,87.33 151.36,87.23 146.27,87.23 146.08,87.42 146.08,90.27 146.44,90.63 148.23,90.63 148.24,90.64 148.45,90.64 149.72,91.91 149.72,94.55 149.7,94.57 149.25,94.57 149.25,95.31 150.32,95.31
GND on TOP (solid shape): 157.74,83.72 157.74,82.13 157.83,82.04 158.94,82.04 158.97,82.01 158.97,79.63 158.87,79.53 158.87,77.5 158.63,77.26 158.63,72.01 158.45,71.83 155.16,71.83 154.07,72.92 154.07,77.58 156.09,79.6 156.95,79.6 157.1,79.76 157.1,82.98 157.08,83 156.63,83 156.63,83.76 157.7,83.76
GND on TOP (solid shape): 181.44,46.44 181.44,43.26 180.98,42.81 180.98,41.85 180.43,41.3 178.52,41.3 178.39,41.17 177.63,41.17 177.38,40.91 176.94,40.91 176.55,41.3 176.17,41.3 175.91,41.55 175.91,42 175.34,42.57 175.34,43.33 175.66,43.65 177.44,43.65 177.76,43.96 179.92,43.96 180.23,44.28 180.23,44.98 179.92,45.29 177.76,45.29 177.25,45.8 177.25,46.63 177.5,46.88 181,46.88
GND on TOP (solid shape): 147.36,105.03 147.36,103.35 147.42,103.29 148.58,103.29 148.6,103.28 148.6,100.51 148.32,100.23 148.32,96.16 147.87,95.71 143.09,95.71 142.9,95.9 142.9,98.37 142.54,98.73 142.54,99.44 142.62,99.52 144.29,99.52 146.08,101.32 146.43,101.32 146.72,101.61 146.72,103.8 146.72,103.8 146.72,104.25 146.69,104.28 146.24,104.28 146.24,104.29 146.24,105 146.27,105.03 147.35,105.03
GND on TOP (solid shape): 110.99,66.08 111.3,66.08 111.54,65.84 112.08,65.84 112.17,65.75 112.17,65.43 112.36,65.24 112.7,65.24 112.89,65.43 112.89,65.81 112.93,65.85 113.34,65.85 113.38,65.81 113.38,65.43 113.57,65.24 113.91,65.24 114.09,65.43 114.09,65.81 114.13,65.85 114.54,65.85 114.59,65.81 114.59,65.43 114.77,65.24 115.11,65.24 115.3,65.43 115.3,65.81 115.34,65.85 115.75,65.85 115.79,65.81 115.79,65.43 115.98,65.24 116.32,65.24 116.5,65.43 116.5,65.81 116.55,65.85 116.96,65.85 117,65.81 117,65.49 117.02,65.47 117.1,65.35 117.23,65.27 117.25,65.24 117.5,65.24 117.5,64.58 110.89,64.58 110.83,64.52 110.38,64.52 110.38,65.48 110.26,65.6 109.83,65.6 109.77,65.66 109.77,66.06 109.81,66.11 110.96,66.11
GND on TOP (solid shape): 215.22,52.79 215.22,51.83 214.78,51.39 214.78,48.02 215.67,47.14 215.67,45.61 215.6,45.55 210.71,45.55 209,43.83 204.17,43.83 202.2,45.8 202.2,46.49 211.43,46.49 211.44,46.44 211.45,46.39 211.47,46.34 211.5,46.29 211.53,46.25 211.57,46.21 211.61,46.18 211.66,46.16 211.71,46.15 211.76,46.14 211.82,46.14 211.87,46.15 211.92,46.16 211.97,46.18 212.01,46.21 212.05,46.25 212.09,46.29 212.11,46.34 212.13,46.39 212.14,46.44 212.15,46.49 212.14,46.55 212.13,46.6 212.11,46.65 212.09,46.69 212.05,46.74 212.01,46.77 211.97,46.8 211.92,46.83 211.87,46.84 211.82,46.85 211.76,46.85 211.71,46.84 211.66,46.83 211.61,46.8 211.57,46.77 211.53,46.74 211.5,46.69 211.47,46.65 211.45,46.6 211.44,46.55 211.43,46.49 202.2,46.49 202.2,51.96 202.52,52.28 211.03,52.28 211.28,52.53 212.36,52.53 212.62,52.79 213.57,52.79 213.76,52.98 215.03,52.98
GND on TOP (solid shape): 110.94,63.31 110.94,62.98 111.09,62.83 111.55,62.83 111.68,62.96 111.68,63.31 111.81,63.44 112.07,63.44 112.17,63.33 112.17,63.01 112.36,62.83 112.7,62.83 112.89,63.01 112.89,63.4 112.93,63.44 113.34,63.44 113.38,63.4 113.38,63.01 113.57,62.83 113.91,62.83 114.09,63.01 114.09,63.4 114.13,63.44 114.54,63.44 114.59,63.4 114.59,63.01 114.77,62.83 115.11,62.83 115.3,63.01 115.3,63.4 115.34,63.44 115.75,63.44 115.79,63.4 115.79,63.01 115.98,62.83 116.32,62.83 116.5,63.01 116.5,63.4 116.55,63.44 116.96,63.44 117,63.4 117,63.08 117.02,63.05 117.1,62.93 117.23,62.85 117.25,62.83 117.5,62.83 117.5,62.17 109.37,62.17 109.3,62.23 109.3,62.84 109.13,63.02 108.73,63.02 108.71,63.04 108.71,63.35 108.77,63.41 109.62,63.41 109.72,63.31 109.72,62.96 109.85,62.83 110.36,62.83 110.48,62.96 110.48,63.31 110.61,63.44 110.81,63.44
GND on TOP (solid shape): 203.79,33.62 203.79,31.39 203.09,30.69 197.89,30.69 197.76,30.83 197.76,31.7 199.14,33.09 199.8,33.09 199.81,33.04 199.82,32.98 199.84,32.93 199.86,32.89 199.9,32.85 199.94,32.81 199.98,32.78 200.03,32.76 200.08,32.74 200.13,32.73 200.19,32.73 200.24,32.74 200.29,32.76 200.34,32.78 200.38,32.81 200.42,32.85 200.45,32.89 200.48,32.93 200.5,32.98 200.51,33.04 200.52,33.09 200.51,33.14 200.5,33.19 200.48,33.24 200.45,33.29 200.42,33.33 200.38,33.37 200.34,33.4 200.29,33.42 200.24,33.44 200.19,33.44 200.13,33.44 200.08,33.44 200.03,33.42 199.98,33.4 199.94,33.37 199.9,33.33 199.86,33.29 199.84,33.24 199.82,33.19 199.81,33.14 199.8,33.09 199.14,33.09 199.51,33.46 199.51,33.6 199.66,33.75 199.89,33.75 200.08,33.56 200.1,33.56 200.12,33.54 200.17,33.52 200.22,33.51 200.27,33.5 200.32,33.5 200.37,33.51 200.42,33.52 200.47,33.54 200.49,33.56 200.5,33.56 200.57,33.62 200.68,33.74 200.68,33.94 200.86,34.12 203.28,34.12
GND on TOP (solid shape): 6.1,6.6 1.85,6.6 1.85,7.1 2.07,7.63 2.6,7.85 3.65,7.85 4.85,9.05 3.65,10.25 2.3,10.25 1.98,10.38 1.85,10.7 1.85,11.5 6.1,11.5
GND on TOP (solid shape): outline of 112 points within 108.42,56.96 117.5,61.09
GND on TOP (solid shape): outline of 104 points within 109.47,52.19 117.08,55.06
GND on TOP (solid shape): outline of 103 points within 111.58,36.95 114.88,42.23
GND on TOP (solid shape): outline of 144 points within 105.97,45.95 119.91,51.75
GND on TOP (solid shape): outline of 226 points within 0.25,0.25 231.65,138.25
GND on BOTTOM (solid shape): 14.63,52.15 14.63,45.55 14.21,45.13 3.1,45.13 2.62,45.61 2.62,51.9 3.32,52.6 14.18,52.6
GND on BOTTOM (solid shape): 46.33,4.81 46.33,3.68 46.1,3.44 44.64,3.44 44.4,3.69 44.4,4.99 44.53,5.13 46.02,5.13
GND on BOTTOM (solid shape): 67.22,109.55 67.22,108.44 67.14,108.36 63.74,108.36 63.6,108.5 63.6,109.61 63.81,109.82 66.95,109.82
GND on BOTTOM (solid shape): 96.22,102.44 96.22,100.28 96.1,100.16 95.33,100.16 94.76,100.73 94.76,102.7 94.89,102.82 95.84,102.82
GND on BOTTOM (solid shape): 104.8,114.32 104.8,112.16 104.73,112.1 103.65,112.1 103.59,112.16 103.59,114.45 103.72,114.57 104.54,114.57
GND on BOTTOM (solid shape): 141.05,38.75 141.05,37.67 140.93,37.55 138.89,37.55 138.64,37.8 138.64,38.75 138.83,38.94 140.86,38.94
GND on BOTTOM (solid shape): 158.71,70.24 158.71,68.71 158.14,68.14 155.66,68.14 155.02,68.78 155.02,70.17 155.6,70.74 158.2,70.74
GND on BOTTOM (solid shape): 162.9,45.24 162.9,43.84 162.77,43.71 159.85,43.71 159.66,43.9 159.66,45.24 159.72,45.3 162.83,45.3
GND on BOTTOM (solid shape): 177.12,27.27 177.12,22.57 176.99,22.44 175.98,22.44 175.66,22.76 175.66,27.2 175.91,27.46 176.93,27.46
GND on BOTTOM (solid shape): 182.01,20.4 182.01,17.16 181.76,16.91 180.49,16.91 180.23,17.16 180.23,20.53 180.49,20.78 181.63,20.78
GND on BOTTOM (solid shape): 182.5,42.73 182.5,42.23 182.29,42.01 181.39,42.01 181.18,42.22 181.18,42.67 181.41,42.9 182.33,42.9
GND on BOTTOM (solid shape): 137.4,89.82 137.4,88.44 136.38,87.42 134.87,87.42 134.42,87.87 134.42,89.98 134.89,90.46 136.77,90.46
GND on BOTTOM (solid shape): 141.31,47.59 141.31,46.34 141.26,46.29 140.63,46.29 140.48,46.44 138.07,46.44 137.94,46.57 137.94,47.65 138.07,47.78 141.12,47.78
GND on BOTTOM (solid shape): 178.39,18.81 178.39,18.5 178.01,18.12 178.01,17.1 177.82,16.91 176.42,16.91 176.23,17.1 176.23,18.69 176.55,19 178.2,19
GND on BOTTOM (solid shape): 56.18,4.57 56.18,3.86 55.68,3.36 53.07,3.36 52.95,3.48 52.95,4.17 53.14,4.36 53.61,4.36 54.09,4.84 55.92,4.84
GND on BOTTOM (solid shape): 162.55,89.73 162.55,87.13 162.05,86.62 160.33,86.62 159.82,87.13 159.82,89.6 159.83,89.61 159.83,89.74 160.39,90.3 161.98,90.3
GND on BOTTOM (solid shape): 83.01,112.16 83.01,109.11 83.46,108.66 83.46,107.77 83.29,107.6 83.1,107.6 82.81,107.31 81.96,107.31 81.62,107.65 81.62,112.35 81.81,112.54 82.63,112.54
GND on BOTTOM (solid shape): 87.84,113.05 87.84,112.03 87.71,111.91 86.95,111.91 86.63,111.59 86.63,109.81 86.44,109.62 85.62,109.62 85.49,109.75 85.49,112.79 85.87,113.18 87.71,113.18
GND on BOTTOM (solid shape): 217.76,25.3 217.76,20.47 216.93,19.65 213.44,19.65 213.38,19.7 213.38,20.98 213.51,21.11 216.11,21.11 216.24,21.23 216.24,25.42 216.43,25.61 217.44,25.61
GND on BOTTOM (solid shape): 161.12,37.74 161.12,37.04 160.93,36.85 160.93,33.68 160.86,33.62 159.21,33.62 159.15,33.68 159.15,36.28 159.21,36.35 159.53,36.35 160.23,37.04 160.23,37.68 160.36,37.81 161.05,37.81
GND on BOTTOM (solid shape): 13.61,96.47 13.61,94 12.85,93.24 9.99,93.24 9.8,93.43 9.8,95.14 9.35,95.59 8.53,95.59 7.99,95.05 0.81,95.05 0.34,95.52 0.34,97.05 0.91,97.62 2.24,97.62 2.43,97.81 12.28,97.81
GND on BOTTOM (solid shape): 134.07,107.9 134.07,106.42 133.3,105.65 124.89,105.65 123.92,106.62 123.92,107.85 124.86,108.79 133.18,108.79
GND on BOTTOM (solid shape): 169.66,27.38 169.75,27.38 169.94,27.19 169.94,23.2 169.75,23.01 168.67,23.01 168.55,23.14 168.55,27.26 168.68,27.39 169.65,27.39
GND on BOTTOM (solid shape): 204.04,34.69 204.04,32.28 203.98,32.22 203.22,32.22 202.77,31.77 202.77,30.76 202.71,30.69 197.69,30.69 197.63,30.76 197.63,31.96 197.82,32.15 199.79,32.15 200.71,33.08 200.71,34.47 201.06,34.82 203.92,34.82
GND on BOTTOM (solid shape): 14.82,79.58 14.82,67.52 14.18,66.88 4.08,66.88 3.64,67.33 3.64,76.03 2.18,77.49 2.18,78.5 2.59,78.92 8.08,78.92 8.56,78.44 9.29,78.44 9.8,78.95 9.8,79.71 10.56,80.47 13.93,80.47
GND on BOTTOM (solid shape): 82.14,103.36 82.14,100.92 81.74,100.53 77.32,100.53 77.06,100.79 77.06,102.13 77.22,102.29 78.11,102.29 78.51,102.68 78.51,103.59 78.63,103.71 81.78,103.71
GND on BOTTOM (solid shape): 147.59,68.15 147.59,67.96 147.85,67.71 147.85,67.46 148.04,67.26 148.67,67.26 148.8,67.14 148.8,65.61 148.61,65.42 146.33,65.42 145.44,66.31 145.44,68.17 146.18,68.92 146.83,68.92
GND on BOTTOM (solid shape): 165.76,61.36 165.76,56.34 165.63,56.22 163.15,56.22 162.2,57.17 162.01,57.17 161.69,57.49 161.18,57.49 161.06,57.61 161.06,60.79 161.18,60.91 161.88,60.91 162.14,60.66 162.96,60.66 163.15,60.85 163.15,61.36 163.28,61.49 165.63,61.49
GND on BOTTOM (solid shape): 140.04,86.38 141.82,86.38 142.2,86.76 143.02,86.76 143.05,86.73 143.56,86.73 144.17,86.12 144.17,84.22 143.53,83.58 136.35,83.58 135.72,84.22 135.72,86.2 136.28,86.76 139.66,86.76
GND on BOTTOM (solid shape): 227.29,18.94 227.29,17.29 228.37,16.21 230.97,16.21 231.6,15.58 231.6,9.16 231.03,8.59 224.3,8.59 224.05,8.84 224.05,10.88 225.82,12.65 225.82,13.94 225.31,14.46 219.7,14.46 219.58,14.58 219.58,18.59 220.12,19.13 227.1,19.13
GND on BOTTOM (solid shape): 163.22,30.24 163.22,29.29 163.28,29.23 163.28,27.89 162.9,27.51 162.9,25.23 162.77,25.1 161.88,25.1 161.75,25.23 161.75,29.42 161.95,29.61 162.26,29.61 162.45,29.8 162.45,30.12 162.64,30.31 163.15,30.31
GND on BOTTOM (solid shape): 162.32,39.52 162.32,39.15 162.32,39.01 162.45,38.89 162.59,38.89 163.85,38.89 164.04,38.7 164.04,37.36 163.91,37.23 161.56,37.23 161.37,37.42 161.37,37.81 161.18,38 159.15,38 159.02,38.12 159.02,39.46 159.21,39.65 162.2,39.65
GND on BOTTOM (solid shape): 101.37,116.74 101.37,114.45 101.62,114.19 101.62,113.3 101.47,113.15 100.64,113.15 100.42,112.93 100.42,111.63 100.33,111.54 100.23,111.54 100.15,111.62 100.15,112.93 99.84,113.24 99.84,115.08 99.91,115.14 99.91,116.8 100.09,116.99 101.13,116.99
GND on BOTTOM (solid shape): 189.48,21.38 189.48,18.86 189.65,18.69 189.65,17.6 189.64,17.59 189.64,17 189.92,16.72 189.92,16.05 189.69,15.81 189.07,15.81 188.71,16.17 188.71,18.09 188.57,18.23 188.54,18.25 188.54,19.42 188.57,19.47 188.61,19.5 188.61,21.4 188.64,21.44 189.42,21.44
GND on BOTTOM (solid shape): 96.54,10.18 96.54,8.65 98,7.19 99.65,7.19 99.91,7.45 106.26,7.45 106.45,7.64 107.4,7.64 107.65,7.89 107.65,8.21 107.78,8.34 108.1,8.34 108.16,8.27 108.16,7.96 108.41,7.7 108.8,7.7 108.92,7.57 108.92,5.42 108.73,5.23 93.94,5.23 93.43,5.73 93.43,10.31 93.94,10.81 95.91,10.81
GND on BOTTOM (solid shape): 150.34,95.28 150.34,93.6 151.57,93.6 151.58,93.59 151.58,91.08 151.46,90.96 151.46,87.32 151.37,87.24 146.26,87.24 146.08,87.42 146.08,90.27 146.44,90.63 148.23,90.63 148.24,90.64 148.45,90.64 149.72,91.91 149.72,94.55 149.7,94.57 149.25,94.57 149.25,95.31 150.32,95.31
GND on BOTTOM (solid shape): 84.79,130.83 84.79,127.78 83.08,126.07 69.87,126.07 69.17,125.37 69.17,120.48 69.55,120.1 70.4,120.1 70.4,120.1 71.03,120.1 71.03,120.65 71.28,120.65 71.28,120.1 71.83,120.1 71.83,120.65 72.08,120.65 72.08,120.1 74.29,120.1 74.51,119.89 74.51,118.57 74.32,118.38 64.92,118.38 64.03,119.27 64.03,130.98 64.26,131.21 84.41,131.21
GND on BOTTOM (solid shape): 157.74,83.72 157.74,82.13 157.83,82.04 158.94,82.04 158.97,82.01 158.97,79.63 158.84,79.51 158.84,77.51 158.64,77.31 158.64,72.04 158.45,71.85 157.42,71.85 157.41,71.85 155.14,71.85 154.07,72.92 154.07,77.59 156.08,79.6 157.03,79.6 157.09,79.67 157.09,79.75 157.1,79.76 157.1,82.98 157.08,83 156.63,83 156.63,83.76 157.7,83.76
GND on BOTTOM (solid shape): 147.35,105.03 147.35,103.34 147.4,103.29 148.58,103.29 148.6,103.28 148.6,100.51 148.33,100.25 148.33,96.17 147.89,95.73 147.55,95.73 147.53,95.71 143.09,95.71 142.9,95.9 142.9,99.27 143.15,99.52 144.28,99.52 146.08,101.32 146.44,101.32 146.72,101.6 146.72,103.8 146.72,103.8 146.72,104.25 146.69,104.28 146.24,104.28 146.24,104.29 146.24,105 146.27,105.03 147.35,105.03
GND on BOTTOM (solid shape): 154.26,43.33 154.58,43.33 154.64,43.26 154.64,42.95 154.83,42.76 158.07,42.76 158.13,42.7 158.13,41.62 156.8,40.28 155.21,40.28 154.96,40.54 154.96,40.66 154.64,40.98 153.24,40.98 153.12,41.11 153.12,41.68 152.87,41.93 152.87,42.25 152.61,42.51 151.53,42.51 151.09,42.06 150.07,42.06 149.63,42.5 148.23,42.5 148.04,42.31 147.85,42.31 147.72,42.44 147.72,42.69 147.85,42.82 149.68,42.82 150.07,43.2 151.72,43.2 151.81,43.3 152.62,43.3 152.65,43.33 154.26,43.33
GND on BOTTOM (solid shape): 181.82,36.59 181.82,36.53 183.54,34.82 183.54,34.56 184.07,34.02 184.07,31.93 183.88,31.73 181.03,31.73 180.29,32.47 179.15,32.47 178.77,32.09 177.76,32.09 177.38,32.47 176.11,32.47 175.98,32.34 175.79,32.34 175.66,32.47 175.66,32.72 175.79,32.85 176.04,32.85 176.17,32.72 177.5,32.72 177.69,32.91 177.69,33.11 177.76,33.17 180.36,33.17 180.93,33.74 182.4,33.74 182.65,33.99 182.65,34.44 181.88,35.2 181.06,35.2 181,35.26 181,35.39 180.8,35.58 180.55,35.58 180.36,35.77 180.36,36.53 180.49,36.66 181.76,36.66
GND on BOTTOM (solid shape): 218.33,53.36 218.33,50.56 219.1,49.8 219.1,49.23 219.6,48.72 219.6,47.14 219.48,47.01 219.29,47.01 219.1,47.2 219.1,47.52 218.9,47.71 218.9,48.6 218.84,48.66 218.84,49.74 218.71,49.87 218.09,49.87 217.95,49.73 217.95,48.6 217.83,48.47 217.73,48.47 217.63,48.57 217.63,50.63 216.81,51.45 214.46,51.45 214.02,51.01 214.02,48.98 213.63,48.6 212.81,48.6 212.11,49.29 212.11,52.41 212.49,52.79 213.44,52.79 213.7,53.04 214.52,53.04 214.78,53.29 215.35,53.29 215.54,53.49 215.98,53.49 216.17,53.68 216.87,53.68 217.19,53.99 217.7,53.99
